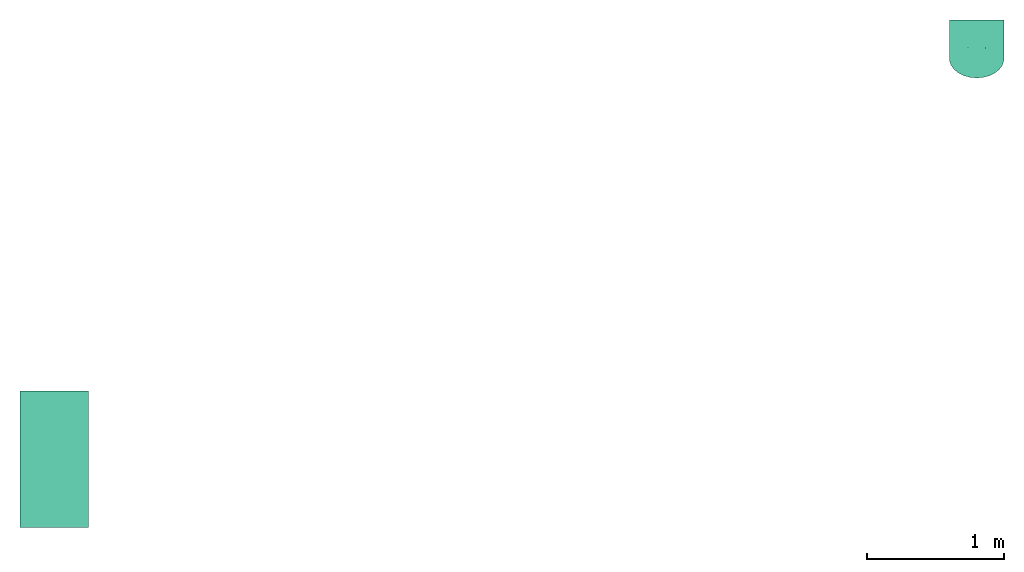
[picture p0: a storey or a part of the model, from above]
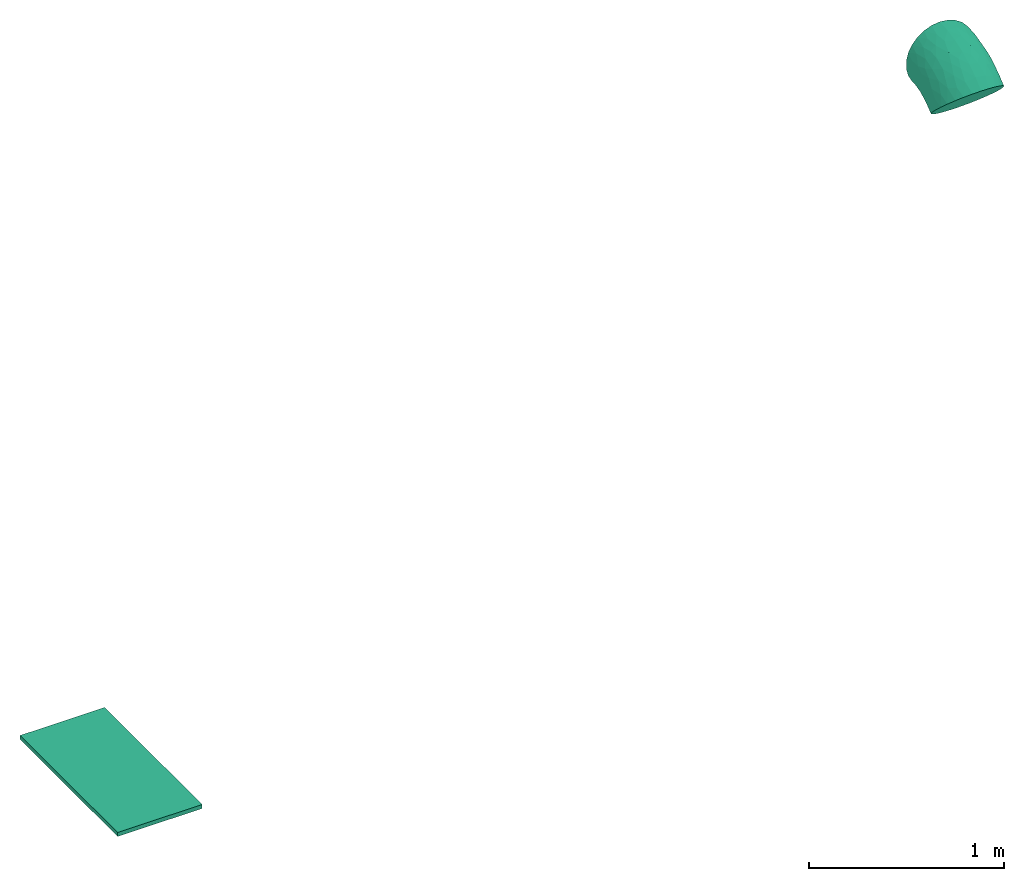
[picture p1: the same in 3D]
Properties of the parts of a building model (IFC2X3), part 1 of 11

# File
Description: ViewDefinition [CoordinationView]
File name: gmtgo-a-200-1-0001.ifc (Edited by Naviate Simple BIM 2022 version 6)
Time: 2026-03-17T17:30:04+01:00
Written by: ODA SDAI 24.12
Made in: Autodesk Revit 25.4.20.11 (ENU) - IFC 25.4.0.27

# IfcProject, 10004870
LongName: 10004870; Phase: Detaljprosjekt

# IfcSite (6)
Name | RefLatitude | RefLongitude | RefElevation (mm)
ENGM | 59, 54, 57, 599999 | 10, 44, 59, 999999 | -4.85124e-10
3 x  | 59, 54, 57, 599999 | 10, 44, 59, 999999 | 0 | MagiCAD Pset_Site - Reference longitude: 10, 44, 59, 999999; Reference elevation: 0; Reference latitude: 59, 54, 57, 599999
ENGM | 59, 54, 49, 759826 | 10, 44, 19, 467315 | 0
Gardermoen

# IfcBuilding (6)
Name
TG | LongName: TG; Pset_BuildingCommon - NumberOfStoreys: 15
3 x mc-building
2 x TG

# IfcBuildingStorey (17)
Name | In | Elevation (mm) | Name
Nivå F - 0,7 m | mc-building | 210200 | Nivå F - 0,7 m Himling
3 x Nivå D + 1,2 m | mc-building | 205200 | Nivå D + 1,2 m
Nivå G - 2,0 m | mc-building | 213700 | Nivå G - 2,0 m
2 x Nivå F - 0,7 m | mc-building | 210200 | Nivå F - 0,7 m
2 x Nivå C | mc-building | 200300 | Nivå C
Nivå F | mc-building | 210900 | Nivå F
Nivå D + 1,2 o | mc-building | 205200 | Nivå D + 1,2 o
Nivå D + 1,2 | TG | 205200 | LongName: Nivå D + 1,2
Nivå F | TG | 210900 | LongName: Nivå F
Nivå F - 0,7 | TG | 210200 | LongName: Nivå F - 0,7
F | TG | 0
G | TG | 0
D | TG | 0

# IfcBuildingStorey: Level:T2 - Kote (6)
In: TG
Name | LongName | Elevation (mm) | Pset_ProductRequirements, Name | Pset_ProductRequirements, sets with these values
Nivå D + 1,2 m | Nivå D + 1,2 m | 205200 | Pset_AirSideSystemInformation - Name: Nivå D + 1,2 m; sets with these values: 2
Nivå E | Nivå E | 207370 | Nivå E | 2
Nivå F - 0,7 m | Nivå F - 0,7 m | 210200 | Nivå F - 0,7 m | 2
Nivå F | Nivå F | 210900 | Nivå F | 2
Nivå G - 2,0 m | Nivå G - 2,0 m | 213700 | Nivå G - 2,0 m | 2
Nivå G | Nivå G | 215700 | Nivå G | 2

# IfcBeam: 10*200 (2)
In: F
Description: 10*200; Material: STEEL/S355
Pset_BeamCommon - LoadBearing: no; Reference: DINN-997(?)
ePset_LocationTool - Splitting: ORIGINAL
ePset_SimplebimBasicQuantities - Volume, net (Simplebim): 0.0007 m3; Area, sides, net (Simplebim): 0.151 m2; Weight, as steel (Simplebim): 5.495 kg; Width (Simplebim): 10 mm; Length (Simplebim): 200 mm; Height (Simplebim): 350 mm
ePset_Simplebim - Assembly Level: Leaf
Tekla Quantity - VOLUME_GROSS: 0.0007 m3; VOLUME_NET: 0.0007 m3; AREA_NET: 0.151 m2; AREA_GROSS: 0.151 m2; WEIGTH_NET: 5.495 kg; WEIGTH_GROSS: 5.495 kg; Heigth: 10 mm; Width: 200 mm; Length: 350 mm
Tekla Common - Grade: S355; Bottom elevation: +213.297; Name: INNSTØPNGODS; Profile: 10*200; Class: 371; Part mark: DINN-997(?); Assembly mark: INN-391(?); Top elevation: +213.647
AVINOR - 07_Fase: F90; 02_Prosjekt: T1; 04_Kontrakt: FDV; 03_Ansvar: FDV; 08_Status: S2; 06_Omrade: TG; 01_Lufthavnkode: ENGM

# IfcBeam: 150*10 (6)
In: F
Description: 150*10; Material: STEEL/S355
ePset_SimplebimBasicQuantities - Weight, as steel (Simplebim): 3.5325 kg; Height (Simplebim): 10 mm; Width (Simplebim): 150 mm; Length (Simplebim): 300 mm; Area, sides, net (Simplebim): 0.099 m2; Volume, net (Simplebim): 0.00045 m3
Pset_BeamCommon - Reference: DINN-1005(?); LoadBearing: no
ePset_LocationTool - Splitting: ORIGINAL
ePset_Simplebim - Assembly Level: Leaf
Tekla Common - Bottom elevation: +209.755; Top elevation: +209.765; Profile: 150*10; Part mark: DINN-1005(?); Grade: S355; Name: INNSTØPNGODS; Class: 371; Assembly mark: INN-402(?)
Tekla Quantity - WEIGTH_NET: 3.5325 kg; WEIGTH_GROSS: 3.5325 kg; Width: 10 mm; Heigth: 150 mm; Length: 300 mm; AREA_NET: 0.099 m2; AREA_GROSS: 0.099 m2; VOLUME_GROSS: 0.00045 m3; VOLUME_NET: 0.00045 m3
AVINOR - 07_Fase: F90; 02_Prosjekt: T1; 04_Kontrakt: FDV; 03_Ansvar: FDV; 08_Status: S2; 06_Omrade: TG; 01_Lufthavnkode: ENGM

# IfcBeam: 20*180 (4)
In: F
Description: 20*180; Material: STEEL/S355
Pset_BeamCommon - LoadBearing: no; Reference: DINN-938(?)
Tekla Quantity - VOLUME_GROSS: 0.00126 m3; VOLUME_NET: 0.00126 m3; AREA_GROSS: 0.1472 m2; AREA_NET: 0.1472 m2; Heigth: 20 mm; Width: 180 mm; Length: 350 mm; WEIGTH_NET: 9.891 kg; WEIGTH_GROSS: 9.891 kg
ePset_Simplebim - Assembly Level: Leaf
ePset_SimplebimBasicQuantities - Volume, net (Simplebim): 0.00126 m3; Area, sides, net (Simplebim): 0.1472 m2; Width (Simplebim): 20 mm; Length (Simplebim): 180 mm; Height (Simplebim): 350 mm; Weight, as steel (Simplebim): 9.891 kg
ePset_LocationTool - Splitting: ORIGINAL
Tekla Common - Grade: S355; Name: INNSTØPNGODS; Assembly mark: INN-346(?); Class: 371; Profile: 20*180; Part mark: DINN-938(?); Top elevation: +213.615; Bottom elevation: +213.265
AVINOR - 07_Fase: F90; 02_Prosjekt: T1; 04_Kontrakt: FDV; 03_Ansvar: FDV; 08_Status: S2; 06_Omrade: TG; 01_Lufthavnkode: ENGM

# IfcBeam: 200*10 (4)
In: F
Description: 200*10; Material: STEEL/S355
Tekla Quantity - VOLUME_NET: 0.00039 m3; VOLUME_GROSS: 0.00039 m3; WEIGTH_GROSS: 3.14 kg; WEIGTH_NET: 3.14 kg; AREA_GROSS: 0.088 m2; AREA_NET: 0.088 m2; Width: 10 mm; Heigth: 200 mm; Length: 200 mm
Tekla Common - Part mark: DINN-1003(?); Grade: S355; Top elevation: +210.030; Bottom elevation: +210.020; Name: INNSTØPNGODS; Profile: 200*10; Class: 371; Assembly mark: INN-399(?)
ePset_Simplebim - Assembly Level: Leaf
ePset_SimplebimBasicQuantities - Length (Simplebim): 200.001 mm; Volume, net (Simplebim): 0.000400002 m3; Height (Simplebim): 10 mm; Width (Simplebim): 200 mm; Area, sides, net (Simplebim): 0.0880004 m2; Weight, as steel (Simplebim): 3.14002 kg
Pset_BeamCommon - Reference: DINN-1003(?); LoadBearing: no
ePset_LocationTool - Splitting: ORIGINAL
AVINOR - 07_Fase: F90; 02_Prosjekt: T1; 04_Kontrakt: FDV; 03_Ansvar: FDV; 08_Status: S2; 06_Omrade: TG; 01_Lufthavnkode: ENGM

# IfcBeam: 25*140 (10)
Description: 25*140; Material: STEEL/S355
Tekla Common - Grade: S355; Profile: 25*140; Name: STÅLBJELKE; Part mark: DSB-20613(?); Class: 330
ePset_Simplebim - Assembly Level: Leaf
ePset_LocationTool - Splitting: ORIGINAL
ePset_SimplebimBasicQuantities - Weight, as steel (Simplebim): 3.57175 kg; Area, sides, net (Simplebim): 0.0499 m2; Volume, net (Simplebim): 0.000455 m3; Width (Simplebim): 25 mm; Height (Simplebim): 130 mm; Length (Simplebim): 140 mm
Tekla Quantity - WEIGTH_NET: 3.57175 kg; WEIGTH_GROSS: 3.57175 kg; AREA_NET: 0.0499 m2; AREA_GROSS: 0.0499 m2; Heigth: 25 mm; Width: 140 mm; Length: 130 mm; VOLUME_GROSS: 0.00045 m3; VOLUME_NET: 0.00045 m3
AVINOR - 07_Fase: F90; 02_Prosjekt: T1; 04_Kontrakt: FDV; 03_Ansvar: FDV; 08_Status: S2; 06_Omrade: TG; 01_Lufthavnkode: ENGM
Pset_BeamCommon - Reference: DSB-20613(?); LoadBearing: no
Name | In | Top elevation | Bottom elevation | Assembly mark
2 x STÅLBJELKE | F | +213.457 | +213.327 | INN-391(?)
4 x STÅLBJELKE | F | +213.425 | +213.295 | INN-346(?)
4 x STÅLBJELKE | G | +213.541 | +213.411 | SB-12403(?)

# IfcBeam: 250*10 (4)
In: F
Description: 250*10; Material: STEEL/S355
ePset_LocationTool - Splitting: ORIGINAL
Tekla Quantity - VOLUME_GROSS: 0.00063 m3; VOLUME_NET: 0.00063 m3; AREA_NET: 0.135 m2; AREA_GROSS: 0.135 m2; WEIGTH_NET: 4.90625 kg; WEIGTH_GROSS: 4.90625 kg; Width: 10 mm; Heigth: 250 mm; Length: 250 mm
ePset_SimplebimBasicQuantities - Area, sides, net (Simplebim): 0.135 m2; Weight, as steel (Simplebim): 4.90625 kg; Height (Simplebim): 10 mm; Length (Simplebim): 250 mm; Width (Simplebim): 250 mm; Volume, net (Simplebim): 0.000625 m3
Pset_BeamCommon - Reference: DINN-1006(?); LoadBearing: no
ePset_Simplebim - Assembly Level: Leaf
Tekla Common - Profile: 250*10; Part mark: DINN-1006(?); Grade: S355; Name: INNSTØPNGODS; Class: 371; Assembly mark: INN-403(?)
AVINOR - 07_Fase: F90; 02_Prosjekt: T1; 04_Kontrakt: FDV; 03_Ansvar: FDV; 08_Status: S2; 06_Omrade: TG; 01_Lufthavnkode: ENGM
Name | Bottom elevation | Top elevation
3 x INNSTØPNGODS | +209.570 | +209.580
INNSTØPNGODS | +209.296 | +209.320

# IfcBeam: 350*10 (2)
In: F
Description: 350*10; Material: STEEL/S355
Pset_BeamCommon - Reference: DINN-1008(?); LoadBearing: no
ePset_SimplebimBasicQuantities - Volume, net (Simplebim): 0.00139999 m3; Length (Simplebim): 399.998 mm; Area, sides, net (Simplebim): 0.294998 m2; Height (Simplebim): 10 mm; Width (Simplebim): 350 mm; Weight, as steel (Simplebim): 10.9899 kg
ePset_Simplebim - Assembly Level: Leaf
ePset_LocationTool - Splitting: ORIGINAL
Tekla Common - Profile: 350*10; Part mark: DINN-1008(?); Grade: S355; Top elevation: +210.030; Bottom elevation: +210.020; Name: INNSTØPNGODS; Class: 371; Assembly mark: INN-405(?)
AVINOR - 07_Fase: F90; 02_Prosjekt: T1; 04_Kontrakt: FDV; 03_Ansvar: FDV; 08_Status: S2; 06_Omrade: TG; 01_Lufthavnkode: ENGM
Tekla Quantity - AREA_NET: 0.295 m2; AREA_GROSS: 0.295 m2; VOLUME_NET: 0.0014 m3; VOLUME_GROSS: 0.00141 m3; Length: 399.998 mm; WEIGTH_GROSS: 10.9899 kg; WEIGTH_NET: 10.9899 kg; Width: 10 mm; Heigth: 350 mm

# IfcBeam: 40*5, STÅLBJELKE
In: F
Description: 40*5; Material: STEEL/S355
Pset_BeamCommon - LoadBearing: no; Reference: DSB-18884(?)
Tekla Quantity - Length: 590.185 mm; AREA_GROSS: 0.05352 m2; AREA_NET: 0.05352 m2; WEIGTH_NET: 0.92659 kg; WEIGTH_GROSS: 0.92659 kg; Width: 5 mm; VOLUME_NET: 0.00013 m3; VOLUME_GROSS: 0.00013 m3; Heigth: 40 mm
Tekla Common - Grade: S355; Top elevation: +210.295; Bottom elevation: +210.255; Name: STÅLBJELKE; Assembly mark: SS-7596(?); Class: 330; Profile: 40*5; Part mark: DSB-18884(?)
ePset_Simplebim - Assembly Level: Leaf
ePset_SimplebimBasicQuantities - Volume, net (Simplebim): 0.000118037 m3; Length (Simplebim): 590.185 mm; Weight, as steel (Simplebim): 0.92659 kg; Height (Simplebim): 40 mm; Width (Simplebim): 5 mm; Area, sides, net (Simplebim): 0.0535166 m2
ePset_LocationTool - Splitting: ORIGINAL
AVINOR - 07_Fase: F90; 02_Prosjekt: T1; 04_Kontrakt: FDV; 03_Ansvar: FDV; 08_Status: S2; 06_Omrade: TG; 01_Lufthavnkode: ENGM

# IfcBeam: 5*80 (3)
In: F
Description: 5*80; Material: STEEL/S355
ePset_LocationTool - Splitting: ORIGINAL
Tekla Quantity - Heigth: 5 mm; Width: 80 mm
ePset_Simplebim - Assembly Level: Leaf
ePset_SimplebimBasicQuantities - Height (Simplebim): 5 mm; Width (Simplebim): 80 mm
Pset_BeamCommon - LoadBearing: no
AVINOR - 07_Fase: F90; 02_Prosjekt: T1; 04_Kontrakt: FDV; 03_Ansvar: FDV; 08_Status: S2; 06_Omrade: TG; 01_Lufthavnkode: ENGM
Tekla Common - Grade: S355; Bottom elevation: +210.255; Name: STÅLBJELKE; Profile: 5*80; Assembly mark: SS-7596(?); Class: 330; Top elevation: +210.260
Name | AREA_GROSS (m2) = AREA_NET (m2) | WEIGTH_GROSS (kg) = WEIGTH_NET (kg) = Weight, as steel (Simplebim) (kg) | Length (mm) = Length (Simplebim) (mm) | VOLUME_GROSS (m3) = VOLUME_NET (m3) | Volume, net (Simplebim) (m3) | Area, sides, net (Simplebim) (m2) | Reference = Part mark
STÅLBJELKE | 0.40879 | 7.53573 | 2399.91 | 0.00096 | 0.000959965 | 0.408785 | DSB-18881(?)
2 x STÅLBJELKE | 0.34491 | 6.35586 | 2024.16 | 0.00081 | 0.000809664 | 0.344907 | DSB-18880(?)

# IfcBeam: 50*12 (8)
In: F
Description: 50*12; Material: STEEL/S355
ePset_SimplebimBasicQuantities - Width (Simplebim): 12 mm; Height (Simplebim): 50 mm
Pset_BeamCommon - LoadBearing: no
Tekla Common - Grade: S355; Name: STÅLBJELKE; Profile: 50*12; Assembly mark: SS-7596(?); Class: 330
ePset_Simplebim - Assembly Level: Leaf
Tekla Quantity - Width: 12 mm; Heigth: 50 mm
ePset_LocationTool - Splitting: ORIGINAL
AVINOR - 07_Fase: F90; 02_Prosjekt: T1; 04_Kontrakt: FDV; 03_Ansvar: FDV; 08_Status: S2; 06_Omrade: TG; 01_Lufthavnkode: ENGM
Name | Volume, net (Simplebim) (m3) | Area, sides, net (Simplebim) (m2) | Length (Simplebim) (mm) | Weight, as steel (Simplebim) (kg) | Reference = Part mark | Bottom elevation | Top elevation | WEIGTH_NET (kg) = WEIGTH_GROSS (kg) | Length (mm) | VOLUME_GROSS (m3) = VOLUME_NET (m3) | AREA_GROSS (m2) = AREA_NET (m2)
STÅLBJELKE | 0.00144 | 0.2988 | 2400 | 11.304 | DSB-19554(?) | +213.180 | +213.230 | 11.304 | 2400 | 0.00144 | 0.2988
STÅLBJELKE | 0.000354 | 0.07436 | 590 | 2.7789 | DSB-19555(?) | +210.230 | +210.280 | 2.77977 | 590.185 | 0.00035 | 0.07438
2 x STÅLBJELKE | 0.000354 | 0.07436 | 590 | 2.7789 | DSB-19555(?) | +210.930 | +210.980 | 2.77977 | 590.185 | 0.00035 | 0.07438
2 x STÅLBJELKE | 0.000354 | 0.07436 | 590 | 2.7789 | DSB-19555(?) | +211.680 | +211.730 | 2.77977 | 590.185 | 0.00035 | 0.07438
STÅLBJELKE | 0.000731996 | 0.152479 | 1219.99 | 5.74617 | DSB-19556(?) | +212.385 | +212.435 | 5.7462 | 1220 | 0.00073 | 0.15248
STÅLBJELKE | 0.0012144 | 0.252176 | 2024 | 9.53305 | DSB-19553(?) | +213.180 | +213.230 | 9.53379 | 2024.16 | 0.00121 | 0.2522

# IfcBeam: 60*5 (28)
In: G
Description: 60*5; Material: STEEL/S355
Pset_BeamCommon - LoadBearing: no; Reference: DSB-18871(?)
Tekla Common - Grade: S355; Name: STÅLBJELKE; Assembly mark: SB-11173(?); Top elevation: +213.665; Bottom elevation: +213.660; Part mark: DSB-18871(?); Class: 330; Profile: 60*5
ePset_SimplebimBasicQuantities - Weight, as steel (Simplebim): 0.35325 kg; Volume, net (Simplebim): 0.000045 m3; Area, sides, net (Simplebim): 0.0201 m2; Height (Simplebim): 5 mm; Width (Simplebim): 60 mm; Length (Simplebim): 150 mm
ePset_Simplebim - Assembly Level: Leaf
ePset_LocationTool - Splitting: ORIGINAL
Tekla Quantity - VOLUME_GROSS: 0.00005 m3; VOLUME_NET: 0.00005 m3; WEIGTH_NET: 0.35325 kg; WEIGTH_GROSS: 0.35325 kg; AREA_NET: 0.0201 m2; AREA_GROSS: 0.0201 m2; Width: 5 mm; Heigth: 60 mm; Length: 150 mm
AVINOR - 07_Fase: F90; 02_Prosjekt: T1; 04_Kontrakt: FDV; 03_Ansvar: FDV; 08_Status: S2; 06_Omrade: TG; 01_Lufthavnkode: ENGM

# IfcBeam: 80*5 (10)
In: F
Description: 80*5; Material: STEEL/S355
ePset_SimplebimBasicQuantities - Width (Simplebim): 5 mm; Height (Simplebim): 80 mm
Tekla Quantity - Width: 5 mm; Heigth: 80 mm
ePset_Simplebim - Assembly Level: Leaf
Tekla Common - Grade: S355; Name: STÅLBJELKE; Assembly mark: SS-7596(?); Class: 330; Profile: 80*5
Pset_BeamCommon - LoadBearing: no
AVINOR - 07_Fase: F90; 02_Prosjekt: T1; 04_Kontrakt: FDV; 03_Ansvar: FDV; 08_Status: S2; 06_Omrade: TG; 01_Lufthavnkode: ENGM
ePset_LocationTool - Splitting: ORIGINAL
Name | Length (Simplebim) (mm) = Length (mm) | Area, sides, net (Simplebim) (m2) | Weight, as steel (Simplebim) (kg) = WEIGTH_GROSS (kg) = WEIGTH_NET (kg) | Volume, net (Simplebim) (m3) | AREA_NET (m2) = AREA_GROSS (m2) | VOLUME_GROSS (m3) = VOLUME_NET (m3) | Bottom elevation | Top elevation | Part mark = Reference
STÅLBJELKE | 2400 | 0.4088 | 7.536 | 0.00096 | 0.4088 | 0.00096 | +213.165 | +213.245 | DSB-18881(?)
STÅLBJELKE | 590.185 | 0.101131 | 1.85318 | 0.000236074 | 0.10113 | 0.00024 | +210.105 | +210.185 | DSB-18883(?)
2 x STÅLBJELKE | 590.185 | 0.101131 | 1.85318 | 0.000236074 | 0.10113 | 0.00024 | +210.915 | +210.995 | DSB-18883(?)
2 x STÅLBJELKE | 590.185 | 0.101131 | 1.85318 | 0.000236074 | 0.10113 | 0.00024 | +211.665 | +211.745 | DSB-18883(?)
STÅLBJELKE | 1220 | 0.2082 | 3.8308 | 0.000488 | 0.2082 | 0.00049 | +212.370 | +212.450 | DSB-18882(?)
2 x STÅLBJELKE | 590.185 | 0.101131 | 1.85318 | 0.000236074 | 0.10113 | 0.00024 | +213.605 | +213.685 | DSB-18883(?)
STÅLBJELKE | 2024.16 | 0.344907 | 6.35586 | 0.000809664 | 0.34491 | 0.00081 | +213.165 | +213.245 | DSB-18880(?)

# IfcBeam: AAJKORS265*195*30*900*150*700*700 (4)
In: F
Description: AAJKORS265*195*30*900*150*700*700
ePset_LocationTool - Splitting: RESULT
AVINOR - 07_Fase: F90; 02_Prosjekt: T1; 04_Kontrakt: FDV; 03_Ansvar: FDV; 08_Status: S2; 05_ID-nummer: +TA=223.001; 06_Omrade: TG; 01_Lufthavnkode: ENGM
ePset_Simplebim - Assembly Level: Leaf
Pset_BeamCommon - LoadBearing: no
ePset_SimplebimBasicQuantities - Height (Simplebim): 830 mm; Length (Simplebim): 9310 mm
Tekla Common - Name: PREFABBJELKE; Top elevation: +210.030; Bottom elevation: +209.130; Profile: AAJKORS265*195*30*900*150*700*700; Grade: C45/55; Class: 130
Name | Reference = Part mark | Volume, net (Simplebim) (m3) | Weight, as steel (Simplebim) (kg) | Width (Simplebim) (mm) | Area, sides, net (Simplebim) (m2) | Assembly mark
PREFABBJELKE | Concrete-19788(?) | 5.4907 | 43102 | 1000 | 36.4043 | PB-539(?)
PREFABBJELKE | Concrete-19791(?) | 4.22354 | 33154.8 | 705 | 30.4457 | PB-542(?)
PREFABBJELKE | Concrete-19784(?) | 5.49345 | 43123.6 | 1000 | 36.3873 | PB-535(?)
PREFABBJELKE | Concrete-19782(?) | 3.21961 | 25274 | 565 | 27.0215 | PB-533(?)

# IfcBeam: B223 - Bjelke - Flatstål:B223 - Bjelke - Flatstål - w240 h 8 (2)
In: Nivå G - 2,0 m
Type - PredefinedType: BEAM
Type - Pset_BeamCommon - LoadBearing: yes
Material: _NSW Stål
AVINOR - 08_Status: S4; 07_Fase: F90; 03_Ansvar: FDV; 06_Omrade: TG; 02_Prosjekt: T20100; 01_Lufthavnkode: ENGM
ePset_SimplebimBasicQuantities - Width (Simplebim): 8 mm; Volume, net (Simplebim): 0.01728 m3; Weight, as steel (Simplebim): 135.648 kg; Area, sides, net (Simplebim): 4.46784 m2; Height (Simplebim): 240 mm; Length (Simplebim): 9000 mm
ePset_Simplebim - Assembly Level: Leaf
ePset_LocationTool - Splitting: ORIGINAL
Pset_BeamCommon - IsExternal: no; Slope: 0 deg; Reference: B223 - Bjelke - Flatstål - w240 h 8; Span: 9000 mm
Pset_ReinforcementBarPitchOfBeam - Reference: B223 - Bjelke - Flatstål - w240 h 8; sets with these values: 2
Name (B223 - Bjelke - Flatstål:B223 - Bjelke - Flatstål - w240 h 8:...) | Group
49950679 | Model Group:A240 - eksisterende gallerivegg i pir G-2 / generell (members excluded):49950707
49959070 | Model Group:A240 - eksisterende gallerivegg i pir G-2 / forkortet ved bru akse 19-20 nordside, 21-22 sørside (members excluded):49959098

# IfcBeam: B223 - Bjelke - HUP2:B223 - HUP 150 x 150 x 8 mm (2)
In: Nivå G - 2,0 m
Type - PredefinedType: BEAM
Type - Pset_BeamCommon - LoadBearing: yes
Material: _NSW Stål; Group: Model Group:A162446 - Utvidelse eksisterende Kiosk (members excluded):59114857
AVINOR - 08_Status: S4; 07_Fase: F90; 02_Prosjekt: A162446; 03_Ansvar: 182412; 06_Omrade: TG; 01_Lufthavnkode: ENGM
ePset_SimplebimBasicQuantities - Width (Simplebim): 150 mm; Height (Simplebim): 150 mm
ePset_Simplebim - Assembly Level: Leaf
Pset_BeamCommon - IsExternal: no; Slope: 0 deg; Reference: B223 - HUP 150 x 150 x 8 mm
ePset_LocationTool - Splitting: ORIGINAL
Pset_QuantityTakeOff - Reference: B223 - HUP 150 x 150 x 8 mm; sets with these values: 2
Name (B223 - Bjelke - HUP2:B223 - HUP 150 x 150 x 8 mm:...) | Area, sides, net (Simplebim) (m2) | Weight, as steel (Simplebim) (kg) | Length (Simplebim) (mm) = Span (mm) | Volume, net (Simplebim) (m3)
59105830 | 16.5911 | 525.445 | 14867.6 | 0.0669357
59105838 | 16.2479 | 514.573 | 14560 | 0.0655506

# IfcBeam: B223 - Bjelke - HUP:B223 - HUP 100 x 100 x 5 mm (2)
Type - PredefinedType: BEAM
Type - Pset_BeamCommon - LoadBearing: yes
Material: _NSW Stål; Group: Model Group:tettfelt 2 (members excluded):48741169
AVINOR - 08_Status: S4; 07_Fase: F90; 03_Ansvar: FDV; 06_Omrade: TG; 02_Prosjekt: T20100; 01_Lufthavnkode: ENGM
Pset_BeamCommon - Reference: B223 - HUP 100 x 100 x 5 mm; IsExternal: no; Slope: 0 deg
ePset_Simplebim - Assembly Level: Leaf
ePset_LocationTool - Splitting: ORIGINAL
ePset_SimplebimBasicQuantities - Width (Simplebim): 100 mm; Height (Simplebim): 100 mm
Pset_ReinforcementBarPitchOfBeam - Reference: B223 - HUP 100 x 100 x 5 mm; sets with these values: 2
Name (B223 - Bjelke - HUP:B223 - HUP 100 x 100 x 5 mm:...) | In | Span (mm) = Length (Simplebim) (mm) | Volume, net (Simplebim) (m3) | Weight, as steel (Simplebim) (kg) | Area, sides, net (Simplebim) (m2)
48742636 | Nivå G - 2,0 m | 400 | 0.00075345 | 5.91458 | 0.302596
48742642 | Nivå F - 0,7 m | 425 | 0.000800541 | 6.28424 | 0.321273

# IfcBeam: B223 - Bjelke - HUP:B223 - HUP 40 x 80 x 4 mm (3)
In: Nivå G - 2,0 m
Type - PredefinedType: BEAM
Type - Pset_BeamCommon - LoadBearing: yes
Material: _NSW Stål
AVINOR - 08_Status: S4; 07_Fase: F90; 03_Ansvar: FDV; 06_Omrade: TG; 02_Prosjekt: T20100; 01_Lufthavnkode: ENGM
ePset_LocationTool - Splitting: ORIGINAL
Pset_BeamCommon - Reference: B223 - HUP 40 x 80 x 4 mm; IsExternal: no; Slope: 0 deg; Span: 9000 mm
ePset_Simplebim - Assembly Level: Leaf
ePset_SimplebimBasicQuantities - Area, sides, net (Simplebim): 3.94066 m2; Volume, net (Simplebim): 0.00796963 m3; Weight, as steel (Simplebim): 62.5616 kg; Width (Simplebim): 40 mm; Height (Simplebim): 80 mm; Length (Simplebim): 9000 mm
Pset_ReinforcementBarPitchOfBeam - Reference: B223 - HUP 40 x 80 x 4 mm; sets with these values: 2
Name (B223 - Bjelke - HUP:B223 - HUP 40 x 80 x 4 mm:...) | Group
49956616 | Model Group:A254 - eksisterende glassgulv i pir G ved fasade / __generell (members excluded):49956618
49956669 | Model Group:A254 - eksisterende glassgulv i pir G ved fasade / __generell (members excluded):49956671
53645472 | Model Group:A254 - eksisterende glassgulv i pir G ved fasade / __generell (members excluded):53645474

# IfcBeam: B223 - Bjelke - L:B223 - L-profil - 25 x 25 x 5 mm (12)
In: Nivå G - 2,0 m
Type - PredefinedType: BEAM
Type - Pset_BeamCommon - LoadBearing: yes
Material: _NSW Stål
AVINOR - 08_Status: S4; 07_Fase: F90; 03_Ansvar: FDV; 06_Omrade: TG; 02_Prosjekt: T20100; 01_Lufthavnkode: ENGM
Pset_QuantityTakeOff - Reference: B223 - L-profil - 25 x 25 x 5 mm; sets with these values: 2
ePset_Simplebim - Assembly Level: Leaf
Pset_BeamCommon - Reference: B223 - L-profil - 25 x 25 x 5 mm; IsExternal: no; Slope: 0 deg
ePset_LocationTool - Splitting: ORIGINAL
ePset_SimplebimBasicQuantities - Width (Simplebim): 25 mm; Height (Simplebim): 25 mm
Name (B223 - Bjelke - L:B223 - L-profil - 25 x 25 x 5 mm:...) | Span (mm) = Length (Simplebim) (mm) | Area, sides, net (Simplebim) (m2) | Volume, net (Simplebim) (m3) | Weight, as steel (Simplebim) (kg) | Group
49950716 | 1485 | 0.14639 | 0.000334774 | 2.62798 | Model Group:A240 - eksisterende gallerivegg i pir G-2 / generell (members excluded):49950707
49950719 | 1335 | 0.131648 | 0.000300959 | 2.36253 | Model Group:A240 - eksisterende gallerivegg i pir G-2 / generell (members excluded):49950707
49950722 | 1485 | 0.14639 | 0.000334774 | 2.62798 | Model Group:A240 - eksisterende gallerivegg i pir G-2 / generell (members excluded):49950707
49950725 | 1485 | 0.14639 | 0.000334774 | 2.62798 | Model Group:A240 - eksisterende gallerivegg i pir G-2 / generell (members excluded):49950707
49950728 | 1485 | 0.14639 | 0.000334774 | 2.62798 | Model Group:A240 - eksisterende gallerivegg i pir G-2 / generell (members excluded):49950707
49950731 | 1335 | 0.131648 | 0.000300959 | 2.36253 | Model Group:A240 - eksisterende gallerivegg i pir G-2 / generell (members excluded):49950707
49950747 | 285 | 0.0284593 | 0.0000642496 | 0.504359 | Model Group:A240 - eksisterende gallerivegg i pir G-2 / generell (members excluded):49950707
49951059 | 285 | 0.0284593 | 0.0000642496 | 0.504359 | Model Group:A240 - eksisterende gallerivegg i pir G-2 / generell (members excluded):49951019
49959107 | 1485 | 0.14639 | 0.000334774 | 2.62798 | Model Group:A240 - eksisterende gallerivegg i pir G-2 / forkortet ved bru akse 19-20 nordside, 21-22 sørside (members excluded):49959098
49959110 | 1335 | 0.131648 | 0.000300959 | 2.36253 | Model Group:A240 - eksisterende gallerivegg i pir G-2 / forkortet ved bru akse 19-20 nordside, 21-22 sørside (members excluded):49959098
49959113 | 1485 | 0.14639 | 0.000334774 | 2.62798 | Model Group:A240 - eksisterende gallerivegg i pir G-2 / forkortet ved bru akse 19-20 nordside, 21-22 sørside (members excluded):49959098
49959116 | 1317.58 | 0.129936 | 0.000297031 | 2.33169 | Model Group:A240 - eksisterende gallerivegg i pir G-2 / forkortet ved bru akse 19-20 nordside, 21-22 sørside (members excluded):49959098

# IfcBeam: B223 - Bjelke - L:B223 - L-profil - 40 x 40 x 4 mm (6)
In: Nivå G - 2,0 m
Type - PredefinedType: BEAM
Type - Pset_BeamCommon - LoadBearing: yes
Material: _NSW Stål
Pset_BeamCommon - Reference: B223 - L-profil - 40 x 40 x 4 mm; IsExternal: no; Slope: 0 deg; Span: 9000 mm
AVINOR - 08_Status: S4; 07_Fase: F90; 03_Ansvar: FDV; 06_Omrade: TG; 02_Prosjekt: T20100; 01_Lufthavnkode: ENGM
ePset_Simplebim - Assembly Level: Leaf
ePset_LocationTool - Splitting: ORIGINAL
ePset_SimplebimBasicQuantities - Height (Simplebim): 40 mm; Width (Simplebim): 40 mm; Weight, as steel (Simplebim): 21.6713 kg; Area, sides, net (Simplebim): 1.40182 m2; Length (Simplebim): 9000 mm; Volume, net (Simplebim): 0.00276068 m3
Pset_ReinforcementBarPitchOfBeam - Reference: B223 - L-profil - 40 x 40 x 4 mm; sets with these values: 2
Name (B223 - Bjelke - L:B223 - L-profil - 40 x 40 x 4 mm:...) | Group
49956612 | Model Group:A254 - eksisterende glassgulv i pir G ved fasade / __generell (members excluded):49956618
49956614 | Model Group:A254 - eksisterende glassgulv i pir G ved fasade / __generell (members excluded):49956618
49956665 | Model Group:A254 - eksisterende glassgulv i pir G ved fasade / __generell (members excluded):49956671
49956667 | Model Group:A254 - eksisterende glassgulv i pir G ved fasade / __generell (members excluded):49956671
53645468 | Model Group:A254 - eksisterende glassgulv i pir G ved fasade / __generell (members excluded):53645474
53645470 | Model Group:A254 - eksisterende glassgulv i pir G ved fasade / __generell (members excluded):53645474

# IfcBeam: B223 - Bjelke - T:B223 - T-profil - 40 x 40 x 10 mm (10)
In: Nivå G - 2,0 m
Type - PredefinedType: BEAM
Type - Pset_BeamCommon - LoadBearing: yes
Material: _NSW Stål
Pset_BeamCommon - Reference: B223 - T-profil - 40 x 40 x 10 mm; IsExternal: no; Slope: 0 deg; Span: 372 mm
AVINOR - 08_Status: S4; 07_Fase: F90; 03_Ansvar: FDV; 06_Omrade: TG; 02_Prosjekt: T20100; 01_Lufthavnkode: ENGM
ePset_LocationTool - Splitting: ORIGINAL
ePset_Simplebim - Assembly Level: Leaf
ePset_SimplebimBasicQuantities - Length (Simplebim): 372 mm; Weight, as steel (Simplebim): 1.09635 kg; Volume, net (Simplebim): 0.000139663 m3; Width (Simplebim): 40 mm; Height (Simplebim): 40 mm; Area, sides, net (Simplebim): 0.0599501 m2
Pset_QuantityTakeOff - Reference: B223 - T-profil - 40 x 40 x 10 mm; sets with these values: 2
Name (B223 - Bjelke - T:B223 - T-profil - 40 x 40 x 10 mm:...) | Group
50053641 | Model Group:A254 - eksisterende glassgulv i pir G ved fasade / __generell (members excluded):49956618
50053643 | Model Group:A254 - eksisterende glassgulv i pir G ved fasade / __generell (members excluded):49956618
50053645 | Model Group:A254 - eksisterende glassgulv i pir G ved fasade / __generell (members excluded):49956618
50053647 | Model Group:A254 - eksisterende glassgulv i pir G ved fasade / __generell (members excluded):49956671
50053649 | Model Group:A254 - eksisterende glassgulv i pir G ved fasade / __generell (members excluded):49956671
50053651 | Model Group:A254 - eksisterende glassgulv i pir G ved fasade / __generell (members excluded):49956671
50084047 | Model Group:A254 - eksisterende glassgulv i pir G ved fasade / Type D - SSG (members excluded):50084020
53645475 | Model Group:A254 - eksisterende glassgulv i pir G ved fasade / __generell (members excluded):53645474
53645477 | Model Group:A254 - eksisterende glassgulv i pir G ved fasade / __generell (members excluded):53645474
53645479 | Model Group:A254 - eksisterende glassgulv i pir G ved fasade / __generell (members excluded):53645474

# IfcBeam: B223 - Bjelke - UNP:B223 - UNP 240 (2)
In: Nivå G - 2,0 m
Type - PredefinedType: BEAM
Type - Pset_BeamCommon - LoadBearing: yes
Material: _NSW Stål
AVINOR - 08_Status: S4; 07_Fase: F90; 03_Ansvar: FDV; 06_Omrade: TG; 02_Prosjekt: T20100; 01_Lufthavnkode: ENGM
ePset_SimplebimBasicQuantities - Area, sides, net (Simplebim): 7.13458 m2; Volume, net (Simplebim): 0.0377809 m3; Weight, as steel (Simplebim): 296.58 kg; Width (Simplebim): 85 mm; Height (Simplebim): 240 mm; Length (Simplebim): 9000 mm
ePset_Simplebim - Assembly Level: Leaf
Pset_BeamCommon - IsExternal: no; Slope: 0 deg; Span: 9000 mm; Reference: B223 - UNP 240
Pset_ReinforcementBarPitchOfBeam - Reference: B223 - UNP 240; sets with these values: 2
ePset_LocationTool - Splitting: ORIGINAL
Name (B223 - Bjelke - UNP:B223 - UNP 240:...) | Group
49950690 | Model Group:A240 - eksisterende gallerivegg i pir G-2 / generell (members excluded):49950707
49959081 | Model Group:A240 - eksisterende gallerivegg i pir G-2 / forkortet ved bru akse 19-20 nordside, 21-22 sørside (members excluded):49959098

# IfcBeam: D12 (4)
In: F
Description: D12; Material: STEEL/S355
ePset_SimplebimBasicQuantities - Width (Simplebim): 12 mm
Tekla Quantity - Heigth: 12 mm; Width: 12 mm
ePset_LocationTool - Splitting: ORIGINAL
ePset_Simplebim - Assembly Level: Leaf
Pset_BeamCommon - LoadBearing: no
AVINOR - 07_Fase: F90; 02_Prosjekt: T1; 04_Kontrakt: FDV; 03_Ansvar: FDV; 08_Status: S2; 06_Omrade: TG; 01_Lufthavnkode: ENGM
Tekla Common - Grade: S355; Profile: D12; Name: STÅLBJELKE; Assembly mark: SS-7596(?); Class: 330
Name | Length (Simplebim) (mm) | Volume, net (Simplebim) (m3) | Weight, as steel (Simplebim) (kg) = WEIGTH_NET (kg) = WEIGTH_GROSS (kg) | Area, sides, net (Simplebim) (m2) | Height (Simplebim) (mm) | Length (mm) | VOLUME_NET (m3) = VOLUME_GROSS (m3) | AREA_GROSS (m2) = AREA_NET (m2) | Reference = Part mark | Top elevation | Bottom elevation
2 x STÅLBJELKE | 3173.13 | 0.000323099 | 2.53633 | 0.116777 | 12 | 3173.13 | 0.00032 | 0.11678 | DSB-22011(?) | +212.408 | +210.277
2 x STÅLBJELKE | 12 | 0.000295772 | 2.32181 | 0.106917 | 2904.75 | 2904.75 | 0.0003 | 0.10692 | DSB-22010(?) | +212.409 | +210.276

# IfcBeam: HEA260, STÅLBJELKE
In: F
Description: HEA260; Material: STEEL/S355
ePset_SimplebimBasicQuantities - Weight, as steel (Simplebim): 284.725 kg; Length (Simplebim): 4430 mm; Volume, net (Simplebim): 0.0362706 m3; Height (Simplebim): 250 mm; Width (Simplebim): 260 mm; Area, sides, net (Simplebim): 6.77213 m2
ePset_LocationTool - Splitting: ORIGINAL
Tekla Quantity - WEIGTH_GROSS: 301.921 kg; WEIGTH_NET: 284.725 kg; Length: 4430 mm; VOLUME_NET: 0.03627 m3; Heigth: 250 mm; Width: 260 mm; VOLUME_GROSS: 0.03846 m3; AREA_GROSS: 6.57412 m2; AREA_NET: 6.77213 m2
Tekla Common - Part mark: DSB-14574(?); Bottom elevation: +209.765; Grade: S355; Assembly mark: SB-8799(?); Name: STÅLBJELKE; Top elevation: +210.015; Profile: HEA260; Class: 330
ePset_Simplebim - Assembly Level: Leaf
Pset_BeamCommon - Reference: DSB-14574(?); LoadBearing: no
AVINOR - 07_Fase: F90; 02_Prosjekt: T1; 04_Kontrakt: FDV; 03_Ansvar: FDV; 08_Status: S2; 06_Omrade: TG; 01_Lufthavnkode: ENGM

# IfcBeam: HEB200, STÅLBJELKE
In: G
Description: HEB200; Material: STEEL/S355
ePset_LocationTool - Splitting: ORIGINAL
Tekla Common - Grade: S355; Assembly mark: SB-8261(?); Top elevation: +213.570; Name: STÅLBJELKE; Profile: HEB200; Bottom elevation: +213.370; Part mark: DSB-13801(?); Class: 330
ePset_Simplebim - Assembly Level: Leaf
Pset_BeamCommon - LoadBearing: no; Reference: DSB-13801(?)
Tekla Quantity - VOLUME_GROSS: 0.03949 m3; Length: 5057.01 mm; AREA_GROSS: 5.82062 m2; AREA_NET: 5.80971 m2; WEIGTH_NET: 288.437 kg; VOLUME_NET: 0.03674 m3; Heigth: 200 mm; Width: 200 mm; WEIGTH_GROSS: 309.958 kg
AVINOR - 07_Fase: F90; 02_Prosjekt: T1; 04_Kontrakt: FDV; 03_Ansvar: FDV; 08_Status: S2; 06_Omrade: TG; 01_Lufthavnkode: ENGM
ePset_SimplebimBasicQuantities - Length (Simplebim): 5057.01 mm; Weight, as steel (Simplebim): 288.437 kg; Volume, net (Simplebim): 0.0367436 m3; Area, sides, net (Simplebim): 5.80971 m2; Width (Simplebim): 200 mm; Height (Simplebim): 200 mm

# IfcBeam: HQ265*5-40*130-12*440 (4)
In: G
Description: HQ265*5-40*130-12*440; Material: STEEL/S355
Tekla Quantity - VOLUME_NET: 0.05199 m3; AREA_NET: 8.51048 m2; AREA_GROSS: 8.80808 m2; Heigth: 277 mm; Length: 4096 mm; WEIGTH_GROSS: 422.177 kg; Width: 440 mm; VOLUME_GROSS: 0.05378 m3; WEIGTH_NET: 408.158 kg
Tekla Common - Grade: S355; Top elevation: +213.560; Name: STÅLBJELKE; Part mark: DSB-24230(?); Assembly mark: SB-12403(?); Bottom elevation: +213.283; Profile: HQ265*5-40*130-12*440; Class: 330
ePset_LocationTool - Splitting: ORIGINAL
ePset_Simplebim - Assembly Level: Leaf
ePset_SimplebimBasicQuantities - Weight, as steel (Simplebim): 408.158 kg; Area, sides, net (Simplebim): 8.51049 m2; Volume, net (Simplebim): 0.0519947 m3; Height (Simplebim): 277 mm; Length (Simplebim): 4096 mm; Width (Simplebim): 440 mm
Pset_BeamCommon - Reference: DSB-24230(?); LoadBearing: no
AVINOR - 07_Fase: F90; 02_Prosjekt: T1; 04_Kontrakt: FDV; 03_Ansvar: FDV; 08_Status: S2; 06_Omrade: TG; 01_Lufthavnkode: ENGM

# IfcBeam: IPE330 (5)
In: G
Description: IPE330; Material: STEEL/S355
Pset_BeamCommon - LoadBearing: no
Tekla Common - Grade: S355; Top elevation: +213.570; Name: STÅLBJELKE; Profile: IPE330; Class: 330; Bottom elevation: +213.240
ePset_SimplebimBasicQuantities - Width (Simplebim): 160 mm; Height (Simplebim): 330 mm
ePset_LocationTool - Splitting: ORIGINAL
ePset_Simplebim - Assembly Level: Leaf
Tekla Quantity - Width: 160 mm; Heigth: 330 mm
AVINOR - 07_Fase: F90; 02_Prosjekt: T1; 04_Kontrakt: FDV; 03_Ansvar: FDV; 08_Status: S2; 06_Omrade: TG; 01_Lufthavnkode: ENGM
Name | Reference = Part mark | Assembly mark | Length (Simplebim) (mm) | Area, sides, net (Simplebim) (m2) | Weight, as steel (Simplebim) (kg) | Volume, net (Simplebim) (m3) | AREA_GROSS (m2) | VOLUME_NET (m3) | VOLUME_GROSS (m3) | WEIGTH_NET (kg) | AREA_NET (m2) | WEIGTH_GROSS (kg) | Length (mm)
STÅLBJELKE | DSB-13972(?) | SB-8213(?) | 4116 | 5.26825 | 191.878 | 0.0244431 | 5.16146 | 0.02444 | 0.02578 | 191.879 | 5.26826 | 202.265 | 4116.01
STÅLBJELKE | DSB-13972(?) | SB-8212(?) | 4116 | 5.26825 | 191.878 | 0.0244431 | 5.16146 | 0.02444 | 0.02578 | 191.879 | 5.26826 | 202.265 | 4116.01
3 x STÅLBJELKE | DSB-13962(?) | SB-8195(?) | 5057.01 | 6.33646 | 230.778 | 0.0293984 | 6.34149 | 0.0294 | 0.03166 | 230.778 | 6.33646 | 248.506 | 5057.01

# IfcBeam: L120*80*8, STÅLBJELKE
In: G
Description: L120*80*8
Pset_BeamCommon - Reference: DSB-5301(?); LoadBearing: no
ePset_SimplebimBasicQuantities - Volume, net (Simplebim): 0.00817153 m3; Area, sides, net (Simplebim): 2.13107 m2; Width (Simplebim): 80 mm; Height (Simplebim): 120 mm; Length (Simplebim): 5320 mm; Weight, as steel (Simplebim): 64.1465 kg
ePset_LocationTool - Splitting: RESULT
Tekla Common - Grade: S355; Bottom elevation: +213.580; Part mark: DSB-5301(?); Top elevation: +213.700; Name: STÅLBJELKE; Assembly mark: SB-8258(?); Class: 330; Profile: L120*80*8
ePset_Simplebim - Assembly Level: Leaf
AVINOR - 07_Fase: F90; 02_Prosjekt: T1; 04_Kontrakt: FDV; 03_Ansvar: FDV; 08_Status: S2; 06_Omrade: TG; 01_Lufthavnkode: ENGM

# IfcBeam: L150*12, STÅLBJELKE
In: F
Description: L150*12; Material: STEEL/S355
Pset_BeamCommon - Reference: DSB-16281(?); LoadBearing: no
Tekla Quantity - AREA_NET: 1.44682 m2; WEIGTH_NET: 65.1067 kg; WEIGTH_GROSS: 65.54 kg; VOLUME_NET: 0.00829 m3; AREA_GROSS: 1.40631 m2; Length: 2399.84 mm; VOLUME_GROSS: 0.00835 m3; Heigth: 150 mm; Width: 150 mm
ePset_Simplebim - Assembly Level: Leaf
Tekla Common - Grade: S355; Part mark: DSB-16281(?); Name: STÅLBJELKE; Bottom elevation: +213.467; Assembly mark: SS-7596(?); Class: 330; Top elevation: +213.617; Profile: L150*12
ePset_SimplebimBasicQuantities - Volume, net (Simplebim): 0.00829385 m3; Area, sides, net (Simplebim): 1.44682 m2; Length (Simplebim): 2399.84 mm; Weight, as steel (Simplebim): 65.1067 kg; Width (Simplebim): 150 mm; Height (Simplebim): 150 mm
AVINOR - 07_Fase: F90; 02_Prosjekt: T1; 04_Kontrakt: FDV; 03_Ansvar: FDV; 08_Status: S2; 06_Omrade: TG; 01_Lufthavnkode: ENGM
ePset_LocationTool - Splitting: ORIGINAL

# IfcBeam: L150*150*25 (4)
In: G
Description: L150*150*25; Material: STEEL/S355
ePset_SimplebimBasicQuantities - Weight, as steel (Simplebim): 16.1906 kg; Area, sides, net (Simplebim): 0.19375 m2; Width (Simplebim): 150 mm; Height (Simplebim): 150 mm; Length (Simplebim): 300 mm; Volume, net (Simplebim): 0.0020625 m3
Pset_BeamCommon - LoadBearing: no; Reference: DSB-16695(?)
ePset_LocationTool - Splitting: ORIGINAL
Tekla Common - Grade: S355; Name: STÅLBJELKE; Top elevation: +213.585; Bottom elevation: +213.435; Profile: L150*150*25; Class: 330; Part mark: DSB-16695(?)
ePset_Simplebim - Assembly Level: Leaf
Tekla Quantity - AREA_GROSS: 0.19375 m2; AREA_NET: 0.19375 m2; VOLUME_NET: 0.00206 m3; VOLUME_GROSS: 0.00206 m3; Heigth: 150 mm; Width: 150 mm; Length: 300 mm; WEIGTH_GROSS: 16.1906 kg; WEIGTH_NET: 16.1906 kg
AVINOR - 07_Fase: F90; 02_Prosjekt: T1; 04_Kontrakt: FDV; 03_Ansvar: FDV; 08_Status: S2; 06_Omrade: TG; 01_Lufthavnkode: ENGM
Name | Assembly mark
STÅLBJELKE | SB-8261(?)
3 x STÅLBJELKE | SB-8195(?)

# IfcBeam: L150*75*12, STÅLBJELKE
In: F
Description: L150*75*12; Material: STEEL/S355
ePset_SimplebimBasicQuantities - Area, sides, net (Simplebim): 0.0992368 m2; Height (Simplebim): 256.993 mm; Weight, as steel (Simplebim): 4.18799 kg; Volume, net (Simplebim): 0.000533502 m3; Width (Simplebim): 35 mm; Length (Simplebim): 150 mm
Tekla Common - Part mark: DSB-24274(?); Grade: S355; Name: STÅLBJELKE; Top elevation: +213.555; Bottom elevation: +213.298; Profile: L150*75*12; Class: 330; Assembly mark: SS-7757(?)
Tekla Quantity - AREA_GROSS: 0.12076 m2; Length: 256.993 mm; AREA_NET: 0.09924 m2; VOLUME_GROSS: 0.00066 m3; WEIGTH_GROSS: 5.15645 kg; WEIGTH_NET: 4.18799 kg; Width: 35 mm; Heigth: 150 mm; VOLUME_NET: 0.00053 m3
ePset_Simplebim - Assembly Level: Leaf
Pset_BeamCommon - Reference: DSB-24274(?); LoadBearing: no
ePset_LocationTool - Splitting: ORIGINAL
AVINOR - 07_Fase: F90; 02_Prosjekt: T1; 04_Kontrakt: FDV; 03_Ansvar: FDV; 08_Status: S2; 06_Omrade: TG; 01_Lufthavnkode: ENGM

# IfcBeam: L40*4 (2)
In: G
Description: L40*4
ePset_Simplebim - Assembly Level: Leaf
Pset_BeamCommon - LoadBearing: no; Reference: DSB-24129(?)
ePset_SimplebimBasicQuantities - Weight, as steel (Simplebim): 65.0765 kg; Volume, net (Simplebim): 0.00829 m3; Area, sides, net (Simplebim): 4.36377 m2; Width (Simplebim): 40 mm; Height (Simplebim): 40 mm
ePset_LocationTool - Splitting: RESULT
Tekla Common - Grade: S355; Profile: L40*4; Top elevation: +213.700; Name: STÅLBJELKE; Part mark: DSB-24129(?); Assembly mark: SB-11173(?); Bottom elevation: +213.660; Class: 330
AVINOR - 07_Fase: F90; 02_Prosjekt: T1; 04_Kontrakt: FDV; 03_Ansvar: FDV; 08_Status: S2; 06_Omrade: TG; 01_Lufthavnkode: ENGM
Name | Length (Simplebim) (mm)
STÅLBJELKE | 27269
STÅLBJELKE | 27270

# IfcBeam: L80*8 (3)
In: F
Description: L80*8; Material: STEEL/S355
ePset_LocationTool - Splitting: ORIGINAL
ePset_Simplebim - Assembly Level: Leaf
Pset_BeamCommon - LoadBearing: no
ePset_SimplebimBasicQuantities - Width (Simplebim): 80 mm; Height (Simplebim): 80 mm
Tekla Quantity - Heigth: 80 mm; Width: 80 mm
Tekla Common - Grade: S355; Name: STÅLBJELKE; Bottom elevation: +210.095; Top elevation: +210.175; Assembly mark: SS-7596(?); Profile: L80*8; Class: 330
AVINOR - 07_Fase: F90; 02_Prosjekt: T1; 04_Kontrakt: FDV; 03_Ansvar: FDV; 08_Status: S2; 06_Omrade: TG; 01_Lufthavnkode: ENGM
Name | Reference = Part mark | Volume, net (Simplebim) (m3) | Weight, as steel (Simplebim) (kg) | Length (Simplebim) (mm) | Area, sides, net (Simplebim) (m2) | AREA_NET (m2) | VOLUME_GROSS (m3) | VOLUME_NET (m3) | WEIGTH_NET (kg) | WEIGTH_GROSS (kg) | AREA_GROSS (m2) | Length (mm)
STÅLBJELKE | DSB-22082(?) | 0.00291829 | 22.9086 | 2399.91 | 0.770404 | 0.7704 | 0.00295 | 0.00292 | 22.9086 | 23.1724 | 0.74637 | 2399.91
2 x STÅLBJELKE | DSB-15645(?) | 0.00246123 | 19.3206 | 2024.03 | 0.650123 | 0.65016 | 0.00249 | 0.00246 | 19.3218 | 19.5443 | 0.62951 | 2024.16

# IfcBeam: PL10*110 (2)
In: G
Description: PL10*110; Material: STEEL/S355
Pset_BeamCommon - LoadBearing: no; Reference: DSB-5108(?)
Tekla Common - Grade: S355; Name: STÅLBJELKE; Assembly mark: SB-1530(?); Bottom elevation: +213.170; Part mark: DSB-5108(?); Profile: PL10*110; Class: 330; Top elevation: +213.280
ePset_SimplebimBasicQuantities - Width (Simplebim): 10 mm; Height (Simplebim): 110 mm; Length (Simplebim): 315 mm; Weight, as steel (Simplebim): 2.56695 kg; Volume, net (Simplebim): 0.000327 m3; Area, sides, net (Simplebim): 0.0739 m2
ePset_Simplebim - Assembly Level: Leaf
Tekla Quantity - VOLUME_NET: 0.00034 m3; VOLUME_GROSS: 0.00034 m3; AREA_GROSS: 0.03465 m2; Width: 10 mm; Heigth: 110 mm; Length: 315 mm; WEIGTH_NET: 2.56695 kg; WEIGTH_GROSS: 2.72003 kg; AREA_NET: 0.0739 m2
ePset_LocationTool - Splitting: ORIGINAL
AVINOR - 07_Fase: F90; 02_Prosjekt: T1; 04_Kontrakt: FDV; 03_Ansvar: FDV; 08_Status: S2; 06_Omrade: TG; 01_Lufthavnkode: ENGM

# IfcBeam: PL10*138 (4)
In: F
Description: PL10*138; Material: STEEL/S355
Pset_BeamCommon - Reference: DSB-17317(?); LoadBearing: no
ePset_LocationTool - Splitting: ORIGINAL
ePset_SimplebimBasicQuantities - Volume, net (Simplebim): 0.000189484 m3; Width (Simplebim): 137.831 mm; Length (Simplebim): 137.837 mm; Area, sides, net (Simplebim): 0.0433454 m2; Weight, as steel (Simplebim): 1.48745 kg; Height (Simplebim): 10 mm
ePset_Simplebim - Assembly Level: Leaf
Tekla Common - Grade: S355; Name: STÅLBJELKE; Part mark: DSB-17317(?); Assembly mark: SS-7596(?); Class: 330; Profile: PL10*138
Tekla Quantity - AREA_NET: 0.04335 m2; VOLUME_GROSS: 0.00019 m3; VOLUME_NET: 0.00019 m3; Heigth: 137.831 mm; Length: 137.837 mm; Width: 10 mm; AREA_GROSS: 0.019 m2; WEIGTH_NET: 1.48745 kg; WEIGTH_GROSS: 1.49136 kg
AVINOR - 07_Fase: F90; 02_Prosjekt: T1; 04_Kontrakt: FDV; 03_Ansvar: FDV; 08_Status: S2; 06_Omrade: TG; 01_Lufthavnkode: ENGM
Name | Bottom elevation | Top elevation
2 x STÅLBJELKE | +212.975 | +212.985
2 x STÅLBJELKE | +213.625 | +213.635

# IfcBeam: PL10*160 (14)
Description: PL10*160
Tekla Quantity - WEIGTH_NET: 3.2656 kg; WEIGTH_GROSS: 3.2656 kg; AREA_NET: 0.0916 m2; Width: 10 mm; Heigth: 160 mm; Length: 260 mm; VOLUME_NET: 0.00042 m3; VOLUME_GROSS: 0.00042 m3
ePset_SimplebimBasicQuantities - Weight, as steel (Simplebim): 3.2656 kg; Width (Simplebim): 10 mm; Length (Simplebim): 160 mm; Height (Simplebim): 260 mm; Volume, net (Simplebim): 0.000416 m3
Tekla Common - Name: STÅLBJELKE; Profile: PL10*160; Class: 330
ePset_LocationTool - Splitting: ORIGINAL
ePset_Simplebim - Assembly Level: Leaf
Pset_BeamCommon - LoadBearing: no
AVINOR - 07_Fase: F90; 02_Prosjekt: T1; 04_Kontrakt: FDV; 03_Ansvar: FDV; 08_Status: S2; 06_Omrade: TG; 01_Lufthavnkode: ENGM
Name | In | Material | AREA_GROSS (m2) | Area, sides, net (Simplebim) (m2) | Bottom elevation | Assembly mark | Grade | Part mark = Reference | Top elevation | 05_ID-nummer
4 x STÅLBJELKE | G | STEEL/S355J0 | 0.0916 | 0.0916 | +213.292 | SB-12403(?) | S355J0 | DSB-0(?) | +213.552
10 x STÅLBJELKE | F | STEEL/S355 | 0.0416 | 0.0915999 | +209.770 | SB-1554(?) | S355 | DSB-13648(?) | +210.030 | +TA=223.002

# IfcBeam: PL10*179 (3)
In: G
Description: PL10*179; Material: STEEL/S355
Tekla Quantity - WEIGTH_GROSS: 9.42153 kg; WEIGTH_NET: 9.24581 kg; AREA_NET: 0.2541 m2; VOLUME_GROSS: 0.00119 m3; Width: 10 mm; Heigth: 179 mm; Length: 670.5 mm; AREA_GROSS: 0.12002 m2; VOLUME_NET: 0.00118 m3
ePset_LocationTool - Splitting: ORIGINAL
ePset_Simplebim - Assembly Level: Leaf
Pset_BeamCommon - Reference: DSB-13718(?); LoadBearing: no
ePset_SimplebimBasicQuantities - Area, sides, net (Simplebim): 0.254098 m2; Weight, as steel (Simplebim): 9.24581 kg; Volume, net (Simplebim): 0.00117781 m3; Width (Simplebim): 10 mm; Height (Simplebim): 179 mm; Length (Simplebim): 670.5 mm
Tekla Common - Grade: S355; Part mark: DSB-13718(?); Name: STÅLBJELKE; Profile: PL10*179; Assembly mark: SB-8348(?); Bottom elevation: +213.380; Top elevation: +213.559; Class: 330
AVINOR - 07_Fase: F90; 02_Prosjekt: T1; 04_Kontrakt: FDV; 03_Ansvar: FDV; 08_Status: S2; 06_Omrade: TG; 01_Lufthavnkode: ENGM

# IfcBeam: PL10*180 (6)
In: F
Description: PL10*180; Material: STEEL/S355
Tekla Common - Grade: S355; Assembly mark: SB-1554(?); Name: STÅLBJELKE; Profile: PL10*180; Class: 330; Bottom elevation: +209.760; Top elevation: +209.770
AVINOR - 07_Fase: F90; 02_Prosjekt: T1; 04_Kontrakt: FDV; 03_Ansvar: FDV; 08_Status: S2; 05_ID-nummer: +TA=223.002; 06_Omrade: TG; 01_Lufthavnkode: ENGM
ePset_Simplebim - Assembly Level: Leaf
Pset_BeamCommon - LoadBearing: no
ePset_LocationTool - Splitting: ORIGINAL
ePset_SimplebimBasicQuantities - Width (Simplebim): 180 mm; Height (Simplebim): 10 mm
Tekla Quantity - Heigth: 180 mm; Width: 10 mm
Name | Part mark = Reference | Area, sides, net (Simplebim) (m2) | Length (Simplebim) (mm) = Length (mm) | Weight, as steel (Simplebim) (kg) = WEIGTH_NET (kg) | Volume, net (Simplebim) (m3) | AREA_GROSS (m2) | AREA_NET (m2) | VOLUME_NET (m3) | VOLUME_GROSS (m3) | WEIGTH_GROSS (kg)
STÅLBJELKE | DSB-5073(?) | 0.299056 | 777.524 | 10.9863 | 0.00139953 | 0.13995 | 0.29906 | 0.0014 | 0.00141 | 10.9864
2 x STÅLBJELKE | DSB-13647(?) | 0.297 | 772.114 | 10.9099 | 0.00138979 | 0.13898 | 0.297 | 0.00139 | 0.00139 | 10.91
STÅLBJELKE | DSB-5074(?) | 0.701226 | 1835.87 | 25.9407 | 0.00330454 | 0.33046 | 0.70123 | 0.0033 | 0.0033 | 25.9408
STÅLBJELKE | DSB-5075(?) | 0.0784986 | 197.109 | 2.78505 | 0.000354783 | 0.03548 | 0.0785 | 0.00035 | 0.00035 | 2.78515
STÅLBJELKE | DSB-5076(?) | 0.913661 | 2394.91 | 33.8399 | 0.00431081 | 0.43108 | 0.91366 | 0.00431 | 0.00431 | 33.84

# IfcBeam: PL10*189, STÅLBJELKE
In: G
Description: PL10*189; Material: STEEL/S355
ePset_SimplebimBasicQuantities - Weight, as steel (Simplebim): 2.01501 kg; Volume, net (Simplebim): 0.000256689 m3; Area, sides, net (Simplebim): 0.0581977 m2; Length (Simplebim): 188.863 mm; Height (Simplebim): 199.948 mm; Width (Simplebim): 10 mm
Pset_BeamCommon - Reference: DSB-13532(?); LoadBearing: no
ePset_Simplebim - Assembly Level: Leaf
ePset_LocationTool - Splitting: ORIGINAL
Tekla Common - Grade: S355; Assembly mark: SB-8261(?); Name: STÅLBJELKE; Profile: PL10*189; Bottom elevation: +213.170; Part mark: DSB-13532(?); Top elevation: +213.370; Class: 330
AVINOR - 07_Fase: F90; 02_Prosjekt: T1; 04_Kontrakt: FDV; 03_Ansvar: FDV; 08_Status: S2; 06_Omrade: TG; 01_Lufthavnkode: ENGM
Tekla Quantity - Heigth: 188.863 mm; AREA_NET: 0.0582 m2; WEIGTH_NET: 2.01501 kg; WEIGTH_GROSS: 2.96437 kg; Length: 199.948 mm; VOLUME_NET: 0.00026 m3; VOLUME_GROSS: 0.00026 m3; Width: 10 mm; AREA_GROSS: 0.03776 m2

# IfcBeam: PL10*460 (2)
In: G
Description: PL10*460; Material: STEEL/S355
Tekla Quantity - WEIGTH_NET: 24.335 kg; AREA_GROSS: 0.46 m2; VOLUME_NET: 0.0031 m3; VOLUME_GROSS: 0.0031 m3; WEIGTH_GROSS: 36.11 kg; Width: 10 mm; Heigth: 460 mm; Length: 1000 mm; AREA_NET: 0.64664 m2
Pset_BeamCommon - Reference: DSB-13444(?); LoadBearing: no
ePset_SimplebimBasicQuantities - Height (Simplebim): 460 mm; Weight, as steel (Simplebim): 24.335 kg; Volume, net (Simplebim): 0.0031 m3; Area, sides, net (Simplebim): 0.64664 m2; Width (Simplebim): 10 mm; Length (Simplebim): 1000 mm
ePset_LocationTool - Splitting: ORIGINAL
ePset_Simplebim - Assembly Level: Leaf
Tekla Common - Grade: S355; Part mark: DSB-13444(?); Top elevation: +213.550; Name: STÅLBJELKE; Profile: PL10*460; Class: 330; Bottom elevation: +213.090; Assembly mark: SB-7852(?)
AVINOR - 07_Fase: F90; 02_Prosjekt: T1; 04_Kontrakt: FDV; 03_Ansvar: FDV; 08_Status: S2; 06_Omrade: TG; 01_Lufthavnkode: ENGM

# IfcBeam: PL10*76 (5)
In: G
Description: PL10*76; Material: STEEL/S355
Tekla Common - Grade: S355; Part mark: DSB-5056(?); Name: STÅLBJELKE; Assembly mark: SB-1530(?); Bottom elevation: +213.170; Top elevation: +213.390; Profile: PL10*76; Class: 330
ePset_SimplebimBasicQuantities - Area, sides, net (Simplebim): 0.0382388 m2; Volume, net (Simplebim): 0.000162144 m3; Height (Simplebim): 220.8 mm; Weight, as steel (Simplebim): 1.27283 kg; Width (Simplebim): 10 mm; Length (Simplebim): 75.5 mm
ePset_Simplebim - Assembly Level: Leaf
Pset_BeamCommon - Reference: DSB-5056(?); LoadBearing: no
ePset_LocationTool - Splitting: ORIGINAL
AVINOR - 07_Fase: F90; 02_Prosjekt: T1; 04_Kontrakt: FDV; 03_Ansvar: FDV; 08_Status: S2; 06_Omrade: TG; 01_Lufthavnkode: ENGM
Tekla Quantity - WEIGTH_NET: 1.27283 kg; Length: 220.8 mm; AREA_GROSS: 0.01667 m2; VOLUME_GROSS: 0.00015 m3; VOLUME_NET: 0.00015 m3; WEIGTH_GROSS: 1.30863 kg; Width: 10 mm; Heigth: 75.5 mm; AREA_NET: 0.03824 m2

# IfcBeam: PL10*86, STÅLBJELKE
In: G
Description: PL10*86; Material: STEEL/S355
ePset_LocationTool - Splitting: ORIGINAL
Pset_BeamCommon - LoadBearing: no; Reference: DSB-13529(?)
Tekla Common - Grade: S355; Name: STÅLBJELKE; Bottom elevation: +213.395; Profile: PL10*86; Top elevation: +213.685; Assembly mark: SB-8258(?); Part mark: DSB-13529(?); Class: 330
ePset_Simplebim - Assembly Level: Leaf
Tekla Quantity - WEIGTH_GROSS: 1.95779 kg; AREA_NET: 0.05658 m2; AREA_GROSS: 0.02494 m2; Width: 10 mm; Heigth: 86 mm; Length: 290 mm; WEIGTH_NET: 1.92876 kg; VOLUME_GROSS: 0.00024 m3; VOLUME_NET: 0.00024 m3
ePset_SimplebimBasicQuantities - Area, sides, net (Simplebim): 0.0565765 m2; Weight, as steel (Simplebim): 1.92876 kg; Length (Simplebim): 100.16 mm; Volume, net (Simplebim): 0.000245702 m3; Width (Simplebim): 10 mm; Height (Simplebim): 289.638 mm
AVINOR - 07_Fase: F90; 02_Prosjekt: T1; 04_Kontrakt: FDV; 03_Ansvar: FDV; 08_Status: S2; 06_Omrade: TG; 01_Lufthavnkode: ENGM

# IfcBeam: PL100*10, STÅLBJELKE
In: G
Description: PL100*10; Material: STEEL/S355
ePset_SimplebimBasicQuantities - Area, sides, net (Simplebim): 0.0570287 m2; Weight, as steel (Simplebim): 1.91908 kg; Width (Simplebim): 10 mm; Length (Simplebim): 100 mm; Height (Simplebim): 253.032 mm; Volume, net (Simplebim): 0.000244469 m3
ePset_LocationTool - Splitting: ORIGINAL
Pset_BeamCommon - Reference: DSB-13630(?); LoadBearing: no
ePset_Simplebim - Assembly Level: Leaf
Tekla Quantity - WEIGTH_GROSS: 1.9863 kg; AREA_GROSS: 0.05719 m2; WEIGTH_NET: 1.91908 kg; Width: 10 mm; Heigth: 100 mm; Length: 253.032 mm; VOLUME_GROSS: 0.00024 m3; VOLUME_NET: 0.00024 m3; AREA_NET: 0.05703 m2
Tekla Common - Grade: S355; Name: STÅLBJELKE; Bottom elevation: +213.160; Part mark: DSB-13630(?); Top elevation: +213.380; Assembly mark: SB-8258(?); Profile: PL100*10; Class: 330
AVINOR - 07_Fase: F90; 02_Prosjekt: T1; 04_Kontrakt: FDV; 03_Ansvar: FDV; 08_Status: S2; 06_Omrade: TG; 01_Lufthavnkode: ENGM

# IfcBeam: PL145*10 (4)
In: G
Description: PL145*10; Material: STEEL/S355
Pset_BeamCommon - Reference: DSB-13531(?); LoadBearing: no
ePset_LocationTool - Splitting: ORIGINAL
Tekla Quantity - Length: 95.4991 mm; WEIGTH_NET: 1.08702 kg; WEIGTH_GROSS: 1.08702 kg; AREA_GROSS: 0.0325 m2; AREA_NET: 0.0325 m2; VOLUME_NET: 0.00013 m3; VOLUME_GROSS: 0.00013 m3; Width: 10 mm; Heigth: 145 mm
ePset_Simplebim - Assembly Level: Leaf
ePset_SimplebimBasicQuantities - Volume, net (Simplebim): 0.000138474 m3; Length (Simplebim): 95.4991 mm; Weight, as steel (Simplebim): 1.08702 kg; Area, sides, net (Simplebim): 0.0325047 m2; Width (Simplebim): 10 mm; Height (Simplebim): 145 mm
Tekla Common - Grade: S355; Assembly mark: SB-8261(?); Profile: PL145*10; Name: STÅLBJELKE; Top elevation: +213.555; Part mark: DSB-13531(?); Bottom elevation: +213.410; Class: 330
AVINOR - 07_Fase: F90; 02_Prosjekt: T1; 04_Kontrakt: FDV; 03_Ansvar: FDV; 08_Status: S2; 06_Omrade: TG; 01_Lufthavnkode: ENGM

# IfcBeam: PL148.5*10 (12)
In: G
Description: PL148.5*10; Material: STEEL/S355
Tekla Common - Grade: S355; Part mark: DSB-13446(?); Assembly mark: SB-8195(?); Name: STÅLBJELKE; Profile: PL148.5*10; Top elevation: +213.559; Bottom elevation: +213.410; Class: 330
Pset_BeamCommon - Reference: DSB-13446(?); LoadBearing: no
Tekla Quantity - AREA_GROSS: 0.02714 m2; AREA_NET: 0.02714 m2; WEIGTH_NET: 0.88885 kg; WEIGTH_GROSS: 0.88885 kg; VOLUME_GROSS: 0.0001 m3; VOLUME_NET: 0.0001 m3; Length: 76.2491 mm; Width: 10 mm; Heigth: 148.5 mm
ePset_LocationTool - Splitting: ORIGINAL
ePset_Simplebim - Assembly Level: Leaf
ePset_SimplebimBasicQuantities - Weight, as steel (Simplebim): 0.888854 kg; Area, sides, net (Simplebim): 0.027141 m2; Length (Simplebim): 76.2491 mm; Volume, net (Simplebim): 0.00011323 m3; Width (Simplebim): 10 mm; Height (Simplebim): 148.5 mm
AVINOR - 07_Fase: F90; 02_Prosjekt: T1; 04_Kontrakt: FDV; 03_Ansvar: FDV; 08_Status: S2; 06_Omrade: TG; 01_Lufthavnkode: ENGM

# IfcBeam: PL15*200 (2)
In: G
Description: PL15*200; Material: STEEL/S355
ePset_SimplebimBasicQuantities - Volume, net (Simplebim): 0.00075 m3; Weight, as steel (Simplebim): 5.8875 kg; Area, sides, net (Simplebim): 0.1135 m2; Height (Simplebim): 15 mm; Width (Simplebim): 200 mm; Length (Simplebim): 250 mm
Tekla Quantity - WEIGTH_GROSS: 5.8875 kg; WEIGTH_NET: 5.8875 kg; AREA_GROSS: 0.05 m2; VOLUME_GROSS: 0.00074 m3; VOLUME_NET: 0.00074 m3; AREA_NET: 0.1135 m2; Width: 15 mm; Heigth: 200 mm; Length: 250 mm
ePset_Simplebim - Assembly Level: Leaf
Tekla Common - Grade: S355; Name: STÅLBJELKE; Assembly mark: SB-1530(?); Profile: PL15*200; Part mark: DSB-5124(?); Top elevation: +213.295; Class: 330; Bottom elevation: +213.280
ePset_LocationTool - Splitting: ORIGINAL
AVINOR - 07_Fase: F90; 02_Prosjekt: T1; 04_Kontrakt: FDV; 03_Ansvar: FDV; 08_Status: S2; 06_Omrade: TG; 01_Lufthavnkode: ENGM
Pset_BeamCommon - Reference: DSB-5124(?); LoadBearing: no

# IfcBeam: PL15*75 (4)
In: G
Description: PL15*75; Material: STEEL/S355
Tekla Common - Grade: S355; Name: STÅLBJELKE; Part mark: DSB-13070(?); Class: 330; Bottom elevation: +213.090; Profile: PL15*75; Top elevation: +213.240; Assembly mark: SB-7852(?)
Tekla Quantity - WEIGTH_NET: 1.1775 kg; AREA_NET: 0.02631 m2; VOLUME_GROSS: 0.00015 m3; VOLUME_NET: 0.00015 m3; WEIGTH_GROSS: 1.32469 kg; Width: 15 mm; Heigth: 75 mm; Length: 150 mm; AREA_GROSS: 0.01125 m2
ePset_LocationTool - Splitting: ORIGINAL
Pset_BeamCommon - LoadBearing: no; Reference: DSB-13070(?)
ePset_Simplebim - Assembly Level: Leaf
ePset_SimplebimBasicQuantities - Area, sides, net (Simplebim): 0.0263107 m2; Weight, as steel (Simplebim): 1.1775 kg; Volume, net (Simplebim): 0.00015 m3; Width (Simplebim): 15 mm; Length (Simplebim): 75 mm; Height (Simplebim): 150 mm
AVINOR - 07_Fase: F90; 02_Prosjekt: T1; 04_Kontrakt: FDV; 03_Ansvar: FDV; 08_Status: S2; 06_Omrade: TG; 01_Lufthavnkode: ENGM

# IfcBeam: PL15*95 (4)
In: G
Description: PL15*95; Material: STEEL/S355
Tekla Common - Grade: S355; Name: STÅLBJELKE; Profile: PL15*95; Part mark: DSB-12911(?); Class: 330; Assembly mark: SB-7852(?)
Pset_BeamCommon - LoadBearing: no; Reference: DSB-12911(?)
ePset_Simplebim - Assembly Level: Leaf
ePset_SimplebimBasicQuantities - Weight, as steel (Simplebim): 3.22515 kg; Volume, net (Simplebim): 0.000410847 m3; Height (Simplebim): 15 mm; Width (Simplebim): 95 mm; Length (Simplebim): 364 mm; Area, sides, net (Simplebim): 0.0694177 m2
ePset_LocationTool - Splitting: ORIGINAL
Tekla Quantity - WEIGTH_GROSS: 4.0718 kg; WEIGTH_NET: 3.22515 kg; Width: 15 mm; Heigth: 95 mm; Length: 364 mm; AREA_NET: 0.06942 m2; VOLUME_NET: 0.00042 m3; VOLUME_GROSS: 0.00042 m3; AREA_GROSS: 0.03458 m2
AVINOR - 07_Fase: F90; 02_Prosjekt: T1; 04_Kontrakt: FDV; 03_Ansvar: FDV; 08_Status: S2; 06_Omrade: TG; 01_Lufthavnkode: ENGM
Name | Top elevation | Bottom elevation
2 x STÅLBJELKE | +213.105 | +213.090
2 x STÅLBJELKE | +213.550 | +213.535

# IfcBeam: PL160*10 (11)
In: G
Description: PL160*10; Material: STEEL/S355
Tekla Common - Grade: S355; Profile: PL160*10; Name: STÅLBJELKE; Class: 330
Tekla Quantity - Width: 10 mm; Heigth: 160 mm
ePset_Simplebim - Assembly Level: Leaf
Pset_BeamCommon - LoadBearing: no
ePset_LocationTool - Splitting: ORIGINAL
AVINOR - 07_Fase: F90; 02_Prosjekt: T1; 04_Kontrakt: FDV; 03_Ansvar: FDV; 08_Status: S2; 06_Omrade: TG; 01_Lufthavnkode: ENGM
Name | Top elevation | Bottom elevation | Part mark = Reference | Assembly mark | Volume, net (Simplebim) (m3) | Weight, as steel (Simplebim) (kg) = WEIGTH_NET (kg) | Area, sides, net (Simplebim) (m2) | Width (Simplebim) (mm) | Height (Simplebim) (mm) | Length (Simplebim) (mm) | WEIGTH_GROSS (kg) | AREA_GROSS (m2) = AREA_NET (m2) | VOLUME_GROSS (m3) = VOLUME_NET (m3) | Length (mm)
2 x STÅLBJELKE | +213.550 | +213.390 | DSB-13527(?) | SB-7852(?) | 0.001272 | 9.98519 | 0.2735 | 10 | 160 | 794.999 | 9.98519 | 0.2735 | 0.00127 | 794.999
3 x STÅLBJELKE | +213.410 | +213.400 | DSB-13442(?) | SB-8195(?) | 0.000207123 | 1.62592 | 0.0473957 | 131.904 | 10 | 160 | 1.65671 | 0.0474 | 0.00021 | 131.904
3 x STÅLBJELKE | +213.252 | +213.160 | DSB-13445(?) | SB-8195(?) | 0.000224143 | 1.75952 | 0.0515285 | 147.046 | 10 | 160 | 1.84689 | 0.05153 | 0.00021 | 147.046
3 x STÅLBJELKE | +213.410 | +213.251 | DSB-13441(?) | SB-8195(?) | 0.000294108 | 2.30875 | 0.0668933 | 10 | 192.726 | 160 | 2.42064 | 0.06689 | 0.00029 | 192.726

# IfcBeam: PL160*12 (5)
In: G
Description: PL160*12; Material: STEEL/S355
Tekla Quantity - AREA_GROSS: 0.08133 m2; AREA_NET: 0.08133 m2; Width: 12 mm; Heigth: 160 mm; Length: 232.64 mm; WEIGTH_NET: 3.32539 kg; WEIGTH_GROSS: 3.50635 kg; VOLUME_NET: 0.00042 m3; VOLUME_GROSS: 0.00042 m3
ePset_LocationTool - Splitting: ORIGINAL
Pset_BeamCommon - Reference: DSB-13855(?); LoadBearing: no
ePset_Simplebim - Assembly Level: Leaf
Tekla Common - Grade: S355; Name: STÅLBJELKE; Part mark: DSB-13855(?); Class: 330; Profile: PL160*12; Top elevation: +213.240; Bottom elevation: +213.073
AVINOR - 07_Fase: F90; 02_Prosjekt: T1; 04_Kontrakt: FDV; 03_Ansvar: FDV; 08_Status: S2; 06_Omrade: TG; 01_Lufthavnkode: ENGM
ePset_SimplebimBasicQuantities - Weight, as steel (Simplebim): 3.32539 kg; Height (Simplebim): 232.64 mm; Volume, net (Simplebim): 0.000423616 m3; Width (Simplebim): 12 mm; Length (Simplebim): 160 mm; Area, sides, net (Simplebim): 0.0813308 m2
Name | Assembly mark
STÅLBJELKE | SB-8213(?)
STÅLBJELKE | SB-8212(?)
3 x STÅLBJELKE | SB-8195(?)

# IfcBeam: PL170*10 (2)
In: G
Description: PL170*10; Material: STEEL/S355
Pset_BeamCommon - Reference: DSB-13530(?); LoadBearing: no
ePset_LocationTool - Splitting: ORIGINAL
Tekla Common - Grade: S355; Profile: PL170*10; Assembly mark: SB-8261(?); Name: STÅLBJELKE; Top elevation: +213.555; Part mark: DSB-13530(?); Bottom elevation: +213.385; Class: 330
ePset_SimplebimBasicQuantities - Weight, as steel (Simplebim): 1.27443 kg; Length (Simplebim): 95.4991 mm; Volume, net (Simplebim): 0.000162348 m3; Area, sides, net (Simplebim): 0.0377797 m2; Width (Simplebim): 10 mm; Height (Simplebim): 170 mm
ePset_Simplebim - Assembly Level: Leaf
Tekla Quantity - WEIGTH_GROSS: 1.27443 kg; WEIGTH_NET: 1.27443 kg; Length: 95.4991 mm; VOLUME_GROSS: 0.00015 m3; VOLUME_NET: 0.00015 m3; Width: 10 mm; Heigth: 170 mm; AREA_GROSS: 0.03778 m2; AREA_NET: 0.03778 m2
AVINOR - 07_Fase: F90; 02_Prosjekt: T1; 04_Kontrakt: FDV; 03_Ansvar: FDV; 08_Status: S2; 06_Omrade: TG; 01_Lufthavnkode: ENGM

# IfcBeam: PL190*10 (7)
In: G
Description: PL190*10; Material: STEEL/S355
Tekla Common - Grade: S355; Top elevation: +213.530; Name: STÅLBJELKE; Profile: PL190*10; Part mark: DSB-13526(?); Class: 330; Bottom elevation: +213.090; Assembly mark: SB-7852(?)
ePset_LocationTool - Splitting: ORIGINAL
ePset_Simplebim - Assembly Level: Leaf
Pset_BeamCommon - LoadBearing: no; Reference: DSB-13526(?)
Tekla Quantity - AREA_NET: 0.1798 m2; AREA_GROSS: 0.1798 m2; Length: 439.999 mm; WEIGTH_GROSS: 6.56259 kg; WEIGTH_NET: 6.56259 kg; Width: 10 mm; Heigth: 190 mm; VOLUME_GROSS: 0.00083 m3; VOLUME_NET: 0.00084 m3
AVINOR - 07_Fase: F90; 02_Prosjekt: T1; 04_Kontrakt: FDV; 03_Ansvar: FDV; 08_Status: S2; 06_Omrade: TG; 01_Lufthavnkode: ENGM
ePset_SimplebimBasicQuantities - Weight, as steel (Simplebim): 6.56259 kg; Area, sides, net (Simplebim): 0.1798 m2; Volume, net (Simplebim): 0.000835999 m3; Height (Simplebim): 439.999 mm; Width (Simplebim): 10 mm; Length (Simplebim): 190 mm

# IfcBeam: PL190*15 (2)
In: G
Description: PL190*15; Material: STEEL/S355
Tekla Common - Grade: S355; Name: STÅLBJELKE; Profile: PL190*15; Part mark: DSB-12942(?); Class: 330; Bottom elevation: +213.090; Top elevation: +213.250; Assembly mark: SB-7852(?)
ePset_Simplebim - Assembly Level: Leaf
ePset_LocationTool - Splitting: ORIGINAL
Tekla Quantity - Length: 159.999 mm; AREA_GROSS: 0.0713 m2; AREA_NET: 0.0713 m2; Width: 15 mm; Heigth: 190 mm; WEIGTH_GROSS: 3.57959 kg; WEIGTH_NET: 3.57959 kg; VOLUME_GROSS: 0.00045 m3; VOLUME_NET: 0.00045 m3
ePset_SimplebimBasicQuantities - Height (Simplebim): 159.999 mm; Weight, as steel (Simplebim): 3.57959 kg; Area, sides, net (Simplebim): 0.0712997 m2; Width (Simplebim): 15 mm; Length (Simplebim): 190 mm; Volume, net (Simplebim): 0.000455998 m3
AVINOR - 07_Fase: F90; 02_Prosjekt: T1; 04_Kontrakt: FDV; 03_Ansvar: FDV; 08_Status: S2; 06_Omrade: TG; 01_Lufthavnkode: ENGM
Pset_BeamCommon - Reference: DSB-12942(?); LoadBearing: no

# IfcBeam: PL20*230 (2)
In: F
Description: PL20*230; Material: STEEL/S355
Pset_BeamCommon - Reference: DSB-13196(?); LoadBearing: no
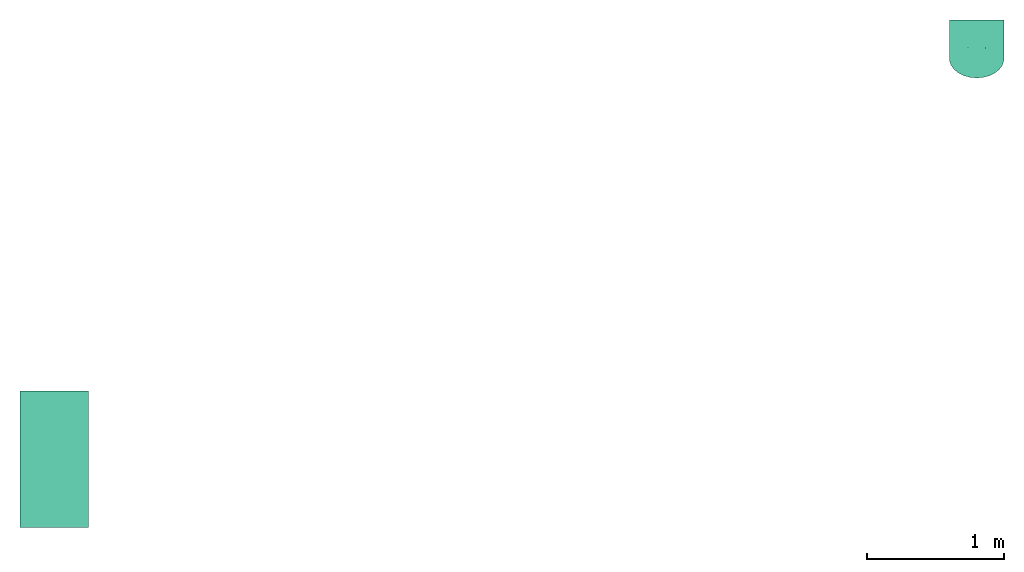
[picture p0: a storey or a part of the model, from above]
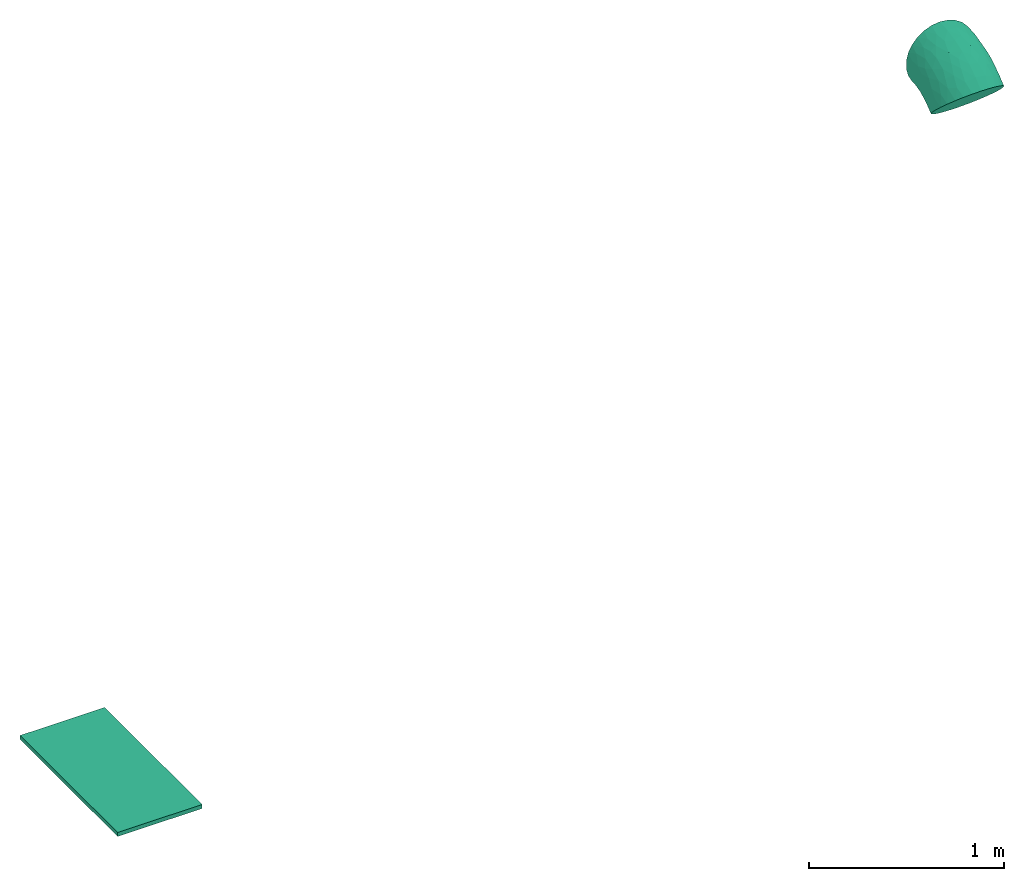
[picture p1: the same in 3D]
Properties of the parts of a building model (IFC2X3), part 2 of 11

# IfcBeam: PL20*230 (2)
Tekla Common - Grade: S355; Part mark: DSB-13196(?); Name: STÅLBJELKE; Assembly mark: SS-7548(?); Profile: PL20*230; Bottom elevation: +213.047; Top elevation: +213.067; Class: 330
ePset_Simplebim - Assembly Level: Leaf
ePset_LocationTool - Splitting: ORIGINAL
Tekla Quantity - AREA_GROSS: 0.0552 m2; AREA_NET: 0.1292 m2; WEIGTH_NET: 8.6664 kg; WEIGTH_GROSS: 8.6664 kg; VOLUME_GROSS: 0.0011 m3; VOLUME_NET: 0.0011 m3; Width: 20 mm; Heigth: 230 mm; Length: 240 mm
ePset_SimplebimBasicQuantities - Volume, net (Simplebim): 0.001104 m3; Area, sides, net (Simplebim): 0.1292 m2; Weight, as steel (Simplebim): 8.6664 kg; Height (Simplebim): 20 mm; Length (Simplebim): 240 mm; Width (Simplebim): 230 mm
AVINOR - 07_Fase: F90; 02_Prosjekt: T1; 04_Kontrakt: FDV; 03_Ansvar: FDV; 08_Status: S2; 06_Omrade: TG; 01_Lufthavnkode: ENGM

# IfcBeam: PL20*400, STÅLBJELKE
In: G
Description: PL20*400; Material: STEEL/S355
Tekla Quantity - Length: 1000 mm; AREA_GROSS: 0.4 m2; VOLUME_GROSS: 0.008 m3; VOLUME_NET: 0.008 m3; AREA_NET: 0.89122 m2; WEIGTH_NET: 62.8 kg; WEIGTH_GROSS: 62.8 kg; Width: 320 mm; Heigth: 400 mm
Tekla Common - Grade: S355; Part mark: DSB-13245(?); Name: STÅLBJELKE; Profile: PL20*400; Top elevation: +213.390; Class: 330; Bottom elevation: +213.070; Assembly mark: SB-7852(?)
Pset_BeamCommon - Reference: DSB-13245(?); LoadBearing: no
ePset_LocationTool - Splitting: ORIGINAL
ePset_Simplebim - Assembly Level: Leaf
ePset_SimplebimBasicQuantities - Length (Simplebim): 1000 mm; Volume, net (Simplebim): 0.008 m3; Weight, as steel (Simplebim): 62.8 kg; Area, sides, net (Simplebim): 0.891224 m2; Height (Simplebim): 320 mm; Width (Simplebim): 400 mm
AVINOR - 07_Fase: F90; 02_Prosjekt: T1; 04_Kontrakt: FDV; 03_Ansvar: FDV; 08_Status: S2; 06_Omrade: TG; 01_Lufthavnkode: ENGM

# IfcBeam: PL200*10 (3)
In: G
Description: PL200*10; Material: STEEL/S355
ePset_SimplebimBasicQuantities - Length (Simplebim): 200 mm
ePset_LocationTool - Splitting: ORIGINAL
ePset_Simplebim - Assembly Level: Leaf
Pset_BeamCommon - LoadBearing: no
Tekla Quantity - Width: 10 mm; Heigth: 200 mm
Tekla Common - Grade: S355; Assembly mark: SB-8261(?); Name: STÅLBJELKE; Profile: PL200*10; Class: 330
AVINOR - 07_Fase: F90; 02_Prosjekt: T1; 04_Kontrakt: FDV; 03_Ansvar: FDV; 08_Status: S2; 06_Omrade: TG; 01_Lufthavnkode: ENGM
Name | Volume, net (Simplebim) (m3) | Area, sides, net (Simplebim) (m2) | Weight, as steel (Simplebim) (kg) = WEIGTH_NET (kg) | Width (Simplebim) (mm) | Height (Simplebim) (mm) | Reference = Part mark | VOLUME_NET (m3) | AREA_NET (m2) | WEIGTH_GROSS (kg) | VOLUME_GROSS (m3) | Length (mm) | AREA_GROSS (m2) | Bottom elevation | Top elevation
STÅLBJELKE | 0.000471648 | 0.105513 | 3.70244 | 10 | 244.387 | DSB-13636(?) | 0.00047 | 0.10551 | 3.83688 | 0.00048 | 244.387 | 0.10572 | +213.160 | +213.370
STÅLBJELKE | 0.000236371 | 0.0537213 | 1.85552 | 120.132 | 10 | DSB-13533(?) | 0.00024 | 0.05372 | 1.88606 | 0.00024 | 120.132 | 0.05372 | +213.370 | +213.410
STÅLBJELKE | 0.000255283 | 0.0576258 | 2.00397 | 128.283 | 10 | DSB-13534(?) | 0.00026 | 0.05763 | 2.01404 | 0.00026 | 128.283 | 0.05763 | +213.400 | +213.410

# IfcBeam: PL3*100 (2)
In: G
Description: PL3*100; Material: STEEL/S355
ePset_LocationTool - Splitting: ORIGINAL
Pset_BeamCommon - Reference: DSB-23919(?); LoadBearing: no
Tekla Common - Grade: S355; Part mark: DSB-23919(?); Name: STÅLBJELKE; Profile: PL3*100; Bottom elevation: +213.067; Class: 330; Top elevation: +213.070; Assembly mark: SB-7852(?)
ePset_Simplebim - Assembly Level: Leaf
ePset_SimplebimBasicQuantities - Area, sides, net (Simplebim): 0.0212 m2; Weight, as steel (Simplebim): 0.2355 kg; Height (Simplebim): 3 mm; Length (Simplebim): 100 mm; Width (Simplebim): 100 mm; Volume, net (Simplebim): 0.00003 m3
AVINOR - 07_Fase: F90; 02_Prosjekt: T1; 04_Kontrakt: FDV; 03_Ansvar: FDV; 08_Status: S2; 06_Omrade: TG; 01_Lufthavnkode: ENGM
Tekla Quantity - AREA_NET: 0.0212 m2; WEIGTH_GROSS: 0.2355 kg; WEIGTH_NET: 0.2355 kg; Width: 3 mm; Heigth: 100 mm; Length: 100 mm; VOLUME_GROSS: 0.00003 m3; VOLUME_NET: 0.00003 m3; AREA_GROSS: 0.01 m2

# IfcBeam: PL307*10 (16)
In: G
Description: PL307*10; Material: STEEL/S355
Pset_BeamCommon - Reference: DSB-13443(?); LoadBearing: no
ePset_LocationTool - Splitting: ORIGINAL
ePset_SimplebimBasicQuantities - Volume, net (Simplebim): 0.000234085 m3; Length (Simplebim): 76.2491 mm; Weight, as steel (Simplebim): 1.83756 kg; Width (Simplebim): 10 mm; Height (Simplebim): 307 mm; Area, sides, net (Simplebim): 0.0544819 m2
Tekla Common - Grade: S355; Part mark: DSB-13443(?); Name: STÅLBJELKE; Bottom elevation: +213.252; Top elevation: +213.559; Profile: PL307*10; Class: 330
ePset_Simplebim - Assembly Level: Leaf
Tekla Quantity - VOLUME_NET: 0.00023 m3; VOLUME_GROSS: 0.00023 m3; Length: 76.2491 mm; Width: 10 mm; Heigth: 307 mm; AREA_GROSS: 0.05448 m2; AREA_NET: 0.05448 m2; WEIGTH_NET: 1.83756 kg; WEIGTH_GROSS: 1.83756 kg
AVINOR - 07_Fase: F90; 02_Prosjekt: T1; 04_Kontrakt: FDV; 03_Ansvar: FDV; 08_Status: S2; 06_Omrade: TG; 01_Lufthavnkode: ENGM
Name | Assembly mark
2 x STÅLBJELKE | SB-8213(?)
2 x STÅLBJELKE | SB-8212(?)
12 x STÅLBJELKE | SB-8195(?)

# IfcBeam: PL400*20 (5)
In: G
Description: PL400*20
Pset_BeamCommon - LoadBearing: no
Tekla Common - Grade: S355; Name: STÅLBJELKE; Profile: PL400*20; Class: 330; Assembly mark: SB-7852(?)
ePset_Simplebim - Assembly Level: Leaf
ePset_SimplebimBasicQuantities - Height (Simplebim): 20 mm; Width (Simplebim): 400 mm
AVINOR - 07_Fase: F90; 02_Prosjekt: T1; 04_Kontrakt: FDV; 03_Ansvar: FDV; 08_Status: S2; 06_Omrade: TG; 01_Lufthavnkode: ENGM
Name | Material | Reference = Part mark | Bottom elevation | Top elevation | Splitting | Volume, net (Simplebim) (m3) | Weight, as steel (Simplebim) (kg) | Length (Simplebim) (mm) | Area, sides, net (Simplebim) (m2) | AREA_GROSS (m2) | VOLUME_GROSS (m3) | VOLUME_NET (m3) | AREA_NET (m2) | WEIGTH_NET (kg) | Width (mm) | Heigth (mm) | Length (mm) | WEIGTH_GROSS (kg)
STÅLBJELKE | STEEL/S355 | DSB-13190(?) | +213.370 | +213.390 | ORIGINAL | 0.00625999 | 49.1409 | 794.999 | 0.679695 | 0.6838 | 0.00636 | 0.00626 | 0.6797 | 49.1409 | 20 | 400 | 794.999 | 49.9259
STÅLBJELKE | STEEL/S355 | DSB-13274(?) | +213.550 | +213.570 | ORIGINAL | 0.00635999 | 49.9259 | 794.999 | 0.683799 | 0.6838 | 0.00636 | 0.00636 | 0.6838 | 49.9259 | 20 | 400 | 794.999 | 49.9259
STÅLBJELKE | STEEL/S355 | DSB-13246(?) | +213.550 | +213.570 | ORIGINAL | 0.00799999 | 62.7999 | 999.999 | 0.855999 | 0.856 | 0.008 | 0.008 | 0.856 | 62.7999 | 20 | 400 | 999.999 | 62.7999
STÅLBJELKE |  | DSB-18186(?) | +213.070 | +213.090 | RESULT | 0.0835944 | 656.216 | 10485 | 8.79716
STÅLBJELKE |  | DSB-13187(?) | +213.550 | +213.570 | RESULT | 0.0835944 | 656.216 | 10485 | 8.79716

# IfcBeam: PL460*10 (2)
In: G
Description: PL460*10
Pset_BeamCommon - LoadBearing: no; Reference: DSB-13528(?)
ePset_Simplebim - Assembly Level: Leaf
ePset_SimplebimBasicQuantities - Width (Simplebim): 10 mm; Height (Simplebim): 460 mm; Length (Simplebim): 10485 mm; Volume, net (Simplebim): 0.0482321 m3; Area, sides, net (Simplebim): 9.86533 m2; Weight, as steel (Simplebim): 378.622 kg
ePset_LocationTool - Splitting: RESULT
AVINOR - 07_Fase: F90; 02_Prosjekt: T1; 04_Kontrakt: FDV; 03_Ansvar: FDV; 08_Status: S2; 06_Omrade: TG; 01_Lufthavnkode: ENGM
Tekla Common - Grade: S355; Top elevation: +213.550; Profile: PL460*10; Name: STÅLBJELKE; Part mark: DSB-13528(?); Class: 330; Bottom elevation: +213.090; Assembly mark: SB-7852(?)

# IfcBeam: PL5*140 (5)
Description: PL5*140
Tekla Quantity - Width: 5 mm
ePset_Simplebim - Assembly Level: Leaf
Tekla Common - Name: STÅLBJELKE; Class: 330; Profile: PL5*140
ePset_LocationTool - Splitting: ORIGINAL
ePset_SimplebimBasicQuantities - Width (Simplebim): 5 mm
AVINOR - 07_Fase: F90; 02_Prosjekt: T1; 04_Kontrakt: FDV; 03_Ansvar: FDV; 08_Status: S2; 06_Omrade: TG; 01_Lufthavnkode: ENGM
Pset_BeamCommon - LoadBearing: no
Name | In | Material | VOLUME_NET (m3) | VOLUME_GROSS (m3) | AREA_GROSS (m2) | WEIGTH_GROSS (kg) = WEIGTH_NET (kg) | AREA_NET (m2) | Heigth (mm) | Length (mm) | Grade | Top elevation | Part mark = Reference | Assembly mark | Bottom elevation | Weight, as steel (Simplebim) (kg) | Volume, net (Simplebim) (m3) | Area, sides, net (Simplebim) (m2) | Length (Simplebim) (mm) | Height (Simplebim) (mm)
STÅLBJELKE | F | STEEL/S355 | 0.0014 | 0.00141 | 0.28299 | 11.1074 | 0.58762 | 139.807 | 2024.16 | S355 | +213.758 | DSB-21134(?) | SS-7596(?) | +213.635 | 11.1074 | 0.00141496 | 0.587622 | 2024.16 | 139.807
4 x STÅLBJELKE | G | STEEL/S355J0 | 0.00017 | 0.00017 | 0.07593 | 1.41222 | 0.07593 | 140 | 257 | S355J0 | +213.550 | DSB-0(?) | SB-12403(?) | +213.293 | 1.41221 | 0.0001799 | 0.07593 | 140 | 257

# IfcBeam: PL5*405, STÅLBJELKE
In: F
Description: PL5*405; Material: STEEL/S355
Tekla Quantity - AREA_NET: 1.6645 m2; WEIGTH_NET: 32.1892 kg; WEIGTH_GROSS: 32.1892 kg; Width: 5 mm; VOLUME_NET: 0.0041 m3; VOLUME_GROSS: 0.0041 m3; AREA_GROSS: 0.82011 m2; Heigth: 405.159 mm; Length: 2024.16 mm
Tekla Common - Grade: S355; Name: STÅLBJELKE; Profile: PL5*405; Part mark: DSB-21132(?); Assembly mark: SS-7596(?); Top elevation: +213.635; Class: 330; Bottom elevation: +213.230
ePset_Simplebim - Assembly Level: Leaf
ePset_SimplebimBasicQuantities - Area, sides, net (Simplebim): 1.6645 m2; Length (Simplebim): 2024.16 mm; Weight, as steel (Simplebim): 32.1892 kg; Width (Simplebim): 5 mm; Volume, net (Simplebim): 0.00410053 m3; Height (Simplebim): 405.159 mm
ePset_LocationTool - Splitting: ORIGINAL
Pset_BeamCommon - LoadBearing: no; Reference: DSB-21132(?)
AVINOR - 07_Fase: F90; 02_Prosjekt: T1; 04_Kontrakt: FDV; 03_Ansvar: FDV; 08_Status: S2; 06_Omrade: TG; 01_Lufthavnkode: ENGM

# IfcBeam: PL5*74, STÅLBJELKE
In: F
Description: PL5*74; Material: STEEL/S355J0
ePset_LocationTool - Splitting: ORIGINAL
ePset_SimplebimBasicQuantities - Weight, as steel (Simplebim): 0.214933 kg; Area, sides, net (Simplebim): 0.012432 m2; Width (Simplebim): 5 mm; Length (Simplebim): 74 mm; Height (Simplebim): 74 mm; Volume, net (Simplebim): 0.00002738 m3
ePset_Simplebim - Assembly Level: Leaf
Tekla Common - Name: STÅLBJELKE; Profile: PL5*74; Grade: S355J0; Top elevation: +213.082; Part mark: DSB-0(?); Assembly mark: SB-0(?); Bottom elevation: +213.008; Class: 330
Tekla Quantity - WEIGTH_GROSS: 0.21493 kg; WEIGTH_NET: 0.21493 kg; Width: 5 mm; Heigth: 74 mm; Length: 74 mm; AREA_NET: 0.01243 m2; AREA_GROSS: 0.01243 m2; VOLUME_GROSS: 0.00003 m3; VOLUME_NET: 0.00003 m3
AVINOR - 08_Status: S4; 07_Fase: F90; 05_ID-nummer: +TG=221.002; 04_Kontrakt: 72717; 06_Omrade: TG; 02_Prosjekt: T20100; 03_Ansvar: 72101; 01_Lufthavnkode: ENGM
Pset_BeamCommon - LoadBearing: no; Reference: DSB-0(?)

# IfcBeam: PL8*150 (5)
In: G
Description: PL8*150; Material: STEEL/S355
Pset_BeamCommon - Reference: DSB-14959(?); LoadBearing: no
Tekla Quantity - WEIGTH_NET: 1.57785 kg; VOLUME_GROSS: 0.00019 m3; VOLUME_NET: 0.00019 m3; AREA_GROSS: 0.036 m2; WEIGTH_GROSS: 2.26081 kg; Length: 240.001 mm; Width: 8 mm; Heigth: 150 mm; AREA_NET: 0.0558 m2
ePset_SimplebimBasicQuantities - Weight, as steel (Simplebim): 1.57785 kg; Volume, net (Simplebim): 0.000201 m3; Height (Simplebim): 150.001 mm; Width (Simplebim): 8 mm; Length (Simplebim): 240 mm; Area, sides, net (Simplebim): 0.055799 m2
ePset_Simplebim - Assembly Level: Leaf
Tekla Common - Grade: S355; Part mark: DSB-14959(?); Name: STÅLBJELKE; Profile: PL8*150; Class: 330; Bottom elevation: +213.090; Top elevation: +213.240
ePset_LocationTool - Splitting: ORIGINAL
AVINOR - 07_Fase: F90; 02_Prosjekt: T1; 04_Kontrakt: FDV; 03_Ansvar: FDV; 08_Status: S2; 06_Omrade: TG; 01_Lufthavnkode: ENGM
Name | Assembly mark
STÅLBJELKE | SB-8213(?)
STÅLBJELKE | SB-8212(?)
3 x STÅLBJELKE | SB-8195(?)

# IfcBeam: PL8*189, STÅLBJELKE
In: G
Description: PL8*189; Material: STEEL/S355
Pset_BeamCommon - Reference: DSB-14960(?); LoadBearing: no
Tekla Quantity - AREA_NET: 0.05956 m2; AREA_GROSS: 0.03968 m2; Length: 209.937 mm; Heigth: 188.999 mm; Width: 8 mm; WEIGTH_GROSS: 2.49177 kg; WEIGTH_NET: 1.69325 kg; VOLUME_NET: 0.00021 m3; VOLUME_GROSS: 0.00021 m3
ePset_LocationTool - Splitting: ORIGINAL
Tekla Common - Grade: S355; Name: STÅLBJELKE; Part mark: DSB-14960(?); Bottom elevation: +213.170; Top elevation: +213.380; Profile: PL8*189; Assembly mark: SB-8258(?); Class: 330
ePset_Simplebim - Assembly Level: Leaf
AVINOR - 07_Fase: F90; 02_Prosjekt: T1; 04_Kontrakt: FDV; 03_Ansvar: FDV; 08_Status: S2; 06_Omrade: TG; 01_Lufthavnkode: ENGM
ePset_SimplebimBasicQuantities - Volume, net (Simplebim): 0.0002157 m3; Width (Simplebim): 8 mm; Area, sides, net (Simplebim): 0.0595631 m2; Weight, as steel (Simplebim): 1.69325 kg; Height (Simplebim): 209.937 mm; Length (Simplebim): 188.999 mm

# IfcBeam: PL8*190 (3)
In: G
Description: PL8*190; Material: STEEL/S355
ePset_LocationTool - Splitting: ORIGINAL
ePset_Simplebim - Assembly Level: Leaf
Pset_BeamCommon - LoadBearing: no; Reference: DSB-14927(?)
Tekla Common - Profile: PL8*190; Grade: S355; Assembly mark: SB-8195(?); Name: STÅLBJELKE; Bottom elevation: +213.170; Part mark: DSB-14927(?); Top elevation: +213.400; Class: 330
Tekla Quantity - AREA_GROSS: 0.04381 m2; AREA_NET: 0.06414 m2; VOLUME_NET: 0.00023 m3; VOLUME_GROSS: 0.00023 m3; Heigth: 190.157 mm; Length: 230.4 mm; WEIGTH_NET: 1.83846 kg; Width: 8 mm; WEIGTH_GROSS: 2.7514 kg
ePset_SimplebimBasicQuantities - Height (Simplebim): 230.4 mm; Area, sides, net (Simplebim): 0.0641443 m2; Length (Simplebim): 190.157 mm; Volume, net (Simplebim): 0.000234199 m3; Weight, as steel (Simplebim): 1.83846 kg; Width (Simplebim): 8 mm
AVINOR - 07_Fase: F90; 02_Prosjekt: T1; 04_Kontrakt: FDV; 03_Ansvar: FDV; 08_Status: S2; 06_Omrade: TG; 01_Lufthavnkode: ENGM

# IfcBeam: RHS100*4 (2)
In: F
Description: RHS100*4; Material: STEEL/S355
ePset_LocationTool - Splitting: ORIGINAL
Tekla Common - Grade: S355; Name: STÅLBJELKE; Profile: RHS100*4; Class: 330; Assembly mark: SS-7757(?)
ePset_Simplebim - Assembly Level: Leaf
ePset_SimplebimBasicQuantities - Width (Simplebim): 100 mm; Height (Simplebim): 100 mm
Tekla Quantity - Heigth: 100 mm; Width: 100 mm
AVINOR - 07_Fase: F90; 02_Prosjekt: T1; 04_Kontrakt: FDV; 03_Ansvar: FDV; 08_Status: S2; 06_Omrade: TG; 01_Lufthavnkode: ENGM
Pset_BeamCommon - LoadBearing: no
Name | Bottom elevation | Top elevation | Part mark = Reference | Weight, as steel (Simplebim) (kg) = WEIGTH_NET (kg) | Area, sides, net (Simplebim) (m2) | Length (Simplebim) (mm) = Length (mm) | Volume, net (Simplebim) (m3) | WEIGTH_GROSS (kg) | AREA_NET (m2) | VOLUME_GROSS (m3) = VOLUME_NET (m3) | AREA_GROSS (m2)
STÅLBJELKE | +213.570 | +213.670 | DSB-5634(?) | 2.41151 | 0.156671 | 199.999 | 0.000307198 | 2.40209 | 0.0816 | 0.0003 | 0.0782
STÅLBJELKE | +209.830 | +209.930 | DSB-21267(?) | 3.91871 | 0.252671 | 324.999 | 0.000499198 | 3.9034 | 0.1316 | 0.00049 | 0.12707

# IfcBeam: RHS120*80*5 (8)
In: F
Description: RHS120*80*5; Material: STEEL/S355
Tekla Common - Grade: S355; Name: STÅLBJELKE; Assembly mark: SS-579(?); Profile: RHS120*80*5; Class: 330
Pset_BeamCommon - LoadBearing: no
ePset_SimplebimBasicQuantities - Width (Simplebim): 80 mm; Height (Simplebim): 120 mm
ePset_Simplebim - Assembly Level: Leaf
ePset_LocationTool - Splitting: ORIGINAL
Tekla Quantity - Width: 80 mm; Heigth: 120 mm
AVINOR - 07_Fase: F90; 02_Prosjekt: T1; 04_Kontrakt: FDV; 03_Ansvar: FDV; 08_Status: S2; 06_Omrade: TG; 01_Lufthavnkode: ENGM
Name | Top elevation | Bottom elevation | Part mark = Reference | Length (Simplebim) (mm) = Length (mm) | Area, sides, net (Simplebim) (m2) | Weight, as steel (Simplebim) (kg) = WEIGTH_NET (kg) | Volume, net (Simplebim) (m3) | AREA_GROSS (m2) | AREA_NET (m2) | WEIGTH_GROSS (kg) | VOLUME_NET (m3) | VOLUME_GROSS (m3)
4 x STÅLBJELKE | +212.510 | +212.390 | DSB-5597(?) | 2495 | 1.9 | 37.2129 | 0.0047405 | 0.97055 | 0.9913 | 37.0171 | 0.00474 | 0.00472
2 x STÅLBJELKE | +211.760 | +211.640 | DSB-5597(?) | 2495 | 1.9 | 37.2129 | 0.0047405 | 0.97055 | 0.9913 | 37.0171 | 0.00474 | 0.00472
2 x STÅLBJELKE | +212.510 | +212.390 | DSB-5598(?) | 1870 | 1.425 | 27.891 | 0.003553 | 0.72743 | 0.74348 | 27.7443 | 0.00355 | 0.00353

# IfcBeam: RHS160*80*6.3 (4)
In: F
Description: RHS160*80*6.3; Material: STEEL/S355
Tekla Quantity - Width: 80 mm; Heigth: 160 mm
ePset_Simplebim - Assembly Level: Leaf
Tekla Common - Grade: S355; Top elevation: +213.500; Name: STÅLBJELKE; Bottom elevation: +213.340; Assembly mark: SS-579(?); Profile: RHS160*80*6.3; Class: 330
ePset_SimplebimBasicQuantities - Width (Simplebim): 80 mm; Height (Simplebim): 160 mm
Pset_BeamCommon - LoadBearing: no
ePset_LocationTool - Splitting: ORIGINAL
AVINOR - 07_Fase: F90; 02_Prosjekt: T1; 04_Kontrakt: FDV; 03_Ansvar: FDV; 08_Status: S2; 06_Omrade: TG; 01_Lufthavnkode: ENGM
Name | VOLUME_NET (m3) | AREA_NET (m2) | Length (mm) = Length (Simplebim) (mm) | WEIGTH_GROSS (kg) | WEIGTH_NET (kg) = Weight, as steel (Simplebim) (kg) | VOLUME_GROSS (m3) | AREA_GROSS (m2) | Part mark = Reference | Area, sides, net (Simplebim) (m2) | Volume, net (Simplebim) (m3)
2 x STÅLBJELKE | 0.01499 | 2.47908 | 5230 | 117.008 | 117.634 | 0.01491 | 2.43718 | DSB-5618(?) | 4.76294 | 0.0149852
2 x STÅLBJELKE | 0.00536 | 0.88832 | 1870 | 41.8366 | 42.0603 | 0.00533 | 0.87142 | DSB-5619(?) | 1.70668 | 0.005358

# IfcBeam: RHS80*40*4 (4)
In: F
Description: RHS80*40*4; Material: STEEL/S355
ePset_SimplebimBasicQuantities - Width (Simplebim): 40 mm; Height (Simplebim): 80 mm
Pset_BeamCommon - LoadBearing: no
ePset_Simplebim - Assembly Level: Leaf
ePset_LocationTool - Splitting: ORIGINAL
Tekla Common - Grade: S355; Top elevation: +210.255; Name: STÅLBJELKE; Bottom elevation: +210.175; Profile: RHS80*40*4; Assembly mark: SS-7596(?); Class: 330
AVINOR - 07_Fase: F90; 02_Prosjekt: T1; 04_Kontrakt: FDV; 03_Ansvar: FDV; 08_Status: S2; 06_Omrade: TG; 01_Lufthavnkode: ENGM
Tekla Quantity - Width: 40 mm; Heigth: 80 mm
Name | Area, sides, net (Simplebim) (m2) | Weight, as steel (Simplebim) (kg) | Length (Simplebim) (mm) | Volume, net (Simplebim) (m3) | Reference = Part mark | WEIGTH_GROSS (kg) | Length (mm) | VOLUME_GROSS (m3) | WEIGTH_NET (kg) | AREA_NET (m2) | AREA_GROSS (m2) | VOLUME_NET (m3)
STÅLBJELKE | 0.266112 | 4.14983 | 590 | 0.00052864 | DSB-23464(?) | 4.11277 | 590 | 0.00052 | 4.14983 | 0.14006 | 0.13629 | 0.00053
STÅLBJELKE | 1.07695 | 16.88 | 2399.91 | 0.00215032 | DSB-23465(?) | 16.7293 | 2399.91 | 0.00213 | 16.88 | 0.56682 | 0.55438 | 0.00215
2 x STÅLBJELKE | 0.90856 | 14.2363 | 2024.03 | 0.00181354 | DSB-5470(?) | 14.11 | 2024.16 | 0.0018 | 14.2371 | 0.47822 | 0.46758 | 0.00181

# IfcBeam: RHS80*40*5, STÅLBJELKE
In: G
Description: RHS80*40*5
Tekla Common - Grade: S355; Bottom elevation: +213.580; Profile: RHS80*40*5; Name: STÅLBJELKE; Part mark: DSB-24093(?); Assembly mark: SB-11173(?); Top elevation: +213.660; Class: 330
ePset_LocationTool - Splitting: RESULT
Pset_BeamCommon - LoadBearing: no; Reference: DSB-24093(?)
ePset_Simplebim - Assembly Level: Leaf
ePset_SimplebimBasicQuantities - Area, sides, net (Simplebim): 12.0009 m2; Volume, net (Simplebim): 0.0299967 m3; Weight, as steel (Simplebim): 235.474 kg; Width (Simplebim): 40 mm; Height (Simplebim): 80 mm; Length (Simplebim): 27270 mm
AVINOR - 07_Fase: F90; 02_Prosjekt: T1; 04_Kontrakt: FDV; 03_Ansvar: FDV; 08_Status: S2; 06_Omrade: TG; 01_Lufthavnkode: ENGM

# IfcBeam: RØR60.3X5.0 (3)
In: F
Description: RØR60.3X5.0; Material: STEEL/S355
Tekla Quantity - Heigth: 60.3 mm; Width: 60.3 mm
ePset_Simplebim - Assembly Level: Leaf
Pset_BeamCommon - LoadBearing: no
ePset_SimplebimBasicQuantities - Height (Simplebim): 60.3 mm; Width (Simplebim): 60.3 mm
Tekla Common - Grade: S355; Name: STÅLBJELKE; Profile: RØR60.3X5.0; Assembly mark: SS-7596(?); Top elevation: +212.485; Bottom elevation: +212.425; Class: 330
AVINOR - 07_Fase: F90; 02_Prosjekt: T1; 04_Kontrakt: FDV; 03_Ansvar: FDV; 08_Status: S2; 06_Omrade: TG; 01_Lufthavnkode: ENGM
ePset_LocationTool - Splitting: ORIGINAL
Name | VOLUME_NET (m3) | WEIGTH_NET (kg) | AREA_NET (m2) | VOLUME_GROSS (m3) | WEIGTH_GROSS (kg) | AREA_GROSS (m2) | Length (mm) | Reference = Part mark | Volume, net (Simplebim) (m3) | Area, sides, net (Simplebim) (m2) | Weight, as steel (Simplebim) (kg) | Length (Simplebim) (mm)
2 x STÅLBJELKE | 0.00203 | 15.9474 | 0.45264 | 0.00209 | 16.3714 | 0.45358 | 2399.91 | DSB-16480(?) | 0.00203152 | 0.830219 | 15.9474 | 2399.91
STÅLBJELKE | 0.00171 | 13.4505 | 0.38192 | 0.00176 | 13.8081 | 0.38257 | 2024.16 | DSB-5474(?) | 0.00171332 | 0.700446 | 13.4495 | 2024.01

# IfcBeam: T-Tees:TEE100x140 (7)
In: Nivå G - 2,0 m
Type - PredefinedType: BEAM
Type - Pset_BeamCommon - LoadBearing: yes
Material: Metal - Steel - 345 MPa; Group: Model Group:A162446 - Utvidelse eksisterende Kiosk (members excluded):59114857
AVINOR - 08_Status: S4; 07_Fase: F90; 02_Prosjekt: A162446; 03_Ansvar: 182412; 06_Omrade: TG; 01_Lufthavnkode: ENGM
Pset_ReinforcementBarPitchOfBeam - Reference: TEE100x140; sets with these values: 2
ePset_SimplebimBasicQuantities - Width (Simplebim): 100 mm; Height (Simplebim): 140 mm
ePset_LocationTool - Splitting: ORIGINAL
ePset_Simplebim - Assembly Level: Leaf
Pset_BeamCommon - Reference: TEE100x140; IsExternal: no; Slope: 0 deg; Span: 5300 mm
Name (T-Tees:TEE100x140:...) | Volume, net (Simplebim) (m3) | Weight, as steel (Simplebim) (kg) | Area, sides, net (Simplebim) (m2) | Length (Simplebim) (mm)
59105842 | 0.0135989 | 106.751 | 2.37485 | 5143
59105886 | 0.0135989 | 106.751 | 2.37485 | 5143
59105888 | 0.0135989 | 106.751 | 2.37485 | 5143
59105890 | 0.0135989 | 106.751 | 2.37485 | 5143
59105892 | 0.0135989 | 106.751 | 2.37485 | 5143
59105894 | 0.011559 | 90.7384 | 2.01942 | 4371.55
59106062 | 0.0135989 | 106.751 | 2.37485 | 5143

# IfcBeam: T100, STÅLBJELKE
In: G
Description: T100; Material: STEEL/S355
Tekla Quantity - AREA_GROSS: 2.00601 m2; VOLUME_GROSS: 0.01048 m3; VOLUME_NET: 0.01031 m3; WEIGTH_NET: 80.9517 kg; WEIGTH_GROSS: 82.2789 kg; Length: 5015.02 mm; AREA_NET: 1.98946 m2; Heigth: 100 mm; Width: 100 mm
Tekla Common - Grade: S355; Assembly mark: SB-9613(?); Profile: T100; Part mark: DSB-16230(?); Top elevation: +213.570; Name: STÅLBJELKE; Bottom elevation: +213.470; Class: 330
ePset_Simplebim - Assembly Level: Leaf
Pset_BeamCommon - Reference: DSB-16230(?); LoadBearing: no
ePset_SimplebimBasicQuantities - Volume, net (Simplebim): 0.0103123 m3; Area, sides, net (Simplebim): 1.98946 m2; Weight, as steel (Simplebim): 80.9517 kg; Length (Simplebim): 5015.02 mm; Width (Simplebim): 100 mm; Height (Simplebim): 100 mm
AVINOR - 07_Fase: F90; 02_Prosjekt: T1; 04_Kontrakt: FDV; 03_Ansvar: FDV; 08_Status: S2; 06_Omrade: TG; 01_Lufthavnkode: ENGM
ePset_LocationTool - Splitting: ORIGINAL

# IfcBeam: T40 (10)
In: G
Description: T40; Material: STEEL/S355
Tekla Common - Grade: S355; Profile: T40; Top elevation: +213.700; Name: STÅLBJELKE; Assembly mark: SB-11173(?); Part mark: DSB-18617(?); Bottom elevation: +213.660; Class: 330
Tekla Quantity - Heigth: 40.0006 mm; AREA_GROSS: 0.05952 m2; Length: 372 mm; WEIGTH_NET: 0.98205 kg; AREA_NET: 0.05451 m2; VOLUME_NET: 0.00013 m3; VOLUME_GROSS: 0.00013 m3; Width: 40 mm; WEIGTH_GROSS: 1.10092 kg
ePset_Simplebim - Assembly Level: Leaf
AVINOR - 07_Fase: F90; 02_Prosjekt: T1; 04_Kontrakt: FDV; 03_Ansvar: FDV; 08_Status: S2; 06_Omrade: TG; 01_Lufthavnkode: ENGM
ePset_LocationTool - Splitting: ORIGINAL
Pset_BeamCommon - LoadBearing: no; Reference: DSB-18617(?)
ePset_SimplebimBasicQuantities - Area, sides, net (Simplebim): 0.0545101 m2; Height (Simplebim): 40.0006 mm; Length (Simplebim): 372 mm; Volume, net (Simplebim): 0.000125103 m3; Width (Simplebim): 40 mm; Weight, as steel (Simplebim): 0.982055 kg

# IfcBeam: UNP240 (2)
In: G
Description: UNP240; Material: STEEL/S355
ePset_LocationTool - Splitting: ORIGINAL
Pset_BeamCommon - LoadBearing: no; Reference: DSB-5420(?)
ePset_SimplebimBasicQuantities - Volume, net (Simplebim): 0.0372979 m3; Area, sides, net (Simplebim): 7.04412 m2; Weight, as steel (Simplebim): 292.788 kg; Width (Simplebim): 85 mm; Height (Simplebim): 240 mm; Length (Simplebim): 8980 mm
Tekla Common - Grade: S355; Profile: UNP240; Name: STÅLBJELKE; Assembly mark: SB-1530(?); Bottom elevation: +213.160; Top elevation: +213.400; Class: 330; Part mark: DSB-5420(?)
ePset_Simplebim - Assembly Level: Leaf
AVINOR - 07_Fase: F90; 02_Prosjekt: T1; 04_Kontrakt: FDV; 03_Ansvar: FDV; 08_Status: S2; 06_Omrade: TG; 01_Lufthavnkode: ENGM
Tekla Quantity - AREA_NET: 7.04412 m2; WEIGTH_NET: 292.788 kg; VOLUME_GROSS: 0.03799 m3; WEIGTH_GROSS: 298.185 kg; Width: 85 mm; Heigth: 240 mm; Length: 8980 mm; AREA_GROSS: 6.9595 m2; VOLUME_NET: 0.0373 m3

# IfcBeam: UNP260 (2)
In: F
Description: UNP260; Material: STEEL/S355
Tekla Quantity - AREA_NET: 7.01166 m2; AREA_GROSS: 6.88885 m2; WEIGTH_NET: 309.681 kg; Width: 90 mm; Heigth: 260 mm; Length: 8260.02 mm; WEIGTH_GROSS: 313.183 kg; VOLUME_GROSS: 0.03991 m3; VOLUME_NET: 0.03945 m3
Pset_BeamCommon - Reference: DSB-14072(?); LoadBearing: no
Tekla Common - Part mark: DSB-14072(?); Grade: S355; Top elevation: +210.030; Assembly mark: SB-1554(?); Profile: UNP260; Name: STÅLBJELKE; Class: 330; Bottom elevation: +209.770
ePset_LocationTool - Splitting: ORIGINAL
AVINOR - 07_Fase: F90; 02_Prosjekt: T1; 04_Kontrakt: FDV; 03_Ansvar: FDV; 08_Status: S2; 05_ID-nummer: +TA=223.002; 06_Omrade: TG; 01_Lufthavnkode: ENGM
ePset_Simplebim - Assembly Level: Leaf
ePset_SimplebimBasicQuantities - Volume, net (Simplebim): 0.0394498 m3; Area, sides, net (Simplebim): 7.01166 m2; Weight, as steel (Simplebim): 309.681 kg; Width (Simplebim): 90 mm; Height (Simplebim): 260 mm; Length (Simplebim): 8260.02 mm

# IfcBeam: UNP320, STÅLBJELKE
In: G
Description: UNP320
Tekla Common - Grade: S355; Top elevation: +213.700; Name: STÅLBJELKE; Part mark: DSB-15924(?); Bottom elevation: +213.380; Assembly mark: SB-8258(?); Profile: UNP320; Class: 330
ePset_LocationTool - Splitting: RESULT
ePset_Simplebim - Assembly Level: Leaf
Pset_BeamCommon - Reference: DSB-15924(?); LoadBearing: no
ePset_SimplebimBasicQuantities - Volume, net (Simplebim): 0.0393739 m3; Area, sides, net (Simplebim): 5.33602 m2; Weight, as steel (Simplebim): 309.085 kg; Width (Simplebim): 100 mm; Height (Simplebim): 320 mm; Length (Simplebim): 5320 mm
AVINOR - 07_Fase: F90; 02_Prosjekt: T1; 04_Kontrakt: FDV; 03_Ansvar: FDV; 08_Status: S2; 06_Omrade: TG; 01_Lufthavnkode: ENGM

# IfcBuildingElementProxy (3)
ePset_SimplebimBasicQuantities - Height (Simplebim): 100 mm
ePset_Simplebim - Assembly Level: Leaf
ePset_LocationTool - Splitting: ORIGINAL
Name | In | Thickness (Simplebim) (mm) | Length (Simplebim) (mm) | Volume, net (Simplebim) (m3) | Area, largest surface, net (Simplebim) (m2) | Group
Fordeler_Varme_2XDN32_0005 | Nivå F - 0,7 m | 175 | 520 | 0.00880479 | 0.0875 | 32= R 20° Kopi 57; 32= R 20° Kopi 58
Fordeler_Varme_2XDN32_0005 | Nivå F - 0,7 m | 175 | 520 | 0.00880479 | 0.0875 | 32= R 20° Kopi 5; 32= R 20° Kopi 7
Pådrag_DN20_4 | Nivå D + 1,2 m | 225 | 275 | 0.00533211 | 0.052875

# IfcBuildingElementProxy: A234 - Gitter:A241 - Gitter 300 x 300_UK_2700_offset 51 (3)
In: Nivå F - 0,7 m
Type - Material: <Unnamed>
ePset_SimplebimBasicQuantities - Height (Simplebim): 300 mm; Thickness (Simplebim): 300 mm
ePset_Simplebim - Assembly Level: Leaf
ePset_LocationTool - Splitting: ORIGINAL
Pset_QuantityTakeOff - Reference: A241 - Gitter 300 x 300_UK_2700_offset 51; sets with these values: 2
AVINOR - 08_Status: S4; 07_Fase: F90; 02_Prosjekt: A162446; 03_Ansvar: 182412; 06_Omrade: TG; 01_Lufthavnkode: ENGM
Group: Model Group:A162446 - Utvidelse eksisterende Kiosk (members excluded):59114857
Name (A234 - Gitter:A241 - Gitter 300 x 300_UK_2700_offset 51:...) | Volume, net (Simplebim) (m3) | Length (Simplebim) (mm) | Area, largest surface, net (Simplebim) (m2) | 05_ID-nummer
59105807 | 0.41985 | 4665 | 1.3995 | +TG=243.001-IR0016
59105829 | 0.47925 | 5325 | 1.5975 | +TG=243.001-IR0015
59105883 | 0.41625 | 4625 | 1.3875 | +TG=243.001-IR0017

# IfcBuildingElementProxy: A240 - eksisterende dekkeforkantbeslag nivå G:A240 - Eksisterende dekkeforkantbeslag - Plate - 1500 mm (15)
In: Nivå F
Type - Material: <Unnamed>
AVINOR - 08_Status: S4; 07_Fase: F90; 03_Ansvar: FDV; 06_Omrade: TG; 02_Prosjekt: T20100; 01_Lufthavnkode: ENGM
Pset_QuantityTakeOff - Reference: A240 - Eksisterende dekkeforkantbeslag - Plate - 1500 mm; sets with these values: 2
ePset_Simplebim - Assembly Level: Leaf
ePset_SimplebimBasicQuantities - Thickness (Simplebim): 26 mm; Height (Simplebim): 295 mm
ePset_LocationTool - Splitting: ORIGINAL
Name (A240 - eksisterende dekkeforkantbeslag nivå G:A240 - Eksisterende dekkeforkantbeslag - Plate - 1500 mm:...) | Volume, net (Simplebim) (m3) | Length (Simplebim) (mm) | Area, largest surface, net (Simplebim) (m2) | Group
49950708 | 0.00048015 | 1455 | 0.39285 | Model Group:A240 - eksisterende gallerivegg i pir G-2 / generell (members excluded):49950707
49950718 | 0.00043065 | 1305 | 0.35235 | Model Group:A240 - eksisterende gallerivegg i pir G-2 / generell (members excluded):49950707
49950721 | 0.00048015 | 1455 | 0.39285 | Model Group:A240 - eksisterende gallerivegg i pir G-2 / generell (members excluded):49950707
49950724 | 0.00048015 | 1455 | 0.39285 | Model Group:A240 - eksisterende gallerivegg i pir G-2 / generell (members excluded):49950707
49950727 | 0.00048015 | 1455 | 0.39285 | Model Group:A240 - eksisterende gallerivegg i pir G-2 / generell (members excluded):49950707
49950730 | 0.00043065 | 1305 | 0.35235 | Model Group:A240 - eksisterende gallerivegg i pir G-2 / generell (members excluded):49950707
49950746 | 0.00008415 | 255 | 0.06885 | Model Group:A240 - eksisterende gallerivegg i pir G-2 / generell (members excluded):49950707
49951058 | 0.00008415 | 255 | 0.06885 | Model Group:A240 - eksisterende gallerivegg i pir G-2 / generell (members excluded):49951019
49959099 | 0.00048015 | 1455 | 0.39285 | Model Group:A240 - eksisterende gallerivegg i pir G-2 / forkortet ved bru akse 19-20 nordside, 21-22 sørside (members excluded):49959098
49959109 | 0.00043065 | 1305 | 0.35235 | Model Group:A240 - eksisterende gallerivegg i pir G-2 / forkortet ved bru akse 19-20 nordside, 21-22 sørside (members excluded):49959098
49959112 | 0.00048015 | 1455 | 0.39285 | Model Group:A240 - eksisterende gallerivegg i pir G-2 / forkortet ved bru akse 19-20 nordside, 21-22 sørside (members excluded):49959098
49959115 | 0.000424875 | 1287.5 | 0.347625 | Model Group:A240 - eksisterende gallerivegg i pir G-2 / forkortet ved bru akse 19-20 nordside, 21-22 sørside (members excluded):49959098
49959118 | 0.00048015 | 1455 | 0.39285 | Model Group:A240 - eksisterende gallerivegg i pir G-2 / forkortet ved bru akse 19-20 nordside, 21-22 sørside (members excluded):49959098
49959121 | 0.00043065 | 1305 | 0.35235 | Model Group:A240 - eksisterende gallerivegg i pir G-2 / forkortet ved bru akse 19-20 nordside, 21-22 sørside (members excluded):49959098
49959129 | 0.00008415 | 255 | 0.06885 | Model Group:A240 - eksisterende gallerivegg i pir G-2 / forkortet ved bru akse 19-20 nordside, 21-22 sørside (members excluded):49959098

# IfcBuildingElementProxy: A255 - eksisterende beslag mellom himling - pirF_type__A:A255 - eksisterende beslag mellom himling - Type A (100mm sprang) (2)
In: Nivå F
Type - Material: <Unnamed>
AVINOR - 08_Status: S4; 07_Fase: F90; 03_Ansvar: FDV; 06_Omrade: TG; 02_Prosjekt: T20100; 01_Lufthavnkode: ENGM
ePset_LocationTool - Splitting: ORIGINAL
ePset_SimplebimBasicQuantities - Length (Simplebim): 9000 mm; Volume, net (Simplebim): 0.001701 m3; Area, largest surface, net (Simplebim): 0.909 m2; Thickness (Simplebim): 50 mm; Height (Simplebim): 101 mm
ePset_Simplebim - Assembly Level: Leaf
Pset_BuildingElementProxyCommon - Reference: A255 - eksisterende beslag mellom himling - Type A (100mm sprang); sets with these values: 2
Group: Model Group:A255 - eksisterende himling i pir F-0,7 / TG__sørside akse 22-24:49480116
Name (A255 - eksisterende beslag mellom himling - pirF_type__A:A255 - eksisterende beslag mellom himling - Type A (100mm sprang):...)
49480120
49480121

# IfcBuildingElementProxy: A255 - eksisterende beslag mellom himling - pirF_type__B:A255 - eksisterende beslag mellom himling - Type B (305mm sprang), A255 - eksisterende beslag mellom himling - pirF_type__B:A255 - eksisterende beslag mellom himling - Type B (305mm sprang):49480122
In: Nivå F
Type - Material: <Unnamed>
AVINOR - 08_Status: S4; 07_Fase: F90; 03_Ansvar: FDV; 06_Omrade: TG; 02_Prosjekt: T20100; 01_Lufthavnkode: ENGM
Pset_BuildingElementProxyCommon - Reference: A255 - eksisterende beslag mellom himling - Type B (305mm sprang); sets with these values: 2
ePset_LocationTool - Splitting: ORIGINAL
ePset_SimplebimBasicQuantities - Length (Simplebim): 9000 mm; Thickness (Simplebim): 50 mm; Height (Simplebim): 306 mm; Area, largest surface, net (Simplebim): 2.754 m2; Volume, net (Simplebim): 0.003546 m3
ePset_Simplebim - Assembly Level: Leaf
Group: Model Group:A255 - eksisterende himling i pir F-0,7 / TG__sørside akse 22-24:49480116

# IfcBuildingElementProxy: A255 - eksisterende beslag mellom himling - pirF_type__C:A255 - eksisterende beslag mellom himling - Type C (4)
In: Nivå F
Type - Material: <Unnamed>
AVINOR - 08_Status: S4; 07_Fase: F90; 03_Ansvar: FDV; 06_Omrade: TG; 02_Prosjekt: T20100; 01_Lufthavnkode: ENGM
ePset_SimplebimBasicQuantities - Thickness (Simplebim): 130 mm; Height (Simplebim): 315 mm
ePset_Simplebim - Assembly Level: Leaf
ePset_LocationTool - Splitting: ORIGINAL
Pset_BuildingElementProxyCommon - Reference: A255 - eksisterende beslag mellom himling - Type C; sets with these values: 2
Name (A255 - eksisterende beslag mellom himling - pirF_type__C:A255 - eksisterende beslag mellom himling - Type C:...) | Length (Simplebim) (mm) | Area, largest surface, net (Simplebim) (m2) | Volume, net (Simplebim) (m3)
49469875 | 3000 | 0.87 | 0.00168
49470116 | 9000 | 2.61 | 0.00504
49480123 | 9000 | 2.61 | 0.00504 | Group: Model Group:A255 - eksisterende himling i pir F-0,7 / TG__sørside akse 22-24:49480116
49480834 | 6000 | 1.74 | 0.00336

# IfcBuildingElementProxy: A255 - eksisterende beslag mellom himling - pirF_type__D:A255 - eksisterende beslag mellom himling - Type D, A255 - eksisterende beslag mellom himling - pirF_type__D:A255 - eksisterende beslag mellom himling - Type D:49480124
In: Nivå F
Type - Material: <Unnamed>
AVINOR - 08_Status: S4; 07_Fase: F90; 03_Ansvar: FDV; 06_Omrade: TG; 02_Prosjekt: T20100; 01_Lufthavnkode: ENGM
ePset_LocationTool - Splitting: ORIGINAL
ePset_SimplebimBasicQuantities - Length (Simplebim): 9000 mm; Height (Simplebim): 155 mm; Thickness (Simplebim): 81 mm; Area, largest surface, net (Simplebim): 0.72 m2; Volume, net (Simplebim): 0.003258 m3
Pset_QuantityTakeOff - Reference: A255 - eksisterende beslag mellom himling - Type D; sets with these values: 2
ePset_Simplebim - Assembly Level: Leaf
Group: Model Group:A255 - eksisterende himling i pir F-0,7 / TG__sørside akse 22-24:49480116

# IfcBuildingElementProxy: A270 - eksisterende skilt Pendel_T1:A270 - 1400x300mm (2)
In: Nivå F - 0,7 m
Type - Material: <Unnamed>
AVINOR - 08_Status: S4; 07_Fase: F90; 03_Ansvar: FDV; 06_Omrade: TG; 02_Prosjekt: T20100; 01_Lufthavnkode: ENGM
ePset_LocationTool - Splitting: ORIGINAL
ePset_SimplebimBasicQuantities - Area, largest surface, net (Simplebim): 0.42 m2; Length (Simplebim): 1400 mm; Thickness (Simplebim): 70 mm; Height (Simplebim): 840 mm; Volume, net (Simplebim): 0.0301595 m3
ePset_Simplebim - Assembly Level: Leaf
Pset_QuantityTakeOff - Reference: A270 - 1400x300mm; sets with these values: 2
Name (A270 - eksisterende skilt Pendel_T1:A270 - 1400x300mm:...)
49623032
49623079

# IfcBuildingElementProxy: A270 - eksisterende skilt Pendel_T1:A270 - 800x300mm (2)
In: Nivå F - 0,7 m
Type - Material: <Unnamed>
AVINOR - 08_Status: S4; 07_Fase: F90; 03_Ansvar: FDV; 06_Omrade: TG; 02_Prosjekt: T20100; 01_Lufthavnkode: ENGM
ePset_SimplebimBasicQuantities - Volume, net (Simplebim): 0.0175595 m3; Length (Simplebim): 800 mm; Thickness (Simplebim): 70 mm; Area, largest surface, net (Simplebim): 0.24 m2; Height (Simplebim): 840 mm
Pset_QuantityTakeOff - Reference: A270 - 800x300mm; sets with these values: 2
ePset_Simplebim - Assembly Level: Leaf
ePset_LocationTool - Splitting: ORIGINAL
Name (A270 - eksisterende skilt Pendel_T1:A270 - 800x300mm:...)
49623003
49623078

# IfcBuildingElementProxy: A275 - Pylon - venstrehengslet:Pylon med topp brakett, A275 - Pylon - venstrehengslet:Pylon med topp brakett:56702736
In: Nivå F - 0,7 m
Type - Material: <Unnamed>
Pset_QuantityTakeOff - Reference: Pylon med topp brakett; sets with these values: 2
ePset_Simplebim - Assembly Level: Leaf
ePset_LocationTool - Splitting: ORIGINAL
ePset_SimplebimBasicQuantities - Area, largest surface, net (Simplebim): 1.78713 m2; Volume, net (Simplebim): 0.0408924 m3; Thickness (Simplebim): 195 mm; Length (Simplebim): 752 mm; Height (Simplebim): 2500 mm
AVINOR - 08_Status: S4; 04_Kontrakt: 72717; 06_Omrade: TG; 02_Prosjekt: T20100; 07_Fase: F50; 03_Ansvar: OSL; 01_Lufthavnkode: ENGM

# IfcBuildingElementProxy: A313 Drikkefontene:A313 Drikkefontene, A313 Drikkefontene:A313 Drikkefontene:53029942
In: Nivå F - 0,7 m
Type - Material: <Unnamed>
AVINOR - 08_Status: S4; 07_Fase: F90; 03_Ansvar: FDV; 06_Omrade: TG; 02_Prosjekt: T20100; 01_Lufthavnkode: ENGM
Pset_QuantityTakeOff - Reference: A313 Drikkefontene; sets with these values: 2
ePset_LocationTool - Splitting: ORIGINAL
ePset_SimplebimBasicQuantities - Area, largest surface, net (Simplebim): 0.27 m2; Thickness (Simplebim): 450 mm; Length (Simplebim): 470 mm; Height (Simplebim): 600 mm; Volume, net (Simplebim): 0.0894767 m3
ePset_Simplebim - Assembly Level: Leaf

# IfcBuildingElementProxy: B220 - konsoll eksyst pir Vest:B220 - Konsoll eksyst. pir Vest (6)
In: Nivå G - 2,0 m
Type - Material: _NSW Stål
AVINOR - 08_Status: S4; 07_Fase: F90; 03_Ansvar: FDV; 06_Omrade: TG; 02_Prosjekt: T20100; 01_Lufthavnkode: ENGM
ePset_Simplebim - Assembly Level: Leaf
ePset_LocationTool - Splitting: ORIGINAL
ePset_SimplebimBasicQuantities - Area, largest surface, net (Simplebim): 0.0594036 m2; Height (Simplebim): 269.993 mm; Thickness (Simplebim): 150.019 mm; Volume, net (Simplebim): 0.00149397 m3; Length (Simplebim): 339.998 mm
Pset_QuantityTakeOff - Reference: B220 - Konsoll eksyst. pir Vest; sets with these values: 2
Name (B220 - konsoll eksyst pir Vest:B220 - Konsoll eksyst. pir Vest:...) | Group
50060606 | Model Group:A254 - eksisterende glassgulv i pir G ved fasade / __generell (members excluded):49956618
50060607 | Model Group:A254 - eksisterende glassgulv i pir G ved fasade / __generell (members excluded):49956618
50060608 | Model Group:A254 - eksisterende glassgulv i pir G ved fasade / __generell (members excluded):49956671
50060609 | Model Group:A254 - eksisterende glassgulv i pir G ved fasade / __generell (members excluded):49956671
53645481 | Model Group:A254 - eksisterende glassgulv i pir G ved fasade / __generell (members excluded):53645474
53645482 | Model Group:A254 - eksisterende glassgulv i pir G ved fasade / __generell (members excluded):53645474

# IfcBuildingElementProxy: Generic Models 10:Generic Models 1, Generic Models 10:Generic Models 1:59105980
In: Nivå F
Type - Material: <Unnamed>
AVINOR - 08_Status: S4; 07_Fase: F90; 02_Prosjekt: A162446; 03_Ansvar: 182412; 06_Omrade: TG; 01_Lufthavnkode: ENGM
ePset_LocationTool - Splitting: ORIGINAL
ePset_Simplebim - Assembly Level: Leaf
ePset_SimplebimBasicQuantities - Height (Simplebim): 500 mm; Area, largest surface, net (Simplebim): 0.975 m2; Thickness (Simplebim): 50 mm; Length (Simplebim): 1950 mm; Volume, net (Simplebim): 0.00367837 m3
Pset_QuantityTakeOff - Reference: Generic Models 1; sets with these values: 2
Group: Model Group:A162446 - Utvidelse eksisterende Kiosk (members excluded):59114857

# IfcBuildingElementProxy: Generic Models 11:Generic Models 1, Generic Models 11:Generic Models 1:59105996
In: Nivå F
Type - Material: <Unnamed>
AVINOR - 08_Status: S4; 07_Fase: F90; 02_Prosjekt: A162446; 03_Ansvar: 182412; 06_Omrade: TG; 01_Lufthavnkode: ENGM
ePset_Simplebim - Assembly Level: Leaf
ePset_LocationTool - Splitting: ORIGINAL
ePset_SimplebimBasicQuantities - Height (Simplebim): 500 mm; Area, largest surface, net (Simplebim): 0.975 m2; Thickness (Simplebim): 50 mm; Length (Simplebim): 1950 mm; Volume, net (Simplebim): 0.00367837 m3
Pset_QuantityTakeOff - Reference: Generic Models 1; sets with these values: 2
Group: Model Group:A162446 - Utvidelse eksisterende Kiosk (members excluded):59114857

# IfcBuildingElementProxy: Generic Models 12:Generic Models 1, Generic Models 12:Generic Models 1:59106012
In: Nivå F
Type - Material: <Unnamed>
AVINOR - 08_Status: S4; 07_Fase: F90; 02_Prosjekt: A162446; 03_Ansvar: 182412; 06_Omrade: TG; 01_Lufthavnkode: ENGM
ePset_Simplebim - Assembly Level: Leaf
ePset_SimplebimBasicQuantities - Height (Simplebim): 500 mm; Area, largest surface, net (Simplebim): 0.975 m2; Thickness (Simplebim): 50 mm; Length (Simplebim): 1950 mm; Volume, net (Simplebim): 0.00367837 m3
Pset_QuantityTakeOff - Reference: Generic Models 1; sets with these values: 2
ePset_LocationTool - Splitting: ORIGINAL
Group: Model Group:A162446 - Utvidelse eksisterende Kiosk (members excluded):59114857

# IfcBuildingElementProxy: Generic Models 13:Generic Models 1, Generic Models 13:Generic Models 1:59106028
In: Nivå F
Type - Material: <Unnamed>
AVINOR - 08_Status: S4; 07_Fase: F90; 02_Prosjekt: A162446; 03_Ansvar: 182412; 06_Omrade: TG; 01_Lufthavnkode: ENGM
ePset_LocationTool - Splitting: ORIGINAL
ePset_Simplebim - Assembly Level: Leaf
ePset_SimplebimBasicQuantities - Height (Simplebim): 500 mm; Area, largest surface, net (Simplebim): 0.975 m2; Thickness (Simplebim): 50 mm; Length (Simplebim): 1950 mm; Volume, net (Simplebim): 0.00367837 m3
Pset_QuantityTakeOff - Reference: Generic Models 1; sets with these values: 2
Group: Model Group:A162446 - Utvidelse eksisterende Kiosk (members excluded):59114857

# IfcBuildingElementProxy: Generic Models 14:Generic Models 1, Generic Models 14:Generic Models 1:59106044
In: Nivå F
Type - Material: <Unnamed>
AVINOR - 08_Status: S4; 07_Fase: F90; 02_Prosjekt: A162446; 03_Ansvar: 182412; 06_Omrade: TG; 01_Lufthavnkode: ENGM
ePset_LocationTool - Splitting: ORIGINAL
ePset_SimplebimBasicQuantities - Volume, net (Simplebim): 0.00285634 m3; Height (Simplebim): 500 mm; Thickness (Simplebim): 50 mm; Area, largest surface, net (Simplebim): 0.757109 m2; Length (Simplebim): 1514.22 mm
ePset_Simplebim - Assembly Level: Leaf
Pset_QuantityTakeOff - Reference: Generic Models 1; sets with these values: 2
Group: Model Group:A162446 - Utvidelse eksisterende Kiosk (members excluded):59114857

# IfcBuildingElementProxy: Generic Models 15:Generic Models 1, Generic Models 15:Generic Models 1:59106060
In: Nivå F
Type - Material: <Unnamed>
AVINOR - 08_Status: S4; 07_Fase: F90; 02_Prosjekt: A162446; 03_Ansvar: 182412; 06_Omrade: TG; 01_Lufthavnkode: ENGM
ePset_Simplebim - Assembly Level: Leaf
ePset_LocationTool - Splitting: ORIGINAL
ePset_SimplebimBasicQuantities - Height (Simplebim): 500 mm; Length (Simplebim): 1840.38 mm; Area, largest surface, net (Simplebim): 0.920188 m2; Thickness (Simplebim): 50 mm; Volume, net (Simplebim): 0.00345306 m3
Pset_QuantityTakeOff - Reference: Generic Models 1; sets with these values: 2
Group: Model Group:A162446 - Utvidelse eksisterende Kiosk (members excluded):59114857

# IfcBuildingElementProxy: Generic Models 1:Generic Models 1, Generic Models 1:Generic Models 1:59105948
In: Nivå F
Type - Material: <Unnamed>
AVINOR - 08_Status: S4; 07_Fase: F90; 02_Prosjekt: A162446; 03_Ansvar: 182412; 06_Omrade: TG; 01_Lufthavnkode: ENGM
ePset_Simplebim - Assembly Level: Leaf
ePset_SimplebimBasicQuantities - Height (Simplebim): 500 mm; Area, largest surface, net (Simplebim): 0.975 m2; Thickness (Simplebim): 50 mm; Length (Simplebim): 1950 mm; Volume, net (Simplebim): 0.00367837 m3
Pset_QuantityTakeOff - Reference: Generic Models 1; sets with these values: 2
ePset_LocationTool - Splitting: ORIGINAL
Group: Model Group:A162446 - Utvidelse eksisterende Kiosk (members excluded):59114857

# IfcBuildingElementProxy: Generic Models 9:Generic Models 1, Generic Models 9:Generic Models 1:59105964
In: Nivå F
Type - Material: <Unnamed>
AVINOR - 08_Status: S4; 07_Fase: F90; 02_Prosjekt: A162446; 03_Ansvar: 182412; 06_Omrade: TG; 01_Lufthavnkode: ENGM
ePset_LocationTool - Splitting: ORIGINAL
ePset_Simplebim - Assembly Level: Leaf
ePset_SimplebimBasicQuantities - Height (Simplebim): 500 mm; Area, largest surface, net (Simplebim): 0.975 m2; Thickness (Simplebim): 50 mm; Length (Simplebim): 1950 mm; Volume, net (Simplebim): 0.00367837 m3
Pset_QuantityTakeOff - Reference: Generic Models 1; sets with these values: 2
Group: Model Group:A162446 - Utvidelse eksisterende Kiosk (members excluded):59114857

# IfcBuildingElementProxy: Model Text:230mm Arial (2)
In: Nivå F
AVINOR - 08_Status: S4; 07_Fase: F90; 02_Prosjekt: A162446; 03_Ansvar: 182412; 06_Omrade: TG; 01_Lufthavnkode: ENGM
Pset_BuildingElementProxyCommon - Reference: 230mm Arial; sets with these values: 2
ePset_SimplebimBasicQuantities - Thickness (Simplebim): 49.9986 mm; Area, largest surface, net (Simplebim): 0.0356542 m2; Length (Simplebim): 498.857 mm; Volume, net (Simplebim): 0.00363536 m3; Height (Simplebim): 1656.54 mm
ePset_Simplebim - Assembly Level: Leaf
ePset_LocationTool - Splitting: ORIGINAL
Group: Model Group:A162446 - Utvidelse eksisterende Kiosk (members excluded):59114857
Name (Model Text:230mm Arial:...)
59105885
59105912

# IfcColumn: A243 - Rullegardinskinner:A243 - Portskinne Trav Val Innl (12)
Type - PredefinedType: COLUMN; Material: _NSW Stål
Type - Pset_ColumnCommon - LoadBearing: yes
AVINOR - 08_Status: S4; 07_Fase: F90; 02_Prosjekt: A162446; 03_Ansvar: 182412; 06_Omrade: TG; 01_Lufthavnkode: ENGM
ePset_SimplebimBasicQuantities - Width (Simplebim): 60 mm; Depth (Simplebim): 100 mm
Pset_ReinforcementBarPitchOfColumn - Reference: A243 - Portskinne Trav Val Innl; sets with these values: 2
Pset_ColumnCommon - IsExternal: no; Reference: A243 - Portskinne Trav Val Innl
ePset_Simplebim - Assembly Level: Leaf
ePset_LocationTool - Splitting: ORIGINAL
Group: Model Group:A162446 - Utvidelse eksisterende Kiosk (members excluded):59114857
Name (A243 - Rullegardinskinner:A243 - Portskinne Trav Val Innl:...) | In | Volume, net (Simplebim) (m3) | Weight, as steel (Simplebim) (kg) | Area, sides, net (Simplebim) (m2) | Height (Simplebim) (mm)
59105808 | Nivå F - 0,7 m | 0.0006888 | 5.40708 | 0.4396 | 700
59105808 | Nivå F | 0.0020172 | 15.835 | 1.2874 | 2050
59105814 | Nivå F - 0,7 m | 0.0006888 | 5.40708 | 0.4396 | 700
59105814 | Nivå F | 0.0020172 | 15.835 | 1.2874 | 2050
59105875 | Nivå F - 0,7 m | 0.0006888 | 5.40708 | 0.4396 | 700
59105875 | Nivå F | 0.0020172 | 15.835 | 1.2874 | 2050
59105877 | Nivå F - 0,7 m | 0.0006888 | 5.40708 | 0.4396 | 700
59105877 | Nivå F | 0.0020172 | 15.835 | 1.2874 | 2050
59105879 | Nivå F - 0,7 m | 0.0006888 | 5.40708 | 0.4396 | 700
59105879 | Nivå F | 0.0020172 | 15.835 | 1.2874 | 2050
59105881 | Nivå F - 0,7 m | 0.0006888 | 5.40708 | 0.4396 | 700
59105881 | Nivå F | 0.0020172 | 15.835 | 1.2874 | 2050

# IfcColumn: AAJOVAL470*770 (4)
In: F
Description: AAJOVAL470*770; Material: CONCRETE/C45/55
Pset_ColumnCommon - Reference: Concrete-820; LoadBearing: no
Tekla Common - Name: PREFABSØYLE; Bottom elevation: +210.080; Class: 120; Part mark: Concrete-820; Top elevation: +210.350; Grade: C45/55; Profile: AAJOVAL470*770
Tekla Quantity - AREA_GROSS: 1.18912 m2; AREA_NET: 1.18912 m2; VOLUME_GROSS: 0.08486 m3; VOLUME_NET: 0.08486 m3; Heigth: 769.577 mm; Length: 270 mm; Width: 470 mm; WEIGTH_NET: 203.657 kg; WEIGTH_GROSS: 203.657 kg
ePset_Simplebim - Assembly Level: Leaf
ePset_SimplebimBasicQuantities - Weight, as steel (Simplebim): 666.129 kg; Height (Simplebim): 769.577 mm; Volume, net (Simplebim): 0.0848572 m3; Area, sides, net (Simplebim): 0.560548 m2; Width (Simplebim): 270 mm; Depth (Simplebim): 470 mm
AVINOR - 07_Fase: F90; 02_Prosjekt: T1; 04_Kontrakt: FDV; 03_Ansvar: FDV; 08_Status: S2; 06_Omrade: TG; 01_Lufthavnkode: ENGM
ePset_LocationTool - Splitting: ORIGINAL
Name | Assembly mark
2 x PREFABSØYLE | PS-439
2 x PREFABSØYLE | PS-166

# IfcColumn: AAJOVAL500*800 (3)
In: F
Description: AAJOVAL500*800; Material: CONCRETE/C45/55
Tekla Quantity - VOLUME_GROSS: 2.02684 m3; WEIGTH_GROSS: 4864.42 kg; Width: 500 mm; Length: 5856 mm; AREA_GROSS: 13.4017 m2
ePset_LocationTool - Splitting: ORIGINAL
ePset_SimplebimBasicQuantities - Width (Simplebim): 500 mm; Height (Simplebim): 5856 mm
Pset_ColumnCommon - LoadBearing: no
ePset_Simplebim - Assembly Level: Leaf
Tekla Common - Name: PREFABSØYLE; Class: 120; Bottom elevation: +210.350; Top elevation: +216.206; Grade: C45/55; Profile: AAJOVAL500*800
AVINOR - 07_Fase: F90; 02_Prosjekt: T1; 04_Kontrakt: FDV; 03_Ansvar: FDV; 08_Status: S2; 06_Omrade: TG; 01_Lufthavnkode: ENGM
Name | WEIGTH_NET (kg) | VOLUME_NET (m3) = Volume, net (Simplebim) (m3) | AREA_NET (m2) | Heigth (mm) = Depth (Simplebim) (mm) | Area, sides, net (Simplebim) (m2) | Weight, as steel (Simplebim) (kg) | Reference = Part mark | Assembly mark
2 x PREFABSØYLE | 4854.9 | 2.02288 | 13.4375 | 799.991 | 12.7204 | 15879.6 | Concrete-20168 | PS-439
PREFABSØYLE | 4859.01 | 2.02459 | 13.4257 | 799.775 | 12.7194 | 15893 | Concrete-828 | PS-166

# IfcColumn: B222 - HUP (Oppsveiset):B222 - HUP oppsveiset - 100 x 100 x 6.3 mm (2)
Type - PredefinedType: COLUMN; Material: _NSW Stål
Type - Pset_ColumnCommon - LoadBearing: yes
AVINOR - 08_Status: S4; 07_Fase: F90; 03_Ansvar: FDV; 06_Omrade: TG; 02_Prosjekt: T20100; 01_Lufthavnkode: ENGM
ePset_SimplebimBasicQuantities - Width (Simplebim): 100 mm; Depth (Simplebim): 100 mm
ePset_Simplebim - Assembly Level: Leaf
ePset_LocationTool - Splitting: ORIGINAL
Pset_QuantityTakeOff - Reference: B222 - HUP oppsveiset - 100 x 100 x 6.3 mm; sets with these values: 2
Pset_ColumnCommon - Reference: B222 - HUP oppsveiset - 100 x 100 x 6.3 mm; IsExternal: no
Group: Model Group:tettfelt 2 (members excluded):48741169
Name (B222 - HUP (Oppsveiset):B222 - HUP oppsveiset - 100 x 100 x 6.3 mm:...) | In | Volume, net (Simplebim) (m3) | Height (Simplebim) (mm) | Area, sides, net (Simplebim) (m2) | Weight, as steel (Simplebim) (kg)
48742604 | Nivå F - 0,7 m | 0.0022904 | 970 | 0.727112 | 17.9797
48742604 | Nivå F | 0.00661147 | 2800 | 2.09888 | 51.9001

# IfcColumn: B222 - HUP (Oppsveiset):B222 - HUP oppsveiset - 150 x 150 x 6 mm 2 (8)
Type - PredefinedType: COLUMN; Material: _NSW Stål
Type - Pset_ColumnCommon - LoadBearing: yes
AVINOR - 08_Status: S4; 07_Fase: F90; 02_Prosjekt: A162446; 03_Ansvar: 182412; 06_Omrade: TG; 01_Lufthavnkode: ENGM
ePset_LocationTool - Splitting: ORIGINAL
ePset_Simplebim - Assembly Level: Leaf
ePset_SimplebimBasicQuantities - Width (Simplebim): 150 mm; Depth (Simplebim): 150 mm
Pset_QuantityTakeOff - Reference: B222 - HUP oppsveiset - 150 x 150 x 6 mm 2; sets with these values: 2
Pset_ColumnCommon - IsExternal: no; Reference: B222 - HUP oppsveiset - 150 x 150 x 6 mm 2
Group: Model Group:A162446 - Utvidelse eksisterende Kiosk (members excluded):59114857
Name (B222 - HUP (Oppsveiset):B222 - HUP oppsveiset - 150 x 150 x 6 mm 2:...) | In | Weight, as steel (Simplebim) (kg) | Volume, net (Simplebim) (m3) | Height (Simplebim) (mm) | Area, sides, net (Simplebim) (m2)
59105812 | Nivå F - 0,7 m | 18.9907 | 0.0024192 | 700 | 0.8064
59105812 | Nivå F | 62.3981 | 0.0079488 | 2300 | 2.6496
59105896 | Nivå F - 0,7 m | 18.9907 | 0.0024192 | 700 | 0.8064
59105896 | Nivå F | 62.3981 | 0.0079488 | 2300 | 2.6496
59105898 | Nivå F - 0,7 m | 18.9907 | 0.0024192 | 700 | 0.8064
59105898 | Nivå F | 62.3981 | 0.0079488 | 2300 | 2.6496
59105900 | Nivå F - 0,7 m | 18.9907 | 0.0024192 | 700 | 0.8064
59105900 | Nivå F | 62.3981 | 0.0079488 | 2300 | 2.6496

# IfcColumn: B222 - HUP1:B222 - HUP 90x60x5 (4)
Type - PredefinedType: COLUMN; Material: _NSW Stål
Type - Pset_ColumnCommon - LoadBearing: yes
Pset_ReinforcementBarPitchOfColumn - Reference: B222 - HUP 90x60x5; sets with these values: 2
Pset_ColumnCommon - IsExternal: no; Reference: B222 - HUP 90x60x5
ePset_LocationTool - Splitting: ORIGINAL
ePset_SimplebimBasicQuantities - Width (Simplebim): 80 mm; Depth (Simplebim): 120 mm
ePset_Simplebim - Assembly Level: Leaf
Group: Model Group:pylon 2430 (members excluded):59105865
Name (B222 - HUP1:B222 - HUP 90x60x5:...) | In | Weight, as steel (Simplebim) (kg) | Area, sides, net (Simplebim) (m2) | Volume, net (Simplebim) (m3) | Height (Simplebim) (mm)
59105859 | Nivå F - 0,7 m | 12.2226 | 0.514567 | 0.00155702 | 700
59105859 | Nivå F | 30.2057 | 1.27169 | 0.00384786 | 1730
59105863 | Nivå F - 0,7 m | 12.2227 | 0.514567 | 0.00155703 | 700
59105863 | Nivå F | 30.2058 | 1.27169 | 0.00384788 | 1730

# IfcColumn: B222 - UNP (U-profil):B222 - UNP 120 (4)
Type - PredefinedType: COLUMN; Material: _NSW Stål
Type - Pset_ColumnCommon - LoadBearing: yes
Pset_ReinforcementBarPitchOfColumn - Reference: B222 - UNP 120; sets with these values: 2
Pset_ColumnCommon - Reference: B222 - UNP 120; IsExternal: no
AVINOR - 08_Status: S4; 07_Fase: F90; 03_Ansvar: FDV; 06_Omrade: TG; 02_Prosjekt: T20100; 01_Lufthavnkode: ENGM
ePset_SimplebimBasicQuantities - Width (Simplebim): 55 mm; Depth (Simplebim): 120 mm
ePset_Simplebim - Assembly Level: Leaf
ePset_LocationTool - Splitting: ORIGINAL
Name (B222 - UNP (U-profil):B222 - UNP 120:...) | In | Area, sides, net (Simplebim) (m2) | Volume, net (Simplebim) (m3) | Height (Simplebim) (mm) | Weight, as steel (Simplebim) (kg)
49351539 | Nivå F - 0,7 m | 0.338916 | 0.0012958 | 770 | 10.1721
49351539 | Nivå F | 1.23242 | 0.00471201 | 2800 | 36.9893
49351541 | Nivå F - 0,7 m | 0.338916 | 0.0012958 | 770 | 10.1721
49351541 | Nivå F | 1.23242 | 0.00471201 | 2800 | 36.9893

# IfcColumn: B222 - Vinkelprofil:B222 - Stålvinkel - 150 x 150 x 12 mm (4)
Type - PredefinedType: COLUMN; Material: _NSW Stål
Type - Pset_ColumnCommon - LoadBearing: yes
AVINOR - 08_Status: S4; 07_Fase: F90; 03_Ansvar: FDV; 06_Omrade: TG; 02_Prosjekt: T20100; 01_Lufthavnkode: ENGM
Pset_ReinforcementBarPitchOfColumn - Reference: B222 - Stålvinkel - 150 x 150 x 12 mm; sets with these values: 2
Pset_ColumnCommon - IsExternal: no; Reference: B222 - Stålvinkel - 150 x 150 x 12 mm
ePset_Simplebim - Assembly Level: Leaf
ePset_SimplebimBasicQuantities - Width (Simplebim): 150 mm; Depth (Simplebim): 150 mm
ePset_LocationTool - Splitting: ORIGINAL
Name (B222 - Vinkelprofil:B222 - Stålvinkel - 150 x 150 x 12 mm:...) | In | Weight, as steel (Simplebim) (kg) | Height (Simplebim) (mm) | Area, sides, net (Simplebim) (m2) | Volume, net (Simplebim) (m3)
49351535 | Nivå F - 0,7 m | 21.0595 | 770 | 0.45138 | 0.00268274
49351535 | Nivå F | 76.58 | 2800 | 1.64138 | 0.00975541
49351537 | Nivå F - 0,7 m | 21.0595 | 770 | 0.45138 | 0.00268274
49351537 | Nivå F | 76.58 | 2800 | 1.64138 | 0.00975541

# IfcColumn: HEA140 (4)
In: F
Description: HEA140; Material: STEEL/S355
Tekla Quantity - WEIGTH_GROSS: 77.1512 kg; AREA_NET: 2.55536 m2; AREA_GROSS: 2.48363 m2; Width: 140 mm; Heigth: 133 mm; Length: 3128 mm; WEIGTH_NET: 74.1064 kg; VOLUME_NET: 0.00944 m3; VOLUME_GROSS: 0.00983 m3
ePset_LocationTool - Splitting: ORIGINAL
Tekla Common - Grade: S355; Class: 320; Bottom elevation: +210.145; Name: STÅLSØYLE; Assembly mark: SS-8790(?); Top elevation: +213.273; Part mark: DSS-6485(?); Profile: HEA140
ePset_Simplebim - Assembly Level: Leaf
Pset_ColumnCommon - LoadBearing: no; Reference: DSS-6485(?)
ePset_SimplebimBasicQuantities - Area, sides, net (Simplebim): 2.54932 m2; Volume, net (Simplebim): 0.0094403 m3; Width (Simplebim): 133 mm; Depth (Simplebim): 140 mm; Height (Simplebim): 3128 mm; Weight, as steel (Simplebim): 74.1064 kg
AVINOR - 07_Fase: F90; 02_Prosjekt: T1; 04_Kontrakt: FDV; 03_Ansvar: FDV; 08_Status: S2; 06_Omrade: TG; 01_Lufthavnkode: ENGM

# IfcColumn: HEA240 (2)
In: F
Description: HEA240; Material: STEEL/S355
Tekla Quantity - WEIGTH_GROSS: 170.523 kg; VOLUME_GROSS: 0.02172 m3; AREA_NET: 3.98655 m2; AREA_GROSS: 3.87016 m2; VOLUME_NET: 0.02065 m3; Heigth: 230 mm; Width: 240 mm; Length: 2827 mm; WEIGTH_NET: 162.112 kg
ePset_SimplebimBasicQuantities - Area, sides, net (Simplebim): 3.97194 m2; Volume, net (Simplebim): 0.0206512 m3; Depth (Simplebim): 240 mm; Width (Simplebim): 230 mm; Height (Simplebim): 2827 mm; Weight, as steel (Simplebim): 162.112 kg
ePset_Simplebim - Assembly Level: Leaf
Tekla Common - Grade: S355; Assembly mark: SS-7548(?); Class: 320; Profile: HEA240; Name: STÅLSØYLE; Part mark: DSS-4527(?); Top elevation: +213.047; Bottom elevation: +210.220
ePset_LocationTool - Splitting: ORIGINAL
AVINOR - 07_Fase: F90; 02_Prosjekt: T1; 04_Kontrakt: FDV; 03_Ansvar: FDV; 08_Status: S2; 06_Omrade: TG; 01_Lufthavnkode: ENGM
Pset_ColumnCommon - Reference: DSS-4527(?); LoadBearing: no

# IfcColumn: PL10*138 (2)
In: F
Description: PL10*138; Material: STEEL/S355
Tekla Quantity - AREA_NET: 0.04335 m2; VOLUME_NET: 0.00019 m3; VOLUME_GROSS: 0.00019 m3; Heigth: 137.831 mm; Length: 137.837 mm; Width: 10 mm; AREA_GROSS: 0.019 m2; WEIGTH_NET: 1.48745 kg; WEIGTH_GROSS: 1.49136 kg
Tekla Common - Grade: S355; Class: 320; Name: STÅLSØYLE; Assembly mark: SS-7596(?); Part mark: DSS-0(?); Top elevation: +212.460; Bottom elevation: +212.450; Profile: PL10*138
Pset_ColumnCommon - LoadBearing: no; Reference: DSS-0(?)
ePset_SimplebimBasicQuantities - Volume, net (Simplebim): 0.000189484 m3; Depth (Simplebim): 137.831 mm; Height (Simplebim): 137.837 mm; Weight, as steel (Simplebim): 1.48745 kg; Width (Simplebim): 10 mm; Area, sides, net (Simplebim): 0.00544848 m2
ePset_LocationTool - Splitting: ORIGINAL
ePset_Simplebim - Assembly Level: Leaf
AVINOR - 07_Fase: F90; 02_Prosjekt: T1; 04_Kontrakt: FDV; 03_Ansvar: FDV; 08_Status: S2; 06_Omrade: TG; 01_Lufthavnkode: ENGM

# IfcColumn: PL10*160 (4)
In: F
Description: PL10*160; Material: STEEL/S355J0
Tekla Common - Part mark: DSS-5802(?); Class: 320; Name: STÅLSØYLE; Assembly mark: SS-8790(?); Grade: S355J0; Bottom elevation: +213.273; Top elevation: +213.283; Profile: PL10*160
Tekla Quantity - AREA_GROSS: 0.05522 m2; AREA_NET: 0.05522 m2; WEIGTH_GROSS: 1.92168 kg; WEIGTH_NET: 1.92168 kg; Width: 10 mm; Length: 153 mm; Heigth: 160 mm; VOLUME_NET: 0.00024 m3; VOLUME_GROSS: 0.00024 m3
Pset_ColumnCommon - Reference: DSS-5802(?); LoadBearing: no
ePset_Simplebim - Assembly Level: Leaf
ePset_LocationTool - Splitting: ORIGINAL
ePset_SimplebimBasicQuantities - Weight, as steel (Simplebim): 1.92168 kg; Volume, net (Simplebim): 0.0002448 m3; Area, sides, net (Simplebim): 0.00626 m2; Width (Simplebim): 10 mm; Depth (Simplebim): 153 mm; Height (Simplebim): 160 mm
AVINOR - 07_Fase: F90; 02_Prosjekt: T1; 04_Kontrakt: FDV; 03_Ansvar: FDV; 08_Status: S2; 06_Omrade: TG; 01_Lufthavnkode: ENGM

# IfcColumn: PL10*70 (8)
In: F
Description: PL10*70; Material: STEEL/S355
ePset_LocationTool - Splitting: ORIGINAL
Pset_ColumnCommon - LoadBearing: no; Reference: DSS-0(?)
ePset_SimplebimBasicQuantities - Width (Simplebim): 10 mm
Tekla Quantity - VOLUME_NET: 0.00002 m3; VOLUME_GROSS: 0.00002 m3; Width: 10 mm
ePset_Simplebim - Assembly Level: Leaf
Tekla Common - Grade: S355; Class: 320; Profile: PL10*70; Name: STÅLSØYLE; Assembly mark: SS-7596(?); Part mark: DSS-0(?)
AVINOR - 07_Fase: F90; 02_Prosjekt: T1; 04_Kontrakt: FDV; 03_Ansvar: FDV; 08_Status: S2; 06_Omrade: TG; 01_Lufthavnkode: ENGM
Name | Volume, net (Simplebim) (m3) | Weight, as steel (Simplebim) (kg) | Height (Simplebim) (mm) | Depth (Simplebim) (mm) | WEIGTH_NET (kg) | WEIGTH_GROSS (kg) | Length (mm) | AREA_NET (m2) | Heigth (mm) | AREA_GROSS (m2) | Bottom elevation | Top elevation
2 x STÅLSØYLE | 0.0000245 | 0.192325 | 70 | 70 | 0.19323 | 0.38647 | 70.1667 | 0.00732 | 70.1646 | 0.00492 | +212.355 | +212.425
2 x STÅLSØYLE | 0.0000245 | 0.192325 | 70 | 70 | 0.19233 | 0.38465 | 69.9997 | 0.00729 | 70.0006 | 0.0049 | +212.355 | +212.425
2 x STÅLSØYLE | 0.0000245 | 0.192325 | 70 | 70 | 0.19323 | 0.38647 | 70.1646 | 0.00732 | 70.1656 | 0.00492 | +210.260 | +210.330
2 x STÅLSØYLE | 0.0000245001 | 0.192326 | 98.9952 | 49.4976 | 0.19233 | 0.38465 | 70.0006 | 0.00729 | 69.9997 | 0.0049 | +210.260 | +210.330
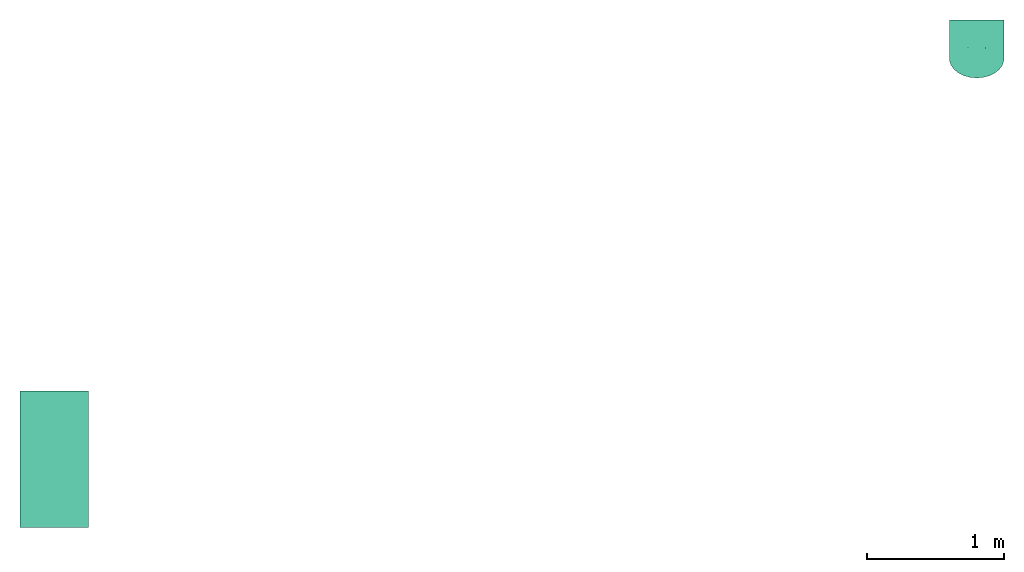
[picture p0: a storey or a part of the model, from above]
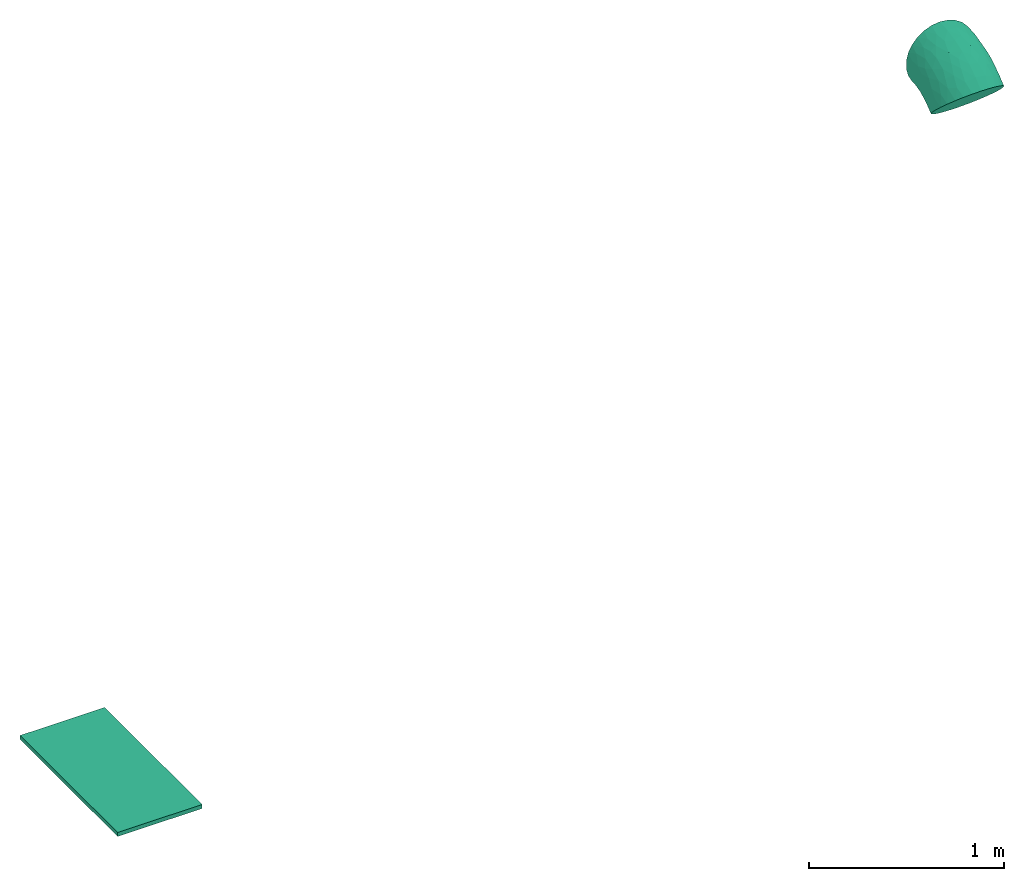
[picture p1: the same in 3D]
Properties of the parts of a building model (IFC2X3), part 3 of 11

# IfcColumn: PL15*160 (4)
In: F
Description: PL15*160; Material: STEEL/S355J0
ePset_SimplebimBasicQuantities - Volume, net (Simplebim): 0.0003672 m3; Weight, as steel (Simplebim): 2.88252 kg; Width (Simplebim): 15 mm; Depth (Simplebim): 153 mm; Height (Simplebim): 160 mm; Area, sides, net (Simplebim): 0.00939 m2
Tekla Common - Profile: PL15*160; Part mark: DSS-5487(?); Class: 320; Top elevation: +210.145; Bottom elevation: +210.130; Name: STÅLSØYLE; Assembly mark: SS-8790(?); Grade: S355J0
Pset_ColumnCommon - Reference: DSS-5487(?); LoadBearing: no
ePset_Simplebim - Assembly Level: Leaf
Tekla Quantity - VOLUME_GROSS: 0.00037 m3; VOLUME_NET: 0.00037 m3; WEIGTH_GROSS: 2.88252 kg; WEIGTH_NET: 2.88252 kg; AREA_NET: 0.05835 m2; AREA_GROSS: 0.05835 m2; Width: 15 mm; Length: 153 mm; Heigth: 160 mm
ePset_LocationTool - Splitting: ORIGINAL
AVINOR - 07_Fase: F90; 02_Prosjekt: T1; 04_Kontrakt: FDV; 03_Ansvar: FDV; 08_Status: S2; 06_Omrade: TG; 01_Lufthavnkode: ENGM

# IfcColumn: PL25*250 (4)
In: F
Description: PL25*250; Material: STEEL/S355
Pset_ColumnCommon - LoadBearing: no; Reference: DSS-0(?)
Tekla Quantity - Length: 250 mm; AREA_NET: 0.1253 m2; VOLUME_NET: 0.00128 m3; VOLUME_GROSS: 0.00128 m3; WEIGTH_NET: 10.0578 kg; WEIGTH_GROSS: 12.2656 kg; AREA_GROSS: 0.0625 m2; Width: 25 mm; Heigth: 250 mm
Tekla Common - Grade: S355; Bottom elevation: +210.070; Top elevation: +210.095; Class: 320; Profile: PL25*250; Name: STÅLSØYLE; Assembly mark: SS-7596(?); Part mark: DSS-0(?)
ePset_SimplebimBasicQuantities - Depth (Simplebim): 250 mm; Volume, net (Simplebim): 0.00128125 m3; Area, sides, net (Simplebim): 0.0228033 m2; Weight, as steel (Simplebim): 10.0578 kg; Width (Simplebim): 25 mm; Height (Simplebim): 250 mm
ePset_Simplebim - Assembly Level: Leaf
ePset_LocationTool - Splitting: ORIGINAL
AVINOR - 07_Fase: F90; 02_Prosjekt: T1; 04_Kontrakt: FDV; 03_Ansvar: FDV; 08_Status: S2; 06_Omrade: TG; 01_Lufthavnkode: ENGM

# IfcColumn: PL270*20 (2)
In: F
Description: PL270*20; Material: STEEL/S355
Tekla Common - Grade: S355; Profile: PL270*20; Assembly mark: SS-7548(?); Class: 320; Name: STÅLSØYLE; Part mark: DSS-625(?); Top elevation: +210.220; Bottom elevation: +210.200
Pset_ColumnCommon - LoadBearing: no; Reference: DSS-625(?)
ePset_SimplebimBasicQuantities - Volume, net (Simplebim): 0.001458 m3; Weight, as steel (Simplebim): 11.4453 kg; Width (Simplebim): 20 mm; Height (Simplebim): 270 mm; Depth (Simplebim): 270 mm; Area, sides, net (Simplebim): 0.0216 m2
ePset_LocationTool - Splitting: ORIGINAL
ePset_Simplebim - Assembly Level: Leaf
Tekla Quantity - AREA_GROSS: 0.1674 m2; AREA_NET: 0.1674 m2; WEIGTH_NET: 11.4453 kg; WEIGTH_GROSS: 11.4453 kg; VOLUME_NET: 0.00146 m3; VOLUME_GROSS: 0.00146 m3; Width: 20 mm; Heigth: 270 mm; Length: 270 mm
AVINOR - 07_Fase: F90; 02_Prosjekt: T1; 04_Kontrakt: FDV; 03_Ansvar: FDV; 08_Status: S2; 06_Omrade: TG; 01_Lufthavnkode: ENGM

# IfcColumn: PL30*345, STÅLDIAGONAL
In: D
Description: PL30*345; Material: STEEL/S355
ePset_SimplebimBasicQuantities - Volume, net (Simplebim): 0.0052605 m3; Area, sides, net (Simplebim): 0.360882 m2; Width (Simplebim): 30 mm; Depth (Simplebim): 345 mm; Height (Simplebim): 700 mm; Weight, as steel (Simplebim): 41.2949 kg
Pset_ColumnCommon - Reference: DSD-82(?); LoadBearing: no
ePset_Simplebim - Assembly Level: Leaf
Tekla Quantity - WEIGTH_GROSS: 56.8732 kg; AREA_GROSS: 0.2415 m2; AREA_NET: 0.40119 m2; WEIGTH_NET: 41.2949 kg; Width: 30 mm; Heigth: 345 mm; Length: 700 mm; VOLUME_NET: 0.00526 m3; VOLUME_GROSS: 0.00526 m3
AVINOR - 07_Fase: F90; 02_Prosjekt: T1; 04_Kontrakt: FDV; 03_Ansvar: FDV; 08_Status: S2; 06_Omrade: TG; 01_Lufthavnkode: ENGM
Tekla Common - Top elevation: +209.735; Grade: S355; Bottom elevation: +209.390; Part mark: DSD-82(?); Assembly mark: SD-136(?); Name: STÅLDIAGONAL; Profile: PL30*345; Class: 331
ePset_LocationTool - Splitting: ORIGINAL

# IfcColumn: PL300*20 (2)
In: F
Description: PL300*20; Material: STEEL/S355
Tekla Common - Grade: S355; Part mark: DSS-3991(?); Top elevation: +210.050; Bottom elevation: +210.030; Assembly mark: SS-7548(?); Class: 320; Name: STÅLSØYLE; Profile: PL300*20
ePset_SimplebimBasicQuantities - Area, sides, net (Simplebim): 0.024 m2; Weight, as steel (Simplebim): 14.13 kg; Width (Simplebim): 20 mm; Height (Simplebim): 300 mm; Depth (Simplebim): 300 mm; Volume, net (Simplebim): 0.0018 m3
Pset_ColumnCommon - Reference: DSS-3991(?); LoadBearing: no
ePset_Simplebim - Assembly Level: Leaf
ePset_LocationTool - Splitting: ORIGINAL
Tekla Quantity - WEIGTH_GROSS: 14.13 kg; WEIGTH_NET: 14.13 kg; AREA_NET: 0.204 m2; AREA_GROSS: 0.204 m2; Width: 20 mm; Heigth: 300 mm; Length: 300 mm; VOLUME_NET: 0.0018 m3; VOLUME_GROSS: 0.0018 m3
AVINOR - 07_Fase: F90; 02_Prosjekt: T1; 04_Kontrakt: FDV; 03_Ansvar: FDV; 08_Status: S2; 06_Omrade: TG; 01_Lufthavnkode: ENGM

# IfcColumn: PL5*134 (6)
In: D
Description: PL5*134; Material: STEEL/S355J0
Pset_ColumnCommon - Reference: DSS-6966(?); LoadBearing: no
ePset_LocationTool - Splitting: ORIGINAL
AVINOR - 07_Fase: F90; 02_Prosjekt: T1; 04_Kontrakt: FDV; 03_Ansvar: FDV; 08_Status: S2; 05_ID-nummer: +TA=222.002; 06_Omrade: TG; 01_Lufthavnkode: ENGM
ePset_Simplebim - Assembly Level: Leaf
ePset_SimplebimBasicQuantities - Volume, net (Simplebim): 0.00008978 m3; Weight, as steel (Simplebim): 0.704773 kg; Area, sides, net (Simplebim): 0.00268 m2; Width (Simplebim): 5 mm; Height (Simplebim): 134 mm; Depth (Simplebim): 134 mm
Tekla Common - Part mark: DSS-6966(?); Class: 320; Profile: PL5*134; Name: STÅLSØYLE; Grade: S355J0
Tekla Quantity - VOLUME_NET: 0.00008 m3; VOLUME_GROSS: 0.00008 m3; AREA_GROSS: 0.03859 m2; AREA_NET: 0.03859 m2; WEIGTH_NET: 0.70477 kg; WEIGTH_GROSS: 0.70477 kg; Width: 5 mm; Heigth: 134 mm; Length: 134 mm
Name | Top elevation | Bottom elevation | Assembly mark
STÅLSØYLE | +209.310 | +209.305 | SS-9073(?)
3 x STÅLSØYLE | +209.570 | +209.565 | SS-9077(?)
2 x STÅLSØYLE | +209.765 | +209.760 | SS-9080(?)

# IfcColumn: RHS100*5 (4)
In: F
Description: RHS100*5; Material: STEEL/S355
ePset_LocationTool - Splitting: ORIGINAL
ePset_Simplebim - Assembly Level: Leaf
ePset_SimplebimBasicQuantities - Volume, net (Simplebim): 0.00019 m3; Weight, as steel (Simplebim): 1.4915 kg; Height (Simplebim): 100 mm; Width (Simplebim): 100 mm; Depth (Simplebim): 100 mm; Area, sides, net (Simplebim): 0.076 m2
Tekla Common - Grade: S355; Bottom elevation: +210.030; Profile: RHS100*5; Class: 320; Top elevation: +210.130; Part mark: DSS-6795(?); Name: STÅLSØYLE; Assembly mark: SS-8790(?)
Tekla Quantity - VOLUME_NET: 0.00019 m3; VOLUME_GROSS: 0.00019 m3; WEIGTH_GROSS: 1.48365 kg; AREA_NET: 0.042 m2; WEIGTH_NET: 1.4915 kg; Heigth: 100 mm; Width: 100 mm; Length: 100 mm; AREA_GROSS: 0.0389 m2
Pset_ColumnCommon - Reference: DSS-6795(?); LoadBearing: no
AVINOR - 07_Fase: F90; 02_Prosjekt: T1; 04_Kontrakt: FDV; 03_Ansvar: FDV; 08_Status: S2; 06_Omrade: TG; 01_Lufthavnkode: ENGM

# IfcColumn: RHS140*10 (5)
In: D
Description: RHS140*10; Material: STEEL/S355
Pset_ColumnCommon - LoadBearing: no; Reference: DSS-5952(?)
ePset_LocationTool - Splitting: ORIGINAL
ePset_SimplebimBasicQuantities - Volume, net (Simplebim): 0.00124795 m3; Weight, as steel (Simplebim): 9.79639 kg; Width (Simplebim): 140 mm; Depth (Simplebim): 140 mm; Height (Simplebim): 239.99 mm; Area, sides, net (Simplebim): 0.24959 m2
Tekla Common - Grade: S355; Profile: RHS140*10; Class: 320; Name: STÅLSØYLE; Part mark: DSS-5952(?)
Tekla Quantity - WEIGTH_GROSS: 9.7022 kg; VOLUME_GROSS: 0.00124 m3; AREA_NET: 0.13999 m2; WEIGTH_NET: 9.79639 kg; Heigth: 140 mm; Width: 140 mm; AREA_GROSS: 0.12935 m2; Length: 239.99 mm; VOLUME_NET: 0.00125 m3
AVINOR - 07_Fase: F90; 02_Prosjekt: T1; 04_Kontrakt: FDV; 03_Ansvar: FDV; 08_Status: S2; 05_ID-nummer: +TA=222.002; 06_Omrade: TG; 01_Lufthavnkode: ENGM
ePset_Simplebim - Assembly Level: Leaf
Name | Top elevation | Bottom elevation | Assembly mark
3 x STÅLSØYLE | +209.565 | +209.325 | SS-9077(?)
2 x STÅLSØYLE | +209.760 | +209.520 | SS-9080(?)

# IfcColumn: RHS250*250*10 (2)
In: F
Description: RHS250*250*10; Material: STEEL/S355
ePset_SimplebimBasicQuantities - Weight, as steel (Simplebim): 11.304 kg; Area, sides, net (Simplebim): 0.288 m2; Volume, net (Simplebim): 0.00144 m3; Width (Simplebim): 150 mm; Height (Simplebim): 250 mm; Depth (Simplebim): 250 mm
ePset_Simplebim - Assembly Level: Leaf
Tekla Common - Grade: S355; Bottom elevation: +210.050; Profile: RHS250*250*10; Assembly mark: SS-7548(?); Class: 320; Name: STÅLSØYLE; Part mark: DSS-4880(?); Top elevation: +210.200
Tekla Quantity - WEIGTH_NET: 11.304 kg; WEIGTH_GROSS: 11.2451 kg; VOLUME_GROSS: 0.00143 m3; VOLUME_NET: 0.00144 m3; AREA_GROSS: 0.14685 m2; Length: 150 mm; Heigth: 250 mm; Width: 250 mm; AREA_NET: 0.16 m2
Pset_ColumnCommon - LoadBearing: no; Reference: DSS-4880(?)
ePset_LocationTool - Splitting: ORIGINAL
AVINOR - 07_Fase: F90; 02_Prosjekt: T1; 04_Kontrakt: FDV; 03_Ansvar: FDV; 08_Status: S2; 06_Omrade: TG; 01_Lufthavnkode: ENGM

# IfcColumn: RHS80*80*5 (6)
In: F
Description: RHS80*80*5; Material: STEEL/S355
ePset_SimplebimBasicQuantities - Area, sides, net (Simplebim): 1.989 m2; Width (Simplebim): 80 mm; Depth (Simplebim): 80 mm; Height (Simplebim): 3315 mm; Volume, net (Simplebim): 0.0049725 m3; Weight, as steel (Simplebim): 39.0341 kg
Pset_ColumnCommon - LoadBearing: no; Reference: DSS-814(?)
ePset_LocationTool - Splitting: ORIGINAL
Tekla Quantity - AREA_GROSS: 1.02433 m2; VOLUME_NET: 0.00497 m3; VOLUME_GROSS: 0.00494 m3; AREA_NET: 1.0624 m2; WEIGTH_NET: 39.0341 kg; Heigth: 80 mm; Width: 80 mm; Length: 3315 mm; WEIGTH_GROSS: 38.7739 kg
ePset_Simplebim - Assembly Level: Leaf
Tekla Common - Grade: S355; Profile: RHS80*80*5; Bottom elevation: +210.025; Class: 320; Top elevation: +213.340; Assembly mark: SS-579(?); Name: STÅLSØYLE; Part mark: DSS-814(?)
AVINOR - 07_Fase: F90; 02_Prosjekt: T1; 04_Kontrakt: FDV; 03_Ansvar: FDV; 08_Status: S2; 06_Omrade: TG; 01_Lufthavnkode: ENGM

# IfcColumn: T100 (4)
In: F
Description: T100; Material: STEEL/S355
ePset_LocationTool - Splitting: ORIGINAL
Tekla Common - Grade: S355; Bottom elevation: +212.847; Profile: T100; Part mark: DSS-5017(?); Assembly mark: SS-7548(?); Class: 320; Name: STÅLSØYLE; Top elevation: +213.047
Pset_ColumnCommon - Reference: DSS-5017(?); LoadBearing: no
ePset_Simplebim - Assembly Level: Leaf
Tekla Quantity - WEIGTH_NET: 2.72434 kg; VOLUME_NET: 0.00035 m3; AREA_NET: 0.07063 m2; Heigth: 100 mm; Width: 100 mm; Length: 200 mm; WEIGTH_GROSS: 3.2813 kg; AREA_GROSS: 0.08 m2; VOLUME_GROSS: 0.00042 m3
ePset_SimplebimBasicQuantities - Area, sides, net (Simplebim): 0.0678427 m2; Width (Simplebim): 100 mm; Depth (Simplebim): 100 mm; Height (Simplebim): 200 mm; Weight, as steel (Simplebim): 2.72434 kg; Volume, net (Simplebim): 0.00034705 m3
AVINOR - 07_Fase: F90; 02_Prosjekt: T1; 04_Kontrakt: FDV; 03_Ansvar: FDV; 08_Status: S2; 06_Omrade: TG; 01_Lufthavnkode: ENGM

# IfcColumn: T80, STÅLSØYLE
In: F
Description: T80; Material: STEEL/S355
ePset_LocationTool - Splitting: ORIGINAL
ePset_SimplebimBasicQuantities - Height (Simplebim): 3345 mm; Area, sides, net (Simplebim): 1.04834 m2; Weight, as steel (Simplebim): 34.9055 kg; Volume, net (Simplebim): 0.00444657 m3; Width (Simplebim): 80 mm; Depth (Simplebim): 80 mm
Tekla Common - Grade: S355; Part mark: DSS-7911(?); Class: 320; Profile: T80; Name: STÅLSØYLE; Assembly mark: SS-7596(?); Top elevation: +213.605; Bottom elevation: +210.260
ePset_Simplebim - Assembly Level: Leaf
Pset_ColumnCommon - Reference: DSS-7911(?); LoadBearing: no
Tekla Quantity - Length: 3345 mm; AREA_NET: 1.05105 m2; VOLUME_NET: 0.00445 m3; WEIGTH_NET: 34.9055 kg; AREA_GROSS: 1.0704 m2; WEIGTH_GROSS: 35.7112 kg; Heigth: 80 mm; Width: 80 mm; VOLUME_GROSS: 0.00455 m3
AVINOR - 07_Fase: F90; 02_Prosjekt: T1; 04_Kontrakt: FDV; 03_Ansvar: FDV; 08_Status: S2; 06_Omrade: TG; 01_Lufthavnkode: ENGM

# IfcColumn: UNP120 (3)
In: F
Description: UNP120; Material: STEEL/S355
Tekla Quantity - Width: 55 mm; Heigth: 120 mm
Tekla Common - Grade: S355; Class: 320; Name: STÅLSØYLE; Assembly mark: SS-7596(?); Top elevation: +212.410; Profile: UNP120
ePset_LocationTool - Splitting: ORIGINAL
ePset_Simplebim - Assembly Level: Leaf
Pset_ColumnCommon - LoadBearing: no
AVINOR - 07_Fase: F90; 02_Prosjekt: T1; 04_Kontrakt: FDV; 03_Ansvar: FDV; 08_Status: S2; 06_Omrade: TG; 01_Lufthavnkode: ENGM
ePset_SimplebimBasicQuantities - Width (Simplebim): 55 mm; Depth (Simplebim): 120 mm
Name | AREA_NET (m2) | VOLUME_NET (m3) | VOLUME_GROSS (m3) | WEIGTH_GROSS (kg) | AREA_GROSS (m2) | Length (mm) = Height (Simplebim) (mm) | WEIGTH_NET (kg) = Weight, as steel (Simplebim) (kg) | Part mark = Reference | Bottom elevation | Volume, net (Simplebim) (m3)
STÅLSØYLE | 0.48707 | 0.00184 | 0.00207 | 16.276 | 0.52932 | 1219.63 | 14.4771 | DSS-8072(?) | +212.290 | 0.00184421 | ePset_SimplebimBasicQuantities - Area, sides, net (Simplebim): 0.26021 m2
STÅLSØYLE | 0.99315 | 0.00378 | 0.00394 | 30.8937 | 1.00471 | 2315 | 29.688 | DSS-4540(?) | +210.095 | 0.00378191
STÅLSØYLE | 0.99315 | 0.00378 | 0.00394 | 30.8937 | 1.00471 | 2315 | 29.688 | DSS-4538(?) | +210.095 | 0.00378191

# IfcCovering (435)
PredefinedType: INSULATION
ePset_Simplebim - Assembly Level: Leaf
Name | In | Description | Area, largest surface, net (Simplebim) (m2) | Length (Simplebim) (mm) | Width (Simplebim) (mm) | Volume, net (Simplebim) (m3) | Height (Simplebim) (mm) | Splitting | SystemType | Material | MagiCAD Pset_Pipe, User Code | MagiCAD Pset_Pipe, NationalCode | SystemClass
BI17T - Cellegummi 13 mm SPV fett | Nivå F - 0,7 m | BI17T - Cellegummi 13 mm SPV fett | 0.00689709 | 58 | 58 | 0.0000693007 | 37.9 | ORIGINAL | SPV FETT | PP avløpsrør | PP | UB2.1114431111 | Sanitary | MagiCAD Pset_Heating - v_SizingFlow_ms: 0 m/s; pTot_SizingFlow_kPa: 0 kPa; dpTot_SizingFlow_kPa: 0 kPa; MagiCAD Pset_Water - dpTot_SizingFlow_kPa: 0 kPa; pTot_SizingFlow_kPa: 0 kPa; v_SizingFlow_ms: 0 m/s; MagiCAD Pset_Pipe - Length_mm: 37.92 mm; qv_SizingFlow_ls: 0 m3/s; SystemName: 31= SPV Kopi 138; Insulation_thickness_mm: 13 mm; ConnectionSize_mm: 32 mm
3 x BI17T - Cellegummi 13 mm SPV fett | Nivå F - 0,7 m | BI17T - Cellegummi 13 mm SPV fett | 0.0626278 | 199.49 | 157 | 0.00348595 | 199.075 | ORIGINAL | MagiCAD Pset_Elbow - Description: Generic PVC Bend; qv_SizingFlow_ls: 0 m3/s; pTot_SizingFlow_Pa: 0 kPa; dpTot_SizingFlow_Pa: 0 kPa; v_SizingFlow_ms: 0 m/s; ConnectionSize_mm: 0 mm; Insulation_thickness_mm: 13 mm
BI17T - Cellegummi 13 mm SPV fett | Nivå F - 0,7 m | BI17T - Cellegummi 13 mm SPV fett | 0.0086623 | 136 | 20.3 | 0.000101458 | 136 | ORIGINAL | SPV FETT | MA | MA | UB2.1115131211 | Sanitary | MagiCAD Pset_Heating - v_SizingFlow_ms: 0 m/s; pTot_SizingFlow_kPa: 0 kPa; dpTot_SizingFlow_kPa: 0 kPa; MagiCAD Pset_Water - dpTot_SizingFlow_kPa: 0 kPa; pTot_SizingFlow_kPa: 0 kPa; v_SizingFlow_ms: 0 m/s; MagiCAD Pset_Pipe - Length_mm: 20.278 mm; qv_SizingFlow_ls: 0 m3/s; SystemName: 31= SPV Kopi 138; Insulation_thickness_mm: 13 mm; ConnectionSize_mm: 110 mm
BI17T - Cellegummi 13 mm SPV fett | Nivå F - 0,7 m | BI17T - Cellegummi 13 mm SPV fett | 0.0435837 | 160.911 | 137.527 | 0.00158751 | 147 | ORIGINAL | MagiCAD Pset_Elbow - Description: Generic PVC Bend; qv_SizingFlow_ls: 0 m3/s; pTot_SizingFlow_Pa: 0 kPa; dpTot_SizingFlow_Pa: 0 kPa; v_SizingFlow_ms: 0 m/s; ConnectionSize_mm: 0 mm; Insulation_thickness_mm: 13 mm
BI17T - Cellegummi 13 mm SPV fett | Nivå F - 0,7 m | BI17T - Cellegummi 13 mm SPV fett | 0.158482 | 371.4 | 136 | 0.00185624 | 136 | ORIGINAL | SPV FETT | MA | MA | UB2.1115131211 | Sanitary | MagiCAD Pset_Heating - v_SizingFlow_ms: 0 m/s; pTot_SizingFlow_kPa: 0 kPa; dpTot_SizingFlow_kPa: 0 kPa; MagiCAD Pset_Water - dpTot_SizingFlow_kPa: 0 kPa; pTot_SizingFlow_kPa: 0 kPa; v_SizingFlow_ms: 0 m/s; MagiCAD Pset_Pipe - Length_mm: 371.355 mm; qv_SizingFlow_ls: 0 m3/s; SystemName: 31= SPV Kopi 138; Insulation_thickness_mm: 13 mm; ConnectionSize_mm: 110 mm
BI17T - Cellegummi 13 mm SPV fett | Nivå F - 0,7 m | BI17T - Cellegummi 13 mm SPV fett | 1.52862 | 3582.3 | 136 | 0.0179041 | 136 | ORIGINAL | SPV FETT | MA | MA | UB2.1115131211 | Sanitary | MagiCAD Pset_Heating - v_SizingFlow_ms: 0 m/s; pTot_SizingFlow_kPa: 0 kPa; dpTot_SizingFlow_kPa: 0 kPa; MagiCAD Pset_Water - dpTot_SizingFlow_kPa: 0 kPa; pTot_SizingFlow_kPa: 0 kPa; v_SizingFlow_ms: 0 m/s; MagiCAD Pset_Pipe - Length_mm: 3582.26 mm; qv_SizingFlow_ls: 0 m3/s; SystemName: 31= SPV Kopi 138; Insulation_thickness_mm: 13 mm; ConnectionSize_mm: 110 mm
BI17T - Cellegummi 13 mm SPV fett | Nivå F - 0,7 m | BI17T - Cellegummi 13 mm SPV fett | 0.0453766 | 239.357 | 238.016 | 0.00761463 | 171.021 | ORIGINAL | MagiCAD Pset_TBranch - qv_SizingFlow_ls: 0 m3/s; pTot_SizingFlow_Pa: 0 kPa; dpTot_SizingFlow_Pa: 0 kPa; v_SizingFlow_ms: 0 m/s; ConnectionSize_mm: 0 mm; Insulation_thickness_mm: 13 mm
BI17T - Cellegummi 13 mm SPV fett | Nivå F - 0,7 m | BI17T - Cellegummi 13 mm SPV fett | 0.18784 | 440.2 | 136 | 0.00220009 | 136 | ORIGINAL | SPV FETT | MA | MA | UB2.1115131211 | Sanitary | MagiCAD Pset_Heating - v_SizingFlow_ms: 0 m/s; pTot_SizingFlow_kPa: 0 kPa; dpTot_SizingFlow_kPa: 0 kPa; MagiCAD Pset_Water - dpTot_SizingFlow_kPa: 0 kPa; pTot_SizingFlow_kPa: 0 kPa; v_SizingFlow_ms: 0 m/s; MagiCAD Pset_Pipe - Length_mm: 440.221 mm; qv_SizingFlow_ls: 0 m3/s; SystemName: 31= SPV Kopi 138; Insulation_thickness_mm: 13 mm; ConnectionSize_mm: 110 mm
BI17T - Cellegummi 13 mm SPV fett | Nivå F - 0,7 m | BI17T - Cellegummi 13 mm SPV fett | 0.162152 | 380 | 136 | 0.00189922 | 136 | ORIGINAL | SPV FETT | MA | MA | UB2.1115131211 | Sanitary | MagiCAD Pset_Heating - v_SizingFlow_ms: 0 m/s; pTot_SizingFlow_kPa: 0 kPa; dpTot_SizingFlow_kPa: 0 kPa; MagiCAD Pset_Water - dpTot_SizingFlow_kPa: 0 kPa; pTot_SizingFlow_kPa: 0 kPa; v_SizingFlow_ms: 0 m/s; MagiCAD Pset_Pipe - Length_mm: 379.99 mm; qv_SizingFlow_ls: 0 m3/s; SystemName: 31= SPV Kopi 138; Insulation_thickness_mm: 13 mm; ConnectionSize_mm: 110 mm
BI17T - Cellegummi 13 mm SPV fett | Nivå F - 0,7 m | BI17T - Cellegummi 13 mm SPV fett | 0.165224 | 387.2 | 136 | 0.0019352 | 136 | ORIGINAL | SPV FETT | MA | MA | UB2.1115131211 | Sanitary | MagiCAD Pset_Heating - v_SizingFlow_ms: 0 m/s; pTot_SizingFlow_kPa: 0 kPa; dpTot_SizingFlow_kPa: 0 kPa; MagiCAD Pset_Water - dpTot_SizingFlow_kPa: 0 kPa; pTot_SizingFlow_kPa: 0 kPa; v_SizingFlow_ms: 0 m/s; MagiCAD Pset_Pipe - Length_mm: 387.157 mm; qv_SizingFlow_ls: 0 m3/s; SystemName: 31= SPV Kopi 138; Insulation_thickness_mm: 13 mm; ConnectionSize_mm: 110 mm
BI17T - Cellegummi 13 mm SPV fett | Nivå F - 0,7 m | BI17T - Cellegummi 13 mm SPV fett | 0.224068 | 525.1 | 136 | 0.00262442 | 136 | ORIGINAL | SPV FETT | MA | MA | UB2.1115131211 | Sanitary | MagiCAD Pset_Heating - v_SizingFlow_ms: 0 m/s; pTot_SizingFlow_kPa: 0 kPa; dpTot_SizingFlow_kPa: 0 kPa; MagiCAD Pset_Water - dpTot_SizingFlow_kPa: 0 kPa; pTot_SizingFlow_kPa: 0 kPa; v_SizingFlow_ms: 0 m/s; MagiCAD Pset_Pipe - Length_mm: 525.125 mm; qv_SizingFlow_ls: 0 m3/s; SystemName: 31= SPV Kopi 138; Insulation_thickness_mm: 13 mm; ConnectionSize_mm: 110 mm
BI10T - Cellegummi 18-32 mm kalde rør | Nivå F - 0,7 m | BI10T - Cellegummi 18-32 mm kalde rør | 0.352165 | 2440 | 46 | 0.00375993 | 46 | ORIGINAL | KV | Kobberrør | Cu | UB1.111713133 | Domestic Cold Water | MagiCAD Pset_Heating - v_SizingFlow_ms: 0 m/s; pTot_SizingFlow_kPa: 0 kPa; dpTot_SizingFlow_kPa: 0 kPa; MagiCAD Pset_Water - dpTot_SizingFlow_kPa: 0 kPa; pTot_SizingFlow_kPa: 0 kPa; v_SizingFlow_ms: 0 m/s; MagiCAD Pset_Pipe - Length_mm: 2440 mm; qv_SizingFlow_ls: 0 m3/s; SystemName: 31=KV Kopi 13; Insulation_thickness_mm: 17 mm; ConnectionSize_mm: 12 mm
BI16T - Rørskål m/Al.folie - VV 40mm | Nivå F - 0,7 m | BI16T - Rørskål m/Al.folie - VV 40mm | 0.474657 | 2440 | 62 | 0.00705463 | 62 | ORIGINAL | VV | Kobberrør | Cu | UB1.111713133 | Domestic Hot Water | MagiCAD Pset_Heating - v_SizingFlow_ms: 0 m/s; pTot_SizingFlow_kPa: 0 kPa; dpTot_SizingFlow_kPa: 0 kPa; MagiCAD Pset_Water - dpTot_SizingFlow_kPa: 0 kPa; pTot_SizingFlow_kPa: 0 kPa; v_SizingFlow_ms: 0 m/s; MagiCAD Pset_Pipe - Length_mm: 2440 mm; qv_SizingFlow_ls: 0 m3/s; SystemName: 31= VV Kopi 11; Insulation_thickness_mm: 25 mm; ConnectionSize_mm: 12 mm
BI10T - Cellegummi 18-32 mm kalde rør | Nivå F - 0,7 m | BI10T - Cellegummi 18-32 mm kalde rør | 0.558675 | 2871.9 | 62 | 0.00772886 | 62 | ORIGINAL | Kjøle Retur 17° | Stålrør normaltykke | DN | UB3.144613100 | Hydronic Return | MagiCAD Pset_Heating - v_SizingFlow_ms: 0 m/s; pTot_SizingFlow_kPa: 0 kPa; dpTot_SizingFlow_kPa: 0 kPa; MagiCAD Pset_Water - dpTot_SizingFlow_kPa: 0 kPa; pTot_SizingFlow_kPa: 0 kPa; v_SizingFlow_ms: 0 m/s; MagiCAD Pset_Pipe - Length_mm: 2871.88 mm; qv_SizingFlow_ls: 0 m3/s; SystemName: 37= R 12° Kopi 4; Insulation_thickness_mm: 21 mm; ConnectionSize_mm: 20 mm
BI10T - Cellegummi 18-32 mm kalde rør | Nivå F - 0,7 m | BI10T - Cellegummi 18-32 mm kalde rør | 0.0603023 | 343.2 | 56 | 0.000733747 | 56 | ORIGINAL | Kjøle Tur 14° | Stålrør normaltykke | DN | UB3.144613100 | Hydronic Supply | MagiCAD Pset_Heating - v_SizingFlow_ms: 0 m/s; pTot_SizingFlow_kPa: 0 kPa; dpTot_SizingFlow_kPa: 0 kPa; MagiCAD Pset_Water - dpTot_SizingFlow_kPa: 0 kPa; pTot_SizingFlow_kPa: 0 kPa; v_SizingFlow_ms: 0 m/s; MagiCAD Pset_Pipe - Length_mm: 343.2 mm; qv_SizingFlow_ls: 0 m3/s; SystemName: 37= T 7° Kopi 6; Insulation_thickness_mm: 18 mm; ConnectionSize_mm: 20 mm
BI10T - Cellegummi 18-32 mm kalde rør | Nivå F - 0,7 m | BI10T - Cellegummi 18-32 mm kalde rør | 0.0655735 | 373.2 | 56 | 0.000797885 | 56 | ORIGINAL | Kjøle Tur 14° | Stålrør normaltykke | DN | UB3.144613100 | Hydronic Supply | MagiCAD Pset_Heating - v_SizingFlow_ms: 0 m/s; pTot_SizingFlow_kPa: 0 kPa; dpTot_SizingFlow_kPa: 0 kPa; MagiCAD Pset_Water - dpTot_SizingFlow_kPa: 0 kPa; pTot_SizingFlow_kPa: 0 kPa; v_SizingFlow_ms: 0 m/s; MagiCAD Pset_Pipe - Length_mm: 373.2 mm; qv_SizingFlow_ls: 0 m3/s; SystemName: 37= T 7° Kopi 6; Insulation_thickness_mm: 18 mm; ConnectionSize_mm: 20 mm
BI10T - Cellegummi 18-32 mm kalde rør | Nivå F - 0,7 m | BI10T - Cellegummi 18-32 mm kalde rør | 0.0891532 | 507.4 | 56 | 0.0010848 | 56 | ORIGINAL | Kjøle Tur 14° | Stålrør normaltykke | DN | UB3.144613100 | Hydronic Supply | MagiCAD Pset_Heating - v_SizingFlow_ms: 0 m/s; pTot_SizingFlow_kPa: 0 kPa; dpTot_SizingFlow_kPa: 0 kPa; MagiCAD Pset_Water - dpTot_SizingFlow_kPa: 0 kPa; pTot_SizingFlow_kPa: 0 kPa; v_SizingFlow_ms: 0 m/s; MagiCAD Pset_Pipe - Length_mm: 507.389 mm; qv_SizingFlow_ls: 0 m3/s; SystemName: 37= T 7° Kopi 6; Insulation_thickness_mm: 18 mm; ConnectionSize_mm: 20 mm
4 x BI10T - Cellegummi 18-32 mm kalde rør | Nivå F - 0,7 m | BI10T - Cellegummi 18-32 mm kalde rør | 0.00720979 | 62.8 | 58.2 | 0.000128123 | 58.2 | ORIGINAL | MagiCAD Pset_Elbow - qv_SizingFlow_ls: 0 m3/s; pTot_SizingFlow_Pa: 0 kPa; dpTot_SizingFlow_Pa: 0 kPa; v_SizingFlow_ms: 0 m/s; ConnectionSize_mm: 0 mm; Insulation_thickness_mm: 18 mm
BI10T - Cellegummi 18-32 mm kalde rør | Nivå F - 0,7 m | BI10T - Cellegummi 18-32 mm kalde rør | 0.00471848 | 69.8 | 60.25 | 0.000284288 | 67.6 | ORIGINAL | MagiCAD Pset_TBranch - qv_SizingFlow_ls: 0 m3/s; pTot_SizingFlow_Pa: 0 kPa; dpTot_SizingFlow_Pa: 0 kPa; v_SizingFlow_ms: 0 m/s; ConnectionSize_mm: 0 mm; Insulation_thickness_mm: 18 mm
BI10T - Cellegummi 18-32 mm kalde rør | Nivå F - 0,7 m | BI10T - Cellegummi 18-32 mm kalde rør | 0.733151 | 4172.6 | 56 | 0.00892084 | 56 | ORIGINAL | Kjøle Tur 14° | Stålrør normaltykke | DN | UB3.144613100 | Hydronic Supply | MagiCAD Pset_Heating - v_SizingFlow_ms: 0 m/s; pTot_SizingFlow_kPa: 0 kPa; dpTot_SizingFlow_kPa: 0 kPa; MagiCAD Pset_Water - dpTot_SizingFlow_kPa: 0 kPa; pTot_SizingFlow_kPa: 0 kPa; v_SizingFlow_ms: 0 m/s; MagiCAD Pset_Pipe - Length_mm: 4172.58 mm; qv_SizingFlow_ls: 0 m3/s; SystemName: 37= T 7° Kopi 6; Insulation_thickness_mm: 18 mm; ConnectionSize_mm: 20 mm
2 x BI10T - Cellegummi 18-32 mm kalde rør | Nivå F - 0,7 m | BI10T - Cellegummi 18-32 mm kalde rør | 0.00295788 | 7 | 62.8 | 0.0000207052 | 62.8 | ORIGINAL | MagiCAD Pset_Reduction - qv_SizingFlow_ls: 0 m3/s; pTot_SizingFlow_Pa: 0 kPa; dpTot_SizingFlow_Pa: 0 kPa; v_SizingFlow_ms: 0 m/s; ConnectionSize_mm: 0 mm; Insulation_thickness_mm: 18 mm
BI10T - Cellegummi 18-32 mm kalde rør | Nivå F - 0,7 m | BI10T - Cellegummi 18-32 mm kalde rør | 0.0822655 | 468.2 | 56 | 0.00100099 | 56 | ORIGINAL | Kjøle Retur 17° | Stålrør normaltykke | DN | UB3.144613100 | Hydronic Return | MagiCAD Pset_Heating - v_SizingFlow_ms: 0 m/s; pTot_SizingFlow_kPa: 0 kPa; dpTot_SizingFlow_kPa: 0 kPa; MagiCAD Pset_Water - dpTot_SizingFlow_kPa: 0 kPa; pTot_SizingFlow_kPa: 0 kPa; v_SizingFlow_ms: 0 m/s; MagiCAD Pset_Pipe - Length_mm: 468.2 mm; qv_SizingFlow_ls: 0.096 m3/s; SystemName: 37= R 12° Kopi 6; Insulation_thickness_mm: 18 mm; ConnectionSize_mm: 20 mm
BI10T - Cellegummi 18-32 mm kalde rør | Nivå F - 0,7 m | BI10T - Cellegummi 18-32 mm kalde rør | 0.0822655 | 468.2 | 56 | 0.00100099 | 56 | ORIGINAL | Kjøle Retur 17° | Stålrør normaltykke | DN | UB3.144613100 | Hydronic Return | MagiCAD Pset_Heating - v_SizingFlow_ms: 0 m/s; pTot_SizingFlow_kPa: 0 kPa; dpTot_SizingFlow_kPa: 0 kPa; MagiCAD Pset_Water - dpTot_SizingFlow_kPa: 0 kPa; pTot_SizingFlow_kPa: 0 kPa; v_SizingFlow_ms: 0 m/s; MagiCAD Pset_Pipe - Length_mm: 468.2 mm; qv_SizingFlow_ls: 0 m3/s; SystemName: 37= R 12° Kopi 6; Insulation_thickness_mm: 18 mm; ConnectionSize_mm: 20 mm
BI10T - Cellegummi 18-32 mm kalde rør | Nivå F - 0,7 m | BI10T - Cellegummi 18-32 mm kalde rør | 0.377946 | 1974.7 | 61 | 0.00477733 | 61 | ORIGINAL | Kjøle Tur 14° | Stålrør normaltykke | DN | UB3.144613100 | Hydronic Supply | MagiCAD Pset_Heating - v_SizingFlow_ms: 0 m/s; pTot_SizingFlow_kPa: 0 kPa; dpTot_SizingFlow_kPa: 0 kPa; MagiCAD Pset_Water - dpTot_SizingFlow_kPa: 0 kPa; pTot_SizingFlow_kPa: 0 kPa; v_SizingFlow_ms: 0 m/s; MagiCAD Pset_Pipe - Length_mm: 1974.65 mm; qv_SizingFlow_ls: 0 m3/s; SystemName: 37= T 7° Kopi 6; Insulation_thickness_mm: 18 mm; ConnectionSize_mm: 25 mm
BI10T - Cellegummi 18-32 mm kalde rør | Nivå F - 0,7 m | BI10T - Cellegummi 18-32 mm kalde rør | 0.361007 | 1886.2 | 61 | 0.00456322 | 61 | ORIGINAL | Kjøle Retur 17° | Stålrør normaltykke | DN | UB3.144613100 | Hydronic Return | MagiCAD Pset_Heating - v_SizingFlow_ms: 0 m/s; pTot_SizingFlow_kPa: 0 kPa; dpTot_SizingFlow_kPa: 0 kPa; MagiCAD Pset_Water - dpTot_SizingFlow_kPa: 0 kPa; pTot_SizingFlow_kPa: 0 kPa; v_SizingFlow_ms: 0 m/s; MagiCAD Pset_Pipe - Length_mm: 1886.2 mm; qv_SizingFlow_ls: 0 m3/s; SystemName: 37= R 12° Kopi 6; Insulation_thickness_mm: 18 mm; ConnectionSize_mm: 25 mm
BI10T - Cellegummi 18-32 mm kalde rør | Nivå F - 0,7 m | BI10T - Cellegummi 18-32 mm kalde rør | 0.00269866 | 61 | 61 | 0.0000341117 | 14.1 | ORIGINAL | Kjøle Retur 17° | Stålrør normaltykke | DN | UB3.144613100 | Hydronic Return | MagiCAD Pset_Heating - v_SizingFlow_ms: 0 m/s; pTot_SizingFlow_kPa: 0 kPa; dpTot_SizingFlow_kPa: 0 kPa; MagiCAD Pset_Water - dpTot_SizingFlow_kPa: 0 kPa; pTot_SizingFlow_kPa: 0 kPa; v_SizingFlow_ms: 0 m/s; MagiCAD Pset_Pipe - Length_mm: 14.1 mm; qv_SizingFlow_ls: 0 m3/s; SystemName: 37= R 12° Kopi 6; Insulation_thickness_mm: 18 mm; ConnectionSize_mm: 25 mm
BI10T - Cellegummi 18-32 mm kalde rør | Nivå F - 0,7 m | BI10T - Cellegummi 18-32 mm kalde rør | 0.00471848 | 69.8 | 67.6 | 0.000243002 | 51.5 | ORIGINAL | MagiCAD Pset_TBranch - qv_SizingFlow_ls: 0 m3/s; pTot_SizingFlow_Pa: 0 kPa; dpTot_SizingFlow_Pa: 0 kPa; v_SizingFlow_ms: 0 m/s; ConnectionSize_mm: 0 mm; Insulation_thickness_mm: 18 mm
BI10T - Cellegummi 18-32 mm kalde rør | Nivå F - 0,7 m | BI10T - Cellegummi 18-32 mm kalde rør | 0.106091 | 603.8 | 56 | 0.0012909 | 56 | ORIGINAL | Kjøle Retur 17° | Stålrør normaltykke | DN | UB3.144613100 | Hydronic Return | MagiCAD Pset_Heating - v_SizingFlow_ms: 0 m/s; pTot_SizingFlow_kPa: 0 kPa; dpTot_SizingFlow_kPa: 0 kPa; MagiCAD Pset_Water - dpTot_SizingFlow_kPa: 0 kPa; pTot_SizingFlow_kPa: 0 kPa; v_SizingFlow_ms: 0 m/s; MagiCAD Pset_Pipe - Length_mm: 603.796 mm; qv_SizingFlow_ls: 0.096 m3/s; SystemName: 37= R 12° Kopi 6; Insulation_thickness_mm: 18 mm; ConnectionSize_mm: 20 mm
BI10T - Cellegummi 18-32 mm kalde rør | Nivå F - 0,7 m | BI10T - Cellegummi 18-32 mm kalde rør | 0.00960412 | 69.8 | 68.7 | 0.0000874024 | 68.6996 | ORIGINAL | MagiCAD Pset_Elbow - qv_SizingFlow_ls: 0 m3/s; pTot_SizingFlow_Pa: 0 kPa; dpTot_SizingFlow_Pa: 0 kPa; v_SizingFlow_ms: 0 m/s; ConnectionSize_mm: 25 mm; Insulation_thickness_mm: 18 mm
BI10T - Cellegummi 18-32 mm kalde rør | Nivå F - 0,7 m | BI10T - Cellegummi 18-32 mm kalde rør | 0.568168 | 2920.7 | 62 | 0.00786019 | 62 | ORIGINAL | Kjøle Tur 14° | Stålrør normaltykke | DN | UB3.144613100 | Hydronic Supply | MagiCAD Pset_Heating - v_SizingFlow_ms: 0 m/s; pTot_SizingFlow_kPa: 0 kPa; dpTot_SizingFlow_kPa: 0 kPa; MagiCAD Pset_Water - dpTot_SizingFlow_kPa: 0 kPa; pTot_SizingFlow_kPa: 0 kPa; v_SizingFlow_ms: 0 m/s; MagiCAD Pset_Pipe - Length_mm: 2920.75 mm; qv_SizingFlow_ls: 0 m3/s; SystemName: 37= T 7° Kopi 4; Insulation_thickness_mm: 21 mm; ConnectionSize_mm: 20 mm
BI10T - Cellegummi 18-32 mm kalde rør | Nivå F - 0,7 m | BI10T - Cellegummi 18-32 mm kalde rør | 0.173422 | 921.2 | 60 | 0.00230349 | 60 | ORIGINAL | Kjøle Tur 14° | Stålrør normaltykke | DN | UB3.144613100 | Hydronic Supply | MagiCAD Pset_Heating - v_SizingFlow_ms: 0 m/s; pTot_SizingFlow_kPa: 0 kPa; dpTot_SizingFlow_kPa: 0 kPa; MagiCAD Pset_Water - dpTot_SizingFlow_kPa: 0 kPa; pTot_SizingFlow_kPa: 0 kPa; v_SizingFlow_ms: 0 m/s; MagiCAD Pset_Pipe - Length_mm: 921.237 mm; qv_SizingFlow_ls: 0 m3/s; SystemName: 37= T 7° Kopi 4; Insulation_thickness_mm: 20 mm; ConnectionSize_mm: 20 mm
2 x BI10T - Cellegummi 18-32 mm kalde rør | Nivå F - 0,7 m | BI10T - Cellegummi 18-32 mm kalde rør | 0.0078726 | 66.8 | 60.2 | 0.000145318 | 60.2 | ORIGINAL | MagiCAD Pset_Elbow - qv_SizingFlow_ls: 0 m3/s; pTot_SizingFlow_Pa: 0 kPa; dpTot_SizingFlow_Pa: 0 kPa; v_SizingFlow_ms: 0 m/s; ConnectionSize_mm: 0 mm; Insulation_thickness_mm: 20 mm
BI10T - Cellegummi 18-32 mm kalde rør | Nivå F - 0,7 m | BI10T - Cellegummi 18-32 mm kalde rør | 0.0153241 | 81.4 | 60 | 0.000203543 | 60 | ORIGINAL | Kjøle Retur 17° | Stålrør normaltykke | DN | UB3.144613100 | Hydronic Return | MagiCAD Pset_Heating - v_SizingFlow_ms: 0 m/s; pTot_SizingFlow_kPa: 0 kPa; dpTot_SizingFlow_kPa: 0 kPa; MagiCAD Pset_Water - dpTot_SizingFlow_kPa: 0 kPa; pTot_SizingFlow_kPa: 0 kPa; v_SizingFlow_ms: 0 m/s; MagiCAD Pset_Pipe - Length_mm: 81.405 mm; qv_SizingFlow_ls: 0 m3/s; SystemName: 37= R 12° Kopi 4; Insulation_thickness_mm: 20 mm; ConnectionSize_mm: 20 mm
BI10T - Cellegummi 18-32 mm kalde rør | Nivå F - 0,7 m | BI10T - Cellegummi 18-32 mm kalde rør | 0.00787174 | 66.8 | 60.2 | 0.000145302 | 60.2 | ORIGINAL | MagiCAD Pset_Elbow - qv_SizingFlow_ls: 0 m3/s; pTot_SizingFlow_Pa: 0 kPa; dpTot_SizingFlow_Pa: 0 kPa; v_SizingFlow_ms: 0 m/s; ConnectionSize_mm: 0 mm; Insulation_thickness_mm: 20 mm
BI10T - Cellegummi 18-32 mm kalde rør | Nivå F - 0,7 m | BI10T - Cellegummi 18-32 mm kalde rør | 0.174325 | 926 | 60 | 0.00231549 | 60 | ORIGINAL | Kjøle Retur 17° | Stålrør normaltykke | DN | UB3.144613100 | Hydronic Return | MagiCAD Pset_Heating - v_SizingFlow_ms: 0 m/s; pTot_SizingFlow_kPa: 0 kPa; dpTot_SizingFlow_kPa: 0 kPa; MagiCAD Pset_Water - dpTot_SizingFlow_kPa: 0 kPa; pTot_SizingFlow_kPa: 0 kPa; v_SizingFlow_ms: 0 m/s; MagiCAD Pset_Pipe - Length_mm: 925.987 mm; qv_SizingFlow_ls: 0 m3/s; SystemName: 37= R 12° Kopi 4; Insulation_thickness_mm: 20 mm; ConnectionSize_mm: 20 mm
BI10T - Cellegummi 18-32 mm kalde rør | Nivå F - 0,7 m | BI10T - Cellegummi 18-32 mm kalde rør | 0.0145172 | 58 | 79.9 | 0.000287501 | 79.9 | ORIGINAL | MagiCAD Pset_Valve - Description: Ball valve, threaded, brass; qv_SizingFlow_ls: 0 m3/s; pTot_SizingFlow_kPa: 0 kPa; dpTot_SizingFlow_kPa: 0 kPa; Manufacturer: Armatec; Product Code: AT3600-20; User Code: SM01T; Insulation_thickness_mm: 20 mm
BI10T - Cellegummi 18-32 mm kalde rør | Nivå F - 0,7 m | BI10T - Cellegummi 18-32 mm kalde rør | 0.0365217 | 194 | 60 | 0.000485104 | 60 | ORIGINAL | Kjøle Tur 14° | Stålrør normaltykke | DN | UB3.144613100 | Hydronic Supply | MagiCAD Pset_Heating - v_SizingFlow_ms: 0 m/s; pTot_SizingFlow_kPa: 0 kPa; dpTot_SizingFlow_kPa: 0 kPa; MagiCAD Pset_Water - dpTot_SizingFlow_kPa: 0 kPa; pTot_SizingFlow_kPa: 0 kPa; v_SizingFlow_ms: 0 m/s; MagiCAD Pset_Pipe - Length_mm: 193.963 mm; qv_SizingFlow_ls: 0 m3/s; SystemName: 37= T 7° Kopi 4; Insulation_thickness_mm: 20 mm; ConnectionSize_mm: 20 mm
BI10T - Cellegummi 18-32 mm kalde rør | Nivå F - 0,7 m | BI10T - Cellegummi 18-32 mm kalde rør | 0.0211794 | 97 | 69.7 | 0.000365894 | 69.7 | ORIGINAL | MagiCAD Pset_Valve - Description: Presetting of flow, shut-off valve, flow measuring,pressure reading 10-50; qv_SizingFlow_ls: 0 m3/s; pTot_SizingFlow_kPa: 0 kPa; dpTot_SizingFlow_kPa: 0 kPa; Manufacturer: TA; Product Code: STAD/F-20; User Code: SV01T; Insulation_thickness_mm: 20 mm; NationalCode: UL5.11091
BI10T - Cellegummi 18-32 mm kalde rør | Nivå F - 0,7 m | BI10T - Cellegummi 18-32 mm kalde rør | 0.0508669 | 270.2 | 60 | 0.000675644 | 60 | ORIGINAL | Kjøle Retur 17° | Stålrør normaltykke | DN | UB3.144613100 | Hydronic Return | MagiCAD Pset_Heating - v_SizingFlow_ms: 0 m/s; pTot_SizingFlow_kPa: 0 kPa; dpTot_SizingFlow_kPa: 0 kPa; MagiCAD Pset_Water - dpTot_SizingFlow_kPa: 0 kPa; pTot_SizingFlow_kPa: 0 kPa; v_SizingFlow_ms: 0 m/s; MagiCAD Pset_Pipe - Length_mm: 270.213 mm; qv_SizingFlow_ls: 0 m3/s; SystemName: 37= R 12° Kopi 4; Insulation_thickness_mm: 20 mm; ConnectionSize_mm: 20 mm
BI10T - Cellegummi 18-32 mm kalde rør | Nivå F - 0,7 m | BI10T - Cellegummi 18-32 mm kalde rør | 0.0137905 | 58 | 75.9 | 0.000259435 | 75.9 | ORIGINAL | MagiCAD Pset_Valve - Description: Ball valve, threaded, brass; qv_SizingFlow_ls: 0 m3/s; pTot_SizingFlow_kPa: 0 kPa; dpTot_SizingFlow_kPa: 0 kPa; Manufacturer: Armatec; Product Code: AT3600-20; User Code: SM01T; Insulation_thickness_mm: 18 mm
BI10T - Cellegummi 18-32 mm kalde rør | Nivå F - 0,7 m | BI10T - Cellegummi 18-32 mm kalde rør | 0.106636 | 606.9 | 56 | 0.00129753 | 56 | ORIGINAL | Kjøle Tur 14° | Stålrør normaltykke | DN | UB3.144613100 | Hydronic Supply | MagiCAD Pset_Heating - v_SizingFlow_ms: 0 m/s; pTot_SizingFlow_kPa: 0 kPa; dpTot_SizingFlow_kPa: 0 kPa; MagiCAD Pset_Water - dpTot_SizingFlow_kPa: 0 kPa; pTot_SizingFlow_kPa: 0 kPa; v_SizingFlow_ms: 0 m/s; MagiCAD Pset_Pipe - Length_mm: 606.889 mm; qv_SizingFlow_ls: 0 m3/s; SystemName: 37= T 7° Kopi 6; Insulation_thickness_mm: 18 mm; ConnectionSize_mm: 20 mm
BI10T - Cellegummi 18-32 mm kalde rør | Nivå F - 0,7 m | BI10T - Cellegummi 18-32 mm kalde rør | 0.063588 | 361.9 | 56 | 0.000773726 | 56 | ORIGINAL | Kjøle Tur 14° | Stålrør normaltykke | DN | UB3.144613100 | Hydronic Supply | MagiCAD Pset_Heating - v_SizingFlow_ms: 0 m/s; pTot_SizingFlow_kPa: 0 kPa; dpTot_SizingFlow_kPa: 0 kPa; MagiCAD Pset_Water - dpTot_SizingFlow_kPa: 0 kPa; pTot_SizingFlow_kPa: 0 kPa; v_SizingFlow_ms: 0 m/s; MagiCAD Pset_Pipe - Length_mm: 361.945 mm; qv_SizingFlow_ls: 0 m3/s; SystemName: 37= T 7° Kopi 6; Insulation_thickness_mm: 18 mm; ConnectionSize_mm: 20 mm
BI10T - Cellegummi 18-32 mm kalde rør | Nivå F - 0,7 m | BI10T - Cellegummi 18-32 mm kalde rør | 0.102542 | 583.6 | 56 | 0.00124771 | 56 | ORIGINAL | Kjøle Retur 17° | Stålrør normaltykke | DN | UB3.144613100 | Hydronic Return | MagiCAD Pset_Heating - v_SizingFlow_ms: 0 m/s; pTot_SizingFlow_kPa: 0 kPa; dpTot_SizingFlow_kPa: 0 kPa; MagiCAD Pset_Water - dpTot_SizingFlow_kPa: 0 kPa; pTot_SizingFlow_kPa: 0 kPa; v_SizingFlow_ms: 0 m/s; MagiCAD Pset_Pipe - Length_mm: 583.578 mm; qv_SizingFlow_ls: 0.096 m3/s; SystemName: 37= R 12° Kopi 6; Insulation_thickness_mm: 18 mm; ConnectionSize_mm: 20 mm
BI10T - Cellegummi 18-32 mm kalde rør | Nivå F - 0,7 m | BI10T - Cellegummi 18-32 mm kalde rør | 0.0606361 | 345.1 | 56 | 0.000737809 | 56 | ORIGINAL | Kjøle Retur 17° | Stålrør normaltykke | DN | UB3.144613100 | Hydronic Return | MagiCAD Pset_Heating - v_SizingFlow_ms: 0 m/s; pTot_SizingFlow_kPa: 0 kPa; dpTot_SizingFlow_kPa: 0 kPa; MagiCAD Pset_Water - dpTot_SizingFlow_kPa: 0 kPa; pTot_SizingFlow_kPa: 0 kPa; v_SizingFlow_ms: 0 m/s; MagiCAD Pset_Pipe - Length_mm: 345.121 mm; qv_SizingFlow_ls: 0 m3/s; SystemName: 37= R 12° Kopi 6; Insulation_thickness_mm: 18 mm; ConnectionSize_mm: 20 mm
2 x BI10T - Cellegummi 18-32 mm kalde rør | Nivå F - 0,7 m | BI10T - Cellegummi 18-32 mm kalde rør | 0.0199639 | 97 | 65.7 | 0.000325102 | 65.7 | ORIGINAL | MagiCAD Pset_Valve - Description: Presetting of flow, shut-off valve, flow measuring,pressure reading 10-50; qv_SizingFlow_ls: 0 m3/s; pTot_SizingFlow_kPa: 0 kPa; dpTot_SizingFlow_kPa: 0 kPa; Manufacturer: TA; Product Code: STAD/F-20; User Code: SV01T; Insulation_thickness_mm: 18 mm; NationalCode: UL5.11091
BI10T - Cellegummi 18-32 mm kalde rør | Nivå F - 0,7 m | BI10T - Cellegummi 18-32 mm kalde rør | 0.711803 | 4051.1 | 56 | 0.00866108 | 56 | ORIGINAL | Kjøle Retur 17° | Stålrør normaltykke | DN | UB3.144613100 | Hydronic Return | MagiCAD Pset_Heating - v_SizingFlow_ms: 0 m/s; pTot_SizingFlow_kPa: 0 kPa; dpTot_SizingFlow_kPa: 0 kPa; MagiCAD Pset_Water - dpTot_SizingFlow_kPa: 0 kPa; pTot_SizingFlow_kPa: 0 kPa; v_SizingFlow_ms: 0 m/s; MagiCAD Pset_Pipe - Length_mm: 4051.11 mm; qv_SizingFlow_ls: 0 m3/s; SystemName: 37= R 12° Kopi 6; Insulation_thickness_mm: 18 mm; ConnectionSize_mm: 20 mm
BI17T - Cellegummi 13 mm SPV fett | Nivå F - 0,7 m | BI17T - Cellegummi 13 mm SPV fett | 0.804186 | 1884.6 | 136 | 0.00941912 | 136 | ORIGINAL | SPV FETT | MA | MA | UB2.1115131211 | Sanitary | MagiCAD Pset_Heating - v_SizingFlow_ms: 0 m/s; pTot_SizingFlow_kPa: 0 kPa; dpTot_SizingFlow_kPa: 0 kPa; MagiCAD Pset_Water - dpTot_SizingFlow_kPa: 0 kPa; pTot_SizingFlow_kPa: 0 kPa; v_SizingFlow_ms: 0 m/s; MagiCAD Pset_Pipe - Length_mm: 1884.56 mm; qv_SizingFlow_ls: 0 m3/s; SystemName: 31= SPV Kopi 138; Insulation_thickness_mm: 13 mm; ConnectionSize_mm: 110 mm
BI17T - Cellegummi 13 mm SPV fett | Nivå F - 0,7 m | BI17T - Cellegummi 13 mm SPV fett | 0.0626287 | 199.49 | 157 | 0.00348606 | 199.077 | ORIGINAL | MagiCAD Pset_Elbow - Description: Generic PVC Bend; qv_SizingFlow_ls: 0 m3/s; pTot_SizingFlow_Pa: 0 kPa; dpTot_SizingFlow_Pa: 0 kPa; v_SizingFlow_ms: 0 m/s; ConnectionSize_mm: 0 mm; Insulation_thickness_mm: 13 mm
BI17T - Cellegummi 13 mm SPV fett | Nivå F - 0,7 m | BI17T - Cellegummi 13 mm SPV fett | 0.0453754 | 239.36 | 238.009 | 0.00761228 | 170.958 | ORIGINAL | MagiCAD Pset_TBranch - qv_SizingFlow_ls: 0 m3/s; pTot_SizingFlow_Pa: 0 kPa; dpTot_SizingFlow_Pa: 0 kPa; v_SizingFlow_ms: 0 m/s; ConnectionSize_mm: 0 mm; Insulation_thickness_mm: 13 mm
BI17T - Cellegummi 13 mm SPV fett | Nivå F - 0,7 m | BI17T - Cellegummi 13 mm SPV fett | 0.00499794 | 136 | 3 | 0.0000149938 | 136 | ORIGINAL | SPV FETT | MA | MA | UB2.1115131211 | Sanitary | MagiCAD Pset_Heating - v_SizingFlow_ms: 0 m/s; pTot_SizingFlow_kPa: 0 kPa; dpTot_SizingFlow_kPa: 0 kPa; MagiCAD Pset_Water - dpTot_SizingFlow_kPa: 0 kPa; pTot_SizingFlow_kPa: 0 kPa; v_SizingFlow_ms: 0 m/s; MagiCAD Pset_Pipe - Length_mm: 3.018 mm; qv_SizingFlow_ls: 0 m3/s; SystemName: 31= SPV Kopi 138; Insulation_thickness_mm: 13 mm; ConnectionSize_mm: 110 mm
BI17T - Cellegummi 13 mm SPV fett | Nivå F - 0,7 m | BI17T - Cellegummi 13 mm SPV fett | 0.0368923 | 224.902 | 202.236 | 0.00615866 | 168.963 | ORIGINAL | MagiCAD Pset_TBranch - qv_SizingFlow_ls: 0 m3/s; pTot_SizingFlow_Pa: 0 kPa; dpTot_SizingFlow_Pa: 0 kPa; v_SizingFlow_ms: 0 m/s; ConnectionSize_mm: 0 mm; Insulation_thickness_mm: 13 mm
BI17T - Cellegummi 13 mm SPV fett | Nivå F - 0,7 m | BI17T - Cellegummi 13 mm SPV fett | 0.178068 | 417.3 | 136 | 0.00208564 | 136 | ORIGINAL | SPV FETT | MA | MA | UB2.1115131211 | Sanitary | MagiCAD Pset_Heating - v_SizingFlow_ms: 0 m/s; pTot_SizingFlow_kPa: 0 kPa; dpTot_SizingFlow_kPa: 0 kPa; MagiCAD Pset_Water - dpTot_SizingFlow_kPa: 0 kPa; pTot_SizingFlow_kPa: 0 kPa; v_SizingFlow_ms: 0 m/s; MagiCAD Pset_Pipe - Length_mm: 417.345 mm; qv_SizingFlow_ls: 0 m3/s; SystemName: 31= SPV Kopi 138; Insulation_thickness_mm: 13 mm; ConnectionSize_mm: 110 mm
BI17T - Cellegummi 13 mm SPV fett | Nivå F - 0,7 m | BI17T - Cellegummi 13 mm SPV fett | 0.0864815 | 272.9 | 101 | 0.000975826 | 101 | ORIGINAL | SPV FETT | MA | MA | UB2.1115131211 | Sanitary | MagiCAD Pset_Heating - v_SizingFlow_ms: 0 m/s; pTot_SizingFlow_kPa: 0 kPa; dpTot_SizingFlow_kPa: 0 kPa; MagiCAD Pset_Water - dpTot_SizingFlow_kPa: 0 kPa; pTot_SizingFlow_kPa: 0 kPa; v_SizingFlow_ms: 0 m/s; MagiCAD Pset_Pipe - Length_mm: 272.891 mm; qv_SizingFlow_ls: 0 m3/s; SystemName: 31= SPV Kopi 138; Insulation_thickness_mm: 13 mm; ConnectionSize_mm: 75 mm
BI17T - Cellegummi 13 mm SPV fett | Nivå F - 0,7 m | BI17T - Cellegummi 13 mm SPV fett | 0.0181583 | 57.3 | 101 | 0.000204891 | 101 | ORIGINAL | SPV FETT | MA | MA | UB2.1115131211 | Sanitary | MagiCAD Pset_Heating - v_SizingFlow_ms: 0 m/s; pTot_SizingFlow_kPa: 0 kPa; dpTot_SizingFlow_kPa: 0 kPa; MagiCAD Pset_Water - dpTot_SizingFlow_kPa: 0 kPa; pTot_SizingFlow_kPa: 0 kPa; v_SizingFlow_ms: 0 m/s; MagiCAD Pset_Pipe - Length_mm: 57.282 mm; qv_SizingFlow_ls: 0 m3/s; SystemName: 31= SPV Kopi 138; Insulation_thickness_mm: 13 mm; ConnectionSize_mm: 75 mm
BI17T - Cellegummi 13 mm SPV fett | Nivå F - 0,7 m | BI17T - Cellegummi 13 mm SPV fett | 0.0154089 | 116.575 | 95.7251 | 0.000581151 | 108.5 | ORIGINAL | MagiCAD Pset_Elbow - Description: Generic PVC Bend; qv_SizingFlow_ls: 0 m3/s; pTot_SizingFlow_Pa: 0 kPa; dpTot_SizingFlow_Pa: 0 kPa; v_SizingFlow_ms: 0 m/s; ConnectionSize_mm: 0 mm; Insulation_thickness_mm: 13 mm
BI17T - Cellegummi 13 mm SPV fett | Nivå F - 0,7 m | BI17T - Cellegummi 13 mm SPV fett | 0.122259 | 385.8 | 101 | 0.00137953 | 101 | ORIGINAL | SPV FETT | MA | MA | UB2.1115131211 | Sanitary | MagiCAD Pset_Heating - v_SizingFlow_ms: 0 m/s; pTot_SizingFlow_kPa: 0 kPa; dpTot_SizingFlow_kPa: 0 kPa; MagiCAD Pset_Water - dpTot_SizingFlow_kPa: 0 kPa; pTot_SizingFlow_kPa: 0 kPa; v_SizingFlow_ms: 0 m/s; MagiCAD Pset_Pipe - Length_mm: 385.827 mm; qv_SizingFlow_ls: 0 m3/s; SystemName: 31= SPV Kopi 138; Insulation_thickness_mm: 13 mm; ConnectionSize_mm: 75 mm
BI17T - Cellegummi 13 mm SPV fett | Nivå F - 0,7 m | BI17T - Cellegummi 13 mm SPV fett | 0.015634 | 116.774 | 108.5 | 0.000589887 | 96.6968 | ORIGINAL | MagiCAD Pset_Elbow - Description: Generic PVC Bend; qv_SizingFlow_ls: 0 m3/s; pTot_SizingFlow_Pa: 0 kPa; dpTot_SizingFlow_Pa: 0 kPa; v_SizingFlow_ms: 0 m/s; ConnectionSize_mm: 0 mm; Insulation_thickness_mm: 13 mm
BI17T - Cellegummi 13 mm SPV fett | Nivå F - 0,7 m | BI17T - Cellegummi 13 mm SPV fett | 0.00567781 | 31.2 | 58 | 0.0000570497 | 58 | ORIGINAL | SPV FETT | PP avløpsrør | PP | UB2.1114431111 | Sanitary | MagiCAD Pset_Heating - v_SizingFlow_ms: 0 m/s; pTot_SizingFlow_kPa: 0 kPa; dpTot_SizingFlow_kPa: 0 kPa; MagiCAD Pset_Water - dpTot_SizingFlow_kPa: 0 kPa; pTot_SizingFlow_kPa: 0 kPa; v_SizingFlow_ms: 0 m/s; MagiCAD Pset_Pipe - Length_mm: 31.182 mm; qv_SizingFlow_ls: 0 m3/s; SystemName: 31= SPV Kopi 138; Insulation_thickness_mm: 13 mm; ConnectionSize_mm: 32 mm
BI17T - Cellegummi 13 mm SPV fett | Nivå F - 0,7 m | BI17T - Cellegummi 13 mm SPV fett | 0.00410354 | 62.5473 | 61.2 | 0.0000797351 | 46.5276 | ORIGINAL | MagiCAD Pset_Elbow - Description: Generic PVC Bend; qv_SizingFlow_ls: 0 m3/s; pTot_SizingFlow_Pa: 0 kPa; dpTot_SizingFlow_Pa: 0 kPa; v_SizingFlow_ms: 0 m/s; ConnectionSize_mm: 0 mm; Insulation_thickness_mm: 13 mm
BI17T - Cellegummi 13 mm SPV fett | Nivå F - 0,7 m | BI17T - Cellegummi 13 mm SPV fett | 0.115776 | 636.2 | 58 | 0.0011633 | 58 | ORIGINAL | SPV FETT | PP avløpsrør | PP | UB2.1114431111 | Sanitary | MagiCAD Pset_Heating - v_SizingFlow_ms: 0 m/s; pTot_SizingFlow_kPa: 0 kPa; dpTot_SizingFlow_kPa: 0 kPa; MagiCAD Pset_Water - dpTot_SizingFlow_kPa: 0 kPa; pTot_SizingFlow_kPa: 0 kPa; v_SizingFlow_ms: 0 m/s; MagiCAD Pset_Pipe - Length_mm: 636.184 mm; qv_SizingFlow_ls: 0 m3/s; SystemName: 31= SPV Kopi 138; Insulation_thickness_mm: 13 mm; ConnectionSize_mm: 32 mm
2 x BI17T - Cellegummi 13 mm SPV fett | Nivå F - 0,7 m | BI17T - Cellegummi 13 mm SPV fett | 0.00402115 | 62.4936 | 45.7458 | 0.0000781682 | 61.2 | ORIGINAL | MagiCAD Pset_Elbow - Description: Generic PVC Bend; qv_SizingFlow_ls: 0 m3/s; pTot_SizingFlow_Pa: 0 kPa; dpTot_SizingFlow_Pa: 0 kPa; v_SizingFlow_ms: 0 m/s; ConnectionSize_mm: 0 mm; Insulation_thickness_mm: 13 mm
BI17T - Cellegummi 13 mm SPV fett | Nivå F - 0,7 m | BI17T - Cellegummi 13 mm SPV fett | 0.00744303 | 40.9 | 58 | 0.0000747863 | 58 | ORIGINAL | SPV FETT | PP avløpsrør | PP | UB2.1114431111 | Sanitary | MagiCAD Pset_Heating - v_SizingFlow_ms: 0 m/s; pTot_SizingFlow_kPa: 0 kPa; dpTot_SizingFlow_kPa: 0 kPa; MagiCAD Pset_Water - dpTot_SizingFlow_kPa: 0 kPa; pTot_SizingFlow_kPa: 0 kPa; v_SizingFlow_ms: 0 m/s; MagiCAD Pset_Pipe - Length_mm: 40.853 mm; qv_SizingFlow_ls: 0 m3/s; SystemName: 31= SPV Kopi 138; Insulation_thickness_mm: 13 mm; ConnectionSize_mm: 32 mm
2 x BI17T - Cellegummi 13 mm SPV fett | Nivå F - 0,7 m | BI17T - Cellegummi 13 mm SPV fett | 0.00410296 | 62.5469 | 46.5224 | 0.0000797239 | 61.2 | ORIGINAL | MagiCAD Pset_Elbow - Description: Generic PVC Bend; qv_SizingFlow_ls: 0 m3/s; pTot_SizingFlow_Pa: 0 kPa; dpTot_SizingFlow_Pa: 0 kPa; v_SizingFlow_ms: 0 m/s; ConnectionSize_mm: 0 mm; Insulation_thickness_mm: 13 mm
BI17T - Cellegummi 13 mm SPV fett | Nivå F - 0,7 m | BI17T - Cellegummi 13 mm SPV fett | 0.155066 | 852.1 | 58 | 0.00155808 | 58 | ORIGINAL | SPV FETT | PP avløpsrør | PP | UB2.1114431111 | Sanitary | MagiCAD Pset_Heating - v_SizingFlow_ms: 0 m/s; pTot_SizingFlow_kPa: 0 kPa; dpTot_SizingFlow_kPa: 0 kPa; MagiCAD Pset_Water - dpTot_SizingFlow_kPa: 0 kPa; pTot_SizingFlow_kPa: 0 kPa; v_SizingFlow_ms: 0 m/s; MagiCAD Pset_Pipe - Length_mm: 852.113 mm; qv_SizingFlow_ls: 0 m3/s; SystemName: 31= SPV Kopi 138; Insulation_thickness_mm: 13 mm; ConnectionSize_mm: 32 mm
BI17T - Cellegummi 13 mm SPV fett | Nivå F - 0,7 m | BI17T - Cellegummi 13 mm SPV fett | 0.00962681 | 58 | 58 | 0.0000967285 | 52.9 | ORIGINAL | SPV FETT | PP avløpsrør | PP | UB2.1114431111 | Sanitary | MagiCAD Pset_Heating - v_SizingFlow_ms: 0 m/s; pTot_SizingFlow_kPa: 0 kPa; dpTot_SizingFlow_kPa: 0 kPa; MagiCAD Pset_Water - dpTot_SizingFlow_kPa: 0 kPa; pTot_SizingFlow_kPa: 0 kPa; v_SizingFlow_ms: 0 m/s; MagiCAD Pset_Pipe - Length_mm: 53.213 mm; qv_SizingFlow_ls: 0 m3/s; SystemName: 31= SPV Kopi 138; Insulation_thickness_mm: 13 mm; ConnectionSize_mm: 32 mm
BI17T - Cellegummi 13 mm SPV fett | Nivå F - 0,7 m | BI17T - Cellegummi 13 mm SPV fett | 0.0250588 | 137.7 | 58 | 0.000251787 | 58 | ORIGINAL | SPV FETT | PP avløpsrør | PP | UB2.1114431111 | Sanitary | MagiCAD Pset_Heating - v_SizingFlow_ms: 0 m/s; pTot_SizingFlow_kPa: 0 kPa; dpTot_SizingFlow_kPa: 0 kPa; MagiCAD Pset_Water - dpTot_SizingFlow_kPa: 0 kPa; pTot_SizingFlow_kPa: 0 kPa; v_SizingFlow_ms: 0 m/s; MagiCAD Pset_Pipe - Length_mm: 137.75 mm; qv_SizingFlow_ls: 0 m3/s; SystemName: 31= SPV Kopi 138; Insulation_thickness_mm: 13 mm; ConnectionSize_mm: 32 mm
BI17T - Cellegummi 13 mm SPV fett | Nivå F - 0,7 m | BI17T - Cellegummi 13 mm SPV fett | 0.00410354 | 62.5473 | 46.5276 | 0.0000797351 | 61.2 | ORIGINAL | MagiCAD Pset_Elbow - Description: Generic PVC Bend; qv_SizingFlow_ls: 0 m3/s; pTot_SizingFlow_Pa: 0 kPa; dpTot_SizingFlow_Pa: 0 kPa; v_SizingFlow_ms: 0 m/s; ConnectionSize_mm: 0 mm; Insulation_thickness_mm: 13 mm
2 x BI17T - Cellegummi 13 mm SPV fett | Nivå F - 0,7 m | BI17T - Cellegummi 13 mm SPV fett | 0.0073281 | 68.4 | 68.4 | 0.000124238 | 34.2 | ORIGINAL | MagiCAD Pset_Plug - ConnectionSize_mm: 0 mm; pTot_SizingFlow_kPa: 0 kPa; Insulation_thickness_mm: 13 mm
BI17T - Cellegummi 13 mm SPV fett | Nivå F - 0,7 m | BI17T - Cellegummi 13 mm SPV fett | 0.00590793 | 94.9555 | 68 | 0.000401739 | 77.0122 | ORIGINAL | MagiCAD Pset_TBranch - qv_SizingFlow_ls: 0 m3/s; pTot_SizingFlow_Pa: 0 kPa; dpTot_SizingFlow_Pa: 0 kPa; v_SizingFlow_ms: 0 m/s; ConnectionSize_mm: 0 mm; Insulation_thickness_mm: 13 mm
BI17T - Cellegummi 13 mm SPV fett | Nivå F - 0,7 m | BI17T - Cellegummi 13 mm SPV fett | 0.073666 | 404.8 | 58 | 0.000740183 | 58 | ORIGINAL | SPV FETT | PP avløpsrør | PP | UB2.1114431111 | Sanitary | MagiCAD Pset_Heating - v_SizingFlow_ms: 0 m/s; pTot_SizingFlow_kPa: 0 kPa; dpTot_SizingFlow_kPa: 0 kPa; MagiCAD Pset_Water - dpTot_SizingFlow_kPa: 0 kPa; pTot_SizingFlow_kPa: 0 kPa; v_SizingFlow_ms: 0 m/s; MagiCAD Pset_Pipe - Length_mm: 404.765 mm; qv_SizingFlow_ls: 0 m3/s; SystemName: 31= SPV Kopi 138; Insulation_thickness_mm: 13 mm; ConnectionSize_mm: 32 mm
BI17T - Cellegummi 13 mm SPV fett | Nivå F - 0,7 m | BI17T - Cellegummi 13 mm SPV fett | 0.0390137 | 112.6 | 111 | 0.00106183 | 111 | ORIGINAL | MagiCAD Pset_Reduction - qv_SizingFlow_ls: 0 m3/s; pTot_SizingFlow_Pa: 0 kPa; dpTot_SizingFlow_Pa: 0 kPa; v_SizingFlow_ms: 0 m/s; ConnectionSize_mm: 0 mm; Insulation_thickness_mm: 13 mm
BI17T - Cellegummi 13 mm SPV fett | Nivå F - 0,7 m | BI17T - Cellegummi 13 mm SPV fett | 0.0227658 | 125.1 | 58 | 0.000228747 | 58 | ORIGINAL | SPV FETT | PP avløpsrør | PP | UB2.1114431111 | Sanitary | MagiCAD Pset_Heating - v_SizingFlow_ms: 0 m/s; pTot_SizingFlow_kPa: 0 kPa; dpTot_SizingFlow_kPa: 0 kPa; MagiCAD Pset_Water - dpTot_SizingFlow_kPa: 0 kPa; pTot_SizingFlow_kPa: 0 kPa; v_SizingFlow_ms: 0 m/s; MagiCAD Pset_Pipe - Length_mm: 125.129 mm; qv_SizingFlow_ls: 0 m3/s; SystemName: 31= SPV Kopi 138; Insulation_thickness_mm: 13 mm; ConnectionSize_mm: 32 mm
BI17T - Cellegummi 13 mm SPV fett | Nivå F - 0,7 m | BI17T - Cellegummi 13 mm SPV fett | 0.00948122 | 58 | 58 | 0.0000952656 | 52.1 | ORIGINAL | SPV FETT | PP avløpsrør | PP | UB2.1114431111 | Sanitary | MagiCAD Pset_Heating - v_SizingFlow_ms: 0 m/s; pTot_SizingFlow_kPa: 0 kPa; dpTot_SizingFlow_kPa: 0 kPa; MagiCAD Pset_Water - dpTot_SizingFlow_kPa: 0 kPa; pTot_SizingFlow_kPa: 0 kPa; v_SizingFlow_ms: 0 m/s; MagiCAD Pset_Pipe - Length_mm: 52.1 mm; qv_SizingFlow_ls: 0 m3/s; SystemName: 31= SPV Kopi 138; Insulation_thickness_mm: 13 mm; ConnectionSize_mm: 32 mm
BI17T - Cellegummi 13 mm SPV fett | Nivå F - 0,7 m | BI17T - Cellegummi 13 mm SPV fett | 0.00402115 | 62.4936 | 61.2 | 0.0000781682 | 45.7458 | ORIGINAL | MagiCAD Pset_Elbow - Description: Generic PVC Bend; qv_SizingFlow_ls: 0 m3/s; pTot_SizingFlow_Pa: 0 kPa; dpTot_SizingFlow_Pa: 0 kPa; v_SizingFlow_ms: 0 m/s; ConnectionSize_mm: 0 mm; Insulation_thickness_mm: 13 mm
BI10T - Cellegummi 18-32 mm kalde rør | Nivå F - 0,7 m | BI10T - Cellegummi 18-32 mm kalde rør | 0.0392778 | 391.2 | 32 | 0.000269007 | 32 | ORIGINAL | KV | Kobberrør | Cu | UB1.111713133 | Domestic Cold Water | MagiCAD Pset_Heating - v_SizingFlow_ms: 0 m/s; pTot_SizingFlow_kPa: 0 kPa; dpTot_SizingFlow_kPa: 0 kPa; MagiCAD Pset_Water - dpTot_SizingFlow_kPa: 0 kPa; pTot_SizingFlow_kPa: 0 kPa; v_SizingFlow_ms: 0 m/s; MagiCAD Pset_Pipe - Length_mm: 391.151 mm; qv_SizingFlow_ls: 0 m3/s; SystemName: 31=KV Kopi 4 (29) (2); Insulation_thickness_mm: 10 mm; ConnectionSize_mm: 12 mm
BI10T - Cellegummi 18-32 mm kalde rør | Nivå F - 0,7 m | BI10T - Cellegummi 18-32 mm kalde rør | 0.157985 | 1573.5 | 32 | 0.00108201 | 32 | ORIGINAL | KV | Kobberrør | Cu | UB1.111713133 | Domestic Cold Water | MagiCAD Pset_Heating - v_SizingFlow_ms: 0 m/s; pTot_SizingFlow_kPa: 0 kPa; dpTot_SizingFlow_kPa: 0 kPa; MagiCAD Pset_Water - dpTot_SizingFlow_kPa: 0 kPa; pTot_SizingFlow_kPa: 0 kPa; v_SizingFlow_ms: 0 m/s; MagiCAD Pset_Pipe - Length_mm: 1573.5 mm; qv_SizingFlow_ls: 0 m3/s; SystemName: 31=KV Kopi 4 (29) (2); Insulation_thickness_mm: 10 mm; ConnectionSize_mm: 12 mm
BI10T - Cellegummi 18-32 mm kalde rør | Nivå F - 0,7 m | BI10T - Cellegummi 18-32 mm kalde rør | 0.0175907 | 175.2 | 32 | 0.000120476 | 32 | ORIGINAL | KV | Kobberrør | Cu | UB1.111713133 | Domestic Cold Water | MagiCAD Pset_Heating - v_SizingFlow_ms: 0 m/s; pTot_SizingFlow_kPa: 0 kPa; dpTot_SizingFlow_kPa: 0 kPa; MagiCAD Pset_Water - dpTot_SizingFlow_kPa: 0 kPa; pTot_SizingFlow_kPa: 0 kPa; v_SizingFlow_ms: 0 m/s; MagiCAD Pset_Pipe - Length_mm: 175.184 mm; qv_SizingFlow_ls: 0 m3/s; SystemName: 31=KV Kopi 4 (29) (2); Insulation_thickness_mm: 10 mm; ConnectionSize_mm: 12 mm
BI10T - Cellegummi 18-32 mm kalde rør | Nivå F - 0,7 m | BI10T - Cellegummi 18-32 mm kalde rør | 0.0008 | 32 | 24 | 0.0000192 | 25 | ORIGINAL | MagiCAD Pset_TBranch - qv_SizingFlow_ls: 0 m3/s; pTot_SizingFlow_Pa: 0 kPa; dpTot_SizingFlow_Pa: 0 kPa; v_SizingFlow_ms: 0 m/s; ConnectionSize_mm: 0 mm; Insulation_thickness_mm: 10 mm
BI10T - Cellegummi 18-32 mm kalde rør | Nivå F - 0,7 m | BI10T - Cellegummi 18-32 mm kalde rør | 0.119329 | 1188.5 | 32 | 0.000817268 | 32 | ORIGINAL | KV | Kobberrør | Cu | UB1.111713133 | Domestic Cold Water | MagiCAD Pset_Heating - v_SizingFlow_ms: 0 m/s; pTot_SizingFlow_kPa: 0 kPa; dpTot_SizingFlow_kPa: 0 kPa; MagiCAD Pset_Water - dpTot_SizingFlow_kPa: 0 kPa; pTot_SizingFlow_kPa: 0 kPa; v_SizingFlow_ms: 0 m/s; MagiCAD Pset_Pipe - Length_mm: 1188.5 mm; qv_SizingFlow_ls: 0 m3/s; SystemName: 31=KV Kopi 4 (29) (2); Insulation_thickness_mm: 10 mm; ConnectionSize_mm: 12 mm
5 x BI10T - Cellegummi 18-32 mm kalde rør | Nivå F - 0,7 m | BI10T - Cellegummi 18-32 mm kalde rør | 0.00175276 | 32 | 28 | 0.00000675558 | 28 | ORIGINAL | MagiCAD Pset_Elbow - qv_SizingFlow_ls: 0 m3/s; pTot_SizingFlow_Pa: 0 kPa; dpTot_SizingFlow_Pa: 0 kPa; v_SizingFlow_ms: 0 m/s; ConnectionSize_mm: 0 mm; Insulation_thickness_mm: 10 mm
BI10T - Cellegummi 18-32 mm kalde rør | Nivå F - 0,7 m | BI10T - Cellegummi 18-32 mm kalde rør | 0.0388963 | 387.4 | 32 | 0.000266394 | 32 | ORIGINAL | KV | Kobberrør | Cu | UB1.111713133 | Domestic Cold Water | MagiCAD Pset_Heating - v_SizingFlow_ms: 0 m/s; pTot_SizingFlow_kPa: 0 kPa; dpTot_SizingFlow_kPa: 0 kPa; MagiCAD Pset_Water - dpTot_SizingFlow_kPa: 0 kPa; pTot_SizingFlow_kPa: 0 kPa; v_SizingFlow_ms: 0 m/s; MagiCAD Pset_Pipe - Length_mm: 387.439 mm; qv_SizingFlow_ls: 0 m3/s; SystemName: 31=KV Kopi 4 (29) (2); Insulation_thickness_mm: 10 mm; ConnectionSize_mm: 12 mm
BI10T - Cellegummi 18-32 mm kalde rør | Nivå F - 0,7 m | BI10T - Cellegummi 18-32 mm kalde rør | 0.0126207 | 125.7 | 32 | 0.0000864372 | 32 | ORIGINAL | KV | Kobberrør | Cu | UB1.111713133 | Domestic Cold Water | MagiCAD Pset_Heating - v_SizingFlow_ms: 0 m/s; pTot_SizingFlow_kPa: 0 kPa; dpTot_SizingFlow_kPa: 0 kPa; MagiCAD Pset_Water - dpTot_SizingFlow_kPa: 0 kPa; pTot_SizingFlow_kPa: 0 kPa; v_SizingFlow_ms: 0 m/s; MagiCAD Pset_Pipe - Length_mm: 125.689 mm; qv_SizingFlow_ls: 0 m3/s; SystemName: 31=KV Kopi 4 (29) (2); Insulation_thickness_mm: 10 mm; ConnectionSize_mm: 12 mm
BI10T - Cellegummi 18-32 mm kalde rør | Nivå F - 0,7 m | BI10T - Cellegummi 18-32 mm kalde rør | 0.0040563 | 40.4 | 32 | 0.0000277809 | 32 | ORIGINAL | KV | Kobberrør | Cu | UB1.111713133 | Domestic Cold Water | MagiCAD Pset_Heating - v_SizingFlow_ms: 0 m/s; pTot_SizingFlow_kPa: 0 kPa; dpTot_SizingFlow_kPa: 0 kPa; MagiCAD Pset_Water - dpTot_SizingFlow_kPa: 0 kPa; pTot_SizingFlow_kPa: 0 kPa; v_SizingFlow_ms: 0 m/s; MagiCAD Pset_Pipe - Length_mm: 40.448 mm; qv_SizingFlow_ls: 0 m3/s; SystemName: 31=KV Kopi 4 (29) (2); Insulation_thickness_mm: 10 mm; ConnectionSize_mm: 12 mm
BI10T - Cellegummi 18-32 mm kalde rør | Nivå F - 0,7 m | BI10T - Cellegummi 18-32 mm kalde rør | 0.00139561 | 13.9 | 32 | 0.00000955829 | 32 | ORIGINAL | KV | Kobberrør | Cu | UB1.111713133 | Domestic Cold Water | MagiCAD Pset_Heating - v_SizingFlow_ms: 0 m/s; pTot_SizingFlow_kPa: 0 kPa; dpTot_SizingFlow_kPa: 0 kPa; MagiCAD Pset_Water - dpTot_SizingFlow_kPa: 0 kPa; pTot_SizingFlow_kPa: 0 kPa; v_SizingFlow_ms: 0 m/s; MagiCAD Pset_Pipe - Length_mm: 13.876 mm; qv_SizingFlow_ls: 0 m3/s; SystemName: 31=KV Kopi 4 (29) (2); Insulation_thickness_mm: 10 mm; ConnectionSize_mm: 12 mm
BI10T - Cellegummi 18-32 mm kalde rør | Nivå F - 0,7 m | BI10T - Cellegummi 18-32 mm kalde rør | 0.00112452 | 32 | 32 | 0.00000770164 | 11.2 | ORIGINAL | KV | Kobberrør | Cu | UB1.111713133 | Domestic Cold Water | MagiCAD Pset_Heating - v_SizingFlow_ms: 0 m/s; pTot_SizingFlow_kPa: 0 kPa; dpTot_SizingFlow_kPa: 0 kPa; MagiCAD Pset_Water - dpTot_SizingFlow_kPa: 0 kPa; pTot_SizingFlow_kPa: 0 kPa; v_SizingFlow_ms: 0 m/s; MagiCAD Pset_Pipe - Length_mm: 11.22 mm; qv_SizingFlow_ls: 0 m3/s; SystemName: 31=KV Kopi 4 (29) (2); Insulation_thickness_mm: 10 mm; ConnectionSize_mm: 12 mm
BI10T - Cellegummi 18-32 mm kalde rør | Nivå F - 0,7 m | BI10T - Cellegummi 18-32 mm kalde rør | 0.000737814 | 32 | 2.61354 | 8.98319e-07 | 27.894 | ORIGINAL | MagiCAD Pset_Elbow - qv_SizingFlow_ls: 0 m3/s; pTot_SizingFlow_Pa: 0 kPa; dpTot_SizingFlow_Pa: 0 kPa; v_SizingFlow_ms: 0 m/s; ConnectionSize_mm: 0 mm; Insulation_thickness_mm: 10 mm
2 x BI10T - Cellegummi 18-32 mm kalde rør | Nivå F - 0,7 m | BI10T - Cellegummi 18-32 mm kalde rør | 0.000868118 | 32 | 19.799 | 0.00000749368 | 27.9247 | ORIGINAL | MagiCAD Pset_Elbow - qv_SizingFlow_ls: 0 m3/s; pTot_SizingFlow_Pa: 0 kPa; dpTot_SizingFlow_Pa: 0 kPa; v_SizingFlow_ms: 0 m/s; ConnectionSize_mm: 0 mm; Insulation_thickness_mm: 10 mm
BI10T - Cellegummi 18-32 mm kalde rør | Nivå F - 0,7 m | BI10T - Cellegummi 18-32 mm kalde rør | 0.000737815 | 32 | 2.61354 | 8.98318e-07 | 27.894 | ORIGINAL | MagiCAD Pset_Elbow - qv_SizingFlow_ls: 0 m3/s; pTot_SizingFlow_Pa: 0 kPa; dpTot_SizingFlow_Pa: 0 kPa; v_SizingFlow_ms: 0 m/s; ConnectionSize_mm: 0 mm; Insulation_thickness_mm: 10 mm
BI10T - Cellegummi 18-32 mm kalde rør | Nivå F - 0,7 m | BI10T - Cellegummi 18-32 mm kalde rør | 0.00349216 | 26.5 | 42 | 0.0000335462 | 42 | ORIGINAL | VV | Kobberrør | Cu | UB1.111713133 | Domestic Hot Water | MagiCAD Pset_Heating - v_SizingFlow_ms: 0 m/s; pTot_SizingFlow_kPa: 0 kPa; dpTot_SizingFlow_kPa: 0 kPa; MagiCAD Pset_Water - dpTot_SizingFlow_kPa: 0 kPa; pTot_SizingFlow_kPa: 0 kPa; v_SizingFlow_ms: 0 m/s; MagiCAD Pset_Pipe - Length_mm: 26.503 mm; qv_SizingFlow_ls: 0 m3/s; SystemName: 31= VV Kopi 41; Insulation_thickness_mm: 15 mm; ConnectionSize_mm: 12 mm
BI10T - Cellegummi 18-32 mm kalde rør | Nivå F - 0,7 m | BI10T - Cellegummi 18-32 mm kalde rør | 0.00863469 | 86 | 32 | 0.0000591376 | 32 | ORIGINAL | Undefined | Kobberrør | Cu | UB1.111713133 | Undefined | MagiCAD Pset_Heating - v_SizingFlow_ms: 0 m/s; pTot_SizingFlow_kPa: 0 kPa; dpTot_SizingFlow_kPa: 0 kPa; MagiCAD Pset_Water - dpTot_SizingFlow_kPa: 0 kPa; pTot_SizingFlow_kPa: 0 kPa; v_SizingFlow_ms: 0 m/s; MagiCAD Pset_Pipe - Length_mm: 86 mm; qv_SizingFlow_ls: 0 m3/s; Insulation_thickness_mm: 10 mm; ConnectionSize_mm: 12 mm
BI17T - Cellegummi 13 mm SPV fett | Nivå F - 0,7 m | BI17T - Cellegummi 13 mm SPV fett | 0.0633797 | 200 | 101 | 0.000715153 | 101 | ORIGINAL | SPV | MA | MA | UB2.1115131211 | Sanitary | MagiCAD Pset_Heating - v_SizingFlow_ms: 0 m/s; pTot_SizingFlow_kPa: 0 kPa; dpTot_SizingFlow_kPa: 0 kPa; MagiCAD Pset_Water - dpTot_SizingFlow_kPa: 0 kPa; pTot_SizingFlow_kPa: 0 kPa; v_SizingFlow_ms: 0 m/s; MagiCAD Pset_Pipe - Length_mm: 200 mm; qv_SizingFlow_ls: 0 m3/s; SystemName: 31= SPV Kopi 147 (4); Insulation_thickness_mm: 13 mm; ConnectionSize_mm: 75 mm
BI10T - Cellegummi 18-32 mm kalde rør | Nivå F - 0,7 m | BI10T - Cellegummi 18-32 mm kalde rør | 0.0560251 | 558 | 32 | 0.000383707 | 32 | ORIGINAL | KV | Kobberrør | Cu | UB1.111713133 | Domestic Cold Water | MagiCAD Pset_Heating - v_SizingFlow_ms: 0 m/s; pTot_SizingFlow_kPa: 0 kPa; dpTot_SizingFlow_kPa: 0 kPa; MagiCAD Pset_Water - dpTot_SizingFlow_kPa: 0 kPa; pTot_SizingFlow_kPa: 0 kPa; v_SizingFlow_ms: 0 m/s; MagiCAD Pset_Pipe - Length_mm: 557.997 mm; qv_SizingFlow_ls: 0 m3/s; SystemName: 31=KV Kopi 4 (29) (2); Insulation_thickness_mm: 10 mm; ConnectionSize_mm: 12 mm
BI10T - Cellegummi 18-32 mm kalde rør | Nivå F - 0,7 m | BI10T - Cellegummi 18-32 mm kalde rør | 0.0156629 | 156 | 32 | 0.000107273 | 32 | ORIGINAL | KV | Kobberrør | Cu | UB1.111713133 | Domestic Cold Water | MagiCAD Pset_Heating - v_SizingFlow_ms: 0 m/s; pTot_SizingFlow_kPa: 0 kPa; dpTot_SizingFlow_kPa: 0 kPa; MagiCAD Pset_Water - dpTot_SizingFlow_kPa: 0 kPa; pTot_SizingFlow_kPa: 0 kPa; v_SizingFlow_ms: 0 m/s; MagiCAD Pset_Pipe - Length_mm: 156 mm; qv_SizingFlow_ls: 0 m3/s; SystemName: 31=KV Kopi 4 (29) (2); Insulation_thickness_mm: 10 mm; ConnectionSize_mm: 12 mm
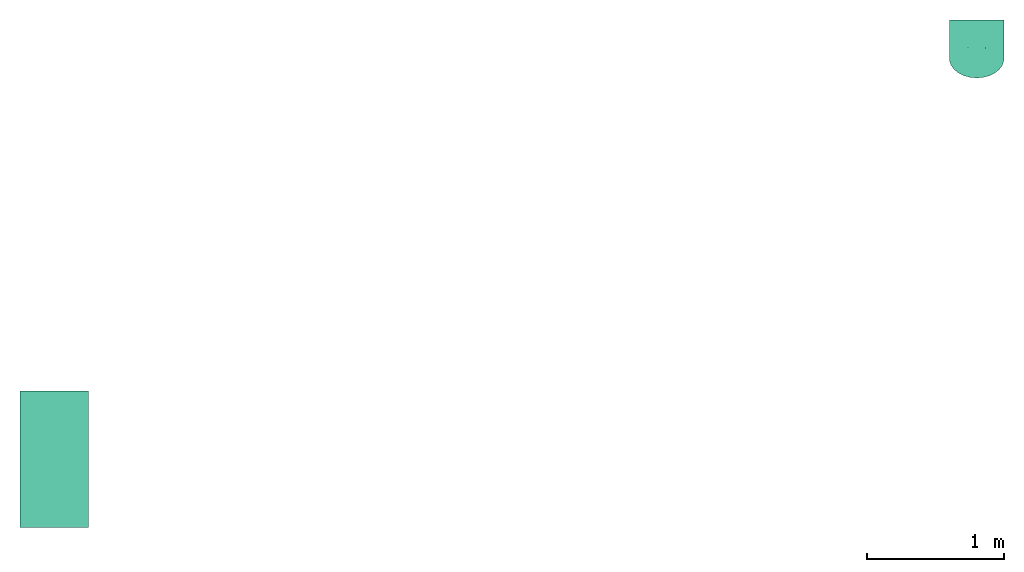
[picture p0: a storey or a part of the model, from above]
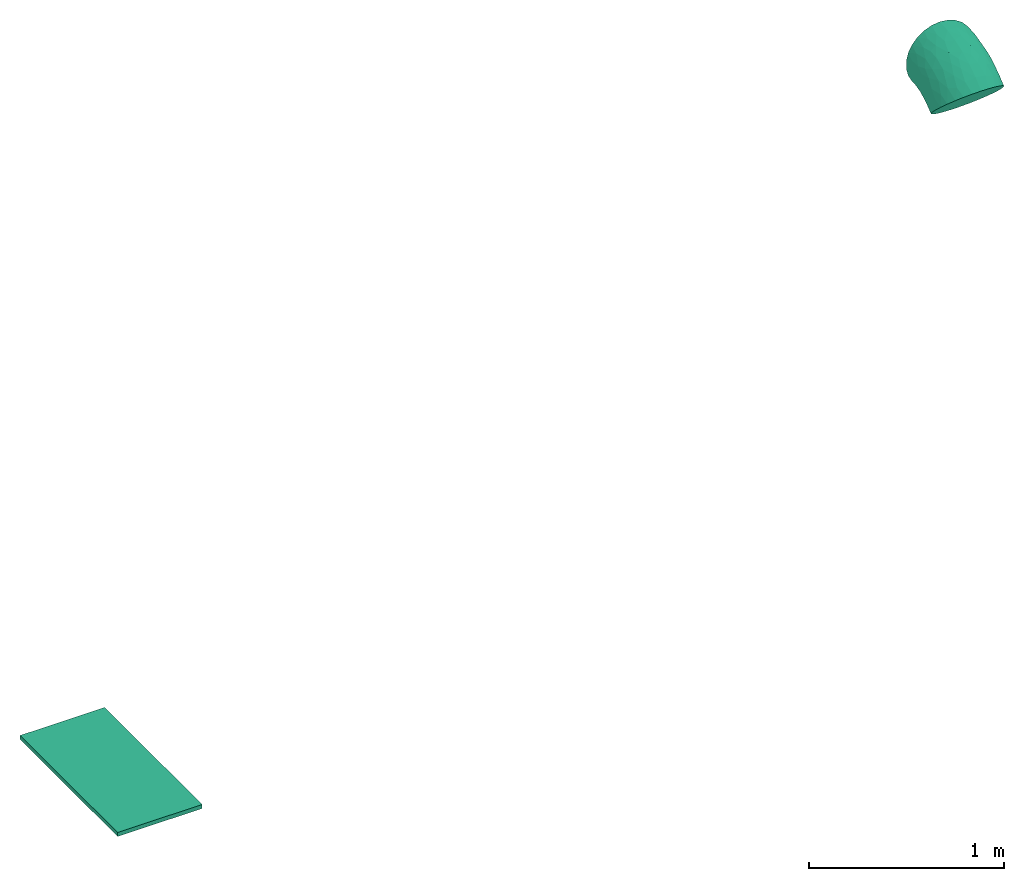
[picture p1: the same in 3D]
Properties of the parts of a building model (IFC2X3), part 4 of 11

# IfcCovering (435)
Name | In | Description | Area, largest surface, net (Simplebim) (m2) | Length (Simplebim) (mm) | Width (Simplebim) (mm) | Volume, net (Simplebim) (m3) | Height (Simplebim) (mm) | Splitting | SystemType | Material | MagiCAD Pset_Pipe, User Code | MagiCAD Pset_Pipe, NationalCode | SystemClass
BI10T - Cellegummi 18-32 mm kalde rør | Nivå F - 0,7 m | BI10T - Cellegummi 18-32 mm kalde rør | 0.0850216 | 846.8 | 32 | 0.000582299 | 32 | ORIGINAL | KV | Kobberrør | Cu | UB1.111713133 | Domestic Cold Water | MagiCAD Pset_Heating - v_SizingFlow_ms: 0 m/s; pTot_SizingFlow_kPa: 0 kPa; dpTot_SizingFlow_kPa: 0 kPa; MagiCAD Pset_Water - dpTot_SizingFlow_kPa: 0 kPa; pTot_SizingFlow_kPa: 0 kPa; v_SizingFlow_ms: 0 m/s; MagiCAD Pset_Pipe - Length_mm: 846.814 mm; qv_SizingFlow_ls: 0 m3/s; SystemName: 31=KV Kopi 4 (29) (2); Insulation_thickness_mm: 10 mm; ConnectionSize_mm: 12 mm
BI10T - Cellegummi 18-32 mm kalde rør | Nivå F - 0,7 m | BI10T - Cellegummi 18-32 mm kalde rør | 0.0291772 | 290.6 | 32 | 0.00019983 | 32 | ORIGINAL | KV | Kobberrør | Cu | UB1.111713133 | Domestic Cold Water | MagiCAD Pset_Heating - v_SizingFlow_ms: 0 m/s; pTot_SizingFlow_kPa: 0 kPa; dpTot_SizingFlow_kPa: 0 kPa; MagiCAD Pset_Water - dpTot_SizingFlow_kPa: 0 kPa; pTot_SizingFlow_kPa: 0 kPa; v_SizingFlow_ms: 0 m/s; MagiCAD Pset_Pipe - Length_mm: 290.568 mm; qv_SizingFlow_ls: 0 m3/s; SystemName: 31=KV Kopi 4 (29) (2); Insulation_thickness_mm: 10 mm; ConnectionSize_mm: 12 mm
BI10T - Cellegummi 18-32 mm kalde rør | Nivå F - 0,7 m | BI10T - Cellegummi 18-32 mm kalde rør | 0.000687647 | 4.8 | 32 | 0.0000033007 | 32 | ORIGINAL | KV | Kobberrør | Cu | UB1.111713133 | Domestic Cold Water | MagiCAD Pset_Heating - v_SizingFlow_ms: 0 m/s; pTot_SizingFlow_kPa: 0 kPa; dpTot_SizingFlow_kPa: 0 kPa; MagiCAD Pset_Water - dpTot_SizingFlow_kPa: 0 kPa; pTot_SizingFlow_kPa: 0 kPa; v_SizingFlow_ms: 0 m/s; MagiCAD Pset_Pipe - Length_mm: 4.809 mm; qv_SizingFlow_ls: 0 m3/s; SystemName: 31=KV Kopi 4 (29) (2); Insulation_thickness_mm: 10 mm; ConnectionSize_mm: 12 mm
BI10T - Cellegummi 18-32 mm kalde rør | Nivå F - 0,7 m | BI10T - Cellegummi 18-32 mm kalde rør | 0.14188 | 1413.1 | 32 | 0.000971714 | 32 | ORIGINAL | KV | Kobberrør | Cu | UB1.111713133 | Domestic Cold Water | MagiCAD Pset_Heating - v_SizingFlow_ms: 0 m/s; pTot_SizingFlow_kPa: 0 kPa; dpTot_SizingFlow_kPa: 0 kPa; MagiCAD Pset_Water - dpTot_SizingFlow_kPa: 0 kPa; pTot_SizingFlow_kPa: 0 kPa; v_SizingFlow_ms: 0 m/s; MagiCAD Pset_Pipe - Length_mm: 1413.1 mm; qv_SizingFlow_ls: 0 m3/s; SystemName: 31=KV Kopi 4 (29) (2); Insulation_thickness_mm: 10 mm; ConnectionSize_mm: 12 mm
BI10T - Cellegummi 18-32 mm kalde rør | Nivå F - 0,7 m | BI10T - Cellegummi 18-32 mm kalde rør | 0.0469888 | 468 | 32 | 0.000321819 | 32 | ORIGINAL | KV | Kobberrør | Cu | UB1.111713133 | Domestic Cold Water | MagiCAD Pset_Heating - v_SizingFlow_ms: 0 m/s; pTot_SizingFlow_kPa: 0 kPa; dpTot_SizingFlow_kPa: 0 kPa; MagiCAD Pset_Water - dpTot_SizingFlow_kPa: 0 kPa; pTot_SizingFlow_kPa: 0 kPa; v_SizingFlow_ms: 0 m/s; MagiCAD Pset_Pipe - Length_mm: 468 mm; qv_SizingFlow_ls: 0 m3/s; SystemName: 31=KV Kopi 4 (29) (2); Insulation_thickness_mm: 10 mm; ConnectionSize_mm: 12 mm
BI10T - Cellegummi 18-32 mm kalde rør | Nivå F - 0,7 m | BI10T - Cellegummi 18-32 mm kalde rør | 0.0529754 | 402 | 42 | 0.00050889 | 42 | ORIGINAL | VV | Kobberrør | Cu | UB1.111713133 | Domestic Hot Water | MagiCAD Pset_Heating - v_SizingFlow_ms: 0 m/s; pTot_SizingFlow_kPa: 0 kPa; dpTot_SizingFlow_kPa: 0 kPa; MagiCAD Pset_Water - dpTot_SizingFlow_kPa: 0 kPa; pTot_SizingFlow_kPa: 0 kPa; v_SizingFlow_ms: 0 m/s; MagiCAD Pset_Pipe - Length_mm: 401.971 mm; qv_SizingFlow_ls: 0 m3/s; SystemName: 31= VV Kopi 41; Insulation_thickness_mm: 15 mm; ConnectionSize_mm: 12 mm
BI10T - Cellegummi 18-32 mm kalde rør | Nivå F - 0,7 m | BI10T - Cellegummi 18-32 mm kalde rør | 0.0555532 | 553.3 | 32 | 0.000380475 | 32 | ORIGINAL | KV | Kobberrør | Cu | UB1.111713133 | Domestic Cold Water | MagiCAD Pset_Heating - v_SizingFlow_ms: 0 m/s; pTot_SizingFlow_kPa: 0 kPa; dpTot_SizingFlow_kPa: 0 kPa; MagiCAD Pset_Water - dpTot_SizingFlow_kPa: 0 kPa; pTot_SizingFlow_kPa: 0 kPa; v_SizingFlow_ms: 0 m/s; MagiCAD Pset_Pipe - Length_mm: 553.316 mm; qv_SizingFlow_ls: 0 m3/s; SystemName: 31=KV Kopi 4 (29) (2); Insulation_thickness_mm: 10 mm; ConnectionSize_mm: 12 mm
BI10T - Cellegummi 18-32 mm kalde rør | Nivå F - 0,7 m | BI10T - Cellegummi 18-32 mm kalde rør | 0.0397598 | 396 | 32 | 0.000272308 | 32 | ORIGINAL | KV | Kobberrør | Cu | UB1.111713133 | Domestic Cold Water | MagiCAD Pset_Heating - v_SizingFlow_ms: 0 m/s; pTot_SizingFlow_kPa: 0 kPa; dpTot_SizingFlow_kPa: 0 kPa; MagiCAD Pset_Water - dpTot_SizingFlow_kPa: 0 kPa; pTot_SizingFlow_kPa: 0 kPa; v_SizingFlow_ms: 0 m/s; MagiCAD Pset_Pipe - Length_mm: 396 mm; qv_SizingFlow_ls: 0 m3/s; SystemName: 31=KV Kopi 4 (29) (2); Insulation_thickness_mm: 10 mm; ConnectionSize_mm: 12 mm
BI10T - Cellegummi 18-32 mm kalde rør | Nivå F - 0,7 m | BI10T - Cellegummi 18-32 mm kalde rør | 0.00261893 | 42 | 33 | 0.0000267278 | 33 | ORIGINAL | MagiCAD Pset_Elbow - qv_SizingFlow_ls: 0 m3/s; pTot_SizingFlow_Pa: 0 kPa; dpTot_SizingFlow_Pa: 0 kPa; v_SizingFlow_ms: 0 m/s; ConnectionSize_mm: 0 mm; Insulation_thickness_mm: 15 mm
BI10T - Cellegummi 18-32 mm kalde rør | Nivå F - 0,7 m | BI10T - Cellegummi 18-32 mm kalde rør | 0.0642952 | 487.9 | 42 | 0.00061763 | 42 | ORIGINAL | VV | Kobberrør | Cu | UB1.111713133 | Domestic Hot Water | MagiCAD Pset_Heating - v_SizingFlow_ms: 0 m/s; pTot_SizingFlow_kPa: 0 kPa; dpTot_SizingFlow_kPa: 0 kPa; MagiCAD Pset_Water - dpTot_SizingFlow_kPa: 0 kPa; pTot_SizingFlow_kPa: 0 kPa; v_SizingFlow_ms: 0 m/s; MagiCAD Pset_Pipe - Length_mm: 487.898 mm; qv_SizingFlow_ls: 0 m3/s; SystemName: 31= VV Kopi 41; Insulation_thickness_mm: 15 mm; ConnectionSize_mm: 12 mm
BI10T - Cellegummi 18-32 mm kalde rør | Nivå F - 0,7 m | BI10T - Cellegummi 18-32 mm kalde rør | 0.154933 | 1543.1 | 32 | 0.00106111 | 32 | ORIGINAL | KV | Kobberrør | Cu | UB1.111713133 | Domestic Cold Water | MagiCAD Pset_Heating - v_SizingFlow_ms: 0 m/s; pTot_SizingFlow_kPa: 0 kPa; dpTot_SizingFlow_kPa: 0 kPa; MagiCAD Pset_Water - dpTot_SizingFlow_kPa: 0 kPa; pTot_SizingFlow_kPa: 0 kPa; v_SizingFlow_ms: 0 m/s; MagiCAD Pset_Pipe - Length_mm: 1543.12 mm; qv_SizingFlow_ls: 0 m3/s; SystemName: 31=KV Kopi 4 (29) (2); Insulation_thickness_mm: 10 mm; ConnectionSize_mm: 12 mm
BI10T - Cellegummi 18-32 mm kalde rør | Nivå F - 0,7 m | BI10T - Cellegummi 18-32 mm kalde rør | 0.409134 | 4074.9 | 32 | 0.00280209 | 32 | ORIGINAL | KV | Kobberrør | Cu | UB1.111713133 | Domestic Cold Water | MagiCAD Pset_Heating - v_SizingFlow_ms: 0 m/s; pTot_SizingFlow_kPa: 0 kPa; dpTot_SizingFlow_kPa: 0 kPa; MagiCAD Pset_Water - dpTot_SizingFlow_kPa: 0 kPa; pTot_SizingFlow_kPa: 0 kPa; v_SizingFlow_ms: 0 m/s; MagiCAD Pset_Pipe - Length_mm: 4074.91 mm; qv_SizingFlow_ls: 0 m3/s; SystemName: 31=KV Kopi 4 (29) (2); Insulation_thickness_mm: 10 mm; ConnectionSize_mm: 12 mm
BI10T - Cellegummi 18-32 mm kalde rør | Nivå F - 0,7 m | BI10T - Cellegummi 18-32 mm kalde rør | 0.000799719 | 32 | 18.5254 | 0.00000691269 | 27.9202 | ORIGINAL | MagiCAD Pset_Elbow - qv_SizingFlow_ls: 0 m3/s; pTot_SizingFlow_Pa: 0 kPa; dpTot_SizingFlow_Pa: 0 kPa; v_SizingFlow_ms: 0 m/s; ConnectionSize_mm: 0 mm; Insulation_thickness_mm: 10 mm
BI17T - Cellegummi 13 mm SPV fett | Nivå D + 1,2 m | BI17T - Cellegummi 13 mm SPV fett | 0.130562 | 412 | 101 | 0.00147321 | 101 | ORIGINAL | SPV | MA | MA | UB2.1115131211 | Sanitary | MagiCAD Pset_Heating - v_SizingFlow_ms: 0 m/s; pTot_SizingFlow_kPa: 0 kPa; dpTot_SizingFlow_kPa: 0 kPa; MagiCAD Pset_Water - dpTot_SizingFlow_kPa: 0 kPa; pTot_SizingFlow_kPa: 0 kPa; v_SizingFlow_ms: 0 m/s; MagiCAD Pset_Pipe - Length_mm: 411.987 mm; qv_SizingFlow_ls: 0 m3/s; SystemName: 31= SPV Kopi 147 (11); Insulation_thickness_mm: 13 mm; ConnectionSize_mm: 75 mm
BI17T - Cellegummi 13 mm SPV fett | Nivå D + 1,2 m | BI17T - Cellegummi 13 mm SPV fett | 0.0422447 | 99 | 136 | 0.000494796 | 136 | ORIGINAL | SPV FETT | MA | MA | UB2.1115131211 | Sanitary | MagiCAD Pset_Heating - v_SizingFlow_ms: 0 m/s; pTot_SizingFlow_kPa: 0 kPa; dpTot_SizingFlow_kPa: 0 kPa; MagiCAD Pset_Water - dpTot_SizingFlow_kPa: 0 kPa; pTot_SizingFlow_kPa: 0 kPa; v_SizingFlow_ms: 0 m/s; MagiCAD Pset_Pipe - Length_mm: 99.036 mm; qv_SizingFlow_ls: 0 m3/s; SystemName: 31= SPV Kopi 138; Insulation_thickness_mm: 13 mm; ConnectionSize_mm: 110 mm
3 x BI17T - Cellegummi 13 mm SPV fett | Nivå D + 1,2 m | BI17T - Cellegummi 13 mm SPV fett | 0.043586 | 160.912 | 147 | 0.00158759 | 137.532 | ORIGINAL | MagiCAD Pset_Elbow - Description: Generic PVC Bend; qv_SizingFlow_ls: 0 m3/s; pTot_SizingFlow_Pa: 0 kPa; dpTot_SizingFlow_Pa: 0 kPa; v_SizingFlow_ms: 0 m/s; ConnectionSize_mm: 0 mm; Insulation_thickness_mm: 13 mm
BI17T - Cellegummi 13 mm SPV fett | Nivå D + 1,2 m | BI17T - Cellegummi 13 mm SPV fett | 0.0637938 | 149.5 | 136 | 0.000747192 | 136 | ORIGINAL | SPV FETT | MA | MA | UB2.1115131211 | Sanitary | MagiCAD Pset_Heating - v_SizingFlow_ms: 0 m/s; pTot_SizingFlow_kPa: 0 kPa; dpTot_SizingFlow_kPa: 0 kPa; MagiCAD Pset_Water - dpTot_SizingFlow_kPa: 0 kPa; pTot_SizingFlow_kPa: 0 kPa; v_SizingFlow_ms: 0 m/s; MagiCAD Pset_Pipe - Length_mm: 149.496 mm; qv_SizingFlow_ls: 0 m3/s; SystemName: 31= SPV Kopi 138; Insulation_thickness_mm: 13 mm; ConnectionSize_mm: 110 mm
3 x BI17T - Cellegummi 13 mm SPV fett | Nivå D + 1,2 m | BI17T - Cellegummi 13 mm SPV fett | 0.0426693 | 160.357 | 135.221 | 0.00155452 | 147 | ORIGINAL | MagiCAD Pset_Elbow - Description: Generic PVC Bend; qv_SizingFlow_ls: 0 m3/s; pTot_SizingFlow_Pa: 0 kPa; dpTot_SizingFlow_Pa: 0 kPa; v_SizingFlow_ms: 0 m/s; ConnectionSize_mm: 0 mm; Insulation_thickness_mm: 13 mm
BI17T - Cellegummi 13 mm SPV fett | Nivå D + 1,2 m | BI17T - Cellegummi 13 mm SPV fett | 0.321273 | 752.9 | 136 | 0.00376295 | 136 | ORIGINAL | SPV FETT | MA | MA | UB2.1115131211 | Sanitary | MagiCAD Pset_Heating - v_SizingFlow_ms: 0 m/s; pTot_SizingFlow_kPa: 0 kPa; dpTot_SizingFlow_kPa: 0 kPa; MagiCAD Pset_Water - dpTot_SizingFlow_kPa: 0 kPa; pTot_SizingFlow_kPa: 0 kPa; v_SizingFlow_ms: 0 m/s; MagiCAD Pset_Pipe - Length_mm: 752.937 mm; qv_SizingFlow_ls: 0 m3/s; SystemName: 31= SPV Kopi 138; Insulation_thickness_mm: 13 mm; ConnectionSize_mm: 110 mm
BI17T - Cellegummi 13 mm SPV fett | Nivå D + 1,2 m | BI17T - Cellegummi 13 mm SPV fett | 0.0200556 | 136 | 136 | 0.000234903 | 47 | ORIGINAL | SPV FETT | MA | MA | UB2.1115131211 | Sanitary | MagiCAD Pset_Heating - v_SizingFlow_ms: 0 m/s; pTot_SizingFlow_kPa: 0 kPa; dpTot_SizingFlow_kPa: 0 kPa; MagiCAD Pset_Water - dpTot_SizingFlow_kPa: 0 kPa; pTot_SizingFlow_kPa: 0 kPa; v_SizingFlow_ms: 0 m/s; MagiCAD Pset_Pipe - Length_mm: 46.98 mm; qv_SizingFlow_ls: 0 m3/s; SystemName: 31= SPV Kopi 138; Insulation_thickness_mm: 13 mm; ConnectionSize_mm: 110 mm
BI17T - Cellegummi 13 mm SPV fett | Nivå D + 1,2 m | BI17T - Cellegummi 13 mm SPV fett | 0.046978 | 163.061 | 147 | 0.00170915 | 145.8 | ORIGINAL | MagiCAD Pset_Elbow - Description: Generic PVC Bend; qv_SizingFlow_ls: 0 m3/s; pTot_SizingFlow_Pa: 0 kPa; dpTot_SizingFlow_Pa: 0 kPa; v_SizingFlow_ms: 0 m/s; ConnectionSize_mm: 0 mm; Insulation_thickness_mm: 13 mm
BI17T - Cellegummi 13 mm SPV fett | Nivå D + 1,2 m | BI17T - Cellegummi 13 mm SPV fett | 0.0642329 | 413.845 | 207.975 | 0.011744 | 286.388 | ORIGINAL | MagiCAD Pset_TBranch - qv_SizingFlow_ls: 0 m3/s; pTot_SizingFlow_Pa: 0 kPa; dpTot_SizingFlow_Pa: 0 kPa; v_SizingFlow_ms: 0 m/s; ConnectionSize_mm: 0 mm; Insulation_thickness_mm: 13 mm
BI17T - Cellegummi 13 mm SPV fett | Nivå D + 1,2 m | BI17T - Cellegummi 13 mm SPV fett | 0.131129 | 307.3 | 136 | 0.00153587 | 136 | ORIGINAL | SPV FETT | MA | MA | UB2.1115131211 | Sanitary | MagiCAD Pset_Heating - v_SizingFlow_ms: 0 m/s; pTot_SizingFlow_kPa: 0 kPa; dpTot_SizingFlow_kPa: 0 kPa; MagiCAD Pset_Water - dpTot_SizingFlow_kPa: 0 kPa; pTot_SizingFlow_kPa: 0 kPa; v_SizingFlow_ms: 0 m/s; MagiCAD Pset_Pipe - Length_mm: 307.273 mm; qv_SizingFlow_ls: 0 m3/s; SystemName: 31= SPV Kopi 138; Insulation_thickness_mm: 13 mm; ConnectionSize_mm: 110 mm
BI17T - Cellegummi 13 mm SPV fett | Nivå D + 1,2 m | BI17T - Cellegummi 13 mm SPV fett | 0.251676 | 589.8 | 136 | 0.00294779 | 136 | ORIGINAL | SPV FETT | MA | MA | UB2.1115131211 | Sanitary | MagiCAD Pset_Heating - v_SizingFlow_ms: 0 m/s; pTot_SizingFlow_kPa: 0 kPa; dpTot_SizingFlow_kPa: 0 kPa; MagiCAD Pset_Water - dpTot_SizingFlow_kPa: 0 kPa; pTot_SizingFlow_kPa: 0 kPa; v_SizingFlow_ms: 0 m/s; MagiCAD Pset_Pipe - Length_mm: 589.786 mm; qv_SizingFlow_ls: 0 m3/s; SystemName: 31= SPV Kopi 138; Insulation_thickness_mm: 13 mm; ConnectionSize_mm: 110 mm
BI17T - Cellegummi 13 mm SPV fett | Nivå D + 1,2 m | BI17T - Cellegummi 13 mm SPV fett | 0.0434822 | 136 | 101.9 | 0.00050929 | 136 | ORIGINAL | SPV FETT | MA | MA | UB2.1115131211 | Sanitary | MagiCAD Pset_Heating - v_SizingFlow_ms: 0 m/s; pTot_SizingFlow_kPa: 0 kPa; dpTot_SizingFlow_kPa: 0 kPa; MagiCAD Pset_Water - dpTot_SizingFlow_kPa: 0 kPa; pTot_SizingFlow_kPa: 0 kPa; v_SizingFlow_ms: 0 m/s; MagiCAD Pset_Pipe - Length_mm: 101.938 mm; qv_SizingFlow_ls: 0 m3/s; SystemName: 31= SPV Kopi 138; Insulation_thickness_mm: 13 mm; ConnectionSize_mm: 110 mm
BI17T - Cellegummi 13 mm SPV fett | Nivå D + 1,2 m | BI17T - Cellegummi 13 mm SPV fett | 0.05265 | 166.814 | 147 | 0.00191783 | 158.044 | ORIGINAL | MagiCAD Pset_Elbow - Description: Generic PVC Bend; qv_SizingFlow_ls: 0 m3/s; pTot_SizingFlow_Pa: 0 kPa; dpTot_SizingFlow_Pa: 0 kPa; v_SizingFlow_ms: 0 m/s; ConnectionSize_mm: 0 mm; Insulation_thickness_mm: 13 mm
BI17T - Cellegummi 13 mm SPV fett | Nivå D + 1,2 m | BI17T - Cellegummi 13 mm SPV fett | 0.0730812 | 416.994 | 236.828 | 0.0137932 | 303.201 | ORIGINAL | MagiCAD Pset_TBranch - qv_SizingFlow_ls: 0 m3/s; pTot_SizingFlow_Pa: 0 kPa; dpTot_SizingFlow_Pa: 0 kPa; v_SizingFlow_ms: 0 m/s; ConnectionSize_mm: 0 mm; Insulation_thickness_mm: 13 mm
BI17T - Cellegummi 13 mm SPV fett | Nivå D + 1,2 m | BI17T - Cellegummi 13 mm SPV fett | 0.0553875 | 129.8 | 136 | 0.000648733 | 136 | ORIGINAL | SPV FETT | MA | MA | UB2.1115131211 | Sanitary | MagiCAD Pset_Heating - v_SizingFlow_ms: 0 m/s; pTot_SizingFlow_kPa: 0 kPa; dpTot_SizingFlow_kPa: 0 kPa; MagiCAD Pset_Water - dpTot_SizingFlow_kPa: 0 kPa; pTot_SizingFlow_kPa: 0 kPa; v_SizingFlow_ms: 0 m/s; MagiCAD Pset_Pipe - Length_mm: 129.759 mm; qv_SizingFlow_ls: 0 m3/s; SystemName: 31= SPV Kopi 138; Insulation_thickness_mm: 13 mm; ConnectionSize_mm: 110 mm
BI17T - Cellegummi 13 mm SPV fett | Nivå D + 1,2 m | BI17T - Cellegummi 13 mm SPV fett | 0.0125027 | 29.3 | 136 | 0.00014644 | 136 | ORIGINAL | SPV FETT | MA | MA | UB2.1115131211 | Sanitary | MagiCAD Pset_Heating - v_SizingFlow_ms: 0 m/s; pTot_SizingFlow_kPa: 0 kPa; dpTot_SizingFlow_kPa: 0 kPa; MagiCAD Pset_Water - dpTot_SizingFlow_kPa: 0 kPa; pTot_SizingFlow_kPa: 0 kPa; v_SizingFlow_ms: 0 m/s; MagiCAD Pset_Pipe - Length_mm: 29.344 mm; qv_SizingFlow_ls: 0 m3/s; SystemName: 31= SPV Kopi 138; Insulation_thickness_mm: 13 mm; ConnectionSize_mm: 110 mm
BI17T - Cellegummi 13 mm SPV fett | Nivå D + 1,2 m | BI17T - Cellegummi 13 mm SPV fett | 0.300322 | 703.8 | 136 | 0.00351755 | 136 | ORIGINAL | SPV FETT | MA | MA | UB2.1115131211 | Sanitary | MagiCAD Pset_Heating - v_SizingFlow_ms: 0 m/s; pTot_SizingFlow_kPa: 0 kPa; dpTot_SizingFlow_kPa: 0 kPa; MagiCAD Pset_Water - dpTot_SizingFlow_kPa: 0 kPa; pTot_SizingFlow_kPa: 0 kPa; v_SizingFlow_ms: 0 m/s; MagiCAD Pset_Pipe - Length_mm: 703.781 mm; qv_SizingFlow_ls: 0 m3/s; SystemName: 31= SPV Kopi 138; Insulation_thickness_mm: 13 mm; ConnectionSize_mm: 110 mm
BI17T - Cellegummi 13 mm SPV fett | Nivå D + 1,2 m | BI17T - Cellegummi 13 mm SPV fett | 0.299938 | 702.9 | 136 | 0.00351305 | 136 | ORIGINAL | SPV FETT | MA | MA | UB2.1115131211 | Sanitary | MagiCAD Pset_Heating - v_SizingFlow_ms: 0 m/s; pTot_SizingFlow_kPa: 0 kPa; dpTot_SizingFlow_kPa: 0 kPa; MagiCAD Pset_Water - dpTot_SizingFlow_kPa: 0 kPa; pTot_SizingFlow_kPa: 0 kPa; v_SizingFlow_ms: 0 m/s; MagiCAD Pset_Pipe - Length_mm: 702.868 mm; qv_SizingFlow_ls: 0 m3/s; SystemName: 31= SPV Kopi 138; Insulation_thickness_mm: 13 mm; ConnectionSize_mm: 110 mm
BI17T - Cellegummi 13 mm SPV fett | Nivå D + 1,2 m | BI17T - Cellegummi 13 mm SPV fett | 0.319182 | 748 | 136 | 0.00373846 | 136 | ORIGINAL | SPV FETT | MA | MA | UB2.1115131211 | Sanitary | MagiCAD Pset_Heating - v_SizingFlow_ms: 0 m/s; pTot_SizingFlow_kPa: 0 kPa; dpTot_SizingFlow_kPa: 0 kPa; MagiCAD Pset_Water - dpTot_SizingFlow_kPa: 0 kPa; pTot_SizingFlow_kPa: 0 kPa; v_SizingFlow_ms: 0 m/s; MagiCAD Pset_Pipe - Length_mm: 747.975 mm; qv_SizingFlow_ls: 0 m3/s; SystemName: 31= SPV Kopi 138; Insulation_thickness_mm: 13 mm; ConnectionSize_mm: 110 mm
BI17T - Cellegummi 13 mm SPV fett | Nivå D + 1,2 m | BI17T - Cellegummi 13 mm SPV fett | 0.0382763 | 136 | 136 | 0.000448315 | 89.7 | ORIGINAL | SPV FETT | MA | MA | UB2.1115131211 | Sanitary | MagiCAD Pset_Heating - v_SizingFlow_ms: 0 m/s; pTot_SizingFlow_kPa: 0 kPa; dpTot_SizingFlow_kPa: 0 kPa; MagiCAD Pset_Water - dpTot_SizingFlow_kPa: 0 kPa; pTot_SizingFlow_kPa: 0 kPa; v_SizingFlow_ms: 0 m/s; MagiCAD Pset_Pipe - Length_mm: 89.701 mm; qv_SizingFlow_ls: 0 m3/s; SystemName: 31= SPV Kopi 138; Insulation_thickness_mm: 13 mm; ConnectionSize_mm: 110 mm
BI17T - Cellegummi 13 mm SPV fett | Nivå D + 1,2 m | BI17T - Cellegummi 13 mm SPV fett | 0.04359 | 160.919 | 147 | 0.00158766 | 137.561 | ORIGINAL | MagiCAD Pset_Elbow - Description: Generic PVC Bend; qv_SizingFlow_ls: 0 m3/s; pTot_SizingFlow_Pa: 0 kPa; dpTot_SizingFlow_Pa: 0 kPa; v_SizingFlow_ms: 0 m/s; ConnectionSize_mm: 0 mm; Insulation_thickness_mm: 13 mm
BI17T - Cellegummi 13 mm SPV fett | Nivå D + 1,2 m | BI17T - Cellegummi 13 mm SPV fett | 0.0617579 | 400.483 | 207.545 | 0.0112409 | 283.515 | ORIGINAL | MagiCAD Pset_TBranch - qv_SizingFlow_ls: 0 m3/s; pTot_SizingFlow_Pa: 0 kPa; dpTot_SizingFlow_Pa: 0 kPa; v_SizingFlow_ms: 0 m/s; ConnectionSize_mm: 0 mm; Insulation_thickness_mm: 13 mm
BI17T - Cellegummi 13 mm SPV fett | Nivå D + 1,2 m | BI17T - Cellegummi 13 mm SPV fett | 0.339835 | 796.4 | 136 | 0.00398036 | 136 | ORIGINAL | SPV FETT | MA | MA | UB2.1115131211 | Sanitary | MagiCAD Pset_Heating - v_SizingFlow_ms: 0 m/s; pTot_SizingFlow_kPa: 0 kPa; dpTot_SizingFlow_kPa: 0 kPa; MagiCAD Pset_Water - dpTot_SizingFlow_kPa: 0 kPa; pTot_SizingFlow_kPa: 0 kPa; v_SizingFlow_ms: 0 m/s; MagiCAD Pset_Pipe - Length_mm: 796.367 mm; qv_SizingFlow_ls: 0 m3/s; SystemName: 31= SPV Kopi 138; Insulation_thickness_mm: 13 mm; ConnectionSize_mm: 110 mm
BI17T - Cellegummi 13 mm SPV fett | Nivå D + 1,2 m | BI17T - Cellegummi 13 mm SPV fett | 0.0287179 | 136 | 136 | 0.000336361 | 67.3 | ORIGINAL | SPV FETT | MA | MA | UB2.1115131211 | Sanitary | MagiCAD Pset_Heating - v_SizingFlow_ms: 0 m/s; pTot_SizingFlow_kPa: 0 kPa; dpTot_SizingFlow_kPa: 0 kPa; MagiCAD Pset_Water - dpTot_SizingFlow_kPa: 0 kPa; pTot_SizingFlow_kPa: 0 kPa; v_SizingFlow_ms: 0 m/s; MagiCAD Pset_Pipe - Length_mm: 67.343 mm; qv_SizingFlow_ls: 0 m3/s; SystemName: 31= SPV Kopi 138; Insulation_thickness_mm: 13 mm; ConnectionSize_mm: 110 mm
BI17T - Cellegummi 13 mm SPV fett | Nivå D + 1,2 m | BI17T - Cellegummi 13 mm SPV fett | 0.043594 | 160.922 | 147 | 0.00158781 | 137.571 | ORIGINAL | MagiCAD Pset_Elbow - Description: Generic PVC Bend; qv_SizingFlow_ls: 0 m3/s; pTot_SizingFlow_Pa: 0 kPa; dpTot_SizingFlow_Pa: 0 kPa; v_SizingFlow_ms: 0 m/s; ConnectionSize_mm: 0 mm; Insulation_thickness_mm: 13 mm
BI17T - Cellegummi 13 mm SPV fett | Nivå D + 1,2 m | BI17T - Cellegummi 13 mm SPV fett | 0.0617022 | 401.174 | 206.833 | 0.0112151 | 283.119 | ORIGINAL | MagiCAD Pset_TBranch - qv_SizingFlow_ls: 0 m3/s; pTot_SizingFlow_Pa: 0 kPa; dpTot_SizingFlow_Pa: 0 kPa; v_SizingFlow_ms: 0 m/s; ConnectionSize_mm: 0 mm; Insulation_thickness_mm: 13 mm
BI17T - Cellegummi 13 mm SPV fett | Nivå D + 1,2 m | BI17T - Cellegummi 13 mm SPV fett | 0.35332 | 828 | 136 | 0.0041383 | 136 | ORIGINAL | SPV FETT | MA | MA | UB2.1115131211 | Sanitary | MagiCAD Pset_Heating - v_SizingFlow_ms: 0 m/s; pTot_SizingFlow_kPa: 0 kPa; dpTot_SizingFlow_kPa: 0 kPa; MagiCAD Pset_Water - dpTot_SizingFlow_kPa: 0 kPa; pTot_SizingFlow_kPa: 0 kPa; v_SizingFlow_ms: 0 m/s; MagiCAD Pset_Pipe - Length_mm: 827.969 mm; qv_SizingFlow_ls: 0 m3/s; SystemName: 31= SPV Kopi 138; Insulation_thickness_mm: 13 mm; ConnectionSize_mm: 110 mm
BI17T - Cellegummi 13 mm SPV fett | Nivå D + 1,2 m | BI17T - Cellegummi 13 mm SPV fett | 0.108126 | 341.2 | 101 | 0.00122005 | 101 | ORIGINAL | SPV FETT | MA | MA | UB2.1115131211 | Sanitary | MagiCAD Pset_Heating - v_SizingFlow_ms: 0 m/s; pTot_SizingFlow_kPa: 0 kPa; dpTot_SizingFlow_kPa: 0 kPa; MagiCAD Pset_Water - dpTot_SizingFlow_kPa: 0 kPa; pTot_SizingFlow_kPa: 0 kPa; v_SizingFlow_ms: 0 m/s; MagiCAD Pset_Pipe - Length_mm: 341.224 mm; qv_SizingFlow_ls: 0 m3/s; SystemName: 31= SPV Kopi 138; Insulation_thickness_mm: 13 mm; ConnectionSize_mm: 75 mm
BI17T - Cellegummi 13 mm SPV fett | Nivå D + 1,2 m | BI17T - Cellegummi 13 mm SPV fett | 0.0435796 | 160.909 | 137.516 | 0.00158736 | 147 | ORIGINAL | MagiCAD Pset_Elbow - Description: Generic PVC Bend; qv_SizingFlow_ls: 0 m3/s; pTot_SizingFlow_Pa: 0 kPa; dpTot_SizingFlow_Pa: 0 kPa; v_SizingFlow_ms: 0 m/s; ConnectionSize_mm: 0 mm; Insulation_thickness_mm: 13 mm
BI17T - Cellegummi 13 mm SPV fett | Nivå D + 1,2 m | BI17T - Cellegummi 13 mm SPV fett | 0.0230426 | 136 | 54 | 0.000269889 | 136 | ORIGINAL | SPV FETT | MA | MA | UB2.1115131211 | Sanitary | MagiCAD Pset_Heating - v_SizingFlow_ms: 0 m/s; pTot_SizingFlow_kPa: 0 kPa; dpTot_SizingFlow_kPa: 0 kPa; MagiCAD Pset_Water - dpTot_SizingFlow_kPa: 0 kPa; pTot_SizingFlow_kPa: 0 kPa; v_SizingFlow_ms: 0 m/s; MagiCAD Pset_Pipe - Length_mm: 54.04 mm; qv_SizingFlow_ls: 0 m3/s; SystemName: 31= SPV Kopi 138; Insulation_thickness_mm: 13 mm; ConnectionSize_mm: 110 mm
BI17T - Cellegummi 13 mm SPV fett | Nivå D + 1,2 m | BI17T - Cellegummi 13 mm SPV fett | 0.0870851 | 531.912 | 239.369 | 0.0158216 | 187.961 | ORIGINAL | MagiCAD Pset_TBranch - qv_SizingFlow_ls: 0 m3/s; pTot_SizingFlow_Pa: 0 kPa; dpTot_SizingFlow_Pa: 0 kPa; v_SizingFlow_ms: 0 m/s; ConnectionSize_mm: 0 mm; Insulation_thickness_mm: 13 mm
BI17T - Cellegummi 13 mm SPV fett | Nivå D + 1,2 m | BI17T - Cellegummi 13 mm SPV fett | 0.0220185 | 136 | 51.6 | 0.000257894 | 136 | ORIGINAL | SPV FETT | MA | MA | UB2.1115131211 | Sanitary | MagiCAD Pset_Heating - v_SizingFlow_ms: 0 m/s; pTot_SizingFlow_kPa: 0 kPa; dpTot_SizingFlow_kPa: 0 kPa; MagiCAD Pset_Water - dpTot_SizingFlow_kPa: 0 kPa; pTot_SizingFlow_kPa: 0 kPa; v_SizingFlow_ms: 0 m/s; MagiCAD Pset_Pipe - Length_mm: 51.626 mm; qv_SizingFlow_ls: 0 m3/s; SystemName: 31= SPV Kopi 138; Insulation_thickness_mm: 13 mm; ConnectionSize_mm: 110 mm
BI17T - Cellegummi 13 mm SPV fett | Nivå D + 1,2 m | BI17T - Cellegummi 13 mm SPV fett | 0.0366121 | 136 | 85.8 | 0.000428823 | 136 | ORIGINAL | SPV FETT | MA | MA | UB2.1115131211 | Sanitary | MagiCAD Pset_Heating - v_SizingFlow_ms: 0 m/s; pTot_SizingFlow_kPa: 0 kPa; dpTot_SizingFlow_kPa: 0 kPa; MagiCAD Pset_Water - dpTot_SizingFlow_kPa: 0 kPa; pTot_SizingFlow_kPa: 0 kPa; v_SizingFlow_ms: 0 m/s; MagiCAD Pset_Pipe - Length_mm: 85.76 mm; qv_SizingFlow_ls: 0 m3/s; SystemName: 31= SPV Kopi 138; Insulation_thickness_mm: 13 mm; ConnectionSize_mm: 110 mm
BI17T - Cellegummi 13 mm SPV fett | Nivå D + 1,2 m | BI17T - Cellegummi 13 mm SPV fett | 0.045688 | 239.373 | 237.824 | 0.00864046 | 196.197 | ORIGINAL | MagiCAD Pset_TBranch - qv_SizingFlow_ls: 0 m3/s; pTot_SizingFlow_Pa: 0 kPa; dpTot_SizingFlow_Pa: 0 kPa; v_SizingFlow_ms: 0 m/s; ConnectionSize_mm: 0 mm; Insulation_thickness_mm: 13 mm
BI17T - Cellegummi 13 mm SPV fett | Nivå D + 1,2 m | BI17T - Cellegummi 13 mm SPV fett | 0.0396418 | 136 | 92.9 | 0.000464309 | 136 | ORIGINAL | SPV FETT | MA | MA | UB2.1115131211 | Sanitary | MagiCAD Pset_Heating - v_SizingFlow_ms: 0 m/s; pTot_SizingFlow_kPa: 0 kPa; dpTot_SizingFlow_kPa: 0 kPa; MagiCAD Pset_Water - dpTot_SizingFlow_kPa: 0 kPa; pTot_SizingFlow_kPa: 0 kPa; v_SizingFlow_ms: 0 m/s; MagiCAD Pset_Pipe - Length_mm: 92.941 mm; qv_SizingFlow_ls: 0 m3/s; SystemName: 31= SPV Kopi 138; Insulation_thickness_mm: 13 mm; ConnectionSize_mm: 110 mm
BI17T - Cellegummi 13 mm SPV fett | Nivå D + 1,2 m | BI17T - Cellegummi 13 mm SPV fett | 0.153105 | 358.8 | 136 | 0.00179326 | 136 | ORIGINAL | SPV FETT | MA | MA | UB2.1115131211 | Sanitary | MagiCAD Pset_Heating - v_SizingFlow_ms: 0 m/s; pTot_SizingFlow_kPa: 0 kPa; dpTot_SizingFlow_kPa: 0 kPa; MagiCAD Pset_Water - dpTot_SizingFlow_kPa: 0 kPa; pTot_SizingFlow_kPa: 0 kPa; v_SizingFlow_ms: 0 m/s; MagiCAD Pset_Pipe - Length_mm: 358.78 mm; qv_SizingFlow_ls: 0 m3/s; SystemName: 31= SPV Kopi 138; Insulation_thickness_mm: 13 mm; ConnectionSize_mm: 110 mm
BI17T - Cellegummi 13 mm SPV fett | Nivå D + 1,2 m | BI17T - Cellegummi 13 mm SPV fett | 0.0435942 | 160.917 | 137.553 | 0.00158789 | 147 | ORIGINAL | MagiCAD Pset_Elbow - Description: Generic PVC Bend; qv_SizingFlow_ls: 0 m3/s; pTot_SizingFlow_Pa: 0 kPa; dpTot_SizingFlow_Pa: 0 kPa; v_SizingFlow_ms: 0 m/s; ConnectionSize_mm: 0 mm; Insulation_thickness_mm: 13 mm
BI17T - Cellegummi 13 mm SPV fett | Nivå D + 1,2 m | BI17T - Cellegummi 13 mm SPV fett | 0.0518011 | 128 | 146 | 0.00162766 | 146 | ORIGINAL | MagiCAD Pset_Reduction - qv_SizingFlow_ls: 0 m3/s; pTot_SizingFlow_Pa: 0 kPa; dpTot_SizingFlow_Pa: 0 kPa; v_SizingFlow_ms: 0 m/s; ConnectionSize_mm: 0 mm; Insulation_thickness_mm: 13 mm
5 x BI17T - Cellegummi 13 mm SPV fett | Nivå D + 1,2 m | BI17T - Cellegummi 13 mm SPV fett | 0.0289705 | 136 | 136 | 0.000976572 | 68 | ORIGINAL | MagiCAD Pset_Plug - ConnectionSize_mm: 0 mm; pTot_SizingFlow_kPa: 0 kPa; Insulation_thickness_mm: 13 mm
BI17T - Cellegummi 13 mm SPV fett | Nivå D + 1,2 m | BI17T - Cellegummi 13 mm SPV fett | 0.197491 | 623.2 | 101 | 0.00222842 | 101 | ORIGINAL | SPV FETT | MA | MA | UB2.1115131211 | Sanitary | MagiCAD Pset_Heating - v_SizingFlow_ms: 0 m/s; pTot_SizingFlow_kPa: 0 kPa; dpTot_SizingFlow_kPa: 0 kPa; MagiCAD Pset_Water - dpTot_SizingFlow_kPa: 0 kPa; pTot_SizingFlow_kPa: 0 kPa; v_SizingFlow_ms: 0 m/s; MagiCAD Pset_Pipe - Length_mm: 623.231 mm; qv_SizingFlow_ls: 0 m3/s; SystemName: 31= SPV Kopi 138; Insulation_thickness_mm: 13 mm; ConnectionSize_mm: 75 mm
BI17T - Cellegummi 13 mm SPV fett | Nivå D + 1,2 m | BI17T - Cellegummi 13 mm SPV fett | 0.0086623 | 136 | 20.3 | 0.000101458 | 136 | ORIGINAL | SPV FETT | MA | MA | UB2.1115131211 | Sanitary | MagiCAD Pset_Heating - v_SizingFlow_ms: 0 m/s; pTot_SizingFlow_kPa: 0 kPa; dpTot_SizingFlow_kPa: 0 kPa; MagiCAD Pset_Water - dpTot_SizingFlow_kPa: 0 kPa; pTot_SizingFlow_kPa: 0 kPa; v_SizingFlow_ms: 0 m/s; MagiCAD Pset_Pipe - Length_mm: 19.634 mm; qv_SizingFlow_ls: 0 m3/s; SystemName: 31= SPV Kopi 138; Insulation_thickness_mm: 13 mm; ConnectionSize_mm: 110 mm
BI17T - Cellegummi 13 mm SPV fett | Nivå D + 1,2 m | BI17T - Cellegummi 13 mm SPV fett | 0.0208237 | 48.8 | 136 | 0.0002439 | 136 | ORIGINAL | SPV FETT | MA | MA | UB2.1115131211 | Sanitary | MagiCAD Pset_Heating - v_SizingFlow_ms: 0 m/s; pTot_SizingFlow_kPa: 0 kPa; dpTot_SizingFlow_kPa: 0 kPa; MagiCAD Pset_Water - dpTot_SizingFlow_kPa: 0 kPa; pTot_SizingFlow_kPa: 0 kPa; v_SizingFlow_ms: 0 m/s; MagiCAD Pset_Pipe - Length_mm: 48.847 mm; qv_SizingFlow_ls: 0 m3/s; SystemName: 31= SPV Kopi 138; Insulation_thickness_mm: 13 mm; ConnectionSize_mm: 110 mm
BI17T - Cellegummi 13 mm SPV fett | Nivå D + 1,2 m | BI17T - Cellegummi 13 mm SPV fett | 0.0424415 | 160.216 | 134.621 | 0.00154675 | 147 | ORIGINAL | MagiCAD Pset_Elbow - Description: Generic PVC Bend; qv_SizingFlow_ls: 0 m3/s; pTot_SizingFlow_Pa: 0 kPa; dpTot_SizingFlow_Pa: 0 kPa; v_SizingFlow_ms: 0 m/s; ConnectionSize_mm: 0 mm; Insulation_thickness_mm: 13 mm
BI17T - Cellegummi 13 mm SPV fett | Nivå D + 1,2 m | BI17T - Cellegummi 13 mm SPV fett | 0.043586 | 160.912 | 137.532 | 0.00158759 | 147 | ORIGINAL | MagiCAD Pset_Elbow - Description: Generic PVC Bend; qv_SizingFlow_ls: 0 m3/s; pTot_SizingFlow_Pa: 0 kPa; dpTot_SizingFlow_Pa: 0 kPa; v_SizingFlow_ms: 0 m/s; ConnectionSize_mm: 0 mm; Insulation_thickness_mm: 13 mm
BI17T - Cellegummi 13 mm SPV fett | Nivå D + 1,2 m | BI17T - Cellegummi 13 mm SPV fett | 0.127374 | 298.5 | 136 | 0.00149189 | 136 | ORIGINAL | SPV FETT | MA | MA | UB2.1115131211 | Sanitary | MagiCAD Pset_Heating - v_SizingFlow_ms: 0 m/s; pTot_SizingFlow_kPa: 0 kPa; dpTot_SizingFlow_kPa: 0 kPa; MagiCAD Pset_Water - dpTot_SizingFlow_kPa: 0 kPa; pTot_SizingFlow_kPa: 0 kPa; v_SizingFlow_ms: 0 m/s; MagiCAD Pset_Pipe - Length_mm: 298.518 mm; qv_SizingFlow_ls: 0 m3/s; SystemName: 31= SPV Kopi 138; Insulation_thickness_mm: 13 mm; ConnectionSize_mm: 110 mm
BI17T - Cellegummi 13 mm SPV fett | Nivå D + 1,2 m | BI17T - Cellegummi 13 mm SPV fett | 0.00823559 | 136 | 136 | 0.0000964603 | 19.3 | ORIGINAL | SPV FETT | MA | MA | UB2.1115131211 | Sanitary | MagiCAD Pset_Heating - v_SizingFlow_ms: 0 m/s; pTot_SizingFlow_kPa: 0 kPa; dpTot_SizingFlow_kPa: 0 kPa; MagiCAD Pset_Water - dpTot_SizingFlow_kPa: 0 kPa; pTot_SizingFlow_kPa: 0 kPa; v_SizingFlow_ms: 0 m/s; MagiCAD Pset_Pipe - Length_mm: 19.338 mm; qv_SizingFlow_ls: 0 m3/s; SystemName: 31= SPV Kopi 138; Insulation_thickness_mm: 13 mm; ConnectionSize_mm: 110 mm
BI17T - Cellegummi 13 mm SPV fett | Nivå D + 1,2 m | BI17T - Cellegummi 13 mm SPV fett | 0.0625136 | 199.472 | 157 | 0.00347273 | 198.792 | ORIGINAL | MagiCAD Pset_Elbow - Description: Generic PVC Bend; qv_SizingFlow_ls: 0 m3/s; pTot_SizingFlow_Pa: 0 kPa; dpTot_SizingFlow_Pa: 0 kPa; v_SizingFlow_ms: 0 m/s; ConnectionSize_mm: 0 mm; Insulation_thickness_mm: 13 mm
BI17T - Cellegummi 13 mm SPV fett | Nivå D + 1,2 m | BI17T - Cellegummi 13 mm SPV fett | 0.107446 | 212.7 | 161 | 0.00127913 | 161 | ORIGINAL | SPV FETT | MA | MA | UB2.1115131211 | Sanitary | MagiCAD Pset_Heating - v_SizingFlow_ms: 0 m/s; pTot_SizingFlow_kPa: 0 kPa; dpTot_SizingFlow_kPa: 0 kPa; MagiCAD Pset_Water - dpTot_SizingFlow_kPa: 0 kPa; pTot_SizingFlow_kPa: 0 kPa; v_SizingFlow_ms: 0 m/s; MagiCAD Pset_Pipe - Length_mm: 212.732 mm; qv_SizingFlow_ls: 0 m3/s; SystemName: 31= SPV Kopi 138; Insulation_thickness_mm: 13 mm; ConnectionSize_mm: 135 mm
BI17T - Cellegummi 13 mm SPV fett | Nivå D + 1,2 m | BI17T - Cellegummi 13 mm SPV fett | 0.0351588 | 69.6 | 161 | 0.000418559 | 161 | ORIGINAL | SPV FETT | MA | MA | UB2.1115131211 | Sanitary | MagiCAD Pset_Heating - v_SizingFlow_ms: 0 m/s; pTot_SizingFlow_kPa: 0 kPa; dpTot_SizingFlow_kPa: 0 kPa; MagiCAD Pset_Water - dpTot_SizingFlow_kPa: 0 kPa; pTot_SizingFlow_kPa: 0 kPa; v_SizingFlow_ms: 0 m/s; MagiCAD Pset_Pipe - Length_mm: 69.588 mm; qv_SizingFlow_ls: 0 m3/s; SystemName: 31= SPV Kopi 138; Insulation_thickness_mm: 13 mm; ConnectionSize_mm: 135 mm
2 x BI17T - Cellegummi 13 mm SPV fett | Nivå D + 1,2 m | BI17T - Cellegummi 13 mm SPV fett | 0.070914 | 196.582 | 174.5 | 0.0030642 | 181.248 | ORIGINAL | MagiCAD Pset_Elbow - Description: Generic PVC Bend; qv_SizingFlow_ls: 0 m3/s; pTot_SizingFlow_Pa: 0 kPa; dpTot_SizingFlow_Pa: 0 kPa; v_SizingFlow_ms: 0 m/s; ConnectionSize_mm: 0 mm; Insulation_thickness_mm: 13 mm
BI17T - Cellegummi 13 mm SPV fett | Nivå D + 1,2 m | BI17T - Cellegummi 13 mm SPV fett | 1.43727 | 2845.2 | 161 | 0.0171104 | 161 | ORIGINAL | SPV FETT | MA | MA | UB2.1115131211 | Sanitary | MagiCAD Pset_Heating - v_SizingFlow_ms: 0 m/s; pTot_SizingFlow_kPa: 0 kPa; dpTot_SizingFlow_kPa: 0 kPa; MagiCAD Pset_Water - dpTot_SizingFlow_kPa: 0 kPa; pTot_SizingFlow_kPa: 0 kPa; v_SizingFlow_ms: 0 m/s; MagiCAD Pset_Pipe - Length_mm: 2845.23 mm; qv_SizingFlow_ls: 0 m3/s; SystemName: 31= SPV Kopi 138; Insulation_thickness_mm: 13 mm; ConnectionSize_mm: 135 mm
BI17T - Cellegummi 13 mm SPV fett | Nivå D + 1,2 m | BI17T - Cellegummi 13 mm SPV fett | 0.0548093 | 108.5 | 161 | 0.000652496 | 161 | ORIGINAL | SPV FETT | MA | MA | UB2.1115131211 | Sanitary | MagiCAD Pset_Heating - v_SizingFlow_ms: 0 m/s; pTot_SizingFlow_kPa: 0 kPa; dpTot_SizingFlow_kPa: 0 kPa; MagiCAD Pset_Water - dpTot_SizingFlow_kPa: 0 kPa; pTot_SizingFlow_kPa: 0 kPa; v_SizingFlow_ms: 0 m/s; MagiCAD Pset_Pipe - Length_mm: 108.54 mm; qv_SizingFlow_ls: 0 m3/s; SystemName: 31= SPV Kopi 138; Insulation_thickness_mm: 13 mm; ConnectionSize_mm: 135 mm
BI17T - Cellegummi 13 mm SPV fett | Nivå D + 1,2 m | BI17T - Cellegummi 13 mm SPV fett | 0.0634394 | 192.44 | 174.5 | 0.00273831 | 166.7 | ORIGINAL | MagiCAD Pset_Elbow - Description: Generic PVC Bend; qv_SizingFlow_ls: 0 m3/s; pTot_SizingFlow_Pa: 0 kPa; dpTot_SizingFlow_Pa: 0 kPa; v_SizingFlow_ms: 0 m/s; ConnectionSize_mm: 0 mm; Insulation_thickness_mm: 13 mm
BI17T - Cellegummi 13 mm SPV fett | Nivå D + 1,2 m | BI17T - Cellegummi 13 mm SPV fett | 0.575977 | 1140.2 | 161 | 0.00685692 | 161 | ORIGINAL | SPV FETT | MA | MA | UB2.1115131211 | Sanitary | MagiCAD Pset_Heating - v_SizingFlow_ms: 0 m/s; pTot_SizingFlow_kPa: 0 kPa; dpTot_SizingFlow_kPa: 0 kPa; MagiCAD Pset_Water - dpTot_SizingFlow_kPa: 0 kPa; pTot_SizingFlow_kPa: 0 kPa; v_SizingFlow_ms: 0 m/s; MagiCAD Pset_Pipe - Length_mm: 1140.16 mm; qv_SizingFlow_ls: 0 m3/s; SystemName: 31= SPV Kopi 138; Insulation_thickness_mm: 13 mm; ConnectionSize_mm: 135 mm
BI17T - Cellegummi 13 mm SPV fett | Nivå D + 1,2 m | BI17T - Cellegummi 13 mm SPV fett | 0.0621224 | 191.724 | 163.899 | 0.00268193 | 174.5 | ORIGINAL | MagiCAD Pset_Elbow - Description: Generic PVC Bend; qv_SizingFlow_ls: 0 m3/s; pTot_SizingFlow_Pa: 0 kPa; dpTot_SizingFlow_Pa: 0 kPa; v_SizingFlow_ms: 0 m/s; ConnectionSize_mm: 0 mm; Insulation_thickness_mm: 13 mm
BI17T - Cellegummi 13 mm SPV fett | Nivå D + 1,2 m | BI17T - Cellegummi 13 mm SPV fett | 0.0695598 | 137.7 | 161 | 0.000828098 | 161 | ORIGINAL | SPV FETT | MA | MA | UB2.1115131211 | Sanitary | MagiCAD Pset_Heating - v_SizingFlow_ms: 0 m/s; pTot_SizingFlow_kPa: 0 kPa; dpTot_SizingFlow_kPa: 0 kPa; MagiCAD Pset_Water - dpTot_SizingFlow_kPa: 0 kPa; pTot_SizingFlow_kPa: 0 kPa; v_SizingFlow_ms: 0 m/s; MagiCAD Pset_Pipe - Length_mm: 137.681 mm; qv_SizingFlow_ls: 0 m3/s; SystemName: 31= SPV Kopi 138; Insulation_thickness_mm: 13 mm; ConnectionSize_mm: 135 mm
BI17T - Cellegummi 13 mm SPV fett | Nivå D + 1,2 m | BI17T - Cellegummi 13 mm SPV fett | 0.0720088 | 197.217 | 174.5 | 0.00311314 | 183.251 | ORIGINAL | MagiCAD Pset_Elbow - Description: Generic PVC Bend; qv_SizingFlow_ls: 0 m3/s; pTot_SizingFlow_Pa: 0 kPa; dpTot_SizingFlow_Pa: 0 kPa; v_SizingFlow_ms: 0 m/s; ConnectionSize_mm: 0 mm; Insulation_thickness_mm: 13 mm
BI17T - Cellegummi 13 mm SPV fett | Nivå D + 1,2 m | BI17T - Cellegummi 13 mm SPV fett | 0.488939 | 967.9 | 161 | 0.00582074 | 161 | ORIGINAL | SPV FETT | MA | MA | UB2.1115131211 | Sanitary | MagiCAD Pset_Heating - v_SizingFlow_ms: 0 m/s; pTot_SizingFlow_kPa: 0 kPa; dpTot_SizingFlow_kPa: 0 kPa; MagiCAD Pset_Water - dpTot_SizingFlow_kPa: 0 kPa; pTot_SizingFlow_kPa: 0 kPa; v_SizingFlow_ms: 0 m/s; MagiCAD Pset_Pipe - Length_mm: 967.949 mm; qv_SizingFlow_ls: 0 m3/s; SystemName: 31= SPV Kopi 138; Insulation_thickness_mm: 13 mm; ConnectionSize_mm: 135 mm
BI17T - Cellegummi 13 mm SPV fett | Nivå D + 1,2 m | BI17T - Cellegummi 13 mm SPV fett | 0.0730413 | 197.843 | 174.5 | 0.00315481 | 185.176 | ORIGINAL | MagiCAD Pset_Elbow - Description: Generic PVC Bend; qv_SizingFlow_ls: 0 m3/s; pTot_SizingFlow_Pa: 0 kPa; dpTot_SizingFlow_Pa: 0 kPa; v_SizingFlow_ms: 0 m/s; ConnectionSize_mm: 0 mm; Insulation_thickness_mm: 13 mm
BI10T - Cellegummi 18-32 mm kalde rør | Nivå D + 1,2 m | BI10T - Cellegummi 18-32 mm kalde rør | 1.41898 | 3350 | 135 | 0.0366484 | 135 | ORIGINAL | Undefined | Stålrør normaltykke | DN | UB3.144613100 | Undefined | MagiCAD Pset_Heating - v_SizingFlow_ms: 0 m/s; pTot_SizingFlow_kPa: 0 kPa; dpTot_SizingFlow_kPa: 0 kPa; MagiCAD Pset_Water - dpTot_SizingFlow_kPa: 0 kPa; pTot_SizingFlow_kPa: 0 kPa; v_SizingFlow_ms: 0 m/s; MagiCAD Pset_Pipe - Length_mm: 3350 mm; qv_SizingFlow_ls: 0 m3/s; Insulation_thickness_mm: 35 mm; ConnectionSize_mm: 65 mm
8 x BI10T - Cellegummi 18-32 mm kalde rør | Nivå D + 1,2 m | BI10T - Cellegummi 18-32 mm kalde rør | 0.0430311 | 135 | 132.5 | 0.00143575 | 132.5 | ORIGINAL | MagiCAD Pset_Elbow - qv_SizingFlow_ls: 0 m3/s; pTot_SizingFlow_Pa: 0 kPa; dpTot_SizingFlow_Pa: 0 kPa; v_SizingFlow_ms: 0 m/s; ConnectionSize_mm: 0 mm; Insulation_thickness_mm: 35 mm
BI10T - Cellegummi 18-32 mm kalde rør | Nivå D + 1,2 m | BI10T - Cellegummi 18-32 mm kalde rør | 0.113434 | 267.8 | 135 | 0.00292969 | 135 | ORIGINAL | Undefined | Stålrør normaltykke | DN | UB3.144613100 | Undefined | MagiCAD Pset_Heating - v_SizingFlow_ms: 0 m/s; pTot_SizingFlow_kPa: 0 kPa; dpTot_SizingFlow_kPa: 0 kPa; MagiCAD Pset_Water - dpTot_SizingFlow_kPa: 0 kPa; pTot_SizingFlow_kPa: 0 kPa; v_SizingFlow_ms: 0 m/s; MagiCAD Pset_Pipe - Length_mm: 267.829 mm; qv_SizingFlow_ls: 0 m3/s; Insulation_thickness_mm: 35 mm; ConnectionSize_mm: 65 mm
BI10T - Cellegummi 18-32 mm kalde rør | Nivå D + 1,2 m | BI10T - Cellegummi 18-32 mm kalde rør | 0.346189 | 817.3 | 135 | 0.00894113 | 135 | ORIGINAL | Undefined | Stålrør normaltykke | DN | UB3.144613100 | Undefined | MagiCAD Pset_Heating - v_SizingFlow_ms: 0 m/s; pTot_SizingFlow_kPa: 0 kPa; dpTot_SizingFlow_kPa: 0 kPa; MagiCAD Pset_Water - dpTot_SizingFlow_kPa: 0 kPa; pTot_SizingFlow_kPa: 0 kPa; v_SizingFlow_ms: 0 m/s; MagiCAD Pset_Pipe - Length_mm: 817.274 mm; qv_SizingFlow_ls: 0 m3/s; Insulation_thickness_mm: 35 mm; ConnectionSize_mm: 65 mm
BI17T - Cellegummi 13 mm SPV fett | Nivå D + 1,2 m | BI17T - Cellegummi 13 mm SPV fett | 0.611519 | 1929.7 | 101 | 0.00690015 | 101 | ORIGINAL | SPV FETT | MA | MA | UB2.1115131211 | Sanitary | MagiCAD Pset_Heating - v_SizingFlow_ms: 0 m/s; pTot_SizingFlow_kPa: 0 kPa; dpTot_SizingFlow_kPa: 0 kPa; MagiCAD Pset_Water - dpTot_SizingFlow_kPa: 0 kPa; pTot_SizingFlow_kPa: 0 kPa; v_SizingFlow_ms: 0 m/s; MagiCAD Pset_Pipe - Length_mm: 1929.7 mm; qv_SizingFlow_ls: 0 m3/s; SystemName: 31= SPV Kopi 138; Insulation_thickness_mm: 13 mm; ConnectionSize_mm: 75 mm
BI10T - Cellegummi 18-32 mm kalde rør | Nivå D + 1,2 m | BI10T - Cellegummi 18-32 mm kalde rør | 0.0464664 | 109.7 | 135 | 0.0012001 | 135 | ORIGINAL | Undefined | Stålrør normaltykke | DN | UB3.144613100 | Undefined | MagiCAD Pset_Heating - v_SizingFlow_ms: 0 m/s; pTot_SizingFlow_kPa: 0 kPa; dpTot_SizingFlow_kPa: 0 kPa; MagiCAD Pset_Water - dpTot_SizingFlow_kPa: 0 kPa; pTot_SizingFlow_kPa: 0 kPa; v_SizingFlow_ms: 0 m/s; MagiCAD Pset_Pipe - Length_mm: 109.661 mm; qv_SizingFlow_ls: 0 m3/s; Insulation_thickness_mm: 35 mm; ConnectionSize_mm: 65 mm
BI10T - Cellegummi 18-32 mm kalde rør | Nivå D + 1,2 m | BI10T - Cellegummi 18-32 mm kalde rør | 0.0166768 | 135 | 75.856 | 0.000556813 | 132.375 | ORIGINAL | MagiCAD Pset_Elbow - qv_SizingFlow_ls: 0 m3/s; pTot_SizingFlow_Pa: 0 kPa; dpTot_SizingFlow_Pa: 0 kPa; v_SizingFlow_ms: 0 m/s; ConnectionSize_mm: 0 mm; Insulation_thickness_mm: 35 mm
BI10T - Cellegummi 18-32 mm kalde rør | Nivå D + 1,2 m | BI10T - Cellegummi 18-32 mm kalde rør | 0.556284 | 1313.3 | 135 | 0.0143673 | 135 | ORIGINAL | VARME R | Stålrør normaltykke | DN | UB3.144613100 | Hydronic Return | MagiCAD Pset_Heating - v_SizingFlow_ms: 0 m/s; pTot_SizingFlow_kPa: 0 kPa; dpTot_SizingFlow_kPa: 0 kPa; MagiCAD Pset_Water - dpTot_SizingFlow_kPa: 0 kPa; pTot_SizingFlow_kPa: 0 kPa; v_SizingFlow_ms: 0 m/s; MagiCAD Pset_Pipe - Length_mm: 1313.26 mm; qv_SizingFlow_ls: 0 m3/s; SystemName: +TG=320.000.R; Insulation_thickness_mm: 35 mm; ConnectionSize_mm: 65 mm
BI10T - Cellegummi 18-32 mm kalde rør | Nivå D + 1,2 m | BI10T - Cellegummi 18-32 mm kalde rør | 0.0552344 | 130.4 | 135 | 0.00142655 | 135 | ORIGINAL | Undefined | Stålrør normaltykke | DN | UB3.144613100 | Undefined | MagiCAD Pset_Heating - v_SizingFlow_ms: 0 m/s; pTot_SizingFlow_kPa: 0 kPa; dpTot_SizingFlow_kPa: 0 kPa; MagiCAD Pset_Water - dpTot_SizingFlow_kPa: 0 kPa; pTot_SizingFlow_kPa: 0 kPa; v_SizingFlow_ms: 0 m/s; MagiCAD Pset_Pipe - Length_mm: 130.396 mm; qv_SizingFlow_ls: 0 m3/s; Insulation_thickness_mm: 35 mm; ConnectionSize_mm: 65 mm
3 x BI10T - Cellegummi 18-32 mm kalde rør | Nivå D + 1,2 m | BI10T - Cellegummi 18-32 mm kalde rør | 0.0178763 | 135 | 93.6916 | 0.000718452 | 132.407 | ORIGINAL | MagiCAD Pset_Elbow - qv_SizingFlow_ls: 0 m3/s; pTot_SizingFlow_Pa: 0 kPa; dpTot_SizingFlow_Pa: 0 kPa; v_SizingFlow_ms: 0 m/s; ConnectionSize_mm: 0 mm; Insulation_thickness_mm: 35 mm
BI10T - Cellegummi 18-32 mm kalde rør | Nivå D + 1,2 m | BI10T - Cellegummi 18-32 mm kalde rør | 0.140966 | 332.8 | 135 | 0.00364078 | 135 | ORIGINAL | Undefined | Stålrør normaltykke | DN | UB3.144613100 | Undefined | MagiCAD Pset_Heating - v_SizingFlow_ms: 0 m/s; pTot_SizingFlow_kPa: 0 kPa; dpTot_SizingFlow_kPa: 0 kPa; MagiCAD Pset_Water - dpTot_SizingFlow_kPa: 0 kPa; pTot_SizingFlow_kPa: 0 kPa; v_SizingFlow_ms: 0 m/s; MagiCAD Pset_Pipe - Length_mm: 332.82 mm; qv_SizingFlow_ls: 0 m3/s; Insulation_thickness_mm: 35 mm; ConnectionSize_mm: 65 mm
BI10T - Cellegummi 18-32 mm kalde rør | Nivå D + 1,2 m | BI10T - Cellegummi 18-32 mm kalde rør | 0.423831 | 1000.6 | 135 | 0.0109464 | 135 | ORIGINAL | Undefined | Stålrør normaltykke | DN | UB3.144613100 | Undefined | MagiCAD Pset_Heating - v_SizingFlow_ms: 0 m/s; pTot_SizingFlow_kPa: 0 kPa; dpTot_SizingFlow_kPa: 0 kPa; MagiCAD Pset_Water - dpTot_SizingFlow_kPa: 0 kPa; pTot_SizingFlow_kPa: 0 kPa; v_SizingFlow_ms: 0 m/s; MagiCAD Pset_Pipe - Length_mm: 1000.64 mm; qv_SizingFlow_ls: 0 m3/s; Insulation_thickness_mm: 35 mm; ConnectionSize_mm: 65 mm
BI17T - Cellegummi 13 mm SPV fett | Nivå D + 1,2 m | BI17T - Cellegummi 13 mm SPV fett | 0.148087 | 467.3 | 101 | 0.00167095 | 101 | ORIGINAL | SPV FETT | MA | MA | UB2.1115131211 | Sanitary | MagiCAD Pset_Heating - v_SizingFlow_ms: 0 m/s; pTot_SizingFlow_kPa: 0 kPa; dpTot_SizingFlow_kPa: 0 kPa; MagiCAD Pset_Water - dpTot_SizingFlow_kPa: 0 kPa; pTot_SizingFlow_kPa: 0 kPa; v_SizingFlow_ms: 0 m/s; MagiCAD Pset_Pipe - Length_mm: 467.265 mm; qv_SizingFlow_ls: 0 m3/s; SystemName: 31= SPV Kopi 138; Insulation_thickness_mm: 13 mm; ConnectionSize_mm: 75 mm
BI17T - Cellegummi 13 mm SPV fett | Nivå D + 1,2 m | BI17T - Cellegummi 13 mm SPV fett | 0.0265668 | 125.5 | 125.5 | 0.00092494 | 101 | ORIGINAL | MagiCAD Pset_Elbow - qv_SizingFlow_ls: 0 m3/s; pTot_SizingFlow_Pa: 0 kPa; dpTot_SizingFlow_Pa: 0 kPa; v_SizingFlow_ms: 0 m/s; ConnectionSize_mm: 0 mm; Insulation_thickness_mm: 13 mm
BI17T - Cellegummi 13 mm SPV fett | Nivå D + 1,2 m | BI17T - Cellegummi 13 mm SPV fett | 0.0173026 | 101 | 101 | 0.000195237 | 54.6 | ORIGINAL | SPV FETT | MA | MA | UB2.1115131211 | Sanitary | MagiCAD Pset_Heating - v_SizingFlow_ms: 0 m/s; pTot_SizingFlow_kPa: 0 kPa; dpTot_SizingFlow_kPa: 0 kPa; MagiCAD Pset_Water - dpTot_SizingFlow_kPa: 0 kPa; pTot_SizingFlow_kPa: 0 kPa; v_SizingFlow_ms: 0 m/s; MagiCAD Pset_Pipe - Length_mm: 54.839 mm; qv_SizingFlow_ls: 0 m3/s; SystemName: 31= SPV Kopi 138; Insulation_thickness_mm: 13 mm; ConnectionSize_mm: 75 mm
BI17T - Cellegummi 13 mm SPV fett | Nivå D + 1,2 m | BI17T - Cellegummi 13 mm SPV fett | 0.0164903 | 106.732 | 80.6698 | 0.000412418 | 101 | ORIGINAL | MagiCAD Pset_Elbow - qv_SizingFlow_ls: 0 m3/s; pTot_SizingFlow_Pa: 0 kPa; dpTot_SizingFlow_Pa: 0 kPa; v_SizingFlow_ms: 0 m/s; ConnectionSize_mm: 0 mm; Insulation_thickness_mm: 13 mm
BI17T - Cellegummi 13 mm SPV fett | Nivå D + 1,2 m | BI17T - Cellegummi 13 mm SPV fett | 0.179048 | 565 | 101 | 0.00202031 | 101 | ORIGINAL | SPV FETT | MA | MA | UB2.1115131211 | Sanitary | MagiCAD Pset_Heating - v_SizingFlow_ms: 0 m/s; pTot_SizingFlow_kPa: 0 kPa; dpTot_SizingFlow_kPa: 0 kPa; MagiCAD Pset_Water - dpTot_SizingFlow_kPa: 0 kPa; pTot_SizingFlow_kPa: 0 kPa; v_SizingFlow_ms: 0 m/s; MagiCAD Pset_Pipe - Length_mm: 565 mm; qv_SizingFlow_ls: 0 m3/s; SystemName: 31= SPV Kopi 138; Insulation_thickness_mm: 13 mm; ConnectionSize_mm: 75 mm
BI17T - Cellegummi 13 mm SPV fett | Nivå D + 1,2 m | BI17T - Cellegummi 13 mm SPV fett | 0.020609 | 109.752 | 96.1386 | 0.000515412 | 101 | ORIGINAL | MagiCAD Pset_Elbow - qv_SizingFlow_ls: 0 m3/s; pTot_SizingFlow_Pa: 0 kPa; dpTot_SizingFlow_Pa: 0 kPa; v_SizingFlow_ms: 0 m/s; ConnectionSize_mm: 0 mm; Insulation_thickness_mm: 13 mm
BI17T - Cellegummi 13 mm SPV fett | Nivå D + 1,2 m | BI17T - Cellegummi 13 mm SPV fett | 0.0454432 | 143.4 | 101 | 0.000512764 | 101 | ORIGINAL | SPV FETT | MA | MA | UB2.1115131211 | Sanitary | MagiCAD Pset_Heating - v_SizingFlow_ms: 0 m/s; pTot_SizingFlow_kPa: 0 kPa; dpTot_SizingFlow_kPa: 0 kPa; MagiCAD Pset_Water - dpTot_SizingFlow_kPa: 0 kPa; pTot_SizingFlow_kPa: 0 kPa; v_SizingFlow_ms: 0 m/s; MagiCAD Pset_Pipe - Length_mm: 143.401 mm; qv_SizingFlow_ls: 0 m3/s; SystemName: 31= SPV Kopi 138; Insulation_thickness_mm: 13 mm; ConnectionSize_mm: 75 mm
BI17T - Cellegummi 13 mm SPV fett | Nivå D + 1,2 m | BI17T - Cellegummi 13 mm SPV fett | 0.0259343 | 184.727 | 177.55 | 0.00287871 | 111 | ORIGINAL | MagiCAD Pset_TBranch - qv_SizingFlow_ls: 0 m3/s; pTot_SizingFlow_Pa: 0 kPa; dpTot_SizingFlow_Pa: 0 kPa; v_SizingFlow_ms: 0 m/s; ConnectionSize_mm: 0 mm; Insulation_thickness_mm: 13 mm
BI17T - Cellegummi 13 mm SPV fett | Nivå D + 1,2 m | BI17T - Cellegummi 13 mm SPV fett | 0.0220878 | 101 | 69.7 | 0.000249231 | 101 | ORIGINAL | SPV FETT | MA | MA | UB2.1115131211 | Sanitary | MagiCAD Pset_Heating - v_SizingFlow_ms: 0 m/s; pTot_SizingFlow_kPa: 0 kPa; dpTot_SizingFlow_kPa: 0 kPa; MagiCAD Pset_Water - dpTot_SizingFlow_kPa: 0 kPa; pTot_SizingFlow_kPa: 0 kPa; v_SizingFlow_ms: 0 m/s; MagiCAD Pset_Pipe - Length_mm: 69.687 mm; qv_SizingFlow_ls: 0 m3/s; SystemName: 31= SPV Kopi 138; Insulation_thickness_mm: 13 mm; ConnectionSize_mm: 75 mm
BI17T - Cellegummi 13 mm SPV fett | Nivå D + 1,2 m | BI17T - Cellegummi 13 mm SPV fett | 0.1189 | 375.2 | 101 | 0.00134163 | 101 | ORIGINAL | SPV FETT | MA | MA | UB2.1115131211 | Sanitary | MagiCAD Pset_Heating - v_SizingFlow_ms: 0 m/s; pTot_SizingFlow_kPa: 0 kPa; dpTot_SizingFlow_kPa: 0 kPa; MagiCAD Pset_Water - dpTot_SizingFlow_kPa: 0 kPa; pTot_SizingFlow_kPa: 0 kPa; v_SizingFlow_ms: 0 m/s; MagiCAD Pset_Pipe - Length_mm: 375.221 mm; qv_SizingFlow_ls: 0 m3/s; SystemName: 31= SPV Kopi 138; Insulation_thickness_mm: 13 mm; ConnectionSize_mm: 75 mm
4 x BI17T - Cellegummi 13 mm SPV fett | Nivå D + 1,2 m | BI17T - Cellegummi 13 mm SPV fett | 0.0133213 | 108.176 | 88.7419 | 0.000464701 | 101 | ORIGINAL | MagiCAD Pset_Elbow - qv_SizingFlow_ls: 0 m3/s; pTot_SizingFlow_Pa: 0 kPa; dpTot_SizingFlow_Pa: 0 kPa; v_SizingFlow_ms: 0 m/s; ConnectionSize_mm: 0 mm; Insulation_thickness_mm: 13 mm
BI17T - Cellegummi 13 mm SPV fett | Nivå D + 1,2 m | BI17T - Cellegummi 13 mm SPV fett | 0.0894604 | 282.3 | 101 | 0.00100944 | 101 | ORIGINAL | SPV FETT | MA | MA | UB2.1115131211 | Sanitary | MagiCAD Pset_Heating - v_SizingFlow_ms: 0 m/s; pTot_SizingFlow_kPa: 0 kPa; dpTot_SizingFlow_kPa: 0 kPa; MagiCAD Pset_Water - dpTot_SizingFlow_kPa: 0 kPa; pTot_SizingFlow_kPa: 0 kPa; v_SizingFlow_ms: 0 m/s; MagiCAD Pset_Pipe - Length_mm: 282.327 mm; qv_SizingFlow_ls: 0 m3/s; SystemName: 31= SPV Kopi 138; Insulation_thickness_mm: 13 mm; ConnectionSize_mm: 75 mm
5 x BI17T - Cellegummi 13 mm SPV fett | Nivå D + 1,2 m | BI17T - Cellegummi 13 mm SPV fett | 0.0265668 | 101 | 125.5 | 0.00092494 | 125.5 | ORIGINAL | MagiCAD Pset_Elbow - qv_SizingFlow_ls: 0 m3/s; pTot_SizingFlow_Pa: 0 kPa; dpTot_SizingFlow_Pa: 0 kPa; v_SizingFlow_ms: 0 m/s; ConnectionSize_mm: 0 mm; Insulation_thickness_mm: 13 mm
BI17T - Cellegummi 13 mm SPV fett | Nivå D + 1,2 m | BI17T - Cellegummi 13 mm SPV fett | 0.0262392 | 82.8 | 101 | 0.000296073 | 101 | ORIGINAL | SPV FETT | MA | MA | UB2.1115131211 | Sanitary | MagiCAD Pset_Heating - v_SizingFlow_ms: 0 m/s; pTot_SizingFlow_kPa: 0 kPa; dpTot_SizingFlow_kPa: 0 kPa; MagiCAD Pset_Water - dpTot_SizingFlow_kPa: 0 kPa; pTot_SizingFlow_kPa: 0 kPa; v_SizingFlow_ms: 0 m/s; MagiCAD Pset_Pipe - Length_mm: 82.824 mm; qv_SizingFlow_ls: 0 m3/s; SystemName: 31= SPV Kopi 138; Insulation_thickness_mm: 13 mm; ConnectionSize_mm: 75 mm
BI17T - Cellegummi 13 mm SPV fett | Nivå D + 1,2 m | BI17T - Cellegummi 13 mm SPV fett | 0.0867984 | 273.9 | 101 | 0.000979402 | 101 | ORIGINAL | SPV FETT | MA | MA | UB2.1115131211 | Sanitary | MagiCAD Pset_Heating - v_SizingFlow_ms: 0 m/s; pTot_SizingFlow_kPa: 0 kPa; dpTot_SizingFlow_kPa: 0 kPa; MagiCAD Pset_Water - dpTot_SizingFlow_kPa: 0 kPa; pTot_SizingFlow_kPa: 0 kPa; v_SizingFlow_ms: 0 m/s; MagiCAD Pset_Pipe - Length_mm: 273.934 mm; qv_SizingFlow_ls: 0 m3/s; SystemName: 31= SPV Kopi 138; Insulation_thickness_mm: 13 mm; ConnectionSize_mm: 75 mm
BI17T - Cellegummi 13 mm SPV fett | Nivå D + 1,2 m | BI17T - Cellegummi 13 mm SPV fett | 0.235265 | 742.4 | 101 | 0.00265465 | 101 | ORIGINAL | SPV FETT | MA | MA | UB2.1115131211 | Sanitary | MagiCAD Pset_Heating - v_SizingFlow_ms: 0 m/s; pTot_SizingFlow_kPa: 0 kPa; dpTot_SizingFlow_kPa: 0 kPa; MagiCAD Pset_Water - dpTot_SizingFlow_kPa: 0 kPa; pTot_SizingFlow_kPa: 0 kPa; v_SizingFlow_ms: 0 m/s; MagiCAD Pset_Pipe - Length_mm: 742.376 mm; qv_SizingFlow_ls: 0 m3/s; SystemName: 31= SPV Kopi 138; Insulation_thickness_mm: 13 mm; ConnectionSize_mm: 75 mm
BI17T - Cellegummi 13 mm SPV fett | Nivå D + 1,2 m | BI17T - Cellegummi 13 mm SPV fett | 0.0283307 | 101 | 89.4 | 0.000319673 | 101 | ORIGINAL | SPV FETT | MA | MA | UB2.1115131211 | Sanitary | MagiCAD Pset_Heating - v_SizingFlow_ms: 0 m/s; pTot_SizingFlow_kPa: 0 kPa; dpTot_SizingFlow_kPa: 0 kPa; MagiCAD Pset_Water - dpTot_SizingFlow_kPa: 0 kPa; pTot_SizingFlow_kPa: 0 kPa; v_SizingFlow_ms: 0 m/s; MagiCAD Pset_Pipe - Length_mm: 89.375 mm; qv_SizingFlow_ls: 0 m3/s; SystemName: 31= SPV Kopi 138; Insulation_thickness_mm: 13 mm; ConnectionSize_mm: 75 mm
BI17T - Cellegummi 13 mm SPV fett | Nivå D + 1,2 m | BI17T - Cellegummi 13 mm SPV fett | 0.0169224 | 53.4 | 101 | 0.000190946 | 101 | ORIGINAL | SPV FETT | MA | MA | UB2.1115131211 | Sanitary | MagiCAD Pset_Heating - v_SizingFlow_ms: 0 m/s; pTot_SizingFlow_kPa: 0 kPa; dpTot_SizingFlow_kPa: 0 kPa; MagiCAD Pset_Water - dpTot_SizingFlow_kPa: 0 kPa; pTot_SizingFlow_kPa: 0 kPa; v_SizingFlow_ms: 0 m/s; MagiCAD Pset_Pipe - Length_mm: 53.226 mm; qv_SizingFlow_ls: 0 m3/s; SystemName: 31= SPV Kopi 138; Insulation_thickness_mm: 13 mm; ConnectionSize_mm: 75 mm
BI17T - Cellegummi 13 mm SPV fett | Nivå D + 1,2 m | BI17T - Cellegummi 13 mm SPV fett | 0.00794478 | 101.723 | 30.259 | 0.000143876 | 101 | ORIGINAL | MagiCAD Pset_Elbow - qv_SizingFlow_ls: 0 m3/s; pTot_SizingFlow_Pa: 0 kPa; dpTot_SizingFlow_Pa: 0 kPa; v_SizingFlow_ms: 0 m/s; ConnectionSize_mm: 0 mm; Insulation_thickness_mm: 13 mm
BI17T - Cellegummi 13 mm SPV fett | Nivå D + 1,2 m | BI17T - Cellegummi 13 mm SPV fett | 0.00794478 | 102.325 | 40.7099 | 0.000193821 | 101 | ORIGINAL | MagiCAD Pset_Elbow - qv_SizingFlow_ls: 0 m3/s; pTot_SizingFlow_Pa: 0 kPa; dpTot_SizingFlow_Pa: 0 kPa; v_SizingFlow_ms: 0 m/s; ConnectionSize_mm: 0 mm; Insulation_thickness_mm: 13 mm
BI17T - Cellegummi 13 mm SPV fett | Nivå D + 1,2 m | BI17T - Cellegummi 13 mm SPV fett | 0.0952596 | 300.6 | 101 | 0.00107487 | 101 | ORIGINAL | SPV FETT | MA | MA | UB2.1115131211 | Sanitary | MagiCAD Pset_Heating - v_SizingFlow_ms: 0 m/s; pTot_SizingFlow_kPa: 0 kPa; dpTot_SizingFlow_kPa: 0 kPa; MagiCAD Pset_Water - dpTot_SizingFlow_kPa: 0 kPa; pTot_SizingFlow_kPa: 0 kPa; v_SizingFlow_ms: 0 m/s; MagiCAD Pset_Pipe - Length_mm: 300.636 mm; qv_SizingFlow_ls: 0 m3/s; SystemName: 31= SPV Kopi 138; Insulation_thickness_mm: 13 mm; ConnectionSize_mm: 75 mm
BI17T - Cellegummi 13 mm SPV fett | Nivå D + 1,2 m | BI17T - Cellegummi 13 mm SPV fett | 0.0133899 | 108.246 | 101 | 0.000467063 | 89.0973 | ORIGINAL | MagiCAD Pset_Elbow - qv_SizingFlow_ls: 0 m3/s; pTot_SizingFlow_Pa: 0 kPa; dpTot_SizingFlow_Pa: 0 kPa; v_SizingFlow_ms: 0 m/s; ConnectionSize_mm: 0 mm; Insulation_thickness_mm: 13 mm
BI10T - Cellegummi 18-32 mm kalde rør | Nivå D + 1,2 m | BI10T - Cellegummi 18-32 mm kalde rør | 0.73067 | 1725 | 135 | 0.0188712 | 135 | ORIGINAL | VARME T | Stålrør normaltykke | DN | UB3.144613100 | Hydronic Supply | MagiCAD Pset_Heating - v_SizingFlow_ms: 0 m/s; pTot_SizingFlow_kPa: 0 kPa; dpTot_SizingFlow_kPa: 0 kPa; MagiCAD Pset_Water - dpTot_SizingFlow_kPa: 0 kPa; pTot_SizingFlow_kPa: 0 kPa; v_SizingFlow_ms: 0 m/s; MagiCAD Pset_Pipe - Length_mm: 1725.01 mm; qv_SizingFlow_ls: 0 m3/s; SystemName: +TG=320.000.T; Insulation_thickness_mm: 35 mm; ConnectionSize_mm: 65 mm
BI10T - Cellegummi 18-32 mm kalde rør | Nivå D + 1,2 m | BI10T - Cellegummi 18-32 mm kalde rør | 0.713642 | 1684.8 | 135 | 0.0184314 | 135 | ORIGINAL | VARME R | Stålrør normaltykke | DN | UB3.144613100 | Hydronic Return | MagiCAD Pset_Heating - v_SizingFlow_ms: 0 m/s; pTot_SizingFlow_kPa: 0 kPa; dpTot_SizingFlow_kPa: 0 kPa; MagiCAD Pset_Water - dpTot_SizingFlow_kPa: 0 kPa; pTot_SizingFlow_kPa: 0 kPa; v_SizingFlow_ms: 0 m/s; MagiCAD Pset_Pipe - Length_mm: 1684.79 mm; qv_SizingFlow_ls: 0 m3/s; SystemName: +TG=320.000.R; Insulation_thickness_mm: 35 mm; ConnectionSize_mm: 65 mm
BI17T - Cellegummi 13 mm SPV fett | Nivå D + 1,2 m | BI17T - Cellegummi 13 mm SPV fett | 0.03882 | 122.5 | 101 | 0.000438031 | 101 | ORIGINAL | SPV FETT | MA | MA | UB2.1115131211 | Sanitary | MagiCAD Pset_Heating - v_SizingFlow_ms: 0 m/s; pTot_SizingFlow_kPa: 0 kPa; dpTot_SizingFlow_kPa: 0 kPa; MagiCAD Pset_Water - dpTot_SizingFlow_kPa: 0 kPa; pTot_SizingFlow_kPa: 0 kPa; v_SizingFlow_ms: 0 m/s; MagiCAD Pset_Pipe - Length_mm: 122.056 mm; qv_SizingFlow_ls: 0 m3/s; SystemName: 31= SPV Kopi 138; Insulation_thickness_mm: 13 mm; ConnectionSize_mm: 75 mm
BI17T - Cellegummi 13 mm SPV fett | Nivå D + 1,2 m | BI17T - Cellegummi 13 mm SPV fett | 0.0426545 | 134.6 | 101 | 0.000481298 | 101 | ORIGINAL | SPV FETT | MA | MA | UB2.1115131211 | Sanitary | MagiCAD Pset_Heating - v_SizingFlow_ms: 0 m/s; pTot_SizingFlow_kPa: 0 kPa; dpTot_SizingFlow_kPa: 0 kPa; MagiCAD Pset_Water - dpTot_SizingFlow_kPa: 0 kPa; pTot_SizingFlow_kPa: 0 kPa; v_SizingFlow_ms: 0 m/s; MagiCAD Pset_Pipe - Length_mm: 134.553 mm; qv_SizingFlow_ls: 0 m3/s; SystemName: 31= SPV Kopi 138; Insulation_thickness_mm: 13 mm; ConnectionSize_mm: 75 mm
BI17T - Cellegummi 13 mm SPV fett | Nivå D + 1,2 m | BI17T - Cellegummi 13 mm SPV fett | 0.0239575 | 75.6 | 101 | 0.000270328 | 101 | ORIGINAL | SPV FETT | MA | MA | UB2.1115131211 | Sanitary | MagiCAD Pset_Heating - v_SizingFlow_ms: 0 m/s; pTot_SizingFlow_kPa: 0 kPa; dpTot_SizingFlow_kPa: 0 kPa; MagiCAD Pset_Water - dpTot_SizingFlow_kPa: 0 kPa; pTot_SizingFlow_kPa: 0 kPa; v_SizingFlow_ms: 0 m/s; MagiCAD Pset_Pipe - Length_mm: 75.871 mm; qv_SizingFlow_ls: 0 m3/s; SystemName: 31= SPV Kopi 138; Insulation_thickness_mm: 13 mm; ConnectionSize_mm: 75 mm
BI17T - Cellegummi 13 mm SPV fett | Nivå D + 1,2 m | BI17T - Cellegummi 13 mm SPV fett | 0.0197511 | 109.086 | 101 | 0.000493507 | 93.1703 | ORIGINAL | MagiCAD Pset_Elbow - qv_SizingFlow_ls: 0 m3/s; pTot_SizingFlow_Pa: 0 kPa; dpTot_SizingFlow_Pa: 0 kPa; v_SizingFlow_ms: 0 m/s; ConnectionSize_mm: 0 mm; Insulation_thickness_mm: 13 mm
BI17T - Cellegummi 13 mm SPV fett | Nivå D + 1,2 m | BI17T - Cellegummi 13 mm SPV fett | 0.0124218 | 107.318 | 84.1159 | 0.000433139 | 101 | ORIGINAL | MagiCAD Pset_Elbow - qv_SizingFlow_ls: 0 m3/s; pTot_SizingFlow_Pa: 0 kPa; dpTot_SizingFlow_Pa: 0 kPa; v_SizingFlow_ms: 0 m/s; ConnectionSize_mm: 0 mm; Insulation_thickness_mm: 13 mm
BI17T - Cellegummi 13 mm SPV fett | Nivå D + 1,2 m | BI17T - Cellegummi 13 mm SPV fett | 0.0212005 | 101 | 101 | 0.000239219 | 66.9 | ORIGINAL | SPV FETT | MA | MA | UB2.1115131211 | Sanitary | MagiCAD Pset_Heating - v_SizingFlow_ms: 0 m/s; pTot_SizingFlow_kPa: 0 kPa; dpTot_SizingFlow_kPa: 0 kPa; MagiCAD Pset_Water - dpTot_SizingFlow_kPa: 0 kPa; pTot_SizingFlow_kPa: 0 kPa; v_SizingFlow_ms: 0 m/s; MagiCAD Pset_Pipe - Length_mm: 66.582 mm; qv_SizingFlow_ls: 0 m3/s; SystemName: 31= SPV Kopi 138; Insulation_thickness_mm: 13 mm; ConnectionSize_mm: 75 mm
BI17T - Cellegummi 13 mm SPV fett | Nivå D + 1,2 m | BI17T - Cellegummi 13 mm SPV fett | 0.387218 | 1221.9 | 101 | 0.00436923 | 101 | ORIGINAL | SPV FETT | MA | MA | UB2.1115131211 | Sanitary | MagiCAD Pset_Heating - v_SizingFlow_ms: 0 m/s; pTot_SizingFlow_kPa: 0 kPa; dpTot_SizingFlow_kPa: 0 kPa; MagiCAD Pset_Water - dpTot_SizingFlow_kPa: 0 kPa; pTot_SizingFlow_kPa: 0 kPa; v_SizingFlow_ms: 0 m/s; MagiCAD Pset_Pipe - Length_mm: 1221.93 mm; qv_SizingFlow_ls: 0 m3/s; SystemName: 31= SPV Kopi 138; Insulation_thickness_mm: 13 mm; ConnectionSize_mm: 75 mm
2 x BI17T - Cellegummi 13 mm SPV fett | Nivå D + 1,2 m | BI17T - Cellegummi 13 mm SPV fett | 0.0316898 | 101 | 101 | 0.000357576 | 100 | ORIGINAL | SPV FETT | MA | MA | UB2.1115131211 | Sanitary | MagiCAD Pset_Heating - v_SizingFlow_ms: 0 m/s; pTot_SizingFlow_kPa: 0 kPa; dpTot_SizingFlow_kPa: 0 kPa; MagiCAD Pset_Water - dpTot_SizingFlow_kPa: 0 kPa; pTot_SizingFlow_kPa: 0 kPa; v_SizingFlow_ms: 0 m/s; MagiCAD Pset_Pipe - Length_mm: 100.2 mm; qv_SizingFlow_ls: 0 m3/s; SystemName: 31= SPV Kopi 138; Insulation_thickness_mm: 13 mm; ConnectionSize_mm: 75 mm
BI17T - Cellegummi 13 mm SPV fett | Nivå D + 1,2 m | BI17T - Cellegummi 13 mm SPV fett | 0.0122503 | 107.152 | 83.1647 | 0.000427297 | 101 | ORIGINAL | MagiCAD Pset_Elbow - qv_SizingFlow_ls: 0 m3/s; pTot_SizingFlow_Pa: 0 kPa; dpTot_SizingFlow_Pa: 0 kPa; v_SizingFlow_ms: 0 m/s; ConnectionSize_mm: 0 mm; Insulation_thickness_mm: 13 mm
BI17T - Cellegummi 13 mm SPV fett | Nivå D + 1,2 m | BI17T - Cellegummi 13 mm SPV fett | 0.0407848 | 128.7 | 101 | 0.000460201 | 101 | ORIGINAL | SPV FETT | MA | MA | UB2.1115131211 | Sanitary | MagiCAD Pset_Heating - v_SizingFlow_ms: 0 m/s; pTot_SizingFlow_kPa: 0 kPa; dpTot_SizingFlow_kPa: 0 kPa; MagiCAD Pset_Water - dpTot_SizingFlow_kPa: 0 kPa; pTot_SizingFlow_kPa: 0 kPa; v_SizingFlow_ms: 0 m/s; MagiCAD Pset_Pipe - Length_mm: 128.682 mm; qv_SizingFlow_ls: 0 m3/s; SystemName: 31= SPV Kopi 138; Insulation_thickness_mm: 13 mm; ConnectionSize_mm: 75 mm
BI17T - Cellegummi 13 mm SPV fett | Nivå D + 1,2 m | BI17T - Cellegummi 13 mm SPV fett | 0.985712 | 3110.5 | 101 | 0.0111224 | 101 | ORIGINAL | SPV FETT | MA | MA | UB2.1115131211 | Sanitary | MagiCAD Pset_Heating - v_SizingFlow_ms: 0 m/s; pTot_SizingFlow_kPa: 0 kPa; dpTot_SizingFlow_kPa: 0 kPa; MagiCAD Pset_Water - dpTot_SizingFlow_kPa: 0 kPa; pTot_SizingFlow_kPa: 0 kPa; v_SizingFlow_ms: 0 m/s; MagiCAD Pset_Pipe - Length_mm: 3110.46 mm; qv_SizingFlow_ls: 0 m3/s; SystemName: 31= SPV Kopi 138; Insulation_thickness_mm: 13 mm; ConnectionSize_mm: 75 mm
BI17T - Cellegummi 13 mm SPV fett | Nivå D + 1,2 m | BI17T - Cellegummi 13 mm SPV fett | 0.0265114 | 125.499 | 125.42 | 0.000923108 | 101 | ORIGINAL | MagiCAD Pset_Elbow - qv_SizingFlow_ls: 0 m3/s; pTot_SizingFlow_Pa: 0 kPa; dpTot_SizingFlow_Pa: 0 kPa; v_SizingFlow_ms: 0 m/s; ConnectionSize_mm: 0 mm; Insulation_thickness_mm: 13 mm
BI17T - Cellegummi 13 mm SPV fett | Nivå D + 1,2 m | BI17T - Cellegummi 13 mm SPV fett | 0.182438 | 575.7 | 101 | 0.00205857 | 101 | ORIGINAL | SPV FETT | MA | MA | UB2.1115131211 | Sanitary | MagiCAD Pset_Heating - v_SizingFlow_ms: 0 m/s; pTot_SizingFlow_kPa: 0 kPa; dpTot_SizingFlow_kPa: 0 kPa; MagiCAD Pset_Water - dpTot_SizingFlow_kPa: 0 kPa; pTot_SizingFlow_kPa: 0 kPa; v_SizingFlow_ms: 0 m/s; MagiCAD Pset_Pipe - Length_mm: 575.745 mm; qv_SizingFlow_ls: 0 m3/s; SystemName: 31= SPV Kopi 138; Insulation_thickness_mm: 13 mm; ConnectionSize_mm: 75 mm
BI17T - Cellegummi 13 mm SPV fett | Nivå D + 1,2 m | BI17T - Cellegummi 13 mm SPV fett | 0.0134594 | 104.887 | 67.834 | 0.000336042 | 101 | ORIGINAL | MagiCAD Pset_Elbow - qv_SizingFlow_ls: 0 m3/s; pTot_SizingFlow_Pa: 0 kPa; dpTot_SizingFlow_Pa: 0 kPa; v_SizingFlow_ms: 0 m/s; ConnectionSize_mm: 0 mm; Insulation_thickness_mm: 13 mm
BI17T - Cellegummi 13 mm SPV fett | Nivå D + 1,2 m | BI17T - Cellegummi 13 mm SPV fett | 0.00399292 | 101 | 101 | 0.0000450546 | 12.6 | ORIGINAL | SPV FETT | MA | MA | UB2.1115131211 | Sanitary | MagiCAD Pset_Heating - v_SizingFlow_ms: 0 m/s; pTot_SizingFlow_kPa: 0 kPa; dpTot_SizingFlow_kPa: 0 kPa; MagiCAD Pset_Water - dpTot_SizingFlow_kPa: 0 kPa; pTot_SizingFlow_kPa: 0 kPa; v_SizingFlow_ms: 0 m/s; MagiCAD Pset_Pipe - Length_mm: 12.625 mm; qv_SizingFlow_ls: 0 m3/s; SystemName: 31= SPV Kopi 138; Insulation_thickness_mm: 13 mm; ConnectionSize_mm: 75 mm
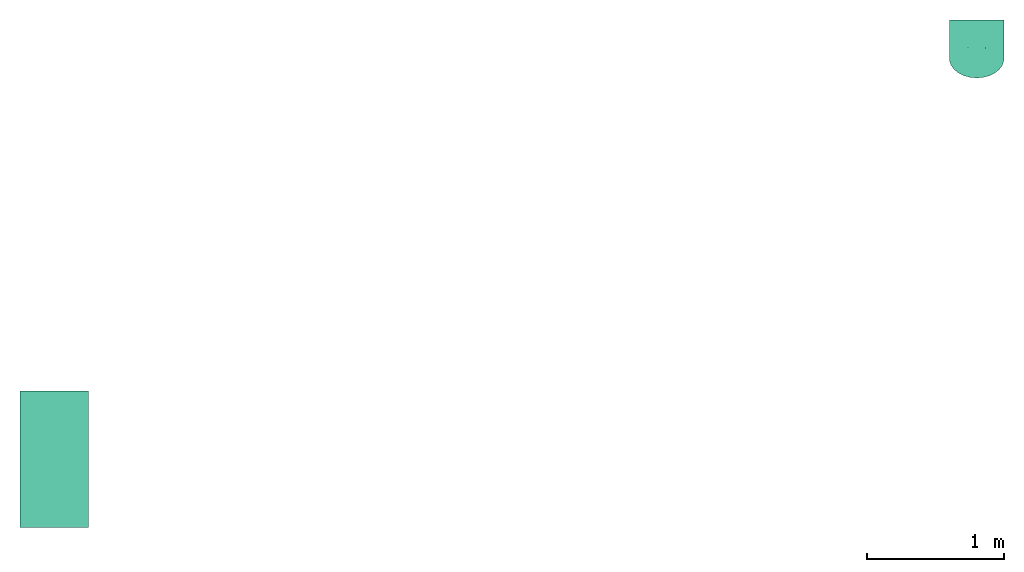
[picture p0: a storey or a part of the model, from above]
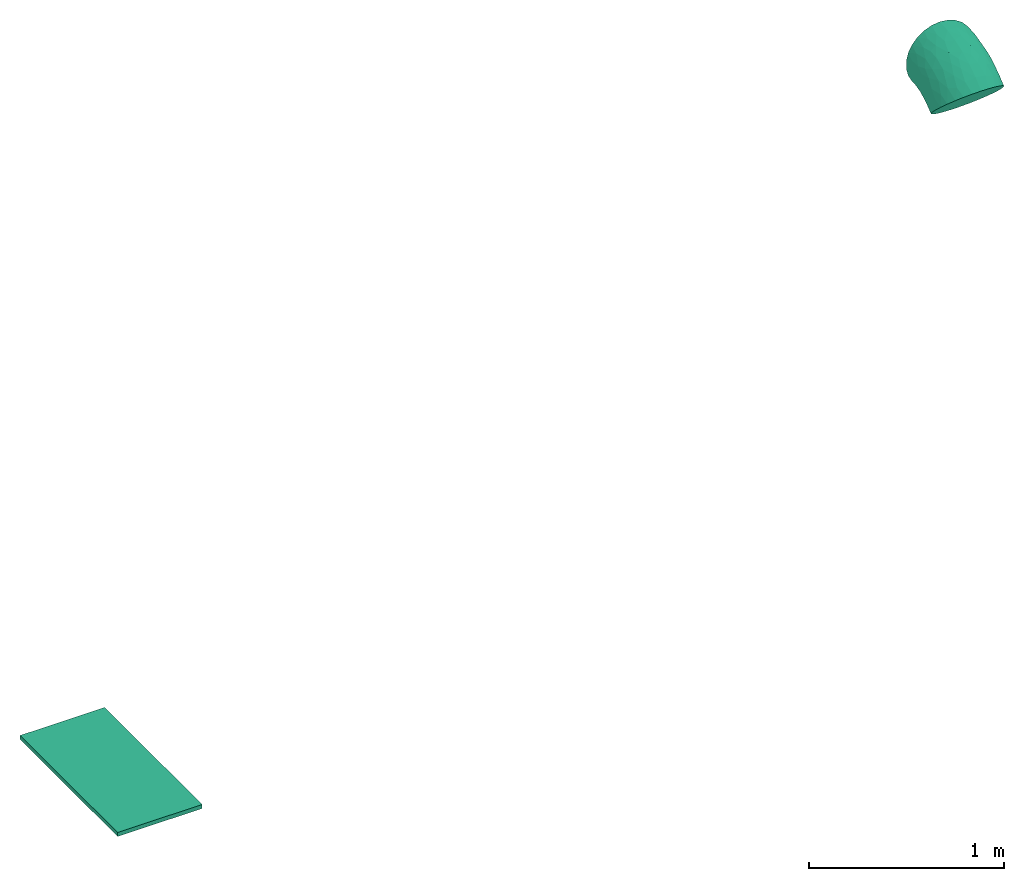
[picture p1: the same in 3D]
Properties of the parts of a building model (IFC2X3), part 5 of 11

# IfcCovering (435)
Name | In | Description | Area, largest surface, net (Simplebim) (m2) | Length (Simplebim) (mm) | Width (Simplebim) (mm) | Volume, net (Simplebim) (m3) | Height (Simplebim) (mm) | Splitting | SystemType | Material | MagiCAD Pset_Pipe, User Code | MagiCAD Pset_Pipe, NationalCode | SystemClass
BI17T - Cellegummi 13 mm SPV fett | Nivå D + 1,2 m | BI17T - Cellegummi 13 mm SPV fett | 0.0253719 | 125.194 | 101 | 0.000884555 | 123.791 | ORIGINAL | MagiCAD Pset_Elbow - qv_SizingFlow_ls: 0 m3/s; pTot_SizingFlow_Pa: 0 kPa; dpTot_SizingFlow_Pa: 0 kPa; v_SizingFlow_ms: 0 m/s; ConnectionSize_mm: 0 mm; Insulation_thickness_mm: 13 mm
BI17T - Cellegummi 13 mm SPV fett | Nivå D + 1,2 m | BI17T - Cellegummi 13 mm SPV fett | 0.323521 | 1020.9 | 101 | 0.0036505 | 101 | ORIGINAL | SPV FETT | MA | MA | UB2.1115131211 | Sanitary | MagiCAD Pset_Heating - v_SizingFlow_ms: 0 m/s; pTot_SizingFlow_kPa: 0 kPa; dpTot_SizingFlow_kPa: 0 kPa; MagiCAD Pset_Water - dpTot_SizingFlow_kPa: 0 kPa; pTot_SizingFlow_kPa: 0 kPa; v_SizingFlow_ms: 0 m/s; MagiCAD Pset_Pipe - Length_mm: 1020.94 mm; qv_SizingFlow_ls: 0 m3/s; SystemName: 31= SPV Kopi 138; Insulation_thickness_mm: 13 mm; ConnectionSize_mm: 75 mm
BI10T - Cellegummi 18-32 mm kalde rør | Nivå D + 1,2 m | BI10T - Cellegummi 18-32 mm kalde rør | 0.202485 | 1290.7 | 50 | 0.00242058 | 50 | ORIGINAL | Undefined | Stålrør normaltykke | DN | UB3.144613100 | Undefined | MagiCAD Pset_Heating - v_SizingFlow_ms: 0 m/s; pTot_SizingFlow_kPa: 0 kPa; dpTot_SizingFlow_kPa: 0 kPa; MagiCAD Pset_Water - dpTot_SizingFlow_kPa: 0 kPa; pTot_SizingFlow_kPa: 0 kPa; v_SizingFlow_ms: 0 m/s; MagiCAD Pset_Pipe - Length_mm: 1290.74 mm; qv_SizingFlow_ls: 0 m3/s; Insulation_thickness_mm: 20 mm; ConnectionSize_mm: 10 mm
BI10T - Cellegummi 18-32 mm kalde rør | Nivå D + 1,2 m | BI10T - Cellegummi 18-32 mm kalde rør | 0.164693 | 1049.8 | 50 | 0.0019688 | 50 | ORIGINAL | Undefined | Stålrør normaltykke | DN | UB3.144613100 | Undefined | MagiCAD Pset_Heating - v_SizingFlow_ms: 0 m/s; pTot_SizingFlow_kPa: 0 kPa; dpTot_SizingFlow_kPa: 0 kPa; MagiCAD Pset_Water - dpTot_SizingFlow_kPa: 0 kPa; pTot_SizingFlow_kPa: 0 kPa; v_SizingFlow_ms: 0 m/s; MagiCAD Pset_Pipe - Length_mm: 1049.76 mm; qv_SizingFlow_ls: 0 m3/s; Insulation_thickness_mm: 20 mm; ConnectionSize_mm: 10 mm
BI10T - Cellegummi 18-32 mm kalde rør | Nivå D + 1,2 m | BI10T - Cellegummi 18-32 mm kalde rør | 0.02303 | 146.8 | 50 | 0.000275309 | 50 | ORIGINAL | Undefined | Stålrør normaltykke | DN | UB3.144613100 | Undefined | MagiCAD Pset_Heating - v_SizingFlow_ms: 0 m/s; pTot_SizingFlow_kPa: 0 kPa; dpTot_SizingFlow_kPa: 0 kPa; MagiCAD Pset_Water - dpTot_SizingFlow_kPa: 0 kPa; pTot_SizingFlow_kPa: 0 kPa; v_SizingFlow_ms: 0 m/s; MagiCAD Pset_Pipe - Length_mm: 146.8 mm; qv_SizingFlow_ls: 0 m3/s; Insulation_thickness_mm: 20 mm; ConnectionSize_mm: 10 mm
BI10T - Cellegummi 18-32 mm kalde rør | Nivå D + 1,2 m | BI10T - Cellegummi 18-32 mm kalde rør | 0.0135545 | 72 | 60 | 0.000196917 | 60 | ORIGINAL | Undefined | Stålrør normaltykke | DN | UB3.144613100 | Undefined | MagiCAD Pset_Heating - v_SizingFlow_ms: 0 m/s; pTot_SizingFlow_kPa: 0 kPa; dpTot_SizingFlow_kPa: 0 kPa; MagiCAD Pset_Water - dpTot_SizingFlow_kPa: 0 kPa; pTot_SizingFlow_kPa: 0 kPa; v_SizingFlow_ms: 0 m/s; MagiCAD Pset_Pipe - Length_mm: 71.967 mm; qv_SizingFlow_ls: 0 m3/s; Insulation_thickness_mm: 25 mm; ConnectionSize_mm: 10 mm
BI10T - Cellegummi 18-32 mm kalde rør | Nivå D + 1,2 m | BI10T - Cellegummi 18-32 mm kalde rør | 0.00212682 | 60 | 39.7996 | 0.0000268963 | 28.2843 | ORIGINAL | MagiCAD Pset_Elbow - qv_SizingFlow_ls: 0 m3/s; pTot_SizingFlow_Pa: 0 kPa; dpTot_SizingFlow_Pa: 0 kPa; v_SizingFlow_ms: 0 m/s; ConnectionSize_mm: 0 mm; Insulation_thickness_mm: 25 mm
BI10T - Cellegummi 18-32 mm kalde rør | Nivå D + 1,2 m | BI10T - Cellegummi 18-32 mm kalde rør | 3.83798 | 20387 | 60 | 0.0557576 | 60 | ORIGINAL | Undefined | Stålrør normaltykke | DN | UB3.144613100 | Undefined | MagiCAD Pset_Heating - v_SizingFlow_ms: 0 m/s; pTot_SizingFlow_kPa: 0 kPa; dpTot_SizingFlow_kPa: 0 kPa; MagiCAD Pset_Water - dpTot_SizingFlow_kPa: 0 kPa; pTot_SizingFlow_kPa: 0 kPa; v_SizingFlow_ms: 0 m/s; MagiCAD Pset_Pipe - Length_mm: 20387 mm; qv_SizingFlow_ls: 0 m3/s; Insulation_thickness_mm: 25 mm; ConnectionSize_mm: 10 mm
2 x BI10T - Cellegummi 18-32 mm kalde rør | Nivå D + 1,2 m | BI10T - Cellegummi 18-32 mm kalde rør | 0.00427011 | 60 | 40 | 0.0000537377 | 40 | ORIGINAL | MagiCAD Pset_Elbow - qv_SizingFlow_ls: 0 m3/s; pTot_SizingFlow_Pa: 0 kPa; dpTot_SizingFlow_Pa: 0 kPa; v_SizingFlow_ms: 0 m/s; ConnectionSize_mm: 0 mm; Insulation_thickness_mm: 25 mm
BI10T - Cellegummi 18-32 mm kalde rør | Nivå D + 1,2 m | BI10T - Cellegummi 18-32 mm kalde rør | 0.43619 | 2317 | 60 | 0.0063369 | 60 | ORIGINAL | Undefined | Stålrør normaltykke | DN | UB3.144613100 | Undefined | MagiCAD Pset_Heating - v_SizingFlow_ms: 0 m/s; pTot_SizingFlow_kPa: 0 kPa; dpTot_SizingFlow_kPa: 0 kPa; MagiCAD Pset_Water - dpTot_SizingFlow_kPa: 0 kPa; pTot_SizingFlow_kPa: 0 kPa; v_SizingFlow_ms: 0 m/s; MagiCAD Pset_Pipe - Length_mm: 2316.97 mm; qv_SizingFlow_ls: 0 m3/s; Insulation_thickness_mm: 25 mm; ConnectionSize_mm: 10 mm
BI10T - Cellegummi 18-32 mm kalde rør | Nivå D + 1,2 m | BI10T - Cellegummi 18-32 mm kalde rør | 0.00564769 | 30 | 60 | 0.0000820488 | 60 | ORIGINAL | Undefined | Stålrør normaltykke | DN | UB3.144613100 | Undefined | MagiCAD Pset_Heating - v_SizingFlow_ms: 0 m/s; pTot_SizingFlow_kPa: 0 kPa; dpTot_SizingFlow_kPa: 0 kPa; MagiCAD Pset_Water - dpTot_SizingFlow_kPa: 0 kPa; pTot_SizingFlow_kPa: 0 kPa; v_SizingFlow_ms: 0 m/s; MagiCAD Pset_Pipe - Length_mm: 30 mm; qv_SizingFlow_ls: 0 m3/s; Insulation_thickness_mm: 25 mm; ConnectionSize_mm: 10 mm
2 x BI10T - Cellegummi 18-32 mm kalde rør | Nivå D + 1,2 m | BI10T - Cellegummi 18-32 mm kalde rør | 0.00197318 | 60 | 22.188 | 0.000012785 | 39.7642 | ORIGINAL | MagiCAD Pset_Elbow - qv_SizingFlow_ls: 0 m3/s; pTot_SizingFlow_Pa: 0 kPa; dpTot_SizingFlow_Pa: 0 kPa; v_SizingFlow_ms: 0 m/s; ConnectionSize_mm: 0 mm; Insulation_thickness_mm: 25 mm
BI10T - Cellegummi 18-32 mm kalde rør | Nivå D + 1,2 m | BI10T - Cellegummi 18-32 mm kalde rør | 0.0423953 | 225.2 | 60 | 0.000615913 | 60 | ORIGINAL | Undefined | Stålrør normaltykke | DN | UB3.144613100 | Undefined | MagiCAD Pset_Heating - v_SizingFlow_ms: 0 m/s; pTot_SizingFlow_kPa: 0 kPa; dpTot_SizingFlow_kPa: 0 kPa; MagiCAD Pset_Water - dpTot_SizingFlow_kPa: 0 kPa; pTot_SizingFlow_kPa: 0 kPa; v_SizingFlow_ms: 0 m/s; MagiCAD Pset_Pipe - Length_mm: 225.25 mm; qv_SizingFlow_ls: 0 m3/s; Insulation_thickness_mm: 25 mm; ConnectionSize_mm: 10 mm
BI10T - Cellegummi 18-32 mm kalde rør | Nivå D + 1,2 m | BI10T - Cellegummi 18-32 mm kalde rør | 0.00197318 | 60 | 39.7829 | 0.0000239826 | 25.7115 | ORIGINAL | MagiCAD Pset_Elbow - qv_SizingFlow_ls: 0 m3/s; pTot_SizingFlow_Pa: 0 kPa; dpTot_SizingFlow_Pa: 0 kPa; v_SizingFlow_ms: 0 m/s; ConnectionSize_mm: 0 mm; Insulation_thickness_mm: 25 mm
BI10T - Cellegummi 18-32 mm kalde rør | Nivå D + 1,2 m | BI10T - Cellegummi 18-32 mm kalde rør | 0.582955 | 3096.6 | 60 | 0.00846907 | 60 | ORIGINAL | Undefined | Stålrør normaltykke | DN | UB3.144613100 | Undefined | MagiCAD Pset_Heating - v_SizingFlow_ms: 0 m/s; pTot_SizingFlow_kPa: 0 kPa; dpTot_SizingFlow_kPa: 0 kPa; MagiCAD Pset_Water - dpTot_SizingFlow_kPa: 0 kPa; pTot_SizingFlow_kPa: 0 kPa; v_SizingFlow_ms: 0 m/s; MagiCAD Pset_Pipe - Length_mm: 3096.55 mm; qv_SizingFlow_ls: 0 m3/s; Insulation_thickness_mm: 25 mm; ConnectionSize_mm: 10 mm
BI10T - Cellegummi 18-32 mm kalde rør | Nivå D + 1,2 m | BI10T - Cellegummi 18-32 mm kalde rør | 0.440294 | 2338.8 | 60 | 0.00639652 | 60 | ORIGINAL | Undefined | Stålrør normaltykke | DN | UB3.144613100 | Undefined | MagiCAD Pset_Heating - v_SizingFlow_ms: 0 m/s; pTot_SizingFlow_kPa: 0 kPa; dpTot_SizingFlow_kPa: 0 kPa; MagiCAD Pset_Water - dpTot_SizingFlow_kPa: 0 kPa; pTot_SizingFlow_kPa: 0 kPa; v_SizingFlow_ms: 0 m/s; MagiCAD Pset_Pipe - Length_mm: 2338.77 mm; qv_SizingFlow_ls: 0 m3/s; Insulation_thickness_mm: 25 mm; ConnectionSize_mm: 10 mm
BI10T - Cellegummi 18-32 mm kalde rør | Nivå D + 1,2 m | BI10T - Cellegummi 18-32 mm kalde rør | 0.00730435 | 38.8 | 60 | 0.000106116 | 60 | ORIGINAL | Undefined | Stålrør normaltykke | DN | UB3.144613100 | Undefined | MagiCAD Pset_Heating - v_SizingFlow_ms: 0 m/s; pTot_SizingFlow_kPa: 0 kPa; dpTot_SizingFlow_kPa: 0 kPa; MagiCAD Pset_Water - dpTot_SizingFlow_kPa: 0 kPa; pTot_SizingFlow_kPa: 0 kPa; v_SizingFlow_ms: 0 m/s; MagiCAD Pset_Pipe - Length_mm: 38.769 mm; qv_SizingFlow_ls: 0 m3/s; Insulation_thickness_mm: 25 mm; ConnectionSize_mm: 10 mm
4 x BI10T - Cellegummi 18-32 mm kalde rør | Nivå D + 1,2 m | BI10T - Cellegummi 18-32 mm kalde rør | 0.00196916 | 60 | 9.70143 | 0.00000838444 | 39.7333 | ORIGINAL | MagiCAD Pset_Elbow - qv_SizingFlow_ls: 0 m3/s; pTot_SizingFlow_Pa: 0 kPa; dpTot_SizingFlow_Pa: 0 kPa; v_SizingFlow_ms: 0 m/s; ConnectionSize_mm: 0 mm; Insulation_thickness_mm: 25 mm
BI10T - Cellegummi 18-32 mm kalde rør | Nivå D + 1,2 m | BI10T - Cellegummi 18-32 mm kalde rør | 0.882452 | 4687.5 | 60 | 0.0128201 | 60 | ORIGINAL | Undefined | Stålrør normaltykke | DN | UB3.144613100 | Undefined | MagiCAD Pset_Heating - v_SizingFlow_ms: 0 m/s; pTot_SizingFlow_kPa: 0 kPa; dpTot_SizingFlow_kPa: 0 kPa; MagiCAD Pset_Water - dpTot_SizingFlow_kPa: 0 kPa; pTot_SizingFlow_kPa: 0 kPa; v_SizingFlow_ms: 0 m/s; MagiCAD Pset_Pipe - Length_mm: 4687.54 mm; qv_SizingFlow_ls: 0 m3/s; Insulation_thickness_mm: 25 mm; ConnectionSize_mm: 10 mm
BI10T - Cellegummi 18-32 mm kalde rør | Nivå D + 1,2 m | BI10T - Cellegummi 18-32 mm kalde rør | 0.0150605 | 80 | 60 | 0.000218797 | 60 | ORIGINAL | Undefined | Stålrør normaltykke | DN | UB3.144613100 | Undefined | MagiCAD Pset_Heating - v_SizingFlow_ms: 0 m/s; pTot_SizingFlow_kPa: 0 kPa; dpTot_SizingFlow_kPa: 0 kPa; MagiCAD Pset_Water - dpTot_SizingFlow_kPa: 0 kPa; pTot_SizingFlow_kPa: 0 kPa; v_SizingFlow_ms: 0 m/s; MagiCAD Pset_Pipe - Length_mm: 80 mm; qv_SizingFlow_ls: 0 m3/s; Insulation_thickness_mm: 25 mm; ConnectionSize_mm: 10 mm
BI10T - Cellegummi 18-32 mm kalde rør | Nivå D + 1,2 m | BI10T - Cellegummi 18-32 mm kalde rør | 0.398539 | 2117 | 60 | 0.00578991 | 60 | ORIGINAL | Undefined | Stålrør normaltykke | DN | UB3.144613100 | Undefined | MagiCAD Pset_Heating - v_SizingFlow_ms: 0 m/s; pTot_SizingFlow_kPa: 0 kPa; dpTot_SizingFlow_kPa: 0 kPa; MagiCAD Pset_Water - dpTot_SizingFlow_kPa: 0 kPa; pTot_SizingFlow_kPa: 0 kPa; v_SizingFlow_ms: 0 m/s; MagiCAD Pset_Pipe - Length_mm: 2116.96 mm; qv_SizingFlow_ls: 0 m3/s; Insulation_thickness_mm: 25 mm; ConnectionSize_mm: 10 mm
BI10T - Cellegummi 18-32 mm kalde rør | Nivå D + 1,2 m | BI10T - Cellegummi 18-32 mm kalde rør | 0.0112013 | 59.5 | 60 | 0.00016273 | 60 | ORIGINAL | Undefined | Stålrør normaltykke | DN | UB3.144613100 | Undefined | MagiCAD Pset_Heating - v_SizingFlow_ms: 0 m/s; pTot_SizingFlow_kPa: 0 kPa; dpTot_SizingFlow_kPa: 0 kPa; MagiCAD Pset_Water - dpTot_SizingFlow_kPa: 0 kPa; pTot_SizingFlow_kPa: 0 kPa; v_SizingFlow_ms: 0 m/s; MagiCAD Pset_Pipe - Length_mm: 59.485 mm; qv_SizingFlow_ls: 0 m3/s; Insulation_thickness_mm: 25 mm; ConnectionSize_mm: 10 mm
BI10T - Cellegummi 18-32 mm kalde rør | Nivå D + 1,2 m | BI10T - Cellegummi 18-32 mm kalde rør | 0.00368983 | 19.6 | 60 | 0.0000536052 | 60 | ORIGINAL | Undefined | Stålrør normaltykke | DN | UB3.144613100 | Undefined | MagiCAD Pset_Heating - v_SizingFlow_ms: 0 m/s; pTot_SizingFlow_kPa: 0 kPa; dpTot_SizingFlow_kPa: 0 kPa; MagiCAD Pset_Water - dpTot_SizingFlow_kPa: 0 kPa; pTot_SizingFlow_kPa: 0 kPa; v_SizingFlow_ms: 0 m/s; MagiCAD Pset_Pipe - Length_mm: 19.633 mm; qv_SizingFlow_ls: 0 m3/s; Insulation_thickness_mm: 25 mm; ConnectionSize_mm: 10 mm
BI10T - Cellegummi 18-32 mm kalde rør | Nivå D + 1,2 m | BI10T - Cellegummi 18-32 mm kalde rør | 0.00229437 | 60 | 29.9772 | 0.0000290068 | 39.8124 | ORIGINAL | MagiCAD Pset_Elbow - qv_SizingFlow_ls: 0 m3/s; pTot_SizingFlow_Pa: 0 kPa; dpTot_SizingFlow_Pa: 0 kPa; v_SizingFlow_ms: 0 m/s; ConnectionSize_mm: 0 mm; Insulation_thickness_mm: 25 mm
BI10T - Cellegummi 18-32 mm kalde rør | Nivå D + 1,2 m | BI10T - Cellegummi 18-32 mm kalde rør | 0.00212682 | 60 | 28.2843 | 0.0000268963 | 39.7996 | ORIGINAL | MagiCAD Pset_Elbow - qv_SizingFlow_ls: 0 m3/s; pTot_SizingFlow_Pa: 0 kPa; dpTot_SizingFlow_Pa: 0 kPa; v_SizingFlow_ms: 0 m/s; ConnectionSize_mm: 0 mm; Insulation_thickness_mm: 25 mm
BI10T - Cellegummi 18-32 mm kalde rør | Nivå D + 1,2 m | BI10T - Cellegummi 18-32 mm kalde rør | 0.00196944 | 60 | 14.0449 | 0.0000123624 | 39.7516 | ORIGINAL | MagiCAD Pset_Elbow - qv_SizingFlow_ls: 0 m3/s; pTot_SizingFlow_Pa: 0 kPa; dpTot_SizingFlow_Pa: 0 kPa; v_SizingFlow_ms: 0 m/s; ConnectionSize_mm: 0 mm; Insulation_thickness_mm: 25 mm
BI10T - Cellegummi 18-32 mm kalde rør | Nivå D + 1,2 m | BI10T - Cellegummi 18-32 mm kalde rør | 0.661194 | 3512.2 | 60 | 0.00960572 | 60 | ORIGINAL | Undefined | Stålrør normaltykke | DN | UB3.144613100 | Undefined | MagiCAD Pset_Heating - v_SizingFlow_ms: 0 m/s; pTot_SizingFlow_kPa: 0 kPa; dpTot_SizingFlow_kPa: 0 kPa; MagiCAD Pset_Water - dpTot_SizingFlow_kPa: 0 kPa; pTot_SizingFlow_kPa: 0 kPa; v_SizingFlow_ms: 0 m/s; MagiCAD Pset_Pipe - Length_mm: 3512.16 mm; qv_SizingFlow_ls: 0 m3/s; Insulation_thickness_mm: 25 mm; ConnectionSize_mm: 10 mm
BI10T - Cellegummi 18-32 mm kalde rør | Nivå D + 1,2 m | BI10T - Cellegummi 18-32 mm kalde rør | 0.159736 | 848.5 | 60 | 0.00232061 | 60 | ORIGINAL | Undefined | Stålrør normaltykke | DN | UB3.144613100 | Undefined | MagiCAD Pset_Heating - v_SizingFlow_ms: 0 m/s; pTot_SizingFlow_kPa: 0 kPa; dpTot_SizingFlow_kPa: 0 kPa; MagiCAD Pset_Water - dpTot_SizingFlow_kPa: 0 kPa; pTot_SizingFlow_kPa: 0 kPa; v_SizingFlow_ms: 0 m/s; MagiCAD Pset_Pipe - Length_mm: 848.53 mm; qv_SizingFlow_ls: 0 m3/s; Insulation_thickness_mm: 25 mm; ConnectionSize_mm: 10 mm
BI10T - Cellegummi 18-32 mm kalde rør | Nivå D + 1,2 m | BI10T - Cellegummi 18-32 mm kalde rør | 0.00344509 | 18.3 | 60 | 0.0000500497 | 60 | ORIGINAL | Undefined | Stålrør normaltykke | DN | UB3.144613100 | Undefined | MagiCAD Pset_Heating - v_SizingFlow_ms: 0 m/s; pTot_SizingFlow_kPa: 0 kPa; dpTot_SizingFlow_kPa: 0 kPa; MagiCAD Pset_Water - dpTot_SizingFlow_kPa: 0 kPa; pTot_SizingFlow_kPa: 0 kPa; v_SizingFlow_ms: 0 m/s; MagiCAD Pset_Pipe - Length_mm: 18.333 mm; qv_SizingFlow_ls: 0 m3/s; Insulation_thickness_mm: 25 mm; ConnectionSize_mm: 10 mm
2 x BI10T - Cellegummi 18-32 mm kalde rør | Nivå D + 1,2 m | BI10T - Cellegummi 18-32 mm kalde rør | 0.00197318 | 60 | 24 | 0.000022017 | 39.7733 | ORIGINAL | MagiCAD Pset_Elbow - qv_SizingFlow_ls: 0 m3/s; pTot_SizingFlow_Pa: 0 kPa; dpTot_SizingFlow_Pa: 0 kPa; v_SizingFlow_ms: 0 m/s; ConnectionSize_mm: 0 mm; Insulation_thickness_mm: 25 mm
BI10T - Cellegummi 18-32 mm kalde rør | Nivå D + 1,2 m | BI10T - Cellegummi 18-32 mm kalde rør | 0.0105612 | 56.1 | 60 | 0.000153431 | 60 | ORIGINAL | Undefined | Stålrør normaltykke | DN | UB3.144613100 | Undefined | MagiCAD Pset_Heating - v_SizingFlow_ms: 0 m/s; pTot_SizingFlow_kPa: 0 kPa; dpTot_SizingFlow_kPa: 0 kPa; MagiCAD Pset_Water - dpTot_SizingFlow_kPa: 0 kPa; pTot_SizingFlow_kPa: 0 kPa; v_SizingFlow_ms: 0 m/s; MagiCAD Pset_Pipe - Length_mm: 56.083 mm; qv_SizingFlow_ls: 0 m3/s; Insulation_thickness_mm: 25 mm; ConnectionSize_mm: 10 mm
2 x BI10T - Cellegummi 18-32 mm kalde rør | Nivå D + 1,2 m | BI10T - Cellegummi 18-32 mm kalde rør | 0.00196966 | 60 | 16.5521 | 0.0000146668 | 39.7652 | ORIGINAL | MagiCAD Pset_Elbow - qv_SizingFlow_ls: 0 m3/s; pTot_SizingFlow_Pa: 0 kPa; dpTot_SizingFlow_Pa: 0 kPa; v_SizingFlow_ms: 0 m/s; ConnectionSize_mm: 0 mm; Insulation_thickness_mm: 25 mm
BI10T - Cellegummi 18-32 mm kalde rør | Nivå D + 1,2 m | BI10T - Cellegummi 18-32 mm kalde rør | 0.0123935 | 79 | 50 | 0.000148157 | 50 | ORIGINAL | Undefined | Stålrør normaltykke | DN | UB3.144613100 | Undefined | MagiCAD Pset_Heating - v_SizingFlow_ms: 0 m/s; pTot_SizingFlow_kPa: 0 kPa; dpTot_SizingFlow_kPa: 0 kPa; MagiCAD Pset_Water - dpTot_SizingFlow_kPa: 0 kPa; pTot_SizingFlow_kPa: 0 kPa; v_SizingFlow_ms: 0 m/s; MagiCAD Pset_Pipe - Length_mm: 79.002 mm; qv_SizingFlow_ls: 0 m3/s; Insulation_thickness_mm: 20 mm; ConnectionSize_mm: 10 mm
3 x BI10T - Cellegummi 18-32 mm kalde rør | Nivå D + 1,2 m | BI10T - Cellegummi 18-32 mm kalde rør | 0.0031248 | 67.2 | 34.4 | 0.000107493 | 46.5 | ORIGINAL | MagiCAD Pset_TBranch - qv_SizingFlow_ls: 0 m3/s; pTot_SizingFlow_Pa: 0 kPa; dpTot_SizingFlow_Pa: 0 kPa; v_SizingFlow_ms: 0 m/s; ConnectionSize_mm: 0 mm; Insulation_thickness_mm: 25 mm
BI10T - Cellegummi 18-32 mm kalde rør | Nivå D + 1,2 m | BI10T - Cellegummi 18-32 mm kalde rør | 0.11815 | 627.6 | 60 | 0.00171646 | 60 | ORIGINAL | Undefined | Stålrør normaltykke | DN | UB3.144613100 | Undefined | MagiCAD Pset_Heating - v_SizingFlow_ms: 0 m/s; pTot_SizingFlow_kPa: 0 kPa; dpTot_SizingFlow_kPa: 0 kPa; MagiCAD Pset_Water - dpTot_SizingFlow_kPa: 0 kPa; pTot_SizingFlow_kPa: 0 kPa; v_SizingFlow_ms: 0 m/s; MagiCAD Pset_Pipe - Length_mm: 627.589 mm; qv_SizingFlow_ls: 0 m3/s; Insulation_thickness_mm: 25 mm; ConnectionSize_mm: 10 mm
BI10T - Cellegummi 18-32 mm kalde rør | Nivå D + 1,2 m | BI10T - Cellegummi 18-32 mm kalde rør | 0.0288346 | 183.8 | 50 | 0.000344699 | 50 | ORIGINAL | Undefined | Stålrør normaltykke | DN | UB3.144613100 | Undefined | MagiCAD Pset_Heating - v_SizingFlow_ms: 0 m/s; pTot_SizingFlow_kPa: 0 kPa; dpTot_SizingFlow_kPa: 0 kPa; MagiCAD Pset_Water - dpTot_SizingFlow_kPa: 0 kPa; pTot_SizingFlow_kPa: 0 kPa; v_SizingFlow_ms: 0 m/s; MagiCAD Pset_Pipe - Length_mm: 183.804 mm; qv_SizingFlow_ls: 0 m3/s; Insulation_thickness_mm: 20 mm; ConnectionSize_mm: 10 mm
BI10T - Cellegummi 18-32 mm kalde rør | Nivå D + 1,2 m | BI10T - Cellegummi 18-32 mm kalde rør | 0.00274542 | 50 | 34.9523 | 0.0000301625 | 34.2352 | ORIGINAL | MagiCAD Pset_Elbow - qv_SizingFlow_ls: 0 m3/s; pTot_SizingFlow_Pa: 0 kPa; dpTot_SizingFlow_Pa: 0 kPa; v_SizingFlow_ms: 0 m/s; ConnectionSize_mm: 0 mm; Insulation_thickness_mm: 20 mm
BI10T - Cellegummi 18-32 mm kalde rør | Nivå D + 1,2 m | BI10T - Cellegummi 18-32 mm kalde rør | 0.0246145 | 156.9 | 50 | 0.00029425 | 50 | ORIGINAL | Undefined | Stålrør normaltykke | DN | UB3.144613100 | Undefined | MagiCAD Pset_Heating - v_SizingFlow_ms: 0 m/s; pTot_SizingFlow_kPa: 0 kPa; dpTot_SizingFlow_kPa: 0 kPa; MagiCAD Pset_Water - dpTot_SizingFlow_kPa: 0 kPa; pTot_SizingFlow_kPa: 0 kPa; v_SizingFlow_ms: 0 m/s; MagiCAD Pset_Pipe - Length_mm: 156.902 mm; qv_SizingFlow_ls: 0 m3/s; Insulation_thickness_mm: 20 mm; ConnectionSize_mm: 10 mm
BI10T - Cellegummi 18-32 mm kalde rør | Nivå D + 1,2 m | BI10T - Cellegummi 18-32 mm kalde rør | 0.00274542 | 50 | 34.2352 | 0.0000301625 | 34.9523 | ORIGINAL | MagiCAD Pset_Elbow - qv_SizingFlow_ls: 0 m3/s; pTot_SizingFlow_Pa: 0 kPa; dpTot_SizingFlow_Pa: 0 kPa; v_SizingFlow_ms: 0 m/s; ConnectionSize_mm: 0 mm; Insulation_thickness_mm: 20 mm
BI10T - Cellegummi 18-32 mm kalde rør | Nivå D + 1,2 m | BI10T - Cellegummi 18-32 mm kalde rør | 0.015688 | 100 | 50 | 0.00018754 | 50 | ORIGINAL | Undefined | Stålrør normaltykke | DN | UB3.144613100 | Undefined | MagiCAD Pset_Heating - v_SizingFlow_ms: 0 m/s; pTot_SizingFlow_kPa: 0 kPa; dpTot_SizingFlow_kPa: 0 kPa; MagiCAD Pset_Water - dpTot_SizingFlow_kPa: 0 kPa; pTot_SizingFlow_kPa: 0 kPa; v_SizingFlow_ms: 0 m/s; MagiCAD Pset_Pipe - Length_mm: 100 mm; qv_SizingFlow_ls: 0 m3/s; Insulation_thickness_mm: 20 mm; ConnectionSize_mm: 10 mm
BI10T - Cellegummi 18-32 mm kalde rør | Nivå D + 1,2 m | BI10T - Cellegummi 18-32 mm kalde rør | 0.00933752 | 49.6 | 60 | 0.000135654 | 60 | ORIGINAL | Undefined | Stålrør normaltykke | DN | UB3.144613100 | Undefined | MagiCAD Pset_Heating - v_SizingFlow_ms: 0 m/s; pTot_SizingFlow_kPa: 0 kPa; dpTot_SizingFlow_kPa: 0 kPa; MagiCAD Pset_Water - dpTot_SizingFlow_kPa: 0 kPa; pTot_SizingFlow_kPa: 0 kPa; v_SizingFlow_ms: 0 m/s; MagiCAD Pset_Pipe - Length_mm: 49.581 mm; qv_SizingFlow_ls: 0 m3/s; Insulation_thickness_mm: 25 mm; ConnectionSize_mm: 10 mm
BI10T - Cellegummi 18-32 mm kalde rør | Nivå D + 1,2 m | BI10T - Cellegummi 18-32 mm kalde rør | 0.0101972 | 65 | 50 | 0.000121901 | 50 | ORIGINAL | Undefined | Stålrør normaltykke | DN | UB3.144613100 | Undefined | MagiCAD Pset_Heating - v_SizingFlow_ms: 0 m/s; pTot_SizingFlow_kPa: 0 kPa; dpTot_SizingFlow_kPa: 0 kPa; MagiCAD Pset_Water - dpTot_SizingFlow_kPa: 0 kPa; pTot_SizingFlow_kPa: 0 kPa; v_SizingFlow_ms: 0 m/s; MagiCAD Pset_Pipe - Length_mm: 65 mm; qv_SizingFlow_ls: 0 m3/s; Insulation_thickness_mm: 20 mm; ConnectionSize_mm: 10 mm
12 x BI10T - Cellegummi 18-32 mm kalde rør | Nivå D + 1,2 m | BI10T - Cellegummi 18-32 mm kalde rør | 0.00317344 | 50 | 35 | 0.0000347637 | 35 | ORIGINAL | MagiCAD Pset_Elbow - qv_SizingFlow_ls: 0 m3/s; pTot_SizingFlow_Pa: 0 kPa; dpTot_SizingFlow_Pa: 0 kPa; v_SizingFlow_ms: 0 m/s; ConnectionSize_mm: 0 mm; Insulation_thickness_mm: 20 mm
BI10T - Cellegummi 18-32 mm kalde rør | Nivå D + 1,2 m | BI10T - Cellegummi 18-32 mm kalde rør | 0.0125504 | 80 | 50 | 0.000150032 | 50 | ORIGINAL | Undefined | Stålrør normaltykke | DN | UB3.144613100 | Undefined | MagiCAD Pset_Heating - v_SizingFlow_ms: 0 m/s; pTot_SizingFlow_kPa: 0 kPa; dpTot_SizingFlow_kPa: 0 kPa; MagiCAD Pset_Water - dpTot_SizingFlow_kPa: 0 kPa; pTot_SizingFlow_kPa: 0 kPa; v_SizingFlow_ms: 0 m/s; MagiCAD Pset_Pipe - Length_mm: 80 mm; qv_SizingFlow_ls: 0 m3/s; Insulation_thickness_mm: 20 mm; ConnectionSize_mm: 10 mm
BI10T - Cellegummi 18-32 mm kalde rør | Nivå D + 1,2 m | BI10T - Cellegummi 18-32 mm kalde rør | 0.0133348 | 85 | 50 | 0.000159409 | 50 | ORIGINAL | Undefined | Stålrør normaltykke | DN | UB3.144613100 | Undefined | MagiCAD Pset_Heating - v_SizingFlow_ms: 0 m/s; pTot_SizingFlow_kPa: 0 kPa; dpTot_SizingFlow_kPa: 0 kPa; MagiCAD Pset_Water - dpTot_SizingFlow_kPa: 0 kPa; pTot_SizingFlow_kPa: 0 kPa; v_SizingFlow_ms: 0 m/s; MagiCAD Pset_Pipe - Length_mm: 85 mm; qv_SizingFlow_ls: 0 m3/s; Insulation_thickness_mm: 20 mm; ConnectionSize_mm: 10 mm
2 x BI10T - Cellegummi 18-32 mm kalde rør | Nivå D + 1,2 m | BI10T - Cellegummi 18-32 mm kalde rør | 0.0109816 | 70 | 50 | 0.000131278 | 50 | ORIGINAL | Undefined | Stålrør normaltykke | DN | UB3.144613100 | Undefined | MagiCAD Pset_Heating - v_SizingFlow_ms: 0 m/s; pTot_SizingFlow_kPa: 0 kPa; dpTot_SizingFlow_kPa: 0 kPa; MagiCAD Pset_Water - dpTot_SizingFlow_kPa: 0 kPa; pTot_SizingFlow_kPa: 0 kPa; v_SizingFlow_ms: 0 m/s; MagiCAD Pset_Pipe - Length_mm: 70 mm; qv_SizingFlow_ls: 0 m3/s; Insulation_thickness_mm: 20 mm; ConnectionSize_mm: 10 mm
BI10T - Cellegummi 18-32 mm kalde rør | Nivå D + 1,2 m | BI10T - Cellegummi 18-32 mm kalde rør | 0.0160175 | 102.1 | 50 | 0.000191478 | 50 | ORIGINAL | Undefined | Stålrør normaltykke | DN | UB3.144613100 | Undefined | MagiCAD Pset_Heating - v_SizingFlow_ms: 0 m/s; pTot_SizingFlow_kPa: 0 kPa; dpTot_SizingFlow_kPa: 0 kPa; MagiCAD Pset_Water - dpTot_SizingFlow_kPa: 0 kPa; pTot_SizingFlow_kPa: 0 kPa; v_SizingFlow_ms: 0 m/s; MagiCAD Pset_Pipe - Length_mm: 102.1 mm; qv_SizingFlow_ls: 0 m3/s; Insulation_thickness_mm: 20 mm; ConnectionSize_mm: 10 mm
BI10T - Cellegummi 18-32 mm kalde rør | Nivå D + 1,2 m | BI10T - Cellegummi 18-32 mm kalde rør | 0.9567 | 5081.9 | 60 | 0.0138988 | 60 | ORIGINAL | Undefined | Stålrør normaltykke | DN | UB3.144613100 | Undefined | MagiCAD Pset_Heating - v_SizingFlow_ms: 0 m/s; pTot_SizingFlow_kPa: 0 kPa; dpTot_SizingFlow_kPa: 0 kPa; MagiCAD Pset_Water - dpTot_SizingFlow_kPa: 0 kPa; pTot_SizingFlow_kPa: 0 kPa; v_SizingFlow_ms: 0 m/s; MagiCAD Pset_Pipe - Length_mm: 5081.88 mm; qv_SizingFlow_ls: 0 m3/s; Insulation_thickness_mm: 25 mm; ConnectionSize_mm: 10 mm
BI10T - Cellegummi 18-32 mm kalde rør | Nivå D + 1,2 m | BI10T - Cellegummi 18-32 mm kalde rør | 0.0321605 | 205 | 50 | 0.000384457 | 50 | ORIGINAL | Undefined | Stålrør normaltykke | DN | UB3.144613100 | Undefined | MagiCAD Pset_Heating - v_SizingFlow_ms: 0 m/s; pTot_SizingFlow_kPa: 0 kPa; dpTot_SizingFlow_kPa: 0 kPa; MagiCAD Pset_Water - dpTot_SizingFlow_kPa: 0 kPa; pTot_SizingFlow_kPa: 0 kPa; v_SizingFlow_ms: 0 m/s; MagiCAD Pset_Pipe - Length_mm: 205 mm; qv_SizingFlow_ls: 0 m3/s; Insulation_thickness_mm: 20 mm; ConnectionSize_mm: 10 mm
BI10T - Cellegummi 18-32 mm kalde rør | Nivå D + 1,2 m | BI10T - Cellegummi 18-32 mm kalde rør | 0.0282385 | 180 | 50 | 0.000337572 | 50 | ORIGINAL | Undefined | Stålrør normaltykke | DN | UB3.144613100 | Undefined | MagiCAD Pset_Heating - v_SizingFlow_ms: 0 m/s; pTot_SizingFlow_kPa: 0 kPa; dpTot_SizingFlow_kPa: 0 kPa; MagiCAD Pset_Water - dpTot_SizingFlow_kPa: 0 kPa; pTot_SizingFlow_kPa: 0 kPa; v_SizingFlow_ms: 0 m/s; MagiCAD Pset_Pipe - Length_mm: 180 mm; qv_SizingFlow_ls: 0 m3/s; Insulation_thickness_mm: 20 mm; ConnectionSize_mm: 10 mm
BI10T - Cellegummi 18-32 mm kalde rør | Nivå D + 1,2 m | BI10T - Cellegummi 18-32 mm kalde rør | 0.0153272 | 97.7 | 50 | 0.000183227 | 50 | ORIGINAL | Undefined | Stålrør normaltykke | DN | UB3.144613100 | Undefined | MagiCAD Pset_Heating - v_SizingFlow_ms: 0 m/s; pTot_SizingFlow_kPa: 0 kPa; dpTot_SizingFlow_kPa: 0 kPa; MagiCAD Pset_Water - dpTot_SizingFlow_kPa: 0 kPa; pTot_SizingFlow_kPa: 0 kPa; v_SizingFlow_ms: 0 m/s; MagiCAD Pset_Pipe - Length_mm: 97.667 mm; qv_SizingFlow_ls: 0 m3/s; Insulation_thickness_mm: 20 mm; ConnectionSize_mm: 10 mm
BI10T - Cellegummi 18-32 mm kalde rør | Nivå D + 1,2 m | BI10T - Cellegummi 18-32 mm kalde rør | 0.283514 | 1807.2 | 50 | 0.00338922 | 50 | ORIGINAL | Undefined | Stålrør normaltykke | DN | UB3.144613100 | Undefined | MagiCAD Pset_Heating - v_SizingFlow_ms: 0 m/s; pTot_SizingFlow_kPa: 0 kPa; dpTot_SizingFlow_kPa: 0 kPa; MagiCAD Pset_Water - dpTot_SizingFlow_kPa: 0 kPa; pTot_SizingFlow_kPa: 0 kPa; v_SizingFlow_ms: 0 m/s; MagiCAD Pset_Pipe - Length_mm: 1807.24 mm; qv_SizingFlow_ls: 0 m3/s; Insulation_thickness_mm: 20 mm; ConnectionSize_mm: 10 mm
BI10T - Cellegummi 18-32 mm kalde rør | Nivå D + 1,2 m | BI10T - Cellegummi 18-32 mm kalde rør | 0.0149036 | 95 | 50 | 0.000178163 | 50 | ORIGINAL | Undefined | Stålrør normaltykke | DN | UB3.144613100 | Undefined | MagiCAD Pset_Heating - v_SizingFlow_ms: 0 m/s; pTot_SizingFlow_kPa: 0 kPa; dpTot_SizingFlow_kPa: 0 kPa; MagiCAD Pset_Water - dpTot_SizingFlow_kPa: 0 kPa; pTot_SizingFlow_kPa: 0 kPa; v_SizingFlow_ms: 0 m/s; MagiCAD Pset_Pipe - Length_mm: 95 mm; qv_SizingFlow_ls: 0 m3/s; Insulation_thickness_mm: 20 mm; ConnectionSize_mm: 10 mm
BI10T - Cellegummi 18-32 mm kalde rør | Nivå D + 1,2 m | BI10T - Cellegummi 18-32 mm kalde rør | 0.182954 | 1166.2 | 50 | 0.00218709 | 50 | ORIGINAL | Undefined | Stålrør normaltykke | DN | UB3.144613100 | Undefined | MagiCAD Pset_Heating - v_SizingFlow_ms: 0 m/s; pTot_SizingFlow_kPa: 0 kPa; dpTot_SizingFlow_kPa: 0 kPa; MagiCAD Pset_Water - dpTot_SizingFlow_kPa: 0 kPa; pTot_SizingFlow_kPa: 0 kPa; v_SizingFlow_ms: 0 m/s; MagiCAD Pset_Pipe - Length_mm: 1166.19 mm; qv_SizingFlow_ls: 0 m3/s; Insulation_thickness_mm: 20 mm; ConnectionSize_mm: 10 mm
BI10T - Cellegummi 18-32 mm kalde rør | Nivå D + 1,2 m | BI10T - Cellegummi 18-32 mm kalde rør | 0.0191551 | 122.1 | 50 | 0.000228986 | 50 | ORIGINAL | Undefined | Stålrør normaltykke | DN | UB3.144613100 | Undefined | MagiCAD Pset_Heating - v_SizingFlow_ms: 0 m/s; pTot_SizingFlow_kPa: 0 kPa; dpTot_SizingFlow_kPa: 0 kPa; MagiCAD Pset_Water - dpTot_SizingFlow_kPa: 0 kPa; pTot_SizingFlow_kPa: 0 kPa; v_SizingFlow_ms: 0 m/s; MagiCAD Pset_Pipe - Length_mm: 122.1 mm; qv_SizingFlow_ls: 0 m3/s; Insulation_thickness_mm: 20 mm; ConnectionSize_mm: 10 mm
2 x BI10T - Cellegummi 18-32 mm kalde rør | Nivå D + 1,2 m | BI10T - Cellegummi 18-32 mm kalde rør | 0.0023738 | 57.2 | 34.4 | 0.0000816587 | 41.5 | ORIGINAL | MagiCAD Pset_TBranch - qv_SizingFlow_ls: 0 m3/s; pTot_SizingFlow_Pa: 0 kPa; dpTot_SizingFlow_Pa: 0 kPa; v_SizingFlow_ms: 0 m/s; ConnectionSize_mm: 0 mm; Insulation_thickness_mm: 20 mm
BI10T - Cellegummi 18-32 mm kalde rør | Nivå D + 1,2 m | BI10T - Cellegummi 18-32 mm kalde rør | 0.00680861 | 43.4 | 50 | 0.0000813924 | 50 | ORIGINAL | Undefined | Stålrør normaltykke | DN | UB3.144613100 | Undefined | MagiCAD Pset_Heating - v_SizingFlow_ms: 0 m/s; pTot_SizingFlow_kPa: 0 kPa; dpTot_SizingFlow_kPa: 0 kPa; MagiCAD Pset_Water - dpTot_SizingFlow_kPa: 0 kPa; pTot_SizingFlow_kPa: 0 kPa; v_SizingFlow_ms: 0 m/s; MagiCAD Pset_Pipe - Length_mm: 43.361 mm; qv_SizingFlow_ls: 0 m3/s; Insulation_thickness_mm: 20 mm; ConnectionSize_mm: 10 mm
BI10T - Cellegummi 18-32 mm kalde rør | Nivå D + 1,2 m | BI10T - Cellegummi 18-32 mm kalde rør | 0.0251009 | 160 | 50 | 0.000300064 | 50 | ORIGINAL | Undefined | Stålrør normaltykke | DN | UB3.144613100 | Undefined | MagiCAD Pset_Heating - v_SizingFlow_ms: 0 m/s; pTot_SizingFlow_kPa: 0 kPa; dpTot_SizingFlow_kPa: 0 kPa; MagiCAD Pset_Water - dpTot_SizingFlow_kPa: 0 kPa; pTot_SizingFlow_kPa: 0 kPa; v_SizingFlow_ms: 0 m/s; MagiCAD Pset_Pipe - Length_mm: 160 mm; qv_SizingFlow_ls: 0 m3/s; Insulation_thickness_mm: 20 mm; ConnectionSize_mm: 10 mm
BI10T - Cellegummi 18-32 mm kalde rør | Nivå D + 1,2 m | BI10T - Cellegummi 18-32 mm kalde rør | 0.0450403 | 287.1 | 50 | 0.000538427 | 50 | ORIGINAL | Undefined | Stålrør normaltykke | DN | UB3.144613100 | Undefined | MagiCAD Pset_Heating - v_SizingFlow_ms: 0 m/s; pTot_SizingFlow_kPa: 0 kPa; dpTot_SizingFlow_kPa: 0 kPa; MagiCAD Pset_Water - dpTot_SizingFlow_kPa: 0 kPa; pTot_SizingFlow_kPa: 0 kPa; v_SizingFlow_ms: 0 m/s; MagiCAD Pset_Pipe - Length_mm: 287.1 mm; qv_SizingFlow_ls: 0 m3/s; Insulation_thickness_mm: 20 mm; ConnectionSize_mm: 10 mm
BI10T - Cellegummi 18-32 mm kalde rør | Nivå D + 1,2 m | BI10T - Cellegummi 18-32 mm kalde rør | 0.0171627 | 109.4 | 50 | 0.000205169 | 50 | ORIGINAL | Undefined | Stålrør normaltykke | DN | UB3.144613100 | Undefined | MagiCAD Pset_Heating - v_SizingFlow_ms: 0 m/s; pTot_SizingFlow_kPa: 0 kPa; dpTot_SizingFlow_kPa: 0 kPa; MagiCAD Pset_Water - dpTot_SizingFlow_kPa: 0 kPa; pTot_SizingFlow_kPa: 0 kPa; v_SizingFlow_ms: 0 m/s; MagiCAD Pset_Pipe - Length_mm: 109.408 mm; qv_SizingFlow_ls: 0 m3/s; Insulation_thickness_mm: 20 mm; ConnectionSize_mm: 10 mm
BI15T - Cellegummi KV 15mm | Nivå D + 1,2 m | BI15T - Cellegummi KV 15mm | 0.263284 | 1907.1 | 44 | 0.00240227 | 44 | ORIGINAL | KJØL T | Kobberrør | Cu | UB1.111713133 | Hydronic Supply | MagiCAD Pset_Heating - v_SizingFlow_ms: 0 m/s; pTot_SizingFlow_kPa: 0 kPa; dpTot_SizingFlow_kPa: 0 kPa; MagiCAD Pset_Water - dpTot_SizingFlow_kPa: 0 kPa; pTot_SizingFlow_kPa: 0 kPa; v_SizingFlow_ms: 0 m/s; MagiCAD Pset_Pipe - Length_mm: 1907.1 mm; qv_SizingFlow_ls: 0 m3/s; SystemName: 37= T 9° Kopi 168; Insulation_thickness_mm: 13 mm; ConnectionSize_mm: 18 mm
BI15T - Cellegummi KV 15mm | Nivå D + 1,2 m | BI15T - Cellegummi KV 15mm | 0.00394651 | 46 | 43 | 0.0000228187 | 43 | ORIGINAL | MagiCAD Pset_Elbow - qv_SizingFlow_ls: 0 m3/s; pTot_SizingFlow_Pa: 0 kPa; dpTot_SizingFlow_Pa: 0 kPa; v_SizingFlow_ms: 0 m/s; ConnectionSize_mm: 0 mm; Insulation_thickness_mm: 13 mm
BI10T - Cellegummi 18-32 mm kalde rør | Nivå D + 1,2 m | BI10T - Cellegummi 18-32 mm kalde rør | 0.193321 | 456.4 | 135 | 0.00499294 | 135 | ORIGINAL | VARME T | Stålrør normaltykke | DN | UB3.144613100 | Hydronic Supply | MagiCAD Pset_Heating - v_SizingFlow_ms: 0 m/s; pTot_SizingFlow_kPa: 0 kPa; dpTot_SizingFlow_kPa: 0 kPa; MagiCAD Pset_Water - dpTot_SizingFlow_kPa: 0 kPa; pTot_SizingFlow_kPa: 0 kPa; v_SizingFlow_ms: 0 m/s; MagiCAD Pset_Pipe - Length_mm: 456.355 mm; qv_SizingFlow_ls: 0 m3/s; SystemName: +TG=320.000.T; Insulation_thickness_mm: 35 mm; ConnectionSize_mm: 65 mm
BI10T - Cellegummi 18-32 mm kalde rør | Nivå D + 1,2 m | BI10T - Cellegummi 18-32 mm kalde rør | 0.017409 | 41.1 | 135 | 0.000449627 | 135 | ORIGINAL | Undefined | Stålrør normaltykke | DN | UB3.144613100 | Undefined | MagiCAD Pset_Heating - v_SizingFlow_ms: 0 m/s; pTot_SizingFlow_kPa: 0 kPa; dpTot_SizingFlow_kPa: 0 kPa; MagiCAD Pset_Water - dpTot_SizingFlow_kPa: 0 kPa; pTot_SizingFlow_kPa: 0 kPa; v_SizingFlow_ms: 0 m/s; MagiCAD Pset_Pipe - Length_mm: 41.133 mm; qv_SizingFlow_ls: 0 m3/s; Insulation_thickness_mm: 35 mm; ConnectionSize_mm: 65 mm
BI10T - Cellegummi 18-32 mm kalde rør | Nivå D + 1,2 m | BI10T - Cellegummi 18-32 mm kalde rør | 0.0430241 | 135 | 132.5 | 0.00143552 | 132.5 | ORIGINAL | MagiCAD Pset_Elbow - qv_SizingFlow_ls: 0 m3/s; pTot_SizingFlow_Pa: 0 kPa; dpTot_SizingFlow_Pa: 0 kPa; v_SizingFlow_ms: 0 m/s; ConnectionSize_mm: 0 mm; Insulation_thickness_mm: 35 mm
BI10T - Cellegummi 18-32 mm kalde rør | Nivå D + 1,2 m | BI10T - Cellegummi 18-32 mm kalde rør | 0.0703561 | 166.1 | 135 | 0.00181711 | 135 | ORIGINAL | VARME R | Stålrør normaltykke | DN | UB3.144613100 | Hydronic Return | MagiCAD Pset_Heating - v_SizingFlow_ms: 0 m/s; pTot_SizingFlow_kPa: 0 kPa; dpTot_SizingFlow_kPa: 0 kPa; MagiCAD Pset_Water - dpTot_SizingFlow_kPa: 0 kPa; pTot_SizingFlow_kPa: 0 kPa; v_SizingFlow_ms: 0 m/s; MagiCAD Pset_Pipe - Length_mm: 166.139 mm; qv_SizingFlow_ls: 0 m3/s; SystemName: +TG=320.000.R; Insulation_thickness_mm: 35 mm; ConnectionSize_mm: 65 mm
BI10T - Cellegummi 18-32 mm kalde rør | Nivå D + 1,2 m | BI10T - Cellegummi 18-32 mm kalde rør | 0.0146981 | 34.7 | 135 | 0.000379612 | 135 | ORIGINAL | Undefined | Stålrør normaltykke | DN | UB3.144613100 | Undefined | MagiCAD Pset_Heating - v_SizingFlow_ms: 0 m/s; pTot_SizingFlow_kPa: 0 kPa; dpTot_SizingFlow_kPa: 0 kPa; MagiCAD Pset_Water - dpTot_SizingFlow_kPa: 0 kPa; pTot_SizingFlow_kPa: 0 kPa; v_SizingFlow_ms: 0 m/s; MagiCAD Pset_Pipe - Length_mm: 34.597 mm; qv_SizingFlow_ls: 0 m3/s; Insulation_thickness_mm: 35 mm; ConnectionSize_mm: 65 mm
BI10T - Cellegummi 18-32 mm kalde rør | Nivå D + 1,2 m | BI10T - Cellegummi 18-32 mm kalde rør | 0.0178766 | 135 | 93.6918 | 0.000718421 | 132.407 | ORIGINAL | MagiCAD Pset_Elbow - qv_SizingFlow_ls: 0 m3/s; pTot_SizingFlow_Pa: 0 kPa; dpTot_SizingFlow_Pa: 0 kPa; v_SizingFlow_ms: 0 m/s; ConnectionSize_mm: 0 mm; Insulation_thickness_mm: 35 mm
BI10T - Cellegummi 18-32 mm kalde rør | Nivå D + 1,2 m | BI10T - Cellegummi 18-32 mm kalde rør | 0.0430279 | 135 | 132.5 | 0.00143564 | 132.5 | ORIGINAL | MagiCAD Pset_Elbow - qv_SizingFlow_ls: 0 m3/s; pTot_SizingFlow_Pa: 0 kPa; dpTot_SizingFlow_Pa: 0 kPa; v_SizingFlow_ms: 0 m/s; ConnectionSize_mm: 0 mm; Insulation_thickness_mm: 35 mm
BI10T - Cellegummi 18-32 mm kalde rør | Nivå D + 1,2 m | BI10T - Cellegummi 18-32 mm kalde rør | 0.0178766 | 135 | 132.407 | 0.000718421 | 93.6918 | ORIGINAL | MagiCAD Pset_Elbow - qv_SizingFlow_ls: 0 m3/s; pTot_SizingFlow_Pa: 0 kPa; dpTot_SizingFlow_Pa: 0 kPa; v_SizingFlow_ms: 0 m/s; ConnectionSize_mm: 0 mm; Insulation_thickness_mm: 35 mm
BI10T - Cellegummi 18-32 mm kalde rør | Nivå D + 1,2 m | BI10T - Cellegummi 18-32 mm kalde rør | 0.224538 | 530.1 | 135 | 0.00579921 | 135 | ORIGINAL | Undefined | Stålrør normaltykke | DN | UB3.144613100 | Undefined | MagiCAD Pset_Heating - v_SizingFlow_ms: 0 m/s; pTot_SizingFlow_kPa: 0 kPa; dpTot_SizingFlow_kPa: 0 kPa; MagiCAD Pset_Water - dpTot_SizingFlow_kPa: 0 kPa; pTot_SizingFlow_kPa: 0 kPa; v_SizingFlow_ms: 0 m/s; MagiCAD Pset_Pipe - Length_mm: 530.123 mm; qv_SizingFlow_ls: 0 m3/s; Insulation_thickness_mm: 35 mm; ConnectionSize_mm: 65 mm
BI10T - Cellegummi 18-32 mm kalde rør | Nivå D + 1,2 m | BI10T - Cellegummi 18-32 mm kalde rør | 1.40632 | 3320.1 | 135 | 0.0363213 | 135 | ORIGINAL | Undefined | Stålrør normaltykke | DN | UB3.144613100 | Undefined | MagiCAD Pset_Heating - v_SizingFlow_ms: 0 m/s; pTot_SizingFlow_kPa: 0 kPa; dpTot_SizingFlow_kPa: 0 kPa; MagiCAD Pset_Water - dpTot_SizingFlow_kPa: 0 kPa; pTot_SizingFlow_kPa: 0 kPa; v_SizingFlow_ms: 0 m/s; MagiCAD Pset_Pipe - Length_mm: 3320.13 mm; qv_SizingFlow_ls: 0 m3/s; Insulation_thickness_mm: 35 mm; ConnectionSize_mm: 65 mm
BI10T - Cellegummi 18-32 mm kalde rør | Nivå D + 1,2 m | BI10T - Cellegummi 18-32 mm kalde rør | 0.0366818 | 86.6 | 135 | 0.00094739 | 135 | ORIGINAL | Undefined | Stålrør normaltykke | DN | UB3.144613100 | Undefined | MagiCAD Pset_Heating - v_SizingFlow_ms: 0 m/s; pTot_SizingFlow_kPa: 0 kPa; dpTot_SizingFlow_kPa: 0 kPa; MagiCAD Pset_Water - dpTot_SizingFlow_kPa: 0 kPa; pTot_SizingFlow_kPa: 0 kPa; v_SizingFlow_ms: 0 m/s; MagiCAD Pset_Pipe - Length_mm: 86.844 mm; qv_SizingFlow_ls: 0 m3/s; Insulation_thickness_mm: 35 mm; ConnectionSize_mm: 65 mm
BI10T - Cellegummi 18-32 mm kalde rør | Nivå D + 1,2 m | BI10T - Cellegummi 18-32 mm kalde rør | 0.0429795 | 135 | 132.5 | 0.00143404 | 132.5 | ORIGINAL | MagiCAD Pset_Elbow - qv_SizingFlow_ls: 0 m3/s; pTot_SizingFlow_Pa: 0 kPa; dpTot_SizingFlow_Pa: 0 kPa; v_SizingFlow_ms: 0 m/s; ConnectionSize_mm: 0 mm; Insulation_thickness_mm: 35 mm
2 x BI10T - Cellegummi 18-32 mm kalde rør | Nivå D + 1,2 m | BI10T - Cellegummi 18-32 mm kalde rør | 0.043031 | 135 | 132.5 | 0.00143575 | 132.5 | ORIGINAL | MagiCAD Pset_Elbow - qv_SizingFlow_ls: 0 m3/s; pTot_SizingFlow_Pa: 0 kPa; dpTot_SizingFlow_Pa: 0 kPa; v_SizingFlow_ms: 0 m/s; ConnectionSize_mm: 0 mm; Insulation_thickness_mm: 35 mm
BI17T - Cellegummi 13 mm SPV fett | Nivå D + 1,2 m | BI17T - Cellegummi 13 mm SPV fett | 0.362373 | 1143.5 | 101 | 0.00408889 | 101 | ORIGINAL | SPV FETT | MA | MA | UB2.1115131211 | Sanitary | MagiCAD Pset_Heating - v_SizingFlow_ms: 0 m/s; pTot_SizingFlow_kPa: 0 kPa; dpTot_SizingFlow_kPa: 0 kPa; MagiCAD Pset_Water - dpTot_SizingFlow_kPa: 0 kPa; pTot_SizingFlow_kPa: 0 kPa; v_SizingFlow_ms: 0 m/s; MagiCAD Pset_Pipe - Length_mm: 1143.47 mm; qv_SizingFlow_ls: 0 m3/s; SystemName: 31= SPV Kopi 138; Insulation_thickness_mm: 13 mm; ConnectionSize_mm: 75 mm
BI17T - Cellegummi 13 mm SPV fett | Nivå D + 1,2 m | BI17T - Cellegummi 13 mm SPV fett | 0.0201864 | 63.7 | 101 | 0.000227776 | 101 | ORIGINAL | SPV FETT | MA | MA | UB2.1115131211 | Sanitary | MagiCAD Pset_Heating - v_SizingFlow_ms: 0 m/s; pTot_SizingFlow_kPa: 0 kPa; dpTot_SizingFlow_kPa: 0 kPa; MagiCAD Pset_Water - dpTot_SizingFlow_kPa: 0 kPa; pTot_SizingFlow_kPa: 0 kPa; v_SizingFlow_ms: 0 m/s; MagiCAD Pset_Pipe - Length_mm: 63.701 mm; qv_SizingFlow_ls: 0 m3/s; SystemName: 31= SPV Kopi 138; Insulation_thickness_mm: 13 mm; ConnectionSize_mm: 75 mm
BI17T - Cellegummi 13 mm SPV fett | Nivå D + 1,2 m | BI17T - Cellegummi 13 mm SPV fett | 0.743792 | 2347.1 | 101 | 0.00839267 | 101 | ORIGINAL | SPV FETT | MA | MA | UB2.1115131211 | Sanitary | MagiCAD Pset_Heating - v_SizingFlow_ms: 0 m/s; pTot_SizingFlow_kPa: 0 kPa; dpTot_SizingFlow_kPa: 0 kPa; MagiCAD Pset_Water - dpTot_SizingFlow_kPa: 0 kPa; pTot_SizingFlow_kPa: 0 kPa; v_SizingFlow_ms: 0 m/s; MagiCAD Pset_Pipe - Length_mm: 2347.07 mm; qv_SizingFlow_ls: 0 m3/s; SystemName: 31= SPV Kopi 138; Insulation_thickness_mm: 13 mm; ConnectionSize_mm: 75 mm
BI17T - Cellegummi 13 mm SPV fett | Nivå D + 1,2 m | BI17T - Cellegummi 13 mm SPV fett | 0.041296 | 126.044 | 111 | 0.00136407 | 119.549 | ORIGINAL | MagiCAD Pset_TBranch - qv_SizingFlow_ls: 0 m3/s; pTot_SizingFlow_Pa: 0 kPa; dpTot_SizingFlow_Pa: 0 kPa; v_SizingFlow_ms: 0 m/s; ConnectionSize_mm: 0 mm; Insulation_thickness_mm: 13 mm
BI17T - Cellegummi 13 mm SPV fett | Nivå D + 1,2 m | BI17T - Cellegummi 13 mm SPV fett | 0.0271899 | 85.8 | 101 | 0.0003068 | 101 | ORIGINAL | SPV FETT | MA | MA | UB2.1115131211 | Sanitary | MagiCAD Pset_Heating - v_SizingFlow_ms: 0 m/s; pTot_SizingFlow_kPa: 0 kPa; dpTot_SizingFlow_kPa: 0 kPa; MagiCAD Pset_Water - dpTot_SizingFlow_kPa: 0 kPa; pTot_SizingFlow_kPa: 0 kPa; v_SizingFlow_ms: 0 m/s; MagiCAD Pset_Pipe - Length_mm: 85.841 mm; qv_SizingFlow_ls: 0 m3/s; SystemName: 31= SPV Kopi 138; Insulation_thickness_mm: 13 mm; ConnectionSize_mm: 75 mm
BI17T - Cellegummi 13 mm SPV fett | Nivå D + 1,2 m | BI17T - Cellegummi 13 mm SPV fett | 0.123495 | 389.7 | 101 | 0.00139347 | 101 | ORIGINAL | SPV FETT | MA | MA | UB2.1115131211 | Sanitary | MagiCAD Pset_Heating - v_SizingFlow_ms: 0 m/s; pTot_SizingFlow_kPa: 0 kPa; dpTot_SizingFlow_kPa: 0 kPa; MagiCAD Pset_Water - dpTot_SizingFlow_kPa: 0 kPa; pTot_SizingFlow_kPa: 0 kPa; v_SizingFlow_ms: 0 m/s; MagiCAD Pset_Pipe - Length_mm: 389.743 mm; qv_SizingFlow_ls: 0 m3/s; SystemName: 31= SPV Kopi 138; Insulation_thickness_mm: 13 mm; ConnectionSize_mm: 75 mm
BI17T - Cellegummi 13 mm SPV fett | Nivå D + 1,2 m | BI17T - Cellegummi 13 mm SPV fett | 0.0156317 | 116.772 | 96.6857 | 0.000589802 | 108.5 | ORIGINAL | MagiCAD Pset_Elbow - Description: Generic PVC Bend; qv_SizingFlow_ls: 0 m3/s; pTot_SizingFlow_Pa: 0 kPa; dpTot_SizingFlow_Pa: 0 kPa; v_SizingFlow_ms: 0 m/s; ConnectionSize_mm: 0 mm; Insulation_thickness_mm: 13 mm
BI17T - Cellegummi 13 mm SPV fett | Nivå D + 1,2 m | BI17T - Cellegummi 13 mm SPV fett | 0.152872 | 482.4 | 101 | 0.00172495 | 101 | ORIGINAL | SPV FETT | MA | MA | UB2.1115131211 | Sanitary | MagiCAD Pset_Heating - v_SizingFlow_ms: 0 m/s; pTot_SizingFlow_kPa: 0 kPa; dpTot_SizingFlow_kPa: 0 kPa; MagiCAD Pset_Water - dpTot_SizingFlow_kPa: 0 kPa; pTot_SizingFlow_kPa: 0 kPa; v_SizingFlow_ms: 0 m/s; MagiCAD Pset_Pipe - Length_mm: 481.495 mm; qv_SizingFlow_ls: 0 m3/s; SystemName: 31= SPV Kopi 138; Insulation_thickness_mm: 13 mm; ConnectionSize_mm: 75 mm
BI17T - Cellegummi 13 mm SPV fett | Nivå D + 1,2 m | BI17T - Cellegummi 13 mm SPV fett | 0.0331478 | 141.75 | 118.5 | 0.00135016 | 141.75 | ORIGINAL | MagiCAD Pset_Elbow - Description: Generic PVC Bend; qv_SizingFlow_ls: 0 m3/s; pTot_SizingFlow_Pa: 0 kPa; dpTot_SizingFlow_Pa: 0 kPa; v_SizingFlow_ms: 0 m/s; ConnectionSize_mm: 0 mm; Insulation_thickness_mm: 13 mm
BI17T - Cellegummi 13 mm SPV fett | Nivå D + 1,2 m | BI17T - Cellegummi 13 mm SPV fett | 0.0459679 | 141.73 | 118.5 | 0.00133788 | 141.363 | ORIGINAL | MagiCAD Pset_Elbow - Description: Generic PVC Bend; qv_SizingFlow_ls: 0 m3/s; pTot_SizingFlow_Pa: 0 kPa; dpTot_SizingFlow_Pa: 0 kPa; v_SizingFlow_ms: 0 m/s; ConnectionSize_mm: 0 mm; Insulation_thickness_mm: 13 mm
BI10T - Cellegummi 18-32 mm kalde rør | Nivå D + 1,2 m | BI10T - Cellegummi 18-32 mm kalde rør | 0.0405617 | 307.8 | 42 | 0.000389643 | 42 | ORIGINAL | VV | Kobberrør | Cu | UB1.111713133 | Domestic Hot Water | MagiCAD Pset_Heating - v_SizingFlow_ms: 0 m/s; pTot_SizingFlow_kPa: 0 kPa; dpTot_SizingFlow_kPa: 0 kPa; MagiCAD Pset_Water - dpTot_SizingFlow_kPa: 0 kPa; pTot_SizingFlow_kPa: 0 kPa; v_SizingFlow_ms: 0 m/s; MagiCAD Pset_Pipe - Length_mm: 307.843 mm; qv_SizingFlow_ls: 0 m3/s; SystemName: 31= VV Kopi 41; Insulation_thickness_mm: 15 mm; ConnectionSize_mm: 12 mm
BI10T - Cellegummi 18-32 mm kalde rør | Nivå D + 1,2 m | BI10T - Cellegummi 18-32 mm kalde rør | 0.0110299 | 83.7 | 42 | 0.000105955 | 42 | ORIGINAL | VV | Kobberrør | Cu | UB1.111713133 | Domestic Hot Water | MagiCAD Pset_Heating - v_SizingFlow_ms: 0 m/s; pTot_SizingFlow_kPa: 0 kPa; dpTot_SizingFlow_kPa: 0 kPa; MagiCAD Pset_Water - dpTot_SizingFlow_kPa: 0 kPa; pTot_SizingFlow_kPa: 0 kPa; v_SizingFlow_ms: 0 m/s; MagiCAD Pset_Pipe - Length_mm: 83.7 mm; qv_SizingFlow_ls: 0 m3/s; SystemName: 31= VV Kopi 41; Insulation_thickness_mm: 15 mm; ConnectionSize_mm: 12 mm
BI10T - Cellegummi 18-32 mm kalde rør | Nivå D + 1,2 m | BI10T - Cellegummi 18-32 mm kalde rør | 0.00261893 | 42 | 33 | 0.0000267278 | 33 | ORIGINAL | MagiCAD Pset_Elbow - qv_SizingFlow_ls: 0 m3/s; pTot_SizingFlow_Pa: 0 kPa; dpTot_SizingFlow_Pa: 0 kPa; v_SizingFlow_ms: 0 m/s; ConnectionSize_mm: 0 mm; Insulation_thickness_mm: 15 mm
BI10T - Cellegummi 18-32 mm kalde rør | Nivå D + 1,2 m | BI10T - Cellegummi 18-32 mm kalde rør | 0.0210847 | 160 | 42 | 0.000202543 | 42 | ORIGINAL | Undefined | Kobberrør | Cu | UB1.111713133 | Undefined | MagiCAD Pset_Heating - v_SizingFlow_ms: 0 m/s; pTot_SizingFlow_kPa: 0 kPa; dpTot_SizingFlow_kPa: 0 kPa; MagiCAD Pset_Water - dpTot_SizingFlow_kPa: 0 kPa; pTot_SizingFlow_kPa: 0 kPa; v_SizingFlow_ms: 0 m/s; MagiCAD Pset_Pipe - Length_mm: 160 mm; qv_SizingFlow_ls: 0 m3/s; Insulation_thickness_mm: 15 mm; ConnectionSize_mm: 12 mm
BI15T - Cellegummi KV 15mm | Nivå D + 1,2 m | BI15T - Cellegummi KV 15mm | 0.00209088 | 8.8 | 52.8 | 0.0000183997 | 52.8 | ORIGINAL | MagiCAD Pset_Reduction - qv_SizingFlow_ls: 0 m3/s; pTot_SizingFlow_Pa: 0 kPa; dpTot_SizingFlow_Pa: 0 kPa; v_SizingFlow_ms: 0 m/s; ConnectionSize_mm: 0 mm; Insulation_thickness_mm: 13 mm
BI15T - Cellegummi KV 15mm | Nivå D + 1,2 m | BI15T - Cellegummi KV 15mm | 0.00415152 | 74.4 | 74.4 | 0.0000896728 | 21.6 | ORIGINAL | MagiCAD Pset_Reduction - qv_SizingFlow_ls: 0 m3/s; pTot_SizingFlow_Pa: 0 kPa; dpTot_SizingFlow_Pa: 0 kPa; v_SizingFlow_ms: 0 m/s; ConnectionSize_mm: 0 mm; Insulation_thickness_mm: 13 mm
BI15T - Cellegummi KV 15mm | Nivå D + 1,2 m | BI15T - Cellegummi KV 15mm | 0.00299579 | 21.7 | 44 | 0.0000273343 | 44 | ORIGINAL | KJØL T | Kobberrør | Cu | UB1.111713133 | Hydronic Supply | MagiCAD Pset_Heating - v_SizingFlow_ms: 0 m/s; pTot_SizingFlow_kPa: 0 kPa; dpTot_SizingFlow_kPa: 0 kPa; MagiCAD Pset_Water - dpTot_SizingFlow_kPa: 0 kPa; pTot_SizingFlow_kPa: 0 kPa; v_SizingFlow_ms: 0 m/s; MagiCAD Pset_Pipe - Length_mm: 21.739 mm; qv_SizingFlow_ls: 0 m3/s; SystemName: 37= T 9° Kopi 168; Insulation_thickness_mm: 13 mm; ConnectionSize_mm: 18 mm
BI15T - Cellegummi KV 15mm | Nivå D + 1,2 m | BI15T - Cellegummi KV 15mm | 0.00125964 | 6.4 | 44 | 0.00000806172 | 44 | ORIGINAL | KJØL T | Kobberrør | Cu | UB1.111713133 | Hydronic Supply | MagiCAD Pset_Heating - v_SizingFlow_ms: 0 m/s; pTot_SizingFlow_kPa: 0 kPa; dpTot_SizingFlow_kPa: 0 kPa; MagiCAD Pset_Water - dpTot_SizingFlow_kPa: 0 kPa; pTot_SizingFlow_kPa: 0 kPa; v_SizingFlow_ms: 0 m/s; MagiCAD Pset_Pipe - Length_mm: 6.354 mm; qv_SizingFlow_ls: 0 m3/s; SystemName: 37= T 9° Kopi 168; Insulation_thickness_mm: 13 mm; ConnectionSize_mm: 18 mm
BI15T - Cellegummi KV 15mm | Nivå D + 1,2 m | BI15T - Cellegummi KV 15mm | 0.00184993 | 13.4 | 44 | 0.0000168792 | 44 | ORIGINAL | KJØL T | Kobberrør | Cu | UB1.111713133 | Hydronic Supply | MagiCAD Pset_Heating - v_SizingFlow_ms: 0 m/s; pTot_SizingFlow_kPa: 0 kPa; dpTot_SizingFlow_kPa: 0 kPa; MagiCAD Pset_Water - dpTot_SizingFlow_kPa: 0 kPa; pTot_SizingFlow_kPa: 0 kPa; v_SizingFlow_ms: 0 m/s; MagiCAD Pset_Pipe - Length_mm: 13.373 mm; qv_SizingFlow_ls: 0 m3/s; SystemName: 37= T 9° Kopi 168; Insulation_thickness_mm: 13 mm; ConnectionSize_mm: 18 mm
2 x BI15T - Cellegummi KV 15mm | Nivå D + 1,2 m | BI15T - Cellegummi KV 15mm | 0.00143555 | 44 | 16.9047 | 0.0000117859 | 39.8845 | ORIGINAL | MagiCAD Pset_Elbow - qv_SizingFlow_ls: 0 m3/s; pTot_SizingFlow_Pa: 0 kPa; dpTot_SizingFlow_Pa: 0 kPa; v_SizingFlow_ms: 0 m/s; ConnectionSize_mm: 0 mm; Insulation_thickness_mm: 13 mm
BI15T - Cellegummi KV 15mm | Nivå D + 1,2 m | BI15T - Cellegummi KV 15mm | 0.00172268 | 44 | 28.2843 | 0.0000211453 | 39.9099 | ORIGINAL | MagiCAD Pset_Elbow - qv_SizingFlow_ls: 0 m3/s; pTot_SizingFlow_Pa: 0 kPa; dpTot_SizingFlow_Pa: 0 kPa; v_SizingFlow_ms: 0 m/s; ConnectionSize_mm: 0 mm; Insulation_thickness_mm: 13 mm
BI15T - Cellegummi KV 15mm | Nivå D + 1,2 m | BI15T - Cellegummi KV 15mm | 0.00172268 | 44 | 39.9099 | 0.0000211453 | 28.2843 | ORIGINAL | MagiCAD Pset_Elbow - qv_SizingFlow_ls: 0 m3/s; pTot_SizingFlow_Pa: 0 kPa; dpTot_SizingFlow_Pa: 0 kPa; v_SizingFlow_ms: 0 m/s; ConnectionSize_mm: 0 mm; Insulation_thickness_mm: 13 mm
BI10T - Cellegummi 18-32 mm kalde rør | Nivå D + 1,2 m | BI10T - Cellegummi 18-32 mm kalde rør | 0.439842 | 1038.4 | 135 | 0.0113599 | 135 | ORIGINAL | VARME T | Stålrør normaltykke | DN | UB3.144613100 | Hydronic Supply | MagiCAD Pset_Heating - v_SizingFlow_ms: 0 m/s; pTot_SizingFlow_kPa: 0 kPa; dpTot_SizingFlow_kPa: 0 kPa; MagiCAD Pset_Water - dpTot_SizingFlow_kPa: 0 kPa; pTot_SizingFlow_kPa: 0 kPa; v_SizingFlow_ms: 0 m/s; MagiCAD Pset_Pipe - Length_mm: 1038.36 mm; qv_SizingFlow_ls: 0 m3/s; SystemName: +TG=320.000.T; Insulation_thickness_mm: 35 mm; ConnectionSize_mm: 65 mm
BI10T - Cellegummi 18-32 mm kalde rør | Nivå D + 1,2 m | BI10T - Cellegummi 18-32 mm kalde rør | 0.0575641 | 135.9 | 135 | 0.00148672 | 135 | ORIGINAL | VARME R | Stålrør normaltykke | DN | UB3.144613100 | Hydronic Return | MagiCAD Pset_Heating - v_SizingFlow_ms: 0 m/s; pTot_SizingFlow_kPa: 0 kPa; dpTot_SizingFlow_kPa: 0 kPa; MagiCAD Pset_Water - dpTot_SizingFlow_kPa: 0 kPa; pTot_SizingFlow_kPa: 0 kPa; v_SizingFlow_ms: 0 m/s; MagiCAD Pset_Pipe - Length_mm: 135.892 mm; qv_SizingFlow_ls: 0 m3/s; SystemName: +TG=320.000.R; Insulation_thickness_mm: 35 mm; ConnectionSize_mm: 65 mm
BI10T - Cellegummi 18-32 mm kalde rør | Nivå D + 1,2 m | BI10T - Cellegummi 18-32 mm kalde rør | 0.0542602 | 128.1 | 135 | 0.00140139 | 135 | ORIGINAL | VARME T | Stålrør normaltykke | DN | UB3.144613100 | Hydronic Supply | MagiCAD Pset_Heating - v_SizingFlow_ms: 0 m/s; pTot_SizingFlow_kPa: 0 kPa; dpTot_SizingFlow_kPa: 0 kPa; MagiCAD Pset_Water - dpTot_SizingFlow_kPa: 0 kPa; pTot_SizingFlow_kPa: 0 kPa; v_SizingFlow_ms: 0 m/s; MagiCAD Pset_Pipe - Length_mm: 128.067 mm; qv_SizingFlow_ls: 0 m3/s; SystemName: +TG=320.000.T; Insulation_thickness_mm: 35 mm; ConnectionSize_mm: 65 mm
2 x BI10T - Cellegummi 18-32 mm kalde rør | Nivå D + 1,2 m | BI10T - Cellegummi 18-32 mm kalde rør | 0.0163593 | 33.8 | 146.2 | 0.000552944 | 146.2 | ORIGINAL | MagiCAD Pset_Reduction - qv_SizingFlow_ls: 0 m3/s; pTot_SizingFlow_Pa: 0 kPa; dpTot_SizingFlow_Pa: 0 kPa; v_SizingFlow_ms: 0 m/s; ConnectionSize_mm: 0 mm; Insulation_thickness_mm: 35 mm
BI17T - Cellegummi 13 mm SPV fett | Nivå D + 1,2 m | BI17T - Cellegummi 13 mm SPV fett | 0.0331523 | 141.75 | 141.75 | 0.00135065 | 118.5 | ORIGINAL | MagiCAD Pset_Elbow - Description: Generic PVC Bend; qv_SizingFlow_ls: 0 m3/s; pTot_SizingFlow_Pa: 0 kPa; dpTot_SizingFlow_Pa: 0 kPa; v_SizingFlow_ms: 0 m/s; ConnectionSize_mm: 0 mm; Insulation_thickness_mm: 13 mm
BI10T - Cellegummi 18-32 mm kalde rør | Nivå D + 1,2 m | BI10T - Cellegummi 18-32 mm kalde rør | 0.0763267 | 579.2 | 42 | 0.000733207 | 42 | ORIGINAL | VV | Kobberrør | Cu | UB1.111713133 | Domestic Hot Water | MagiCAD Pset_Heating - v_SizingFlow_ms: 0 m/s; pTot_SizingFlow_kPa: 0 kPa; dpTot_SizingFlow_kPa: 0 kPa; MagiCAD Pset_Water - dpTot_SizingFlow_kPa: 0 kPa; pTot_SizingFlow_kPa: 0 kPa; v_SizingFlow_ms: 0 m/s; MagiCAD Pset_Pipe - Length_mm: 579.186 mm; qv_SizingFlow_ls: 0 m3/s; SystemName: 31= VV Kopi 41; Insulation_thickness_mm: 15 mm; ConnectionSize_mm: 12 mm
BI10T - Cellegummi 18-32 mm kalde rør | Nivå D + 1,2 m | BI10T - Cellegummi 18-32 mm kalde rør | 0.414908 | 3148.5 | 42 | 0.00398567 | 42 | ORIGINAL | VV | Kobberrør | Cu | UB1.111713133 | Domestic Hot Water | MagiCAD Pset_Heating - v_SizingFlow_ms: 0 m/s; pTot_SizingFlow_kPa: 0 kPa; dpTot_SizingFlow_kPa: 0 kPa; MagiCAD Pset_Water - dpTot_SizingFlow_kPa: 0 kPa; pTot_SizingFlow_kPa: 0 kPa; v_SizingFlow_ms: 0 m/s; MagiCAD Pset_Pipe - Length_mm: 3148.5 mm; qv_SizingFlow_ls: 0 m3/s; SystemName: 31= VV Kopi 41; Insulation_thickness_mm: 15 mm; ConnectionSize_mm: 12 mm
BI10T - Cellegummi 18-32 mm kalde rør | Nivå D + 1,2 m | BI10T - Cellegummi 18-32 mm kalde rør | 0.0288992 | 219.3 | 42 | 0.000277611 | 42 | ORIGINAL | VV | Kobberrør | Cu | UB1.111713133 | Domestic Hot Water | MagiCAD Pset_Heating - v_SizingFlow_ms: 0 m/s; pTot_SizingFlow_kPa: 0 kPa; dpTot_SizingFlow_kPa: 0 kPa; MagiCAD Pset_Water - dpTot_SizingFlow_kPa: 0 kPa; pTot_SizingFlow_kPa: 0 kPa; v_SizingFlow_ms: 0 m/s; MagiCAD Pset_Pipe - Length_mm: 219.315 mm; qv_SizingFlow_ls: 0 m3/s; SystemName: 31= VV Kopi 41; Insulation_thickness_mm: 15 mm; ConnectionSize_mm: 12 mm
BI10T - Cellegummi 18-32 mm kalde rør | Nivå D + 1,2 m | BI10T - Cellegummi 18-32 mm kalde rør | 0.11735 | 890.5 | 42 | 0.00112728 | 42 | ORIGINAL | VV | Kobberrør | Cu | UB1.111713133 | Domestic Hot Water | MagiCAD Pset_Heating - v_SizingFlow_ms: 0 m/s; pTot_SizingFlow_kPa: 0 kPa; dpTot_SizingFlow_kPa: 0 kPa; MagiCAD Pset_Water - dpTot_SizingFlow_kPa: 0 kPa; pTot_SizingFlow_kPa: 0 kPa; v_SizingFlow_ms: 0 m/s; MagiCAD Pset_Pipe - Length_mm: 890.528 mm; qv_SizingFlow_ls: 0 m3/s; SystemName: 31= VV Kopi 41; Insulation_thickness_mm: 15 mm; ConnectionSize_mm: 12 mm
BI10T - Cellegummi 18-32 mm kalde rør | Nivå D + 1,2 m | BI10T - Cellegummi 18-32 mm kalde rør | 0.050577 | 383.8 | 42 | 0.000485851 | 42 | ORIGINAL | VV | Kobberrør | Cu | UB1.111713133 | Domestic Hot Water | MagiCAD Pset_Heating - v_SizingFlow_ms: 0 m/s; pTot_SizingFlow_kPa: 0 kPa; dpTot_SizingFlow_kPa: 0 kPa; MagiCAD Pset_Water - dpTot_SizingFlow_kPa: 0 kPa; pTot_SizingFlow_kPa: 0 kPa; v_SizingFlow_ms: 0 m/s; MagiCAD Pset_Pipe - Length_mm: 383.778 mm; qv_SizingFlow_ls: 0 m3/s; SystemName: 31= VV Kopi 41; Insulation_thickness_mm: 15 mm; ConnectionSize_mm: 12 mm
BI17T - Cellegummi 13 mm SPV fett | Nivå D + 1,2 m | BI17T - Cellegummi 13 mm SPV fett | 0.0156326 | 116.773 | 96.6898 | 0.000589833 | 108.5 | ORIGINAL | MagiCAD Pset_Elbow - Description: Generic PVC Bend; qv_SizingFlow_ls: 0 m3/s; pTot_SizingFlow_Pa: 0 kPa; dpTot_SizingFlow_Pa: 0 kPa; v_SizingFlow_ms: 0 m/s; ConnectionSize_mm: 0 mm; Insulation_thickness_mm: 13 mm
T=25mm | Nivå D + 1,2 m | 25mm lamellmatte | 0.407165 | 740.3 | 550 | 0.0314627 | 350 | ORIGINAL | MagiCAD Pset_Duct - Length_mm: 740.323 mm; qv_SizingFlow_ls: 0 m3/s; dpTot_SizingFlow_Pa: 0 kPa; pTot_SizingFlow_Pa: 0 kPa; v_SizingFlow_ms: 0 m/s; Description: Rektangulære, Forsinket stål; Insulation_thickness_mm: 25 mm; UserCode: 1-REKT
B-EI60 | Nivå D + 1,2 m | EI60 Brannisolasjon 30 mm | 0.0742 | 560 | 132.5 | 0.006837 | 360 | ORIGINAL | MagiCAD Pset_Duct - Length_mm: 132.5 mm; qv_SizingFlow_ls: 0 m3/s; dpTot_SizingFlow_Pa: 0 kPa; pTot_SizingFlow_Pa: 0 kPa; v_SizingFlow_ms: 0 m/s; Description: Rektangulære, Forsinket stål; Insulation_thickness_mm: 30 mm; UserCode: 1-REKT
T=25mm | Nivå D + 1,2 m | 25mm lamellmatte | 0.408375 | 742.5 | 550 | 0.0315563 | 350 | ORIGINAL | MagiCAD Pset_Duct - Length_mm: 742.5 mm; qv_SizingFlow_ls: 0 m3/s; dpTot_SizingFlow_Pa: 0 kPa; pTot_SizingFlow_Pa: 0 kPa; v_SizingFlow_ms: 0 m/s; Description: Rektangulære, Forsinket stål; Insulation_thickness_mm: 25 mm; UserCode: 1-REKT
B-EI60 | Nivå D + 1,2 m | EI60 Brannisolasjon 30 mm | 0.444812 | 644.4 | 220 | 0.0114808 | 220 | ORIGINAL | MagiCAD Pset_Duct - Length_mm: 644.376 mm; qv_SizingFlow_ls: 0 m3/s; dpTot_SizingFlow_Pa: 0 kPa; pTot_SizingFlow_Pa: 0 kPa; v_SizingFlow_ms: 0 m/s; Description: Spiro kanaler, Forsinket stål; Insulation_thickness_mm: 30 mm; UserCode: Circ
3 x B-EI60 | Nivå D + 1,2 m | EI60 Brannisolasjon 30 mm | 0.371179 | 455 | 260 | 0.0149329 | 260 | ORIGINAL | MagiCAD Pset_Duct - Length_mm: 455 mm; qv_SizingFlow_ls: 0 m3/s; dpTot_SizingFlow_Pa: 0 kPa; pTot_SizingFlow_Pa: 0 kPa; v_SizingFlow_ms: 0 m/s; Description: Spiro kanaler, Forsinket stål; Insulation_thickness_mm: 50 mm; UserCode: Circ
B-EI60 | Nivå D + 1,2 m | EI60 Brannisolasjon 30 mm | 0.270148 | 410 | 210 | 0.00592705 | 210 | ORIGINAL | MagiCAD Pset_Duct - Length_mm: 410 mm; qv_SizingFlow_ls: 0 m3/s; dpTot_SizingFlow_Pa: 0 kPa; pTot_SizingFlow_Pa: 0 kPa; v_SizingFlow_ms: 0 m/s; Description: Spiro kanaler, Forsinket stål; Insulation_thickness_mm: 25 mm; UserCode: Circ
B-EI60 | Nivå D + 1,2 m | EI60 Brannisolasjon 30 mm | 0.260264 | 395 | 210 | 0.0057102 | 210 | ORIGINAL | MagiCAD Pset_Duct - Length_mm: 395 mm; qv_SizingFlow_ls: 0 m3/s; dpTot_SizingFlow_Pa: 0 kPa; pTot_SizingFlow_Pa: 0 kPa; v_SizingFlow_ms: 0 m/s; Description: Spiro kanaler, Forsinket stål; Insulation_thickness_mm: 25 mm; UserCode: Circ
T=25mm | Nivå D + 1,2 m | 25mm lamellmatte | 0.331789 | 576.5 | 576.5 | 0.116126 | 350 | ORIGINAL | MagiCAD Pset_Elbow - qv_SizingFlow_ls: 0 m3/s; pTot_SizingFlow_Pa: 0 kPa; dpTot_SizingFlow_Pa: 0 kPa; v_SizingFlow_ms: 0 m/s; ConnectionSize_mm: 0 mm; Insulation_thickness_mm: 25 mm
T=25mm | Nivå D + 1,2 m | 25mm lamellmatte | 0.1925 | 550 | 300.52 | 0.0376509 | 371.967 | ORIGINAL | MagiCAD Pset_Elbow - qv_SizingFlow_ls: 0 m3/s; pTot_SizingFlow_Pa: 0 kPa; dpTot_SizingFlow_Pa: 0 kPa; v_SizingFlow_ms: 0 m/s; ConnectionSize_mm: 0 mm; Insulation_thickness_mm: 25 mm
B-EI60 | Nivå D + 1,2 m | EI60 Brannisolasjon 30 mm | 0.21364 | 560 | 381.5 | 0.0812948 | 381.5 | ORIGINAL | MagiCAD Pset_Elbow - qv_SizingFlow_ls: 0 m3/s; pTot_SizingFlow_Pa: 0 kPa; dpTot_SizingFlow_Pa: 0 kPa; v_SizingFlow_ms: 0 m/s; ConnectionSize_mm: 0 mm; Insulation_thickness_mm: 30 mm
3 x B-EI60 | Nivå D + 1,2 m | EI60 Brannisolasjon 30 mm | 0.16459 | 265 | 210 | 0.00855959 | 265 | ORIGINAL | MagiCAD Pset_Elbow - qv_SizingFlow_ls: 0 m3/s; pTot_SizingFlow_Pa: 0 kPa; dpTot_SizingFlow_Pa: 0 kPa; v_SizingFlow_ms: 0 m/s; ConnectionSize_mm: 0 mm; Insulation_thickness_mm: 25 mm
B-EI60 | Nivå D + 1,2 m | EI60 Brannisolasjon 30 mm | 0.172407 | 270 | 220 | 0.00938891 | 270 | ORIGINAL | MagiCAD Pset_Elbow - qv_SizingFlow_ls: 0 m3/s; pTot_SizingFlow_Pa: 0 kPa; dpTot_SizingFlow_Pa: 0 kPa; v_SizingFlow_ms: 0 m/s; ConnectionSize_mm: 0 mm; Insulation_thickness_mm: 30 mm
5 x B-EI60 | Nivå D + 1,2 m | EI60 Brannisolasjon 30 mm | 0.203747 | 290 | 260 | 0.0131143 | 290 | ORIGINAL | MagiCAD Pset_Elbow - qv_SizingFlow_ls: 0 m3/s; pTot_SizingFlow_Pa: 0 kPa; dpTot_SizingFlow_Pa: 0 kPa; v_SizingFlow_ms: 0 m/s; ConnectionSize_mm: 0 mm; Insulation_thickness_mm: 50 mm
B-EI60 | Nivå D + 1,2 m | EI60 Brannisolasjon 30 mm | 0.441775 | 640 | 220 | 0.0114024 | 220 | ORIGINAL | MagiCAD Pset_Duct - Length_mm: 639.971 mm; qv_SizingFlow_ls: 0 m3/s; dpTot_SizingFlow_Pa: 0 kPa; pTot_SizingFlow_Pa: 0 kPa; v_SizingFlow_ms: 0 m/s; Description: Spiro kanaler, Forsinket stål; Insulation_thickness_mm: 30 mm; UserCode: Circ
B-EI60 | Nivå F - 0,7 m | EI60 Brannisolasjon 30 mm | 0.199251 | 302.4 | 210 | 0.00437156 | 210 | ORIGINAL | MagiCAD Pset_Duct - Length_mm: 302.444 mm; qv_SizingFlow_ls: 0 m3/s; dpTot_SizingFlow_Pa: 0 kPa; pTot_SizingFlow_Pa: 0 kPa; v_SizingFlow_ms: 0 m/s; Description: Spiro kanaler, Forsinket stål; Insulation_thickness_mm: 25 mm; UserCode: Circ
B-EI60 | Nivå F - 0,7 m | EI60 Brannisolasjon 30 mm | 0.19108 | 290 | 210 | 0.0041923 | 210 | ORIGINAL | MagiCAD Pset_Duct - Length_mm: 290 mm; qv_SizingFlow_ls: 0 m3/s; dpTot_SizingFlow_Pa: 0 kPa; pTot_SizingFlow_Pa: 0 kPa; v_SizingFlow_ms: 0 m/s; Description: Spiro kanaler, Forsinket stål; Insulation_thickness_mm: 25 mm; UserCode: Circ
B-EI60 | Nivå F - 0,7 m | EI60 Brannisolasjon 30 mm | 0.0342418 | 210 | 210 | 0.000342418 | 10 | ORIGINAL | MagiCAD Pset_Joint - qv_SizingFlow_ls: 0 m3/s; pTot_SizingFlow_Pa: 0 kPa; dpTot_SizingFlow_Pa: 0 kPa; v_SizingFlow_ms: 0 m/s; ConnectionSize_mm: 0 mm; Insulation_thickness_mm: 25 mm
B-EI60 | Nivå F - 0,7 m | EI60 Brannisolasjon 30 mm | 0.16459 | 265 | 210 | 0.00855959 | 265 | ORIGINAL | MagiCAD Pset_Elbow - qv_SizingFlow_ls: 0 m3/s; pTot_SizingFlow_Pa: 0 kPa; dpTot_SizingFlow_Pa: 0 kPa; v_SizingFlow_ms: 0 m/s; ConnectionSize_mm: 0 mm; Insulation_thickness_mm: 25 mm
B-EI60 | Nivå F - 0,7 m | EI60 Brannisolasjon 30 mm | 0.226065 | 327.5 | 220 | 0.00583484 | 220 | ORIGINAL | MagiCAD Pset_Duct - Length_mm: 327.5 mm; qv_SizingFlow_ls: 0 m3/s; dpTot_SizingFlow_Pa: 0 kPa; pTot_SizingFlow_Pa: 0 kPa; v_SizingFlow_ms: 0 m/s; Description: Spiro kanaler, Forsinket stål; Insulation_thickness_mm: 30 mm; UserCode: Circ
B-EI60 | Nivå F - 0,7 m | EI60 Brannisolasjon 30 mm | 0.25697 | 315 | 260 | 0.0103381 | 260 | ORIGINAL | MagiCAD Pset_Duct - Length_mm: 315 mm; qv_SizingFlow_ls: 0 m3/s; dpTot_SizingFlow_Pa: 0 kPa; pTot_SizingFlow_Pa: 0 kPa; v_SizingFlow_ms: 0 m/s; Description: Spiro kanaler, Forsinket stål; Insulation_thickness_mm: 50 mm; UserCode: Circ
B-EI60 | Nivå F - 0,7 m | EI60 Brannisolasjon 30 mm | 0.261049 | 320 | 260 | 0.0105022 | 260 | ORIGINAL | MagiCAD Pset_Duct - Length_mm: 320 mm; qv_SizingFlow_ls: 0 m3/s; dpTot_SizingFlow_Pa: 0 kPa; pTot_SizingFlow_Pa: 0 kPa; v_SizingFlow_ms: 0 m/s; Description: Spiro kanaler, Forsinket stål; Insulation_thickness_mm: 50 mm; UserCode: Circ
BI10T - Cellegummi 18-32 mm kalde rør | Nivå D + 1,2 m | BI10T - Cellegummi 18-32 mm kalde rør | 0.0216022 | 1836 | 136 | 0.0200853 | 136 | RESULT | VARME T | Stålrør normaltykke | DN | UB3.144613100 | Hydronic Supply | MagiCAD Pset_Pipe - SystemName: +TG=320.000.T
BI10T - Cellegummi 18-32 mm kalde rør | Nivå D + 1,2 m | BI10T - Cellegummi 18-32 mm kalde rør | 0.0250143 | 2126 | 136 | 0.0232578 | 136 | RESULT | VARME R | Stålrør normaltykke | DN | UB3.144613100 | Hydronic Return | MagiCAD Pset_Pipe - SystemName: +TG=320.000.R
BI17T - Cellegummi 13 mm SPV fett | Nivå D + 1,2 m | BI17T - Cellegummi 13 mm SPV fett | 0.026027 | 1827 | 100 | 0.00397681 | 80 | RESULT | SPV FETT | MA | MA | UB2.1115131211 | Sanitary | MagiCAD Pset_Pipe - SystemName: 31= SPV Kopi 138
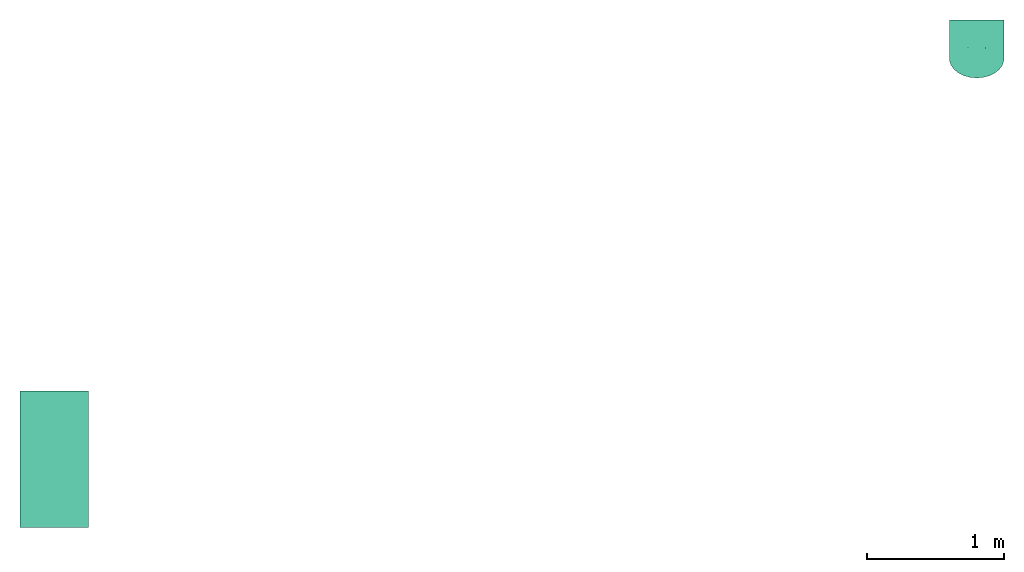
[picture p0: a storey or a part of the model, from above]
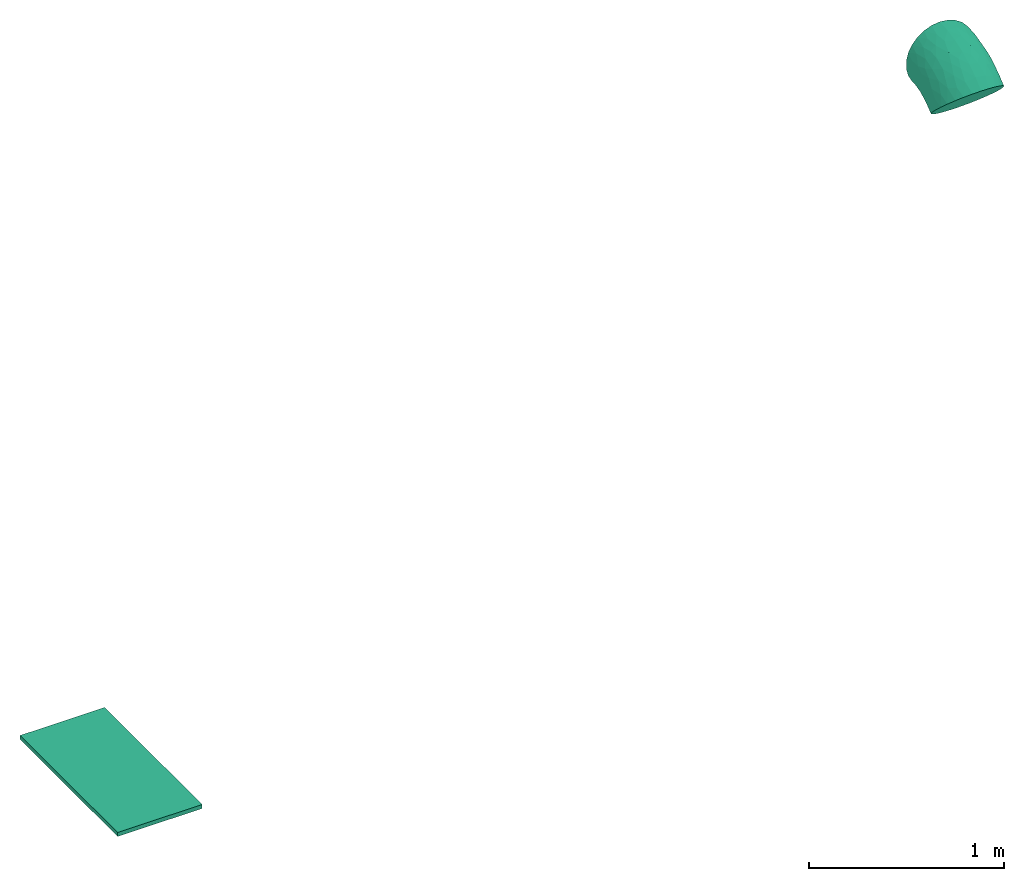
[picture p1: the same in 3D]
Properties of the parts of a building model (IFC2X3), part 6 of 11

# IfcCovering (435)
Name | In | Description | Area, largest surface, net (Simplebim) (m2) | Length (Simplebim) (mm) | Width (Simplebim) (mm) | Volume, net (Simplebim) (m3) | Height (Simplebim) (mm) | Splitting | SystemType | Material | MagiCAD Pset_Pipe, User Code | MagiCAD Pset_Pipe, NationalCode | SystemClass
BI17T - Cellegummi 13 mm SPV fett | Nivå D + 1,2 m | BI17T - Cellegummi 13 mm SPV fett | 0.00837451 | 108 | 77 | 0.000281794 | 95 | RESULT | MagiCAD Pset_Elbow - Description: Generic PVC Bend
BI15T - Cellegummi KV 15mm | Nivå D + 1,2 m | BI15T - Cellegummi KV 15mm | 0.00362338 | 945 | 44 | 0.00119018 | 44 | RESULT | KJØL T | Kobberrør | Cu | UB1.111713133 | Hydronic Supply | MagiCAD Pset_Pipe - SystemName: 37= T 9° Kopi 168
B-EI60 | Nivå D + 1,2 m | EI60 Brannisolasjon 30 mm | 0.0703275 | 500 | 500 | 0.0216327 | 308 | RESULT | MagiCAD Pset_Duct - Description: Spiro kanaler, Forsinket stål; UserCode: Circ
BI10T - Cellegummi 18-32 mm kalde rør | Nivå F - 0,7 m | BI10T - Cellegummi 18-32 mm kalde rør | 0.00312229 | 157 | 32 | 0.000074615 | 32 | RESULT | KV | Kobberrør | Cu | UB1.111713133 | Domestic Cold Water | MagiCAD Pset_Pipe - SystemName: 31=KV Kopi 4 (29) (2)
BI10T - Cellegummi 18-32 mm kalde rør | Nivå F - 0,7 m | BI10T - Cellegummi 18-32 mm kalde rør | 0.0025864 | 109 | 32 | 0.0000417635 | 26 | RESULT | KV | Kobberrør | Cu | UB1.111713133 | Domestic Cold Water | MagiCAD Pset_Pipe - SystemName: 31=KV Kopi 4 (29) (2)
BI10T - Cellegummi 18-32 mm kalde rør | Nivå D + 1,2 m | BI10T - Cellegummi 18-32 mm kalde rør | 0.0192077 | 216 | 136 | 0.000864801 | 94 | RESULT | Undefined | Stålrør normaltykke | DN | UB3.144613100 | Undefined
BI17T - Cellegummi 13 mm SPV fett | Nivå D + 1,2 m | BI17T - Cellegummi 13 mm SPV fett | 0.00505483 | 115 | 100 | 0.00023263 | 100 | RESULT | SPV FETT | MA | MA | UB2.1115131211 | Sanitary | MagiCAD Pset_Pipe - SystemName: 31= SPV Kopi 138
BI17T - Cellegummi 13 mm SPV fett | Nivå D + 1,2 m | BI17T - Cellegummi 13 mm SPV fett | 0.00318359 | 100 | 68 | 0.0000853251 | 67 | RESULT | SPV FETT | MA | MA | UB2.1115131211 | Sanitary | MagiCAD Pset_Pipe - SystemName: 31= SPV Kopi 138
BI17T - Cellegummi 13 mm SPV fett | Nivå D + 1,2 m | BI17T - Cellegummi 13 mm SPV fett | 0.00259425 | 100 | 91 | 0.000063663 | 29 | RESULT | SPV FETT | MA | MA | UB2.1115131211 | Sanitary | MagiCAD Pset_Pipe - SystemName: 31= SPV Kopi 138
BI17T - Cellegummi 13 mm SPV fett | Nivå D + 1,2 m | BI17T - Cellegummi 13 mm SPV fett | 0.0053038 | 90 | 67 | 0.0000801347 | 75 | RESULT
T=25mm | Nivå D + 1,2 m | 25mm lamellmatte | 0.111245 | 550 | 202 | 0.00339479 | 202 | RESULT | MagiCAD Pset_Duct - Description: Rektangulære, Forsinket stål; UserCode: 1-REKT
BI17T - Cellegummi 13 mm SPV fett | Nivå D + 1,2 m | BI17T - Cellegummi 13 mm SPV fett | 0.00357576 | 72 | 100 | 0.000204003 | 100 | RESULT | SPV FETT | MA | MA | UB2.1115131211 | Sanitary | MagiCAD Pset_Pipe - SystemName: 31= SPV Kopi 138

# IfcCovering: Compound Ceiling:A255 - Eksisterende - A60 Gips - 30 mm, Compound Ceiling:A255 - Eksisterende - A60 Gips - 30 mm:49478821
In: Nivå F - 0,7 m
Type - PredefinedType: CEILING
Type - Pset_CoveringCommon - TotalThickness: 30 mm
Material: T2_Gips Protect F 15 mm, T2_Gips Protect F 15 mm
AVINOR - 08_Status: S4; 07_Fase: F90; 03_Ansvar: FDV; 06_Omrade: TG; 02_Prosjekt: T20100; 01_Lufthavnkode: ENGM
Pset_QuantityTakeOff - Reference: A255 - Eksisterende - A60 Gips - 30 mm; sets with these values: 2
ePset_Simplebim - Assembly Level: Leaf
ePset_LocationTool - Splitting: ORIGINAL
ePset_SimplebimBasicQuantities - Width (Simplebim): 1810 mm; Height (Simplebim): 30 mm; Volume, net (Simplebim): 0.108356 m3; Length (Simplebim): 1995.5 mm; Area, largest surface, net (Simplebim): 3.61185 m2

# IfcCovering: Compound Ceiling:A255 - Eksisterende - akustisk direktmontert - 600 x 1200 mm (2)
In: Nivå D + 1,2 m
Type - PredefinedType: CEILING
Type - Pset_CoveringCommon - TotalThickness: 23 mm
AVINOR - 08_Status: S4; 07_Fase: F90; 03_Ansvar: FDV; 06_Omrade: TG; 02_Prosjekt: T20100; 01_Lufthavnkode: ENGM
ePset_LocationTool - Splitting: RESULT
ePset_SimplebimBasicQuantities - Height (Simplebim): 23 mm; Width (Simplebim): 7800 mm; Length (Simplebim): 8000 mm; Area, largest surface, net (Simplebim): 62.4 m2; Volume, net (Simplebim): 1.4352 m3
Pset_QuantityTakeOff - Reference: A255 - Eksisterende - akustisk direktmontert - 600 x 1200 mm; sets with these values: 2
ePset_Simplebim - Assembly Level: Leaf
Name (Compound Ceiling:A255 - Eksisterende - akustisk direktmontert - 600 x 1200 mm:...)
49219716
49219725

# IfcCovering: Compound Ceiling:A255 - Eksisterende - perforerte metallkassetter - 600 x 600 mm (6)
In: Nivå F - 0,7 m
Type - PredefinedType: CEILING
Type - Pset_CoveringCommon - TotalThickness: 52 mm
Material: <Unnamed> 36 mm, _NSW Himlingsplate 600x600 mm_med mønster 16 mm
AVINOR - 08_Status: S4; 07_Fase: F90; 03_Ansvar: FDV; 06_Omrade: TG; 02_Prosjekt: T20100; 01_Lufthavnkode: ENGM
ePset_Simplebim - Assembly Level: Leaf
Pset_CoveringCommon - Reference: A255 - Eksisterende - perforerte metallkassetter - 600 x 600 mm; Finish: _NSW Himlingsplate 600x600 mm_med mønster;
ePset_SimplebimBasicQuantities - Height (Simplebim): 52 mm
ePset_LocationTool - Splitting: ORIGINAL
Pset_QuantityTakeOff - Reference: A255 - Eksisterende - perforerte metallkassetter - 600 x 600 mm
Name (Compound Ceiling:A255 - Eksisterende - perforerte metallkassetter - 600 x 600 mm:...) | Area, largest surface, net (Simplebim) (m2) | Length (Simplebim) (mm) | Volume, net (Simplebim) (m3) | Width (Simplebim) (mm)
49478198 | 1.0572 | 1177.29 | 0.0549746 | 898
49478345 | 1.11323 | 1177.29 | 0.0578885 | 973
49478373 | 1.0572 | 1177.29 | 0.0549746 | 898
49478398 | 1.0572 | 1177.29 | 0.0549746 | 898
49478417 | 1.11249 | 1177.29 | 0.0578496 | 972
49478568 | 5.66547 | 5137 | 0.294601 | 1102.86

# IfcCovering: Compound Ceiling:A255 - eksisterende - perforert gips systemhimling - 1200 x 600 mm (5)
In: Nivå F - 0,7 m
Type - PredefinedType: CEILING
Type - Pset_CoveringCommon - TotalThickness: 52 mm
Material: T2_Gips Standard 36 mm, _NSW Himlingsplate 600x1200 mm 16 mm
ePset_LocationTool - Splitting: ORIGINAL
AVINOR - 08_Status: S4; 07_Fase: F90; 03_Ansvar: FDV; 06_Omrade: TG; 02_Prosjekt: T20100; 01_Lufthavnkode: ENGM
Pset_CoveringCommon - Reference: A255 - eksisterende - perforert gips systemhimling - 1200 x 600 mm; Finish: _NSW Himlingsplate 600x1200 mm;
ePset_Simplebim - Assembly Level: Leaf
Pset_QuantityTakeOff - Reference: A255 - eksisterende - perforert gips systemhimling - 1200 x 600 mm
ePset_SimplebimBasicQuantities - Height (Simplebim): 52 mm; Length (Simplebim): 4930.23 mm
Name (Compound Ceiling:A255 - eksisterende - perforert gips systemhimling - 1200 x 600 mm:...) | Width (Simplebim) (mm) | Volume, net (Simplebim) (m3) | Area, largest surface, net (Simplebim) (m2)
49576698 | 1739.99 | 0.437313 | 8.40988
49576705 | 1190.01 | 0.296312 | 5.69826
49576712 | 669.896 | 0.171742 | 3.30263
49576719 | 1189.99 | 0.305081 | 5.86696
49576726 | 1740.02 | 0.437318 | 8.40988

# IfcCovering: Compound Ceiling:A255 - eksisterende himling perfo. metall kassetter 600mm pir-nivåF (17)
In: Nivå F - 0,7 m
Type - PredefinedType: CEILING
Type - Pset_CoveringCommon - TotalThickness: 40 mm
Material: _NSW Himlingsplate 600mm 40 mm
AVINOR - 08_Status: S4; 07_Fase: F90; 03_Ansvar: FDV; 06_Omrade: TG; 02_Prosjekt: T20100; 01_Lufthavnkode: ENGM
Pset_CoveringCommon - Reference: A255 - eksisterende himling perfo. metall kassetter 600mm pir-nivåF; sets with these values: 2
ePset_SimplebimBasicQuantities - Height (Simplebim): 40 mm
ePset_Simplebim - Assembly Level: Leaf
ePset_LocationTool - Splitting: ORIGINAL
Name (Compound Ceiling:A255 - eksisterende himling perfo. metall kassetter 600mm pir-nivåF:...) | Volume, net (Simplebim) (m3) | Length (Simplebim) (mm) | Area, largest surface, net (Simplebim) (m2) | Width (Simplebim) (mm)
49469843 | 0.535969 | 9000 | 13.3992 | 1500
49469850 | 0.30272 | 8800 | 7.568 | 860
49469857 | 0.30272 | 8800 | 7.568 | 860
49469864 | 0.054 | 3000 | 1.35 | 450
49470084 | 0.0259363 | 1826.5 | 0.648408 | 355
49470091 | 0.0628316 | 1826.5 | 1.57079 | 860
49470098 | 0.0599092 | 1826.5 | 1.49773 | 820
49470105 | 0.162 | 9000 | 4.05 | 450
49479172 | 0.0259931 | 1830.5 | 0.649828 | 355
49479179 | 0.0629692 | 1830.5 | 1.57423 | 860
49479186 | 0.0600111 | 1830.5 | 1.50027 | 819.6
49479500 | 0.357696 | 9000 | 8.94234 | 993.6
49480091 | 0.54 | 9000 | 13.5 | 1500 | Group: Model Group:A255 - eksisterende himling i pir F-0,7 / TG__sørside akse 22-24:49480116
49480098 | 0.3096 | 9000 | 7.74 | 860 | Group: Model Group:A255 - eksisterende himling i pir F-0,7 / TG__sørside akse 22-24:49480116
49480105 | 0.3096 | 9000 | 7.74 | 860 | Group: Model Group:A255 - eksisterende himling i pir F-0,7 / TG__sørside akse 22-24:49480116
49480112 | 0.162 | 9000 | 4.05 | 450 | Group: Model Group:A255 - eksisterende himling i pir F-0,7 / TG__sørside akse 22-24:49480116
49480705 | 0.108 | 6000 | 2.7 | 450

# IfcCovering: Compound Ceiling:A255 - eksisterende utvendig båndtekking med isolasjon (3)
In: Nivå D + 1,2 m
Type - PredefinedType: CEILING
Type - Pset_CoveringCommon - TotalThickness: 100 mm
Material: _NSW Isolasjon 98 mm, _NSW Aluminium 2 mm
AVINOR - 08_Status: S4; 07_Fase: F90; 03_Ansvar: FDV; 06_Omrade: TG; 02_Prosjekt: T20100; 01_Lufthavnkode: ENGM
Pset_QuantityTakeOff - Reference: A255 - eksisterende utvendig båndtekking med isolasjon; sets with these values: 2
ePset_LocationTool - Splitting: ORIGINAL
ePset_Simplebim - Assembly Level: Leaf
ePset_SimplebimBasicQuantities - Width (Simplebim): 424.8 mm; Length (Simplebim): 9003.7 mm; Volume, net (Simplebim): 0.382477 m3; Height (Simplebim): 100 mm; Area, largest surface, net (Simplebim): 3.82488 m2
Name (Compound Ceiling:A255 - eksisterende utvendig båndtekking med isolasjon:...)
49227816
49227832
49228118

# IfcCurtainWall: Curtain Wall:A232 - UGV - Glass 30 mm (4)
AVINOR - 08_Status: S4; 07_Fase: F90; 03_Ansvar: FDV; 06_Omrade: TG; 02_Prosjekt: T20100; 01_Lufthavnkode: ENGM
Pset_CurtainWallCommon - IsExternal: yes; Reference: A232 - UGV - Glass 30 mm
Pset_QuantityTakeOff - Reference: A232 - UGV - Glass 30 mm
ePset_Simplebim - Assembly Level: Topmost
Name (Curtain Wall:A232 - UGV - Glass 30 mm:...) | In | Width (mm) | Height (mm) | Length (mm) | Volume, net (Simplebim) (m3) | Group
37454443 | Nivå D + 1,2 m | 215 | 1725 | 2305 | 0.191989 | Identity Data - CQFireRequirement: EI 60/ A2-s1,d0
48691435 | Nivå F - 0,7 m | 235 | 7460 | 8910 | 6.59956 | Model Group:A230 - eksisterende fasadesystem i pir_SØR_9000_HEL (members excluded):48691507
49613558 | Nivå F - 0,7 m | 235 | 7460 | 8910 | 6.59956 | Model Group:A230 - eksisterende fasadesystem i pir_SØR_9000_HEL (members excluded):49613630
49613693 | Nivå F - 0,7 m | 235 | 7460 | 8908.77 | 6.5989 | Model Group:A230 - eksisterende fasadesystem i pir_SØR_9000_HEL (members excluded):49613765

# IfcCurtainWall: Curtain Wall:A242 - IGV - Glass - 10 mm (4)
In: Nivå F - 0,7 m
AVINOR - 08_Status: S4; 07_Fase: F90; 06_Omrade: TG; 01_Lufthavnkode: ENGM
Pset_CurtainWallCommon - IsExternal: no; Reference: A242 - IGV - Glass - 10 mm
Pset_QuantityTakeOff - Reference: A242 - IGV - Glass - 10 mm
ePset_Simplebim - Assembly Level: Topmost
Name (Curtain Wall:A242 - IGV - Glass - 10 mm:...) | 03_Ansvar | 02_Prosjekt | Length (mm) | Width (mm) | Height (mm) | Volume, net (Simplebim) (m3)
53692766 | FDV | T20100 | 124.862 | 10 | 2500 | 0.00312155
53692772 | FDV | T20100 | 203.694 | 10 | 2500 | 0.00509235
53693266 | FDV | T20100 | 163.669 | 10 | 2250 | 0.00368255
59106076 | 182412 | A162446 | 5183.5 | 22 | 2500 | 0.102461 | Group: Model Group:A162446 - Utvidelse eksisterende Kiosk (members excluded):59114857

# IfcCurtainWall: Curtain Wall:A242 - IGV - Glass - 12 mm (3)
In: Nivå F - 0,7 m
AVINOR - 08_Status: S4; 07_Fase: F90; 03_Ansvar: FDV; 06_Omrade: TG; 02_Prosjekt: T20100; 01_Lufthavnkode: ENGM
Pset_CurtainWallCommon - IsExternal: no; Reference: A242 - IGV - Glass - 12 mm
ePset_SimplebimBasicQuantities - Width: 12 mm; Height: 7300 mm
Pset_QuantityTakeOff - Reference: A242 - IGV - Glass - 12 mm
ePset_Simplebim - Assembly Level: Topmost
Name (Curtain Wall:A242 - IGV - Glass - 12 mm:...) | Volume, net (Simplebim) (m3) | Length (mm)
49351543 | 0.228154 | 2604.49
49351545 | 0.152763 | 2533.24
49351547 | 0.175928 | 2008.31

# IfcCurtainWall: Curtain Wall:A242 - IGV - Glass - 6 mm (18)
In: Nivå F - 0,7 m
AVINOR - 08_Status: S4; 07_Fase: F90; 03_Ansvar: FDV; 06_Omrade: TG; 02_Prosjekt: T20100; 01_Lufthavnkode: ENGM
Pset_QuantityTakeOff - Reference: A242 - IGV - Glass - 6 mm
Pset_CurtainWallCommon - IsExternal: no; Reference: A242 - IGV - Glass - 6 mm
ePset_Simplebim - Assembly Level: Topmost
ePset_SimplebimBasicQuantities - Width: 6 mm
Name (Curtain Wall:A242 - IGV - Glass - 6 mm:...) | Volume, net (Simplebim) (m3) | Length (mm) | Height (mm)
49469457 | 0.00267794 | 1239.79 | 360
49469459 | 0.0112682 | 5216.75 | 360
49469461 | 0.00267794 | 1239.79 | 360
49469463 | 0.00267794 | 1239.79 | 360
49469465 | 0.00267794 | 1239.79 | 360
50544380 | 0.00434808 | 2013 | 360
50544382 | 0.00173694 | 804.137 | 360
50544384 | 0.00504765 | 1869.5 | 450
50544386 | 0.00729105 | 1869.5 | 650
50544388 | 0.00738855 | 1894.5 | 650
50544395 | 0.00504765 | 1869.5 | 450
50544397 | 0.0117439 | 5437 | 360
50544399 | 0.00316478 | 811.481 | 650
50544404 | 0.002739 | 830 | 550
50544406 | 0.00106488 | 394.4 | 450
50544408 | 0.00316478 | 811.481 | 650
50544413 | 0.002739 | 830 | 550
50544415 | 0.00106488 | 394.4 | 450

# IfcCurtainWall: Curtain Wall:A245 - BIM av T1 - IMK 20mm - Offset 30mm (3)
In: Nivå F - 0,7 m
AVINOR - 08_Status: S4; 07_Fase: F90; 03_Ansvar: FDV; 06_Omrade: TG; 02_Prosjekt: T20100; 01_Lufthavnkode: ENGM
Pset_QuantityTakeOff - Reference: A245 - BIM av T1 - IMK 20mm - Offset 30mm
Pset_CurtainWallCommon - Reference: A245 - BIM av T1 - IMK 20mm - Offset 30mm; IsExternal: no
ePset_Simplebim - Assembly Level: Topmost
Name (Curtain Wall:A245 - BIM av T1 - IMK 20mm - Offset 30mm:...) | Volume, net (Simplebim) (m3) | Width (mm) | Height (mm) | Length (mm)
50238658 | 0.651585 | 110 | 5850 | 5390
50238682 | 0.0609013 | 20 | 2950 | 2032.27
50238940 | 0.0790364 | 20 | 2950 | 2186.21

# IfcCurtainWall: Curtain Wall:A245 - IGK - Glass Kledning (2)
In: Nivå F - 0,7 m
Pset_QuantityTakeOff - Reference: A245 - IGK - Glass Kledning
Pset_CurtainWallCommon - Reference: A245 - IGK - Glass Kledning; IsExternal: no
ePset_SimplebimBasicQuantities - Width: 10 mm; Height: 2430 mm
ePset_Simplebim - Assembly Level: Topmost
Group: Model Group:pylon 2430 (members excluded):59105865
Name (Curtain Wall:A245 - IGK - Glass Kledning:...) | Length (mm) | Volume, net (Simplebim) (m3)
59105853 | 619 | 0.0150417
59105857 | 553.546 | 0.0134512

# IfcCurtainWall: Curtain Wall:A245 - IMK - Metal Kledning (3)
In: Nivå F - 0,7 m
ePset_SimplebimBasicQuantities - Width: 10 mm
Pset_QuantityTakeOff - Reference: A245 - IMK - Metal Kledning
Pset_CurtainWallCommon - IsExternal: no; Reference: A245 - IMK - Metal Kledning
ePset_Simplebim - Assembly Level: Topmost
Name (Curtain Wall:A245 - IMK - Metal Kledning:...) | Length (mm) | Height (mm) | Volume, net (Simplebim) (m3) | Group
59105832 | 14845 | 440 | 0.065318 | Model Group:A162446 - Utvidelse eksisterende Kiosk (members excluded):59114857 | AVINOR - 08_Status: S4; 07_Fase: F90; 02_Prosjekt: A162446; 03_Ansvar: 182412; 06_Omrade: TG; 01_Lufthavnkode: ENGM
59105855 | 108 | 2430 | 0.0026244 | Model Group:pylon 2430 (members excluded):59105865
59105861 | 108 | 2430 | 0.0026244 | Model Group:pylon 2430 (members excluded):59105865

# IfcCurtainWall: Curtain Wall:A245 - ITK - Trekledning (6)
In: Nivå F - 0,7 m
AVINOR - 08_Status: S4; 07_Fase: F90; 03_Ansvar: FDV; 06_Omrade: TG; 02_Prosjekt: T20100; 01_Lufthavnkode: ENGM
Pset_CurtainWallCommon - Reference: A245 - ITK - Trekledning; IsExternal: no
Pset_QuantityTakeOff - Reference: A245 - ITK - Trekledning
ePset_SimplebimBasicQuantities - Width: 14 mm; Height: 2250 mm
ePset_Simplebim - Assembly Level: Topmost
Name (Curtain Wall:A245 - ITK - Trekledning:...) | Volume, net (Simplebim) (m3) | Length (mm)
50255382 | 0.298053 | 9462
50255406 | 0.0024674 | 78.3302
50255418 | 0.031563 | 1002
50255442 | 0.073647 | 2338
50255454 | 0.002583 | 82
50255466 | 0.031563 | 1002

# IfcCurtainWall: Curtain Wall:A245 - ITK-01, Curtain Wall:A245 - ITK-01:59105836
In: Nivå F - 0,7 m
AVINOR - 08_Status: S4; 07_Fase: F90; 02_Prosjekt: A162446; 03_Ansvar: 182412; 06_Omrade: TG; 01_Lufthavnkode: ENGM
ePset_SimplebimBasicQuantities - Width: 100 mm; Height: 2700 mm; Length: 2524.76 mm; Volume, net (Simplebim): 0.12884 m3
Pset_CurtainWallCommon - Reference: A245 - ITK-01; IsExternal: no
Pset_QuantityTakeOff - Reference: A245 - ITK-01
ePset_Simplebim - Assembly Level: Topmost
Group: Model Group:A162446 - Utvidelse eksisterende Kiosk (members excluded):59114857

# IfcDistributionControlElement: BUS Binærutgang 4-kanals (2)
In: Nivå F
Type - Description: BUS Binærutgang 4-kanals
MagiCAD Pset_Device - Length [mm]: 0 mm; Width [mm]: 0 mm; Height [mm]: 0 mm; Manufacturer: General; System code: 562X
AVINOR - ID-nummer2: +TG=561.001
ePset_LocationTool - Splitting: ORIGINAL
ePset_Simplebim - Assembly Level: Leaf
Group: KNX Binærutgang
Name | Host | Connection
BUS Binærutgang 4-kanals | +TG=433.055 | 2
BUS Binærutgang 4-kanals | +TG=433.045 | 1

# IfcDistributionControlElement: Standard (12)
Type - Description: Brannalarm Røykdetektor
ePset_LocationTool - Splitting: ORIGINAL
ePset_Simplebim - Assembly Level: Leaf
MagiCAD Pset_Device - System code: 542; Length [mm]: 0 mm; Width [mm]: 0 mm; Height [mm]: 0 mm
AVINOR - 08_Status: S4; 07_Fase: F90; 06_Omrade: TG; 01_Lufthavnkode: ENGM
Group: Brannalarm
Name | In | IP_Code | User code | Host | National code | P1 | Connection | Manufacturer | 03_Ansvar | ID-nummer2 = 05_ID-nummer | 04_Kontrakt | 02_Prosjekt
Standard | Nivå D + 1,2 | IP20 | -TY | +TG=542.001 | XJ1.1115 | -RY | 8 | General | T20100 | +TG=542.003-TY0052 | 72581 | 72101
Standard | Nivå D + 1,2 | IP20 | -TY | +TG=542.002 | XJ1.1115 | -RY | 8 | General | T20100 | +TG=542.013-TY0018 | 72581 | 72101
Standard | Nivå F | IP20 | -TY | +TG=542.001 | XJ1.1115 | -RY | 5 | General | T20100 | +TG=542.004-TY0070 | 72581 | 72101
Standard | Nivå F | IP20 | -TY | +TG=542.001 | XJ1.1115 | -RY | 5 | General | T20100 | +TG=542.004-TY0027 | 72581 | 72101
Standard | Nivå F | IP20 | -TY | +TG=542.001 | XJ1.1115 | -RY | 5 | General | T20100 | +TG=542.004-TY0067 | 72581 | 72101
Standard | Nivå F | IP20 | -TY | +TG=542.002 | XJ1.1115 | -RY | 10 | General | 181608 | +TG=542.014-TY0048 | 183766 | A162446
Standard | Nivå F | IP20 | -TY | +TG=542.001 | XJ1.1115 | -RY | 5 | General | 181608 | +TG=542.004-TY0025 | 183766 | A162446
Standard | Nivå F |  | -TY | +TG=542.001 |  |  | 5 |  | 181608 | +TG=542.004-TY0026 | 183766 | A162446 | Description: Brannalarm Røykdetektor over himling
Standard | Nivå F |  | -TY | +TG=542.002 |  |  | 10 |  | 181608 | +TG=542.014-TY0004 | 183766 | A162446 | Description: Brannalarm Røykdetektor over himling
Standard | Nivå F |  | -TY | +TG=542.001 | XJ1.1115 | -TY | 5 | General | 181608 | +TG=542.004-TY0100 | 183766 | A162446 | Description: Brannalarm Multikriteriedetektor
Standard | Nivå F |  | -TW | +TG=542.002 | XJ1.1117 | -RY | 10 | General | 181608 | +TG=542.014-TW0067 | 183766 | A162446 | Description: Brannalarm Varmedetektor
Standard | Nivå F - 0,7 |  |  |  |  |  | <unnamed> | Generic | T20100 | +TO=542.013 | 72579 | 72101 | Description: Koblingsboks utenpåliggende brannalarm

# IfcDoor: A20 - Dørkarm - uten dørfløy:A243 - veggåpning med karm - 0890 x 2240 mm, A20 - Dørkarm - uten dørfløy:A243 - veggåpning med karm - 0890 x 2240 mm:46950982
In: Nivå F - 0,7 m
Type - ParameterTakesPrecedence: no; Sizeable: no; Material: _NSW Dør - karm, hvit, N_Door - Threshold
OverallHeight: 2260 mm; OverallWidth: 910 mm
ePset_LocationTool - Splitting: ORIGINAL
AVINOR - 08_Status: S4; 07_Fase: F90; 03_Ansvar: FDV; 06_Omrade: TG; 02_Prosjekt: T20100; 01_Lufthavnkode: ENGM
Pset_QuantityTakeOff - Reference: A243 - veggåpning med karm - 0890 x 2240 mm
Pset_DoorCommon - Reference: A243 - veggåpning med karm - 0890 x 2240 mm; IsExternal: no
ePset_Simplebim - Assembly Level: Leaf
ePset_SimplebimBasicQuantities - Length, frame (Simplebim): 5370 mm; Height (Simplebim): 2240 mm; Height, opening (Simplebim): 2260 mm; Area, opening (Simplebim): 2.0566 m2; Area (Simplebim): 1.9936 m2; Width (Simplebim): 890 mm; Width, opening (Simplebim): 910 mm

# IfcDoor: A20 - Slagdør - Enkel:A243 - DI_LTO - 0690 x 2240 mm (5)
In: Nivå F - 0,7 m
Type - OperationType: SINGLE_SWING_RIGHT; ParameterTakesPrecedence: no; Sizeable: no; Material: _NSW Stål - rustfritt, N_Door - Handle, _NSW Dør - karm, hvit, N_Door - Threshold, N_Door - Panel
Type - IfcDoorPanelProperties - PanelOperation: SWINGING
OverallHeight: 2260 mm; OverallWidth: 710 mm
AVINOR - 08_Status: S4; 07_Fase: F90; 03_Ansvar: FDV; 06_Omrade: TG; 02_Prosjekt: T20100; 01_Lufthavnkode: ENGM
Pset_DoorCommon - IsExternal: no; Reference: A243 - DI_LTO - 0690 x 2240 mm
ePset_LocationTool - Splitting: ORIGINAL
ePset_Simplebim - Assembly Level: Leaf
Pset_QuantityTakeOff - Reference: A243 - DI_LTO - 0690 x 2240 mm
ePset_SimplebimBasicQuantities - Height, opening (Simplebim): 2260 mm; Area (Simplebim): 1.5456 m2; Area, opening (Simplebim): 1.6046 m2; Width, opening (Simplebim): 710 mm; Width (Simplebim): 690 mm; Height (Simplebim): 2240 mm; Length, frame (Simplebim): 5170 mm
Name (A20 - Slagdør - Enkel:A243 - DI_LTO - 0690 x 2240 mm:...)
2513532
2513602
2513699
2513700
2513722

# IfcDoor: A20 - Slagdør - Enkel:A243 - DI_LTO - 0890 x 2240 mm, A20 - Slagdør - Enkel:A243 - DI_LTO - 0890 x 2240 mm:53693265
In: Nivå F - 0,7 m
Type - OperationType: SINGLE_SWING_RIGHT; ParameterTakesPrecedence: no; Sizeable: no; Material: _NSW Stål - rustfritt, N_Door - Handle, _NSW Dør - karm, hvit, N_Door - Threshold, N_Door - Panel
Type - IfcDoorPanelProperties - PanelOperation: SWINGING
OverallHeight: 2260 mm; OverallWidth: 910 mm
AVINOR - 08_Status: S4; 07_Fase: F90; 03_Ansvar: FDV; 06_Omrade: TG; 02_Prosjekt: T20100; 01_Lufthavnkode: ENGM
ePset_SimplebimBasicQuantities - Height, opening (Simplebim): 2260 mm; Area, opening (Simplebim): 2.0566 m2; Area (Simplebim): 1.9936 m2; Width (Simplebim): 890 mm; Width, opening (Simplebim): 910 mm; Height (Simplebim): 2240 mm; Length, frame (Simplebim): 5370 mm
Pset_DoorCommon - IsExternal: no; Reference: A243 - DI_LTO - 0890 x 2240 mm
Pset_QuantityTakeOff - Reference: A243 - DI_LTO - 0890 x 2240 mm
ePset_Simplebim - Assembly Level: Leaf
ePset_LocationTool - Splitting: ORIGINAL

# IfcDoor: A20 - Slagdør - Enkel:A243 - DI_LTO - 0990 x 2090 mm, A20 - Slagdør - Enkel:A243 - DI_LTO - 0990 x 2090 mm:2513423
In: Nivå F - 0,7 m
Type - OperationType: SINGLE_SWING_RIGHT; ParameterTakesPrecedence: no; Sizeable: no; Material: _NSW Stål - rustfritt, N_Door - Handle, _NSW Dør - karm, hvit, N_Door - Threshold, N_Door - Panel
Type - IfcDoorPanelProperties - PanelOperation: SWINGING
OverallHeight: 2110 mm; OverallWidth: 1010 mm
AVINOR - 08_Status: S4; 07_Fase: F90; 03_Ansvar: FDV; 06_Omrade: TG; 02_Prosjekt: T20100; 01_Lufthavnkode: ENGM
ePset_LocationTool - Splitting: ORIGINAL
Pset_DoorCommon - Reference: A243 - DI_LTO - 0990 x 2090 mm; IsExternal: no
Identity Data - CQFireRequirement: EI 60Sa
Pset_QuantityTakeOff - Reference: A243 - DI_LTO - 0990 x 2090 mm
ePset_Simplebim - Assembly Level: Leaf
ePset_SimplebimBasicQuantities - Height, opening (Simplebim): 2110 mm; Area (Simplebim): 2.0691 m2; Width (Simplebim): 990 mm; Width, opening (Simplebim): 1010 mm; Height (Simplebim): 2090 mm; Length, frame (Simplebim): 5170 mm; Area, opening (Simplebim): 2.1311 m2

# IfcDoor: A20 - Slagdør - Enkel:A243 - DI_LTO - 0990 x 2240 mm (2)
In: Nivå F - 0,7 m
Type - OperationType: SINGLE_SWING_RIGHT; ParameterTakesPrecedence: no; Sizeable: no; Material: _NSW Stål - rustfritt, N_Door - Handle, _NSW Dør - karm, hvit, N_Door - Threshold, N_Door - Panel
Type - IfcDoorPanelProperties - PanelOperation: SWINGING
OverallHeight: 2260 mm; OverallWidth: 1010 mm
AVINOR - 08_Status: S4; 07_Fase: F90; 03_Ansvar: FDV; 06_Omrade: TG; 02_Prosjekt: T20100; 01_Lufthavnkode: ENGM
ePset_SimplebimBasicQuantities - Area, opening (Simplebim): 2.2826 m2; Height, opening (Simplebim): 2260 mm; Width, opening (Simplebim): 1010 mm; Width (Simplebim): 990 mm; Height (Simplebim): 2240 mm; Length, frame (Simplebim): 5470 mm; Area (Simplebim): 2.2176 m2
ePset_Simplebim - Assembly Level: Leaf
ePset_LocationTool - Splitting: ORIGINAL
Pset_DoorCommon - Reference: A243 - DI_LTO - 0990 x 2240 mm; IsExternal: no
Pset_QuantityTakeOff - Reference: A243 - DI_LTO - 0990 x 2240 mm
Name (A20 - Slagdør - Enkel:A243 - DI_LTO - 0990 x 2240 mm:...)
2513270
2513481

# IfcDoor: A20 - Slagdør - Enkel:A243 - DI_LTO - 1090 x 2090 mm, A20 - Slagdør - Enkel:A243 - DI_LTO - 1090 x 2090 mm:2513354
In: Nivå F - 0,7 m
Type - OperationType: SINGLE_SWING_RIGHT; ParameterTakesPrecedence: no; Sizeable: no; Material: _NSW Stål - rustfritt, N_Door - Handle, _NSW Dør - karm, hvit, N_Door - Threshold, N_Door - Panel
Type - IfcDoorPanelProperties - PanelOperation: SWINGING
OverallHeight: 2110 mm; OverallWidth: 1110 mm
AVINOR - 08_Status: S4; 07_Fase: F90; 03_Ansvar: FDV; 06_Omrade: TG; 02_Prosjekt: T20100; 01_Lufthavnkode: ENGM
ePset_SimplebimBasicQuantities - Area, opening (Simplebim): 2.3421 m2; Height, opening (Simplebim): 2110 mm; Width, opening (Simplebim): 1110 mm; Area (Simplebim): 2.2781 m2; Width (Simplebim): 1090 mm; Height (Simplebim): 2090 mm; Length, frame (Simplebim): 5270 mm
Pset_DoorCommon - Reference: A243 - DI_LTO - 1090 x 2090 mm; IsExternal: no
ePset_Simplebim - Assembly Level: Leaf
Pset_QuantityTakeOff - Reference: A243 - DI_LTO - 1090 x 2090 mm
ePset_LocationTool - Splitting: ORIGINAL

# IfcDoor: A20 - Slagdør - Enkel:A243 - DI_SSO - 0590 x 0985 mm (2)
In: Nivå F - 0,7 m
Type - OperationType: SINGLE_SWING_RIGHT; ParameterTakesPrecedence: no; Sizeable: no; Material: _NSW Stål - rustfritt, N_Door - Handle, _NSW Stål, N_Door - Threshold, N_Door - Panel
Type - IfcDoorPanelProperties - PanelOperation: SWINGING
OverallHeight: 1005 mm; OverallWidth: 610 mm
AVINOR - 08_Status: S4; 07_Fase: F90; 03_Ansvar: FDV; 06_Omrade: TG; 02_Prosjekt: T20100; 01_Lufthavnkode: ENGM
ePset_SimplebimBasicQuantities - Height, opening (Simplebim): 1005 mm; Area (Simplebim): 0.58115 m2; Area, opening (Simplebim): 0.61305 m2; Width (Simplebim): 590 mm; Width, opening (Simplebim): 610 mm; Height (Simplebim): 985 mm; Length, frame (Simplebim): 2560 mm
Identity Data - CQFireRequirement: EI 60Sa
Pset_QuantityTakeOff - Reference: A243 - DI_SSO - 0590 x 0985 mm
ePset_LocationTool - Splitting: ORIGINAL
ePset_Simplebim - Assembly Level: Leaf
Pset_DoorCommon - Reference: A243 - DI_SSO - 0590 x 0985 mm; IsExternal: no
Name (A20 - Slagdør - Enkel:A243 - DI_SSO - 0590 x 0985 mm:...)
49723437
49723705

# IfcDoor: single_panel_sliding_door_whafele_hrdw_parametric_2015:single_panel_sliding_door_whafele_hrdw_parametric_7m (2)
In: Nivå F - 0,7 m
Type - ParameterTakesPrecedence: no; Sizeable: no; Material: Glass, <Unnamed>
OverallHeight: 2133.6 mm; OverallWidth: 700 mm; Group: Model Group:A162446 - Utvidelse eksisterende Kiosk (members excluded):59114857
Pset_QuantityTakeOff - Reference: single_panel_sliding_door_whafele_hrdw_parametric_7m
ePset_LocationTool - Splitting: ORIGINAL
ePset_SimplebimBasicQuantities - Height (Simplebim): 2199.64 mm; Area (Simplebim): 3.41472 m2; Width (Simplebim): 1552.4 mm; Length, frame (Simplebim): 5951.68 mm
ePset_Simplebim - Assembly Level: Leaf
AVINOR - 08_Status: S4; 07_Fase: F90; 02_Prosjekt: A162446; 03_Ansvar: 182412; 06_Omrade: TG; 05_ID-nummer: +TG=243.005-IP2149; 01_Lufthavnkode: ENGM
Pset_DoorCommon - Reference: single_panel_sliding_door_whafele_hrdw_parametric_7m; IsExternal: no
Name (single_panel_sliding_door_whafele_hrdw_parametric_2015:single_panel_sliding_door_whafele_hrdw_parametric_7m:...)
59105930
59106087

# IfcElectricalCircuit (12)
Name | Description
Belysningsutstyr | 442
Kursopplegg for belysning | 441
Underfordelinger | 434
KNX Tilstedeværelsesdetektor | 5621
Kursopplegg for drift og virksomhet | 461
Utstyr for drift og virksomhet | 462
Utstyr for automatisering | 562
Utstyr for nødlys | 443
Kursopplegg belysning | 441
BUS System | 561
Kursopplegg driftsteknisk | 461
Kursopplegg for el varme | 461

# IfcEnergyConversionDevice: GCS2.UWW.K01 (2)
In: Nivå F - 0,7 m
Type - Description: Casette fancoil; PredefinedType: WATERHEATINGCOIL
ePset_LocationTool - Splitting: ORIGINAL
MagiCAD Pset_FanCoilUnit - ProductCode: GCS2.UWW.K01; Description: Casette fancoil; qv_SizingFlow_ls: 0 m3/s; dpTot_SizingFlow_Pa: 0 kPa; qv_SizingFlow_ms: 0 m/s; Manufacturer: GEA; User Code: FC05
ePset_Simplebim - Assembly Level: Leaf
Name | Group
GCS2.UWW.K01 | Kjøle Retur 17°; 32= T 60° Kopi 10
GCS2.UWW.K01 | 32= T 60° Kopi 10; 37= R 12° Kopi 6

# IfcFlowController (2)
In: Nivå F - 0,7
Description: El. ford. skap; Group: Underfordelinger
AVINOR - 07_Fase: F90; 06_Omrade: TG; 01_Lufthavnkode: ENGM
ePset_Simplebim - Assembly Level: Leaf
ePset_LocationTool - Splitting: ORIGINAL
Name | 08_Status | 02_Prosjekt | 05_ID-nummer = ID-nummer2 | 04_Kontrakt | 03_Ansvar
El-ford-Skap_001 | S4 | A162446 | +TG=436.255 | 183766 | 181608
El-ford-Skap_001 | S2 | 72101 | +TG=432.022 | FDV | T20100

# IfcFlowController: AT-3600-20 (3)
In: Nivå F - 0,7 m
Type - Description: Ball valve, threaded, brass
MagiCAD Pset_Valve - Description: Ball valve, threaded, brass; qv_SizingFlow_ls: 0 m3/s; pTot_SizingFlow_kPa: 0 kPa; dpTot_SizingFlow_kPa: 0 kPa; Manufacturer: Armatec; Product Code: AT3600-20; User Code: SM01T
ePset_LocationTool - Splitting: ORIGINAL
ePset_Simplebim - Assembly Level: Leaf
Name | Insulation_thickness_mm (mm) | Group
AT-3600-20 | 20 | 37= T 7° Kopi 4
AT-3600-20 | 18 | 37= T 7° Kopi 6
AT-3600-20 | 0 | 37= T 7° Kopi 6

# IfcFlowController: AT-3600-20 2 (3)
In: Nivå D + 1,2 m
Type - Description: Ball valve, threaded, brass
MagiCAD Pset_Valve - Description: Ball valve, threaded, brass; Insulation_thickness_mm: 0 mm; qv_SizingFlow_ls: 0 m3/s; pTot_SizingFlow_kPa: 0 kPa; dpTot_SizingFlow_kPa: 0 kPa; Manufacturer: Armatec; Product Code: AT3600-20; User Code: SM01T
ePset_Simplebim - Assembly Level: Leaf
ePset_LocationTool - Splitting: ORIGINAL
Name | Group
2 x AT-3600-20 2 | +TG=310.002 (2)
AT-3600-20 2 | 31= VV Kopi 12

# IfcFlowController: AT-3600-32 (2)
In: Nivå F - 0,7 m
Type - Description: Ball valve, threaded, brass
MagiCAD Pset_Valve - Product Code: AT3600-32; Description: Ball valve, threaded, brass; Insulation_thickness_mm: 0 mm; qv_SizingFlow_ls: 0 m3/s; pTot_SizingFlow_kPa: 0 kPa; dpTot_SizingFlow_kPa: 0 kPa; Manufacturer: Armatec; User Code: SM01T
ePset_Simplebim - Assembly Level: Leaf
ePset_LocationTool - Splitting: ORIGINAL
Name | Group
AT-3600-32 | 32= R 20° Kopi 5
AT-3600-32 | 32= R 20° Kopi 58

# IfcFlowController: AT-3600-32 2
In: Nivå D + 1,2 m
Type - Description: Ball valve, threaded, brass
ePset_LocationTool - Splitting: ORIGINAL
MagiCAD Pset_Valve - Product Code: AT3600-32; Description: Ball valve, threaded, brass; Insulation_thickness_mm: 0 mm; qv_SizingFlow_ls: 0 m3/s; pTot_SizingFlow_kPa: 0 kPa; dpTot_SizingFlow_kPa: 0 kPa; Manufacturer: Armatec; User Code: SM01T
ePset_Simplebim - Assembly Level: Leaf
Group: 31=KV Kopi 4 (2)

# IfcFlowController: AT-3600-50 2
In: Nivå D + 1,2 m
Type - Description: Ball valve, threaded, brass
MagiCAD Pset_Valve - Description: Ball valve, threaded, brass; Product Code: AT3600-50; Insulation_thickness_mm: 0 mm; qv_SizingFlow_ls: 0 m3/s; pTot_SizingFlow_kPa: 0 kPa; dpTot_SizingFlow_kPa: 0 kPa; Manufacturer: Armatec; User Code: SM01T
ePset_LocationTool - Splitting: ORIGINAL
ePset_Simplebim - Assembly Level: Leaf
Group: 31=KV Kopi 4 (2)

# IfcFlowController: Bevegelsesdetektor m_boks KNX
In: Nivå F - 0,7
Type - Description: Bevegelsesdetektor m/boks
AVINOR - 07_Fase: F90; 04_Kontrakt: FDV; 05_ID-nummer: +TG=561.001; ID-nummer2: +TG=561.001; 08_Status: S2; 06_Omrade: TG; 03_Ansvar: T20100; 02_Prosjekt: 72101; 01_Lufthavnkode: ENGM
Pset_ElectricalDeviceCommon - IP_Code: IP20; ElectricalDeviceNominalPower: 0 W; NumberOfPoles: 1; NominalVoltage: 230
ePset_LocationTool - Splitting: ORIGINAL
ePset_Simplebim - Assembly Level: Leaf
MagiCAD Pset_Device - National code: WL1.311; System code: 5621; User code: 08; P1: -XD; Length [mm]: 0 mm; Width [mm]: 0 mm; Height [mm]: 0 mm; Manufacturer: General; Product code: Move detector
Group: KNX Tilstedeværelsesdetektor

# IfcFlowController: Bevegelsesdetektor tak-himling KNX
In: Nivå F
Type - Description: Bevegelsesdetektor Tak
ePset_LocationTool - Splitting: ORIGINAL
ePset_Simplebim - Assembly Level: Leaf
MagiCAD Pset_Device - System code: 442; National code: WL1.311; Switchboard: +TG=436.255; P1: -XD; User code: -XD; Length [mm]: 0 mm; Width [mm]: 0 mm; Height [mm]: 0 mm; Circuit: 1; Manufacturer: General
AVINOR - 08_Status: S4; 07_Fase: F90; ID-nummer2: +TO=442.100-XD0001; 05_ID-nummer: +TO=442.100-XD0001; 06_Omrade: TG; 03_Ansvar: T20100; 04_Kontrakt: 72586; 02_Prosjekt: 72101; 01_Lufthavnkode: ENGM
Pset_ElectricalDeviceCommon - ElectricalDeviceNominalPower: 0 W; NumberOfPoles: 1; NominalVoltage: 230
Group: Belysningsutstyr

# IfcFlowController: Bryter 1-polet m_boks (3)
In: Nivå F
Type - Description: Bryter 1-polet m/boks
MagiCAD Pset_Device - System code: 441; User code: 01; National code: WL1.311; P1: -XS; Length [mm]: 0 mm; Width [mm]: 0 mm; Height [mm]: 0 mm; Manufacturer: General; Product code: 1gang switch
AVINOR - 07_Fase: F90; 06_Omrade: TG; 01_Lufthavnkode: ENGM
Pset_ElectricalDeviceCommon - IP_Code: 21; ElectricalDeviceNominalPower: 0 W; NumberOfPoles: 1; NominalVoltage: 230
ePset_LocationTool - Splitting: ORIGINAL
ePset_Simplebim - Assembly Level: Leaf
Name | Switchboard | Circuit | 08_Status | 02_Prosjekt | 05_ID-nummer = ID-nummer2 | 04_Kontrakt | 03_Ansvar | Group
Bryter 1-polet m_boks | +TG=436.255 | 6 | S4 | A162446 | +TO=441.011 | 183766 | 181608 | Kursopplegg for belysning
Bryter 1-polet m_boks | +TG=433.055 | 4 | S2 | 72101 | +TO=441.001 | FDV | T20100 | Kursopplegg belysning
Bryter 1-polet m_boks | +TG=433.055 | 6 | S2 | 72101 | +TO=441.001 | FDV | T20100 | Kursopplegg belysning

# IfcFlowController: Bryter 2-polet m_boks (2)
In: Nivå F
Type - Description: Bryter 2-polet m/boks
AVINOR - 07_Fase: F90; 06_Omrade: TG; 01_Lufthavnkode: ENGM
ePset_LocationTool - Splitting: ORIGINAL
Pset_ElectricalDeviceCommon - IP_Code: 21; ElectricalDeviceNominalPower: 0 W; NumberOfPoles: 1; NominalVoltage: 230
ePset_Simplebim - Assembly Level: Leaf
MagiCAD Pset_Device - Product code: 2006015; National code: WL1.311; User code: 02; P1: -XS; Length [mm]: 0 mm; Width [mm]: 0 mm; Height [mm]: 0 mm; Manufacturer: General
Name | 05_ID-nummer = ID-nummer2 | 04_Kontrakt | 08_Status | 03_Ansvar | 02_Prosjekt | System code | Switchboard | Circuit | Group
Bryter 2-polet m_boks | +TO=441.001 | FDV | S2 | T20100 | 72101 | 441 | +TG=433.055 | 55 | Kursopplegg for belysning
Bryter 2-polet m_boks | +TO=462.001 | 183766 | S4 | 181608 | A162446 | 462 | +TG=436.255 | 9 | Utstyr for drift og virksomhet

# IfcFlowController: IRIS 10831 (2)
Type - PredefinedType: BALANCINGDAMPER
MagiCAD Pset_FlowDamper - Product Code: IRIS 200; Manufacturer: Swegon AB; qv_SizingFlow_ls: 0 m3/s; pTot_SizingFlow_Pa: 0 kPa; dpTot_SizingFlow_Pa: 0 kPa; v_SizingFlow_ms: 0 m/s; User Code: SP01
ePset_LocationTool - Splitting: ORIGINAL
ePset_Simplebim - Assembly Level: Leaf
Name | In | Group
IRIS 10831 | Nivå F | +TG=360.021-22 A
IRIS 10831 | Nivå F - 0,7 m | +TG=360.021-1 TL

# IfcFlowController: IRIS 10834 (2)
In: Nivå D + 1,2 m
Type - PredefinedType: BALANCINGDAMPER
ePset_Simplebim - Assembly Level: Leaf
MagiCAD Pset_FlowDamper - Product Code: IRIS 400; Manufacturer: Swegon AB; qv_SizingFlow_ls: 0 m3/s; pTot_SizingFlow_Pa: 0 kPa; dpTot_SizingFlow_Pa: 0 kPa; v_SizingFlow_ms: 0 m/s; User Code: SP01
ePset_LocationTool - Splitting: ORIGINAL
Name | Group
IRIS 10834 | +TG=360.020 TL
IRIS 10834 | +TG=360.021-22 A

# IfcFlowController: IRIS-125
In: Nivå F
Type - Description: Balancing damper; PredefinedType: BALANCINGDAMPER
ePset_LocationTool - Splitting: ORIGINAL
MagiCAD Pset_FlowDamper - ConnectionSize_mm: 125; qv_SizingFlow_ls: 0 m3/s; pTot_SizingFlow_Pa: 0 kPa; dpTot_SizingFlow_Pa: 0 kPa; v_SizingFlow_ms: 0 m/s; Product Code: IRIS-125; Manufacturer: Oeland
ePset_Simplebim - Assembly Level: Leaf
Group: 36= Avtrekk 3

# IfcFlowController: IRIS-160
In: Nivå F
Type - Description: Balancing damper; PredefinedType: BALANCINGDAMPER
ePset_LocationTool - Splitting: ORIGINAL
ePset_Simplebim - Assembly Level: Leaf
MagiCAD Pset_FlowDamper - qv_SizingFlow_ls: 0 m3/s; pTot_SizingFlow_Pa: 0 kPa; dpTot_SizingFlow_Pa: 0 kPa; v_SizingFlow_ms: 0 m/s; Product Code: IRIS-160; ConnectionSize_mm: 160; Manufacturer: Oeland
Group: +TG=360.021-22 A

# IfcFlowController: IRIS-250
In: Nivå F - 0,7 m
Type - PredefinedType: BALANCINGDAMPER
MagiCAD Pset_FlowDamper - Product Code: IRIS-250; qv_SizingFlow_ls: 0 m3/s; pTot_SizingFlow_Pa: 0 kPa; dpTot_SizingFlow_Pa: 0 kPa; v_SizingFlow_ms: 0 m/s; Manufacturer: Oeland
ePset_Simplebim - Assembly Level: Leaf
ePset_LocationTool - Splitting: ORIGINAL
Group: +TG=360.021-1 TL

# IfcFlowController: PK-I-S-EI90S-300x400-DV9-T (2)
Type - Description: Fire damper for explosive areas rectangular; PredefinedType: FIREDAMPER
MagiCAD Pset_FireDamper - Product Code: PK-I-S-EI90S-300x400-DV9-T; Manufacturer: Systemair; qv_SizingFlow_ls: 0 m3/s; pTot_SizingFlow_Pa: 0 kPa; dpTot_SizingFlow_Pa: 0 kPa; v_SizingFlow_ms: 0 m/s; Description: Fire damper for explosive areas rectangular
ePset_Simplebim - Assembly Level: Leaf
ePset_LocationTool - Splitting: ORIGINAL
Name | In | Group
PK-I-S-EI90S-300x400-DV9-T | Nivå D + 1,2 m | +TG=360.021-1 TL
PK-I-S-EI90S-300x400-DV9-T | Nivå F | +TG=360.021-22 A

# IfcFlowController: SAFE SWITCH, Safe switch
In: Nivå F - 0,7
Type - Description: Bryter 3-polet m/boks 16A
Description: Bryter 3-polet påvegg 16A; Group: Kursopplegg for drift og virksomhet
AVINOR - 07_Fase: F90; 04_Kontrakt: FDV; 05_ID-nummer: +TO=461.001; ID-nummer2: +TO=461.001; 08_Status: S2; 06_Omrade: TG; 03_Ansvar: T20100; 02_Prosjekt: 72101; 01_Lufthavnkode: ENGM
MagiCAD Pset_Device - National code: WL3.1; Circuit: <unnamed>; User code: 52; P1: -XS; Length [mm]: 0 mm; Manufacturer: General; Width [mm]: 106 mm; Height [mm]: 131 mm; Product code: Safe switch; System code: 461
ePset_Simplebim - Assembly Level: Leaf
ePset_LocationTool - Splitting: ORIGINAL
Pset_ElectricalDeviceCommon - IP_Code: 44; ElectricalDeviceNominalPower: 0 W; NumberOfPoles: 3; NominalVoltage: 230

# IfcFlowController: STAD/F-20 (3)
In: Nivå F - 0,7 m
Type - Description: Presetting of flow, shut-off valve, flow measuring,pressure reading 10-50
ePset_LocationTool - Splitting: ORIGINAL
ePset_Simplebim - Assembly Level: Leaf
MagiCAD Pset_Valve - Manufacturer: TA; qv_SizingFlow_ls: 0 m3/s; pTot_SizingFlow_kPa: 0 kPa; dpTot_SizingFlow_kPa: 0 kPa; Description: Presetting of flow, shut-off valve, flow measuring,pressure reading 10-50; NationalCode: UL5.11091; Product Code: STAD/F-20; User Code: SV01T
Name | Insulation_thickness_mm (mm) | Group
STAD/F-20 | 20 | 37= R 12° Kopi 4
2 x STAD/F-20 | 18 | 37= R 12° Kopi 6

# IfcFlowController: STAD/F-32 (2)
In: Nivå F - 0,7 m
Type - Description: Presetting of flow, shut-off valve, flow measuring,pressure reading 10-50
ePset_Simplebim - Assembly Level: Leaf
ePset_LocationTool - Splitting: ORIGINAL
MagiCAD Pset_Valve - Product Code: STAD/F-32; Manufacturer: TA; Insulation_thickness_mm: 0 mm; qv_SizingFlow_ls: 0 m3/s; pTot_SizingFlow_kPa: 0 kPa; dpTot_SizingFlow_kPa: 0 kPa; Description: Presetting of flow, shut-off valve, flow measuring,pressure reading 10-50; NationalCode: UL5.11091; User Code: SV01T
Name | Group
STAD/F-32 | 32= R 20° Kopi 7
STAD/F-32 | 32= R 20° Kopi 57

# IfcFlowController: TVT-EASY/500X300
In: Nivå D + 1,2 m
Type - Description: VARYCONTROL VAV Controller; PredefinedType: BALANCINGDAMPER
Classification: VE5.142012 Not defined (NS3420)
MagiCAD Pset_FlowDamper - Product Code: TVT-EASY/500X300; Manufacturer: TROX; Description: VARYCONTROL VAV Controller; qv_SizingFlow_ls: 0 m3/s; pTot_SizingFlow_Pa: 0 kPa; dpTot_SizingFlow_Pa: 0 kPa; v_SizingFlow_ms: 0 m/s; NationalCode: VE5.142012; User Code: SR01T
ePset_LocationTool - Splitting: ORIGINAL
ePset_Simplebim - Assembly Level: Leaf

# IfcFlowFitting: 10mm Radius
In: Nivå F - 0,7
Type - PredefinedType: TEE
AVINOR - 07_Fase: F90; 04_Kontrakt: FDV; 08_Status: S2; 05_ID-nummer: +TO=411.501; ID-nummer2: +TO=411.501; 06_Omrade: TG; 03_Ansvar: T20100; 02_Prosjekt: 72101; 01_Lufthavnkode: ENGM
ePset_Simplebim - Assembly Level: Leaf
ePset_LocationTool - Splitting: ORIGINAL
Group: Bæresystem generelt

# IfcFlowFitting: Koblingsboks skjult vegg (4)
Type - Description: Koblingsboks skjult
ePset_LocationTool - Splitting: ORIGINAL
AVINOR - 07_Fase: F90; 06_Omrade: TG; 01_Lufthavnkode: ENGM
ePset_Simplebim - Assembly Level: Leaf
MagiCAD Pset_Device - User code: -QM; Switchboard: +TG=433.055; Length [mm]: 0 mm; Width [mm]: 0 mm; Height [mm]: 0 mm; Manufacturer: General
Pset_ElectricalDeviceCommon - ElectricalDeviceNominalPower: 0 W; NumberOfPoles: 1; NominalVoltage: 230
Name | In | ID-nummer2 = 05_ID-nummer | 04_Kontrakt | 08_Status | 03_Ansvar | 02_Prosjekt | System code | Circuit | Group
Koblingsboks skjult vegg | Nivå F | +TO=441.001 | FDV | S2 | T20100 | 72101 | 441 | 2 | Kursopplegg for belysning
Koblingsboks skjult vegg | Nivå F | +TO=441.001 | 183766 | S4 | 181608 | A162446 | 441 | 3 | Kursopplegg for belysning
Koblingsboks skjult vegg | Nivå F | +TO=441.001 | 183766 | S4 | 181608 | A162446 | 441 | 2 | Kursopplegg for belysning
Koblingsboks skjult vegg | Nivå F - 0,7 | +TO=461.001 | FDV | S2 | T20100 | 72101 | 461 | 96 | Kursopplegg for drift og virksomhet

# IfcFlowFitting: Koblingsboks åpen (10)
Type - Description: Koblingsboks åpen
AVINOR - 08_Status: S4; 07_Fase: F90; 02_Prosjekt: A162446; 06_Omrade: TG; 04_Kontrakt: 183766; 03_Ansvar: 181608; 01_Lufthavnkode: ENGM
ePset_LocationTool - Splitting: ORIGINAL
ePset_Simplebim - Assembly Level: Leaf
MagiCAD Pset_Device - User code: -QM; Length [mm]: 0 mm; Width [mm]: 0 mm; Height [mm]: 0 mm; Manufacturer: General
Pset_ElectricalDeviceCommon - ElectricalDeviceNominalPower: 0 W; NumberOfPoles: 1; NominalVoltage: 230
Name | In | ID-nummer2 = 05_ID-nummer | System code | Switchboard | Circuit | Group
2 x Koblingsboks åpen | Nivå F | +TO=441.001 | 441 | +TG=436.255 | 4 | Kursopplegg for belysning
3 x Koblingsboks åpen | Nivå F | +TO=441.001 | 441 | +TG=436.255 | 5 | Kursopplegg for belysning
2 x Koblingsboks åpen | Nivå F | +TO=441.001 | 441 | +TG=436.255 | 3 | Kursopplegg for belysning
2 x Koblingsboks åpen | Nivå F | +TO=441.001 | 441 | +TG=436.255 | 2 | Kursopplegg for belysning
Koblingsboks åpen | Nivå F - 0,7 | +TO=461.001 | 461 | +TG=433.055 | 93 | Kursopplegg for el varme

# IfcFlowFitting: Lindab LBR (2)
In: Nivå D + 1,2 m
Type - PredefinedType: BEND
MagiCAD Pset_Elbow - qv_SizingFlow_ls: 0 m3/s; pTot_SizingFlow_Pa: 0 kPa; dpTot_SizingFlow_Pa: 0 kPa; v_SizingFlow_ms: 0 m/s; ConnectionSize_mm: 0 mm
ePset_Simplebim - Assembly Level: Leaf
ePset_LocationTool - Splitting: ORIGINAL
Name | Insulation_thickness_mm (mm)
Lindab LBR | 25
Lindab LBR | 30

# IfcFlowFitting: Standard
In: Nivå D + 1,2
Type - PredefinedType: BEND
ePset_LocationTool - Splitting: ORIGINAL
MagiCAD Pset_Cabletray - System code: 4111; Width [mm]: 0 mm; Height [mm]: 0 mm; Length [mm]: 0 mm
ePset_Simplebim - Assembly Level: Leaf
Group: Bæresystem for elkraft

# IfcFlowFitting: Standard 10mm (5)
In: Nivå D + 1,2
Type - PredefinedType: BEND
AVINOR - 07_Fase: F90; 04_Kontrakt: FDV; 08_Status: S2; 05_ID-nummer: +TO=411.501; 06_Omrade: TG; 03_Ansvar: T20100; 02_Prosjekt: 72101; 01_Lufthavnkode: ENGM
ePset_Simplebim - Assembly Level: Leaf
Group: Bæresystem for elkraft
Name | ID-nummer2 | Splitting
4 x Standard 10mm | +TO=411.501 | ORIGINAL
Standard 10mm |  | RESULT

# IfcFlowFitting: VSHA_multi_shape_trans
In: Nivå F
Type - PredefinedType: TRANSITION
MagiCAD Pset_Reduction - Insulation_thickness_mm: 0 mm; qv_SizingFlow_ls: 0 m3/s; pTot_SizingFlow_Pa: 0 kPa; dpTot_SizingFlow_Pa: 0 kPa; v_SizingFlow_ms: 0 m/s; ConnectionSize_mm: 0 mm
ePset_LocationTool - Splitting: ORIGINAL
ePset_Simplebim - Assembly Level: Leaf
Group: +TG=360.021-22 A

# IfcFlowFitting: magi_pipe_cu_reducer_centric_short_001 (2)
In: Nivå F - 0,7 m
Type - PredefinedType: TRANSITION
MagiCAD Pset_Reduction - Insulation_thickness_mm: 0 mm; qv_SizingFlow_ls: 0 m3/s; pTot_SizingFlow_Pa: 0 kPa; dpTot_SizingFlow_Pa: 0 kPa; v_SizingFlow_ms: 0 m/s; ConnectionSize_mm: 0 mm
ePset_Simplebim - Assembly Level: Leaf
ePset_LocationTool - Splitting: ORIGINAL
Name | Group
magi_pipe_cu_reducer_centric_short_001 | 31=KV Kopi 4 (2)
magi_pipe_cu_reducer_centric_short_001 | +TG=310.002 (2)

# IfcFlowFitting: magi_pipe_elbow_short_001 (211)
Type - PredefinedType: BEND
ePset_Simplebim - Assembly Level: Leaf
Name | In | Insulation_thickness_mm (mm) | qv_SizingFlow_ls (m3/s) = pTot_SizingFlow_Pa (kPa) = dpTot_SizingFlow_Pa (kPa) = v_SizingFlow_ms (m/s) = ConnectionSize_mm (mm) | Splitting | Group
22 x magi_pipe_elbow_short_001 | Nivå F - 0,7 m | 0 | 0 | ORIGINAL | 31=KV Kopi 4 (2)
3 x magi_pipe_elbow_short_001 | Nivå F - 0,7 m | 0 | 0 | ORIGINAL | +TG=310.002 (15)
3 x magi_pipe_elbow_short_001 | Nivå F - 0,7 m | 0 | 0 | ORIGINAL | 31=KV Kopi 4 (4)
11 x magi_pipe_elbow_short_001 | Nivå F - 0,7 m | 0 | 0 | ORIGINAL | +TG=310.002 (2)
2 x magi_pipe_elbow_short_001 | Nivå F - 0,7 m | 0 | 0 | ORIGINAL | 31=KV Kopi 4 (49)
2 x magi_pipe_elbow_short_001 | Nivå F - 0,7 m | 0 | 0 | ORIGINAL | +TG=310.002 (33)
2 x magi_pipe_elbow_short_001 | Nivå F - 0,7 m | 0 | 0 | ORIGINAL | 31= VV Kopi 12
3 x magi_pipe_elbow_short_001 | Nivå F - 0,7 m | 0 | 0 | ORIGINAL | +TG=310.002 (29)
10 x magi_pipe_elbow_short_001 | Nivå F - 0,7 m | 10 | 0 | ORIGINAL | 31=KV Kopi 4 (29) (2)
magi_pipe_elbow_short_001 | Nivå F - 0,7 m | 0 | 0 | ORIGINAL | 31=KV Kopi 4 (29) (2)
magi_pipe_elbow_short_001 | Nivå F - 0,7 m | 0 | 0 | ORIGINAL | 31= VV Kopi 41
magi_pipe_elbow_short_001 | Nivå F - 0,7 m | 15 | 0 | ORIGINAL | 31= VV Kopi 41
magi_pipe_elbow_short_001 | Nivå C | 0 | 0 | ORIGINAL | +TG=310.002 (2)
magi_pipe_elbow_short_001 | Nivå C | 0 | 0 | ORIGINAL | 31= VV Kopi 12
22 x magi_pipe_elbow_short_001 | Nivå D + 1,2 m | 0 | 0 | ORIGINAL | 31=KV Kopi 4 (2)
10 x magi_pipe_elbow_short_001 | Nivå D + 1,2 m | 0 | 0 | ORIGINAL | +TG=310.002 (2)
6 x magi_pipe_elbow_short_001 | Nivå D + 1,2 m | 0 | 0 | ORIGINAL | 31= VV Kopi 12
magi_pipe_elbow_short_001 | Nivå D + 1,2 m | 0 | 0 | ORIGINAL | +TG=310.002 (29)
15 x magi_pipe_elbow_short_001 | Nivå D + 1,2 m | 35 | 0 | ORIGINAL
21 x magi_pipe_elbow_short_001 | Nivå D + 1,2 m | 13 | 0 | ORIGINAL | 31= SPV Kopi 138
2 x magi_pipe_elbow_short_001 | Nivå D + 1,2 m | 35 | 0 | ORIGINAL | +TG=320.000.T
2 x magi_pipe_elbow_short_001 | Nivå D + 1,2 m | 35 | 0 | ORIGINAL | +TG=320.000.R
9 x magi_pipe_elbow_short_001 | Nivå D + 1,2 m | 0 | 0 | ORIGINAL | 37= T 9° Kopi 44
10 x magi_pipe_elbow_short_001 | Nivå D + 1,2 m | 0 | 0 | ORIGINAL | 37= R 18° Kopi 30
9 x magi_pipe_elbow_short_001 | Nivå D + 1,2 m | 0 | 0 | ORIGINAL
17 x magi_pipe_elbow_short_001 | Nivå D + 1,2 m | 25 | 0 | ORIGINAL
14 x magi_pipe_elbow_short_001 | Nivå D + 1,2 m | 20 | 0 | ORIGINAL
5 x magi_pipe_elbow_short_001 | Nivå D + 1,2 m | 13 | 0 | ORIGINAL | 37= T 9° Kopi 168
magi_pipe_elbow_short_001 | Nivå D + 1,2 m | 15 | 0 | ORIGINAL | 31= VV Kopi 41
3 x magi_pipe_elbow_short_001 | Nivå D + 1,2 m | 0 | 0 | ORIGINAL | 37= R 18° Kopi 81
magi_pipe_elbow_short_001 | Nivå D + 1,2 m |  |  | RESULT | 31= SPV Kopi 138

# IfcFlowFitting: magi_pipe_fe_cross_centric_90_001 (3)
Type - PredefinedType: JUNCTION
MagiCAD Pset_XBranch - Insulation_thickness_mm: 0 mm; qv_SizingFlow_ls: 0 m3/s; pTot_SizingFlow_Pa: 0 kPa; dpTot_SizingFlow_Pa: 0 kPa; v_SizingFlow_ms: 0 m/s; ConnectionSize_mm: 0 mm
ePset_LocationTool - Splitting: ORIGINAL
ePset_Simplebim - Assembly Level: Leaf
Name | In | Group
magi_pipe_fe_cross_centric_90_001 | Nivå F - 0,7 m | +TG=332.003 (2)
magi_pipe_fe_cross_centric_90_001 | Nivå F - 0,7 m | +TG=332.003 (46)
magi_pipe_fe_cross_centric_90_001 | Nivå D + 1,2 m | +TG=332.002 (1) (2)

# IfcFlowFitting: magi_pipe_fe_elbow_short_001 (165)
Type - PredefinedType: BEND
MagiCAD Pset_Elbow - qv_SizingFlow_ls: 0 m3/s; pTot_SizingFlow_Pa: 0 kPa; dpTot_SizingFlow_Pa: 0 kPa; v_SizingFlow_ms: 0 m/s
ePset_LocationTool - Splitting: ORIGINAL
ePset_Simplebim - Assembly Level: Leaf
Name | In | Insulation_thickness_mm (mm) | ConnectionSize_mm (mm) | Group
22 x magi_pipe_fe_elbow_short_001 | Nivå F - 0,7 m | 0 | 0 | +TG=332.003 (2)
11 x magi_pipe_fe_elbow_short_001 | Nivå F - 0,7 m | 0 | 0 | +TG=332.003 (46)
5 x magi_pipe_fe_elbow_short_001 | Nivå F - 0,7 m | 0 | 0 | +TG=332.003 (12)
9 x magi_pipe_fe_elbow_short_001 | Nivå D + 1,2 m | 0 | 0
52 x magi_pipe_fe_elbow_short_001 | Nivå D + 1,2 m | 0 | 0 | +TG=332.002 (1) (2)
7 x magi_pipe_fe_elbow_short_001 | Nivå D + 1,2 m | 0 | 0 | +TG=332.003 (10)
2 x magi_pipe_fe_elbow_short_001 | Nivå G - 2,0 m | 0 | 0 | 37= R 18° Kopi 20
2 x magi_pipe_fe_elbow_short_001 | Nivå G - 2,0 m | 0 | 0 | 37= T 9° Kopi 22
9 x magi_pipe_fe_elbow_short_001 | Nivå F - 0,7 m | 0 | 0 | 32= R 20° Kopi 5
9 x magi_pipe_fe_elbow_short_001 | Nivå F - 0,7 m | 0 | 0 | 32= R 20° Kopi 7
2 x magi_pipe_fe_elbow_short_001 | Nivå F - 0,7 m | 18 | 0 | 37= T 7° Kopi 6
2 x magi_pipe_fe_elbow_short_001 | Nivå F - 0,7 m | 18 | 0 | 37= R 12° Kopi 6
magi_pipe_fe_elbow_short_001 | Nivå F - 0,7 m | 18 | 25 | 37= R 12° Kopi 6
magi_pipe_fe_elbow_short_001 | Nivå F - 0,7 m | 20 | 0 | 37= T 7° Kopi 4
2 x magi_pipe_fe_elbow_short_001 | Nivå F - 0,7 m | 20 | 0 | 37= R 12° Kopi 4
5 x magi_pipe_fe_elbow_short_001 | Nivå F - 0,7 m | 0 | 0 | 32= R 20° Kopi 58
4 x magi_pipe_fe_elbow_short_001 | Nivå F - 0,7 m | 0 | 0 | 32= R 20° Kopi 57
2 x magi_pipe_fe_elbow_short_001 | Nivå D + 1,2 m | 0 | 0 | 37= T 9° Kopi 54
3 x magi_pipe_fe_elbow_short_001 | Nivå D + 1,2 m | 0 | 0 | 37= T 9° Kopi 1
5 x magi_pipe_fe_elbow_short_001 | Nivå D + 1,2 m | 0 | 0 | 37= R 18° Kopi 13
3 x magi_pipe_fe_elbow_short_001 | Nivå D + 1,2 m | 0 | 0 | 32= R 50° Kopi 54
2 x magi_pipe_fe_elbow_short_001 | Nivå D + 1,2 m | 0 | 0 | 32= T 60° Kopi 50
magi_pipe_fe_elbow_short_001 | Nivå D + 1,2 m | 0 | 0 | 37= R 18° Kopi 20
2 x magi_pipe_fe_elbow_short_001 | Nivå D + 1,2 m | 0 | 0 | 37= T 9° Kopi 122
2 x magi_pipe_fe_elbow_short_001 | Nivå D + 1,2 m | 0 | 0 | 37= R 18° Kopi 82

# IfcFlowFitting: magi_pipe_fe_plug_001 (22)
Type - PredefinedType: OBSTRUCTION
ePset_LocationTool - Splitting: ORIGINAL
ePset_Simplebim - Assembly Level: Leaf
MagiCAD Pset_Plug - ConnectionSize_mm: 0 mm; pTot_SizingFlow_kPa: 0 kPa
Name | In | Insulation_thickness_mm (mm) | Group
magi_pipe_fe_plug_001 | Nivå D + 1,2 m | 0
magi_pipe_fe_plug_001 | Nivå D + 1,2 m | 0 | +TG=332.003 (10)
4 x magi_pipe_fe_plug_001 | Nivå F - 0,7 m | 0 | 31=KV Kopi 4 (2)
magi_pipe_fe_plug_001 | Nivå F - 0,7 m | 0 | +TG=310.002 (2)
magi_pipe_fe_plug_001 | Nivå F - 0,7 m | 0 | 31=KV Kopi 4 (4)
magi_pipe_fe_plug_001 | Nivå F - 0,7 m | 0 | 31= SPV Kopi 147 (11)
2 x magi_pipe_fe_plug_001 | Nivå F - 0,7 m | 13 | 31= SPV Kopi 138
magi_pipe_fe_plug_001 | Nivå F - 0,7 m | 0 | +TG=310.002 (15)
magi_pipe_fe_plug_001 | Nivå F - 0,7 m | 0 | +TG=310.002 (29)
5 x magi_pipe_fe_plug_001 | Nivå D + 1,2 m | 13 | 31= SPV Kopi 138
4 x magi_pipe_fe_plug_001 | Nivå D + 1,2 m | 0 | 31=KV Kopi 4 (2)

# IfcFlowFitting: magi_pipe_fe_reducer_centric_short_001 (91)
Type - PredefinedType: TRANSITION
MagiCAD Pset_Reduction - qv_SizingFlow_ls: 0 m3/s; pTot_SizingFlow_Pa: 0 kPa; dpTot_SizingFlow_Pa: 0 kPa; v_SizingFlow_ms: 0 m/s; ConnectionSize_mm: 0 mm
ePset_LocationTool - Splitting: ORIGINAL
ePset_Simplebim - Assembly Level: Leaf
Name | In | Insulation_thickness_mm (mm) | Group
22 x magi_pipe_fe_reducer_centric_short_001 | Nivå F - 0,7 m | 0 | +TG=332.003 (2)
13 x magi_pipe_fe_reducer_centric_short_001 | Nivå F - 0,7 m | 0 | +TG=332.003 (46)
20 x magi_pipe_fe_reducer_centric_short_001 | Nivå D + 1,2 m | 0 | +TG=332.002 (1) (2)
5 x magi_pipe_fe_reducer_centric_short_001 | Nivå D + 1,2 m | 0 | +TG=332.003 (10)
2 x magi_pipe_fe_reducer_centric_short_001 | Nivå F - 0,7 m | 18 | 37= T 7° Kopi 6
magi_pipe_fe_reducer_centric_short_001 | Nivå F - 0,7 m | 0 | 32= R 20° Kopi 5
magi_pipe_fe_reducer_centric_short_001 | Nivå F - 0,7 m | 0 | 32= R 20° Kopi 7
2 x magi_pipe_fe_reducer_centric_short_001 | Nivå F - 0,7 m | 0 | 31=KV Kopi 4 (2)
magi_pipe_fe_reducer_centric_short_001 | Nivå D + 1,2 m | 0 | 32= R 50° Kopi 54
7 x magi_pipe_fe_reducer_centric_short_001 | Nivå D + 1,2 m | 0 | 31=KV Kopi 4 (2)
6 x magi_pipe_fe_reducer_centric_short_001 | Nivå D + 1,2 m | 0 | +TG=310.002 (2)
3 x magi_pipe_fe_reducer_centric_short_001 | Nivå D + 1,2 m | 0 | 31= VV Kopi 12
2 x magi_pipe_fe_reducer_centric_short_001 | Nivå D + 1,2 m | 0
magi_pipe_fe_reducer_centric_short_001 | Nivå D + 1,2 m | 0 | 37= T 9° Kopi 44
magi_pipe_fe_reducer_centric_short_001 | Nivå D + 1,2 m | 0 | 32= T 60° Kopi 50
2 x magi_pipe_fe_reducer_centric_short_001 | Nivå D + 1,2 m | 13 | 37= T 9° Kopi 168
magi_pipe_fe_reducer_centric_short_001 | Nivå D + 1,2 m | 35 | +TG=320.000.R
magi_pipe_fe_reducer_centric_short_001 | Nivå D + 1,2 m | 35 | +TG=320.000.T

# IfcFlowFitting: magi_pipe_fe_tee_centric_90_001 (69)
Type - PredefinedType: JUNCTION
ePset_Simplebim - Assembly Level: Leaf
Name | In | Insulation_thickness_mm (mm) | qv_SizingFlow_ls (m3/s) = pTot_SizingFlow_Pa (kPa) = dpTot_SizingFlow_Pa (kPa) = v_SizingFlow_ms (m/s) = ConnectionSize_mm (mm) | Splitting | Group
31 x magi_pipe_fe_tee_centric_90_001 | Nivå F - 0,7 m | 0 | 0 | ORIGINAL | +TG=332.003 (2)
8 x magi_pipe_fe_tee_centric_90_001 | Nivå F - 0,7 m | 0 | 0 | ORIGINAL | +TG=332.003 (46)
2 x magi_pipe_fe_tee_centric_90_001 | Nivå F - 0,7 m | 0 | 0 | ORIGINAL | +TG=332.003 (12)
6 x magi_pipe_fe_tee_centric_90_001 | Nivå D + 1,2 m | 0 | 0 | ORIGINAL | +TG=332.002 (1) (2)
4 x magi_pipe_fe_tee_centric_90_001 | Nivå D + 1,2 m | 0 | 0 | ORIGINAL | +TG=332.003 (10)
magi_pipe_fe_tee_centric_90_001 | Nivå F - 0,7 m | 18 | 0 | ORIGINAL | 37= T 7° Kopi 6
magi_pipe_fe_tee_centric_90_001 | Nivå F - 0,7 m | 18 | 0 | ORIGINAL | 37= R 12° Kopi 6
magi_pipe_fe_tee_centric_90_001 | Nivå F - 0,7 m | 0 | 0 | ORIGINAL | 32= R 20° Kopi 5
magi_pipe_fe_tee_centric_90_001 | Nivå F - 0,7 m | 0 | 0 | ORIGINAL | 32= R 20° Kopi 7
magi_pipe_fe_tee_centric_90_001 | Nivå D + 1,2 m | 0 | 0 | ORIGINAL | 37= T 9° Kopi 1
magi_pipe_fe_tee_centric_90_001 | Nivå D + 1,2 m | 0 | 0 | ORIGINAL | 37= R 18° Kopi 13
4 x magi_pipe_fe_tee_centric_90_001 | Nivå D + 1,2 m | 0 | 0 | ORIGINAL
magi_pipe_fe_tee_centric_90_001 | Nivå D + 1,2 m | 0 | 0 | ORIGINAL | 37= T 9° Kopi 44
magi_pipe_fe_tee_centric_90_001 | Nivå D + 1,2 m | 0 | 0 | ORIGINAL | 37= R 18° Kopi 30
3 x magi_pipe_fe_tee_centric_90_001 | Nivå D + 1,2 m | 25 | 0 | ORIGINAL
2 x magi_pipe_fe_tee_centric_90_001 | Nivå D + 1,2 m | 20 | 0 | ORIGINAL
magi_pipe_fe_tee_centric_90_001 | Nivå D + 1,2 m |  |  | RESULT | 32= R 50° Kopi 54

# IfcFlowFitting: magi_pipe_tee_centric_90_001 (27)
Type - PredefinedType: JUNCTION
MagiCAD Pset_TBranch - qv_SizingFlow_ls: 0 m3/s; pTot_SizingFlow_Pa: 0 kPa; dpTot_SizingFlow_Pa: 0 kPa; v_SizingFlow_ms: 0 m/s; ConnectionSize_mm: 0 mm
ePset_LocationTool - Splitting: ORIGINAL
ePset_Simplebim - Assembly Level: Leaf
Name | In | Insulation_thickness_mm (mm) | Group
9 x magi_pipe_tee_centric_90_001 | Nivå F - 0,7 m | 0 | 31=KV Kopi 4 (2)
3 x magi_pipe_tee_centric_90_001 | Nivå F - 0,7 m | 0 | +TG=310.002 (2)
magi_pipe_tee_centric_90_001 | Nivå F - 0,7 m | 10 | 31=KV Kopi 4 (29) (2)
9 x magi_pipe_tee_centric_90_001 | Nivå D + 1,2 m | 0 | 31=KV Kopi 4 (2)
5 x magi_pipe_tee_centric_90_001 | Nivå D + 1,2 m | 0 | +TG=310.002 (2)

# IfcFlowFitting: magi_sewer_bend_001 (62)
Type - Description: Generic PVC Bend; PredefinedType: BEND
ePset_Simplebim - Assembly Level: Leaf
MagiCAD Pset_Elbow - Description: Generic PVC Bend
Name | In | Splitting | Insulation_thickness_mm (mm) | qv_SizingFlow_ls (m3/s) = pTot_SizingFlow_Pa (kPa) = dpTot_SizingFlow_Pa (kPa) = v_SizingFlow_ms (m/s) = ConnectionSize_mm (mm) | Group
4 x magi_sewer_bend_001 | Nivå F - 0,7 m | ORIGINAL | 0 | 0 | 31= SPV Kopi 147 (11)
14 x magi_sewer_bend_001 | Nivå F - 0,7 m | ORIGINAL | 13 | 0 | 31= SPV Kopi 138
magi_sewer_bend_001 | Nivå F - 0,7 m | ORIGINAL | 0 | 0 | 31= SPV Kopi 13
magi_sewer_bend_001 | Nivå F - 0,7 m | ORIGINAL | 0 | 0
4 x magi_sewer_bend_001 | Nivå F - 0,7 m | ORIGINAL | 0 | 0 | 31= SPV Kopi 147 (1)
2 x magi_sewer_bend_001 | Nivå F - 0,7 m | ORIGINAL | 0 | 0 | 31= SPV Kopi 147 (7)
3 x magi_sewer_bend_001 | Nivå F - 0,7 m | ORIGINAL | 0 | 0 | 31= SPV Kopi 63
6 x magi_sewer_bend_001 | Nivå C | ORIGINAL | 0 | 0 | 31= SPV Kopi 63
26 x magi_sewer_bend_001 | Nivå D + 1,2 m | ORIGINAL | 13 | 0 | 31= SPV Kopi 138
magi_sewer_bend_001 | Nivå D + 1,2 m | RESULT |  |  | 31= SPV Kopi 138

# IfcFlowFitting: magi_sewer_endcap_001
In: Nivå D + 1,2 m
Type - Description: Generic PVC Plug; PredefinedType: OBSTRUCTION
MagiCAD Pset_Plug - Description: Generic PVC Plug; Insulation_thickness_mm: 0 mm; ConnectionSize_mm: 0 mm; pTot_SizingFlow_kPa: 0 kPa
ePset_LocationTool - Splitting: ORIGINAL
ePset_Simplebim - Assembly Level: Leaf
Group: 32= R 50° Kopi 56

# IfcFlowFitting: magi_sewer_tee_wye_NOR (12)
Type - PredefinedType: JUNCTION
ePset_LocationTool - Splitting: ORIGINAL
MagiCAD Pset_TBranch - qv_SizingFlow_ls: 0 m3/s; pTot_SizingFlow_Pa: 0 kPa; dpTot_SizingFlow_Pa: 0 kPa; v_SizingFlow_ms: 0 m/s; ConnectionSize_mm: 0 mm; Insulation_thickness_mm: 13 mm
ePset_Simplebim - Assembly Level: Leaf
Group: 31= SPV Kopi 138
Name | In
4 x magi_sewer_tee_wye_NOR | Nivå F - 0,7 m
8 x magi_sewer_tee_wye_NOR | Nivå D + 1,2 m

# IfcFlowFitting: magi_sewer_transition_001
In: Nivå F - 0,7 m
Type - Description: Generic PVC Reducer; PredefinedType: TRANSITION
ePset_LocationTool - Splitting: ORIGINAL
ePset_Simplebim - Assembly Level: Leaf
MagiCAD Pset_Reduction - Insulation_thickness_mm: 0 mm; qv_SizingFlow_ls: 0 m3/s; pTot_SizingFlow_Pa: 0 kPa; dpTot_SizingFlow_Pa: 0 kPa; v_SizingFlow_ms: 0 m/s; ConnectionSize_mm: 0 mm; Description: Generic PVC Reducer
Group: 31= SPV Kopi 147 (1)

# IfcFlowFitting: magi_sewer_transition_NOR (3)
Type - PredefinedType: TRANSITION
MagiCAD Pset_Reduction - qv_SizingFlow_ls: 0 m3/s; pTot_SizingFlow_Pa: 0 kPa; dpTot_SizingFlow_Pa: 0 kPa; v_SizingFlow_ms: 0 m/s; ConnectionSize_mm: 0 mm
ePset_Simplebim - Assembly Level: Leaf
ePset_LocationTool - Splitting: ORIGINAL
Name | In | Insulation_thickness_mm (mm) | Group
magi_sewer_transition_NOR | Nivå F - 0,7 m | 0 | 31= SPV Kopi 147 (11)
magi_sewer_transition_NOR | Nivå F - 0,7 m | 13 | 31= SPV Kopi 138
magi_sewer_transition_NOR | Nivå D + 1,2 m | 13 | 31= SPV Kopi 138

# IfcFlowFitting: magicirc_cross_centric_90_001
In: Nivå F - 0,7 m
Type - Description: Branch1 to left -Ok -in MRV; PredefinedType: JUNCTION
MagiCAD Pset_XBranch - Insulation_thickness_mm: 0 mm; qv_SizingFlow_ls: 0 m3/s; pTot_SizingFlow_Pa: 0 kPa; dpTot_SizingFlow_Pa: 0 kPa; v_SizingFlow_ms: 0 m/s; ConnectionSize_mm: 0 mm; Description: Branch1 to left -Ok -in MRV
ePset_LocationTool - Splitting: ORIGINAL
ePset_Simplebim - Assembly Level: Leaf
Group: +TG=360.021-22 A

# IfcFlowFitting: magicirc_elbow_full_radius_001 (60)
Type - PredefinedType: BEND
MagiCAD Pset_Elbow - qv_SizingFlow_ls: 0 m3/s; pTot_SizingFlow_Pa: 0 kPa; dpTot_SizingFlow_Pa: 0 kPa; v_SizingFlow_ms: 0 m/s; ConnectionSize_mm: 0 mm
ePset_LocationTool - Splitting: ORIGINAL
ePset_Simplebim - Assembly Level: Leaf
Name | In | Insulation_thickness_mm (mm) | Group
magicirc_elbow_full_radius_001 | Nivå C | 0 | +TG=360.021-22 A
3 x magicirc_elbow_full_radius_001 | Nivå D + 1,2 m | 0 | +TG=360.020 TL
3 x magicirc_elbow_full_radius_001 | Nivå D + 1,2 m | 25
magicirc_elbow_full_radius_001 | Nivå D + 1,2 m | 30
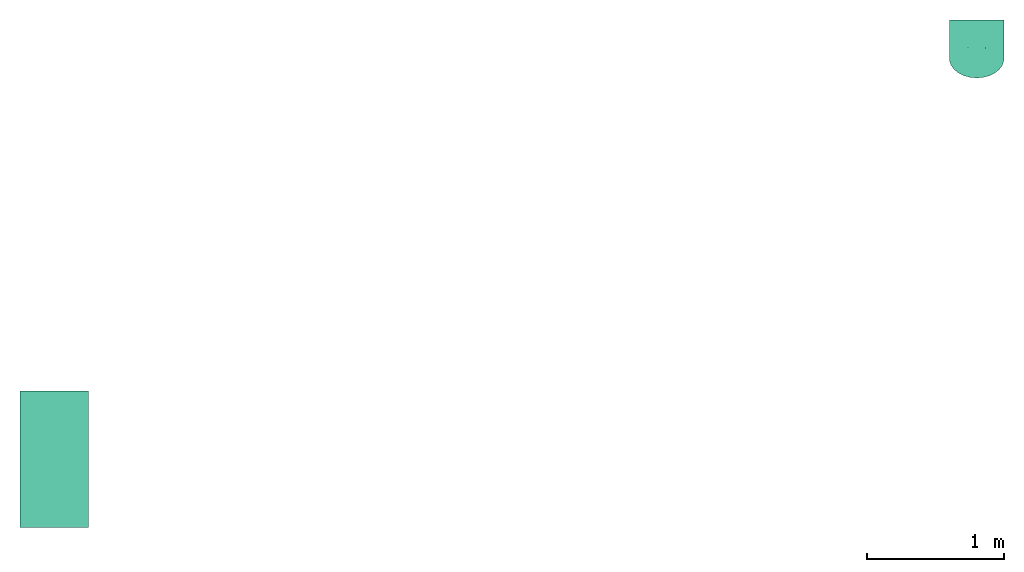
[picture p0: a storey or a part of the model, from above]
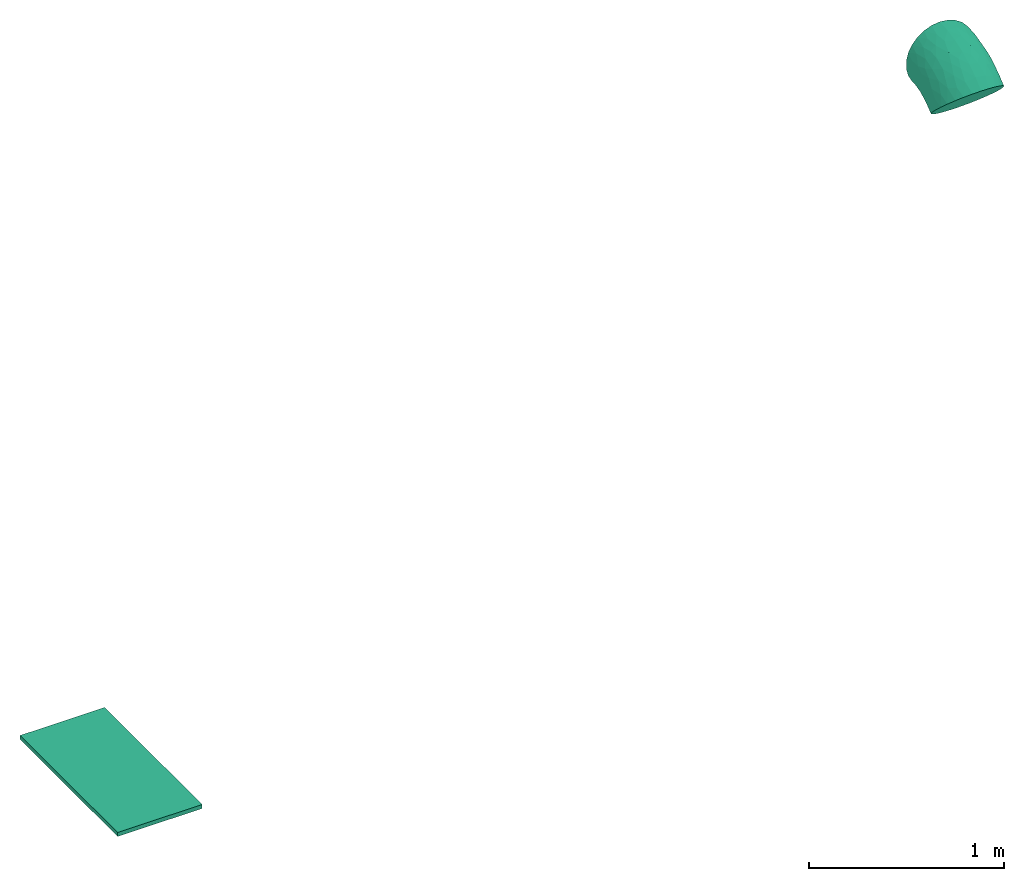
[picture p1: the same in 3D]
Properties of the parts of a building model (IFC2X3), part 7 of 11

# IfcFlowFitting: magicirc_elbow_full_radius_001 (60)
Name | In | Insulation_thickness_mm (mm) | Group
5 x magicirc_elbow_full_radius_001 | Nivå D + 1,2 m | 50
16 x magicirc_elbow_full_radius_001 | Nivå F | 0 | +TG=360.021-22 A
7 x magicirc_elbow_full_radius_001 | Nivå F | 0 | 36= Avtrekk 3
7 x magicirc_elbow_full_radius_001 | Nivå F - 0,7 m | 0 | +TG=360.021-1 TL
13 x magicirc_elbow_full_radius_001 | Nivå F - 0,7 m | 0 | +TG=360.021-22 A
3 x magicirc_elbow_full_radius_001 | Nivå F - 0,7 m | 0 | +TG=360.001 A
magicirc_elbow_full_radius_001 | Nivå F - 0,7 m | 25

# IfcFlowFitting: magicirc_elbow_short_001
In: Nivå F - 0,7 m
Type - PredefinedType: BEND
MagiCAD Pset_Elbow - Insulation_thickness_mm: 0 mm; qv_SizingFlow_ls: 0 m3/s; pTot_SizingFlow_Pa: 0 kPa; dpTot_SizingFlow_Pa: 0 kPa; v_SizingFlow_ms: 0 m/s; ConnectionSize_mm: 0 mm
ePset_Simplebim - Assembly Level: Leaf
ePset_LocationTool - Splitting: ORIGINAL
Group: +TG=360.021-1 TL

# IfcFlowFitting: magicirc_joint_001 (8)
Type - PredefinedType: CONNECTOR
MagiCAD Pset_Joint - qv_SizingFlow_ls: 0 m3/s; pTot_SizingFlow_Pa: 0 kPa; dpTot_SizingFlow_Pa: 0 kPa; v_SizingFlow_ms: 0 m/s; ConnectionSize_mm: 0 mm
ePset_Simplebim - Assembly Level: Leaf
ePset_LocationTool - Splitting: ORIGINAL
Name | In | Insulation_thickness_mm (mm)
2 x magicirc_joint_001 | Nivå D + 1,2 m | 0
magicirc_joint_001 | Nivå F | 0 | Group: +TG=360.021-22 A
magicirc_joint_001 | Nivå F - 0,7 m | 25
4 x magicirc_joint_001 | Nivå F - 0,7 m | 0

# IfcFlowFitting: magicirc_multi_shape_trans_001 (8)
Type - PredefinedType: TRANSITION
MagiCAD Pset_Reduction - Insulation_thickness_mm: 0 mm; qv_SizingFlow_ls: 0 m3/s; pTot_SizingFlow_Pa: 0 kPa; dpTot_SizingFlow_Pa: 0 kPa; v_SizingFlow_ms: 0 m/s; ConnectionSize_mm: 0 mm
ePset_LocationTool - Splitting: ORIGINAL
ePset_Simplebim - Assembly Level: Leaf
Name | In | Group
magicirc_multi_shape_trans_001 | Nivå F | Mechanical 36 Avtrekk (obsolete) 151
2 x magicirc_multi_shape_trans_001 | Nivå F | +TG=360.021-22 A
4 x magicirc_multi_shape_trans_001 | Nivå F - 0,7 m | +TG=360.021-1 TL
magicirc_multi_shape_trans_001 | Nivå F - 0,7 m | +TG=360.021-22 A

# IfcFlowFitting: magicirc_plug_001 (3)
In: Nivå F - 0,7 m
Type - PredefinedType: OBSTRUCTION
ePset_LocationTool - Splitting: ORIGINAL
ePset_Simplebim - Assembly Level: Leaf
MagiCAD Pset_Plug - Insulation_thickness_mm: 0 mm; ConnectionSize_mm: 0 mm; pTot_SizingFlow_kPa: 0 kPa
Name | Group
2 x magicirc_plug_001 | +TG=360.021-1 TL
magicirc_plug_001 | +TG=360.021-22 A

# IfcFlowFitting: magicirc_tee_centric_90_001 (10)
Type - PredefinedType: JUNCTION
MagiCAD Pset_TBranch - Insulation_thickness_mm: 0 mm; qv_SizingFlow_ls: 0 m3/s; pTot_SizingFlow_Pa: 0 kPa; dpTot_SizingFlow_Pa: 0 kPa; v_SizingFlow_ms: 0 m/s; ConnectionSize_mm: 0 mm
ePset_Simplebim - Assembly Level: Leaf
ePset_LocationTool - Splitting: ORIGINAL
Name | In | Group
magicirc_tee_centric_90_001 | Nivå F | 36= Avtrekk 3 | MagiCAD Pset_TBranch - National code: VB2.124212
2 x magicirc_tee_centric_90_001 | Nivå F | +TG=360.021-22 A
3 x magicirc_tee_centric_90_001 | Nivå F - 0,7 m | +TG=360.021-1 TL
2 x magicirc_tee_centric_90_001 | Nivå F - 0,7 m | +TG=360.021-22 A
2 x magicirc_tee_centric_90_001 | Nivå F - 0,7 m | +TG=360.001 A

# IfcFlowFitting: magirect_elbow1_001 (2)
In: Nivå D + 1,2 m
Type - PredefinedType: BEND
MagiCAD Pset_Elbow - qv_SizingFlow_ls: 0 m3/s; pTot_SizingFlow_Pa: 0 kPa; dpTot_SizingFlow_Pa: 0 kPa; v_SizingFlow_ms: 0 m/s; ConnectionSize_mm: 0 mm
ePset_LocationTool - Splitting: ORIGINAL
ePset_Simplebim - Assembly Level: Leaf
Name | Insulation_thickness_mm (mm)
magirect_elbow1_001 | 0 | Group: +TG=360.021-1 TL
magirect_elbow1_001 | 25

# IfcFlowFitting: magirect_outlet1_001 2 (3)
In: Nivå F - 0,7 m
Type - PredefinedType: CONNECTOR
ePset_LocationTool - Splitting: ORIGINAL
ePset_Simplebim - Assembly Level: Leaf
Group: +TG=360.021-1 TL

# IfcFlowFitting: magirect_plug1_001 (4)
Type - PredefinedType: OBSTRUCTION
ePset_Simplebim - Assembly Level: Leaf
MagiCAD Pset_Plug - Insulation_thickness_mm: 0 mm; ConnectionSize_mm: 0 mm; pTot_SizingFlow_kPa: 0 kPa
ePset_LocationTool - Splitting: ORIGINAL
Group: +TG=360.021-1 TL
Name | In
magirect_plug1_001 | Nivå C
3 x magirect_plug1_001 | Nivå F - 0,7 m

# IfcFlowFitting: magirect_reduction1_001 (2)
Type - PredefinedType: TRANSITION
MagiCAD Pset_Reduction - Insulation_thickness_mm: 0 mm; qv_SizingFlow_ls: 0 m3/s; pTot_SizingFlow_Pa: 0 kPa; dpTot_SizingFlow_Pa: 0 kPa; v_SizingFlow_ms: 0 m/s; ConnectionSize_mm: 0 mm
ePset_Simplebim - Assembly Level: Leaf
ePset_LocationTool - Splitting: ORIGINAL
Name | In | Group
magirect_reduction1_001 | Nivå D + 1,2 m | +TG=360.021-1 TL
magirect_reduction1_001 | Nivå F | +TG=360.021-22 A

# IfcFlowFitting: magirect_tbranch1_001 (2)
In: Nivå F
Type - PredefinedType: JUNCTION
MagiCAD Pset_TBranch - Insulation_thickness_mm: 0 mm; qv_SizingFlow_ls: 0 m3/s; pTot_SizingFlow_Pa: 0 kPa; dpTot_SizingFlow_Pa: 0 kPa; v_SizingFlow_ms: 0 m/s; ConnectionSize_mm: 0 mm
ePset_LocationTool - Splitting: ORIGINAL
ePset_Simplebim - Assembly Level: Leaf
Group: +TG=360.021-22 A

# IfcFlowFitting: magirect_xbranch1_001
In: Nivå D + 1,2 m
Type - Description: Branch1 to Right; PredefinedType: JUNCTION
ePset_LocationTool - Splitting: ORIGINAL
MagiCAD Pset_XBranch - Insulation_thickness_mm: 0 mm; qv_SizingFlow_ls: 0 m3/s; pTot_SizingFlow_Pa: 0 kPa; dpTot_SizingFlow_Pa: 0 kPa; v_SizingFlow_ms: 0 m/s; ConnectionSize_mm: 0 mm; Description: Branch1 to Right
ePset_Simplebim - Assembly Level: Leaf
Group: +TG=360.021-1 TL

# IfcFlowMovingDevice: K 125 M Circular duct fan
In: Nivå F
Type - Description: Circular Duct Fan
MagiCAD Pset_Fan - Manufacturer: Systemair; qv_SizingFlow_ls: 0 m3/s; Product Code: K 125 M Circular duct fan; Description: Circular Duct Fan
ePset_LocationTool - Splitting: ORIGINAL
ePset_Simplebim - Assembly Level: Leaf
Group: 36= Avtrekk 3

# IfcFlowMovingDevice: K 160 XL Circular duct fan
In: Nivå F - 0,7 m
Type - Description: Circular Duct Fan
MagiCAD Pset_Fan - Product Code: K 160 XL Circular duct fan; Manufacturer: Systemair; qv_SizingFlow_ls: 0 m3/s; Description: Circular Duct Fan
ePset_LocationTool - Splitting: ORIGINAL
ePset_Simplebim - Assembly Level: Leaf
Group: +TG=360.001 A

# IfcFlowSegment: 1-REKT (16)
Type - Description: Rektangulære, Forsinket stål; PredefinedType: RIGIDSEGMENT
ePset_Simplebim - Assembly Level: Leaf
MagiCAD Pset_Duct - Description: Rektangulære, Forsinket stål; UserCode: 1-REKT
Name | In | Splitting | Length (Simplebim) (mm) | Height (Simplebim) (mm) | Width (Simplebim) (mm) | Length_mm (mm) | qv_SizingFlow_ls (m3/s) = dpTot_SizingFlow_Pa (kPa) = pTot_SizingFlow_Pa (kPa) = v_SizingFlow_ms (m/s) | Insulation_thickness_mm (mm) | Group
1-REKT | Nivå D + 1,2 m | ORIGINAL | 740.3 | 300 | 500 | 740.323 | 0 | 25
1-REKT | Nivå D + 1,2 m | ORIGINAL | 500 | 300 | 132.5 | 132.5 | 0 | 30
1-REKT | Nivå D + 1,2 m | ORIGINAL | 742.5 | 300 | 500 | 742.5 | 0 | 25
1-REKT | Nivå D + 1,2 m | ORIGINAL | 400 | 138.9 | 300 | 138.9 | 0 | 0 | +TG=360.021-1 TL
1-REKT | Nivå D + 1,2 m | ORIGINAL | 2455.3 | 400 | 300 | 2455.31 | 0 | 0 | +TG=360.021-1 TL
1-REKT | Nivå D + 1,2 m | ORIGINAL | 350 | 281.2 | 350 | 281.186 | 0 | 0 | +TG=360.021-1 TL
1-REKT | Nivå F | ORIGINAL | 2489.1 | 400 | 300 | 2489.14 | 0 | 0 | +TG=360.021-22 A
1-REKT | Nivå F | ORIGINAL | 941.8 | 400 | 300 | 941.769 | 0 | 0 | +TG=360.021-22 A
1-REKT | Nivå F - 0,7 m | ORIGINAL | 300 | 200 | 110 | 110 | 0 | 0 | +TG=360.021-1 TL
1-REKT | Nivå F - 0,7 m | ORIGINAL | 1070 | 100 | 200 | 1070 | 0 | 0 | +TG=360.021-1 TL
1-REKT | Nivå F - 0,7 m | ORIGINAL | 300 | 250 | 40 | 40 | 0 | 0 | +TG=360.021-1 TL
1-REKT | Nivå F - 0,7 m | ORIGINAL | 1200 | 692.5 | 150 | 692.5 | 0 | 0 | +TG=360.021-1 TL
1-REKT | Nivå F - 0,7 m | ORIGINAL | 400 | 150 | 194.2 | 194.188 | 0 | 0 | +TG=360.021-1 TL
1-REKT | Nivå F - 0,7 m | ORIGINAL | 1205 | 400 | 150 | 1205 | 0 | 0 | +TG=360.021-1 TL
1-REKT | Nivå D + 1,2 m | RESULT | 5878 | 338 | 1000 |  |  |  | +TG=360.021-1 TL
1-REKT | Nivå D + 1,2 m | RESULT | 745 | 400 | 300 |  |  |  | +TG=360.021-1 TL

# IfcFlowSegment: 2 - Spiro kanaler, Forsinket stål (46)
Type - Description: Spiro kanaler, Forsinket stål; PredefinedType: RIGIDSEGMENT
MagiCAD Pset_Duct - UserCode: Circ; Description: Spiro kanaler, Forsinket stål
ePset_Simplebim - Assembly Level: Leaf
Name | In | Splitting | qv_SizingFlow_ls (m3/s) = dpTot_SizingFlow_Pa (kPa) = pTot_SizingFlow_Pa (kPa) = v_SizingFlow_ms (m/s) | Insulation_thickness_mm (mm) | Length_mm (mm) | Height (Simplebim) (mm) | Width (Simplebim) (mm) | Length (Simplebim) (mm) | Group
2 - Spiro kanaler, Forsinket stål | Nivå D + 1,2 m | ORIGINAL | 0 | 0 | 578.967 | 400 | 400 | 579 | +TG=360.021-22 A
2 - Spiro kanaler, Forsinket stål | Nivå D + 1,2 m | ORIGINAL | 0 | 0 | 211.45 | 400 | 400 | 211.5 | +TG=360.020 TL
2 - Spiro kanaler, Forsinket stål | Nivå D + 1,2 m | ORIGINAL | 0 | 0 | 31.802 | 400 | 400 | 31.8 | +TG=360.020 TL
2 - Spiro kanaler, Forsinket stål | Nivå D + 1,2 m | ORIGINAL | 0 | 30 | 644.376 | 160 | 160 | 644.4
3 x 2 - Spiro kanaler, Forsinket stål | Nivå D + 1,2 m | ORIGINAL | 0 | 50 | 455 | 160 | 160 | 455
2 - Spiro kanaler, Forsinket stål | Nivå D + 1,2 m | ORIGINAL | 0 | 25 | 410 | 160 | 160 | 410
2 - Spiro kanaler, Forsinket stål | Nivå D + 1,2 m | ORIGINAL | 0 | 25 | 395 | 160 | 160 | 395
2 - Spiro kanaler, Forsinket stål | Nivå D + 1,2 m | ORIGINAL | 0 | 0 | 311.772 | 311.7 | 400 | 400 | +TG=360.020 TL
2 - Spiro kanaler, Forsinket stål | Nivå D + 1,2 m | ORIGINAL | 0 | 30 | 639.971 | 160 | 160 | 640
2 - Spiro kanaler, Forsinket stål | Nivå F | ORIGINAL | 0 | 0 | 10.287 | 200 | 200 | 10.3 | +TG=360.021-22 A
2 - Spiro kanaler, Forsinket stål | Nivå F | ORIGINAL | 0 | 0 | 1293.31 | 250 | 250 | 1293.3 | +TG=360.021-22 A
2 - Spiro kanaler, Forsinket stål | Nivå F | ORIGINAL | 0 | 0 | 1639.36 | 250 | 250 | 1639.4 | +TG=360.021-22 A
2 - Spiro kanaler, Forsinket stål | Nivå F | ORIGINAL | 0 | 0 | 65.366 | 250 | 250 | 65.4 | +TG=360.021-22 A
2 - Spiro kanaler, Forsinket stål | Nivå F | ORIGINAL | 0 | 0 | 1855.24 | 250 | 250 | 1855.2 | +TG=360.021-22 A
2 - Spiro kanaler, Forsinket stål | Nivå F | ORIGINAL | 0 | 0 | 157.566 | 250 | 250 | 157.6 | +TG=360.021-22 A
2 - Spiro kanaler, Forsinket stål | Nivå F | ORIGINAL | 0 | 0 | 1653.94 | 250 | 250 | 1653.9 | +TG=360.021-22 A
2 - Spiro kanaler, Forsinket stål | Nivå F | ORIGINAL | 0 | 0 | 349.858 | 250 | 250 | 350 | +TG=360.021-22 A
2 - Spiro kanaler, Forsinket stål | Nivå F | ORIGINAL | 0 | 0 | 60 | 60 | 160 | 160 | +TG=360.021-22 A
2 - Spiro kanaler, Forsinket stål | Nivå F | ORIGINAL | 0 | 0 | 160.406 | 160 | 160 | 160 | +TG=360.021-22 A
2 - Spiro kanaler, Forsinket stål | Nivå F | ORIGINAL | 0 | 0 | 206.82 | 160 | 160 | 206.8 | +TG=360.021-22 A
2 - Spiro kanaler, Forsinket stål | Nivå F | ORIGINAL | 0 | 0 | 183.036 | 160 | 160 | 183 | +TG=360.021-22 A
2 - Spiro kanaler, Forsinket stål | Nivå F | ORIGINAL | 0 | 0 | 304.739 | 160 | 160 | 304.7 | +TG=360.021-22 A
2 - Spiro kanaler, Forsinket stål | Nivå F | ORIGINAL | 0 | 0 | 45 | 45 | 250 | 250 | +TG=360.021-22 A
2 - Spiro kanaler, Forsinket stål | Nivå F | ORIGINAL | 0 | 0 | 12.213 | 200 | 200 | 12.2 | +TG=360.021-22 A
2 - Spiro kanaler, Forsinket stål | Nivå F | ORIGINAL | 0 | 0 | 13.046 | 200 | 200 | 13 | +TG=360.021-22 A
2 - Spiro kanaler, Forsinket stål | Nivå F | ORIGINAL | 0 | 0 | 12.242 | 200 | 200 | 12.2 | +TG=360.021-22 A
2 - Spiro kanaler, Forsinket stål | Nivå F | ORIGINAL | 0 | 0 | 58.849 | 200 | 200 | 58.8 | +TG=360.021-22 A
2 - Spiro kanaler, Forsinket stål | Nivå F | ORIGINAL | 0 | 0 | 208.849 | 200 | 200 | 208.8 | +TG=360.021-22 A
2 - Spiro kanaler, Forsinket stål | Nivå F - 0,7 m | ORIGINAL | 0 | 25 | 302.444 | 160 | 160 | 302.4
2 x 2 - Spiro kanaler, Forsinket stål | Nivå F - 0,7 m | ORIGINAL | 0 | 0 | 340 | 160 | 160 | 340
2 - Spiro kanaler, Forsinket stål | Nivå F - 0,7 m | ORIGINAL | 0 | 0 | 335 | 160 | 160 | 335
2 - Spiro kanaler, Forsinket stål | Nivå F - 0,7 m | ORIGINAL | 0 | 25 | 290 | 160 | 160 | 290
2 - Spiro kanaler, Forsinket stål | Nivå F - 0,7 m | ORIGINAL | 0 | 0 | 312.556 | 160 | 160 | 313.2
2 - Spiro kanaler, Forsinket stål | Nivå F - 0,7 m | ORIGINAL | 0 | 0 | 315 | 160 | 160 | 315
2 - Spiro kanaler, Forsinket stål | Nivå F - 0,7 m | ORIGINAL | 0 | 30 | 327.5 | 160 | 160 | 327.8
2 - Spiro kanaler, Forsinket stål | Nivå F - 0,7 m | ORIGINAL | 0 | 50 | 315 | 160 | 160 | 315
2 - Spiro kanaler, Forsinket stål | Nivå F - 0,7 m | ORIGINAL | 0 | 50 | 320 | 160 | 160 | 320
2 - Spiro kanaler, Forsinket stål | Nivå D + 1,2 o | ORIGINAL | 0 | 0 | 277.869 | 400 | 400 | 277.9 | +TG=360.020 TL
2 - Spiro kanaler, Forsinket stål | Nivå D + 1,2 m | RESULT |  |  |  | 376 | 400 | 1753 | +TG=360.021-22 A
2 - Spiro kanaler, Forsinket stål | Nivå D + 1,2 m | RESULT |  |  |  | 300 | 400 | 628 | +TG=360.020 TL
2 - Spiro kanaler, Forsinket stål | Nivå D + 1,2 m | RESULT |  |  |  | 335 | 400 | 1925
2 - Spiro kanaler, Forsinket stål | Nivå D + 1,2 m | RESULT |  |  |  | 308 | 400 | 400 | +TG=360.020 TL
2 - Spiro kanaler, Forsinket stål | Nivå D + 1,2 m | RESULT |  |  |  | 283 | 283 | 400 | +TG=360.021-22 A

# IfcFlowSegment: 4 - Spiro kanaler, korte bend (68)
Type - Description: Spiro kanaler, korte bend; PredefinedType: RIGIDSEGMENT
ePset_LocationTool - Splitting: ORIGINAL
MagiCAD Pset_Duct - Description: Spiro kanaler, korte bend; UserCode: Circ; qv_SizingFlow_ls: 0 m3/s; dpTot_SizingFlow_Pa: 0 kPa; pTot_SizingFlow_Pa: 0 kPa; v_SizingFlow_ms: 0 m/s; Insulation_thickness_mm: 0 mm
ePset_Simplebim - Assembly Level: Leaf
Name | In | Length_mm (mm) | Height (Simplebim) (mm) | Width (Simplebim) (mm) | Length (Simplebim) (mm) | Group
3 x 4 - Spiro kanaler, korte bend | Nivå F | 174.901 | 125 | 125 | 175 | 36= Avtrekk 3
4 - Spiro kanaler, korte bend | Nivå F | 267.698 | 125 | 125 | 267.7 | 36= Avtrekk 3
4 - Spiro kanaler, korte bend | Nivå F | 161.858 | 125 | 125 | 161.9 | 36= Avtrekk 3
4 - Spiro kanaler, korte bend | Nivå F | 71.349 | 125 | 125 | 71 | 36= Avtrekk 3
4 - Spiro kanaler, korte bend | Nivå F | 108.849 | 125 | 125 | 108.8 | 36= Avtrekk 3
4 - Spiro kanaler, korte bend | Nivå F | 291.142 | 125 | 125 | 291.1 | 36= Avtrekk 3
4 - Spiro kanaler, korte bend | Nivå F | 127.279 | 125 | 125 | 127.3 | 36= Avtrekk 3
4 - Spiro kanaler, korte bend | Nivå F | 198.058 | 125 | 125 | 198.1 | 36= Avtrekk 3
4 - Spiro kanaler, korte bend | Nivå F | 200.503 | 125 | 125 | 200.5 | 36= Avtrekk 3
4 - Spiro kanaler, korte bend | Nivå F | 714.112 | 125 | 125 | 714.1 | 36= Avtrekk 3
4 - Spiro kanaler, korte bend | Nivå F | 101.878 | 100 | 100 | 101.9 | +TG=360.021-22 A
4 - Spiro kanaler, korte bend | Nivå F | 455.731 | 100 | 100 | 455.7 | +TG=360.021-22 A
4 - Spiro kanaler, korte bend | Nivå F | 158.104 | 100 | 100 | 158.1 | +TG=360.021-22 A
4 - Spiro kanaler, korte bend | Nivå F | 350.255 | 100 | 100 | 350.3 | +TG=360.021-22 A
4 - Spiro kanaler, korte bend | Nivå F | 104.807 | 100 | 100 | 104.8 | +TG=360.021-22 A
4 - Spiro kanaler, korte bend | Nivå F | 615.416 | 100 | 100 | 615.4 | +TG=360.021-22 A
4 - Spiro kanaler, korte bend | Nivå F | 156.838 | 100 | 100 | 156.8 | +TG=360.021-22 A
4 - Spiro kanaler, korte bend | Nivå F | 160 | 100 | 100 | 160 | +TG=360.021-22 A
4 - Spiro kanaler, korte bend | Nivå F - 0,7 m | 12.904 | 200 | 200 | 13 | +TG=360.021-1 TL
4 - Spiro kanaler, korte bend | Nivå F - 0,7 m | 39.294 | 39.3 | 200 | 200 | +TG=360.021-1 TL
4 - Spiro kanaler, korte bend | Nivå F - 0,7 m | 661.788 | 160 | 160 | 661.8 | +TG=360.021-1 TL
4 - Spiro kanaler, korte bend | Nivå F - 0,7 m | 360 | 160 | 160 | 360 | +TG=360.021-1 TL
4 - Spiro kanaler, korte bend | Nivå F - 0,7 m | 403.575 | 160 | 160 | 403.6 | +TG=360.021-1 TL
4 - Spiro kanaler, korte bend | Nivå F - 0,7 m | 151.757 | 160 | 160 | 151.8 | +TG=360.021-1 TL
4 - Spiro kanaler, korte bend | Nivå F - 0,7 m | 63.455 | 100 | 100 | 63.5 | +TG=360.021-1 TL
4 - Spiro kanaler, korte bend | Nivå F - 0,7 m | 320.773 | 200 | 200 | 320.8 | +TG=360.021-1 TL
4 - Spiro kanaler, korte bend | Nivå F - 0,7 m | 235.92 | 100 | 100 | 235.9 | +TG=360.021-1 TL
4 - Spiro kanaler, korte bend | Nivå F - 0,7 m | 733.44 | 100 | 100 | 733.4 | +TG=360.021-1 TL
4 - Spiro kanaler, korte bend | Nivå F - 0,7 m | 340.485 | 200 | 200 | 340.5 | +TG=360.021-1 TL
2 x 4 - Spiro kanaler, korte bend | Nivå F - 0,7 m | 67.5 | 250 | 250 | 67.5 | +TG=360.021-1 TL
4 - Spiro kanaler, korte bend | Nivå F - 0,7 m | 1396.22 | 250 | 250 | 1396.2 | +TG=360.021-1 TL
4 - Spiro kanaler, korte bend | Nivå F - 0,7 m | 606.025 | 250 | 250 | 606 | +TG=360.021-1 TL
4 - Spiro kanaler, korte bend | Nivå F - 0,7 m | 971.577 | 250 | 250 | 971.6 | +TG=360.021-1 TL
4 - Spiro kanaler, korte bend | Nivå F - 0,7 m | 49 | 160 | 160 | 49 | +TG=360.021-1 TL
4 - Spiro kanaler, korte bend | Nivå F - 0,7 m | 66.79 | 250 | 250 | 66.8 | +TG=360.021-1 TL
4 - Spiro kanaler, korte bend | Nivå F - 0,7 m | 333.97 | 160 | 160 | 334 | +TG=360.021-1 TL
4 - Spiro kanaler, korte bend | Nivå F - 0,7 m | 2335.37 | 100 | 100 | 2335.4 | +TG=360.021-22 A
4 - Spiro kanaler, korte bend | Nivå F - 0,7 m | 373.827 | 100 | 100 | 373.8 | +TG=360.021-22 A
4 - Spiro kanaler, korte bend | Nivå F - 0,7 m | 11.249 | 200 | 11.2 | 200 | +TG=360.021-22 A
4 - Spiro kanaler, korte bend | Nivå F - 0,7 m | 223.006 | 100 | 100 | 223 | +TG=360.021-22 A
4 - Spiro kanaler, korte bend | Nivå F - 0,7 m | 438.579 | 100 | 100 | 438.6 | +TG=360.021-22 A
4 - Spiro kanaler, korte bend | Nivå F - 0,7 m | 154.982 | 100 | 100 | 155 | +TG=360.021-22 A
4 - Spiro kanaler, korte bend | Nivå F - 0,7 m | 78.683 | 78.7 | 100 | 100 | +TG=360.021-22 A
4 - Spiro kanaler, korte bend | Nivå F - 0,7 m | 83.239 | 83.2 | 100 | 100 | +TG=360.021-22 A
4 - Spiro kanaler, korte bend | Nivå F - 0,7 m | 14.573 | 100 | 100 | 14.6 | +TG=360.021-22 A
4 - Spiro kanaler, korte bend | Nivå F - 0,7 m | 179.63 | 100 | 100 | 180.2 | +TG=360.021-22 A
4 - Spiro kanaler, korte bend | Nivå F - 0,7 m | 189.26 | 100 | 100 | 189.3 | +TG=360.021-22 A
4 - Spiro kanaler, korte bend | Nivå F - 0,7 m | 112.13 | 100 | 100 | 111.9 | +TG=360.021-22 A
4 - Spiro kanaler, korte bend | Nivå F - 0,7 m | 223.8 | 100 | 100 | 223.8 | +TG=360.021-22 A
4 - Spiro kanaler, korte bend | Nivå F - 0,7 m | 35.837 | 35.8 | 100 | 100 | +TG=360.021-22 A
4 - Spiro kanaler, korte bend | Nivå F - 0,7 m | 242.558 | 100 | 100 | 242.6 | +TG=360.021-22 A
4 - Spiro kanaler, korte bend | Nivå F - 0,7 m | 437.647 | 100 | 100 | 437.6 | +TG=360.021-22 A
4 - Spiro kanaler, korte bend | Nivå F - 0,7 m | 245.284 | 100 | 100 | 245.3 | +TG=360.021-22 A
4 - Spiro kanaler, korte bend | Nivå F - 0,7 m | 107.365 | 100 | 100 | 107.4 | +TG=360.021-22 A
4 - Spiro kanaler, korte bend | Nivå F - 0,7 m | 1179.26 | 100 | 100 | 1179.3 | +TG=360.021-22 A
4 - Spiro kanaler, korte bend | Nivå F - 0,7 m | 425.23 | 160 | 160 | 425.2 | +TG=360.001 A
4 - Spiro kanaler, korte bend | Nivå F - 0,7 m | 248.718 | 160 | 160 | 248.7 | +TG=360.001 A
4 - Spiro kanaler, korte bend | Nivå F - 0,7 m | 41.281 | 160 | 160 | 41 | +TG=360.001 A
4 - Spiro kanaler, korte bend | Nivå F - 0,7 m | 160.211 | 160 | 160 | 160 | +TG=360.001 A
4 - Spiro kanaler, korte bend | Nivå F - 0,7 m | 109.414 | 109 | 160 | 160 | +TG=360.001 A
4 - Spiro kanaler, korte bend | Nivå F - 0,7 m | 60.211 | 60 | 160 | 160 | +TG=360.001 A
4 - Spiro kanaler, korte bend | Nivå F - 0,7 m | 628.809 | 160 | 160 | 628.8 | +TG=360.001 A
4 - Spiro kanaler, korte bend | Nivå F - 0,7 m | 628.805 | 160 | 160 | 628.8 | +TG=360.001 A
4 - Spiro kanaler, korte bend | Nivå F - 0,7 m | 726.803 | 160 | 160 | 726.8 | +TG=360.001 A
4 - Spiro kanaler, korte bend | Nivå F - 0,7 m | 187.166 | 160 | 160 | 186.7 | +TG=360.001 A

# IfcFlowSegment: Conduit (30)
In: Nivå D + 1,2
Type - PredefinedType: CONDUITSEGMENT
ePset_Simplebim - Assembly Level: Leaf
AVINOR - 07_Fase: F90; 04_Kontrakt: FDV; 08_Status: S2; ID-nummer2: +TO=411.501; 05_ID-nummer: +TO=411.501; 06_Omrade: TG; 03_Ansvar: T20100; 02_Prosjekt: 72101; 01_Lufthavnkode: ENGM
Group: Trekkerør generelt
Name | Splitting | Height (Simplebim) (mm) = Width (Simplebim) (mm) | Length (Simplebim) (mm)
10 x Conduit | ORIGINAL | 25 | 1095
10 x Conduit | ORIGINAL | 25 | 3650
10 x Conduit | RESULT | 24 | 915

# IfcFlowSegment: Kabelbane (28)
Type - PredefinedType: CABLETRAYSEGMENT
Pset_CableCarrierSegmentTypeCableTraySegment - HasCover: yes
ePset_Simplebim - Assembly Level: Leaf
AVINOR - 07_Fase: F90; 06_Omrade: TG; 01_Lufthavnkode: ENGM
Name | In | Length [mm] (mm) = NominalLength (mm) | Height [mm] (mm) = NominalHeight (mm) | Width [mm] (mm) = NominalWidth (mm) | System code | Splitting | Length (Simplebim) (mm) | Height (Simplebim) (mm) | Width (Simplebim) (mm) | 04_Kontrakt | 08_Status | ID-nummer2 = 05_ID-nummer | 03_Ansvar | 02_Prosjekt | Group
Kabelbane | Nivå D + 1,2 | 6534.99 | 100 | 350 | 4115 | ORIGINAL | 6534.99 | 100 | 350 | FDV | S2 | +TO=411.501 | T20100 | 72101 | Gulvkanal
Kabelbane | Nivå D + 1,2 | 5099.01 | 100 | 350 | 4115 | ORIGINAL | 5099.01 | 100 | 350 | FDV | S2 | +TO=411.501 | T20100 | 72101 | Gulvkanal
Kabelbane | Nivå D + 1,2 | 790 | 100 | 350 | 4115 | ORIGINAL | 790 | 100 | 350 | FDV | S2 | +TO=411.501 | T20100 | 72101 | Gulvkanal
5 x Kabelbane | Nivå D + 1,2 | 2560.03 | 100 | 350 | 4115 | ORIGINAL | 2560.03 | 100 | 350 | FDV | S2 | +TO=411.501 | T20100 | 72101 | Gulvkanal
2 x Kabelbane | Nivå D + 1,2 | 2539.97 | 100 | 350 | 4115 | ORIGINAL | 2539.97 | 100 | 350 | FDV | S2 | +TO=411.501 | T20100 | 72101 | Gulvkanal
3 x Kabelbane | Nivå D + 1,2 | 2550 | 100 | 350 | 4115 | ORIGINAL | 2550 | 100 | 350 | FDV | S2 | +TO=411.501 | T20100 | 72101 | Gulvkanal
Kabelbane | Nivå D + 1,2 | 467.5 | 100 | 350 | 4115 | ORIGINAL | 467.5 | 100 | 350 | FDV | S2 | +TO=411.501 | T20100 | 72101 | Gulvkanal
Kabelbane | Nivå D + 1,2 | 50 | 100 | 350 | 4115 | ORIGINAL | 350 | 100 | 50 | FDV | S2 | +TO=411.501 | T20100 | 72101 | Gulvkanal
5 x Kabelbane | Nivå F - 0,7 | 5000 | 45 | 45 | 4113. | ORIGINAL | 5000 | 45 | 45 | 183766 | S4 | +TO=411.001 | 181608 | A162446 | Armaturskinne
Kabelbane | Nivå F - 0,7 | 1982.06 | 45 | 45 | 4113. | ORIGINAL | 1982.06 | 45 | 45 | 183766 | S4 | +TO=411.001 | 181608 | A162446 | Armaturskinne
2 x Kabelbane | Nivå F - 0,7 | 6400 | 45 | 45 | 4113. | ORIGINAL | 6400 | 45 | 45 | 183766 | S4 | +TO=411.001 | 181608 | A162446 | Armaturskinne
Kabelbane | Nivå F - 0,7 | 10363.8 | 45 | 45 | 4113. | ORIGINAL | 10363.8 | 45 | 45 | 183766 | S4 | +TO=411.001 | 181608 | A162446 | Armaturskinne
2 x Kabelbane | Nivå D + 1,2 |  |  |  | 4115 | RESULT | 3490 | 100 | 350 | FDV | S2 | +TO=411.501 | T20100 | 72101 | Gulvkanal
2 x Kabelbane | Nivå D + 1,2 |  |  |  | 4115 | RESULT | 1344 | 100 | 350 | FDV | S2 | +TO=411.501 | T20100 | 72101 | Gulvkanal

# IfcFlowSegment: Kabelbro (25)
Type - PredefinedType: CABLELADDERSEGMENT
ePset_Simplebim - Assembly Level: Leaf
AVINOR - 05_ID-nummer: +TO=411.501; 06_Omrade: TG; 01_Lufthavnkode: ENGM
Name | In | System code | Length [mm] (mm) = NominalLength (mm) | Height [mm] (mm) = NominalHeight (mm) | Width [mm] (mm) = NominalWidth (mm) | Splitting | Width (Simplebim) (mm) | Height (Simplebim) (mm) | Length (Simplebim) (mm) | 07_Fase | 04_Kontrakt | 08_Status | ID-nummer2 | 03_Ansvar | 02_Prosjekt | Group
Kabelbro | Nivå D + 1,2 | 4111 | 148.924 | 50 | 600 | ORIGINAL | 148.924 | 50 | 600 | F90 | FDV | S2 | +TO=411.501 | T20100 | 72101 | Bæresystem for elkraft
Kabelbro | Nivå D + 1,2 | 4111 | 240 | 50 | 600 | ORIGINAL | 240 | 50 | 600 | F90 | FDV | S2 | +TO=411.501 | T20100 | 72101 | Bæresystem for elkraft
Kabelbro | Nivå D + 1,2 | 4111 | 2777.78 | 50 | 600 | ORIGINAL | 600 | 50 | 2777.78 | F90 | FDV | S2 | +TO=411.501 | T20100 | 72101 | Bæresystem for elkraft
Kabelbro | Nivå D + 1,2 | 4111 | 824.661 | 50 | 300 | ORIGINAL | 300 | 50 | 824.661 | F90 | FDV | S2 | +TO=411.501 | T20100 | 72101 | Bæresystem for elkraft
Kabelbro | Nivå D + 1,2 | 4111 | 714.771 | 50 | 300 | ORIGINAL | 300 | 50 | 714.771 | F90 | FDV | S2 | +TO=411.501 | T20100 | 72101 | Bæresystem for elkraft
Kabelbro | Nivå D + 1,2 | 4111 | 416.045 | 50 | 300 | ORIGINAL | 300 | 50 | 416.045 | F90 | FDV | S2 | +TO=411.001 | T20100 | 72101 | Bæresystem for elkraft
Kabelbro | Nivå D + 1,2 | 4111 | 355 | 50 | 600 | ORIGINAL | 354.599 | 50 | 600 | F90 | FDV | S2 | +TO=411.501 | T20100 | 72101 | Bæresystem for elkraft
Kabelbro | Nivå D + 1,2 | 4111 | 2069.53 | 50 | 600 | ORIGINAL | 600 | 50 | 2069.53 | F90 | FDV | S2 | +TO=411.501 | T20100 | 72101 | Bæresystem for elkraft
Kabelbro | Nivå F | 4111 | 5000 | 50 | 600 | ORIGINAL | 600 | 50 | 5000 | A | 188899 | S4 |  | 187259 | 10004890 | Bæresystem for elkraft | AVINOR - 09_Arbeidspakke: K0G-Nivå D + 1,2
Kabelbro | Nivå F | 4111 | 2163.56 | 50 | 600 | ORIGINAL | 600 | 50 | 2163.56 | A | 188899 | S4 |  | 187259 | 10004890 | Bæresystem for elkraft | AVINOR - 09_Arbeidspakke: K0G-Nivå D + 1,2
Kabelbro | Nivå F - 0,7 | 410 | 9040 | 60 | 600 | ORIGINAL | 600 | 60 | 9040 | F90 | FDV | S2 | +TO=411.501 | T20100 | 72101 | Bæresystem generelt
2 x Kabelbro | Nivå F - 0,7 | 410 | 2800 | 60 | 600 | ORIGINAL | 60 | 600 | 2800 | F90 | FDV | S2 | +TO=411.501 | T20100 | 72101 | Bæresystem generelt
Kabelbro | Nivå F - 0,7 | 410 | 12860 | 50 | 600 | ORIGINAL | 600 | 50 | 12860 | F90 | FDV | S2 | +TO=411.501 | T20100 | 72101 | Bæresystem generelt
Kabelbro | Nivå F - 0,7 | 410 | 1620 | 50 | 600 | ORIGINAL | 600 | 50 | 1620 | F90 | FDV | S2 | +TO=411.501 | T20100 | 72101 | Bæresystem generelt
Kabelbro | Nivå F - 0,7 | 410 | 1160 | 50 | 600 | ORIGINAL | 600 | 50 | 1160 | F90 | FDV | S2 | +TO=411.501 | T20100 | 72101 | Bæresystem generelt
Kabelbro | Nivå F - 0,7 | 410 | 1100 | 50 | 600 | ORIGINAL | 600 | 50 | 1100 | F90 | FDV | S2 | +TO=411.501 | T20100 | 72101 | Bæresystem generelt
Kabelbro | Nivå F - 0,7 | 410 | 80 | 50 | 600 | ORIGINAL | 80 | 50 | 600 | F90 | FDV | S2 | +TO=411.501 | T20100 | 72101 | Bæresystem generelt
Kabelbro | Nivå F - 0,7 | 5111 | 1920 | 50 | 600 | ORIGINAL | 600 | 50 | 1920 | F50 | 188899 | S4 |  | 187259 | A181143 | Bæresystem for elkraft | AVINOR - 09_Arbeidspakke: K0G-Nivå D + 1,2
Kabelbro | Nivå D + 1,2 | 5111 |  |  |  | RESULT | 400 | 50 | 1375 | F90 | FDV | S2 | +TO=411.501 | T20100 | 72101 | Bæresytem for tele- og automasjon
Kabelbro | Nivå F - 0,7 | 410 |  |  |  | RESULT | 600 | 50 | 4505 | F90 | FDV | S2 | +TO=411.501 | T20100 | 72101 | Bæresystem generelt
Kabelbro | Nivå D + 1,2 | 4111 |  |  |  | RESULT | 554 | 40 | 600 | F90 | FDV | S2 | +TO=411.501 | T20100 | 72101 | Bæresystem for elkraft
2 x Kabelbro | Nivå D + 1,2 | 5111 |  |  |  | RESULT | 50 | 565 | 600 | F90 | FDV | S2 | +TO=411.501 | T20100 | 72101 | Bæresytem for tele- og automasjon
Kabelbro | Nivå D + 1,2 | 4111 |  |  |  | RESULT | 300 | 50 | 315 | F90 | FDV | S2 | +TO=411.001 | T20100 | 72101 | Bæresystem for elkraft

# IfcFlowSegment: Kobberrør (191)
Type - PredefinedType: RIGIDSEGMENT
MagiCAD Pset_Pipe - User Code: Cu; NationalCode: UB1.111713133; Material: Kobberrør
ePset_Simplebim - Assembly Level: Leaf
Name | In | SystemName = Group | Insulation_thickness_mm (mm) | qv_SizingFlow_ls (m3/s) = MagiCAD Pset_Heating, v_SizingFlow_ms (m/s) = MagiCAD Pset_Heating, pTot_SizingFlow_kPa (kPa) = MagiCAD Pset_Heating, dpTot_SizingFlow_kPa (kPa) = MagiCAD Pset_Water, dpTot_SizingFlow_kPa (kPa) = MagiCAD Pset_Water, pTot_SizingFlow_kPa (kPa) = MagiCAD Pset_Water, v_SizingFlow_ms (m/s) | Length_mm (mm) | ConnectionSize_mm (mm) | SystemType | SystemClass | Height (Simplebim) (mm) | Width (Simplebim) (mm) | Length (Simplebim) (mm) | Splitting
Kobberrør | Nivå F - 0,7 m | 31=KV Kopi 4 (2) | 0 | 0 | 677.547 | 12 | KV | Domestic Cold Water | 12 | 12 | 677.5 | ORIGINAL
Kobberrør | Nivå F - 0,7 m | 31=KV Kopi 4 (2) | 0 | 0 | 944.295 | 12 | KV | Domestic Cold Water | 12 | 12 | 944.3 | ORIGINAL
Kobberrør | Nivå F - 0,7 m | 31=KV Kopi 4 (2) | 0 | 0 | 1570.63 | 12 | KV | Domestic Cold Water | 12 | 12 | 1570.6 | ORIGINAL
Kobberrør | Nivå F - 0,7 m | +TG=310.002 (15) | 0 | 0 | 1281.94 | 12 | VV | Domestic Hot Water | 12 | 12 | 1281.9 | ORIGINAL
Kobberrør | Nivå F - 0,7 m | +TG=310.002 (15) | 0 | 0 | 786 | 12 | VV | Domestic Hot Water | 12 | 12 | 786 | ORIGINAL
Kobberrør | Nivå F - 0,7 m | 31=KV Kopi 4 (4) | 0 | 0 | 696 | 12 | KV | Domestic Cold Water | 12 | 12 | 696 | ORIGINAL
Kobberrør | Nivå F - 0,7 m | 31=KV Kopi 4 (4) | 0 | 0 | 716 | 12 | KV | Domestic Cold Water | 12 | 12 | 716 | ORIGINAL
Kobberrør | Nivå F - 0,7 m | 31=KV Kopi 4 (4) | 0 | 0 | 132.221 | 12 | KV | Domestic Cold Water | 12 | 12 | 132.2 | ORIGINAL
Kobberrør | Nivå F - 0,7 m | +TG=310.002 (2) | 0 | 0 | 411 | 12 | VV | Domestic Hot Water | 12 | 12 | 411 | ORIGINAL
Kobberrør | Nivå F - 0,7 m | +TG=310.002 (2) | 0 | 0 | 786 | 12 | VV | Domestic Hot Water | 12 | 12 | 786 | ORIGINAL
Kobberrør | Nivå F - 0,7 m | +TG=310.002 (2) | 0 | 0 | 1260.7 | 12 | VV | Domestic Hot Water | 12 | 12 | 1260.7 | ORIGINAL
Kobberrør | Nivå F - 0,7 m | +TG=310.002 (2) | 0 | 0 | 55.898 | 12 | VV | Domestic Hot Water | 12 | 12 | 55.9 | ORIGINAL
Kobberrør | Nivå F - 0,7 m | 31=KV Kopi 13 | 17 | 0 | 2440 | 12 | KV | Domestic Cold Water | 12 | 12 | 2440 | ORIGINAL
Kobberrør | Nivå F - 0,7 m | 31= VV Kopi 11 | 25 | 0 | 2440 | 12 | VV | Domestic Hot Water | 12 | 12 | 2440 | ORIGINAL
Kobberrør | Nivå F - 0,7 m | 31=KV Kopi 4 (49) | 0 | 0 | 190 | 15 | KV | Domestic Cold Water | 15 | 15 | 190 | ORIGINAL
Kobberrør | Nivå F - 0,7 m | 31=KV Kopi 4 (49) | 0 | 0 | 485 | 15 | KV | Domestic Cold Water | 15 | 15 | 485 | ORIGINAL
Kobberrør | Nivå F - 0,7 m | +TG=310.002 (33) | 0 | 0 | 190 | 15 | VV | Domestic Hot Water | 15 | 15 | 190 | ORIGINAL
Kobberrør | Nivå F - 0,7 m | +TG=310.002 (33) | 0 | 0 | 481.117 | 15 | VV | Domestic Hot Water | 15 | 15 | 481.1 | ORIGINAL
Kobberrør | Nivå F - 0,7 m | 31=KV Kopi 4 (2) | 0 | 0 | 343.966 | 28 | KV | Domestic Cold Water | 28 | 28 | 344 | ORIGINAL
Kobberrør | Nivå F - 0,7 m | 31=KV Kopi 4 (2) | 0 | 0 | 640.054 | 28 | KV | Domestic Cold Water | 28 | 28 | 640.1 | ORIGINAL
Kobberrør | Nivå F - 0,7 m | 31=KV Kopi 4 (2) | 0 | 0 | 915.698 | 28 | KV | Domestic Cold Water | 28 | 28 | 915.7 | ORIGINAL
Kobberrør | Nivå F - 0,7 m | 31=KV Kopi 4 (2) | 0 | 0 | 123.352 | 28 | KV | Domestic Cold Water | 28 | 28 | 123.4 | ORIGINAL
Kobberrør | Nivå F - 0,7 m | 31=KV Kopi 4 (2) | 0 | 0 | 77.355 | 15 | KV | Domestic Cold Water | 15 | 15 | 77.4 | ORIGINAL
Kobberrør | Nivå F - 0,7 m | 31=KV Kopi 4 (2) | 0 | 0 | 462.355 | 15 | KV | Domestic Cold Water | 15 | 15 | 462.4 | ORIGINAL
Kobberrør | Nivå F - 0,7 m | 31=KV Kopi 4 (2) | 0 | 0 | 195 | 15 | KV | Domestic Cold Water | 15 | 15 | 195 | ORIGINAL
Kobberrør | Nivå F - 0,7 m | 31=KV Kopi 4 (2) | 0 | 0 | 1999 | 28 | KV | Domestic Cold Water | 28 | 28 | 1999 | ORIGINAL
Kobberrør | Nivå F - 0,7 m | +TG=310.002 (2) | 0 | 0 | 2408 | 12 | VV | Domestic Hot Water | 12 | 12 | 2408 | ORIGINAL
Kobberrør | Nivå F - 0,7 m | 31=KV Kopi 4 (2) | 0 | 0 | 290 | 35 | KV | Domestic Cold Water | 35 | 35 | 290 | ORIGINAL
Kobberrør | Nivå F - 0,7 m | +TG=310.002 (2) | 0 | 0 | 284 | 18 | VV | Domestic Hot Water | 18 | 18 | 284 | ORIGINAL
Kobberrør | Nivå F - 0,7 m | 31= VV Kopi 12 | 0 | 0 | 250 | 15 | VVC | Domestic Hot Water | 15 | 15 | 250 | ORIGINAL
Kobberrør | Nivå F - 0,7 m | 31=KV Kopi 4 (2) | 0 | 0 | 597.698 | 12 | KV | Domestic Cold Water | 12 | 12 | 597.7 | ORIGINAL
Kobberrør | Nivå F - 0,7 m | 31=KV Kopi 4 (2) | 0 | 0 | 823.186 | 12 | KV | Domestic Cold Water | 12 | 12 | 823.2 | ORIGINAL
Kobberrør | Nivå F - 0,7 m | 31=KV Kopi 4 (2) | 0 | 0 | 76 | 12 | KV | Domestic Cold Water | 12 | 12 | 76 | ORIGINAL
Kobberrør | Nivå F - 0,7 m | 31=KV Kopi 4 (2) | 0 | 0 | 163.848 | 12 | KV | Domestic Cold Water | 12 | 12 | 163.8 | ORIGINAL
Kobberrør | Nivå F - 0,7 m | +TG=310.002 (2) | 0 | 0 | 176 | 12 | VV | Domestic Hot Water | 12 | 12 | 176 | ORIGINAL
Kobberrør | Nivå F - 0,7 m | +TG=310.002 (2) | 0 | 0 | 272.626 | 12 | VV | Domestic Hot Water | 12 | 12 | 273 | ORIGINAL
Kobberrør | Nivå F - 0,7 m | 31=KV Kopi 4 (2) | 0 | 0 | 118.367 | 12 | KV | Domestic Cold Water | 12 | 12 | 118.4 | ORIGINAL
Kobberrør | Nivå F - 0,7 m | 31=KV Kopi 4 (2) | 0 | 0 | 545.714 | 28 | KV | Domestic Cold Water | 28 | 28 | 545.7 | ORIGINAL
Kobberrør | Nivå F - 0,7 m | 31=KV Kopi 4 (2) | 0 | 0 | 118.4 | 12 | KV | Domestic Cold Water | 12 | 12 | 118.4 | ORIGINAL
Kobberrør | Nivå F - 0,7 m | 31=KV Kopi 4 (2) | 0 | 0 | 2147.27 | 28 | KV | Domestic Cold Water | 28 | 28 | 2147.3 | ORIGINAL
Kobberrør | Nivå F - 0,7 m | +TG=310.002 (2) | 0 | 0 | 49.586 | 12 | VV | Domestic Hot Water | 12 | 12 | 49.6 | ORIGINAL
Kobberrør | Nivå F - 0,7 m | +TG=310.002 (2) | 0 | 0 | 2260.02 | 12 | VV | Domestic Hot Water | 12 | 12 | 2260 | ORIGINAL
Kobberrør | Nivå F - 0,7 m | +TG=310.002 (2) | 0 | 0 | 228 | 12 | VV | Domestic Hot Water | 12 | 12 | 228 | ORIGINAL
Kobberrør | Nivå F - 0,7 m | 31=KV Kopi 4 (2) | 0 | 0 | 198 | 12 | KV | Domestic Cold Water | 12 | 12 | 198 | ORIGINAL
Kobberrør | Nivå F - 0,7 m | 31=KV Kopi 4 (2) | 0 | 0 | 198.033 | 12 | KV | Domestic Cold Water | 12 | 12 | 198 | ORIGINAL
Kobberrør | Nivå F - 0,7 m | +TG=310.002 (2) | 0 | 0 | 54.038 | 18 | VV | Domestic Hot Water | 18 | 18 | 54 | ORIGINAL
Kobberrør | Nivå F - 0,7 m | +TG=310.002 (2) | 0 | 0 | 522.273 | 18 | VV | Domestic Hot Water | 18 | 18 | 522.3 | ORIGINAL
Kobberrør | Nivå F - 0,7 m | 31= VV Kopi 12 | 0 | 0 | 60.032 | 15 | VVC | Domestic Hot Water | 15 | 15 | 60 | ORIGINAL
Kobberrør | Nivå F - 0,7 m | 31=KV Kopi 4 (2) | 0 | 0 | 20.038 | 35 | KV | Domestic Cold Water | 35 | 35 | 20 | ORIGINAL
Kobberrør | Nivå F - 0,7 m | 31=KV Kopi 4 (2) | 0 | 0 | 507.254 | 35 | KV | Domestic Cold Water | 35 | 35 | 507.3 | ORIGINAL
Kobberrør | Nivå F - 0,7 m | 31=KV Kopi 4 (2) | 0 | 0 | 364.663 | 28 | KV | Domestic Cold Water | 28 | 28 | 364.7 | ORIGINAL
Kobberrør | Nivå F - 0,7 m | 31=KV Kopi 4 (2) | 0 | 0 | 74 | 28 | KV | Domestic Cold Water | 28 | 28 | 74 | ORIGINAL
Kobberrør | Nivå F - 0,7 m | 31=KV Kopi 4 (2) | 0 | 0 | 125.625 | 12 | KV | Domestic Cold Water | 12 | 12 | 125.6 | ORIGINAL
Kobberrør | Nivå F - 0,7 m | 31=KV Kopi 4 (2) | 0 | 0 | 146.662 | 28 | KV | Domestic Cold Water | 28 | 28 | 146.8 | ORIGINAL
Kobberrør | Nivå F - 0,7 m | 31=KV Kopi 4 (2) | 0 | 0 | 138.941 | 12 | KV | Domestic Cold Water | 12 | 12 | 138.9 | ORIGINAL
Kobberrør | Nivå F - 0,7 m | 31=KV Kopi 4 (2) | 0 | 0 | 389.849 | 12 | KV | Domestic Cold Water | 12 | 12 | 389.8 | ORIGINAL
Kobberrør | Nivå F - 0,7 m | +TG=310.002 (2) | 0 | 0 | 274.771 | 12 | VV | Domestic Hot Water | 12 | 12 | 274.8 | ORIGINAL
Kobberrør | Nivå F - 0,7 m | +TG=310.002 (2) | 0 | 0 | 204.338 | 12 | VV | Domestic Hot Water | 12 | 12 | 204.3 | ORIGINAL
Kobberrør | Nivå F - 0,7 m | +TG=310.002 (2) | 0 | 0 | 271.586 | 12 | VV | Domestic Hot Water | 12 | 12 | 271.6 | ORIGINAL
2 x Kobberrør | Nivå F - 0,7 m | 31=KV Kopi 4 (2) | 0 | 0 | 322.4 | 12 | KV | Domestic Cold Water | 12 | 12 | 322.4 | ORIGINAL
Kobberrør | Nivå F - 0,7 m | +TG=310.002 (29) | 0 | 0 | 50.829 | 12 | VV | Domestic Hot Water | 12 | 12 | 50.8 | ORIGINAL
Kobberrør | Nivå F - 0,7 m | +TG=310.002 (29) | 0 | 0 | 756.193 | 12 | VV | Domestic Hot Water | 12 | 12 | 756.2 | ORIGINAL
Kobberrør | Nivå F - 0,7 m | +TG=310.002 (29) | 0 | 0 | 399.522 | 12 | VV | Domestic Hot Water | 12 | 12 | 399.5 | ORIGINAL
Kobberrør | Nivå F - 0,7 m | 31=KV Kopi 4 (2) | 0 | 0 | 49.094 | 12 | KV | Domestic Cold Water | 12 | 12 | 48.7 | ORIGINAL
Kobberrør | Nivå F - 0,7 m | 31=KV Kopi 4 (2) | 0 | 0 | 644.675 | 12 | KV | Domestic Cold Water | 12 | 12 | 644.7 | ORIGINAL
Kobberrør | Nivå F - 0,7 m | 31=KV Kopi 4 (2) | 0 | 0 | 691.109 | 12 | KV | Domestic Cold Water | 12 | 12 | 691.1 | ORIGINAL
Kobberrør | Nivå F - 0,7 m | +TG=310.002 (29) | 0 | 0 | 153 | 12 | VV | Domestic Hot Water | 12 | 12 | 153 | ORIGINAL
Kobberrør | Nivå F - 0,7 m | +TG=310.002 (15) | 0 | 0 | 177.265 | 12 | VV | Domestic Hot Water | 12 | 12 | 177.3 | ORIGINAL
Kobberrør | Nivå F - 0,7 m | 31=KV Kopi 4 (2) | 0 | 0 | 153 | 12 | KV | Domestic Cold Water | 12 | 12 | 153 | ORIGINAL
Kobberrør | Nivå F - 0,7 m | 31=KV Kopi 4 (2) | 0 | 0 | 177.284 | 12 | KV | Domestic Cold Water | 12 | 12 | 177.3 | ORIGINAL
Kobberrør | Nivå F - 0,7 m | 31=KV Kopi 4 (29) (2) | 10 | 0 | 391.151 | 12 | KV | Domestic Cold Water | 12 | 12 | 391.2 | ORIGINAL
Kobberrør | Nivå F - 0,7 m | 31=KV Kopi 4 (29) (2) | 10 | 0 | 1573.5 | 12 | KV | Domestic Cold Water | 12 | 12 | 1573.5 | ORIGINAL
Kobberrør | Nivå F - 0,7 m | 31=KV Kopi 4 (29) (2) | 10 | 0 | 175.184 | 12 | KV | Domestic Cold Water | 12 | 12 | 175.2 | ORIGINAL
Kobberrør | Nivå F - 0,7 m | 31=KV Kopi 4 (29) (2) | 10 | 0 | 1188.5 | 12 | KV | Domestic Cold Water | 12 | 12 | 1188.1 | ORIGINAL
Kobberrør | Nivå F - 0,7 m | 31=KV Kopi 4 (29) (2) | 10 | 0 | 387.439 | 12 | KV | Domestic Cold Water | 12 | 12 | 387.4 | ORIGINAL
Kobberrør | Nivå F - 0,7 m | 31=KV Kopi 4 (29) (2) | 10 | 0 | 125.689 | 12 | KV | Domestic Cold Water | 12 | 12 | 125.6 | ORIGINAL
Kobberrør | Nivå F - 0,7 m | 31=KV Kopi 4 (29) (2) | 0 | 0 | 243.2 | 12 | KV | Domestic Cold Water | 12 | 12 | 243.2 | ORIGINAL
Kobberrør | Nivå F - 0,7 m | 31=KV Kopi 4 (29) (2) | 10 | 0 | 40.448 | 12 | KV | Domestic Cold Water | 12 | 12 | 39.8 | ORIGINAL
Kobberrør | Nivå F - 0,7 m | 31=KV Kopi 4 (29) (2) | 10 | 0 | 13.876 | 12 | KV | Domestic Cold Water | 12 | 12 | 14.3 | ORIGINAL
Kobberrør | Nivå F - 0,7 m | 31=KV Kopi 4 (29) (2) | 10 | 0 | 11.22 | 12 | KV | Domestic Cold Water | 11.2 | 12 | 12 | ORIGINAL
Kobberrør | Nivå F - 0,7 m | 31= VV Kopi 41 | 15 | 0 | 26.503 | 12 | VV | Domestic Hot Water | 12 | 12 | 26.5 | ORIGINAL
Kobberrør | Nivå F - 0,7 m | 31= VV Kopi 41 | 0 | 0 | 52.334 | 12 | VV | Domestic Hot Water | 12 | 12 | 51.5 | ORIGINAL
Kobberrør | Nivå F - 0,7 m | 31= VV Kopi 41 | 0 | 0 | 243.2 | 12 | VV | Domestic Hot Water | 12 | 12 | 243.2 | ORIGINAL
Kobberrør | Nivå F - 0,7 m |  | 10 | 0 | 86 | 12 | Undefined | Undefined | 12 | 12 | 86 | ORIGINAL
Kobberrør | Nivå F - 0,7 m | 31=KV Kopi 4 (29) (2) | 10 | 0 | 557.997 | 12 | KV | Domestic Cold Water | 12 | 12 | 558 | ORIGINAL
Kobberrør | Nivå F - 0,7 m | 31=KV Kopi 4 (29) (2) | 10 | 0 | 156 | 12 | KV | Domestic Cold Water | 12 | 12 | 156 | ORIGINAL
Kobberrør | Nivå F - 0,7 m | 31=KV Kopi 4 (29) (2) | 10 | 0 | 846.814 | 12 | KV | Domestic Cold Water | 12 | 12 | 846.8 | ORIGINAL
Kobberrør | Nivå F - 0,7 m | 31=KV Kopi 4 (29) (2) | 10 | 0 | 290.568 | 12 | KV | Domestic Cold Water | 12 | 12 | 290.6 | ORIGINAL
Kobberrør | Nivå F - 0,7 m | 31=KV Kopi 4 (29) (2) | 10 | 0 | 4.809 | 12 | KV | Domestic Cold Water | 12 | 12 | 4.8 | ORIGINAL
Kobberrør | Nivå F - 0,7 m | 31=KV Kopi 4 (29) (2) | 10 | 0 | 1413.1 | 12 | KV | Domestic Cold Water | 12 | 12 | 1413.1 | ORIGINAL
Kobberrør | Nivå F - 0,7 m | 31=KV Kopi 4 (29) (2) | 10 | 0 | 468 | 12 | KV | Domestic Cold Water | 12 | 12 | 468 | ORIGINAL
Kobberrør | Nivå F - 0,7 m | 31=KV Kopi 4 (4) | 0 | 0 | 908.019 | 12 | KV | Domestic Cold Water | 12 | 12 | 908 | ORIGINAL
Kobberrør | Nivå F - 0,7 m | 31= VV Kopi 41 | 15 | 0 | 401.971 | 12 | VV | Domestic Hot Water | 12 | 12 | 402 | ORIGINAL
Kobberrør | Nivå F - 0,7 m | 31=KV Kopi 4 (29) (2) | 10 | 0 | 553.316 | 12 | KV | Domestic Cold Water | 12 | 12 | 553.3 | ORIGINAL
Kobberrør | Nivå F - 0,7 m | 31=KV Kopi 4 (29) (2) | 10 | 0 | 396 | 12 | KV | Domestic Cold Water | 12 | 12 | 396 | ORIGINAL
Kobberrør | Nivå F - 0,7 m | 31= VV Kopi 41 | 15 | 0 | 487.898 | 12 | VV | Domestic Hot Water | 12 | 12 | 488 | ORIGINAL
Kobberrør | Nivå F - 0,7 m | 31=KV Kopi 4 (29) (2) | 10 | 0 | 1543.12 | 12 | KV | Domestic Cold Water | 12 | 12 | 1543.1 | ORIGINAL
Kobberrør | Nivå F - 0,7 m | 31=KV Kopi 4 (29) (2) | 10 | 0 | 4074.91 | 12 | KV | Domestic Cold Water | 12 | 12 | 4074.9 | ORIGINAL
Kobberrør | Nivå D + 1,2 m | 31=KV Kopi 4 (2) | 0 | 0 | 124.538 | 35 | KV | Domestic Cold Water | 35 | 35 | 123.5 | ORIGINAL
Kobberrør | Nivå D + 1,2 m | 31=KV Kopi 4 (2) | 0 | 0 | 142.832 | 54 | KV | Domestic Cold Water | 54 | 54 | 142.8 | ORIGINAL
Kobberrør | Nivå D + 1,2 m | +TG=310.002 (2) | 0 | 0 | 19.544 | 18 | VV | Domestic Hot Water | 18 | 18 | 20.1 | ORIGINAL
Kobberrør | Nivå D + 1,2 m | +TG=310.002 (2) | 0 | 0 | 346.212 | 18 | VV | Domestic Hot Water | 18 | 18 | 345.5 | ORIGINAL
Kobberrør | Nivå D + 1,2 m | +TG=310.002 (2) | 0 | 0 | 219.738 | 22 | VV | Domestic Hot Water | 22 | 22 | 219.7 | ORIGINAL
Kobberrør | Nivå D + 1,2 m | 31= VV Kopi 12 | 0 | 0 | 23.176 | 15 | VVC | Domestic Hot Water | 15 | 15 | 23.1 | ORIGINAL
Kobberrør | Nivå D + 1,2 m | 31= VV Kopi 12 | 0 | 0 | 557.738 | 15 | VVC | Domestic Hot Water | 15 | 15 | 558 | ORIGINAL
Kobberrør | Nivå D + 1,2 m | 31= VV Kopi 12 | 0 | 0 | 333.224 | 18 | VVC | Domestic Hot Water | 18 | 18 | 333.2 | ORIGINAL
Kobberrør | Nivå D + 1,2 m | 31=KV Kopi 4 (2) | 0 | 0 | 3275.35 | 35 | KV | Domestic Cold Water | 35 | 35 | 3275.3 | ORIGINAL
Kobberrør | Nivå D + 1,2 m | 31=KV Kopi 4 (2) | 0 | 0 | 82 | 54 | KV | Domestic Cold Water | 54 | 54 | 82 | ORIGINAL
Kobberrør | Nivå D + 1,2 m | 31=KV Kopi 4 (2) | 0 | 0 | 116.122 | 54 | KV | Domestic Cold Water | 54 | 54 | 116.1 | ORIGINAL
Kobberrør | Nivå D + 1,2 m | 31=KV Kopi 4 (2) | 0 | 0 | 1150.1 | 15 | KV | Domestic Cold Water | 15 | 15 | 1150.1 | ORIGINAL
Kobberrør | Nivå D + 1,2 m | 31=KV Kopi 4 (2) | 0 | 0 | 1016.28 | 28 | KV | Domestic Cold Water | 28 | 28 | 1016.3 | ORIGINAL
Kobberrør | Nivå D + 1,2 m | 31=KV Kopi 4 (2) | 0 | 0 | 293 | 15 | KV | Domestic Cold Water | 15 | 15 | 293 | ORIGINAL
3 x Kobberrør | Nivå D + 1,2 m | 31=KV Kopi 4 (2) | 0 | 0 | 213 | 15 | KV | Domestic Cold Water | 15 | 15 | 213 | ORIGINAL
Kobberrør | Nivå D + 1,2 m | 31=KV Kopi 4 (2) | 0 | 0 | 410.147 | 28 | KV | Domestic Cold Water | 28 | 28 | 410.1 | ORIGINAL
Kobberrør | Nivå D + 1,2 m | 31=KV Kopi 4 (2) | 0 | 0 | 991.799 | 28 | KV | Domestic Cold Water | 28 | 28 | 991.8 | ORIGINAL
Kobberrør | Nivå D + 1,2 m | 31=KV Kopi 4 (2) | 0 | 0 | 868.228 | 28 | KV | Domestic Cold Water | 28 | 28 | 868.2 | ORIGINAL
Kobberrør | Nivå D + 1,2 m | 31=KV Kopi 4 (2) | 0 | 0 | 223.5 | 12 | KV | Domestic Cold Water | 12 | 12 | 223.5 | ORIGINAL
Kobberrør | Nivå D + 1,2 m | 31=KV Kopi 4 (2) | 0 | 0 | 991.998 | 18 | KV | Domestic Cold Water | 18 | 18 | 992 | ORIGINAL
Kobberrør | Nivå D + 1,2 m | 31=KV Kopi 4 (2) | 0 | 0 | 28.49 | 12 | KV | Domestic Cold Water | 12 | 12 | 28 | ORIGINAL
Kobberrør | Nivå D + 1,2 m | 31=KV Kopi 4 (2) | 0 | 0 | 710.845 | 15 | KV | Domestic Cold Water | 15 | 15 | 710.8 | ORIGINAL
3 x Kobberrør | Nivå D + 1,2 m | 31=KV Kopi 4 (2) | 0 | 0 | 841 | 15 | KV | Domestic Cold Water | 15 | 15 | 841 | ORIGINAL
Kobberrør | Nivå D + 1,2 m | 31=KV Kopi 4 (2) | 0 | 0 | 844 | 12 | KV | Domestic Cold Water | 12 | 12 | 844 | ORIGINAL
Kobberrør | Nivå D + 1,2 m | 31=KV Kopi 4 (2) | 0 | 0 | 440.454 | 35 | KV | Domestic Cold Water | 35 | 35 | 440.5 | ORIGINAL
Kobberrør | Nivå D + 1,2 m | 31=KV Kopi 4 (2) | 0 | 0 | 2516.78 | 35 | KV | Domestic Cold Water | 35 | 35 | 2516.8 | ORIGINAL
Kobberrør | Nivå D + 1,2 m | 31=KV Kopi 4 (2) | 0 | 0 | 54.777 | 28 | KV | Domestic Cold Water | 28 | 28 | 54.8 | ORIGINAL
Kobberrør | Nivå D + 1,2 m | +TG=310.002 (2) | 0 | 0 | 4.901 | 22 | VV | Domestic Hot Water | 22 | 22 | 4.9 | ORIGINAL
Kobberrør | Nivå D + 1,2 m | 31= VV Kopi 12 | 0 | 0 | 2521.16 | 15 | VVC | Domestic Hot Water | 15 | 15 | 2521.2 | ORIGINAL
Kobberrør | Nivå D + 1,2 m | +TG=310.002 (2) | 0 | 0 | 40.044 | 18 | VV | Domestic Hot Water | 18 | 18 | 40 | ORIGINAL
Kobberrør | Nivå D + 1,2 m | +TG=310.002 (2) | 0 | 0 | 2528.79 | 18 | VV | Domestic Hot Water | 18 | 18 | 2528.8 | ORIGINAL
Kobberrør | Nivå D + 1,2 m | +TG=310.002 (2) | 0 | 0 | 18.654 | 18 | VV | Domestic Hot Water | 18 | 18 | 18.7 | ORIGINAL
Kobberrør | Nivå D + 1,2 m | +TG=310.002 (2) | 0 | 0 | 307.019 | 18 | VV | Domestic Hot Water | 18 | 18 | 307.1 | ORIGINAL
Kobberrør | Nivå D + 1,2 m | +TG=310.002 (2) | 0 | 0 | 3893.99 | 12 | VV | Domestic Hot Water | 12 | 12 | 3894 | ORIGINAL
Kobberrør | Nivå D + 1,2 m | +TG=310.002 (2) | 0 | 0 | 262.692 | 12 | VV | Domestic Hot Water | 12 | 12 | 262.7 | ORIGINAL
Kobberrør | Nivå D + 1,2 m | +TG=310.002 (2) | 0 | 0 | 1278.14 | 15 | VV | Domestic Hot Water | 15 | 15 | 1278.1 | ORIGINAL
Kobberrør | Nivå D + 1,2 m | +TG=310.002 (2) | 0 | 0 | 153 | 22 | VV | Domestic Hot Water | 22 | 22 | 153 | ORIGINAL
Kobberrør | Nivå D + 1,2 m | +TG=310.002 (2) | 0 | 0 | 208.122 | 22 | VV | Domestic Hot Water | 22 | 22 | 208.1 | ORIGINAL
Kobberrør | Nivå D + 1,2 m | 31= VV Kopi 12 | 0 | 0 | 162 | 18 | VVC | Domestic Hot Water | 18 | 18 | 162 | ORIGINAL
Kobberrør | Nivå D + 1,2 m | 31= VV Kopi 12 | 0 | 0 | 462.843 | 18 | VVC | Domestic Hot Water | 18 | 18 | 462.8 | ORIGINAL
Kobberrør | Nivå D + 1,2 m | 31=KV Kopi 4 (2) | 0 | 0 | 122.51 | 15 | KV | Domestic Cold Water | 15 | 15 | 121.6 | ORIGINAL
Kobberrør | Nivå D + 1,2 m | 31=KV Kopi 4 (2) | 0 | 0 | 967.81 | 12 | KV | Domestic Cold Water | 12 | 12 | 967.8 | ORIGINAL
Kobberrør | Nivå D + 1,2 m | 31=KV Kopi 4 (2) | 0 | 0 | 373.15 | 35 | KV | Domestic Cold Water | 35 | 35 | 373.1 | ORIGINAL
Kobberrør | Nivå D + 1,2 m | +TG=310.002 (2) | 0 | 0 | 520.734 | 18 | VV | Domestic Hot Water | 18 | 18 | 520.7 | ORIGINAL
Kobberrør | Nivå D + 1,2 m | +TG=310.002 (2) | 0 | 0 | 580.014 | 22 | VV | Domestic Hot Water | 22 | 22 | 580 | ORIGINAL
Kobberrør | Nivå D + 1,2 m | 31= VV Kopi 12 | 0 | 0 | 580.014 | 18 | VVC | Domestic Hot Water | 18 | 18 | 580 | ORIGINAL
Kobberrør | Nivå D + 1,2 m | 31=KV Kopi 4 (2) | 0 | 0 | 507.414 | 54 | KV | Domestic Cold Water | 54 | 54 | 507 | ORIGINAL
Kobberrør | Nivå D + 1,2 m | +TG=310.002 (2) | 0 | 0 | 604.25 | 12 | VV | Domestic Hot Water | 12 | 12 | 604.3 | ORIGINAL
Kobberrør | Nivå D + 1,2 m | +TG=310.002 (2) | 0 | 0 | 2285.85 | 15 | VV | Domestic Hot Water | 15 | 15 | 2285.8 | ORIGINAL
Kobberrør | Nivå D + 1,2 m | 31=KV Kopi 4 (2) | 0 | 0 | 926.454 | 12 | KV | Domestic Cold Water | 12 | 12 | 926.5 | ORIGINAL
Kobberrør | Nivå D + 1,2 m | 31=KV Kopi 4 (2) | 0 | 0 | 554.806 | 15 | KV | Domestic Cold Water | 15 | 15 | 554.8 | ORIGINAL
Kobberrør | Nivå D + 1,2 m | 31=KV Kopi 4 (2) | 0 | 0 | 258.392 | 12 | KV | Domestic Cold Water | 12 | 12 | 258 | ORIGINAL
Kobberrør | Nivå D + 1,2 m | 31=KV Kopi 4 (2) | 0 | 0 | 3891.6 | 12 | KV | Domestic Cold Water | 12 | 12 | 3891.6 | ORIGINAL
Kobberrør | Nivå D + 1,2 m | +TG=310.002 (2) | 0 | 0 | 3975.11 | 12 | VV | Domestic Hot Water | 12 | 12 | 3975.1 | ORIGINAL
Kobberrør | Nivå D + 1,2 m | +TG=310.002 (2) | 0 | 0 | 3387.14 | 18 | VV | Domestic Hot Water | 18 | 18 | 3387.1 | ORIGINAL
Kobberrør | Nivå D + 1,2 m | 31= VV Kopi 12 | 0 | 0 | 3445.43 | 15 | VVC | Domestic Hot Water | 15 | 15 | 3445.4 | ORIGINAL
Kobberrør | Nivå D + 1,2 m | +TG=310.002 (2) | 0 | 0 | 224.72 | 22 | VV | Domestic Hot Water | 22 | 22 | 224.7 | ORIGINAL
Kobberrør | Nivå D + 1,2 m | 31=KV Kopi 4 (2) | 0 | 0 | 95.656 | 15 | KV | Domestic Cold Water | 15 | 15 | 95.7 | ORIGINAL
Kobberrør | Nivå D + 1,2 m | 31=KV Kopi 4 (2) | 0 | 0 | 270.12 | 54 | KV | Domestic Cold Water | 54 | 54 | 270.1 | ORIGINAL
Kobberrør | Nivå D + 1,2 m | 37= T 9° Kopi 168 | 13 | 0 | 1907.1 | 18 | KJØL T | Hydronic Supply | 18 | 18 | 1907.1 | ORIGINAL
Kobberrør | Nivå D + 1,2 m | 31=KV Kopi 4 (2) | 0 | 0 | 815.563 | 28 | KV | Domestic Cold Water | 28 | 28 | 815.6 | ORIGINAL
Kobberrør | Nivå D + 1,2 m | 31=KV Kopi 4 (2) | 0 | 0 | 144 | 28 | KV | Domestic Cold Water | 28 | 28 | 144 | ORIGINAL
Kobberrør | Nivå D + 1,2 m | 31=KV Kopi 4 (2) | 0 | 0 | 105.496 | 28 | KV | Domestic Cold Water | 28 | 28 | 106 | ORIGINAL
Kobberrør | Nivå D + 1,2 m | 31=KV Kopi 4 (2) | 0 | 0 | 1555.36 | 28 | KV | Domestic Cold Water | 28 | 28 | 1555.4 | ORIGINAL
2 x Kobberrør | Nivå D + 1,2 m | 31=KV Kopi 4 (2) | 0 | 0 | 19.23 | 28 | KV | Domestic Cold Water | 28 | 28 | 19.4 | ORIGINAL
Kobberrør | Nivå D + 1,2 m | 31= VV Kopi 41 | 15 | 0 | 307.843 | 12 | VV | Domestic Hot Water | 12 | 12 | 307.8 | ORIGINAL
Kobberrør | Nivå D + 1,2 m | 31= VV Kopi 41 | 15 | 0 | 83.7 | 12 | VV | Domestic Hot Water | 12 | 12 | 83.5 | ORIGINAL
Kobberrør | Nivå D + 1,2 m | 31= VV Kopi 41 | 0 | 0 | 191.25 | 12 | VV | Domestic Hot Water | 12 | 12 | 191.2 | ORIGINAL
Kobberrør | Nivå D + 1,2 m |  | 15 | 0 | 160 | 12 | Undefined | Undefined | 12 | 12 | 160.4 | ORIGINAL
Kobberrør | Nivå D + 1,2 m | 31= VV Kopi 41 | 0 | 0 | 1215 | 12 | VV | Domestic Hot Water | 12 | 12 | 1215 | ORIGINAL
Kobberrør | Nivå D + 1,2 m | 37= R 18° Kopi 81 | 0 | 0 | 194.244 | 12 | KJØL R | Hydronic Return | 12 | 12 | 194.2 | ORIGINAL
Kobberrør | Nivå D + 1,2 m | 37= R 18° Kopi 81 | 0 | 0 | 2365.88 | 12 | KJØL R | Hydronic Return | 12 | 12 | 2365.9 | ORIGINAL
Kobberrør | Nivå D + 1,2 m | 37= R 18° Kopi 81 | 0 | 0 | 218 | 12 | KJØL R | Hydronic Return | 12 | 12 | 217.5 | ORIGINAL
Kobberrør | Nivå D + 1,2 m | 37= T 9° Kopi 168 | 13 | 0 | 21.739 | 18 | KJØL T | Hydronic Supply | 18 | 18 | 21.7 | ORIGINAL
Kobberrør | Nivå D + 1,2 m | 37= T 9° Kopi 168 | 13 | 0 | 6.354 | 18 | KJØL T | Hydronic Supply | 18 | 18 | 6.4 | ORIGINAL
Kobberrør | Nivå D + 1,2 m | 37= T 9° Kopi 168 | 13 | 0 | 13.373 | 18 | KJØL T | Hydronic Supply | 18 | 18 | 12.7 | ORIGINAL
Kobberrør | Nivå D + 1,2 m | 31= VV Kopi 41 | 15 | 0 | 579.186 | 12 | VV | Domestic Hot Water | 12 | 12 | 579.2 | ORIGINAL
Kobberrør | Nivå D + 1,2 m | 31= VV Kopi 41 | 15 | 0 | 3148.5 | 12 | VV | Domestic Hot Water | 12 | 12 | 3148.5 | ORIGINAL
Kobberrør | Nivå D + 1,2 m | 31= VV Kopi 41 | 15 | 0 | 219.315 | 12 | VV | Domestic Hot Water | 12 | 12 | 219.3 | ORIGINAL
Kobberrør | Nivå D + 1,2 m | 31= VV Kopi 41 | 15 | 0 | 890.528 | 12 | VV | Domestic Hot Water | 12 | 12 | 890.5 | ORIGINAL
Kobberrør | Nivå D + 1,2 m | 31= VV Kopi 41 | 15 | 0 | 383.778 | 12 | VV | Domestic Hot Water | 12 | 12 | 384 | ORIGINAL
Kobberrør | Nivå D + 1,2 m | 31= VV Kopi 12 |  |  |  |  | VVC | Domestic Hot Water | 16 | 16 | 702 | RESULT
Kobberrør | Nivå D + 1,2 m | 31=KV Kopi 4 (2) |  |  |  |  | KV | Domestic Cold Water | 12 | 12 | 4222 | RESULT
Kobberrør | Nivå D + 1,2 m | 37= R 18° Kopi 81 |  |  |  |  | KJØL R | Hydronic Return | 12 | 12 | 865 | RESULT
Kobberrør | Nivå D + 1,2 m | 37= T 9° Kopi 168 |  |  |  |  | KJØL T | Hydronic Supply | 18 | 18 | 945 | RESULT
Kobberrør | Nivå F - 0,7 m | 31=KV Kopi 4 (29) (2) |  |  |  |  | KV | Domestic Cold Water | 12 | 12 | 153 | RESULT
Kobberrør | Nivå F - 0,7 m | 31=KV Kopi 4 (29) (2) |  |  |  |  | KV | Domestic Cold Water | 12 | 12 | 105 | RESULT

# IfcFlowSegment: MA (100)
Type - PredefinedType: RIGIDSEGMENT
MagiCAD Pset_Pipe - User Code: MA; Material: MA; NationalCode: UB2.1115131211
ePset_Simplebim - Assembly Level: Leaf
Name | In | Splitting | SystemType | qv_SizingFlow_ls (m3/s) = MagiCAD Pset_Heating, v_SizingFlow_ms (m/s) = MagiCAD Pset_Heating, pTot_SizingFlow_kPa (kPa) = MagiCAD Pset_Heating, dpTot_SizingFlow_kPa (kPa) = MagiCAD Pset_Water, dpTot_SizingFlow_kPa (kPa) = MagiCAD Pset_Water, pTot_SizingFlow_kPa (kPa) = MagiCAD Pset_Water, v_SizingFlow_ms (m/s) | SystemName = Group | SystemClass | Insulation_thickness_mm (mm) | ConnectionSize_mm (mm) | Length_mm (mm) | Width (Simplebim) (mm) | Height (Simplebim) (mm) | Length (Simplebim) (mm)
MA | Nivå F - 0,7 m | ORIGINAL | SPV FETT | 0 | 31= SPV Kopi 138 | Sanitary | 13 | 110 | 20.278 | 20.3 | 110 | 110
MA | Nivå F - 0,7 m | ORIGINAL | SPV FETT | 0 | 31= SPV Kopi 138 | Sanitary | 13 | 110 | 371.355 | 110 | 110 | 371.4
MA | Nivå F - 0,7 m | ORIGINAL | SPV FETT | 0 | 31= SPV Kopi 138 | Sanitary | 13 | 110 | 3582.26 | 110 | 110 | 3582.3
MA | Nivå F - 0,7 m | ORIGINAL | SPV FETT | 0 | 31= SPV Kopi 138 | Sanitary | 13 | 110 | 440.221 | 110 | 110 | 440.2
MA | Nivå F - 0,7 m | ORIGINAL | SPV FETT | 0 | 31= SPV Kopi 138 | Sanitary | 13 | 110 | 379.99 | 110 | 110 | 380
MA | Nivå F - 0,7 m | ORIGINAL | SPV | 0 | 31= SPV Kopi 13 | Sanitary | 0 | 75 | 354.024 | 75 | 75 | 354
MA | Nivå F - 0,7 m | ORIGINAL | SPV | 0 | 31= SPV Kopi 13 | Sanitary | 0 | 75 | 105.789 | 75 | 75 | 106.1
MA | Nivå F - 0,7 m | ORIGINAL | SPV FETT | 0 | 31= SPV Kopi 138 | Sanitary | 13 | 110 | 387.157 | 110 | 110 | 387.2
MA | Nivå F - 0,7 m | ORIGINAL | SPV FETT | 0 | 31= SPV Kopi 138 | Sanitary | 13 | 110 | 525.125 | 110 | 110 | 525.1
MA | Nivå F - 0,7 m | ORIGINAL | Undefined | 0 |  | Undefined | 0 | 75 | 100 | 75 | 75 | 100
MA | Nivå F - 0,7 m | ORIGINAL | SPV | 0 | 31= SPV Kopi 147 (7) | Sanitary | 0 | 75 | 198.864 | 75 | 75 | 198.9
MA | Nivå F - 0,7 m | ORIGINAL | SPV | 0 | 31= SPV Kopi 147 (7) | Sanitary | 0 | 75 | 837.844 | 75 | 75 | 837.8
MA | Nivå F - 0,7 m | ORIGINAL | OV | 0 | 31= SPV Kopi 63 | Sanitary | 0 | 75 | 65.518 | 65.8 | 75 | 75
MA | Nivå F - 0,7 m | ORIGINAL | OV | 0 | 31= SPV Kopi 63 | Sanitary | 0 | 75 | 435.388 | 75 | 75 | 435.4
MA | Nivå F - 0,7 m | ORIGINAL | OV | 0 | 31= SPV Kopi 63 | Sanitary | 0 | 75 | 194.928 | 75 | 75 | 194.9
MA | Nivå F - 0,7 m | ORIGINAL | SPV FETT | 0 | 31= SPV Kopi 138 | Sanitary | 13 | 110 | 1884.56 | 110 | 110 | 1884.6
MA | Nivå F - 0,7 m | ORIGINAL | SPV FETT | 0 | 31= SPV Kopi 138 | Sanitary | 13 | 110 | 3.018 | 110 | 110 | 2.7
MA | Nivå F - 0,7 m | ORIGINAL | SPV FETT | 0 | 31= SPV Kopi 138 | Sanitary | 13 | 110 | 417.345 | 110 | 110 | 417.3
MA | Nivå F - 0,7 m | ORIGINAL | SPV FETT | 0 | 31= SPV Kopi 138 | Sanitary | 13 | 75 | 272.891 | 75 | 75 | 272.9
MA | Nivå F - 0,7 m | ORIGINAL | SPV FETT | 0 | 31= SPV Kopi 138 | Sanitary | 13 | 75 | 57.282 | 75 | 75 | 57
MA | Nivå F - 0,7 m | ORIGINAL | SPV FETT | 0 | 31= SPV Kopi 138 | Sanitary | 13 | 75 | 385.827 | 75 | 75 | 385.8
MA | Nivå F - 0,7 m | ORIGINAL | SPV | 0 | 31= SPV Kopi 147 (4) | Sanitary | 13 | 75 | 200 | 75 | 75 | 200
MA | Nivå C | ORIGINAL | OV | 0 | 31= SPV Kopi 63 | Sanitary | 0 | 75 | 77.029 | 75 | 75 | 77.1
MA | Nivå C | ORIGINAL | OV | 0 | 31= SPV Kopi 63 | Sanitary | 0 | 75 | 1215.9 | 75 | 75 | 1215.9
MA | Nivå C | ORIGINAL | OV | 0 | 31= SPV Kopi 63 | Sanitary | 0 | 75 | 5.191 | 75 | 75 | 4.9
MA | Nivå C | ORIGINAL | OV | 0 | 31= SPV Kopi 63 | Sanitary | 0 | 75 | 3318.05 | 75 | 75 | 3318.1
MA | Nivå C | ORIGINAL | OV | 0 | 31= SPV Kopi 63 | Sanitary | 0 | 75 | 103.968 | 75 | 75 | 103.6
MA | Nivå D + 1,2 m | ORIGINAL | SPV | 0 | 31= SPV Kopi 147 (11) | Sanitary | 13 | 75 | 411.987 | 75 | 75 | 411.5
MA | Nivå D + 1,2 m | ORIGINAL | SPV FETT | 0 | 31= SPV Kopi 138 | Sanitary | 13 | 110 | 99.036 | 110 | 99.3 | 110
MA | Nivå D + 1,2 m | ORIGINAL | SPV FETT | 0 | 31= SPV Kopi 138 | Sanitary | 13 | 110 | 149.496 | 110 | 110 | 149.8
MA | Nivå D + 1,2 m | ORIGINAL | SPV FETT | 0 | 31= SPV Kopi 138 | Sanitary | 13 | 110 | 752.937 | 110 | 110 | 752.9
MA | Nivå D + 1,2 m | ORIGINAL | SPV FETT | 0 | 31= SPV Kopi 138 | Sanitary | 13 | 110 | 46.98 | 110 | 110 | 47.2
MA | Nivå D + 1,2 m | ORIGINAL | SPV FETT | 0 | 31= SPV Kopi 138 | Sanitary | 13 | 110 | 307.273 | 110 | 110 | 307.1
MA | Nivå D + 1,2 m | ORIGINAL | SPV FETT | 0 | 31= SPV Kopi 138 | Sanitary | 13 | 110 | 589.786 | 110 | 110 | 589.8
MA | Nivå D + 1,2 m | ORIGINAL | SPV FETT | 0 | 31= SPV Kopi 138 | Sanitary | 13 | 110 | 101.938 | 110 | 101.5 | 110
MA | Nivå D + 1,2 m | ORIGINAL | SPV FETT | 0 | 31= SPV Kopi 138 | Sanitary | 13 | 110 | 129.759 | 110 | 110 | 130.1
MA | Nivå D + 1,2 m | ORIGINAL | SPV FETT | 0 | 31= SPV Kopi 138 | Sanitary | 13 | 110 | 29.344 | 110 | 110 | 29.3
MA | Nivå D + 1,2 m | ORIGINAL | SPV FETT | 0 | 31= SPV Kopi 138 | Sanitary | 13 | 110 | 703.781 | 110 | 110 | 703.8
MA | Nivå D + 1,2 m | ORIGINAL | SPV FETT | 0 | 31= SPV Kopi 138 | Sanitary | 13 | 110 | 702.868 | 110 | 110 | 702.9
MA | Nivå D + 1,2 m | ORIGINAL | SPV FETT | 0 | 31= SPV Kopi 138 | Sanitary | 13 | 110 | 747.975 | 110 | 110 | 748
MA | Nivå D + 1,2 m | ORIGINAL | SPV FETT | 0 | 31= SPV Kopi 138 | Sanitary | 13 | 110 | 89.701 | 110 | 110 | 90.5
MA | Nivå D + 1,2 m | ORIGINAL | SPV FETT | 0 | 31= SPV Kopi 138 | Sanitary | 13 | 110 | 796.367 | 110 | 110 | 796.4
MA | Nivå D + 1,2 m | ORIGINAL | SPV FETT | 0 | 31= SPV Kopi 138 | Sanitary | 13 | 110 | 67.343 | 67.2 | 110 | 110
MA | Nivå D + 1,2 m | ORIGINAL | SPV FETT | 0 | 31= SPV Kopi 138 | Sanitary | 13 | 110 | 827.969 | 110 | 110 | 828
MA | Nivå D + 1,2 m | ORIGINAL | SPV FETT | 0 | 31= SPV Kopi 138 | Sanitary | 13 | 75 | 341.224 | 75 | 75 | 341.2
MA | Nivå D + 1,2 m | ORIGINAL | SPV FETT | 0 | 31= SPV Kopi 138 | Sanitary | 13 | 110 | 54.04 | 110 | 110 | 53.6
MA | Nivå D + 1,2 m | ORIGINAL | SPV FETT | 0 | 31= SPV Kopi 138 | Sanitary | 13 | 110 | 51.626 | 51.6 | 110 | 110
MA | Nivå D + 1,2 m | ORIGINAL | SPV FETT | 0 | 31= SPV Kopi 138 | Sanitary | 13 | 110 | 85.76 | 85.8 | 110 | 110
MA | Nivå D + 1,2 m | ORIGINAL | SPV FETT | 0 | 31= SPV Kopi 138 | Sanitary | 13 | 110 | 92.941 | 110 | 110 | 93
MA | Nivå D + 1,2 m | ORIGINAL | SPV FETT | 0 | 31= SPV Kopi 138 | Sanitary | 13 | 110 | 358.78 | 110 | 110 | 359.4
MA | Nivå D + 1,2 m | ORIGINAL | SPV FETT | 0 | 31= SPV Kopi 138 | Sanitary | 13 | 75 | 623.231 | 75 | 75 | 623.2
MA | Nivå D + 1,2 m | ORIGINAL | SPV FETT | 0 | 31= SPV Kopi 138 | Sanitary | 13 | 110 | 19.634 | 20.3 | 110 | 110
MA | Nivå D + 1,2 m | ORIGINAL | SPV FETT | 0 | 31= SPV Kopi 138 | Sanitary | 13 | 110 | 48.847 | 110 | 110 | 48.9
MA | Nivå D + 1,2 m | ORIGINAL | SPV FETT | 0 | 31= SPV Kopi 138 | Sanitary | 13 | 110 | 298.518 | 110 | 110 | 298.5
MA | Nivå D + 1,2 m | ORIGINAL | SPV FETT | 0 | 31= SPV Kopi 138 | Sanitary | 13 | 110 | 19.338 | 110 | 19.1 | 110
MA | Nivå D + 1,2 m | ORIGINAL | SPV FETT | 0 | 31= SPV Kopi 138 | Sanitary | 13 | 135 | 212.732 | 135 | 135 | 212.7
MA | Nivå D + 1,2 m | ORIGINAL | SPV FETT | 0 | 31= SPV Kopi 138 | Sanitary | 13 | 135 | 69.588 | 135 | 135 | 69.6
MA | Nivå D + 1,2 m | ORIGINAL | SPV FETT | 0 | 31= SPV Kopi 138 | Sanitary | 13 | 135 | 2845.23 | 135 | 135 | 2845.2
MA | Nivå D + 1,2 m | ORIGINAL | SPV FETT | 0 | 31= SPV Kopi 138 | Sanitary | 13 | 135 | 108.54 | 135 | 135 | 108.5
MA | Nivå D + 1,2 m | ORIGINAL | SPV FETT | 0 | 31= SPV Kopi 138 | Sanitary | 13 | 135 | 1140.16 | 135 | 135 | 1140.2
MA | Nivå D + 1,2 m | ORIGINAL | SPV FETT | 0 | 31= SPV Kopi 138 | Sanitary | 13 | 135 | 137.681 | 135 | 135 | 138.5
MA | Nivå D + 1,2 m | ORIGINAL | SPV FETT | 0 | 31= SPV Kopi 138 | Sanitary | 13 | 135 | 967.949 | 135 | 135 | 967.9
MA | Nivå D + 1,2 m | ORIGINAL | SPV FETT | 0 | 31= SPV Kopi 138 | Sanitary | 13 | 75 | 1929.7 | 75 | 75 | 1929.7
MA | Nivå D + 1,2 m | ORIGINAL | SPV FETT | 0 | 31= SPV Kopi 138 | Sanitary | 13 | 75 | 467.265 | 75 | 75 | 467.3
MA | Nivå D + 1,2 m | ORIGINAL | SPV FETT | 0 | 31= SPV Kopi 138 | Sanitary | 13 | 75 | 54.839 | 75 | 75 | 55.4
MA | Nivå D + 1,2 m | ORIGINAL | SPV FETT | 0 | 31= SPV Kopi 138 | Sanitary | 13 | 75 | 565 | 75 | 75 | 565.3
MA | Nivå D + 1,2 m | ORIGINAL | SPV FETT | 0 | 31= SPV Kopi 138 | Sanitary | 13 | 75 | 143.401 | 75 | 75 | 143.4
MA | Nivå D + 1,2 m | ORIGINAL | SPV FETT | 0 | 31= SPV Kopi 138 | Sanitary | 13 | 75 | 69.687 | 75 | 70.4 | 75
MA | Nivå D + 1,2 m | ORIGINAL | SPV FETT | 0 | 31= SPV Kopi 138 | Sanitary | 13 | 75 | 375.221 | 75 | 75 | 375.2
MA | Nivå D + 1,2 m | ORIGINAL | SPV FETT | 0 | 31= SPV Kopi 138 | Sanitary | 13 | 75 | 282.327 | 75 | 75 | 281.7
MA | Nivå D + 1,2 m | ORIGINAL | SPV FETT | 0 | 31= SPV Kopi 138 | Sanitary | 13 | 75 | 82.824 | 75 | 75 | 83.3
MA | Nivå D + 1,2 m | ORIGINAL | SPV FETT | 0 | 31= SPV Kopi 138 | Sanitary | 13 | 75 | 273.934 | 75 | 75 | 274.5
MA | Nivå D + 1,2 m | ORIGINAL | SPV FETT | 0 | 31= SPV Kopi 138 | Sanitary | 13 | 75 | 742.376 | 75 | 75 | 742.4
MA | Nivå D + 1,2 m | ORIGINAL | SPV FETT | 0 | 31= SPV Kopi 138 | Sanitary | 13 | 75 | 89.375 | 75 | 75 | 88.9
MA | Nivå D + 1,2 m | ORIGINAL | SPV FETT | 0 | 31= SPV Kopi 138 | Sanitary | 13 | 75 | 53.226 | 75 | 75 | 53
MA | Nivå D + 1,2 m | ORIGINAL | SPV FETT | 0 | 31= SPV Kopi 138 | Sanitary | 13 | 75 | 300.636 | 75 | 75 | 300.6
MA | Nivå D + 1,2 m | ORIGINAL | SPV FETT | 0 | 31= SPV Kopi 138 | Sanitary | 13 | 75 | 122.056 | 75 | 75 | 122.4
MA | Nivå D + 1,2 m | ORIGINAL | SPV FETT | 0 | 31= SPV Kopi 138 | Sanitary | 13 | 75 | 134.553 | 75 | 75 | 134.7
MA | Nivå D + 1,2 m | ORIGINAL | SPV FETT | 0 | 31= SPV Kopi 138 | Sanitary | 13 | 75 | 75.871 | 75 | 75 | 75.8
MA | Nivå D + 1,2 m | ORIGINAL | SPV FETT | 0 | 31= SPV Kopi 138 | Sanitary | 13 | 75 | 66.582 | 75 | 75 | 67.4
MA | Nivå D + 1,2 m | ORIGINAL | SPV FETT | 0 | 31= SPV Kopi 138 | Sanitary | 13 | 75 | 1221.93 | 75 | 75 | 1221.9
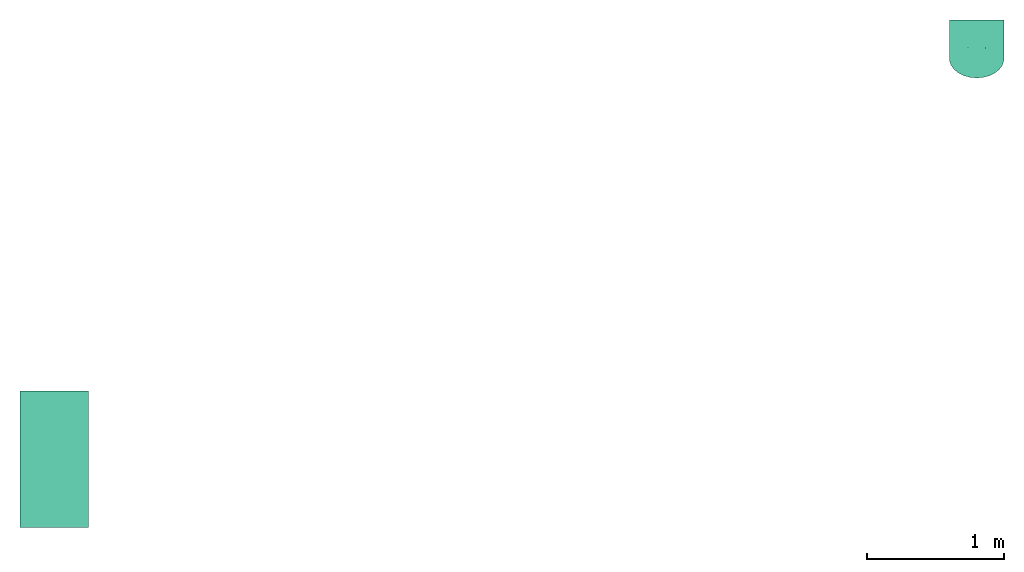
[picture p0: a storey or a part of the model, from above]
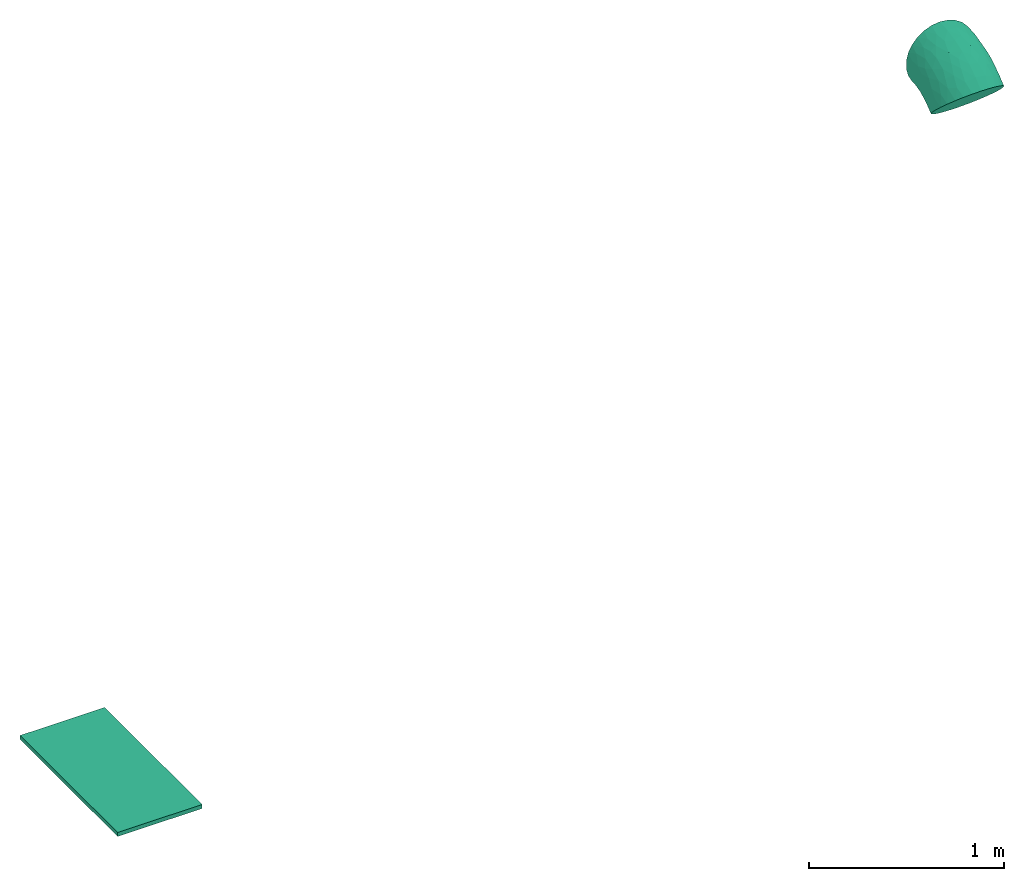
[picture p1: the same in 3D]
Properties of the parts of a building model (IFC2X3), part 8 of 11

# IfcFlowSegment: MA (100)
Name | In | Splitting | SystemType | qv_SizingFlow_ls (m3/s) = MagiCAD Pset_Heating, v_SizingFlow_ms (m/s) = MagiCAD Pset_Heating, pTot_SizingFlow_kPa (kPa) = MagiCAD Pset_Heating, dpTot_SizingFlow_kPa (kPa) = MagiCAD Pset_Water, dpTot_SizingFlow_kPa (kPa) = MagiCAD Pset_Water, pTot_SizingFlow_kPa (kPa) = MagiCAD Pset_Water, v_SizingFlow_ms (m/s) | SystemName = Group | SystemClass | Insulation_thickness_mm (mm) | ConnectionSize_mm (mm) | Length_mm (mm) | Width (Simplebim) (mm) | Height (Simplebim) (mm) | Length (Simplebim) (mm)
2 x MA | Nivå D + 1,2 m | ORIGINAL | SPV FETT | 0 | 31= SPV Kopi 138 | Sanitary | 13 | 75 | 100.2 | 75 | 75 | 100
MA | Nivå D + 1,2 m | ORIGINAL | SPV FETT | 0 | 31= SPV Kopi 138 | Sanitary | 13 | 75 | 128.682 | 75 | 75 | 128.7
MA | Nivå D + 1,2 m | ORIGINAL | SPV FETT | 0 | 31= SPV Kopi 138 | Sanitary | 13 | 75 | 3110.46 | 75 | 75 | 3110.5
MA | Nivå D + 1,2 m | ORIGINAL | SPV FETT | 0 | 31= SPV Kopi 138 | Sanitary | 13 | 75 | 575.745 | 75 | 75 | 575.7
MA | Nivå D + 1,2 m | ORIGINAL | SPV FETT | 0 | 31= SPV Kopi 138 | Sanitary | 13 | 75 | 12.625 | 75 | 75 | 13.1
MA | Nivå D + 1,2 m | ORIGINAL | SPV FETT | 0 | 31= SPV Kopi 138 | Sanitary | 13 | 75 | 1020.94 | 75 | 75 | 1020.9
MA | Nivå D + 1,2 m | ORIGINAL | SPV FETT | 0 | 31= SPV Kopi 138 | Sanitary | 13 | 75 | 1143.47 | 75 | 75 | 1143.5
MA | Nivå D + 1,2 m | ORIGINAL | SPV FETT | 0 | 31= SPV Kopi 138 | Sanitary | 13 | 75 | 63.701 | 75 | 75 | 64
MA | Nivå D + 1,2 m | ORIGINAL | SPV FETT | 0 | 31= SPV Kopi 138 | Sanitary | 13 | 75 | 2347.07 | 75 | 75 | 2347.1
MA | Nivå D + 1,2 m | ORIGINAL | SPV FETT | 0 | 31= SPV Kopi 138 | Sanitary | 13 | 75 | 85.841 | 75 | 75 | 85.8
MA | Nivå D + 1,2 m | ORIGINAL | SPV FETT | 0 | 31= SPV Kopi 138 | Sanitary | 13 | 75 | 389.743 | 75 | 75 | 389.7
MA | Nivå D + 1,2 m | ORIGINAL | SPV FETT | 0 | 31= SPV Kopi 138 | Sanitary | 13 | 75 | 481.495 | 75 | 75 | 482.5
MA | Nivå G - 2,0 m | RESULT | OV |  | 31= SPV Kopi 63 | Sanitary |  |  |  | 76 | 76 | 546
MA | Nivå D + 1,2 m | RESULT | SPV FETT |  | 31= SPV Kopi 138 | Sanitary |  |  |  | 76 | 68 | 1827
MA | Nivå D + 1,2 m | RESULT | SPV FETT |  | 31= SPV Kopi 138 | Sanitary |  |  |  | 76 | 76 | 102
MA | Nivå D + 1,2 m | RESULT | SPV FETT |  | 31= SPV Kopi 138 | Sanitary |  |  |  | 55 | 54 | 76
MA | Nivå D + 1,2 m | RESULT | SPV FETT |  | 31= SPV Kopi 138 | Sanitary |  |  |  | 73 | 29 | 76
MA | Nivå D + 1,2 m | RESULT | SPV FETT |  | 31= SPV Kopi 138 | Sanitary |  |  |  | 76 | 76 | 72

# IfcFlowSegment: PP avløpsrør (19)
In: Nivå F - 0,7 m
Type - PredefinedType: RIGIDSEGMENT
ePset_LocationTool - Splitting: ORIGINAL
ePset_Simplebim - Assembly Level: Leaf
MagiCAD Pset_Pipe - Material: PP avløpsrør; qv_SizingFlow_ls: 0 m3/s; User Code: PP; NationalCode: UB2.1114431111; SystemClass: Sanitary
MagiCAD Pset_Heating - v_SizingFlow_ms: 0 m/s; pTot_SizingFlow_kPa: 0 kPa; dpTot_SizingFlow_kPa: 0 kPa
MagiCAD Pset_Water - dpTot_SizingFlow_kPa: 0 kPa; pTot_SizingFlow_kPa: 0 kPa; v_SizingFlow_ms: 0 m/s
Name | Height (Simplebim) (mm) = Width (Simplebim) (mm) = ConnectionSize_mm (mm) | Length (Simplebim) (mm) | SystemType | Length_mm (mm) | SystemName = Group | Insulation_thickness_mm (mm)
PP avløpsrør | 32 | 37.9 | SPV FETT | 37.92 | 31= SPV Kopi 138 | 13
PP avløpsrør | 50 | 50 | SPV | 50 | 31= SPV Kopi 147 (11) | 0
PP avløpsrør | 50 | 55 | SPV | 55 | 31= SPV Kopi 147 (11) | 0
PP avløpsrør | 50 | 460 | SPV | 460.034 | 31= SPV Kopi 147 (11) | 0
PP avløpsrør | 50 | 665.6 | SPV | 665.591 | 31= SPV Kopi 147 (11) | 0
PP avløpsrør | 50 | 318.9 | SPV | 318.897 | 31= SPV Kopi 147 (11) | 0
PP avløpsrør | 75 | 146.7 | SPV | 146.655 | 31= SPV Kopi 147 (1) | 0
PP avløpsrør | 50 | 87.2 | SPV | 87.218 | 31= SPV Kopi 147 (1) | 0
PP avløpsrør | 50 | 65.1 | SPV | 64.816 | 31= SPV Kopi 147 (1) | 0
PP avløpsrør | 50 | 164.2 | SPV | 164.169 | 31= SPV Kopi 147 (1) | 0
PP avløpsrør | 32 | 31.2 | SPV FETT | 31.182 | 31= SPV Kopi 138 | 13
PP avløpsrør | 32 | 636.2 | SPV FETT | 636.184 | 31= SPV Kopi 138 | 13
PP avløpsrør | 32 | 40.8 | SPV FETT | 40.853 | 31= SPV Kopi 138 | 13
PP avløpsrør | 32 | 852.1 | SPV FETT | 852.113 | 31= SPV Kopi 138 | 13
PP avløpsrør | 32 | 52.9 | SPV FETT | 53.213 | 31= SPV Kopi 138 | 13
PP avløpsrør | 32 | 137.7 | SPV FETT | 137.75 | 31= SPV Kopi 138 | 13
PP avløpsrør | 32 | 404.8 | SPV FETT | 404.765 | 31= SPV Kopi 138 | 13
PP avløpsrør | 32 | 125.1 | SPV FETT | 125.129 | 31= SPV Kopi 138 | 13
PP avløpsrør | 32 | 52.1 | SPV FETT | 52.1 | 31= SPV Kopi 138 | 13

# IfcFlowSegment: Rektangulær kanal (5)
Type - Description: Rektangulær kanal, forsinket stål; PredefinedType: RIGIDSEGMENT
ePset_LocationTool - Splitting: ORIGINAL
MagiCAD Pset_Duct - UserCode: Rekt; qv_SizingFlow_ls: 0 m3/s; dpTot_SizingFlow_Pa: 0 kPa; pTot_SizingFlow_Pa: 0 kPa; v_SizingFlow_ms: 0 m/s; Insulation_thickness_mm: 0 mm; Description: Rektangulær kanal, forsinket stål
ePset_Simplebim - Assembly Level: Leaf
Name | In | Length_mm (mm) | Height (Simplebim) (mm) | Width (Simplebim) (mm) | Length (Simplebim) (mm) | Group
Rektangulær kanal | Nivå F | 147.995 | 148 | 300 | 400 | +TG=360.021-22 A
Rektangulær kanal | Nivå F | 500 | 500 | 1200 | 2110 | Mechanical 36 Avtrekk (obsolete) 149
Rektangulær kanal | Nivå F | 5940.29 | 200 | 400 | 5940.3 | +TG=360.021-22 A
Rektangulær kanal | Nivå F | 253.686 | 253.7 | 350 | 350 | +TG=360.021-22 A
Rektangulær kanal | Nivå F - 0,7 m | 260 | 200 | 260 | 400 | +TG=360.021-22 A

# IfcFlowSegment: SSt
In: Nivå D + 1,2 m
Type - PredefinedType: RIGIDSEGMENT
MagiCAD Pset_Pipe - Length_mm: 277.905 mm; SystemType: SPV LUFT; Material: Rustfritt stål - systemrør; SystemName: 31= SPV Kopi 21; Insulation_thickness_mm: 0 mm; qv_SizingFlow_ls: 0 m3/s; SystemClass: Sanitary; ConnectionSize_mm: 76 mm; User Code: SSt
ePset_SimplebimBasicQuantities - Length (Simplebim): 277.9 mm; Height (Simplebim): 76 mm; Width (Simplebim): 76 mm
ePset_Simplebim - Assembly Level: Leaf
ePset_LocationTool - Splitting: ORIGINAL
MagiCAD Pset_Heating - v_SizingFlow_ms: 0 m/s; pTot_SizingFlow_kPa: 0 kPa; dpTot_SizingFlow_kPa: 0 kPa
MagiCAD Pset_Water - dpTot_SizingFlow_kPa: 0 kPa; pTot_SizingFlow_kPa: 0 kPa; v_SizingFlow_ms: 0 m/s
Group: 31= SPV Kopi 21

# IfcFlowSegment: Sirkulær kanal
In: Nivå F - 0,7 m
Type - Description: Sirkulær kanal, forsinket stål; PredefinedType: RIGIDSEGMENT
ePset_SimplebimBasicQuantities - Height (Simplebim): 250 mm; Width (Simplebim): 250 mm; Length (Simplebim): 8434.9 mm
MagiCAD Pset_Duct - Length_mm: 8434.85 mm; Description: Sirkulær kanal, forsinket stål; qv_SizingFlow_ls: 0 m3/s; dpTot_SizingFlow_Pa: 0 kPa; pTot_SizingFlow_Pa: 0 kPa; v_SizingFlow_ms: 0 m/s; Insulation_thickness_mm: 0 mm; UserCode: KK02T
ePset_LocationTool - Splitting: ORIGINAL
ePset_Simplebim - Assembly Level: Leaf
Group: +TG=360.021-22 A

# IfcFlowSegment: Stålrør normaltykke (445)
Type - PredefinedType: RIGIDSEGMENT
MagiCAD Pset_Pipe - NationalCode: UB3.144613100; User Code: DN
ePset_Simplebim - Assembly Level: Leaf
Name | In | Length (Simplebim) (mm) | Height (Simplebim) (mm) | Width (Simplebim) (mm) | Splitting | SystemClass | SystemName = Group | SystemType | Insulation_thickness_mm (mm) | qv_SizingFlow_ls (m3/s) | Length_mm (mm) | ConnectionSize_mm (mm) | Material | MagiCAD Pset_Heating, v_SizingFlow_ms (m/s) = MagiCAD Pset_Heating, pTot_SizingFlow_kPa (kPa) = MagiCAD Pset_Heating, dpTot_SizingFlow_kPa (kPa) = MagiCAD Pset_Water, dpTot_SizingFlow_kPa (kPa) = MagiCAD Pset_Water, pTot_SizingFlow_kPa (kPa) = MagiCAD Pset_Water, v_SizingFlow_ms (m/s)
6 x Stålrør normaltykke | Nivå F - 0,7 m | 176.9 | 33.8 | 33.8 | ORIGINAL | Fire Protection Wet | +TG=332.003 (2) | SPRINKEL | 0 | 0 | 176.898 | 25 | Stålrør normaltykke | 0
6 x Stålrør normaltykke | Nivå F - 0,7 m | 2932.4 | 76 | 76 | ORIGINAL | Fire Protection Wet | +TG=332.003 (2) | SPRINKEL | 0 | 0 | 2932.4 | 65 |  | 0
Stålrør normaltykke | Nivå F - 0,7 m | 2937.8 | 76 | 76 | ORIGINAL | Fire Protection Wet | +TG=332.003 (2) | SPRINKEL | 0 | 0 | 2937.81 | 65 |  | 0
Stålrør normaltykke | Nivå F - 0,7 m | 491 | 76 | 76 | ORIGINAL | Fire Protection Wet | +TG=332.003 (2) | SPRINKEL | 0 | 0 | 490.973 | 65 |  | 0
Stålrør normaltykke | Nivå F - 0,7 m | 363.8 | 89 | 89 | ORIGINAL | Fire Protection Wet | +TG=332.003 (2) | SPRINKEL | 0 | 0 | 363.839 | 80 | Stålrør normaltykke | 0
Stålrør normaltykke | Nivå F - 0,7 m | 1390.9 | 76 | 76 | ORIGINAL | Fire Protection Wet | +TG=332.003 (2) | SPRINKEL | 0 | 0 | 1390.85 | 65 | Stålrør normaltykke | 0
Stålrør normaltykke | Nivå F - 0,7 m | 579.2 | 60.2 | 60.2 | ORIGINAL | Fire Protection Wet | +TG=332.003 (2) | SPRINKEL | 0 | 0 | 579.2 | 50 | Stålrør normaltykke | 0
Stålrør normaltykke | Nivå F - 0,7 m | 25 | 89 | 89 | ORIGINAL | Fire Protection Wet | +TG=332.003 (2) | SPRINKEL | 0 | 0 | 25 | 80 | Stålrør normaltykke | 0
Stålrør normaltykke | Nivå F - 0,7 m | 1228.8 | 60.2 | 60.2 | ORIGINAL | Fire Protection Wet | +TG=332.003 (2) | SPRINKEL | 0 | 0 | 1228.77 | 50 | Stålrør normaltykke | 0
Stålrør normaltykke | Nivå F - 0,7 m | 1233.8 | 60.2 | 60.2 | ORIGINAL | Fire Protection Wet | +TG=332.003 (2) | SPRINKEL | 0 | 0 | 1233.77 | 50 | Stålrør normaltykke | 0
Stålrør normaltykke | Nivå F - 0,7 m | 4751.1 | 60.2 | 60.2 | ORIGINAL | Fire Protection Wet | +TG=332.003 (2) | SPRINKEL | 0 | 0 | 4751.13 | 50 | Stålrør normaltykke | 0
Stålrør normaltykke | Nivå F - 0,7 m | 1025.2 | 33.8 | 33.8 | ORIGINAL | Fire Protection Wet | +TG=332.003 (2) | SPRINKEL | 0 | 0 | 1025.22 | 25 | Stålrør normaltykke | 0
Stålrør normaltykke | Nivå F - 0,7 m | 68.6 | 33.8 | 33.8 | ORIGINAL | Fire Protection Wet | +TG=332.003 (2) | SPRINKEL | 0 | 0 | 68.938 | 25 | Stålrør normaltykke | 0
4 x Stålrør normaltykke | Nivå F - 0,7 m | 60.8 | 33.8 | 33.8 | ORIGINAL | Fire Protection Wet | +TG=332.003 (2) | SPRINKEL | 0 | 0 | 60.698 | 25 | Stålrør normaltykke | 0
2 x Stålrør normaltykke | Nivå F - 0,7 m | 1120.9 | 33.8 | 33.8 | ORIGINAL | Fire Protection Wet | +TG=332.003 (2) | SPRINKEL | 0 | 0 | 1120.9 | 25 | Stålrør normaltykke | 0
2 x Stålrør normaltykke | Nivå F - 0,7 m | 1239.6 | 33.8 | 33.8 | ORIGINAL | Fire Protection Wet | +TG=332.003 (2) | SPRINKEL | 0 | 0 | 1239.58 | 25 | Stålrør normaltykke | 0
2 x Stålrør normaltykke | Nivå F - 0,7 m | 103.5 | 33.8 | 33.8 | ORIGINAL | Fire Protection Wet | +TG=332.003 (2) | SPRINKEL | 0 | 0 | 104.09 | 25 | Stålrør normaltykke | 0
Stålrør normaltykke | Nivå F - 0,7 m | 8.9 | 60.2 | 60.2 | ORIGINAL | Fire Protection Wet | +TG=332.003 (2) | SPRINKEL | 0 | 0 | 8.873 | 50 | Stålrør normaltykke | 0
Stålrør normaltykke | Nivå F - 0,7 m | 613.3 | 76 | 76 | ORIGINAL | Fire Protection Wet | +TG=332.003 (2) | SPRINKEL | 0 | 0 | 613.28 | 65 | Stålrør normaltykke | 0
Stålrør normaltykke | Nivå F - 0,7 m | 25.9 | 48.2 | 48.2 | ORIGINAL | Fire Protection Wet | +TG=332.003 (2) | SPRINKEL | 0 | 0 | 25.873 | 40 | Stålrør normaltykke | 0
Stålrør normaltykke | Nivå F - 0,7 m | 1481.4 | 33.8 | 33.8 | ORIGINAL | Fire Protection Wet | +TG=332.003 (2) | SPRINKEL | 0 | 0 | 1481.35 | 25 | Stålrør normaltykke | 0
Stålrør normaltykke | Nivå F - 0,7 m | 706.6 | 33.8 | 33.8 | ORIGINAL | Fire Protection Wet | +TG=332.003 (2) | SPRINKEL | 0 | 0 | 706.631 | 25 | Stålrør normaltykke | 0
Stålrør normaltykke | Nivå F - 0,7 m | 99.8 | 33.8 | 33.8 | ORIGINAL | Fire Protection Wet | +TG=332.003 (2) | SPRINKEL | 0 | 0 | 100.248 | 25 | Stålrør normaltykke | 0
Stålrør normaltykke | Nivå F - 0,7 m | 388.7 | 33.8 | 33.8 | ORIGINAL | Fire Protection Wet | +TG=332.003 (2) | SPRINKEL | 0 | 0 | 388.748 | 25 | Stålrør normaltykke | 0
Stålrør normaltykke | Nivå F - 0,7 m | 264.4 | 60.2 | 60.2 | ORIGINAL | Fire Protection Wet | +TG=332.003 (2) | SPRINKEL | 0 | 0 | 264.377 | 50 | Stålrør normaltykke | 0
3 x Stålrør normaltykke | Nivå F - 0,7 m | 398.2 | 33.8 | 33.8 | ORIGINAL | Fire Protection Wet | +TG=332.003 (2) | SPRINKEL | 0 | 0 | 397.748 | 25 | Stålrør normaltykke | 0
Stålrør normaltykke | Nivå F - 0,7 m | 674.5 | 48.2 | 48.2 | ORIGINAL | Fire Protection Wet | +TG=332.003 (2) | SPRINKEL | 0 | 0 | 674.527 | 40 | Stålrør normaltykke | 0
Stålrør normaltykke | Nivå F - 0,7 m | 951.9 | 48.2 | 48.2 | ORIGINAL | Fire Protection Wet | +TG=332.003 (2) | SPRINKEL | 0 | 0 | 951.9 | 40 | Stålrør normaltykke | 0
Stålrør normaltykke | Nivå F - 0,7 m | 957.4 | 48.2 | 48.2 | ORIGINAL | Fire Protection Wet | +TG=332.003 (2) | SPRINKEL | 0 | 0 | 957.4 | 40 | Stålrør normaltykke | 0
Stålrør normaltykke | Nivå F - 0,7 m | 408.7 | 33.8 | 33.8 | ORIGINAL | Fire Protection Wet | +TG=332.003 (2) | SPRINKEL | 0 | 0 | 408.698 | 25 | Stålrør normaltykke | 0
Stålrør normaltykke | Nivå F - 0,7 m | 142.4 | 33.8 | 33.8 | ORIGINAL | Fire Protection Wet | +TG=332.003 (2) | SPRINKEL | 0 | 0 | 141.973 | 25 | Stålrør normaltykke | 0
2 x Stålrør normaltykke | Nivå F - 0,7 m | 399.9 | 33.8 | 33.8 | ORIGINAL | Fire Protection Wet | +TG=332.003 (2) | SPRINKEL | 0 | 0 | 400.248 | 25 | Stålrør normaltykke | 0
Stålrør normaltykke | Nivå F - 0,7 m | 953.8 | 33.8 | 33.8 | ORIGINAL | Fire Protection Wet | +TG=332.003 (2) | SPRINKEL | 0 | 0 | 953.802 | 25 | Stålrør normaltykke | 0
Stålrør normaltykke | Nivå F - 0,7 m | 707.9 | 48.2 | 48.2 | ORIGINAL | Fire Protection Wet | +TG=332.003 (2) | SPRINKEL | 0 | 0 | 707.9 | 40 | Stålrør normaltykke | 0
Stålrør normaltykke | Nivå F - 0,7 m | 944.8 | 33.8 | 33.8 | ORIGINAL | Fire Protection Wet | +TG=332.003 (2) | SPRINKEL | 0 | 0 | 944.802 | 25 | Stålrør normaltykke | 0
Stålrør normaltykke | Nivå F - 0,7 m | 189.4 | 60.2 | 60.2 | ORIGINAL | Fire Protection Wet | +TG=332.003 (2) | SPRINKEL | 0 | 0 | 189.4 | 50 | Stålrør normaltykke | 0
Stålrør normaltykke | Nivå F - 0,7 m | 333.1 | 33.8 | 33.8 | ORIGINAL | Fire Protection Wet | +TG=332.003 (2) | SPRINKEL | 0 | 0 | 333.11 | 25 | Stålrør normaltykke | 0
Stålrør normaltykke | Nivå F - 0,7 m | 57 | 33.8 | 33.8 | ORIGINAL | Fire Protection Wet | +TG=332.003 (2) | SPRINKEL | 0 | 0 | 57.442 | 25 | Stålrør normaltykke | 0
2 x Stålrør normaltykke | Nivå F - 0,7 m | 1124.2 | 33.8 | 33.8 | ORIGINAL | Fire Protection Wet | +TG=332.003 (2) | SPRINKEL | 0 | 0 | 1124.2 | 25 | Stålrør normaltykke | 0
2 x Stålrør normaltykke | Nivå F - 0,7 m | 2332.4 | 60.2 | 60.2 | ORIGINAL | Fire Protection Wet | +TG=332.003 (2) | SPRINKEL | 0 | 0 | 2332.4 | 50 | Stålrør normaltykke | 0
Stålrør normaltykke | Nivå F - 0,7 m | 95 | 60.2 | 60.2 | ORIGINAL | Fire Protection Wet | +TG=332.003 (2) | SPRINKEL | 0 | 0 | 94.95 | 50 | Stålrør normaltykke | 0
Stålrør normaltykke | Nivå F - 0,7 m | 279.3 | 89 | 89 | ORIGINAL | Fire Protection Wet | +TG=332.003 (2) | SPRINKEL | 0 | 0 | 279.307 | 80 | Stålrør normaltykke | 0
Stålrør normaltykke | Nivå F - 0,7 m | 1146.2 | 33.8 | 33.8 | ORIGINAL | Fire Protection Wet | +TG=332.003 (2) | SPRINKEL | 0 | 0 | 1146.2 | 25 | Stålrør normaltykke | 0
Stålrør normaltykke | Nivå F - 0,7 m | 692.4 | 33.8 | 33.8 | ORIGINAL | Fire Protection Wet | +TG=332.003 (2) | SPRINKEL | 0 | 0 | 692.4 | 25 | Stålrør normaltykke | 0
Stålrør normaltykke | Nivå F - 0,7 m | 95.2 | 33.8 | 33.8 | ORIGINAL | Fire Protection Wet | +TG=332.003 (2) | SPRINKEL | 0 | 0 | 95.248 | 25 | Stålrør normaltykke | 0
3 x Stålrør normaltykke | Nivå F - 0,7 m | 729.1 | 33.8 | 33.8 | ORIGINAL | Fire Protection Wet | +TG=332.003 (2) | SPRINKEL | 0 | 0 | 729.05 | 25 | Stålrør normaltykke | 0
3 x Stålrør normaltykke | Nivå F - 0,7 m | 200.2 | 33.8 | 33.8 | ORIGINAL | Fire Protection Wet | +TG=332.003 (2) | SPRINKEL | 0 | 0 | 200.248 | 25 | Stålrør normaltykke | 0
Stålrør normaltykke | Nivå F - 0,7 m | 2284 | 76 | 76 | ORIGINAL | Fire Protection Wet | +TG=332.003 (2) | SPRINKEL | 0 | 0 | 2284.03 | 65 |  | 0
5 x Stålrør normaltykke | Nivå F - 0,7 m | 26.2 | 33.8 | 33.8 | ORIGINAL | Fire Protection Wet | +TG=332.003 (46) | SPRINKEL | 0 | 0 | 26.253 | 25 | Stålrør normaltykke | 0
2 x Stålrør normaltykke | Nivå F - 0,7 m | 873.4 | 33.8 | 33.8 | ORIGINAL | Fire Protection Wet | +TG=332.003 (46) | SPRINKEL | 0 | 0 | 873.354 | 25 | Stålrør normaltykke | 0
5 x Stålrør normaltykke | Nivå F - 0,7 m | 2932.4 | 33.8 | 33.8 | ORIGINAL | Fire Protection Wet | +TG=332.003 (46) | SPRINKEL | 0 | 0 | 2932.4 | 25 | Stålrør normaltykke | 0
5 x Stålrør normaltykke | Nivå F - 0,7 m | 33.8 | 17.8 | 33.8 | ORIGINAL | Fire Protection Wet | +TG=332.003 (46) | SPRINKEL | 0 | 0 | 17.803 | 25 | Stålrør normaltykke | 0
Stålrør normaltykke | Nivå F - 0,7 m | 148.2 | 76 | 76 | ORIGINAL | Fire Protection Wet | +TG=332.003 (46) | SPRINKEL | 0 | 0 | 148.246 | 65 | Stålrør normaltykke | 0
Stålrør normaltykke | Nivå F - 0,7 m | 76 | 69.1 | 76 | ORIGINAL | Fire Protection Wet | +TG=332.003 (46) | SPRINKEL | 0 | 0 | 69.069 | 65 | Stålrør normaltykke | 0
Stålrør normaltykke | Nivå F - 0,7 m | 1290.8 | 76 | 76 | ORIGINAL | Fire Protection Wet | +TG=332.003 (46) | SPRINKEL | 0 | 0 | 1290.77 | 65 | Stålrør normaltykke | 0
2 x Stålrør normaltykke | Nivå F - 0,7 m | 2909 | 48.2 | 48.2 | ORIGINAL | Fire Protection Wet | +TG=332.003 (46) | SPRINKEL | 0 | 0 | 2909.05 | 40 | Stålrør normaltykke | 0
2 x Stålrør normaltykke | Nivå F - 0,7 m | 2917.8 | 33.8 | 33.8 | ORIGINAL | Fire Protection Wet | +TG=332.003 (46) | SPRINKEL | 0 | 0 | 2917.8 | 25 | Stålrør normaltykke | 0
2 x Stålrør normaltykke | Nivå F - 0,7 m | 870.9 | 33.8 | 33.8 | ORIGINAL | Fire Protection Wet | +TG=332.003 (46) | SPRINKEL | 0 | 0 | 870.854 | 25 | Stålrør normaltykke | 0
Stålrør normaltykke | Nivå F - 0,7 m | 816.4 | 33.8 | 33.8 | ORIGINAL | Fire Protection Wet | +TG=332.003 (46) | SPRINKEL | 0 | 0 | 816.354 | 25 | Stålrør normaltykke | 0
Stålrør normaltykke | Nivå F - 0,7 m | 69.7 | 76 | 76 | ORIGINAL | Fire Protection Wet | +TG=332.003 (46) | SPRINKEL | 0 | 0 | 69.689 | 65 | Stålrør normaltykke | 0
Stålrør normaltykke | Nivå F - 0,7 m | 261.8 | 76 | 76 | ORIGINAL | Fire Protection Wet | +TG=332.003 (46) | SPRINKEL | 0 | 0 | 261.843 | 65 | Stålrør normaltykke | 0
Stålrør normaltykke | Nivå F - 0,7 m | 204.6 | 33.8 | 33.8 | ORIGINAL | Fire Protection Wet | +TG=332.003 (12) | SPRINKEL | 0 | 0 | 204.645 | 25 | Stålrør normaltykke | 0
Stålrør normaltykke | Nivå F - 0,7 m | 49.8 | 33.8 | 33.8 | ORIGINAL | Fire Protection Wet | +TG=332.003 (12) | SPRINKEL | 0 | 0 | 49.999 | 25 | Stålrør normaltykke | 0
Stålrør normaltykke | Nivå F - 0,7 m | 49.8 | 33.8 | 33.8 | ORIGINAL | Fire Protection Wet | +TG=332.003 (12) | SPRINKEL | 0 | 0 | 50 | 25 | Stålrør normaltykke | 0
Stålrør normaltykke | Nivå F - 0,7 m | 928.6 | 33.8 | 33.8 | ORIGINAL | Fire Protection Wet | +TG=332.003 (12) | SPRINKEL | 0 | 0 | 929.05 | 25 | Stålrør normaltykke | 0
Stålrør normaltykke | Nivå F - 0,7 m | 1269.1 | 76 | 76 | ORIGINAL | Fire Protection Wet | +TG=332.003 (2) | SPRINKEL | 0 | 0 | 1269.06 | 65 |  | 0
Stålrør normaltykke | Nivå F - 0,7 m | 2432.4 | 33.8 | 33.8 | ORIGINAL | Fire Protection Wet | +TG=332.003 (12) | SPRINKEL | 0 | 0 | 2432.4 | 25 | Stålrør normaltykke | 0
Stålrør normaltykke | Nivå F - 0,7 m | 951.9 | 33.8 | 33.8 | ORIGINAL | Fire Protection Wet | +TG=332.003 (12) | SPRINKEL | 0 | 0 | 952.4 | 25 | Stålrør normaltykke | 0
Stålrør normaltykke | Nivå F - 0,7 m | 960.8 | 33.8 | 33.8 | ORIGINAL | Fire Protection Wet | +TG=332.003 (12) | SPRINKEL | 0 | 0 | 960.849 | 25 | Stålrør normaltykke | 0
Stålrør normaltykke | Nivå F - 0,7 m | 1309.1 | 33.8 | 33.8 | ORIGINAL | Fire Protection Wet | +TG=332.003 (12) | SPRINKEL | 0 | 0 | 1309.12 | 25 | Stålrør normaltykke | 0
Stålrør normaltykke | Nivå F - 0,7 m | 264 | 33.8 | 33.8 | ORIGINAL | Fire Protection Wet | +TG=332.003 (2) | SPRINKEL | 0 | 0 | 264.351 | 25 | Stålrør normaltykke | 0
Stålrør normaltykke | Nivå F - 0,7 m | 107.9 | 33.8 | 33.8 | ORIGINAL | Fire Protection Wet | +TG=332.003 (2) | SPRINKEL | 0 | 0 | 107.933 | 25 | Stålrør normaltykke | 0
Stålrør normaltykke | Nivå F - 0,7 m | 353.8 | 33.8 | 33.8 | ORIGINAL | Fire Protection Wet | +TG=332.003 (2) | SPRINKEL | 0 | 0 | 353.8 | 25 | Stålrør normaltykke | 0
Stålrør normaltykke | Nivå F - 0,7 m | 832.4 | 33.8 | 33.8 | ORIGINAL | Fire Protection Wet | +TG=332.003 (2) | SPRINKEL | 0 | 0 | 832.4 | 25 | Stålrør normaltykke | 0
Stålrør normaltykke | Nivå F - 0,7 m | 278.3 | 33.8 | 33.8 | ORIGINAL | Fire Protection Wet | +TG=332.003 (2) | SPRINKEL | 0 | 0 | 277.494 | 25 | Stålrør normaltykke | 0
Stålrør normaltykke | Nivå F - 0,7 m | 449 | 33.8 | 33.8 | ORIGINAL | Fire Protection Wet | +TG=332.003 (2) | SPRINKEL | 0 | 0 | 448.975 | 25 | Stålrør normaltykke | 0
Stålrør normaltykke | Nivå F - 0,7 m | 846.6 | 33.8 | 33.8 | ORIGINAL | Fire Protection Wet | +TG=332.003 (2) | SPRINKEL | 0 | 0 | 846.644 | 25 | Stålrør normaltykke | 0
Stålrør normaltykke | Nivå F - 0,7 m | 260.8 | 33.8 | 33.8 | ORIGINAL | Fire Protection Wet | +TG=332.003 (2) | SPRINKEL | 0 | 0 | 260.848 | 25 | Stålrør normaltykke | 0
Stålrør normaltykke | Nivå F - 0,7 m | 100 | 89 | 89 | ORIGINAL | Fire Protection Wet | +TG=332.003 (2) | SPRINKEL | 0 | 0 | 99.972 | 80 | Stålrør normaltykke | 0
Stålrør normaltykke | Nivå F - 0,7 m | 54.5 | 33.8 | 33.8 | ORIGINAL | Fire Protection Wet | +TG=332.003 (2) | SPRINKEL | 0 | 0 | 53.848 | 25 | Stålrør normaltykke | 0
Stålrør normaltykke | Nivå F - 0,7 m | 1142.8 | 33.8 | 33.8 | ORIGINAL | Fire Protection Wet | +TG=332.003 (2) | SPRINKEL | 0 | 0 | 1143.12 | 25 | Stålrør normaltykke | 0
Stålrør normaltykke | Nivå F - 0,7 m | 559.5 | 60.2 | 60.2 | ORIGINAL | Fire Protection Wet | +TG=332.003 (2) | SPRINKEL | 0 | 0 | 560.473 | 50 | Stålrør normaltykke | 0
Stålrør normaltykke | Nivå D + 1,2 m | 57 | 33.8 | 33.8 | ORIGINAL | Fire Protection Wet | +TG=332.002 (1) (2) | SPRINKEL | 0 | 0 | 57.024 | 25 | Stålrør normaltykke | 0
Stålrør normaltykke | Nivå D + 1,2 m | 65.5 | 33.8 | 33.8 | ORIGINAL | Fire Protection Wet | +TG=332.002 (1) (2) | SPRINKEL | 0 | 0 | 65.474 | 25 | Stålrør normaltykke | 0
Stålrør normaltykke | Nivå D + 1,2 m | 328.8 | 33.8 | 33.8 | ORIGINAL | Fire Protection Wet | +TG=332.002 (1) (2) | SPRINKEL | 0 | 0 | 328.914 | 25 | Stålrør normaltykke | 0
Stålrør normaltykke | Nivå D + 1,2 m | 22.7 | 33.8 | 33.8 | ORIGINAL | Fire Protection Wet | +TG=332.002 (1) (2) | SPRINKEL | 0 | 0 | 22.612 | 25 | Stålrør normaltykke | 0
Stålrør normaltykke | Nivå D + 1,2 m | 96.1 | 33.8 | 33.8 | ORIGINAL | Fire Protection Wet | +TG=332.002 (1) (2) | SPRINKEL | 0 | 0 | 96.287 | 25 | Stålrør normaltykke | 0
Stålrør normaltykke | Nivå D + 1,2 m | 58.4 | 33.8 | 33.8 | ORIGINAL | Fire Protection Wet | +TG=332.002 (1) (2) | SPRINKEL | 0 | 0 | 57.848 | 25 | Stålrør normaltykke | 0
Stålrør normaltykke | Nivå D + 1,2 m | 1291.1 | 33.8 | 33.8 | ORIGINAL | Fire Protection Wet | +TG=332.002 (1) (2) | SPRINKEL | 0 | 0 | 1291.08 | 25 | Stålrør normaltykke | 0
Stålrør normaltykke | Nivå D + 1,2 m | 42 | 33.8 | 33.8 | ORIGINAL | Fire Protection Wet | +TG=332.002 (1) (2) | SPRINKEL | 0 | 0 | 42.178 | 25 | Stålrør normaltykke | 0
Stålrør normaltykke | Nivå D + 1,2 m | 3754.3 | 33.8 | 33.8 | ORIGINAL | Fire Protection Wet | +TG=332.002 (1) (2) | SPRINKEL | 0 | 0 | 3754.25 | 25 | Stålrør normaltykke | 0
Stålrør normaltykke | Nivå D + 1,2 m | 33.8 | 17.8 | 33.8 | ORIGINAL | Fire Protection Wet | +TG=332.002 (1) (2) | SPRINKEL | 0 | 0 | 17.554 | 25 | Stålrør normaltykke | 0
Stålrør normaltykke | Nivå D + 1,2 m | 45.6 | 33.8 | 33.8 | ORIGINAL | Fire Protection Wet | +TG=332.002 (1) (2) | SPRINKEL | 0 | 0 | 46.004 | 25 | Stålrør normaltykke | 0
Stålrør normaltykke | Nivå D + 1,2 m | 922.7 | 33.8 | 33.8 | ORIGINAL | Fire Protection Wet | +TG=332.002 (1) (2) | SPRINKEL | 0 | 0 | 922.679 | 25 | Stålrør normaltykke | 0
Stålrør normaltykke | Nivå D + 1,2 m | 635.8 | 33.8 | 33.8 | ORIGINAL | Fire Protection Wet | +TG=332.002 (1) (2) | SPRINKEL | 0 | 0 | 635.839 | 25 | Stålrør normaltykke | 0
Stålrør normaltykke | Nivå D + 1,2 m | 33.8 | 8.4 | 33.8 | ORIGINAL | Fire Protection Wet | +TG=332.002 (1) (2) | SPRINKEL | 0 | 0 | 7.848 | 25 | Stålrør normaltykke | 0
Stålrør normaltykke | Nivå D + 1,2 m | 16.5 | 33.8 | 33.8 | ORIGINAL | Fire Protection Wet | +TG=332.002 (1) (2) | SPRINKEL | 0 | 0 | 16.298 | 25 | Stålrør normaltykke | 0
Stålrør normaltykke | Nivå D + 1,2 m | 3498.7 | 33.8 | 33.8 | ORIGINAL | Fire Protection Wet | +TG=332.002 (1) (2) | SPRINKEL | 0 | 0 | 3498.74 | 25 | Stålrør normaltykke | 0
Stålrør normaltykke | Nivå D + 1,2 m | 3585 | 33.8 | 33.8 | ORIGINAL | Fire Protection Wet | +TG=332.002 (1) (2) | SPRINKEL | 0 | 0 | 3584.96 | 25 | Stålrør normaltykke | 0
Stålrør normaltykke | Nivå D + 1,2 m | 33.8 | 33.1 | 33.8 | ORIGINAL | Fire Protection Wet | +TG=332.002 (1) (2) | SPRINKEL | 0 | 0 | 32.848 | 25 | Stålrør normaltykke | 0
Stålrør normaltykke | Nivå D + 1,2 m | 26.2 | 33.8 | 33.8 | ORIGINAL | Fire Protection Wet | +TG=332.002 (1) (2) | SPRINKEL | 0 | 0 | 26.298 | 25 | Stålrør normaltykke | 0
Stålrør normaltykke | Nivå D + 1,2 m | 3526.2 | 33.8 | 33.8 | ORIGINAL | Fire Protection Wet | +TG=332.002 (1) (2) | SPRINKEL | 0 | 0 | 3526.24 | 25 | Stålrør normaltykke | 0
Stålrør normaltykke | Nivå D + 1,2 m | 3509.9 | 33.8 | 33.8 | ORIGINAL | Fire Protection Wet | +TG=332.002 (1) (2) | SPRINKEL | 0 | 0 | 3509.96 | 25 | Stålrør normaltykke | 0
Stålrør normaltykke | Nivå D + 1,2 m | 12.4 | 33.8 | 33.8 | ORIGINAL | Fire Protection Wet | +TG=332.003 (10) | SPRINKEL | 0 | 0 | 12.498 | 25 | Stålrør normaltykke | 0
Stålrør normaltykke | Nivå D + 1,2 m | 284.8 | 76 | 76 | ORIGINAL | Fire Protection Wet | +TG=332.003 (10) | SPRINKEL | 0 | 0 | 284.823 | 65 | Stålrør normaltykke | 0
Stålrør normaltykke | Nivå D + 1,2 m | 33.8 | 12.7 | 33.8 | ORIGINAL | Fire Protection Wet | +TG=332.003 (10) | SPRINKEL | 0 | 0 | 13.348 | 25 | Stålrør normaltykke | 0
Stålrør normaltykke | Nivå D + 1,2 m | 795.6 | 48.2 | 48.2 | ORIGINAL | Fire Protection Wet | +TG=332.003 (10) | SPRINKEL | 0 | 0 | 795.56 | 40 | Stålrør normaltykke | 0
Stålrør normaltykke | Nivå D + 1,2 m | 4467.4 | 48.2 | 48.2 | ORIGINAL | Fire Protection Wet | +TG=332.003 (10) | SPRINKEL | 0 | 0 | 4467.38 | 40 | Stålrør normaltykke | 0
Stålrør normaltykke | Nivå D + 1,2 m | 1551.7 | 76 | 76 | ORIGINAL | Fire Protection Wet | +TG=332.003 (10) | SPRINKEL | 0 | 0 | 1551.66 | 65 | Stålrør normaltykke | 0
Stålrør normaltykke | Nivå D + 1,2 m | 27.2 | 33.8 | 33.8 | ORIGINAL | Fire Protection Wet | +TG=332.002 (1) (2) | SPRINKEL | 0 | 0 | 27.001 | 25 | Stålrør normaltykke | 0
Stålrør normaltykke | Nivå D + 1,2 m | 33.8 | 21.5 | 33.8 | ORIGINAL | Fire Protection Wet | +TG=332.002 (1) (2) | SPRINKEL | 0 | 0 | 21.857 | 25 | Stålrør normaltykke | 0
Stålrør normaltykke | Nivå D + 1,2 m | 2444.9 | 33.8 | 33.8 | ORIGINAL | Fire Protection Wet | +TG=332.002 (1) (2) | SPRINKEL | 0 | 0 | 2444.85 | 25 | Stålrør normaltykke | 0
Stålrør normaltykke | Nivå D + 1,2 m | 662.1 | 33.8 | 33.8 | ORIGINAL | Fire Protection Wet | +TG=332.002 (1) (2) | SPRINKEL | 0 | 0 | 662.201 | 25 | Stålrør normaltykke | 0
Stålrør normaltykke | Nivå D + 1,2 m | 1229.8 | 48.2 | 48.2 | ORIGINAL | Fire Protection Wet | +TG=332.003 (10) | SPRINKEL | 0 | 0 | 1229.8 | 40 | Stålrør normaltykke | 0
Stålrør normaltykke | Nivå D + 1,2 m | 2150 | 76 | 76 | ORIGINAL | Fire Protection Wet | +TG=332.003 (10) | SPRINKEL | 0 | 0 | 2149.97 | 65 | Stålrør normaltykke | 0
Stålrør normaltykke | Nivå D + 1,2 m | 1134.6 | 76 | 76 | ORIGINAL | Fire Protection Wet | +TG=332.003 (10) | SPRINKEL | 0 | 0 | 1134.59 | 65 | Stålrør normaltykke | 0
Stålrør normaltykke | Nivå D + 1,2 m | 130.6 | 76 | 76 | ORIGINAL | Fire Protection Wet | +TG=332.003 (10) | SPRINKEL | 0 | 0 | 130.591 | 65 | Stålrør normaltykke | 0
Stålrør normaltykke | Nivå D + 1,2 m | 76 | 37.6 | 76 | ORIGINAL | Fire Protection Wet | +TG=332.003 (10) | SPRINKEL | 0 | 0 | 37.892 | 65 | Stålrør normaltykke | 0
Stålrør normaltykke | Nivå D + 1,2 m | 70.5 | 33.8 | 33.8 | ORIGINAL | Fire Protection Wet | +TG=332.003 (10) | SPRINKEL | 0 | 0 | 69.698 | 25 | Stålrør normaltykke | 0
Stålrør normaltykke | Nivå D + 1,2 m | 2797.2 | 33.8 | 33.8 | ORIGINAL | Fire Protection Wet | +TG=332.002 (1) (2) | SPRINKEL | 0 | 0 | 2797.19 | 25 | Stålrør normaltykke | 0
Stålrør normaltykke | Nivå D + 1,2 m | 39.7 | 33.8 | 33.8 | ORIGINAL | Fire Protection Wet | +TG=332.002 (1) (2) | SPRINKEL | 0 | 0 | 39.996 | 25 | Stålrør normaltykke | 0
Stålrør normaltykke | Nivå D + 1,2 m | 1012.9 | 33.8 | 33.8 | ORIGINAL | Fire Protection Wet | +TG=332.002 (1) (2) | SPRINKEL | 0 | 0 | 1013.4 | 25 | Stålrør normaltykke | 0
Stålrør normaltykke | Nivå D + 1,2 m | 51.6 | 33.8 | 33.8 | ORIGINAL | Fire Protection Wet | +TG=332.002 (1) (2) | SPRINKEL | 0 | 0 | 51.899 | 25 | Stålrør normaltykke | 0
Stålrør normaltykke | Nivå D + 1,2 m | 1067.9 | 33.8 | 33.8 | ORIGINAL | Fire Protection Wet | +TG=332.002 (1) (2) | SPRINKEL | 0 | 0 | 1067.9 | 25 | Stålrør normaltykke | 0
Stålrør normaltykke | Nivå D + 1,2 m | 196.9 | 33.8 | 33.8 | ORIGINAL | Fire Protection Wet | +TG=332.002 (1) (2) | SPRINKEL | 0 | 0 | 197.348 | 25 | Stålrør normaltykke | 0
Stålrør normaltykke | Nivå D + 1,2 m | 1761.7 | 33.8 | 33.8 | ORIGINAL | Fire Protection Wet | +TG=332.002 (1) (2) | SPRINKEL | 0 | 0 | 1761.68 | 25 | Stålrør normaltykke | 0
Stålrør normaltykke | Nivå D + 1,2 m | 687.2 | 33.8 | 33.8 | ORIGINAL | Fire Protection Wet | +TG=332.002 (1) (2) | SPRINKEL | 0 | 0 | 687.203 | 25 | Stålrør normaltykke | 0
Stålrør normaltykke | Nivå D + 1,2 m | 47.7 | 33.8 | 33.8 | ORIGINAL | Fire Protection Wet | +TG=332.002 (1) (2) | SPRINKEL | 0 | 0 | 47.996 | 25 | Stålrør normaltykke | 0
Stålrør normaltykke | Nivå D + 1,2 m | 54.7 | 33.8 | 33.8 | ORIGINAL | Fire Protection Wet | +TG=332.002 (1) (2) | SPRINKEL | 0 | 0 | 55.233 | 25 | Stålrør normaltykke | 0
Stålrør normaltykke | Nivå D + 1,2 m | 1567.5 | 33.8 | 33.8 | ORIGINAL | Fire Protection Wet | +TG=332.002 (1) (2) | SPRINKEL | 0 | 0 | 1567.52 | 25 | Stålrør normaltykke | 0
Stålrør normaltykke | Nivå D + 1,2 m | 74.9 | 33.8 | 33.8 | ORIGINAL | Fire Protection Wet | +TG=332.002 (1) (2) | SPRINKEL | 0 | 0 | 75.353 | 25 | Stålrør normaltykke | 0
Stålrør normaltykke | Nivå D + 1,2 m | 3156.9 | 33.8 | 33.8 | ORIGINAL | Fire Protection Wet | +TG=332.002 (1) (2) | SPRINKEL | 0 | 0 | 3156.86 | 25 | Stålrør normaltykke | 0
Stålrør normaltykke | Nivå D + 1,2 m | 155.6 | 33.8 | 33.8 | ORIGINAL | Fire Protection Wet | +TG=332.002 (1) (2) | SPRINKEL | 0 | 0 | 156.505 | 25 | Stålrør normaltykke | 0
Stålrør normaltykke | Nivå D + 1,2 m | 63.7 | 33.8 | 33.8 | ORIGINAL | Fire Protection Wet | +TG=332.002 (1) (2) | SPRINKEL | 0 | 0 | 64.028 | 25 | Stålrør normaltykke | 0
Stålrør normaltykke | Nivå D + 1,2 m | 51.6 | 33.8 | 33.8 | ORIGINAL | Fire Protection Wet | +TG=332.002 (1) (2) | SPRINKEL | 0 | 0 | 51.644 | 25 | Stålrør normaltykke | 0
Stålrør normaltykke | Nivå D + 1,2 m | 2441.1 | 33.8 | 33.8 | ORIGINAL | Fire Protection Wet | +TG=332.002 (1) (2) | SPRINKEL | 0 | 0 | 2441.06 | 25 | Stålrør normaltykke | 0
Stålrør normaltykke | Nivå D + 1,2 m | 79.8 | 33.8 | 33.8 | ORIGINAL | Fire Protection Wet | +TG=332.002 (1) (2) | SPRINKEL | 0 | 0 | 79.475 | 25 | Stålrør normaltykke | 0
Stålrør normaltykke | Nivå D + 1,2 m | 2061.4 | 33.8 | 33.8 | ORIGINAL | Fire Protection Wet | +TG=332.002 (1) (2) | SPRINKEL | 0 | 0 | 2061.45 | 25 | Stålrør normaltykke | 0
Stålrør normaltykke | Nivå D + 1,2 m | 60.8 | 33.8 | 33.8 | ORIGINAL | Fire Protection Wet | +TG=332.002 (1) (2) | SPRINKEL | 0 | 0 | 60.634 | 25 | Stålrør normaltykke | 0
Stålrør normaltykke | Nivå D + 1,2 m | 1113.8 | 33.8 | 33.8 | ORIGINAL | Fire Protection Wet | +TG=332.002 (1) (2) | SPRINKEL | 0 | 0 | 1114.03 | 25 | Stålrør normaltykke | 0
Stålrør normaltykke | Nivå D + 1,2 m | 35.1 | 33.8 | 33.8 | ORIGINAL | Fire Protection Wet | +TG=332.002 (1) (2) | SPRINKEL | 0 | 0 | 34.783 | 25 | Stålrør normaltykke | 0
Stålrør normaltykke | Nivå D + 1,2 m | 3614.3 | 33.8 | 33.8 | ORIGINAL | Fire Protection Wet | +TG=332.002 (1) (2) | SPRINKEL | 0 | 0 | 3614.33 | 25 | Stålrør normaltykke | 0
Stålrør normaltykke | Nivå D + 1,2 m | 39.7 | 33.8 | 33.8 | ORIGINAL | Fire Protection Wet | +TG=332.002 (1) (2) | SPRINKEL | 0 | 0 | 39.722 | 25 | Stålrør normaltykke | 0
Stålrør normaltykke | Nivå D + 1,2 m | 821.9 | 33.8 | 33.8 | ORIGINAL | Fire Protection Wet | +TG=332.002 (1) (2) | SPRINKEL | 0 | 0 | 821.919 | 25 | Stålrør normaltykke | 0
Stålrør normaltykke | Nivå D + 1,2 m | 2361.7 | 33.8 | 33.8 | ORIGINAL | Fire Protection Wet | +TG=332.002 (1) (2) | SPRINKEL | 0 | 0 | 2361.65 | 25 | Stålrør normaltykke | 0
Stålrør normaltykke | Nivå D + 1,2 m | 44.2 | 33.8 | 33.8 | ORIGINAL | Fire Protection Wet | +TG=332.002 (1) (2) | SPRINKEL | 0 | 0 | 44.296 | 25 | Stålrør normaltykke | 0
Stålrør normaltykke | Nivå D + 1,2 m | 99.8 | 33.8 | 33.8 | ORIGINAL | Fire Protection Wet | +TG=332.002 (1) (2) | SPRINKEL | 0 | 0 | 99.734 | 25 | Stålrør normaltykke | 0
Stålrør normaltykke | Nivå D + 1,2 m | 1588.4 | 33.8 | 33.8 | ORIGINAL | Fire Protection Wet | +TG=332.002 (1) (2) | SPRINKEL | 0 | 0 | 1587.58 | 25 | Stålrør normaltykke | 0
Stålrør normaltykke | Nivå D + 1,2 m | 42 | 33.8 | 33.8 | ORIGINAL | Fire Protection Wet | +TG=332.002 (1) (2) | SPRINKEL | 0 | 0 | 42.473 | 25 | Stålrør normaltykke | 0
Stålrør normaltykke | Nivå D + 1,2 m | 1142.8 | 33.8 | 33.8 | ORIGINAL | Fire Protection Wet | +TG=332.002 (1) (2) | SPRINKEL | 0 | 0 | 1142.73 | 25 | Stålrør normaltykke | 0
Stålrør normaltykke | Nivå D + 1,2 m | 78.8 | 33.8 | 33.8 | ORIGINAL | Fire Protection Wet | +TG=332.002 (1) (2) | SPRINKEL | 0 | 0 | 79.399 | 25 | Stålrør normaltykke | 0
Stålrør normaltykke | Nivå D + 1,2 m | 562.1 | 33.8 | 33.8 | ORIGINAL | Fire Protection Wet | +TG=332.002 (1) (2) | SPRINKEL | 0 | 0 | 561.659 | 25 | Stålrør normaltykke | 0
Stålrør normaltykke | Nivå D + 1,2 m | 45.6 | 33.8 | 33.8 | ORIGINAL | Fire Protection Wet | +TG=332.002 (1) (2) | SPRINKEL | 0 | 0 | 46.503 | 25 | Stålrør normaltykke | 0
Stålrør normaltykke | Nivå D + 1,2 m | 2043.3 | 33.8 | 33.8 | ORIGINAL | Fire Protection Wet | +TG=332.002 (1) (2) | SPRINKEL | 0 | 0 | 2043.29 | 25 | Stålrør normaltykke | 0
Stålrør normaltykke | Nivå D + 1,2 m | 1040.6 | 33.8 | 33.8 | ORIGINAL | Fire Protection Wet | +TG=332.002 (1) (2) | SPRINKEL | 0 | 0 | 1040.57 | 25 | Stålrør normaltykke | 0
Stålrør normaltykke | Nivå D + 1,2 m | 44.7 | 33.8 | 33.8 | ORIGINAL | Fire Protection Wet | +TG=332.002 (1) (2) | SPRINKEL | 0 | 0 | 45.165 | 25 | Stålrør normaltykke | 0
Stålrør normaltykke | Nivå D + 1,2 m | 35.1 | 33.8 | 33.8 | ORIGINAL | Fire Protection Wet | +TG=332.002 (1) (2) | SPRINKEL | 0 | 0 | 35.043 | 25 | Stålrør normaltykke | 0
Stålrør normaltykke | Nivå D + 1,2 m | 30 | 60.2 | 60.2 | ORIGINAL | Fire Protection Wet | +TG=332.003 (10) | SPRINKEL | 0 | 0 | 30 | 50 | Stålrør normaltykke | 0
Stålrør normaltykke | Nivå D + 1,2 m | 520.9 | 76 | 76 | ORIGINAL | Fire Protection Wet | +TG=332.003 (10) | SPRINKEL | 0 | 0 | 520.928 | 65 | Stålrør normaltykke | 0
Stålrør normaltykke | Nivå D + 1,2 m | 320 | 42.4 | 42.4 | ORIGINAL | Fire Protection Wet | +TG=332.003 (10) | SPRINKEL | 0 | 0 | 320 | 32 | Stålrør normaltykke | 0
4 x Stålrør normaltykke | Nivå D + 1,2 m | 12.4 | 33.8 | 33.8 | ORIGINAL | Fire Protection Wet | +TG=332.002 (1) (2) | SPRINKEL | 0 | 0 | 11.5 | 25 | Stålrør normaltykke | 0
Stålrør normaltykke | Nivå D + 1,2 m | 1519.4 | 33.8 | 33.8 | ORIGINAL | Fire Protection Wet | +TG=332.002 (1) (2) | SPRINKEL | 0 | 0 | 1519.43 | 25 | Stålrør normaltykke | 0
Stålrør normaltykke | Nivå D + 1,2 m | 382.4 | 33.8 | 33.8 | ORIGINAL | Fire Protection Wet | +TG=332.002 (1) (2) | SPRINKEL | 0 | 0 | 382.4 | 25 | Stålrør normaltykke | 0
Stålrør normaltykke | Nivå D + 1,2 m | 1490.2 | 33.8 | 33.8 | ORIGINAL | Fire Protection Wet | +TG=332.002 (1) (2) | SPRINKEL | 0 | 0 | 1490.23 | 25 | Stålrør normaltykke | 0
Stålrør normaltykke | Nivå D + 1,2 m | 3373.3 | 33.8 | 33.8 | ORIGINAL | Fire Protection Wet | +TG=332.002 (1) (2) | SPRINKEL | 0 | 0 | 3373.35 | 25 | Stålrør normaltykke | 0
Stålrør normaltykke | Nivå D + 1,2 m | 212.4 | 33.8 | 33.8 | ORIGINAL | Fire Protection Wet | +TG=332.002 (1) (2) | SPRINKEL | 0 | 0 | 212.053 | 25 | Stålrør normaltykke | 0
Stålrør normaltykke | Nivå D + 1,2 m | 346.1 | 33.8 | 33.8 | ORIGINAL | Fire Protection Wet | +TG=332.002 (1) (2) | SPRINKEL | 0 | 0 | 346.253 | 25 | Stålrør normaltykke | 0
Stålrør normaltykke | Nivå D + 1,2 m | 507 | 48.2 | 48.2 | ORIGINAL | Fire Protection Wet | +TG=332.002 (1) (2) | SPRINKEL | 0 | 0 | 506.988 | 40 | Stålrør normaltykke | 0
Stålrør normaltykke | Nivå D + 1,2 m | 518.7 | 48.2 | 48.2 | ORIGINAL | Fire Protection Wet | +TG=332.002 (1) (2) | SPRINKEL | 0 | 0 | 518.932 | 40 | Stålrør normaltykke | 0
Stålrør normaltykke | Nivå G - 2,0 m | 261.1 | 42.4 | 42.4 | ORIGINAL | Hydronic Return | 37= R 18° Kopi 20 | KJØL RETUR | 0 | 0 | 261.065 | 32 | Stålrør normaltykke | 0
Stålrør normaltykke | Nivå G - 2,0 m | 419.2 | 42.4 | 42.4 | ORIGINAL | Hydronic Supply | 37= T 9° Kopi 22 | KJØL TUR | 0 | 0 | 419.191 | 32 | Stålrør normaltykke | 0
Stålrør normaltykke | Nivå F - 0,7 m | 542.6 | 42.4 | 42.4 | ORIGINAL | Hydronic Return | 32= R 20° Kopi 5 | GULVVARME PRIM T | 0 | 0 | 542.6 | 32 | Stålrør normaltykke | 0
Stålrør normaltykke | Nivå F - 0,7 m | 1575.2 | 42.4 | 42.4 | ORIGINAL | Hydronic Return | 32= R 20° Kopi 5 | GULVVARME PRIM T | 0 | 0 | 1575.2 | 32 | Stålrør normaltykke | 0
Stålrør normaltykke | Nivå F - 0,7 m | 112.9 | 42.4 | 42.4 | ORIGINAL | Hydronic Return | 32= R 20° Kopi 5 | GULVVARME PRIM T | 0 | 0 | 113.365 | 32 | Stålrør normaltykke | 0
Stålrør normaltykke | Nivå F - 0,7 m | 253.4 | 42.4 | 42.4 | ORIGINAL | Hydronic Return | 32= R 20° Kopi 7 | GULVVARME PRIM R | 0 | 0 | 253.365 | 32 | Stålrør normaltykke | 0
Stålrør normaltykke | Nivå F - 0,7 m | 702.6 | 42.4 | 42.4 | ORIGINAL | Hydronic Return | 32= R 20° Kopi 7 | GULVVARME PRIM R | 0 | 0 | 702.6 | 32 | Stålrør normaltykke | 0
Stålrør normaltykke | Nivå F - 0,7 m | 1715.2 | 42.4 | 42.4 | ORIGINAL | Hydronic Return | 32= R 20° Kopi 7 | GULVVARME PRIM R | 0 | 0 | 1715.2 | 32 | Stålrør normaltykke | 0
Stålrør normaltykke | Nivå F - 0,7 m | 71 | 42.4 | 42.4 | ORIGINAL | Hydronic Return | 32= R 20° Kopi 7 | GULVVARME PRIM R | 0 | 0 | 71.012 | 32 | Stålrør normaltykke | 0
Stålrør normaltykke | Nivå F - 0,7 m | 17.5 | 42.4 | 42.4 | ORIGINAL | Hydronic Return | 32= R 20° Kopi 5 | GULVVARME PRIM T | 0 | 0 | 17.512 | 32 | Stålrør normaltykke | 0
Stålrør normaltykke | Nivå F - 0,7 m | 70.2 | 42.4 | 42.4 | ORIGINAL | Hydronic Return | 32= R 20° Kopi 5 | GULVVARME PRIM T | 0 | 0 | 70.2 | 32 | Stålrør normaltykke | 0
Stålrør normaltykke | Nivå F - 0,7 m | 764.6 | 42.4 | 42.4 | ORIGINAL | Hydronic Return | 32= R 20° Kopi 5 | GULVVARME PRIM T | 0 | 0 | 764.602 | 32 | Stålrør normaltykke | 0
Stålrør normaltykke | Nivå F - 0,7 m | 70.2 | 42.4 | 42.4 | ORIGINAL | Hydronic Return | 32= R 20° Kopi 7 | GULVVARME PRIM R | 0 | 0 | 70.2 | 32 | Stålrør normaltykke | 0
Stålrør normaltykke | Nivå F - 0,7 m | 764.6 | 42.4 | 42.4 | ORIGINAL | Hydronic Return | 32= R 20° Kopi 7 | GULVVARME PRIM R | 0 | 0 | 764.602 | 32 | Stålrør normaltykke | 0
Stålrør normaltykke | Nivå F - 0,7 m | 3118.2 | 60.2 | 60.2 | ORIGINAL | Hydronic Return | 32= R 20° Kopi 5 | GULVVARME PRIM T | 0 | 0 | 3118.2 | 50 | Stålrør normaltykke | 0
Stålrør normaltykke | Nivå F - 0,7 m | 3118.2 | 60.2 | 60.2 | ORIGINAL | Hydronic Return | 32= R 20° Kopi 7 | GULVVARME PRIM R | 0 | 0 | 3118.2 | 50 | Stålrør normaltykke | 0
Stålrør normaltykke | Nivå F - 0,7 m | 595.2 | 42.4 | 42.4 | ORIGINAL | Hydronic Return | 32= R 20° Kopi 5 | GULVVARME PRIM T | 0 | 0 | 595.2 | 32 | Stålrør normaltykke | 0
Stålrør normaltykke | Nivå F - 0,7 m | 595.2 | 42.4 | 42.4 | ORIGINAL | Hydronic Return | 32= R 20° Kopi 7 | GULVVARME PRIM R | 0 | 0 | 595.2 | 32 | Stålrør normaltykke | 0
Stålrør normaltykke | Nivå F - 0,7 m | 3274.4 | 42.4 | 42.4 | ORIGINAL | Hydronic Return | 32= R 20° Kopi 5 | GULVVARME PRIM T | 0 | 0 | 3274.35 | 32 | Stålrør normaltykke | 0
Stålrør normaltykke | Nivå F - 0,7 m | 3254.2 | 42.4 | 42.4 | ORIGINAL | Hydronic Return | 32= R 20° Kopi 7 | GULVVARME PRIM R | 0 | 0 | 3254.21 | 32 | Stålrør normaltykke | 0
2 x Stålrør normaltykke | Nivå F - 0,7 m | 71 | 42.4 | 42.4 | ORIGINAL | Hydronic Return | 32= R 20° Kopi 5 | GULVVARME PRIM T | 0 | 0 | 71.345 | 32 | Stålrør normaltykke | 0
2 x Stålrør normaltykke | Nivå F - 0,7 m | 71 | 42.4 | 42.4 | ORIGINAL | Hydronic Return | 32= R 20° Kopi 7 | GULVVARME PRIM R | 0 | 0 | 71.345 | 32 | Stålrør normaltykke | 0
Stålrør normaltykke | Nivå F - 0,7 m | 2871.9 | 26.6 | 26.6 | ORIGINAL | Hydronic Return | 37= R 12° Kopi 4 | Kjøle Retur 17° | 21 | 0 | 2871.88 | 20 | Stålrør normaltykke | 0
Stålrør normaltykke | Nivå F - 0,7 m | 343.2 | 26.6 | 26.6 | ORIGINAL | Hydronic Supply | 37= T 7° Kopi 6 | Kjøle Tur 14° | 18 | 0 | 343.2 | 20 | Stålrør normaltykke | 0
Stålrør normaltykke | Nivå F - 0,7 m | 373.2 | 26.6 | 26.6 | ORIGINAL | Hydronic Supply | 37= T 7° Kopi 6 | Kjøle Tur 14° | 18 | 0 | 373.2 | 20 | Stålrør normaltykke | 0
Stålrør normaltykke | Nivå F - 0,7 m | 507.4 | 26.6 | 26.6 | ORIGINAL | Hydronic Supply | 37= T 7° Kopi 6 | Kjøle Tur 14° | 18 | 0 | 507.389 | 20 | Stålrør normaltykke | 0
Stålrør normaltykke | Nivå F - 0,7 m | 4172.6 | 26.6 | 26.6 | ORIGINAL | Hydronic Supply | 37= T 7° Kopi 6 | Kjøle Tur 14° | 18 | 0 | 4172.58 | 20 | Stålrør normaltykke | 0
Stålrør normaltykke | Nivå F - 0,7 m | 468.2 | 26.6 | 26.6 | ORIGINAL | Hydronic Return | 37= R 12° Kopi 6 | Kjøle Retur 17° | 18 | 0.096 | 468.2 | 20 | Stålrør normaltykke | 0
Stålrør normaltykke | Nivå F - 0,7 m | 468.2 | 26.6 | 26.6 | ORIGINAL | Hydronic Return | 37= R 12° Kopi 6 | Kjøle Retur 17° | 18 | 0 | 468.2 | 20 | Stålrør normaltykke | 0
Stålrør normaltykke | Nivå F - 0,7 m | 1974.7 | 33.8 | 33.8 | ORIGINAL | Hydronic Supply | 37= T 7° Kopi 6 | Kjøle Tur 14° | 18 | 0 | 1974.65 | 25 | Stålrør normaltykke | 0
Stålrør normaltykke | Nivå F - 0,7 m | 1886.2 | 33.8 | 33.8 | ORIGINAL | Hydronic Return | 37= R 12° Kopi 6 | Kjøle Retur 17° | 18 | 0 | 1886.2 | 25 | Stålrør normaltykke | 0
Stålrør normaltykke | Nivå F - 0,7 m | 33.8 | 14.1 | 33.8 | ORIGINAL | Hydronic Return | 37= R 12° Kopi 6 | Kjøle Retur 17° | 18 | 0 | 14.1 | 25 | Stålrør normaltykke | 0
Stålrør normaltykke | Nivå F - 0,7 m | 603.8 | 26.6 | 26.6 | ORIGINAL | Hydronic Return | 37= R 12° Kopi 6 | Kjøle Retur 17° | 18 | 0.096 | 603.796 | 20 | Stålrør normaltykke | 0
Stålrør normaltykke | Nivå F - 0,7 m | 2920.7 | 26.6 | 26.6 | ORIGINAL | Hydronic Supply | 37= T 7° Kopi 4 | Kjøle Tur 14° | 21 | 0 | 2920.75 | 20 | Stålrør normaltykke | 0
Stålrør normaltykke | Nivå F - 0,7 m | 921.2 | 26.6 | 26.6 | ORIGINAL | Hydronic Supply | 37= T 7° Kopi 4 | Kjøle Tur 14° | 20 | 0 | 921.237 | 20 | Stålrør normaltykke | 0
Stålrør normaltykke | Nivå F - 0,7 m | 81.4 | 26.6 | 26.6 | ORIGINAL | Hydronic Return | 37= R 12° Kopi 4 | Kjøle Retur 17° | 20 | 0 | 81.405 | 20 | Stålrør normaltykke | 0
Stålrør normaltykke | Nivå F - 0,7 m | 926 | 26.6 | 26.6 | ORIGINAL | Hydronic Return | 37= R 12° Kopi 4 | Kjøle Retur 17° | 20 | 0 | 925.987 | 20 | Stålrør normaltykke | 0
Stålrør normaltykke | Nivå F - 0,7 m | 194 | 26.6 | 26.6 | ORIGINAL | Hydronic Supply | 37= T 7° Kopi 4 | Kjøle Tur 14° | 20 | 0 | 193.963 | 20 | Stålrør normaltykke | 0
Stålrør normaltykke | Nivå F - 0,7 m | 270.2 | 26.6 | 26.6 | ORIGINAL | Hydronic Return | 37= R 12° Kopi 4 | Kjøle Retur 17° | 20 | 0 | 270.213 | 20 | Stålrør normaltykke | 0
Stålrør normaltykke | Nivå F - 0,7 m | 606.9 | 26.6 | 26.6 | ORIGINAL | Hydronic Supply | 37= T 7° Kopi 6 | Kjøle Tur 14° | 18 | 0 | 606.889 | 20 | Stålrør normaltykke | 0
Stålrør normaltykke | Nivå F - 0,7 m | 361.6 | 26.6 | 26.6 | ORIGINAL | Hydronic Supply | 37= T 7° Kopi 6 | Kjøle Tur 14° | 18 | 0 | 361.945 | 20 | Stålrør normaltykke | 0
Stålrør normaltykke | Nivå F - 0,7 m | 583.6 | 26.6 | 26.6 | ORIGINAL | Hydronic Return | 37= R 12° Kopi 6 | Kjøle Retur 17° | 18 | 0.096 | 583.578 | 20 | Stålrør normaltykke | 0
Stålrør normaltykke | Nivå F - 0,7 m | 345.1 | 26.6 | 26.6 | ORIGINAL | Hydronic Return | 37= R 12° Kopi 6 | Kjøle Retur 17° | 18 | 0 | 345.121 | 20 | Stålrør normaltykke | 0
Stålrør normaltykke | Nivå F - 0,7 m | 4051.1 | 26.6 | 26.6 | ORIGINAL | Hydronic Return | 37= R 12° Kopi 6 | Kjøle Retur 17° | 18 | 0 | 4051.11 | 20 | Stålrør normaltykke | 0
Stålrør normaltykke | Nivå F - 0,7 m | 781.5 | 42.4 | 42.4 | ORIGINAL | Hydronic Return | 37= R 18° Kopi 20 | KJØL RETUR | 0 | 0 | 781.523 | 32 | Stålrør normaltykke | 0
Stålrør normaltykke | Nivå F - 0,7 m | 979.6 | 42.4 | 42.4 | ORIGINAL | Hydronic Supply | 37= T 9° Kopi 22 | KJØL TUR | 0 | 0 | 979.603 | 32 | Stålrør normaltykke | 0
Stålrør normaltykke | Nivå F - 0,7 m | 1031.2 | 42.4 | 42.4 | ORIGINAL | Hydronic Return | 32= R 20° Kopi 57 | GULVVARME PRIM R | 0 | 0 | 1031.18 | 32 | Stålrør normaltykke | 0
Stålrør normaltykke | Nivå F - 0,7 m | 33.4 | 42.4 | 42.4 | ORIGINAL | Hydronic Return | 32= R 20° Kopi 57 | GULVVARME PRIM R | 0 | 0 | 32.856 | 32 | Stålrør normaltykke | 0
Stålrør normaltykke | Nivå F - 0,7 m | 9.1 | 42.4 | 42.4 | ORIGINAL | Hydronic Return | 32= R 20° Kopi 57 | GULVVARME PRIM R | 0 | 0 | 8.892 | 32 | Stålrør normaltykke | 0
Stålrør normaltykke | Nivå F - 0,7 m | 1040.2 | 42.4 | 42.4 | ORIGINAL | Hydronic Return | 32= R 20° Kopi 58 | GULVVARME PRIM T | 0 | 0 | 1040.22 | 32 | Stålrør normaltykke | 0
Stålrør normaltykke | Nivå F - 0,7 m | 9.8 | 42.4 | 42.4 | ORIGINAL | Hydronic Return | 32= R 20° Kopi 58 | GULVVARME PRIM T | 0 | 0 | 9.771 | 32 | Stålrør normaltykke | 0
Stålrør normaltykke | Nivå F - 0,7 m | 609.5 | 60.2 | 60.2 | ORIGINAL | Hydronic Return | 32= R 20° Kopi 5 | GULVVARME PRIM T | 0 | 0 | 609.485 | 50 | Stålrør normaltykke | 0
Stålrør normaltykke | Nivå F - 0,7 m | 609.5 | 60.2 | 60.2 | ORIGINAL | Hydronic Return | 32= R 20° Kopi 7 | GULVVARME PRIM R | 0 | 0 | 609.485 | 50 | Stålrør normaltykke | 0
Stålrør normaltykke | Nivå F - 0,7 m | 152.8 | 42.4 | 42.4 | ORIGINAL | Hydronic Return | 32= R 20° Kopi 58 | GULVVARME PRIM T | 0 | 0 | 153.139 | 32 | Stålrør normaltykke | 0
Stålrør normaltykke | Nivå F - 0,7 m | 2036.2 | 42.4 | 42.4 | ORIGINAL | Hydronic Return | 32= R 20° Kopi 58 | GULVVARME PRIM T | 0 | 0 | 2036.2 | 32 | Stålrør normaltykke | 0
Stålrør normaltykke | Nivå F - 0,7 m | 42.4 | 34 | 42.4 | ORIGINAL | Hydronic Return | 32= R 20° Kopi 57 | GULVVARME PRIM R | 0 | 0 | 33.488 | 32 | Stålrør normaltykke | 0
Stålrør normaltykke | Nivå F - 0,7 m | 2036.2 | 42.4 | 42.4 | ORIGINAL | Hydronic Return | 32= R 20° Kopi 57 | GULVVARME PRIM R | 0 | 0 | 2036.2 | 32 | Stålrør normaltykke | 0
Stålrør normaltykke | Nivå F - 0,7 m | 501.2 | 42.4 | 42.4 | ORIGINAL | Hydronic Return | 32= R 20° Kopi 57 | GULVVARME PRIM R | 0 | 0 | 501.216 | 32 | Stålrør normaltykke | 0
Stålrør normaltykke | Nivå F - 0,7 m | 22.2 | 42.4 | 42.4 | ORIGINAL | Hydronic Return | 32= R 20° Kopi 58 | GULVVARME PRIM T | 0 | 0 | 22.176 | 32 | Stålrør normaltykke | 0
Stålrør normaltykke | Nivå F - 0,7 m | 431.5 | 42.4 | 42.4 | ORIGINAL | Hydronic Return | 32= R 20° Kopi 58 | GULVVARME PRIM T | 0 | 0 | 431.524 | 32 | Stålrør normaltykke | 0
Stålrør normaltykke | Nivå F - 0,7 m | 116 | 42.4 | 42.4 | ORIGINAL | Hydronic Return | 32= R 20° Kopi 58 | GULVVARME PRIM T | 0 | 0 | 116.024 | 32 | Stålrør normaltykke | 0
Stålrør normaltykke | Nivå D + 1,2 m | 2025.2 | 42.4 | 42.4 | ORIGINAL | Hydronic Supply | 37= T 9° Kopi 54 | KJØL TUR | 0 | 0 | 2025.2 | 32 | Stålrør normaltykke | 0
Stålrør normaltykke | Nivå D + 1,2 m | 397.7 | 42.4 | 42.4 | ORIGINAL | Hydronic Supply | 37= T 9° Kopi 54 | KJØL TUR | 0 | 0 | 397.7 | 32 | Stålrør normaltykke | 0
Stålrør normaltykke | Nivå D + 1,2 m | 112.2 | 42.4 | 42.4 | ORIGINAL | Hydronic Supply | 37= T 9° Kopi 1 | KJØL TUR | 0 | 0 | 112.191 | 32 | Stålrør normaltykke | 0
Stålrør normaltykke | Nivå D + 1,2 m | 159.6 | 42.4 | 42.4 | ORIGINAL | Hydronic Supply | 37= T 9° Kopi 1 | KJØL TUR | 0 | 0 | 159.642 | 32 | Stålrør normaltykke | 0
Stålrør normaltykke | Nivå D + 1,2 m | 2115.2 | 42.4 | 42.4 | ORIGINAL | Hydronic Return | 37= R 18° Kopi 13 | KJØL RETUR | 0 | 0 | 2115.2 | 32 | Stålrør normaltykke | 0
Stålrør normaltykke | Nivå D + 1,2 m | 397.7 | 42.4 | 42.4 | ORIGINAL | Hydronic Return | 37= R 18° Kopi 13 | KJØL RETUR | 0 | 0 | 397.7 | 32 | Stålrør normaltykke | 0
Stålrør normaltykke | Nivå D + 1,2 m | 144.5 | 42.4 | 42.4 | ORIGINAL | Hydronic Return | 37= R 18° Kopi 13 | KJØL RETUR | 0 | 0 | 144.5 | 32 | Stålrør normaltykke | 0
Stålrør normaltykke | Nivå D + 1,2 m | 230.5 | 42.4 | 42.4 | ORIGINAL | Hydronic Return | 37= R 18° Kopi 13 | KJØL RETUR | 0 | 0 | 229.642 | 32 | Stålrør normaltykke | 0
Stålrør normaltykke | Nivå D + 1,2 m | 41.7 | 42.4 | 42.4 | ORIGINAL | Hydronic Return | 37= R 18° Kopi 13 | KJØL RETUR | 0 | 0 | 41.47 | 32 | Stålrør normaltykke | 0
Stålrør normaltykke | Nivå D + 1,2 m | 461 | 42.4 | 42.4 | ORIGINAL | Hydronic Supply | 37= T 9° Kopi 54 | KJØL TUR | 0 | 0 | 460.958 | 32 | Stålrør normaltykke | 0
Stålrør normaltykke | Nivå D + 1,2 m | 471.6 | 42.4 | 42.4 | ORIGINAL | Hydronic Return | 37= R 18° Kopi 13 | KJØL RETUR | 0 | 0 | 471.63 | 32 | Stålrør normaltykke | 0
Stålrør normaltykke | Nivå D + 1,2 m | 3797.7 | 42.4 | 42.4 | ORIGINAL | Hydronic Supply | 37= T 9° Kopi 1 | KJØL TUR | 0 | 0 | 3797.7 | 32 | Stålrør normaltykke | 0
Stålrør normaltykke | Nivå D + 1,2 m | 3797.7 | 42.4 | 42.4 | ORIGINAL | Hydronic Return | 37= R 18° Kopi 13 | KJØL RETUR | 0 | 0 | 3797.7 | 32 | Stålrør normaltykke | 0
Stålrør normaltykke | Nivå D + 1,2 m | 1995.6 | 89 | 89 | ORIGINAL | Hydronic Return | 32= R 50° Kopi 54 | VARME RETUR | 0 | 0 | 1995.57 | 80 | Stålrør normaltykke | 0
Stålrør normaltykke | Nivå D + 1,2 m | 451.3 | 76 | 76 | ORIGINAL | Hydronic Return | 32= R 50° Kopi 54 | VARME RETUR | 0 | 0 | 451.302 | 65 | Stålrør normaltykke | 0
Stålrør normaltykke | Nivå D + 1,2 m | 1832.9 | 89 | 89 | ORIGINAL | Hydronic Supply | 32= T 60° Kopi 50 | VARME T | 0 | 0 | 1832.93 | 80 | Stålrør normaltykke | 0
Stålrør normaltykke | Nivå D + 1,2 m | 448 | 76 | 76 | ORIGINAL | Hydronic Supply | 32= T 60° Kopi 50 | VARME T | 0 | 0 | 448.545 | 65 | Stålrør normaltykke | 0
Stålrør normaltykke | Nivå D + 1,2 m | 420 | 21.4 | 21.4 | ORIGINAL | Undefined |  | Undefined | 0 | 0 | 420 | 15 | Stålrør normaltykke | 0
Stålrør normaltykke | Nivå D + 1,2 m | 320 | 21.4 | 21.4 | ORIGINAL | Undefined |  | Undefined | 0 | 0 | 320 | 15 | Stålrør normaltykke | 0
Stålrør normaltykke | Nivå D + 1,2 m | 140.4 | 26.6 | 26.6 | ORIGINAL | Undefined |  | Undefined | 0 | 0 | 140.31 | 20 | Stålrør normaltykke | 0
Stålrør normaltykke | Nivå D + 1,2 m | 112 | 26.6 | 26.6 | ORIGINAL | Undefined |  | Undefined | 0 | 0 | 111.868 | 20 | Stålrør normaltykke | 0
Stålrør normaltykke | Nivå D + 1,2 m | 84 | 21.4 | 21.4 | ORIGINAL | Undefined |  | Undefined | 0 | 0 | 84.024 | 15 | Stålrør normaltykke | 0
Stålrør normaltykke | Nivå D + 1,2 m | 271.8 | 21.4 | 21.4 | ORIGINAL | Undefined |  | Undefined | 0 | 0 | 271.766 | 15 | Stålrør normaltykke | 0
2 x Stålrør normaltykke | Nivå D + 1,2 m | 15.9 | 21.4 | 21.4 | ORIGINAL | Undefined |  | Undefined | 0 | 0 | 15.895 | 15 | Stålrør normaltykke | 0
Stålrør normaltykke | Nivå D + 1,2 m | 1220 | 26.6 | 26.6 | ORIGINAL | Hydronic Supply | 37= T 9° Kopi 122 | KJØL T | 0 | 0 | 1220 | 20 | Stålrør normaltykke | 0
Stålrør normaltykke | Nivå D + 1,2 m | 405.5 | 26.6 | 26.6 | ORIGINAL | Hydronic Supply | 37= T 9° Kopi 122 | KJØL T | 0 | 0 | 406.4 | 20 | Stålrør normaltykke | 0
Stålrør normaltykke | Nivå D + 1,2 m | 1300 | 26.6 | 26.6 | ORIGINAL | Hydronic Return | 37= R 18° Kopi 82 | KJØL R | 0 | 0 | 1300 | 20 | Stålrør normaltykke | 0
Stålrør normaltykke | Nivå D + 1,2 m | 515.5 | 26.6 | 26.6 | ORIGINAL | Hydronic Return | 37= R 18° Kopi 82 | KJØL R | 0 | 0 | 516.4 | 20 | Stålrør normaltykke | 0
Stålrør normaltykke | Nivå D + 1,2 m | 205.8 | 26.6 | 26.6 | ORIGINAL | Undefined |  | Undefined | 0 | 0 | 206.495 | 20 | Stålrør normaltykke | 0
Stålrør normaltykke | Nivå D + 1,2 m | 91.7 | 26.6 | 26.6 | ORIGINAL | Undefined |  | Undefined | 0 | 0 | 92.406 | 20 | Stålrør normaltykke | 0
Stålrør normaltykke | Nivå D + 1,2 m | 9.6 | 21.4 | 21.4 | ORIGINAL | Undefined |  | Undefined | 0 | 0 | 9.772 | 15 | Stålrør normaltykke | 0
Stålrør normaltykke | Nivå D + 1,2 m | 243.9 | 21.4 | 21.4 | ORIGINAL | Undefined |  | Undefined | 0 | 0 | 243.548 | 15 | Stålrør normaltykke | 0
Stålrør normaltykke | Nivå D + 1,2 m | 3350 | 76 | 76 | ORIGINAL | Undefined |  | Undefined | 35 | 0 | 3350 | 65 | Stålrør normaltykke | 0
Stålrør normaltykke | Nivå D + 1,2 m | 267.5 | 76 | 76 | ORIGINAL | Undefined |  | Undefined | 35 | 0 | 267.829 | 65 | Stålrør normaltykke | 0
Stålrør normaltykke | Nivå D + 1,2 m | 817.3 | 76 | 76 | ORIGINAL | Undefined |  | Undefined | 35 | 0 | 817.274 | 65 | Stålrør normaltykke | 0
Stålrør normaltykke | Nivå D + 1,2 m | 109.6 | 76 | 76 | ORIGINAL | Undefined |  | Undefined | 35 | 0 | 109.661 | 65 | Stålrør normaltykke | 0
Stålrør normaltykke | Nivå D + 1,2 m | 1313.3 | 76 | 76 | ORIGINAL | Hydronic Return | +TG=320.000.R | VARME R | 35 | 0 | 1313.26 | 65 | Stålrør normaltykke | 0
Stålrør normaltykke | Nivå D + 1,2 m | 130.4 | 76 | 76 | ORIGINAL | Undefined |  | Undefined | 35 | 0 | 130.396 | 65 | Stålrør normaltykke | 0
Stålrør normaltykke | Nivå D + 1,2 m | 333 | 76 | 76 | ORIGINAL | Undefined |  | Undefined | 35 | 0 | 332.82 | 65 | Stålrør normaltykke | 0
Stålrør normaltykke | Nivå D + 1,2 m | 1000.6 | 76 | 76 | ORIGINAL | Undefined |  | Undefined | 35 | 0 | 1000.64 | 65 | Stålrør normaltykke | 0
Stålrør normaltykke | Nivå D + 1,2 m | 1725.4 | 76 | 76 | ORIGINAL | Hydronic Supply | +TG=320.000.T | VARME T | 35 | 0 | 1725.01 | 65 | Stålrør normaltykke | 0
Stålrør normaltykke | Nivå D + 1,2 m | 1684.8 | 76 | 76 | ORIGINAL | Hydronic Return | +TG=320.000.R | VARME R | 35 | 0 | 1684.79 | 65 | Stålrør normaltykke | 0
Stålrør normaltykke | Nivå D + 1,2 m | 372.9 | 48.2 | 48.2 | ORIGINAL | Hydronic Supply | 37= T 9° Kopi 44 | KJØL T | 0 | 0 | 372.85 | 40 | Stålrør normaltykke | 0
Stålrør normaltykke | Nivå D + 1,2 m | 810 | 48.2 | 48.2 | ORIGINAL | Hydronic Supply | 37= T 9° Kopi 44 | KJØL T | 0 | 0 | 810 | 40 | Stålrør normaltykke | 0
Stålrør normaltykke | Nivå D + 1,2 m | 110.2 | 48.2 | 48.2 | ORIGINAL | Hydronic Supply | 37= T 9° Kopi 44 | KJØL T | 0 | 0 | 110.2 | 40 | Stålrør normaltykke | 0
Stålrør normaltykke | Nivå D + 1,2 m | 84.6 | 48.2 | 48.2 | ORIGINAL | Hydronic Return | 37= R 18° Kopi 30 | KJØL R | 0 | 0 | 85.285 | 40 | Stålrør normaltykke | 0
Stålrør normaltykke | Nivå D + 1,2 m | 78.3 | 48.2 | 48.2 | ORIGINAL | Hydronic Return | 37= R 18° Kopi 30 | KJØL R | 0 | 0 | 78.35 | 40 | Stålrør normaltykke | 0
Stålrør normaltykke | Nivå D + 1,2 m | 103.4 | 48.2 | 48.2 | ORIGINAL | Hydronic Return | 37= R 18° Kopi 30 | KJØL R | 0 | 0 | 103.413 | 40 | Stålrør normaltykke | 0
Stålrør normaltykke | Nivå D + 1,2 m | 61.3 | 48.2 | 48.2 | ORIGINAL | Hydronic Return | 37= R 18° Kopi 30 | KJØL R | 0 | 0 | 61.288 | 40 | Stålrør normaltykke | 0
Stålrør normaltykke | Nivå D + 1,2 m | 1032.3 | 48.2 | 48.2 | ORIGINAL | Hydronic Return | 37= R 18° Kopi 30 | KJØL R | 0 | 0 | 1032.25 | 40 | Stålrør normaltykke | 0
Stålrør normaltykke | Nivå D + 1,2 m | 95.2 | 48.2 | 48.2 | ORIGINAL | Hydronic Return | 37= R 18° Kopi 30 | KJØL R | 0 | 0 | 95.202 | 40 | Stålrør normaltykke | 0
Stålrør normaltykke | Nivå D + 1,2 m | 253.2 | 76 | 76 | ORIGINAL | Undefined |  | Undefined | 0 | 0 | 252.85 | 65 | Stålrør normaltykke | 0
Stålrør normaltykke | Nivå D + 1,2 m | 263.2 | 60.2 | 60.2 | ORIGINAL | Hydronic Supply | 37= T 9° Kopi 44 | KJØL T | 0 | 0 | 262.85 | 50 | Stålrør normaltykke | 0
Stålrør normaltykke | Nivå D + 1,2 m | 310.9 | 42.4 | 42.4 | ORIGINAL | Hydronic Supply | 37= T 9° Kopi 44 | KJØL T | 0 | 0 | 310.85 | 32 | Stålrør normaltykke | 0
Stålrør normaltykke | Nivå D + 1,2 m | 715 | 76 | 76 | ORIGINAL | Undefined |  | Undefined | 0 | 0 | 715 | 65 | Stålrør normaltykke | 0
Stålrør normaltykke | Nivå D + 1,2 m | 382.6 | 60.2 | 60.2 | ORIGINAL | Hydronic Supply | 37= T 9° Kopi 44 | KJØL T | 0 | 0 | 382.565 | 50 | Stålrør normaltykke | 0
Stålrør normaltykke | Nivå D + 1,2 m | 129.2 | 60.2 | 60.2 | ORIGINAL | Hydronic Supply | 37= T 9° Kopi 44 | KJØL T | 0 | 0 | 128.743 | 50 | Stålrør normaltykke | 0
Stålrør normaltykke | Nivå D + 1,2 m | 183.7 | 60.2 | 60.2 | ORIGINAL | Hydronic Supply | 37= T 9° Kopi 44 | KJØL T | 0 | 0 | 183.722 | 50 | Stålrør normaltykke | 0
Stålrør normaltykke | Nivå D + 1,2 m | 60.2 | 43.4 | 60.2 | ORIGINAL | Hydronic Supply | 37= T 9° Kopi 44 | KJØL T | 0 | 0 | 43.157 | 50 | Stålrør normaltykke | 0
Stålrør normaltykke | Nivå D + 1,2 m | 986.8 | 48.2 | 48.2 | ORIGINAL | Hydronic Supply | 37= T 9° Kopi 44 | KJØL T | 0 | 0 | 986.831 | 40 | Stålrør normaltykke | 0
Stålrør normaltykke | Nivå D + 1,2 m | 252.6 | 48.2 | 48.2 | ORIGINAL | Hydronic Supply | 37= T 9° Kopi 44 | KJØL T | 0 | 0 | 252.608 | 40 | Stålrør normaltykke | 0
Stålrør normaltykke | Nivå D + 1,2 m | 48.2 | 6.3 | 48.2 | ORIGINAL | Hydronic Supply | 37= T 9° Kopi 44 | KJØL T | 0 | 0 | 6.288 | 40 | Stålrør normaltykke | 0
Stålrør normaltykke | Nivå D + 1,2 m | 53.9 | 48.2 | 48.2 | ORIGINAL | Hydronic Supply | 37= T 9° Kopi 44 | KJØL T | 0 | 0 | 53.869 | 40 | Stålrør normaltykke | 0
Stålrør normaltykke | Nivå D + 1,2 m | 4.4 | 42.4 | 42.4 | ORIGINAL | Hydronic Supply | 37= T 9° Kopi 44 | KJØL T | 0 | 0 | 4.266 | 32 | Stålrør normaltykke | 0
Stålrør normaltykke | Nivå D + 1,2 m | 267.5 | 76 | 76 | ORIGINAL | Undefined |  | Undefined | 0 | 0 | 268.089 | 65 | Stålrør normaltykke | 0
Stålrør normaltykke | Nivå D + 1,2 m | 247.3 | 76 | 76 | ORIGINAL | Hydronic Return | 37= R 18° Kopi 30 | KJØL R | 0 | 0 | 247.332 | 65 | Stålrør normaltykke | 0
Stålrør normaltykke | Nivå D + 1,2 m | 304.6 | 48.2 | 48.2 | ORIGINAL | Hydronic Return | 37= R 18° Kopi 30 | KJØL R | 0 | 0 | 304.621 | 40 | Stålrør normaltykke | 0
Stålrør normaltykke | Nivå D + 1,2 m | 530 | 76 | 76 | ORIGINAL | Undefined |  | Undefined | 0 | 0 | 530 | 65 | Stålrør normaltykke | 0
Stålrør normaltykke | Nivå D + 1,2 m | 157.6 | 48.2 | 48.2 | ORIGINAL | Hydronic Return | 37= R 18° Kopi 30 | KJØL R | 0 | 0 | 157.571 | 40 | Stålrør normaltykke | 0
Stålrør normaltykke | Nivå D + 1,2 m | 436.5 | 60.2 | 60.2 | ORIGINAL | Hydronic Return | 37= R 18° Kopi 30 | KJØL R | 0 | 0 | 436.458 | 50 | Stålrør normaltykke | 0
Stålrør normaltykke | Nivå D + 1,2 m | 5.7 | 60.2 | 60.2 | ORIGINAL | Hydronic Return | 37= R 18° Kopi 30 | KJØL R | 0 | 0 | 5.695 | 50 | Stålrør normaltykke | 0
Stålrør normaltykke | Nivå D + 1,2 m | 380.1 | 48.2 | 48.2 | ORIGINAL | Hydronic Return | 37= R 18° Kopi 30 | KJØL R | 0 | 0 | 380.138 | 40 | Stålrør normaltykke | 0
Stålrør normaltykke | Nivå D + 1,2 m | 240.2 | 48.2 | 48.2 | ORIGINAL | Hydronic Return | 37= R 18° Kopi 30 | KJØL R | 0 | 0 | 240.2 | 40 | Stålrør normaltykke | 0
Stålrør normaltykke | Nivå D + 1,2 m | 962.2 | 48.2 | 48.2 | ORIGINAL | Hydronic Return | 37= R 18° Kopi 30 | KJØL R | 0 | 0 | 962.391 | 40 | Stålrør normaltykke | 0
Stålrør normaltykke | Nivå D + 1,2 m | 109.1 | 48.2 | 48.2 | ORIGINAL | Hydronic Return | 37= R 18° Kopi 30 | KJØL R | 0 | 0 | 109.104 | 40 | Stålrør normaltykke | 0
Stålrør normaltykke | Nivå D + 1,2 m | 5.3 | 48.2 | 48.2 | ORIGINAL | Hydronic Return | 37= R 18° Kopi 30 | KJØL R | 0 | 0 | 5.299 | 40 | Stålrør normaltykke | 0
Stålrør normaltykke | Nivå D + 1,2 m | 48.2 | 6.3 | 48.2 | ORIGINAL | Hydronic Return | 37= R 18° Kopi 30 | KJØL R | 0 | 0 | 6.528 | 40 | Stålrør normaltykke | 0
Stålrør normaltykke | Nivå D + 1,2 m | 59 | 48.2 | 48.2 | ORIGINAL | Hydronic Return | 37= R 18° Kopi 30 | KJØL R | 0 | 0 | 58.987 | 40 | Stålrør normaltykke | 0
Stålrør normaltykke | Nivå D + 1,2 m | 5.3 | 48.2 | 48.2 | ORIGINAL | Hydronic Return | 37= R 18° Kopi 30 | KJØL R | 0 | 0 | 4.567 | 40 | Stålrør normaltykke | 0
Stålrør normaltykke | Nivå D + 1,2 m | 1290.7 | 17.2 | 17.2 | ORIGINAL | Undefined |  | Undefined | 20 | 0 | 1290.74 | 10 | Stålrør normaltykke | 0
Stålrør normaltykke | Nivå D + 1,2 m | 1049.8 | 17.2 | 17.2 | ORIGINAL | Undefined |  | Undefined | 20 | 0 | 1049.76 | 10 | Stålrør normaltykke | 0
Stålrør normaltykke | Nivå D + 1,2 m | 147.3 | 17.2 | 17.2 | ORIGINAL | Undefined |  | Undefined | 20 | 0 | 146.8 | 10 | Stålrør normaltykke | 0
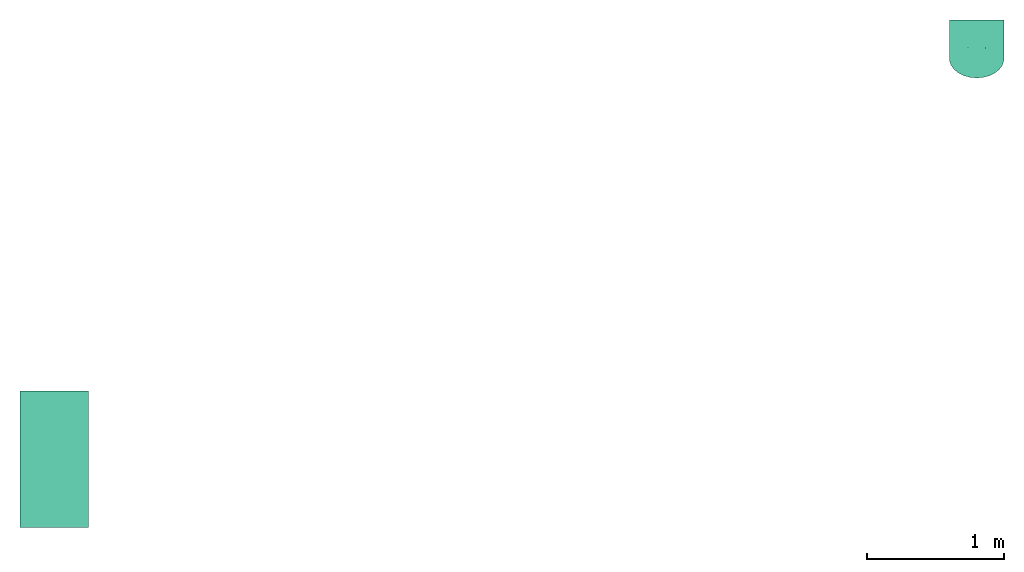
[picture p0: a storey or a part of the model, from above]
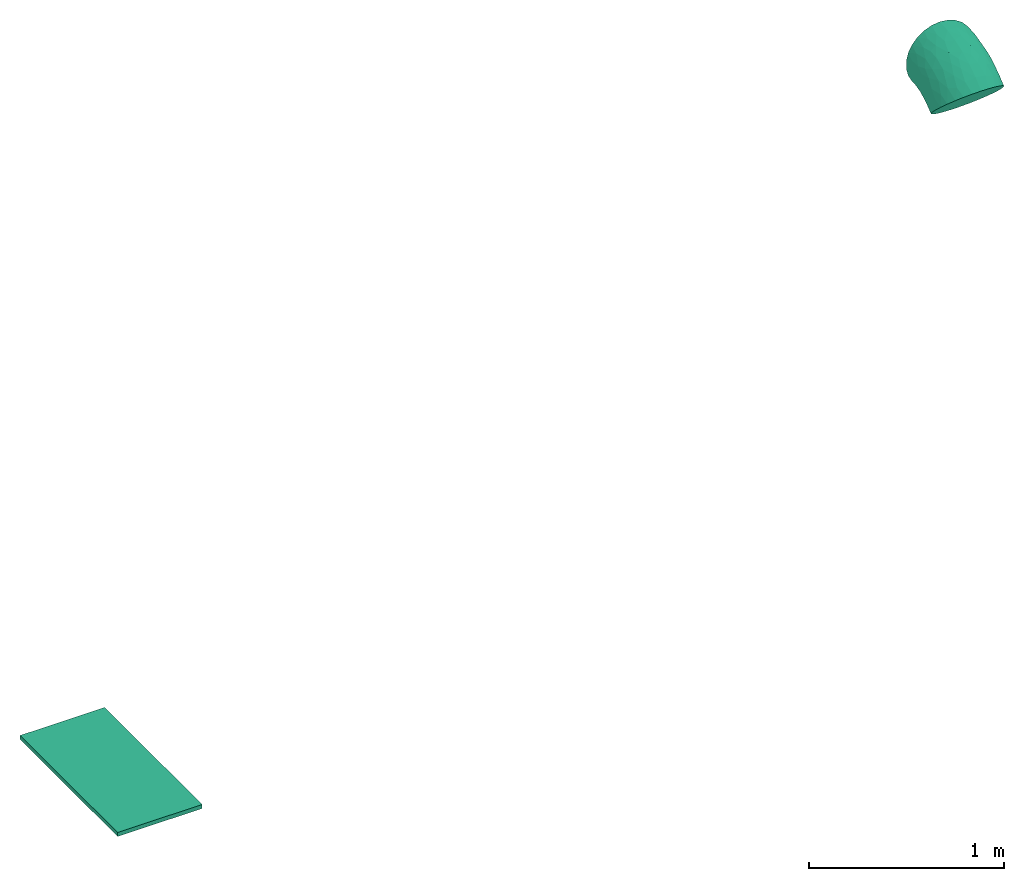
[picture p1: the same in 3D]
Properties of the parts of a building model (IFC2X3), part 9 of 11

# IfcFlowSegment: Stålrør normaltykke (445)
Name | In | Length (Simplebim) (mm) | Height (Simplebim) (mm) | Width (Simplebim) (mm) | Splitting | SystemClass | SystemName = Group | SystemType | Insulation_thickness_mm (mm) | qv_SizingFlow_ls (m3/s) | Length_mm (mm) | ConnectionSize_mm (mm) | Material | MagiCAD Pset_Heating, v_SizingFlow_ms (m/s) = MagiCAD Pset_Heating, pTot_SizingFlow_kPa (kPa) = MagiCAD Pset_Heating, dpTot_SizingFlow_kPa (kPa) = MagiCAD Pset_Water, dpTot_SizingFlow_kPa (kPa) = MagiCAD Pset_Water, pTot_SizingFlow_kPa (kPa) = MagiCAD Pset_Water, v_SizingFlow_ms (m/s)
Stålrør normaltykke | Nivå D + 1,2 m | 2544.2 | 21.4 | 21.4 | ORIGINAL | Undefined |  | Undefined | 0 | 0 | 2544.25 | 15 | Stålrør normaltykke | 0
Stålrør normaltykke | Nivå D + 1,2 m | 2493 | 21.4 | 21.4 | ORIGINAL | Undefined |  | Undefined | 0 | 0 | 2492.95 | 15 | Stålrør normaltykke | 0
Stålrør normaltykke | Nivå D + 1,2 m | 72 | 17.2 | 17.2 | ORIGINAL | Undefined |  | Undefined | 25 | 0 | 71.967 | 10 | Stålrør normaltykke | 0
Stålrør normaltykke | Nivå D + 1,2 m | 20387 | 17.2 | 17.2 | ORIGINAL | Undefined |  | Undefined | 25 | 0 | 20387 | 10 | Stålrør normaltykke | 0
Stålrør normaltykke | Nivå D + 1,2 m | 2317 | 17.2 | 17.2 | ORIGINAL | Undefined |  | Undefined | 25 | 0 | 2316.97 | 10 | Stålrør normaltykke | 0
Stålrør normaltykke | Nivå D + 1,2 m | 30.2 | 17.2 | 17.2 | ORIGINAL | Undefined |  | Undefined | 25 | 0 | 30 | 10 | Stålrør normaltykke | 0
Stålrør normaltykke | Nivå D + 1,2 m | 225.2 | 17.2 | 17.2 | ORIGINAL | Undefined |  | Undefined | 25 | 0 | 225.25 | 10 | Stålrør normaltykke | 0
Stålrør normaltykke | Nivå D + 1,2 m | 3096.6 | 17.2 | 17.2 | ORIGINAL | Undefined |  | Undefined | 25 | 0 | 3096.55 | 10 | Stålrør normaltykke | 0
Stålrør normaltykke | Nivå D + 1,2 m | 2338.8 | 17.2 | 17.2 | ORIGINAL | Undefined |  | Undefined | 25 | 0 | 2338.77 | 10 | Stålrør normaltykke | 0
Stålrør normaltykke | Nivå D + 1,2 m | 39.2 | 17.2 | 17.2 | ORIGINAL | Undefined |  | Undefined | 25 | 0 | 38.769 | 10 | Stålrør normaltykke | 0
Stålrør normaltykke | Nivå D + 1,2 m | 4687.5 | 17.2 | 17.2 | ORIGINAL | Undefined |  | Undefined | 25 | 0 | 4687.54 | 10 | Stålrør normaltykke | 0
Stålrør normaltykke | Nivå D + 1,2 m | 80 | 17.2 | 17.2 | ORIGINAL | Undefined |  | Undefined | 25 | 0 | 80 | 10 | Stålrør normaltykke | 0
Stålrør normaltykke | Nivå D + 1,2 m | 2117 | 17.2 | 17.2 | ORIGINAL | Undefined |  | Undefined | 25 | 0 | 2116.96 | 10 | Stålrør normaltykke | 0
Stålrør normaltykke | Nivå D + 1,2 m | 59.5 | 17.2 | 17.2 | ORIGINAL | Undefined |  | Undefined | 25 | 0 | 59.485 | 10 | Stålrør normaltykke | 0
Stålrør normaltykke | Nivå D + 1,2 m | 19.9 | 17.2 | 17.2 | ORIGINAL | Undefined |  | Undefined | 25 | 0 | 19.633 | 10 | Stålrør normaltykke | 0
Stålrør normaltykke | Nivå D + 1,2 m | 3512.2 | 17.2 | 17.2 | ORIGINAL | Undefined |  | Undefined | 25 | 0 | 3512.16 | 10 | Stålrør normaltykke | 0
Stålrør normaltykke | Nivå D + 1,2 m | 848.5 | 17.2 | 17.2 | ORIGINAL | Undefined |  | Undefined | 25 | 0 | 848.53 | 10 | Stålrør normaltykke | 0
Stålrør normaltykke | Nivå D + 1,2 m | 17.9 | 17.2 | 17.2 | ORIGINAL | Undefined |  | Undefined | 25 | 0 | 18.333 | 10 | Stålrør normaltykke | 0
Stålrør normaltykke | Nivå D + 1,2 m | 56.1 | 17.2 | 17.2 | ORIGINAL | Undefined |  | Undefined | 25 | 0 | 56.083 | 10 | Stålrør normaltykke | 0
Stålrør normaltykke | Nivå D + 1,2 m | 79 | 17.2 | 17.2 | ORIGINAL | Undefined |  | Undefined | 20 | 0 | 79.002 | 10 | Stålrør normaltykke | 0
Stålrør normaltykke | Nivå D + 1,2 m | 627.7 | 17.2 | 17.2 | ORIGINAL | Undefined |  | Undefined | 25 | 0 | 627.589 | 10 | Stålrør normaltykke | 0
Stålrør normaltykke | Nivå D + 1,2 m | 183.8 | 17.2 | 17.2 | ORIGINAL | Undefined |  | Undefined | 20 | 0 | 183.804 | 10 | Stålrør normaltykke | 0
Stålrør normaltykke | Nivå D + 1,2 m | 156.9 | 17.2 | 17.2 | ORIGINAL | Undefined |  | Undefined | 20 | 0 | 156.902 | 10 | Stålrør normaltykke | 0
Stålrør normaltykke | Nivå D + 1,2 m | 99.5 | 17.2 | 17.2 | ORIGINAL | Undefined |  | Undefined | 20 | 0 | 100 | 10 | Stålrør normaltykke | 0
Stålrør normaltykke | Nivå D + 1,2 m | 49.7 | 17.2 | 17.2 | ORIGINAL | Undefined |  | Undefined | 25 | 0 | 49.581 | 10 | Stålrør normaltykke | 0
Stålrør normaltykke | Nivå D + 1,2 m | 65 | 17.2 | 17.2 | ORIGINAL | Undefined |  | Undefined | 20 | 0 | 65 | 10 | Stålrør normaltykke | 0
Stålrør normaltykke | Nivå D + 1,2 m | 80 | 17.2 | 17.2 | ORIGINAL | Undefined |  | Undefined | 20 | 0 | 80 | 10 | Stålrør normaltykke | 0
Stålrør normaltykke | Nivå D + 1,2 m | 85 | 17.2 | 17.2 | ORIGINAL | Undefined |  | Undefined | 20 | 0 | 85 | 10 | Stålrør normaltykke | 0
2 x Stålrør normaltykke | Nivå D + 1,2 m | 69.9 | 17.2 | 17.2 | ORIGINAL | Undefined |  | Undefined | 20 | 0 | 70 | 10 | Stålrør normaltykke | 0
Stålrør normaltykke | Nivå D + 1,2 m | 101.8 | 17.2 | 17.2 | ORIGINAL | Undefined |  | Undefined | 20 | 0 | 102.1 | 10 | Stålrør normaltykke | 0
Stålrør normaltykke | Nivå D + 1,2 m | 5081.9 | 17.2 | 17.2 | ORIGINAL | Undefined |  | Undefined | 25 | 0 | 5081.88 | 10 | Stålrør normaltykke | 0
Stålrør normaltykke | Nivå D + 1,2 m | 204.8 | 17.2 | 17.2 | ORIGINAL | Undefined |  | Undefined | 20 | 0 | 205 | 10 | Stålrør normaltykke | 0
Stålrør normaltykke | Nivå D + 1,2 m | 180 | 17.2 | 17.2 | ORIGINAL | Undefined |  | Undefined | 20 | 0 | 180 | 10 | Stålrør normaltykke | 0
Stålrør normaltykke | Nivå D + 1,2 m | 98.3 | 17.2 | 17.2 | ORIGINAL | Undefined |  | Undefined | 20 | 0 | 97.667 | 10 | Stålrør normaltykke | 0
Stålrør normaltykke | Nivå D + 1,2 m | 1807.2 | 17.2 | 17.2 | ORIGINAL | Undefined |  | Undefined | 20 | 0 | 1807.24 | 10 | Stålrør normaltykke | 0
Stålrør normaltykke | Nivå D + 1,2 m | 95 | 17.2 | 17.2 | ORIGINAL | Undefined |  | Undefined | 20 | 0 | 95 | 10 | Stålrør normaltykke | 0
Stålrør normaltykke | Nivå D + 1,2 m | 1166.2 | 17.2 | 17.2 | ORIGINAL | Undefined |  | Undefined | 20 | 0 | 1166.19 | 10 | Stålrør normaltykke | 0
Stålrør normaltykke | Nivå D + 1,2 m | 122.2 | 17.2 | 17.2 | ORIGINAL | Undefined |  | Undefined | 20 | 0 | 122.1 | 10 | Stålrør normaltykke | 0
Stålrør normaltykke | Nivå D + 1,2 m | 42.8 | 17.2 | 17.2 | ORIGINAL | Undefined |  | Undefined | 20 | 0 | 43.361 | 10 | Stålrør normaltykke | 0
Stålrør normaltykke | Nivå D + 1,2 m | 159.8 | 17.2 | 17.2 | ORIGINAL | Undefined |  | Undefined | 20 | 0 | 160 | 10 | Stålrør normaltykke | 0
Stålrør normaltykke | Nivå D + 1,2 m | 287.1 | 17.2 | 17.2 | ORIGINAL | Undefined |  | Undefined | 20 | 0 | 287.1 | 10 | Stålrør normaltykke | 0
Stålrør normaltykke | Nivå D + 1,2 m | 109.4 | 17.2 | 17.2 | ORIGINAL | Undefined |  | Undefined | 20 | 0 | 109.408 | 10 | Stålrør normaltykke | 0
Stålrør normaltykke | Nivå D + 1,2 m | 399 | 26.6 | 26.6 | ORIGINAL | Undefined |  | Undefined | 0 | 0 | 398.611 | 20 | Stålrør normaltykke | 0
Stålrør normaltykke | Nivå D + 1,2 m | 204.7 | 26.6 | 26.6 | ORIGINAL | Undefined |  | Undefined | 0 | 0 | 205 | 20 | Stålrør normaltykke | 0
Stålrør normaltykke | Nivå D + 1,2 m | 595.1 | 26.6 | 26.6 | ORIGINAL | Undefined |  | Undefined | 0 | 0 | 595.054 | 20 | Stålrør normaltykke | 0
Stålrør normaltykke | Nivå D + 1,2 m | 66.5 | 26.6 | 26.6 | ORIGINAL | Undefined |  | Undefined | 0 | 0 | 65.609 | 20 | Stålrør normaltykke | 0
Stålrør normaltykke | Nivå D + 1,2 m | 5.5 | 26.6 | 26.6 | ORIGINAL | Undefined |  | Undefined | 0 | 0 | 5.525 | 20 | Stålrør normaltykke | 0
Stålrør normaltykke | Nivå D + 1,2 m | 12.2 | 26.6 | 26.6 | ORIGINAL | Undefined |  | Undefined | 0 | 0 | 11.715 | 20 | Stålrør normaltykke | 0
Stålrør normaltykke | Nivå D + 1,2 m | 2092.6 | 76 | 76 | ORIGINAL | Hydronic Supply | 32= T 60° Kopi 125 | VARME T | 0 | 0 | 2092.6 | 65 | Stålrør normaltykke | 0
Stålrør normaltykke | Nivå D + 1,2 m | 2255.3 | 76 | 76 | ORIGINAL | Hydronic Return | 32= R 50° Kopi 56 | VARME RETUR | 0 | 0 | 2255.35 | 65 | Stålrør normaltykke | 0
Stålrør normaltykke | Nivå D + 1,2 m | 3.2 | 21.4 | 21.4 | ORIGINAL | Hydronic Return | 32= R 20° Kopi 81 | GULVVARME PRIM R | 0 | 0 | 3.33 | 15 | Stålrør normaltykke | 0
Stålrør normaltykke | Nivå D + 1,2 m | 456.4 | 76 | 76 | ORIGINAL | Hydronic Supply | +TG=320.000.T | VARME T | 35 | 0 | 456.355 | 65 | Stålrør normaltykke | 0
Stålrør normaltykke | Nivå D + 1,2 m | 41.1 | 76 | 76 | ORIGINAL | Undefined |  | Undefined | 35 | 0 | 41.133 | 65 | Stålrør normaltykke | 0
Stålrør normaltykke | Nivå D + 1,2 m | 166.1 | 76 | 76 | ORIGINAL | Hydronic Return | +TG=320.000.R | VARME R | 35 | 0 | 166.139 | 65 | Stålrør normaltykke | 0
Stålrør normaltykke | Nivå D + 1,2 m | 34.7 | 76 | 76 | ORIGINAL | Undefined |  | Undefined | 35 | 0 | 34.597 | 65 | Stålrør normaltykke | 0
Stålrør normaltykke | Nivå D + 1,2 m | 1973.4 | 76 | 76 | ORIGINAL | Hydronic Return | 32= R 50° Kopi 56 | VARME RETUR | 0 | 0 | 1973.44 | 65 | Stålrør normaltykke | 0
Stålrør normaltykke | Nivå D + 1,2 m | 530 | 76 | 76 | ORIGINAL | Undefined |  | Undefined | 35 | 0 | 530.123 | 65 | Stålrør normaltykke | 0
Stålrør normaltykke | Nivå D + 1,2 m | 3320.1 | 76 | 76 | ORIGINAL | Undefined |  | Undefined | 35 | 0 | 3320.13 | 65 | Stålrør normaltykke | 0
Stålrør normaltykke | Nivå D + 1,2 m | 86.8 | 76 | 76 | ORIGINAL | Undefined |  | Undefined | 35 | 0 | 86.844 | 65 | Stålrør normaltykke | 0
Stålrør normaltykke | Nivå D + 1,2 m | 1038.4 | 76 | 76 | ORIGINAL | Hydronic Supply | +TG=320.000.T | VARME T | 35 | 0 | 1038.36 | 65 | Stålrør normaltykke | 0
Stålrør normaltykke | Nivå D + 1,2 m | 136.4 | 76 | 76 | ORIGINAL | Hydronic Return | +TG=320.000.R | VARME R | 35 | 0 | 135.892 | 65 | Stålrør normaltykke | 0
Stålrør normaltykke | Nivå D + 1,2 m | 128.1 | 76 | 76 | ORIGINAL | Hydronic Supply | +TG=320.000.T | VARME T | 35 | 0 | 128.067 | 65 | Stålrør normaltykke | 0
Stålrør normaltykke | Nivå D + 1,2 m | 14 | 48.2 | 48.2 | ORIGINAL | Hydronic Supply | 37= T 9° Kopi 44 | KJØL T | 0 | 0 | 14.412 | 40 | Stålrør normaltykke | 0
Stålrør normaltykke | Nivå D + 1,2 m | 48.2 | 9.2 | 48.2 | ORIGINAL | Hydronic Return | 37= R 18° Kopi 30 | KJØL R | 0 | 0 | 9.172 | 40 | Stålrør normaltykke | 0
Stålrør normaltykke | Nivå D + 1,2 m | 393.5 | 42.4 | 42.4 | ORIGINAL | Hydronic Supply | 37= T 9° Kopi 44 | KJØL T | 0 | 0 | 393.484 | 32 | Stålrør normaltykke | 0
Stålrør normaltykke | Nivå D + 1,2 m | 180.5 | 48.2 | 48.2 | ORIGINAL | Hydronic Return | 37= R 18° Kopi 30 | KJØL R | 0 | 0 | 180.433 | 40 | Stålrør normaltykke | 0
Stålrør normaltykke | Nivå D + 1,2 m | 1836 | 76 | 76 | RESULT | Hydronic Supply | +TG=320.000.T | VARME T |  |  |  |  | Stålrør normaltykke
Stålrør normaltykke | Nivå D + 1,2 m | 2126 | 76 | 76 | RESULT | Hydronic Return | +TG=320.000.R | VARME R |  |  |  |  | Stålrør normaltykke
Stålrør normaltykke | Nivå F - 0,7 m | 473 | 88 | 88 | RESULT | Fire Protection Wet | +TG=332.003 (2) | SPRINKEL |  |  |  |  | Stålrør normaltykke
2 x Stålrør normaltykke | Nivå F - 0,7 m | 387 | 34 | 34 | RESULT | Fire Protection Wet | +TG=332.003 (2) | SPRINKEL |  |  |  |  | Stålrør normaltykke
Stålrør normaltykke | Nivå F - 0,7 m | 1343 | 60 | 60 | RESULT | Fire Protection Wet | +TG=332.003 (2) | SPRINKEL |  |  |  |  | Stålrør normaltykke
Stålrør normaltykke | Nivå F - 0,7 m | 1338 | 60 | 60 | RESULT | Fire Protection Wet | +TG=332.003 (2) | SPRINKEL |  |  |  |  | Stålrør normaltykke
Stålrør normaltykke | Nivå F - 0,7 m | 1690 | 76 | 76 | RESULT | Fire Protection Wet | +TG=332.003 (2) | SPRINKEL
Stålrør normaltykke | Nivå D + 1,2 m | 6333 | 88 | 88 | RESULT | Fire Protection Wet | +TG=332.002 (1) (2) | SPRINKEL |  |  |  |  | Stålrør normaltykke
Stålrør normaltykke | Nivå D + 1,2 m | 366 | 34 | 34 | RESULT | Undefined |  | Undefined |  |  |  |  | Stålrør normaltykke
Stålrør normaltykke | Nivå D + 1,2 m | 311 | 48 | 48 | RESULT | Fire Protection Wet | +TG=332.003 (10) | SPRINKEL |  |  |  |  | Stålrør normaltykke
Stålrør normaltykke | Nivå D + 1,2 m | 370 | 34 | 34 | RESULT | Undefined |  | Undefined |  |  |  |  | Stålrør normaltykke
Stålrør normaltykke | Nivå D + 1,2 m | 202 | 55 | 60 | RESULT | Undefined |  | Undefined |  |  |  |  | Stålrør normaltykke
Stålrør normaltykke | Nivå D + 1,2 m | 373 | 26 | 26 | RESULT | Hydronic Supply | 37= T 9° Kopi 122 | KJØL T |  |  |  |  | Stålrør normaltykke
Stålrør normaltykke | Nivå D + 1,2 m | 373 | 26 | 26 | RESULT | Hydronic Return | 37= R 18° Kopi 82 | KJØL R |  |  |  |  | Stålrør normaltykke
Stålrør normaltykke | Nivå D + 1,2 m | 4758 | 48 | 48 | RESULT | Undefined |  | Undefined |  |  |  |  | Stålrør normaltykke
Stålrør normaltykke | Nivå D + 1,2 m | 76 | 60 | 60 | RESULT | Hydronic Return | 32= R 50° Kopi 54 | VARME RETUR |  |  |  |  | Stålrør normaltykke
Stålrør normaltykke | Nivå D + 1,2 m | 159 | 64 | 76 | RESULT | Undefined |  | Undefined |  |  |  |  | Stålrør normaltykke
Stålrør normaltykke | Nivå D + 1,2 m | 359 | 48 | 48 | RESULT | Undefined |  | Undefined |  |  |  |  | Stålrør normaltykke

# IfcFlowTerminal: 5611144 IDO Trevi
In: Nivå F - 0,7 m
Type - Description: WASHBASIN TREVI 500x360
ePset_LocationTool - Splitting: ORIGINAL
MagiCAD Pset_DrainageDevices - Manufacturer: IDO; Product Code: 5611144 IDO Trevi; User Code: WB1; ConnectionSize_mm: 0 mm; Description: WASHBASIN TREVI 500x360
ePset_Simplebim - Assembly Level: Leaf
Group: 31= SPV Kopi 147 (1)

# IfcFlowTerminal: A10-S350 118 WALL (12)
In: Nivå F
Type - Description: Glamox A10-S is a very versatile circular luminaire with high light output and a decorative ill
MagiCAD Pset_Device - System code: 442; Switchboard: +TG=433.055; Manufacturer: Glamox; User code: IB2105; Length [mm]: 0 mm; Width [mm]: 0 mm; Height [mm]: 0 mm
AVINOR - 07_Fase: F90; 04_Kontrakt: FDV; 08_Status: S2; ID-nummer2: +TO=446.001-IB2105; 05_ID-nummer: +TO=446.001-IB2105; 06_Omrade: TG; 03_Ansvar: T20100; 02_Prosjekt: 72101; 01_Lufthavnkode: ENGM
ePset_LocationTool - Splitting: ORIGINAL
ePset_Simplebim - Assembly Level: Leaf
Pset_LightFixtureTypeCommon - TotalWattage: 0 W
Pset_ElectricalDeviceCommon - ElectricalDeviceNominalPower: 0 W; NumberOfPoles: 1; NominalVoltage: 230
Group: Belysningsutstyr
Name | Circuit
10 x A10-S350 118 WALL | 57
2 x A10-S350 118 WALL | 56

# IfcFlowTerminal: A313 - Vaskgruppe x0:A313 - Vaskgruppe - b=600 mm, A313 - Vaskgruppe x0:A313 - Vaskgruppe - b=600 mm:46848042
In: Nivå F - 0,7 m
Type - Material: NSW - våtrom silver
AVINOR - 08_Status: S4; 07_Fase: F90; 03_Ansvar: FDV; 06_Omrade: TG; 02_Prosjekt: T20100; 01_Lufthavnkode: ENGM
Pset_QuantityTakeOff - Reference: A313 - Vaskgruppe - b=600 mm; sets with these values: 2
ePset_LocationTool - Splitting: ORIGINAL
ePset_Simplebim - Assembly Level: Leaf

# IfcFlowTerminal: A313 - Vaskgruppe x1:A313 - Vaskgruppe - 850 x 600mm (3)
In: Nivå F - 0,7 m
Type - Material: NSW - våtrom silver
AVINOR - 08_Status: S4; 07_Fase: F90; 03_Ansvar: FDV; 06_Omrade: TG; 02_Prosjekt: T20100; 01_Lufthavnkode: ENGM
ePset_LocationTool - Splitting: ORIGINAL
Pset_DistributionFlowElementCommon - Reference: A313 - Vaskgruppe - 850 x 600mm; sets with these values: 2
ePset_Simplebim - Assembly Level: Leaf
Name (A313 - Vaskgruppe x1:A313 - Vaskgruppe - 850 x 600mm:...)
46848033
46848035
46848037

# IfcFlowTerminal: A313 - WC vegghengt kompakt:A313 - WC vegghengt kompakt - 375 x 570 mm (5)
In: Nivå F - 0,7 m
Type - Material: <Unnamed>
ePset_Simplebim - Assembly Level: Leaf
AVINOR - 08_Status: S1; 06_Omrade: TG; 02_Prosjekt: T20100; 07_Fase: F50; 03_Ansvar: AV1; 01_Lufthavnkode: ENGM
Pset_QuantityTakeOff - Reference: A313 - WC vegghengt kompakt - 375 x 570 mm; sets with these values: 2
ePset_LocationTool - Splitting: ORIGINAL
Name (A313 - WC vegghengt kompakt:A313 - WC vegghengt kompakt - 375 x 570 mm:...)
46848022
46848029
46848030
46848031
46848032

# IfcFlowTerminal: B21 (3)
In: Nivå F - 0,7 m
Type - Description: Sluk 75 rustfri
ePset_Simplebim - Assembly Level: Leaf
ePset_LocationTool - Splitting: ORIGINAL
MagiCAD Pset_DrainageDevices - Product Code: Sluk 75 rustfri; Description: Sluk 75 rustfri; NationalCode: UT5.101054; ConnectionSize_mm: 0 mm; User Code: KN03T
Name | Group
B21 | 31= SPV Kopi 147 (5)
B21 | 31= SPV Kopi 147 (4)
B21 | 31= SPV Kopi 147 (3)

# IfcFlowTerminal: BM NO. 210.200.075 V MULTI 206-75S D150 Horizontal (3)
In: Nivå F - 0,7 m
Type - Description: Floor drain, bath/shower use. Light duty
MagiCAD Pset_DrainageDevices - User Code: sluk 75s; Description: Floor drain, bath/shower use. Light duty; Manufacturer: Blucher; ConnectionSize_mm: 0 mm; Product Code: BM NO. 210.200.075 V MULTI 206-75S D150 Horizontal
ePset_Simplebim - Assembly Level: Leaf
ePset_LocationTool - Splitting: ORIGINAL

# IfcFlowTerminal: BRD-100
In: Nivå F - 0,7 m
Type - Description: Wall diffuser with plenum box
MagiCAD Pset_AirTerminal - Description: Wall diffuser with plenum box; dpTot_SizingFlow_Pa: 0 kPa; qv_SizingFlow_ms: 0 m/s; ConnectionSize_mm: 100; qv_SizingFlow_ls: 27.778 m3/s; Manufacturer: Klimatbyran_Netavent; ProductCode: BRD-100
ePset_LocationTool - Splitting: ORIGINAL
ePset_Simplebim - Assembly Level: Leaf
Group: +TG=360.021-1 TL

# IfcFlowTerminal: D20-R210 226 (6)
In: Nivå F
Type - Description: plug and play solution, meaning easy installation.
Pset_ElectricalDeviceCommon - NumberOfPoles: 1; ElectricalDeviceNominalPower: 50 W; NominalVoltage: 230
AVINOR - 07_Fase: F90; 04_Kontrakt: FDV; 08_Status: S2; 06_Omrade: TG; 03_Ansvar: T20100; 02_Prosjekt: 72101; 01_Lufthavnkode: ENGM; ID-nummer2: +TO=446.001-IB2206; 05_ID-nummer: +TO=446.001-IB2206
ePset_LocationTool - Splitting: ORIGINAL
Pset_LightFixtureTypeCommon - TotalWattage: 50 W
ePset_Simplebim - Assembly Level: Leaf
MagiCAD Pset_Device - System code: 442; User code: IB2206; Manufacturer: Glamox; Length [mm]: 0 mm; Width [mm]: 0 mm; Height [mm]: 0 mm
Group: Belysningsutstyr

# IfcFlowTerminal: Electra 6220F
In: Nivå F - 0,7 m
Type - Description: Electra lavatory faucet 230V, temperature adjustment
MagiCAD Pset_WaterDevices - User Code: vask; Manufacturer: Oras; ProductCode: Electra 6220F; ConnectionSize_mm: 0 mm; qv_SizingFlow_ls: 0 m3/s; pTot_SizingFlow_Pa: 0 kPa; dpTot_SizingFlow_Pa: 0 kPa; Description: Electra lavatory faucet 230V, temperature adjustment
ePset_Simplebim - Assembly Level: Leaf
ePset_LocationTool - Splitting: ORIGINAL
Group: KV; VV

# IfcFlowTerminal: IB1152 (2)
In: Nivå D + 1,2
Type - Description: Industrial luminaire IP 23, with special installation system which reduces installation time up to 50%
Pset_ElectricalDeviceCommon - NumberOfPoles: 1; ElectricalDeviceNominalPower: 54 W; NominalVoltage: 230
ePset_LocationTool - Splitting: ORIGINAL
AVINOR - 07_Fase: F90; 05_ID-nummer: +TO=446.001-IB1152; ID-nummer2: +TO=446.001-IB1152; 04_Kontrakt: FDV; 08_Status: S2; 06_Omrade: TG; 03_Ansvar: T20100; 02_Prosjekt: 72101; 01_Lufthavnkode: ENGM
MagiCAD Pset_Device - System code: 442; Manufacturer: Glamox; Length [mm]: 0 mm; Width [mm]: 0 mm; Height [mm]: 0 mm; User code: IB1152
Pset_LightFixtureTypeCommon - TotalWattage: 54 W
ePset_Simplebim - Assembly Level: Leaf
Group: Belysningsutstyr

# IfcFlowTerminal: IB5310 Zumtobe Panos INF R200H 16W LED940 LDO SM WH (10)
In: Nivå F
Type - Description: Lysarmatur LED Downlight Innfelt Interiør
MagiCAD Pset_Device - System code: 442; Switchboard: +TG=433.055; User code: IB5310; Length [mm]: 0 mm; Width [mm]: 0 mm; Height [mm]: 0 mm
ePset_Simplebim - Assembly Level: Leaf
Pset_ElectricalDeviceCommon - NominalVoltage: 0; ElectricalDeviceNominalPower: 0 W; NumberOfPoles: 0
Pset_LightFixtureTypeCommon - TotalWattage: 0 W
ePset_LocationTool - Splitting: ORIGINAL
AVINOR - 08_Status: S4; 07_Fase: F90; 02_Prosjekt: A162446; 05_ID-nummer: +TO=442.001-IB5310; ID-nummer2: +TO=442.001-IB5310; 06_Omrade: TG; 04_Kontrakt: 183766; 03_Ansvar: 181608; 01_Lufthavnkode: ENGM
Group: Belysningsutstyr
Name | Circuit
7 x IB5310 Zumtobe Panos INF R200H 16W LED940 LDO SM WH | 59
3 x IB5310 Zumtobe Panos INF R200H 16W LED940 LDO SM WH | 60

# IfcFlowTerminal: IB5375 Zumtobel Vivo M LED2200-930 LDO 3CY WFL-S SRM (5)
In: Nivå F
Type - Description: Lysarmatur LED Spotlight på Strømskinne
MagiCAD Pset_Device - System code: 442; User code: IB5375; Length [mm]: 0 mm; Width [mm]: 0 mm; Height [mm]: 0 mm
AVINOR - 08_Status: S4; 07_Fase: F90; 05_ID-nummer: +TO=442.001-IB5375; ID-nummer2: +TO=442.001-IB5375; 06_Omrade: TG; 03_Ansvar: T20100; 04_Kontrakt: 72586; 02_Prosjekt: 72101; 01_Lufthavnkode: ENGM
ePset_Simplebim - Assembly Level: Leaf
Pset_ElectricalDeviceCommon - NominalVoltage: 0; ElectricalDeviceNominalPower: 0 W; NumberOfPoles: 0
Pset_LightFixtureTypeCommon - TotalWattage: 0 W
ePset_LocationTool - Splitting: ORIGINAL
Group: Belysningsutstyr

# IfcFlowTerminal: IB5402 Zumtobel Panos INF E200HG 29W LED930 LDO WH (8)
In: Nivå F
Type - Description: Lysarmatur LED Downlight Innfelt Interiør
ePset_LocationTool - Splitting: ORIGINAL
ePset_Simplebim - Assembly Level: Leaf
Pset_ElectricalDeviceCommon - NominalVoltage: 0; ElectricalDeviceNominalPower: 0 W; NumberOfPoles: 0
Pset_LightFixtureTypeCommon - TotalWattage: 0 W
AVINOR - 08_Status: S4; 05_ID-nummer: +TO=442.001-IB5402; ID-nummer2: +TO=442.001-IB5402; 07_Fase: F90; 02_Prosjekt: A162446; 06_Omrade: TG; 04_Kontrakt: 183766; 03_Ansvar: 181608; 01_Lufthavnkode: ENGM
MagiCAD Pset_Device - User code: IB5402; System code: 442; Length [mm]: 0 mm; Width [mm]: 0 mm; Height [mm]: 0 mm
Group: Belysningsutstyr

# IfcFlowTerminal: IB7330 Zumtobel Puresign/Comsign 150 ED NDA
In: Nivå F
Type - Description: Markeringslys ensidig 30 meter leseavstand innfelt
MagiCAD Pset_Device - System code: 443; Manufacturer: Zumtobel; User code: IB7330; Length [mm]: 0 mm; Width [mm]: 0 mm; Height [mm]: 0 mm; Circuit: 1; Switchboard: +TG=443.232
ePset_LocationTool - Splitting: ORIGINAL
Pset_LightFixtureTypeCommon - TotalWattage: 4.5 W
AVINOR - TT-nummer: +TG=443.232-TT6109; 08_Status: S4; 02_Prosjekt: A172140; 05_ID-nummer: +TO=443.001-IB7330; ID-nummer2: +TO=443.001-IB7330; 06_Omrade: TG; 07_Fase: F50; 03_Ansvar: 181608; 04_Kontrakt: 184990; 01_Lufthavnkode: ENGM
ePset_Simplebim - Assembly Level: Leaf
Pset_ElectricalDeviceCommon - NumberOfPoles: 1; ElectricalDeviceNominalPower: 4.5 W; NominalVoltage: 230
Group: Utstyr for nødlys

# IfcFlowTerminal: IB7404 Zumtobel Resclite C Antipanic AD NDA WH (3)
In: Nivå F
Type - Description: Ledelys utenpåliggende
ePset_LocationTool - Splitting: ORIGINAL
AVINOR - 08_Status: S4; 02_Prosjekt: A172140; 06_Omrade: TG; 07_Fase: F50; 03_Ansvar: 181608; 04_Kontrakt: 184990; ID-nummer2: +TO=443.001-IB7404; 05_ID-nummer: +TO=443.001-IB7404; 01_Lufthavnkode: ENGM
MagiCAD Pset_Device - Product code: Resclite C Antipanic AD NDA WH; System code: 443; Manufacturer: ZUMTOBEL; User code: IB7404; Length [mm]: 0 mm; Width [mm]: 0 mm; Height [mm]: 0 mm
ePset_Simplebim - Assembly Level: Leaf
Pset_LightFixtureTypeCommon - TotalWattage: 0 W
Pset_ElectricalDeviceCommon - ElectricalDeviceNominalPower: 0 W; NumberOfPoles: 1; NominalVoltage: 230
Group: Utstyr for nødlys
Name | TT-nummer | Circuit | Switchboard
IB7404 Zumtobel Resclite C Antipanic AD NDA WH | +TG=443.232-TT6107 | 1 | +TG=443.232
IB7404 Zumtobel Resclite C Antipanic AD NDA WH | +TG=443.212-TT6101 | 6 | +TG=443.212
IB7404 Zumtobel Resclite C Antipanic AD NDA WH | +TG=443.222-TT6216 | 9 | +TG=443.222

# IfcFlowTerminal: IB7405 Zumtobel Resclite C Antipanic ED NDA WH (4)
Type - Description: Ledelys innfelt i himling
MagiCAD Pset_Device - System code: 443; Product code: Resclite C Antipanic ED NDA WH; Manufacturer: Zumtobel; Length [mm]: 0 mm; Width [mm]: 0 mm; Height [mm]: 0 mm; Circuit: 1; User code: IB7405
Pset_LightFixtureTypeCommon - TotalWattage: 6 W
ePset_LocationTool - Splitting: ORIGINAL
Pset_ElectricalDeviceCommon - NumberOfPoles: 1; ElectricalDeviceNominalPower: 6 W; NominalVoltage: 230
AVINOR - 08_Status: S4; 02_Prosjekt: A172140; 05_ID-nummer: +TO=443.001-IB7405; ID-nummer2: +TO=443.001-IB7405; 06_Omrade: TG; 07_Fase: F50; 03_Ansvar: 181608; 04_Kontrakt: 184990; 01_Lufthavnkode: ENGM
ePset_Simplebim - Assembly Level: Leaf
Group: Utstyr for nødlys
Name | In | Switchboard | TT-nummer
IB7405 Zumtobel Resclite C Antipanic ED NDA WH | Nivå F | +TG=443.232 | +TG=443.232-TT6106
IB7405 Zumtobel Resclite C Antipanic ED NDA WH | Nivå F - 0,7 | +TG=443.232 | +TG=443.232-TT6105
IB7405 Zumtobel Resclite C Antipanic ED NDA WH | Nivå F - 0,7 | +TG=443.242 | +TG=443.242-TT6110
IB7405 Zumtobel Resclite C Antipanic ED NDA WH | Nivå F - 0,7 | +TG=443.232 | +TG=443.232-TT6104

# IfcFlowTerminal: IB7406 Zumtobel Resclite C Escape ED NDA WH (2)
In: Nivå F
Type - Description: Ledelys innfelt i himling
ePset_LocationTool - Splitting: ORIGINAL
AVINOR - 08_Status: S4; 02_Prosjekt: A172140; 06_Omrade: TG; 05_ID-nummer: +TO=443.001-IB7406; ID-nummer2: +TO=443.001-IB7406; 07_Fase: F50; 03_Ansvar: 181608; 04_Kontrakt: 184990; 01_Lufthavnkode: ENGM
Pset_LightFixtureTypeCommon - TotalWattage: 6 W
MagiCAD Pset_Device - System code: 443; Manufacturer: Zumtobel; Product code: Resclite C Escape ED NDA WH; Length [mm]: 0 mm; Width [mm]: 0 mm; Height [mm]: 0 mm; User code: IB7406
Pset_ElectricalDeviceCommon - NumberOfPoles: 1; ElectricalDeviceNominalPower: 6 W; NominalVoltage: 230
ePset_Simplebim - Assembly Level: Leaf
Group: Utstyr for nødlys
Name | TT-nummer | Circuit | Switchboard
IB7406 Zumtobel Resclite C Escape ED NDA WH | +TG=443.242-TT6109 | 1 | +TG=443.242
IB7406 Zumtobel Resclite C Escape ED NDA WH | +TG=443.222-TT6215 | 9 | +TG=443.222

# IfcFlowTerminal: IB9510 (5)
In: Nivå F
Type - Description: Powerful asymmetric uplighter
AVINOR - 08_Status: S4; 07_Fase: A; 06_Omrade: TG; ID-nummer2: +TO=442.001-IB9510; 05_ID-nummer: +TO=442.001-IB9510; 02_Prosjekt: 10003145; 01_Lufthavnkode: ENGM
ePset_LocationTool - Splitting: ORIGINAL
ePset_Simplebim - Assembly Level: Leaf
Pset_ElectricalDeviceCommon - NumberOfPoles: 1; NominalVoltage: 230; ElectricalDeviceNominalPower: 275 W
MagiCAD Pset_Device - Product code: A52 1X400W GREY W/SEP BALLAST; Circuit: 14; System code: 442; Manufacturer: Glamox; User code: IB9510; Length [mm]: 0 mm; Width [mm]: 0 mm; Height [mm]: 0 mm; Switchboard: +TG=433.045
Pset_LightFixtureTypeCommon - TotalWattage: 275 W
Group: Belysningsutstyr
Name | O1
IB9510 | B49
IB9510 | B50
IB9510 | B46
IB9510 | B47
IB9510 | B48

# IfcFlowTerminal: Jordet-topolet-1-veis-m_boks (24)
Type - Description: Jordet topolet 1-veis m/boks; PredefinedType: POWEROUTLET
Pset_ElectricalDeviceCommon - NumberOfPoles: 1; IP_Code: 20; ElectricalDeviceNominalPower: 150 W; NominalVoltage: 230
ePset_Simplebim - Assembly Level: Leaf
Pset_OutletTypeCommon - IsPluggableOutlet: yes
MagiCAD Pset_Device - National code: WL1.2111; Length [mm]: 0 mm; Width [mm]: 0 mm; Height [mm]: 0 mm; Product code: Elko S1012 PT; P1: -UE; Manufacturer: General; User code: 03
AVINOR - 07_Fase: F90; 06_Omrade: TG; 01_Lufthavnkode: ENGM
ePset_LocationTool - Splitting: ORIGINAL
Name | In | System code | Switchboard | Circuit | 08_Status | ID-nummer2 = 05_ID-nummer | 02_Prosjekt | 04_Kontrakt | 03_Ansvar | Group
2 x Jordet-topolet-1-veis-m_boks | Nivå F | 441 | +TG=433.055 | 3 | S4 | +TO=441.001 | A162446 | 183766 | 181608 | Kursopplegg for belysning
7 x Jordet-topolet-1-veis-m_boks | Nivå F | 441 | +TG=436.255 | 1 | S4 | +TO=441.001 | A162446 | 183766 | 181608 | Kursopplegg for belysning
4 x Jordet-topolet-1-veis-m_boks | Nivå F | 441 | +TG=433.055 | 15 | S2 | +TO=441.001 | 72101 | FDV | T20100 | Kursopplegg for belysning
Jordet-topolet-1-veis-m_boks | Nivå F | 441 | +TG=433.055 | 2 | S2 | +TO=441.001 | 72101 | FDV | T20100 | Kursopplegg for belysning
Jordet-topolet-1-veis-m_boks | Nivå F | 441 | +TG=433.055 | 6 | S2 | +TO=441.001 | 72101 | FDV | T20100 | Kursopplegg for belysning
2 x Jordet-topolet-1-veis-m_boks | Nivå F | 441 | +TG=433.055 | 4 | S2 | +TO=441.001 | 72101 | FDV | T20100 | Kursopplegg for belysning
2 x Jordet-topolet-1-veis-m_boks | Nivå F | 441 | +TG=433.055 | 15 | S4 | +TO=441.001 | A162446 | 183766 | 181608 | Kursopplegg for belysning
Jordet-topolet-1-veis-m_boks | Nivå F | 441 | +TG=433.045 | 2 | S4 | +TO=441.001 | A162446 | 183766 | 181608 | Kursopplegg for belysning
2 x Jordet-topolet-1-veis-m_boks | Nivå F - 0,7 | 461 | +TG=433.055 | 97 | S2 | +TO=461.001 | 72101 | FDV | T20100 | Kursopplegg for drift og virksomhet
2 x Jordet-topolet-1-veis-m_boks | Nivå F - 0,7 | 461 | +TG=433.055 | 95 | S2 | +TO=461.001 | 72101 | FDV | T20100 | Kursopplegg for drift og virksomhet

# IfcFlowTerminal: Jordet-topolet-2-veis m_boks (HOR) (7)
In: Nivå F - 0,7
Type - PredefinedType: POWEROUTLET
ePset_LocationTool - Splitting: ORIGINAL
ePset_Simplebim - Assembly Level: Leaf
Pset_OutletTypeCommon - IsPluggableOutlet: yes
MagiCAD Pset_Device - Length [mm]: 0 mm; Width [mm]: 0 mm; Height [mm]: 0 mm; P1: -UE; Manufacturer: General; System code: 461
AVINOR - 08_Status: S4; 07_Fase: F90; 02_Prosjekt: A162446; 05_ID-nummer: +TO=461.001; ID-nummer2: +TO=461.001; 06_Omrade: TG; 04_Kontrakt: 183766; 03_Ansvar: 181608; 01_Lufthavnkode: ENGM
Pset_ElectricalDeviceCommon - ElectricalDeviceNominalPower: 0 W; NumberOfPoles: 1; NominalVoltage: 230
Group: Kursopplegg for drift og virksomhet
Name | Circuit | Switchboard
2 x Jordet-topolet-2-veis m_boks (HOR) | 94 | +TG=433.055
4 x Jordet-topolet-2-veis m_boks (HOR) | 7 | +TG=436.255
Jordet-topolet-2-veis m_boks (HOR)

# IfcFlowTerminal: Jordet-topolet-2-veis m_boks-i-gulv
In: Nivå F - 0,7
Type - Description: Jordet topolet 2-veis m/boks GULV; PredefinedType: POWEROUTLET
MagiCAD Pset_Device - Product code: Earthed recessed socket floor 2; National code: WL1.2121; Length [mm]: 0 mm; Width [mm]: 0 mm; Height [mm]: 0 mm; Circuit: 25; P1: -UE; Manufacturer: General; Switchboard: +TG=433.045; System code: 461
ePset_LocationTool - Splitting: ORIGINAL
ePset_Simplebim - Assembly Level: Leaf
Pset_OutletTypeCommon - IsPluggableOutlet: yes
AVINOR - 08_Status: S4; 07_Fase: F90; 02_Prosjekt: A162446; 05_ID-nummer: +TO=461.001; ID-nummer2: +TO=461.001; 06_Omrade: TG; 04_Kontrakt: 183766; 03_Ansvar: 181608; 01_Lufthavnkode: ENGM
Pset_ElectricalDeviceCommon - ElectricalDeviceNominalPower: 0 W; NumberOfPoles: 1; NominalVoltage: 230
Group: Kursopplegg for drift og virksomhet

# IfcFlowTerminal: Jordet-topolet-2-veis m_boks-i-tak (2)
In: Nivå D + 1,2
Type - Description: Jordet topolet 2-veis m/boks i tak; PredefinedType: POWEROUTLET
MagiCAD Pset_Device - National code: WL1.2121; Product code: Elko RS1091; User code: 02; Length [mm]: 0 mm; Width [mm]: 0 mm; Height [mm]: 0 mm; P1: -UE; Manufacturer: General; System code: 461
Pset_ElectricalDeviceCommon - IP_Code: IP20; ElectricalDeviceNominalPower: 0 W; NumberOfPoles: 1; NominalVoltage: 230
AVINOR - 07_Fase: F90; 05_ID-nummer: +TO=461.001; ID-nummer2: +TO=461.001; 06_Omrade: TG; 01_Lufthavnkode: ENGM
ePset_LocationTool - Splitting: ORIGINAL
ePset_Simplebim - Assembly Level: Leaf
Pset_OutletTypeCommon - IsPluggableOutlet: yes
Group: Kursopplegg for drift og virksomhet
Name | 08_Status
Jordet-topolet-2-veis m_boks-i-tak | S2 | AVINOR - 04_Kontrakt: FDV; 03_Ansvar: T20100; 02_Prosjekt: 72101
Jordet-topolet-2-veis m_boks-i-tak | S4 | MagiCAD Pset_Device - Circuit: 34; Switchboard: +TG=433.043

# IfcFlowTerminal: Jordet-topolet-2-veis-Påvegg (4)
In: Nivå F - 0,7
Type - Description: Jordet topolet 2-veis Påvegg Horizontal; PredefinedType: POWEROUTLET
AVINOR - 07_Fase: F90; 04_Kontrakt: FDV; 05_ID-nummer: +TO=461.001; ID-nummer2: +TO=461.001; 08_Status: S2; 06_Omrade: TG; 03_Ansvar: T20100; 02_Prosjekt: 72101; 01_Lufthavnkode: ENGM
ePset_Simplebim - Assembly Level: Leaf
ePset_LocationTool - Splitting: ORIGINAL
Pset_OutletTypeCommon - IsPluggableOutlet: yes
MagiCAD Pset_Device - National code: WL1.2111; Switchboard: +TG=433.055; Length [mm]: 0 mm; Width [mm]: 0 mm; Height [mm]: 0 mm; P1: -UE; Manufacturer: General; System code: 461
Pset_ElectricalDeviceCommon - ElectricalDeviceNominalPower: 0 W; NumberOfPoles: 1; NominalVoltage: 230
Group: Kursopplegg driftsteknisk
Name | Circuit
Jordet-topolet-2-veis-Påvegg | 61
Jordet-topolet-2-veis-Påvegg | 62
Jordet-topolet-2-veis-Påvegg | 63
Jordet-topolet-2-veis-Påvegg | 64

# IfcFlowTerminal: KSO 100 (6)
In: Nivå F - 0,7 m
Type - Description: Exhaust diffusor.
ePset_LocationTool - Splitting: ORIGINAL
ePset_Simplebim - Assembly Level: Leaf
MagiCAD Pset_AirTerminal - Manufacturer: TROX Auranor; dpTot_SizingFlow_Pa: 0 kPa; qv_SizingFlow_ms: 0 m/s; ProductCode: KSO-100; Description: Exhaust diffusor.
Group: +TG=360.021-22 A
Name | qv_SizingFlow_ls (m3/s)
KSO 100 | 27.778
5 x KSO 100 | 20.833

# IfcFlowTerminal: KSO 160 (3)
In: Nivå F - 0,7 m
Type - Description: Exhaust diffusor.
ePset_LocationTool - Splitting: ORIGINAL
ePset_Simplebim - Assembly Level: Leaf
MagiCAD Pset_AirTerminal - User Code: trox; Manufacturer: TROX Auranor; dpTot_SizingFlow_Pa: 0 kPa; qv_SizingFlow_ms: 0 m/s; ProductCode: KSO-160; qv_SizingFlow_ls: 20.833 m3/s; Description: Exhaust diffusor.
Group: +TG=360.001 A

# IfcFlowTerminal: KV160
In: Nivå F
Type - Description: Exhaust valve
ePset_LocationTool - Splitting: ORIGINAL
ePset_Simplebim - Assembly Level: Leaf
MagiCAD Pset_AirTerminal - dpTot_SizingFlow_Pa: 0 kPa; qv_SizingFlow_ms: 0 m/s; Description: Exhaust valve; qv_SizingFlow_ls: 55.556 m3/s; ConnectionSize_mm: 160; Manufacturer: Klimatbyran_Netavent; ProductCode: KV160
Group: +TG=360.021-22 A

# IfcFlowTerminal: Koblingsboks tak-himling (7)
In: Nivå F - 0,7
Type - Description: Jordet topolet 2-veis m/boks i tak; PredefinedType: POWEROUTLET
AVINOR - 07_Fase: F90; 05_ID-nummer: +TO=461.001; ID-nummer2: +TO=461.001; 06_Omrade: TG; 01_Lufthavnkode: ENGM
MagiCAD Pset_Device - User code: -QM; Length [mm]: 0 mm; Width [mm]: 0 mm; Height [mm]: 0 mm; Manufacturer: General; System code: 461
ePset_Simplebim - Assembly Level: Leaf
Pset_OutletTypeCommon - IsPluggableOutlet: yes
ePset_LocationTool - Splitting: ORIGINAL
Pset_ElectricalDeviceCommon - ElectricalDeviceNominalPower: 0 W; NumberOfPoles: 1; NominalVoltage: 230
Group: Kursopplegg for drift og virksomhet
Name | 04_Kontrakt | 08_Status | 03_Ansvar | 02_Prosjekt | Switchboard | Circuit
Koblingsboks tak-himling | FDV | S2 | T20100 | 72101 | +TG=433.055 | 65
Koblingsboks tak-himling | FDV | S2 | T20100 | 72101 | +TG=433.055 | 81
Koblingsboks tak-himling | 183766 | S4 | 181608 | A162446 | +TG=436.255 | 8
Koblingsboks tak-himling | 183766 | S4 | 181608 | A162446 | +TG=436.255 | 10
Koblingsboks tak-himling | 183766 | S4 | 181608 | A162446 | +TG=436.255 | 9
Koblingsboks tak-himling | 183766 | S4 | 181608 | A162446 | +TG=436.255 | 11
Koblingsboks tak-himling | 183766 | S4 | 181608 | A162446 | +TG=433.055 | 98

# IfcFlowTerminal: LOV-160
In: Nivå F - 0,7 m
Type - Description: Supply air diffusor for panneld ceiling.
ePset_LocationTool - Splitting: ORIGINAL
MagiCAD Pset_AirTerminal - ProductCode: LOV-160; User Code: TROX; Description: Supply air diffusor for panneld ceiling.; Manufacturer: TROX Auranor; dpTot_SizingFlow_Pa: 0 kPa; qv_SizingFlow_ms: 0 m/s; qv_SizingFlow_ls: 41.667 m3/s; ConnectionSize_mm: 160
ePset_Simplebim - Assembly Level: Leaf
Group: +TG=360.021-1 TL

# IfcFlowTerminal: OTHER-EE-POWER-BALANCED-DUMMY (18)
In: Nivå F - 0,7
Type - Description: Fuktighetsføler
Description: Gulvboks 60x60
ePset_LocationTool - Splitting: ORIGINAL
AVINOR - 07_Fase: F90; 04_Kontrakt: FDV; 08_Status: S2; ID-nummer2: +TO=411.501; 05_ID-nummer: +TO=411.501; 06_Omrade: TG; 03_Ansvar: T20100; 02_Prosjekt: 72101; 01_Lufthavnkode: ENGM
MagiCAD Pset_Device - Length [mm]: 0 mm; Width [mm]: 0 mm; Height [mm]: 0 mm; Manufacturer: General
ePset_Simplebim - Assembly Level: Leaf
Pset_ElectricalDeviceCommon - NominalVoltage: 0; ElectricalDeviceNominalPower: 0 W; NumberOfPoles: 1

# IfcFlowTerminal: Other_E-Dummy-EE (8)
Type - Description: Tempraturføler
AVINOR - 07_Fase: F90; 06_Omrade: TG; 01_Lufthavnkode: ENGM
ePset_Simplebim - Assembly Level: Leaf
ePset_LocationTool - Splitting: ORIGINAL
MagiCAD Pset_Device - Product code: Other_E-Dummy-EE; Length [mm]: 0 mm; Width [mm]: 0 mm; Height [mm]: 0 mm; Manufacturer: General
Pset_ElectricalDeviceCommon - ElectricalDeviceNominalPower: 0 W; NumberOfPoles: 1; NominalVoltage: 230
Name | In | Description | 04_Kontrakt | 05_ID-nummer = ID-nummer2 | 08_Status | 03_Ansvar | 02_Prosjekt | System code | National code | Group
6 x Other_E-Dummy-EE | Nivå D + 1,2 | Motorstyrt ventil | FDV | +TG=561.001 | S2 | T20100 | 72101 | 561 | XJ3.1 | BUS System
Other_E-Dummy-EE | Nivå F - 0,7 | Motorstyrt ventil | 183766 | +TG=561.001 | S4 | 181608 | A162446 | 561 | XJ3.1 | BUS System | MagiCAD Pset_Device - Circuit: <unnamed>
Other_E-Dummy-EE | Nivå F - 0,7 |  | 183766 | +TO=562.001 | S4 | 181608 | A162446 | 462 | XL2.0 | Utstyr for automatisering

# IfcFlowTerminal: RIA-1-700x1200
In: Nivå F - 0,7 m
Type - Description: Wall mounted outdoor louvres
ePset_LocationTool - Splitting: ORIGINAL
ePset_Simplebim - Assembly Level: Leaf
MagiCAD Pset_AirTerminal - User Code: RIA; qv_SizingFlow_ls: 138.889 m3/s; dpTot_SizingFlow_Pa: 0 kPa; qv_SizingFlow_ms: 0 m/s; ProductCode: RIA-1-700x1200; Description: Wall mounted outdoor louvres
Group: +TG=360.021-1 TL

# IfcFlowTerminal: SKA 118 (3)
In: Nivå F
Type - Description: Batten luminaire for T8 lamps.
MagiCAD Pset_Device - System code: 442; Switchboard: +TG=433.055; Manufacturer: Glamox; Length [mm]: 0 mm; Width [mm]: 0 mm; Height [mm]: 0 mm; User code: IB1109
AVINOR - 07_Fase: F90; 04_Kontrakt: FDV; 08_Status: S2; 06_Omrade: TG; 03_Ansvar: T20100; 02_Prosjekt: 72101; 05_ID-nummer: +TO=444.001-IB1109; ID-nummer2: +TO=444.001-IB1109; 01_Lufthavnkode: ENGM
ePset_Simplebim - Assembly Level: Leaf
Pset_LightFixtureTypeCommon - TotalWattage: 58 W
ePset_LocationTool - Splitting: ORIGINAL
Pset_ElectricalDeviceCommon - NumberOfPoles: 1; ElectricalDeviceNominalPower: 58 W; NominalVoltage: 230
Group: Belysningsutstyr
Name | Circuit
SKA 118 | 2
SKA 118 | 6
SKA 118 | 4

# IfcFlowTerminal: SKA 158 (4)
In: Nivå D + 1,2
Type - Description: Batten luminaire for T8 lamps.
Pset_ElectricalDeviceCommon - NumberOfPoles: 1; ElectricalDeviceNominalPower: 54 W; NominalVoltage: 230
AVINOR - 07_Fase: F90; 04_Kontrakt: FDV; 08_Status: S2; 06_Omrade: TG; 03_Ansvar: T20100; 02_Prosjekt: 72101; 05_ID-nummer: +TO=444.001-IB1109; ID-nummer2: +TO=444.001-IB1109; 01_Lufthavnkode: ENGM
Pset_LightFixtureTypeCommon - TotalWattage: 54 W
ePset_Simplebim - Assembly Level: Leaf
ePset_LocationTool - Splitting: ORIGINAL
MagiCAD Pset_Device - System code: 442; Manufacturer: Glamox; Length [mm]: 0 mm; Width [mm]: 0 mm; Height [mm]: 0 mm; User code: IB1109
Group: Belysningsutstyr

# IfcFlowTerminal: SP-15-K80-68DGR-STD (13)
Type - Description: Spray, pendent installation, STD, K=80
MagiCAD Pset_Sprinkler - User Code: UZ03T; NationalCode: RS1.3000121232; Product code: SP-15-K80-68DGR-STD; Description: Spray, pendent installation, STD, K=80; Manufacturer: General; Nominal Release Temperature [°C]: 68; KFactor: 80
ePset_Simplebim - Assembly Level: Leaf
ePset_LocationTool - Splitting: ORIGINAL
Name | In | Group
10 x SP-15-K80-68DGR-STD | Nivå F - 0,7 m | +TG=332.003 (46)
2 x SP-15-K80-68DGR-STD | Nivå F - 0,7 m | +TG=332.003 (2)
SP-15-K80-68DGR-STD | Nivå D + 1,2 m | +TG=332.002

# IfcFlowTerminal: SP-15-K80-68DGR-STD-HIMLING (23)
In: Nivå F - 0,7 m
Type - Description: Spray, pendent installation, STD, K=80
MagiCAD Pset_Sprinkler - User Code: HIMLING; Product code: SP-15-K80-68DGR-STD; Description: Spray, pendent installation, STD, K=80; Manufacturer: General; Nominal Release Temperature [°C]: 68; KFactor: 80
ePset_LocationTool - Splitting: ORIGINAL
ePset_Simplebim - Assembly Level: Leaf
Name | Group
SP-15-K80-68DGR-STD-HIMLING | +TG=332.003 (73)
12 x SP-15-K80-68DGR-STD-HIMLING | +TG=332.003 (2)
SP-15-K80-68DGR-STD-HIMLING | +TG=332.003 (69)
SP-15-K80-68DGR-STD-HIMLING | +TG=332.003 (68)
SP-15-K80-68DGR-STD-HIMLING | +TG=332.003 (67)
SP-15-K80-68DGR-STD-HIMLING | +TG=332.003 (66)
SP-15-K80-68DGR-STD-HIMLING | +TG=332.003 (65)
SP-15-K80-68DGR-STD-HIMLING | +TG=332.003 (64)
SP-15-K80-68DGR-STD-HIMLING | +TG=332.003 (63)
SP-15-K80-68DGR-STD-HIMLING | +TG=332.003 (54)
SP-15-K80-68DGR-STD-HIMLING | +TG=332.003 (53)
SP-15-K80-68DGR-STD-HIMLING | +TG=332.003 (47)

# IfcFlowTerminal: SP-15-K80-68DGR-STD-NEDOVER (22)
In: Nivå D + 1,2 m
Type - Description: Spray, pendent installation, STD, K=80
ePset_Simplebim - Assembly Level: Leaf
ePset_LocationTool - Splitting: ORIGINAL
MagiCAD Pset_Sprinkler - Product code: SP-15-K80-68DGR-STD-N; NationalCode: RS1.3000121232; Description: Spray, pendent installation, STD, K=80; Manufacturer: General; Nominal Release Temperature [°C]: 68; KFactor: 80; User Code: UZ03TN
Name | Group
SP-15-K80-68DGR-STD-NEDOVER | +TG=332.002
16 x SP-15-K80-68DGR-STD-NEDOVER | +TG=332.002 (1) (2)
2 x SP-15-K80-68DGR-STD-NEDOVER | +TG=332.003 (10)
3 x SP-15-K80-68DGR-STD-NEDOVER

# IfcFlowTerminal: SP-15-K80-68DGR-STD-STÅENDE (2)
In: Nivå F - 0,7 m
Type - Description: Spray, pendent installation, STD, K=80
MagiCAD Pset_Sprinkler - User Code: UZ03T; NationalCode: RS1.3000121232; Product code: SP-15-K80-68DGR-STD; Description: Spray, pendent installation, STD, K=80; Manufacturer: General; Nominal Release Temperature [°C]: 68; KFactor: 80
ePset_LocationTool - Splitting: ORIGINAL
ePset_Simplebim - Assembly Level: Leaf
Group: +TG=332.003 (2)

# IfcFlowTerminal: SPHERICAL-VERTICAL-16 (2)
In: Nivå F
Type - Description: IP66 fitting with recyclable polycarbonate luminaire housing.
AVINOR - 07_Fase: F90; 04_Kontrakt: FDV; 08_Status: S2; ID-nummer2: +TO=446.001-IB2120; 05_ID-nummer: +TO=446.001-IB2120; 06_Omrade: TG; 03_Ansvar: T20100; 02_Prosjekt: 72101; 01_Lufthavnkode: ENGM
ePset_Simplebim - Assembly Level: Leaf
Pset_LightFixtureTypeCommon - TotalWattage: 0 W
ePset_LocationTool - Splitting: ORIGINAL
MagiCAD Pset_Device - System code: 442; Switchboard: +TG=433.055; Length [mm]: 0 mm; Width [mm]: 0 mm; Height [mm]: 0 mm; User code: IB2120; Manufacturer: General; Circuit: 16
Pset_ElectricalDeviceCommon - ElectricalDeviceNominalPower: 0 W; NumberOfPoles: 1; NominalVoltage: 230
Group: Belysningsutstyr

# IfcFlowTerminal: TLK-B-160/K
In: Nivå F - 0,7 m
Type - Description: ATD for wall mounting
Classification: VE1.12372 Not defined (NS3420); Group: +TG=360.021-1 TL
MagiCAD Pset_AirTerminal - Description: ATD for wall mounting; User Code: AS001T; Manufacturer: TROX Auranor; ProductCode: TLK-B-160/K; dpTot_SizingFlow_Pa: 0 kPa; qv_SizingFlow_ms: 0 m/s; NationalCode: VE1.12372; qv_SizingFlow_ls: 69.444 m3/s
ePset_LocationTool - Splitting: ORIGINAL
ePset_Simplebim - Assembly Level: Leaf

# IfcFlowTerminal: V3617DRYK5.6STD68 (2)
In: Nivå F - 0,7 m
Type - Description: Firelock V3617DRY, SSP, Pendent, STD, K=81, 68°C
MagiCAD Pset_Sprinkler - Manufacturer: Victaulic; Nominal Release Temperature [°C]: 68; KFactor: 81; User Code: DP01; Product code: V3617DRYK5.6STD68; Description: Firelock V3617DRY, SSP, Pendent, STD, K=81, 68°C
ePset_LocationTool - Splitting: ORIGINAL
ePset_Simplebim - Assembly Level: Leaf
Group: +TG=332.003 (12)

# IfcFlowTerminal: ZUMTOBEL LFE E LED4400-830 M600Q (6)
In: Nivå F
Type - Description: Recessed mounting in ventilated or unventilated susp. ceiling.
MagiCAD Pset_Device - System code: 442; User code: IB0002; National code: 42185182; Manufacturer: Fagerhult; Length [mm]: 0 mm; P1: -UP; Height [mm]: 92 mm; Width [mm]: 599 mm; Product code: ZUMTOBEL MLevo EL LED3600-830 M600Q
Pset_LightFixtureTypeCommon - TotalWattage: 29 W
Pset_ElectricalDeviceCommon - IP_Code: IP20; NumberOfPoles: 1; ElectricalDeviceNominalPower: 29 W; NominalVoltage: 230
ePset_Simplebim - Assembly Level: Leaf
AVINOR - 08_Status: S4; 04_Kontrakt: FDV; 05_ID-nummer: +TG=444.001-IB0002; ID-nummer2: +TG=444.001-IB0002; 07_Fase: A; 06_Omrade: TG; 03_Ansvar: T20100; 02_Prosjekt: 72101; 01_Lufthavnkode: ENGM
ePset_LocationTool - Splitting: ORIGINAL
Group: Belysningsutstyr

# IfcFlowTreatmentDevice: LKR-160-600
In: Nivå F
Type - Description: Circular sound attenuator.; PredefinedType: ROUND
MagiCAD Pset_Silencer - ProductCode: LKR-160-600; User Code: LKR-600; Manufacturer: TROX Auranor; Description: Circular sound attenuator.; qv_SizingFlow_ls: 0 m3/s; pTot_SizingFlow_Pa: 0 kPa; dpTot_SizingFlow_Pa: 0 kPa
ePset_Simplebim - Assembly Level: Leaf
ePset_LocationTool - Splitting: ORIGINAL
Group: +TG=360.021-22 A

# IfcFlowTreatmentDevice: SLCU 160 600 50 (2)
In: Nivå F - 0,7 m
Type - Description: Circular straight silencer; PredefinedType: ROUND
Classification: VB2.143122 Not defined (NS3420); Group: +TG=360.001 A
MagiCAD Pset_Silencer - Description: Circular straight silencer; User Code: QL02T; qv_SizingFlow_ls: 0 m3/s; pTot_SizingFlow_Pa: 0 kPa; dpTot_SizingFlow_Pa: 0 kPa; ProductCode: SLCU 160 600 50; NationalCode: VB2.143122; Manufacturer: Air Duct System
ePset_LocationTool - Splitting: ORIGINAL
ePset_Simplebim - Assembly Level: Leaf

# IfcFurnishingElement: A278 - brannskap1:A278 - Brannskap - eksisterende 840 x 840 x 150 mm, A278 - brannskap1:A278 - Brannskap - eksisterende 840 x 840 x 150 mm:46840283
In: Nivå F - 0,7 m
Type - Material: <Unnamed>
AVINOR - 08_Status: S4; 07_Fase: F90; 03_Ansvar: FDV; 06_Omrade: TG; 02_Prosjekt: T20100; 01_Lufthavnkode: ENGM
ePset_LocationTool - Splitting: ORIGINAL
Pset_QuantityTakeOff - Reference: A278 - Brannskap - eksisterende 840 x 840 x 150 mm
ePset_Simplebim - Assembly Level: Leaf

# IfcGroup: Model Group:pylon 2430, Model Group:pylon 2430 (members excluded):59105865
Group: Model Group:A162446 - Utvidelse eksisterende Kiosk (members excluded):59114857

# IfcMember: L Corner Mullion:A233 - Sprosse - 20 x 100 mm (58)
In: Nivå F - 0,7 m
Type - PredefinedType: MULLION; Material: Metal - Steel
AVINOR - 08_Status: S4; 07_Fase: F90; 03_Ansvar: FDV; 06_Omrade: TG; 02_Prosjekt: T20100; 01_Lufthavnkode: ENGM
ePset_SimplebimBasicQuantities - Width (Simplebim): 110 mm; Length (Simplebim): 110 mm
Pset_QuantityTakeOff - Reference: A233 - Sprosse - 20 x 100 mm
ePset_LocationTool - Splitting: ORIGINAL
ePset_Simplebim - Assembly Level: Leaf
Pset_MemberCommon - Reference: A233 - Sprosse - 20 x 100 mm; IsExternal: no
Name (L Corner Mullion:A233 - Sprosse - 20 x 100 mm:...) | Volume, net (Simplebim) (m3) | Height (Simplebim) (mm) = Span (mm) | Weight, as steel (Simplebim) (kg) | Area, sides, net (Simplebim) (m2)
50238666 | 0.00442 | 1105 | 34.697 | 0.4942
50238667 | 0.00018 | 45 | 1.413 | 0.0278
50238669 | 0.0006 | 150 | 4.71 | 0.074
50238674 | 0.00022 | 55 | 1.727 | 0.0322
50238675 | 0.00442 | 1105 | 34.697 | 0.4942
50238677 | 0.0006 | 150 | 4.71 | 0.074
50238726 | 0.00018 | 45 | 1.413 | 0.0278
50238727 | 0.00022 | 55 | 1.727 | 0.0322
50238734 | 0.00018 | 45 | 1.413 | 0.0278
50238735 | 0.00022 | 55 | 1.727 | 0.0322
50238742 | 0.00018 | 45 | 1.413 | 0.0278
50238743 | 0.00022 | 55 | 1.727 | 0.0322
50238750 | 0.00022 | 55 | 1.727 | 0.0322
50238751 | 0.00018 | 45 | 1.413 | 0.0278
50238758 | 0.00018 | 45 | 1.413 | 0.0278
50238759 | 0.00022 | 55 | 1.727 | 0.0322
50238766 | 0.00022 | 55 | 1.727 | 0.0322
50238767 | 0.00018 | 45 | 1.413 | 0.0278
50238774 | 0.00018 | 45 | 1.413 | 0.0278
50238775 | 0.00022 | 55 | 1.727 | 0.0322
50238782 | 0.00022 | 55 | 1.727 | 0.0322
50238783 | 0.00018 | 45 | 1.413 | 0.0278
50238790 | 0.00018 | 45 | 1.413 | 0.0278
50238791 | 0.00022 | 55 | 1.727 | 0.0322
50238798 | 0.00022 | 55 | 1.727 | 0.0322
50238799 | 0.00018 | 45 | 1.413 | 0.0278
50238806 | 0.00018 | 45 | 1.413 | 0.0278
50238807 | 0.00022 | 55 | 1.727 | 0.0322
50238814 | 0.00022 | 55 | 1.727 | 0.0322
50238815 | 0.00018 | 45 | 1.413 | 0.0278
50238822 | 0.00022 | 55 | 1.727 | 0.0322
50238823 | 0.00018 | 45 | 1.413 | 0.0278
50238830 | 0.00018 | 45 | 1.413 | 0.0278
50238831 | 0.00022 | 55 | 1.727 | 0.0322
50238838 | 0.00022 | 55 | 1.727 | 0.0322
50238839 | 0.00018 | 45 | 1.413 | 0.0278
50238846 | 0.00018 | 45 | 1.413 | 0.0278
50238847 | 0.00022 | 55 | 1.727 | 0.0322
50238854 | 0.00022 | 55 | 1.727 | 0.0322
50238855 | 0.00018 | 45 | 1.413 | 0.0278
50238862 | 0.00018 | 45 | 1.413 | 0.0278
50238863 | 0.00022 | 55 | 1.727 | 0.0322
50238870 | 0.00022 | 55 | 1.727 | 0.0322
50238871 | 0.00018 | 45 | 1.413 | 0.0278
50238878 | 0.00022 | 55 | 1.727 | 0.0322
50238879 | 0.00018 | 45 | 1.413 | 0.0278
50238886 | 0.00022 | 55 | 1.727 | 0.0322
50238887 | 0.00018 | 45 | 1.413 | 0.0278
50238894 | 0.00022 | 55 | 1.727 | 0.0322
50238895 | 0.00018 | 45 | 1.413 | 0.0278
50238902 | 0.00022 | 55 | 1.727 | 0.0322
50238903 | 0.00018 | 45 | 1.413 | 0.0278
50238910 | 0.00018 | 45 | 1.413 | 0.0278
50238911 | 0.00022 | 55 | 1.727 | 0.0322
50238918 | 0.00018 | 45 | 1.413 | 0.0278
50238919 | 0.00018 | 45 | 1.413 | 0.0278
50238926 | 0.00018 | 45 | 1.413 | 0.0278
50238927 | 0.00022 | 55 | 1.727 | 0.0322

# IfcMember: Rectangular Mullion:A233 - Sprosse - 165(post)+50(dekkprofil) x 50 mm (28)
Type - PredefinedType: MULLION; Material: T2_Metal_Aluminium
Pset_QuantityTakeOff - Reference: A233 - Sprosse - 165(post)+50(dekkprofil) x 50 mm
AVINOR - 08_Status: S4; 07_Fase: F90; 03_Ansvar: FDV; 06_Omrade: TG; 02_Prosjekt: T20100; 01_Lufthavnkode: ENGM
Pset_MemberCommon - IsExternal: yes; Reference: A233 - Sprosse - 165(post)+50(dekkprofil) x 50 mm
ePset_SimplebimBasicQuantities - Width (Simplebim): 215 mm; Height (Simplebim): 50 mm
ePset_Simplebim - Assembly Level: Leaf
ePset_LocationTool - Splitting: ORIGINAL
Name (Rectangular Mullion:A233 - Sprosse - 165(post)+50(dekkprofil) x 50 mm:...) | In | Span (mm) = Length (Simplebim) (mm) | Volume, net (Simplebim) (m3) | Area, sides, net (Simplebim) (m2) | Weight, as steel (Simplebim) (kg) | Group
6489728 | Nivå D + 1,2 m | 2205 | 0.0237038 | 1.19015 | 186.074
48691437 | Nivå F - 0,7 m | 2905 | 0.0312287 | 1.56115 | 245.146 | Model Group:A230 - eksisterende fasadesystem i pir_SØR_9000_HEL (members excluded):48691507
48691442 | Nivå F - 0,7 m | 2905 | 0.0312287 | 1.56115 | 245.146 | Model Group:A230 - eksisterende fasadesystem i pir_SØR_9000_HEL (members excluded):48691507
48691446 | Nivå F - 0,7 m | 3000 | 0.03225 | 1.6115 | 253.162 | Model Group:A230 - eksisterende fasadesystem i pir_SØR_9000_HEL (members excluded):48691507
48691469 | Nivå F - 0,7 m | 2880 | 0.03096 | 1.5479 | 243.036 | Model Group:A230 - eksisterende fasadesystem i pir_SØR_9000_HEL (members excluded):48691507
48691470 | Nivå F - 0,7 m | 2880 | 0.03096 | 1.5479 | 243.036 | Model Group:A230 - eksisterende fasadesystem i pir_SØR_9000_HEL (members excluded):48691507
48691471 | Nivå F - 0,7 m | 2950 | 0.0317125 | 1.585 | 248.943 | Model Group:A230 - eksisterende fasadesystem i pir_SØR_9000_HEL (members excluded):48691507
48691481 | Nivå F - 0,7 m | 2880 | 0.03096 | 1.5479 | 243.036 | Model Group:A230 - eksisterende fasadesystem i pir_SØR_9000_HEL (members excluded):48691507
48691482 | Nivå F - 0,7 m | 2880 | 0.03096 | 1.5479 | 243.036 | Model Group:A230 - eksisterende fasadesystem i pir_SØR_9000_HEL (members excluded):48691507
48691483 | Nivå F - 0,7 m | 2950 | 0.0317125 | 1.585 | 248.943 | Model Group:A230 - eksisterende fasadesystem i pir_SØR_9000_HEL (members excluded):48691507
49613560 | Nivå F - 0,7 m | 2905 | 0.0312287 | 1.56115 | 245.146 | Model Group:A230 - eksisterende fasadesystem i pir_SØR_9000_HEL (members excluded):49613630
49613565 | Nivå F - 0,7 m | 2905 | 0.0312287 | 1.56115 | 245.146 | Model Group:A230 - eksisterende fasadesystem i pir_SØR_9000_HEL (members excluded):49613630
49613569 | Nivå F - 0,7 m | 3000 | 0.03225 | 1.6115 | 253.162 | Model Group:A230 - eksisterende fasadesystem i pir_SØR_9000_HEL (members excluded):49613630
49613592 | Nivå F - 0,7 m | 2880 | 0.03096 | 1.5479 | 243.036 | Model Group:A230 - eksisterende fasadesystem i pir_SØR_9000_HEL (members excluded):49613630
49613593 | Nivå F - 0,7 m | 2880 | 0.03096 | 1.5479 | 243.036 | Model Group:A230 - eksisterende fasadesystem i pir_SØR_9000_HEL (members excluded):49613630
49613594 | Nivå F - 0,7 m | 2950 | 0.0317125 | 1.585 | 248.943 | Model Group:A230 - eksisterende fasadesystem i pir_SØR_9000_HEL (members excluded):49613630
49613604 | Nivå F - 0,7 m | 2880 | 0.03096 | 1.5479 | 243.036 | Model Group:A230 - eksisterende fasadesystem i pir_SØR_9000_HEL (members excluded):49613630
49613605 | Nivå F - 0,7 m | 2880 | 0.03096 | 1.5479 | 243.036 | Model Group:A230 - eksisterende fasadesystem i pir_SØR_9000_HEL (members excluded):49613630
49613606 | Nivå F - 0,7 m | 2950 | 0.0317125 | 1.585 | 248.943 | Model Group:A230 - eksisterende fasadesystem i pir_SØR_9000_HEL (members excluded):49613630
49613695 | Nivå F - 0,7 m | 2903.77 | 0.0312156 | 1.5605 | 245.042 | Model Group:A230 - eksisterende fasadesystem i pir_SØR_9000_HEL (members excluded):49613765
49613700 | Nivå F - 0,7 m | 2905 | 0.0312287 | 1.56115 | 245.146 | Model Group:A230 - eksisterende fasadesystem i pir_SØR_9000_HEL (members excluded):49613765
49613704 | Nivå F - 0,7 m | 3000 | 0.03225 | 1.6115 | 253.162 | Model Group:A230 - eksisterende fasadesystem i pir_SØR_9000_HEL (members excluded):49613765
49613727 | Nivå F - 0,7 m | 2878.77 | 0.0309468 | 1.54725 | 242.933 | Model Group:A230 - eksisterende fasadesystem i pir_SØR_9000_HEL (members excluded):49613765
49613728 | Nivå F - 0,7 m | 2880 | 0.03096 | 1.5479 | 243.036 | Model Group:A230 - eksisterende fasadesystem i pir_SØR_9000_HEL (members excluded):49613765
49613729 | Nivå F - 0,7 m | 2950 | 0.0317125 | 1.585 | 248.943 | Model Group:A230 - eksisterende fasadesystem i pir_SØR_9000_HEL (members excluded):49613765
49613739 | Nivå F - 0,7 m | 2878.77 | 0.0309468 | 1.54725 | 242.933 | Model Group:A230 - eksisterende fasadesystem i pir_SØR_9000_HEL (members excluded):49613765
49613740 | Nivå F - 0,7 m | 2880 | 0.03096 | 1.5479 | 243.036 | Model Group:A230 - eksisterende fasadesystem i pir_SØR_9000_HEL (members excluded):49613765
49613741 | Nivå F - 0,7 m | 2950 | 0.0317125 | 1.585 | 248.943 | Model Group:A230 - eksisterende fasadesystem i pir_SØR_9000_HEL (members excluded):49613765

# IfcMember: Rectangular Mullion:A233 - Sprosse - 165(post)+70(dekkprofil) x 50 mm (24)
In: Nivå F - 0,7 m
Type - PredefinedType: MULLION; Material: T2_Metal_Aluminium
AVINOR - 08_Status: S4; 07_Fase: F90; 03_Ansvar: FDV; 06_Omrade: TG; 02_Prosjekt: T20100; 01_Lufthavnkode: ENGM
ePset_SimplebimBasicQuantities - Length (Simplebim): 235 mm; Width (Simplebim): 50 mm
Pset_QuantityTakeOff - Reference: A233 - Sprosse - 165(post)+70(dekkprofil) x 50 mm
ePset_LocationTool - Splitting: ORIGINAL
ePset_Simplebim - Assembly Level: Leaf
Pset_MemberCommon - IsExternal: yes; Reference: A233 - Sprosse - 165(post)+70(dekkprofil) x 50 mm
Name (Rectangular Mullion:A233 - Sprosse - 165(post)+70(dekkprofil) x 50 mm:...) | Height (Simplebim) (mm) = Span (mm) | Weight, as steel (Simplebim) (kg) | Area, sides, net (Simplebim) (m2) | Volume, net (Simplebim) (m3) | Group
48691448 | 2225 | 205.228 | 1.29175 | 0.0261437 | Model Group:A230 - eksisterende fasadesystem i pir_SØR_9000_HEL (members excluded):48691507
48691449 | 2225 | 205.228 | 1.29175 | 0.0261437 | Model Group:A230 - eksisterende fasadesystem i pir_SØR_9000_HEL (members excluded):48691507
48691455 | 1000 | 92.2375 | 0.5935 | 0.01175 | Model Group:A230 - eksisterende fasadesystem i pir_SØR_9000_HEL (members excluded):48691507
48691477 | 1000 | 92.2375 | 0.5935 | 0.01175 | Model Group:A230 - eksisterende fasadesystem i pir_SØR_9000_HEL (members excluded):48691507
48691478 | 1000 | 92.2375 | 0.5935 | 0.01175 | Model Group:A230 - eksisterende fasadesystem i pir_SØR_9000_HEL (members excluded):48691507
48691479 | 1000 | 92.2375 | 0.5935 | 0.01175 | Model Group:A230 - eksisterende fasadesystem i pir_SØR_9000_HEL (members excluded):48691507
48691480 | 2275 | 209.84 | 1.32025 | 0.0267312 | Model Group:A230 - eksisterende fasadesystem i pir_SØR_9000_HEL (members excluded):48691507
48691512 | 2275 | 209.84 | 1.32025 | 0.0267312 | Model Group:A230 - eksisterende fasadesystem i pir_SØR_9000_HEL (members excluded):48691507
49613571 | 2225 | 205.228 | 1.29175 | 0.0261437 | Model Group:A230 - eksisterende fasadesystem i pir_SØR_9000_HEL (members excluded):49613630
49613572 | 2225 | 205.228 | 1.29175 | 0.0261437 | Model Group:A230 - eksisterende fasadesystem i pir_SØR_9000_HEL (members excluded):49613630
49613578 | 1000 | 92.2375 | 0.5935 | 0.01175 | Model Group:A230 - eksisterende fasadesystem i pir_SØR_9000_HEL (members excluded):49613630
49613600 | 1000 | 92.2375 | 0.5935 | 0.01175 | Model Group:A230 - eksisterende fasadesystem i pir_SØR_9000_HEL (members excluded):49613630
49613601 | 1000 | 92.2375 | 0.5935 | 0.01175 | Model Group:A230 - eksisterende fasadesystem i pir_SØR_9000_HEL (members excluded):49613630
49613602 | 1000 | 92.2375 | 0.5935 | 0.01175 | Model Group:A230 - eksisterende fasadesystem i pir_SØR_9000_HEL (members excluded):49613630
49613603 | 2275 | 209.84 | 1.32025 | 0.0267312 | Model Group:A230 - eksisterende fasadesystem i pir_SØR_9000_HEL (members excluded):49613630
49613635 | 2275 | 209.84 | 1.32025 | 0.0267312 | Model Group:A230 - eksisterende fasadesystem i pir_SØR_9000_HEL (members excluded):49613630
49613706 | 2225 | 205.228 | 1.29175 | 0.0261437 | Model Group:A230 - eksisterende fasadesystem i pir_SØR_9000_HEL (members excluded):49613765
49613707 | 2225 | 205.228 | 1.29175 | 0.0261437 | Model Group:A230 - eksisterende fasadesystem i pir_SØR_9000_HEL (members excluded):49613765
49613713 | 1000 | 92.2375 | 0.5935 | 0.01175 | Model Group:A230 - eksisterende fasadesystem i pir_SØR_9000_HEL (members excluded):49613765
49613735 | 1000 | 92.2375 | 0.5935 | 0.01175 | Model Group:A230 - eksisterende fasadesystem i pir_SØR_9000_HEL (members excluded):49613765
49613736 | 1000 | 92.2375 | 0.5935 | 0.01175 | Model Group:A230 - eksisterende fasadesystem i pir_SØR_9000_HEL (members excluded):49613765
49613737 | 1000 | 92.2375 | 0.5935 | 0.01175 | Model Group:A230 - eksisterende fasadesystem i pir_SØR_9000_HEL (members excluded):49613765
49613738 | 2275 | 209.84 | 1.32025 | 0.0267312 | Model Group:A230 - eksisterende fasadesystem i pir_SØR_9000_HEL (members excluded):49613765
49613770 | 2275 | 209.84 | 1.32025 | 0.0267312 | Model Group:A230 - eksisterende fasadesystem i pir_SØR_9000_HEL (members excluded):49613765

# IfcMember: Rectangular Mullion:A243 - UTGAAR - Innvendig - 50 x 100 mm (8)
In: Nivå F - 0,7 m
Type - PredefinedType: MULLION; Material: Metal - Aluminium
AVINOR - 08_Status: S4; 07_Fase: F90; 02_Prosjekt: A162446; 03_Ansvar: 182412; 06_Omrade: TG; 01_Lufthavnkode: ENGM
ePset_LocationTool - Splitting: ORIGINAL
Pset_MemberCommon - IsExternal: no; Reference: A243 - UTGAAR - Innvendig - 50 x 100 mm
Pset_QuantityTakeOff - Reference: A243 - UTGAAR - Innvendig - 50 x 100 mm
ePset_Simplebim - Assembly Level: Leaf
Group: Model Group:A162446 - Utvidelse eksisterende Kiosk (members excluded):59114857
Name (Rectangular Mullion:A243 - UTGAAR - Innvendig - 50 x 100 mm:...) | Weight, as steel (Simplebim) (kg) | Area, sides, net (Simplebim) (m2) | Height (Simplebim) (mm) | Width (Simplebim) (mm) | Volume, net (Simplebim) (m3) | Length (Simplebim) (mm) | Span (mm)
59105844 | 48.4644 | 0.380429 | 50 | 100 | 0.00617381 | 1234.76 | 1234.76
59105845 | 46.7075 | 0.367 | 50 | 100 | 0.00595 | 1190 | 1190
59105846 | 5.8875 | 0.055 | 150 | 50 | 0.00075 | 100 | 150
59105847 | 58.875 | 0.46 | 1500 | 50 | 0.0075 | 100 | 1500
59105851 | 58.875 | 0.46 | 1500 | 50 | 0.0075 | 100 | 1500
59105852 | 41.2125 | 0.325 | 1050 | 50 | 0.00525 | 100 | 1050
59105869 | 41.2125 | 0.325 | 1050 | 50 | 0.00525 | 100 | 1050
59105870 | 5.8875 | 0.055 | 150 | 50 | 0.00075 | 100 | 150

# IfcOpeningElement: Opening (30)
Name | In
A20 - Slagdør - Enkel:A243 - DI_LTO - 0990 x 2240 mm:2513270:1 | Nivå F - 0,7 m
A20 - Slagdør - Enkel:A243 - DI_LTO - 1090 x 2090 mm:2513354:1 | Nivå F - 0,7 m
A20 - Slagdør - Enkel:A243 - DI_LTO - 0990 x 2090 mm:2513423:1 | Nivå F - 0,7 m
A20 - Slagdør - Enkel:A243 - DI_LTO - 0990 x 2240 mm:2513481:1 | Nivå F - 0,7 m
A20 - Slagdør - Enkel:A243 - DI_LTO - 0690 x 2240 mm:2513532:1 | Nivå F - 0,7 m
A20 - Slagdør - Enkel:A243 - DI_LTO - 0690 x 2240 mm:2513602:1 | Nivå F - 0,7 m
A20 - Slagdør - Enkel:A243 - DI_LTO - 0690 x 2240 mm:2513699:1 | Nivå F - 0,7 m
A20 - Slagdør - Enkel:A243 - DI_LTO - 0690 x 2240 mm:2513700:1 | Nivå F - 0,7 m
A20 - Slagdør - Enkel:A243 - DI_LTO - 0690 x 2240 mm:2513722:1 | Nivå F - 0,7 m
A20 - Dørkarm - uten dørfløy:A243 - veggåpning med karm - 0890 x 2240 mm:46950982:1 | Nivå F - 0,7 m
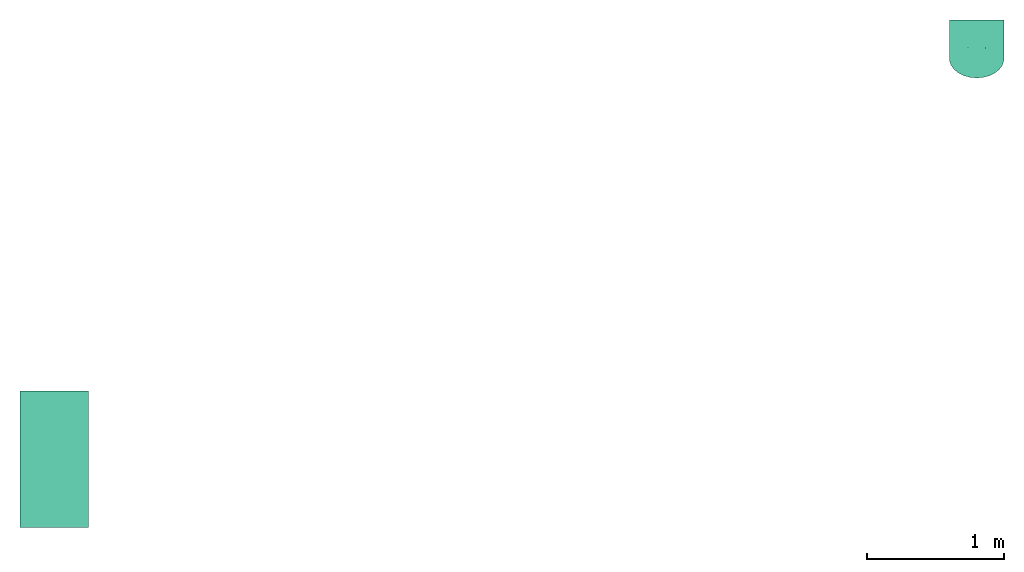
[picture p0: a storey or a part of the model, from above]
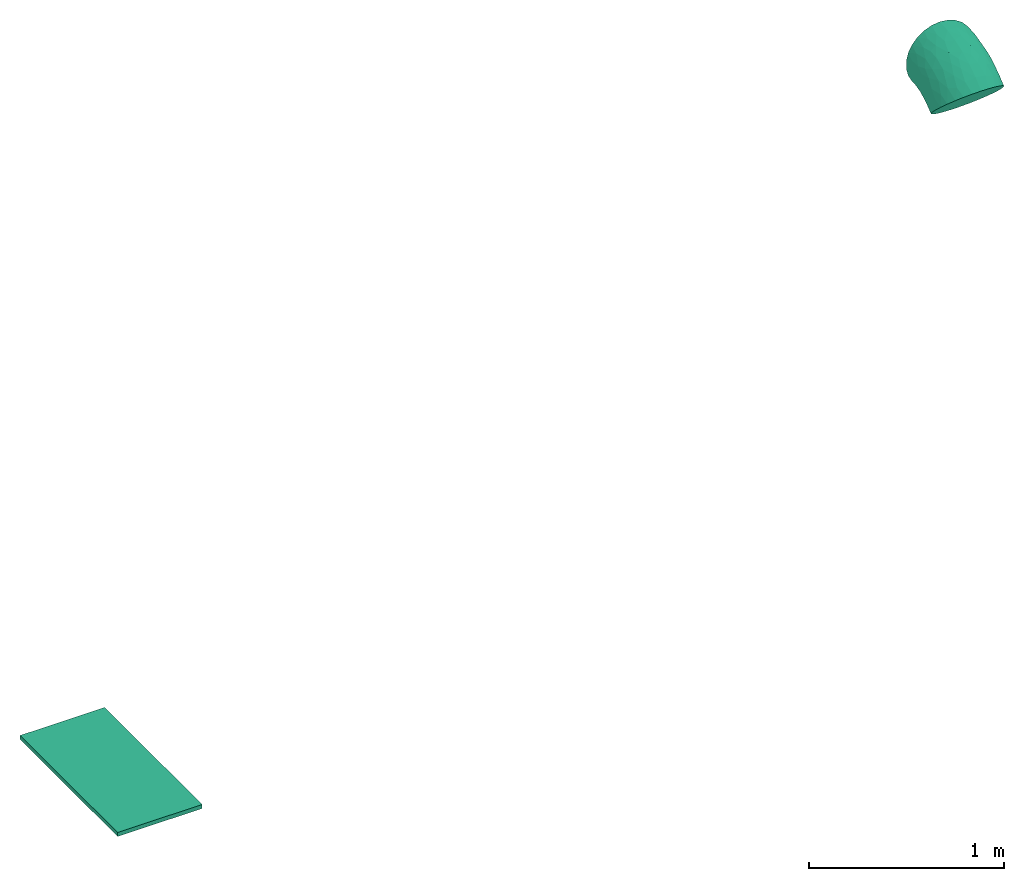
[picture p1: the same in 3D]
Properties of the parts of a building model (IFC2X3), part 10 of 11

# IfcOpeningElement: Opening (30)
Name | In
A20 - Slagdør - Enkel:A243 - DI_SSO - 0590 x 0985 mm:49723437:1 | Nivå F - 0,7 m
A20 - Slagdør - Enkel:A243 - DI_SSO - 0590 x 0985 mm:49723705:1 | Nivå F - 0,7 m
A20 - Slagdør - Enkel:A243 - DI_LTO - 0890 x 2240 mm:53693265:1 | Nivå F - 0,7 m
single_panel_sliding_door_whafele_hrdw_parametric_2015:single_panel_sliding_door_whafele_hrdw_parametric_7m:59105930:1 | Nivå F - 0,7 m
single_panel_sliding_door_whafele_hrdw_parametric_2015:single_panel_sliding_door_whafele_hrdw_parametric_7m:59106087:1 | Nivå F - 0,7 m
Floor:A254 - Gulvoppbygging m_f.o - 70mm - tre:49951745:2
Basic Wall:A241 - Eksisterende - GRVR-30:2512780 | Nivå F
Basic Wall:A241 - Eksisterende - GSVS-30:2512783 | Nivå F
Basic Wall:A241 - Eksisterende - GSVS-30:2512787 | Nivå F
Basic Wall:A241 - FSVF-100:2512799 | Nivå F
Basic Wall:A241 - FVF-100:2512800 | Nivå F
2 x Basic Wall:A241 - FSVF-100:49355532 | Nivå F
Basic Wall:A241 - SVS-75:53693264 | Nivå F
Basic Wall:A241 - V2:59105810 | Nivå F - 0,7 m | Group: Model Group:A162446 - Utvidelse eksisterende Kiosk (members excluded):59114857
Basic Wall:A241 - V2:59105810 | Nivå F | Group: Model Group:A162446 - Utvidelse eksisterende Kiosk (members excluded):59114857
Basic Wall:A241 - V2:59105834 | Nivå F - 0,7 m | Group: Model Group:A162446 - Utvidelse eksisterende Kiosk (members excluded):59114857
Basic Wall:A241 - V2:59105834 | Nivå F | Group: Model Group:A162446 - Utvidelse eksisterende Kiosk (members excluded):59114857
2 x Basic Wall:A241 - Eksisterende - GSVS-11:59105929 | Nivå F

# IfcPlate: Basic Wall:A234 - Blindfelt (eksisterende pir) (9)
In: Nivå F - 0,7 m
Type - PredefinedType: CURTAIN_PANEL; Material: _NSW Aluminium 10 mm, _NSW Luftspalte 25 mm, _NSW Luftspalte 45 mm, _NSW Isolasjon 115 mm, _NSW Aluminium 5 mm
AVINOR - 08_Status: S4; 07_Fase: F90; 03_Ansvar: FDV; 06_Omrade: TG; 02_Prosjekt: T20100; 01_Lufthavnkode: ENGM
ePset_LocationTool - Splitting: ORIGINAL
ePset_Simplebim - Assembly Level: Leaf
Pset_QuantityTakeOff - Reference: A234 - Blindfelt (eksisterende pir)
Pset_PlateCommon - IsExternal: yes; LoadBearing: no; Reference: A234 - Blindfelt (eksisterende pir)
Name (Basic Wall:A234 - Blindfelt (eksisterende pir):...) | Area, largest surface, net (Simplebim) (m2) | Volume, net (Simplebim) (m3) | Weight, as steel (Simplebim) (kg) | Group
52470100 | 0.6336 | 0.12672 | 994.752 | Model Group:A230 - eksisterende fasadesystem i pir_SØR_9000_HEL (members excluded):48691507
52470101 | 0.649 | 0.1298 | 1018.93 | Model Group:A230 - eksisterende fasadesystem i pir_SØR_9000_HEL (members excluded):48691507
52470102 | 0.6336 | 0.12672 | 994.752 | Model Group:A230 - eksisterende fasadesystem i pir_SØR_9000_HEL (members excluded):48691507
52470106 | 0.6336 | 0.12672 | 994.752 | Model Group:A230 - eksisterende fasadesystem i pir_SØR_9000_HEL (members excluded):49613630
52470107 | 0.649 | 0.1298 | 1018.93 | Model Group:A230 - eksisterende fasadesystem i pir_SØR_9000_HEL (members excluded):49613630
52470108 | 0.6336 | 0.12672 | 994.752 | Model Group:A230 - eksisterende fasadesystem i pir_SØR_9000_HEL (members excluded):49613630
52470112 | 0.633479 | 0.126696 | 994.562 | Model Group:A230 - eksisterende fasadesystem i pir_SØR_9000_HEL (members excluded):49613765
52470113 | 0.649 | 0.1298 | 1018.93 | Model Group:A230 - eksisterende fasadesystem i pir_SØR_9000_HEL (members excluded):49613765
52470114 | 0.6336 | 0.12672 | 994.752 | Model Group:A230 - eksisterende fasadesystem i pir_SØR_9000_HEL (members excluded):49613765

# IfcPlate: System Panel:A234 - Glass - 30 mm (15)
In: Nivå F - 0,7 m
Type - PredefinedType: CURTAIN_PANEL; Material: Glass (Avinor)
AVINOR - 08_Status: S4; 07_Fase: F90; 03_Ansvar: FDV; 06_Omrade: TG; 02_Prosjekt: T20100; 01_Lufthavnkode: ENGM
Pset_QuantityTakeOff - Reference: A234 - Glass - 30 mm
Pset_PlateCommon - Reference: A234 - Glass - 30 mm; IsExternal: yes
ePset_Simplebim - Assembly Level: Leaf
ePset_LocationTool - Splitting: ORIGINAL
Name (System Panel:A234 - Glass - 30 mm:...) | Volume, net (Simplebim) (m3) | Area, largest surface, net (Simplebim) (m2) | Weight, as steel (Simplebim) (kg) | Group
48691436 | 0.19008 | 6.336 | 1492.13 | Model Group:A230 - eksisterende fasadesystem i pir_SØR_9000_HEL (members excluded):48691507
48691445 | 0.1947 | 6.49 | 1528.39 | Model Group:A230 - eksisterende fasadesystem i pir_SØR_9000_HEL (members excluded):48691507
48691441 | 0.19008 | 6.336 | 1492.13 | Model Group:A230 - eksisterende fasadesystem i pir_SØR_9000_HEL (members excluded):48691507
48691475 | 0.084075 | 2.8025 | 659.989 | Model Group:A230 - eksisterende fasadesystem i pir_SØR_9000_HEL (members excluded):48691507
48691476 | 0.08208 | 2.736 | 644.328 | Model Group:A230 - eksisterende fasadesystem i pir_SØR_9000_HEL (members excluded):48691507
49613559 | 0.19008 | 6.336 | 1492.13 | Model Group:A230 - eksisterende fasadesystem i pir_SØR_9000_HEL (members excluded):49613630
49613568 | 0.1947 | 6.49 | 1528.39 | Model Group:A230 - eksisterende fasadesystem i pir_SØR_9000_HEL (members excluded):49613630
49613564 | 0.19008 | 6.336 | 1492.13 | Model Group:A230 - eksisterende fasadesystem i pir_SØR_9000_HEL (members excluded):49613630
49613598 | 0.084075 | 2.8025 | 659.989 | Model Group:A230 - eksisterende fasadesystem i pir_SØR_9000_HEL (members excluded):49613630
49613599 | 0.08208 | 2.736 | 644.328 | Model Group:A230 - eksisterende fasadesystem i pir_SØR_9000_HEL (members excluded):49613630
49613694 | 0.189999 | 6.33331 | 1491.49 | Model Group:A230 - eksisterende fasadesystem i pir_SØR_9000_HEL (members excluded):49613765
49613703 | 0.1947 | 6.49 | 1528.39 | Model Group:A230 - eksisterende fasadesystem i pir_SØR_9000_HEL (members excluded):49613765
49613699 | 0.19008 | 6.336 | 1492.13 | Model Group:A230 - eksisterende fasadesystem i pir_SØR_9000_HEL (members excluded):49613765
49613733 | 0.084075 | 2.8025 | 659.989 | Model Group:A230 - eksisterende fasadesystem i pir_SØR_9000_HEL (members excluded):49613765
49613734 | 0.08208 | 2.736 | 644.328 | Model Group:A230 - eksisterende fasadesystem i pir_SØR_9000_HEL (members excluded):49613765

# IfcPlate: System Panel:A245 - Glass - 10 mm (12)
In: Nivå F - 0,7 m
Type - PredefinedType: CURTAIN_PANEL; Material: Glass (Avinor)
AVINOR - 08_Status: S4; 07_Fase: F90; 06_Omrade: TG; 01_Lufthavnkode: ENGM
ePset_Simplebim - Assembly Level: Leaf
ePset_LocationTool - Splitting: ORIGINAL
Pset_QuantityTakeOff - Reference: A245 - Glass - 10 mm
Pset_PlateCommon - Reference: A245 - Glass - 10 mm
Name (System Panel:A245 - Glass - 10 mm:...) | 03_Ansvar | 02_Prosjekt | IsExternal | Area, largest surface, net (Simplebim) (m2) | Volume, net (Simplebim) (m3) | Weight, as steel (Simplebim) (kg) | Group
48691474 | FDV | T20100 | yes | 2.736 | 0.02736 | 214.776 | Model Group:A230 - eksisterende fasadesystem i pir_SØR_9000_HEL (members excluded):48691507
49613597 | FDV | T20100 | yes | 2.736 | 0.02736 | 214.776 | Model Group:A230 - eksisterende fasadesystem i pir_SØR_9000_HEL (members excluded):49613630
49613732 | FDV | T20100 | yes | 2.73484 | 0.0273484 | 214.685 | Model Group:A230 - eksisterende fasadesystem i pir_SØR_9000_HEL (members excluded):49613765
53692767 | FDV | T20100 | no | 0.312155 | 0.00312155 | 24.5042
53692773 | FDV | T20100 | no | 0.509235 | 0.00509235 | 39.975
53693267 | FDV | T20100 | no | 0.368255 | 0.00368255 | 28.9081
59106084 | 182412 | A162446 | no | 0.0102 | 0.00000210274 | 0.0165065 | Model Group:A162446 - Utvidelse eksisterende Kiosk (members excluded):59114857
59106089 | 182412 | A162446 | no | 2.856 | 0.02856 | 224.196 | Model Group:A162446 - Utvidelse eksisterende Kiosk (members excluded):59114857
59106090 | 182412 | A162446 | no | 2.856 | 0.02856 | 224.196 | Model Group:A162446 - Utvidelse eksisterende Kiosk (members excluded):59114857
59106091 | 182412 | A162446 | no | 1.56383 | 0.0156383 | 122.761 | Model Group:A162446 - Utvidelse eksisterende Kiosk (members excluded):59114857
59106092 | 182412 | A162446 | no | 0.408 | 0.00408 | 32.028 | Model Group:A162446 - Utvidelse eksisterende Kiosk (members excluded):59114857
59106093 | 182412 | A162446 | no | 1.8809 | 0.018809 | 147.651 | Model Group:A162446 - Utvidelse eksisterende Kiosk (members excluded):59114857

# IfcPlate: System Panel:A245 - Glass - 12 mm (3)
In: Nivå F - 0,7 m
Type - PredefinedType: CURTAIN_PANEL; Material: Glass (Avinor)
AVINOR - 08_Status: S4; 07_Fase: F90; 03_Ansvar: FDV; 06_Omrade: TG; 02_Prosjekt: T20100; 01_Lufthavnkode: ENGM
ePset_LocationTool - Splitting: RESULT
ePset_Simplebim - Assembly Level: Leaf
Pset_QuantityTakeOff - Reference: A245 - Glass - 12 mm
Pset_PlateCommon - Reference: A245 - Glass - 12 mm; IsExternal: no
Name (System Panel:A245 - Glass - 12 mm:...) | Volume, net (Simplebim) (m3) | Weight, as steel (Simplebim) (kg) | Area, largest surface, net (Simplebim) (m2)
49351544 | 0.109389 | 858.701 | 9.11572
49351546 | 0.0718219 | 563.802 | 5.98515
49351548 | 0.084349 | 662.139 | 7.02908

# IfcPlate: System Panel:A245 - Glass - 6 mm (18)
In: Nivå F - 0,7 m
Type - PredefinedType: CURTAIN_PANEL; Material: Glass (Avinor)
AVINOR - 08_Status: S4; 07_Fase: F90; 03_Ansvar: FDV; 06_Omrade: TG; 02_Prosjekt: T20100; 01_Lufthavnkode: ENGM
Pset_QuantityTakeOff - Reference: A245 - Glass - 6 mm
Pset_PlateCommon - IsExternal: no; Reference: A245 - Glass - 6 mm
ePset_Simplebim - Assembly Level: Leaf
ePset_LocationTool - Splitting: ORIGINAL
Name (System Panel:A245 - Glass - 6 mm:...) | Volume, net (Simplebim) (m3) | Area, largest surface, net (Simplebim) (m2) | Weight, as steel (Simplebim) (kg)
49469458 | 0.00267794 | 0.446323 | 21.0218
49469460 | 0.0112682 | 1.87803 | 88.4552
49469462 | 0.00267794 | 0.446323 | 21.0218
49469464 | 0.00267794 | 0.446323 | 21.0218
49469466 | 0.00267794 | 0.446323 | 21.0218
50544381 | 0.00434808 | 0.72468 | 34.1324
50544383 | 0.00173694 | 0.28949 | 13.635
50544385 | 0.00504765 | 0.841275 | 39.6241
50544387 | 0.00729105 | 1.21517 | 57.2347
50544389 | 0.00738855 | 1.23142 | 58.0001
50544396 | 0.00504765 | 0.841275 | 39.6241
50544398 | 0.0117439 | 1.95732 | 92.1898
50544400 | 0.00316478 | 0.527463 | 24.8435
50544405 | 0.002739 | 0.4565 | 21.5011
50544407 | 0.00106488 | 0.17748 | 8.35931
50544409 | 0.00316478 | 0.527463 | 24.8435
50544414 | 0.002739 | 0.4565 | 21.5011
50544416 | 0.00106488 | 0.17748 | 8.35931

# IfcPlate: System Panel:A245 - KL-G00 - - - skal byttes manuelt (2)
In: Nivå F - 0,7 m
Type - PredefinedType: CURTAIN_PANEL; Material: Glasskledning, silketrykket
Pset_PlateCommon - Reference: A245 - KL-G00 - - - skal byttes manuelt; IsExternal: no
ePset_Simplebim - Assembly Level: Leaf
ePset_LocationTool - Splitting: ORIGINAL
Pset_QuantityTakeOff - Reference: A245 - KL-G00 - - - skal byttes manuelt
Group: Model Group:pylon 2430 (members excluded):59105865
Name (System Panel:A245 - KL-G00 - - - skal byttes manuelt:...) | Area, largest surface, net (Simplebim) (m2) | Volume, net (Simplebim) (m3) | Weight, as steel (Simplebim) (kg)
59105854 | 1.50417 | 0.0150417 | 118.077
59105858 | 1.34512 | 0.0134512 | 105.592

# IfcPlate: System Panel:A245 - KL-M00 - - - skal byttes manuelt (5)
In: Nivå F - 0,7 m
Type - PredefinedType: CURTAIN_PANEL; Material: Metal - Preget plate
ePset_LocationTool - Splitting: ORIGINAL
Pset_QuantityTakeOff - Reference: A245 - KL-M00 - - - skal byttes manuelt
Pset_PlateCommon - Reference: A245 - KL-M00 - - - skal byttes manuelt; IsExternal: no
ePset_Simplebim - Assembly Level: Leaf
Name (System Panel:A245 - KL-M00 - - - skal byttes manuelt:...) | Volume, net (Simplebim) (m3) | Weight, as steel (Simplebim) (kg) | Area, largest surface, net (Simplebim) (m2) | 08_Status | 07_Fase | 02_Prosjekt | 03_Ansvar | 06_Omrade | 01_Lufthavnkode | Group
59105833 | 0.065318 | 512.746 | 6.5318 | S4 | F90 | A162446 | 182412 | TG | ENGM | Model Group:A162446 - Utvidelse eksisterende Kiosk (members excluded):59114857
59105872 | 0.00185214 | 14.5393 | 0.185214 | S4 | F90 | A162446 | 182412 | TG | ENGM | Model Group:A162446 - Utvidelse eksisterende Kiosk (members excluded):59114857
59105874 | 0.001785 | 14.0122 | 0.1785 | S4 | F90 | A162446 | 182412 | TG | ENGM | Model Group:A162446 - Utvidelse eksisterende Kiosk (members excluded):59114857
59105856 | 0.0026244 | 20.6015 | 0.26244 |  |  |  |  |  |  | Model Group:pylon 2430 (members excluded):59105865
59105862 | 0.0026244 | 20.6015 | 0.26244 |  |  |  |  |  |  | Model Group:pylon 2430 (members excluded):59105865

# IfcPlate: System Panel:A245 - KL-M06 - Veggkledning metallplate fendring (4)
In: Nivå F - 0,7 m
Type - PredefinedType: CURTAIN_PANEL; Material: Metal - Panel
AVINOR - 08_Status: S4; 07_Fase: F90; 02_Prosjekt: A162446; 03_Ansvar: 182412; 06_Omrade: TG; 01_Lufthavnkode: ENGM
Pset_PlateCommon - IsExternal: no; Reference: A245 - KL-M06 - Veggkledning metallplate fendring
ePset_LocationTool - Splitting: ORIGINAL
ePset_Simplebim - Assembly Level: Leaf
Pset_QuantityTakeOff - Reference: A245 - KL-M06 - Veggkledning metallplate fendring
Group: Model Group:A162446 - Utvidelse eksisterende Kiosk (members excluded):59114857
Name (System Panel:A245 - KL-M06 - Veggkledning metallplate fendring:...) | Area, largest surface, net (Simplebim) (m2) | Volume, net (Simplebim) (m3) | Weight, as steel (Simplebim) (kg)
59106077 | 0.144 | 0.00216 | 16.956
59106080 | 0.144 | 0.00216 | 16.956
59106082 | 0.0760683 | 0.00114102 | 8.95704
59106086 | 0.0900692 | 0.00135104 | 10.6057

# IfcPlate: System Panel:A245 - KL-T00 - - - skal byttes manuelt (2)
In: Nivå F - 0,7 m
Type - PredefinedType: CURTAIN_PANEL; Material: T2_Tre Finerplate
AVINOR - 08_Status: S4; 07_Fase: F90; 02_Prosjekt: A162446; 03_Ansvar: 182412; 06_Omrade: TG; 01_Lufthavnkode: ENGM
Pset_QuantityTakeOff - Reference: A245 - KL-T00 - - - skal byttes manuelt
ePset_LocationTool - Splitting: ORIGINAL
ePset_Simplebim - Assembly Level: Leaf
Pset_PlateCommon - Reference: A245 - KL-T00 - - - skal byttes manuelt; IsExternal: no
Group: Model Group:A162446 - Utvidelse eksisterende Kiosk (members excluded):59114857
Name (System Panel:A245 - KL-T00 - - - skal byttes manuelt:...) | Volume, net (Simplebim) (m3) | Area, largest surface, net (Simplebim) (m2) | Weight, as steel (Simplebim) (kg)
59105867 | 0.02593 | 1.2965 | 203.551
59105868 | 0.02499 | 1.2495 | 196.171

# IfcPlate: System Panel:A245 - KL-T03 - Trekledning 14mm (36)
In: Nivå F - 0,7 m
Type - PredefinedType: CURTAIN_PANEL; Material: Wood - Timber
AVINOR - 08_Status: S4; 07_Fase: F90; 03_Ansvar: FDV; 06_Omrade: TG; 02_Prosjekt: T20100; 01_Lufthavnkode: ENGM
Pset_PlateCommon - IsExternal: no; Reference: A245 - KL-T03 - Trekledning 14mm
Pset_QuantityTakeOff - Reference: A245 - KL-T03 - Trekledning 14mm
ePset_Simplebim - Assembly Level: Leaf
ePset_LocationTool - Splitting: ORIGINAL
Name (System Panel:A245 - KL-T03 - Trekledning 14mm:...) | Weight, as steel (Simplebim) (kg) | Volume, net (Simplebim) (m3) | Area, largest surface, net (Simplebim) (m2)
50255383 | 155.981 | 0.0198702 | 1.4193
50255385 | 623.924 | 0.0794808 | 5.6772
50255389 | 155.981 | 0.0198702 | 1.4193
50255387 | 623.924 | 0.0794808 | 5.6772
50255391 | 155.981 | 0.0198702 | 1.4193
50255393 | 623.924 | 0.0794808 | 5.6772
50255407 | 1.29127 | 0.000164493 | 0.0117495
50255409 | 5.16509 | 0.000657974 | 0.0469981
50255413 | 1.29127 | 0.000164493 | 0.0117495
50255411 | 5.16509 | 0.000657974 | 0.0469981
50255415 | 1.29127 | 0.000164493 | 0.0117495
50255417 | 5.16509 | 0.000657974 | 0.0469981
50255419 | 16.518 | 0.0021042 | 0.1503
50255421 | 66.0719 | 0.0084168 | 0.6012
50255425 | 16.518 | 0.0021042 | 0.1503
50255423 | 66.0719 | 0.0084168 | 0.6012
50255427 | 16.518 | 0.0021042 | 0.1503
50255429 | 66.0719 | 0.0084168 | 0.6012
50255443 | 38.5419 | 0.0049098 | 0.3507
50255445 | 154.168 | 0.0196392 | 1.4028
50255449 | 38.5419 | 0.0049098 | 0.3507
50255447 | 154.168 | 0.0196392 | 1.4028
50255451 | 38.5419 | 0.0049098 | 0.3507
50255453 | 154.168 | 0.0196392 | 1.4028
50255455 | 1.35177 | 0.0001722 | 0.0123
50255457 | 5.40708 | 0.0006888 | 0.0492
50255461 | 1.35177 | 0.0001722 | 0.0123
50255459 | 5.40708 | 0.0006888 | 0.0492
50255463 | 1.35177 | 0.0001722 | 0.0123
50255465 | 5.40708 | 0.0006888 | 0.0492
50255467 | 16.518 | 0.0021042 | 0.1503
50255469 | 66.0719 | 0.0084168 | 0.6012
50255473 | 16.518 | 0.0021042 | 0.1503
50255471 | 66.0719 | 0.0084168 | 0.6012
50255475 | 16.518 | 0.0021042 | 0.1503
50255477 | 66.0719 | 0.0084168 | 0.6012

# IfcPlate: System Panel:A245 - Metallkasett Inv.20mm - Offset 30mm (7)
In: Nivå F - 0,7 m
Type - PredefinedType: CURTAIN_PANEL; Material: Metal - Steel
AVINOR - 08_Status: S4; 07_Fase: F90; 03_Ansvar: FDV; 06_Omrade: TG; 02_Prosjekt: T20100; 01_Lufthavnkode: ENGM
Pset_PlateCommon - IsExternal: no; Reference: A245 - Metallkasett Inv.20mm - Offset 30mm
ePset_LocationTool - Splitting: ORIGINAL
Pset_QuantityTakeOff - Reference: A245 - Metallkasett Inv.20mm - Offset 30mm
ePset_Simplebim - Assembly Level: Leaf
Name (System Panel:A245 - Metallkasett Inv.20mm - Offset 30mm:...) | Volume, net (Simplebim) (m3) | Weight, as steel (Simplebim) (kg) | Area, largest surface, net (Simplebim) (m2)
50238659 | 0.01551 | 121.754 | 0.7755
50238683 | 0.0011688 | 9.17508 | 0.05844
50238935 | 0.0009945 | 7.80683 | 0.049725
50238691 | 0.0284518 | 223.347 | 1.42259
50238941 | 0.00101182 | 7.94277 | 0.0505909
50238957 | 0.00221681 | 17.402 | 0.110841
50238949 | 0.0306069 | 240.265 | 1.53035

# IfcPlate: System Panel:A245 - T1 - Glass - 10 mm (2)
In: Nivå F - 0,7 m
Type - PredefinedType: CURTAIN_PANEL; Material: Glass (Avinor)
AVINOR - 08_Status: S4; 07_Fase: F90; 02_Prosjekt: A162446; 03_Ansvar: 182412; 06_Omrade: TG; 01_Lufthavnkode: ENGM
Pset_PlateCommon - Reference: A245 - T1 - Glass - 10 mm; IsExternal: no
Pset_QuantityTakeOff - Reference: A245 - T1 - Glass - 10 mm
ePset_Simplebim - Assembly Level: Leaf
ePset_LocationTool - Splitting: ORIGINAL
Group: Model Group:A162446 - Utvidelse eksisterende Kiosk (members excluded):59114857
Name (System Panel:A245 - T1 - Glass - 10 mm:...) | Area, largest surface, net (Simplebim) (m2) | Volume, net (Simplebim) (m3) | Weight, as steel (Simplebim) (kg)
59105849 | 1.7904 | 0.017904 | 140.547
59105850 | 1.7255 | 0.017255 | 135.452

# IfcPlate: System Panel:A245 - Trepanel eksisterende (10)
In: Nivå F - 0,7 m
Type - PredefinedType: CURTAIN_PANEL; Material: T2_Tre Finerplate
AVINOR - 08_Status: S4; 07_Fase: F90; 03_Ansvar: FDV; 06_Omrade: TG; 02_Prosjekt: T20100; 01_Lufthavnkode: ENGM
Pset_PlateCommon - Reference: A245 - Trepanel eksisterende; IsExternal: no
ePset_Simplebim - Assembly Level: Leaf
Pset_QuantityTakeOff - Reference: A245 - Trepanel eksisterende
ePset_LocationTool - Splitting: ORIGINAL
Name (System Panel:A245 - Trepanel eksisterende:...) | Weight, as steel (Simplebim) (kg) | Area, largest surface, net (Simplebim) (m2) | Volume, net (Simplebim) (m3)
50238663 | 162.208 | 1.03317 | 0.0206635
50238716 | 190.833 | 1.2155 | 0.02431
50238709 | 190.833 | 1.2155 | 0.02431
50238702 | 190.833 | 1.2155 | 0.02431
50238695 | 162.208 | 1.03317 | 0.0206635
50238665 | 171.837 | 1.0945 | 0.02189
50238717 | 189.97 | 1.21 | 0.0242
50238710 | 189.97 | 1.21 | 0.0242
50238703 | 189.97 | 1.21 | 0.0242
50238696 | 171.837 | 1.0945 | 0.02189

# IfcPlate: System Panel:A245 - Trepanel eksisterende 2 (14)
In: Nivå F - 0,7 m
Type - PredefinedType: CURTAIN_PANEL; Material: T2_Tre Finerplate
AVINOR - 08_Status: S4; 07_Fase: F90; 03_Ansvar: FDV; 06_Omrade: TG; 02_Prosjekt: T20100; 01_Lufthavnkode: ENGM
Pset_PlateCommon - Reference: A245 - Trepanel eksisterende 2; IsExternal: no
ePset_LocationTool - Splitting: ORIGINAL
ePset_Simplebim - Assembly Level: Leaf
Pset_QuantityTakeOff - Reference: A245 - Trepanel eksisterende 2
Name (System Panel:A245 - Trepanel eksisterende 2:...) | Volume, net (Simplebim) (m3) | Area, largest surface, net (Simplebim) (m2) | Weight, as steel (Simplebim) (kg)
50238661 | 0.011374 | 0.28435 | 89.2859
50238721 | 0.011374 | 0.28435 | 89.2859
50238737 | 0.011374 | 0.28435 | 89.2859
50238753 | 0.011374 | 0.28435 | 89.2859
50238809 | 0.011374 | 0.28435 | 89.2859
50238785 | 0.011374 | 0.28435 | 89.2859
50238801 | 0.011374 | 0.28435 | 89.2859
50238825 | 0.011374 | 0.28435 | 89.2859
50238841 | 0.011374 | 0.28435 | 89.2859
50238857 | 0.011374 | 0.28435 | 89.2859
50238889 | 0.011374 | 0.28435 | 89.2859
50238897 | 0.011374 | 0.28435 | 89.2859
50238905 | 0.011374 | 0.28435 | 89.2859
50238913 | 0.009306 | 0.23265 | 73.0521

# IfcPlate: System Panel:U245 - Metallkasett Inv. - 20 mm - Offset 30 mm (12)
In: Nivå F - 0,7 m
Type - PredefinedType: CURTAIN_PANEL; Material: Metal - Preget plate
AVINOR - 08_Status: S4; 07_Fase: F90; 03_Ansvar: FDV; 06_Omrade: TG; 02_Prosjekt: T20100; 01_Lufthavnkode: ENGM
Pset_QuantityTakeOff - Reference: U245 - Metallkasett Inv. - 20 mm - Offset 30 mm
Pset_PlateCommon - Reference: U245 - Metallkasett Inv. - 20 mm - Offset 30 mm; IsExternal: no
ePset_Simplebim - Assembly Level: Leaf
ePset_LocationTool - Splitting: ORIGINAL
Name (System Panel:U245 - Metallkasett Inv. - 20 mm - Offset 30 mm:...) | Area, largest surface, net (Simplebim) (m2) | Volume, net (Simplebim) (m3) | Weight, as steel (Simplebim) (kg)
50238685 | 0.23376 | 0.0046752 | 36.7003
50238936 | 0.1989 | 0.003978 | 31.2273
50238687 | 0.2922 | 0.005844 | 45.8754
50238937 | 0.248625 | 0.0049725 | 39.0341
50238689 | 0.2922 | 0.005844 | 45.8754
50238938 | 0.248625 | 0.0049725 | 39.0341
50238943 | 0.202364 | 0.00404727 | 31.7711
50238958 | 0.443362 | 0.00886725 | 69.6079
50238945 | 0.252955 | 0.00505909 | 39.7139
50238959 | 0.554203 | 0.0110841 | 87.0099
50238947 | 0.252955 | 0.00505909 | 39.7139
50238960 | 0.554203 | 0.0110841 | 87.0099

# IfcRailing: Railing:A247 Fendring - FE-S01 - Avviser, montert m. brakett mot dekke, 1 rør Ø=49 mm, Railing:A247 Fendring - FE-S01 - Avviser, montert m. brakett mot dekke, 1 rør Ø=49 mm:56271095
In: Nivå F - 0,7 m
Material: <Unnamed>
ePset_SimplebimBasicQuantities - Height: 50 mm; Width: 50 mm; Length: 3860 mm
AVINOR - 08_Status: S4; 04_Kontrakt: 72717; 06_Omrade: TG; 02_Prosjekt: T20100; 07_Fase: F50; 05_ID-nummer: +TG=254.010-IY0001; 03_Ansvar: OSL; 01_Lufthavnkode: ENGM
Pset_QuantityTakeOff - Reference: A247 Fendring - FE-S01 - Avviser, montert m. brakett mot dekke, 1 rør Ø=49 mm
ePset_LocationTool - Splitting: ORIGINAL
ePset_Simplebim - Assembly Level: Leaf
Pset_RailingCommon - Height: 1219.2 mm; Reference: A247 Fendring - FE-S01 - Avviser, montert m. brakett mot dekke, 1 rør Ø=49 mm; IsExternal: no

# IfcSlab: 100*26610, PÅSTØP
In: F
Description: 100*26610; PredefinedType: FLOOR
AVINOR - 07_Fase: F90; 02_Prosjekt: T1; 04_Kontrakt: FDV; 03_Ansvar: FDV; 08_Status: S2; 06_Omrade: TG; 01_Lufthavnkode: ENGM
ePset_SimplebimBasicQuantities - Perimeter (Simplebim): 45858.9 mm; Area, largest surface, net (Simplebim): 80.7509 m2; Area, top, net (Simplebim): 80.7509 m2; Area, sides, net (Simplebim): 4.58589 m2; Thickness (Simplebim): 100 mm; Volume, net (Simplebim): 8.07509 m3
Tekla Common - Bottom elevation: +210.030; Name: PÅSTØP; Part mark: Concrete-4280(?); Profile: 100*26610; Top elevation: +210.130; Assembly mark: PST-344(?); Grade: C30/37; Class: 262
ePset_Simplebim - Assembly Level: Leaf
Pset_SlabCommon - Reference: Concrete-4280(?); LoadBearing: no
ePset_LocationTool - Splitting: RESULT

# IfcSlab: 100*26620, PÅSTØP
In: F
Description: 100*26620; PredefinedType: FLOOR
Tekla Common - Bottom elevation: +210.030; Name: PÅSTØP; Top elevation: +210.130; Profile: 100*26620; Grade: C30/37; Assembly mark: PST-337(?); Part mark: Concrete-4272(?); Class: 262
AVINOR - 07_Fase: F90; 02_Prosjekt: T1; 04_Kontrakt: FDV; 03_Ansvar: FDV; 08_Status: S2; 06_Omrade: TG; 01_Lufthavnkode: ENGM
ePset_LocationTool - Splitting: RESULT
ePset_SimplebimBasicQuantities - Area, sides, net (Simplebim): 5.47493 m2; Perimeter (Simplebim): 54749.3 mm; Thickness (Simplebim): 100 mm; Area, largest surface, net (Simplebim): 168.181 m2; Area, top, net (Simplebim): 168.181 m2; Volume, net (Simplebim): 16.8181 m3
ePset_Simplebim - Assembly Level: Leaf
Pset_SlabCommon - LoadBearing: no; Reference: Concrete-4272(?)

# IfcSlab: 100*3600 (2)
In: G
Description: 100*3600; PredefinedType: FLOOR
AVINOR - 07_Fase: F90; 02_Prosjekt: T1; 04_Kontrakt: FDV; 03_Ansvar: FDV; 08_Status: S2; 06_Omrade: TG; 01_Lufthavnkode: ENGM
Pset_SlabCommon - LoadBearing: no
Tekla Common - Profile: 100*3600; Name: PÅSTØP; Bottom elevation: +213.560; Grade: C30/37; Class: 262; Top elevation: +213.660
ePset_Simplebim - Assembly Level: Leaf
ePset_LocationTool - Splitting: RESULT
ePset_SimplebimBasicQuantities - Thickness (Simplebim): 100 mm
Name | Reference = Part mark | Assembly mark | Volume, net (Simplebim) (m3) | Perimeter (Simplebim) (mm) | Area, sides, net (Simplebim) (m2) | Area, top, net (Simplebim) (m2) = Area, largest surface, net (Simplebim) (m2)
PÅSTØP | Concrete-19429(?) | PST-1039(?) | 3.05763 | 26810.5 | 2.68105 | 30.5763
PÅSTØP | Concrete-4281(?) | PST-345(?) | 6.50324 | 43329 | 4.3329 | 65.0323

# IfcSlab: 250*1420, PREFABDEKKE
In: F
Description: 250*1420; PredefinedType: FLOOR; Material: CONCRETE/C45/55
Pset_SlabCommon - Reference: Concrete_PD-1-7(?); LoadBearing: no
AVINOR - 07_Fase: F90; 02_Prosjekt: T1; 05_ID-nummer: +TA=251.003; 04_Kontrakt: FDV; 03_Ansvar: FDV; 08_Status: S2; 06_Omrade: TG; 01_Lufthavnkode: ENGM
Tekla Quantity - Heigth: 1420.01 mm; AREA_GROSS: 3.86244 m2; AREA_NET: 9.79488 m2; VOLUME_GROSS: 0.96561 m3; VOLUME_NET: 0.96561 m3; WEIGTH_GROSS: 2317.46 kg; Length: 2720 mm; WEIGTH_NET: 2317.46 kg; Width: 250 mm
ePset_Simplebim - Assembly Level: Leaf
Tekla Common - Bottom elevation: +209.785; Name: PREFABDEKKE; Profile: 250*1420; Top elevation: +210.035; Assembly mark: PD-610(?); Grade: C45/55; Part mark: Concrete_PD-1-7(?); Class: 160
ePset_LocationTool - Splitting: ORIGINAL
ePset_SimplebimBasicQuantities - Area, sides, net (Simplebim): 2.07001 m2; Volume, net (Simplebim): 0.965609 m3; Perimeter (Simplebim): 8280.03 mm; Thickness (Simplebim): 250 mm; Area, largest surface, net (Simplebim): 3.86244 m2; Area, top, net (Simplebim): 3.86244 m2

# IfcSlab: 250*1670, PREFABDEKKE
In: F
Description: 250*1670; PredefinedType: FLOOR; Material: CONCRETE/C45/55
ePset_SimplebimBasicQuantities - Area, largest surface, net (Simplebim): 6.26616 m2; Area, top, net (Simplebim): 6.26616 m2; Perimeter (Simplebim): 14834.8 mm; Thickness (Simplebim): 250 mm; Volume, net (Simplebim): 1.56654 m3; Area, sides, net (Simplebim): 3.70871 m2
Pset_SlabCommon - Reference: Concrete_PD-1-29(?); LoadBearing: no
ePset_LocationTool - Splitting: ORIGINAL
AVINOR - 07_Fase: F90; 02_Prosjekt: T1; 05_ID-nummer: +TA=251.003; 04_Kontrakt: FDV; 03_Ansvar: FDV; 08_Status: S2; 06_Omrade: TG; 01_Lufthavnkode: ENGM
ePset_Simplebim - Assembly Level: Leaf
Tekla Quantity - VOLUME_GROSS: 1.78672 m3; AREA_NET: 16.241 m2; AREA_GROSS: 7.1469 m2; WEIGTH_NET: 3759.7 kg; Heigth: 1670 mm; VOLUME_NET: 1.56654 m3; Length: 4279.58 mm; Width: 250 mm; WEIGTH_GROSS: 4288.14 kg
Tekla Common - Bottom elevation: +209.785; Part mark: Concrete_PD-1-29(?); Profile: 250*1670; Name: PREFABDEKKE; Top elevation: +210.035; Grade: C45/55; Assembly mark: PD-632(?); Class: 160

# IfcSlab: 265*1635, PREFABDEKKE
In: F
Description: 265*1635; PredefinedType: FLOOR; Material: CONCRETE/C45/55
Tekla Common - Bottom elevation: +209.765; Top elevation: +210.030; Name: PREFABDEKKE; Part mark: Concrete_PD-1-37(?); Assembly mark: PD-640(?); Grade: C45/55; Profile: 265*1635; Class: 160
ePset_SimplebimBasicQuantities - Volume, net (Simplebim): 0.703974 m3; Area, top, net (Simplebim): 2.6565 m2; Area, largest surface, net (Simplebim): 2.6565 m2; Area, sides, net (Simplebim): 1.75685 m2; Perimeter (Simplebim): 6629.64 mm; Thickness (Simplebim): 265 mm
ePset_LocationTool - Splitting: ORIGINAL
AVINOR - 07_Fase: F90; 02_Prosjekt: T1; 05_ID-nummer: +TA=251.003; 04_Kontrakt: FDV; 03_Ansvar: FDV; 08_Status: S2; 06_Omrade: TG; 01_Lufthavnkode: ENGM
Pset_SlabCommon - Reference: Concrete_PD-1-37(?); LoadBearing: no
Tekla Quantity - Heigth: 1635 mm; AREA_GROSS: 2.7465 m2; WEIGTH_NET: 1689.54 kg; WEIGTH_GROSS: 1746.78 kg; AREA_NET: 7.06986 m2; VOLUME_NET: 0.70397 m3; VOLUME_GROSS: 0.70397 m3; Width: 265 mm; Length: 1679.82 mm
ePset_Simplebim - Assembly Level: Leaf

# IfcSlab: 90*14990, PÅSTØP
In: G
Description: 90*14990; PredefinedType: FLOOR
Tekla Common - Profile: 90*14990; Name: PÅSTØP; Bottom elevation: +213.570; Assembly mark: PST-352(?); Part mark: Concrete-4288(?); Grade: C30/37; Class: 262; Top elevation: +213.660
AVINOR - 07_Fase: F90; 02_Prosjekt: T1; 04_Kontrakt: FDV; 03_Ansvar: FDV; 08_Status: S2; 06_Omrade: TG; 01_Lufthavnkode: ENGM
ePset_SimplebimBasicQuantities - Area, largest surface, net (Simplebim): 40.3949 m2; Perimeter (Simplebim): 58598.3 mm; Area, top, net (Simplebim): 40.3949 m2; Area, sides, net (Simplebim): 5.27385 m2; Thickness (Simplebim): 90 mm; Volume, net (Simplebim): 3.63554 m3
ePset_LocationTool - Splitting: RESULT
ePset_Simplebim - Assembly Level: Leaf
Pset_SlabCommon - Reference: Concrete-4288(?); LoadBearing: no

# IfcSlab: Floor:A251 - TRP - 45 mm, Floor:A251 - TRP - 45 mm:59105904
In: Nivå G
Type - PredefinedType: FLOOR; Material: _NSW Generell Gulv (Floor) 45 mm
AVINOR - 08_Status: S4; 07_Fase: F90; 02_Prosjekt: A162446; 03_Ansvar: 182412; 06_Omrade: TG; 01_Lufthavnkode: ENGM
Pset_ReinforcementBarPitchOfSlab - Reference: A251 - TRP - 45 mm; sets with these values: 2
ePset_LocationTool - Splitting: ORIGINAL
ePset_Simplebim - Assembly Level: Leaf
Pset_SlabCommon - IsExternal: no; LoadBearing: no; PitchAngle: 0 deg; Reference: A251 - TRP - 45 mm
ePset_SimplebimBasicQuantities - Perimeter (Simplebim): 43886.7 mm; Area, top, net (Simplebim): 74.8242 m2; Area, largest surface, net (Simplebim): 74.8242 m2; Area, sides, net (Simplebim): 1.9749 m2; Thickness (Simplebim): 45 mm; Volume, net (Simplebim): 3.36709 m3
Group: Model Group:A162446 - Utvidelse eksisterende Kiosk (members excluded):59114857

# IfcSlab: Floor:A254 - Gulvoppbygging m_f.o - 40mm, Floor:A254 - Gulvoppbygging m_f.o - 40mm:50089583
In: Nivå G - 2,0 m
Type - PredefinedType: FLOOR; Material: T2 - Dekke uten skravur 40 mm
Type - Pset_ReinforcementBarPitchOfSlab - Description: eksisterende gulv
AVINOR - 08_Status: S4; 07_Fase: F90; 03_Ansvar: FDV; 06_Omrade: TG; 02_Prosjekt: T20100; 01_Lufthavnkode: ENGM
ePset_LocationTool - Splitting: ORIGINAL
Pset_ReinforcementBarPitchOfSlab - Reference: A254 - Gulvoppbygging m_f.o - 40mm; sets with these values: 2
ePset_SimplebimBasicQuantities - Volume, net (Simplebim): 0.0865733 m3; Area, top, net (Simplebim): 2.16433 m2; Area, largest surface, net (Simplebim): 2.16433 m2; Thickness (Simplebim): 40 mm; Perimeter (Simplebim): 10216.5 mm; Area, sides, net (Simplebim): 0.40866 m2
ePset_Simplebim - Assembly Level: Leaf
Pset_SlabCommon - IsExternal: no; LoadBearing: no; PitchAngle: 0 deg; Reference: A254 - Gulvoppbygging m_f.o - 40mm

# IfcSlab: Floor:A254 - Gulvoppbygging m_f.o - 40mm - tre (2)
In: Nivå G - 2,0 m
Type - PredefinedType: FLOOR; Material: T2 - Dekke uten skravur 40 mm
Type - Pset_ReinforcementBarPitchOfSlab - Description: eksisterende tregulv
AVINOR - 08_Status: S4; 07_Fase: F90; 03_Ansvar: FDV; 06_Omrade: TG; 02_Prosjekt: T20100; 01_Lufthavnkode: ENGM
ePset_Simplebim - Assembly Level: Leaf
Pset_ReinforcementBarPitchOfSlab - Reference: A254 - Gulvoppbygging m_f.o - 40mm - tre; sets with these values: 2
Pset_SlabCommon - Reference: A254 - Gulvoppbygging m_f.o - 40mm - tre; IsExternal: no; LoadBearing: no
ePset_SimplebimBasicQuantities - Thickness (Simplebim): 40 mm
ePset_LocationTool - Splitting: RESULT
Name (Floor:A254 - Gulvoppbygging m_f.o - 40mm - tre:...) | Perimeter (Simplebim) (mm) | Area, sides, net (Simplebim) (m2) | Area, top, net (Simplebim) (m2) = Area, largest surface, net (Simplebim) (m2) | Volume, net (Simplebim) (m3)
50088594 | 46408.4 | 1.85634 | 39.9542 | 1.59817
50089729 | 61667.8 | 2.46671 | 97.0803 | 3.88322

# IfcSlab: Floor:A254 - Gulvoppbygging m_f.o - 40mm - våtrom, Floor:A254 - Gulvoppbygging m_f.o - 40mm - våtrom:50089261
In: Nivå G - 2,0 m
Type - PredefinedType: FLOOR; Material: T2 - Dekke uten skravur 40 mm
Type - Pset_ReinforcementBarPitchOfSlab - Description: eksisterende våtromgulv
AVINOR - 08_Status: S4; 07_Fase: F90; 03_Ansvar: FDV; 06_Omrade: TG; 02_Prosjekt: T20100; 01_Lufthavnkode: ENGM
ePset_SimplebimBasicQuantities - Area, sides, net (Simplebim): 0.41634 m2; Area, top, net (Simplebim): 6.50878 m2; Area, largest surface, net (Simplebim): 6.50878 m2; Volume, net (Simplebim): 0.260351 m3; Thickness (Simplebim): 40 mm; Perimeter (Simplebim): 10408.5 mm
ePset_LocationTool - Splitting: ORIGINAL
Pset_ReinforcementBarPitchOfSlab - Reference: A254 - Gulvoppbygging m_f.o - 40mm - våtrom; sets with these values: 2
ePset_Simplebim - Assembly Level: Leaf
Pset_SlabCommon - Reference: A254 - Gulvoppbygging m_f.o - 40mm - våtrom; IsExternal: no; LoadBearing: no; PitchAngle: 0 deg

# IfcSlab: Floor:A254 - Gulvoppbygging m_f.o - 70mm - stein (2)
In: Nivå F - 0,7 m
Type - PredefinedType: FLOOR; Material: T2 - Dekke uten skravur 70 mm
Type - Pset_ReinforcementBarPitchOfSlab - Description: eksisterende steingulv
AVINOR - 08_Status: S4; 07_Fase: F90; 03_Ansvar: FDV; 06_Omrade: TG; 02_Prosjekt: T20100; 01_Lufthavnkode: ENGM
ePset_SimplebimBasicQuantities - Thickness (Simplebim): 70 mm
ePset_Simplebim - Assembly Level: Leaf
Pset_SlabCommon - Reference: A254 - Gulvoppbygging m_f.o - 70mm - stein; IsExternal: no; LoadBearing: no
Pset_QuantityTakeOff - Reference: A254 - Gulvoppbygging m_f.o - 70mm - stein; sets with these values: 2
Name (Floor:A254 - Gulvoppbygging m_f.o - 70mm - stein:...) | Splitting | Area, top, net (Simplebim) (m2) = Area, largest surface, net (Simplebim) (m2) | Perimeter (Simplebim) (mm) | Area, sides, net (Simplebim) (m2) | Volume, net (Simplebim) (m3)
49468518 | ORIGINAL | 23.4202 | 22080.1 | 1.54561 | 1.63942 | Pset_SlabCommon - PitchAngle: 0 deg
49466013 | RESULT | 32.9397 | 39601.4 | 2.7721 | 2.30578

# IfcSlab: Floor:A254 - Gulvoppbygging m_f.o - 70mm - tre, Floor:A254 - Gulvoppbygging m_f.o - 70mm - tre:49951745:2
In: Nivå F - 0,7 m
Type - PredefinedType: FLOOR; Material: T2 - Dekke uten skravur 70 mm
Type - Pset_ReinforcementBarPitchOfSlab - Description: eksisterende tregulv
AVINOR - 08_Status: S4; 07_Fase: F90; 03_Ansvar: FDV; 06_Omrade: TG; 02_Prosjekt: T20100; 01_Lufthavnkode: ENGM
ePset_SimplebimBasicQuantities - Area, top, net (Simplebim): 158.146 m2; Area, largest surface, net (Simplebim): 158.146 m2; Area, sides, net (Simplebim): 6.66675 m2; Perimeter (Simplebim): 95239.3 mm; Volume, net (Simplebim): 11.0702 m3; Thickness (Simplebim): 70 mm
Pset_SlabCommon - Reference: A254 - Gulvoppbygging m_f.o - 70mm - tre; IsExternal: no; LoadBearing: no
Pset_QuantityTakeOff - Reference: A254 - Gulvoppbygging m_f.o - 70mm - tre; sets with these values: 2
ePset_Simplebim - Assembly Level: Leaf
ePset_LocationTool - Splitting: RESULT

# IfcSlab: Floor:A254 - Gulvoppbygging m_f.o - 70mm - våtrom, Floor:A254 - Gulvoppbygging m_f.o - 70mm - våtrom:49468337
In: Nivå F - 0,7 m
Type - PredefinedType: FLOOR; Material: T2 - Dekke uten skravur 70 mm
Type - Pset_ReinforcementBarPitchOfSlab - Description: eksisterende våtromgulv
AVINOR - 08_Status: S4; 07_Fase: F90; 03_Ansvar: FDV; 06_Omrade: TG; 02_Prosjekt: T20100; 01_Lufthavnkode: ENGM
ePset_LocationTool - Splitting: ORIGINAL
Pset_ReinforcementBarPitchOfSlab - Reference: A254 - Gulvoppbygging m_f.o - 70mm - våtrom; sets with these values: 2
ePset_Simplebim - Assembly Level: Leaf
Pset_SlabCommon - IsExternal: no; LoadBearing: no; PitchAngle: 0 deg; Reference: A254 - Gulvoppbygging m_f.o - 70mm - våtrom
ePset_SimplebimBasicQuantities - Volume, net (Simplebim): 1.59865 m3; Thickness (Simplebim): 70 mm; Perimeter (Simplebim): 23879.6 mm; Area, sides, net (Simplebim): 1.67157 m2; Area, largest surface, net (Simplebim): 22.838 m2; Area, top, net (Simplebim): 22.838 m2

# IfcSlab: Floor:A254 - eksisterende gangbar glass pir - 27mm (9)
In: Nivå G - 2,0 m
Type - PredefinedType: FLOOR; Material: Glass (Avinor) 27 mm
AVINOR - 08_Status: S4; 07_Fase: F90; 03_Ansvar: FDV; 06_Omrade: TG; 02_Prosjekt: T20100; 01_Lufthavnkode: ENGM
Pset_SlabCommon - IsExternal: no; LoadBearing: no; PitchAngle: 0 deg; Reference: A254 - eksisterende gangbar glass pir - 27mm
Pset_ReinforcementBarPitchOfSlab - Reference: A254 - eksisterende gangbar glass pir - 27mm; sets with these values: 2
ePset_Simplebim - Assembly Level: Leaf
ePset_LocationTool - Splitting: ORIGINAL
ePset_SimplebimBasicQuantities - Area, sides, net (Simplebim): 0.17955 m2; Volume, net (Simplebim): 0.0266855 m3; Area, top, net (Simplebim): 0.98835 m2; Area, largest surface, net (Simplebim): 0.98835 m2; Thickness (Simplebim): 27 mm; Perimeter (Simplebim): 6650 mm
Name (Floor:A254 - eksisterende gangbar glass pir - 27mm:...) | Group
49956593 | Model Group:A254 - eksisterende glassgulv i pir G ved fasade / __generell (members excluded):49956618
49956600 | Model Group:A254 - eksisterende glassgulv i pir G ved fasade / __generell (members excluded):49956618
49956607 | Model Group:A254 - eksisterende glassgulv i pir G ved fasade / __generell (members excluded):49956618
49956646 | Model Group:A254 - eksisterende glassgulv i pir G ved fasade / __generell (members excluded):49956671
49956653 | Model Group:A254 - eksisterende glassgulv i pir G ved fasade / __generell (members excluded):49956671
49956660 | Model Group:A254 - eksisterende glassgulv i pir G ved fasade / __generell (members excluded):49956671
53645449 | Model Group:A254 - eksisterende glassgulv i pir G ved fasade / __generell (members excluded):53645474
53645456 | Model Group:A254 - eksisterende glassgulv i pir G ved fasade / __generell (members excluded):53645474
53645463 | Model Group:A254 - eksisterende glassgulv i pir G ved fasade / __generell (members excluded):53645474

# IfcSlab: HD265 (31)
Description: HD265; PredefinedType: FLOOR
ePset_SimplebimBasicQuantities - Thickness (Simplebim): 265 mm
Tekla Common - Grade: C45/55; Profile: HD265; Name: HULLDEKKE; Class: 162
AVINOR - 07_Fase: F90; 02_Prosjekt: T1; 04_Kontrakt: FDV; 03_Ansvar: FDV; 08_Status: S2; 06_Omrade: TG; 01_Lufthavnkode: ENGM
ePset_Simplebim - Assembly Level: Leaf
Pset_SlabCommon - LoadBearing: no
Name | In | Material | VOLUME_NET (m3) | AREA_GROSS (m2) | AREA_NET (m2) | Heigth (mm) | Width (mm) | Length (mm) | WEIGTH_NET (kg) | WEIGTH_GROSS (kg) | VOLUME_GROSS (m3) | Area, top, net (Simplebim) (m2) | Volume, net (Simplebim) (m3) | Perimeter (Simplebim) (mm) | Area, largest surface, net (Simplebim) (m2) | Area, sides, net (Simplebim) (m2) | Bottom elevation | Top elevation | Part mark = Reference | Assembly mark | 05_ID-nummer | Splitting
3 x HULLDEKKE | F | CONCRETE/C45/55 | 1.35128 | 0 | 45.9113 | 265 | 1200 | 8220 | 3243.08 | 3442.8 | 1.4345 | 8.88498 | 1.35128 | 101785 | 9.59077 | 26.9729 | +209.765 | +210.030 | Concrete_HD-1-198(?) | HD-3523(?) | +TA=251.001 | ORIGINAL
3 x HULLDEKKE | G | CONCRETE/C45/55 | 1.50525 | 0 | 50.8441 | 265 | 1200 | 8768 | 3612.59 | 3672.32 | 1.53013 | 9.99318 | 1.50525 | 96842.7 | 10.2302 | 25.6633 | +213.295 | +213.560 | Concrete-18854 | HD-3074 |  | ORIGINAL
4 x HULLDEKKE | G | CONCRETE/C45/55 | 1.52551 | 0 | 51.1949 | 265 | 1200 | 8768 | 3661.21 | 3672.32 | 1.53013 | 10.4432 | 1.52551 | 113892 | 10.2302 | 30.1814 | +213.295 | +213.560 | Concrete-14302 | HD-2346 |  | ORIGINAL
2 x HULLDEKKE | G | CONCRETE/C45/55 | 1.43349 | 0 | 49.3754 | 265 | 1200 | 8768 | 3440.38 | 3672.32 | 1.53013 | 8.86494 | 1.43349 | 112982 | 10.2302 | 29.9401 | +213.295 | +213.560 | Concrete-14302(?) | HD-2346(?) |  | ORIGINAL
HULLDEKKE | F | CONCRETE/C45/55 | 0.67828 | 0 | 23.2087 | 265 | 550.01 | 8220 | 1627.87 | 3442.8 | 1.4345 | 4.48432 | 0.678279 | 53511.4 | 4.77606 | 14.1805 | +209.765 | +210.030 | Concrete_HD-1-206(?) | HD-3531(?) | +TA=251.001 | ORIGINAL
2 x HULLDEKKE | F | CONCRETE/C45/55 | 0.75858 | 0 | 25.6325 | 265 | 1200 | 4360.04 | 1820.6 | 1826.12 | 0.76088 | 5.19305 | 0.758584 | 57295 | 5.08712 | 15.1832 | +209.765 | +210.030 | Concrete_HD-1-12(?) | HD-3337(?) | +TA=251.001 | ORIGINAL
2 x HULLDEKKE | F | CONCRETE/C45/55 | 1.43016 | 0 | 48.017 | 265 | 1200 | 8220 | 3432.39 | 3442.8 | 1.4345 | 9.79048 | 1.43016 | 106856 | 9.59077 | 28.3169 | +209.765 | +210.030 | Concrete_HD-1-10(?) | HD-3335(?) | +TA=251.001 | ORIGINAL
12 x HULLDEKKE | F | CONCRETE/C45/55 | 1.43016 | 0 | 48.017 | 265 | 1200 | 8220 | 3432.39 | 3442.8 | 1.4345 | 9.79048 | 1.43016 | 106856 | 9.59077 | 28.3169 | +209.765 | +210.030 | Concrete-665 | HD-1002 | +TA=251.001 | ORIGINAL
2 x HULLDEKKE | F |  |  |  |  |  |  |  |  |  |  | 10.2988 | 0.966102 | 44482.2 | 6.43942 | 11.7878 | +209.765 | +210.030 | Concrete-665 | HD-1002 | +TA=251.001 | RESULT

# IfcSlab: PLNJABE155*40*42.6*71*32.5 (6)
In: G
Description: PLNJABE155*40*42.6*71*32.5; PredefinedType: FLOOR; Material: CONCRETE/C35/45
AVINOR - 07_Fase: F90; 02_Prosjekt: T1; 04_Kontrakt: FDV; 03_Ansvar: FDV; 08_Status: S2; 06_Omrade: TG; 01_Lufthavnkode: ENGM
ePset_SimplebimBasicQuantities - Thickness (Simplebim): 197.6 mm
ePset_LocationTool - Splitting: ORIGINAL
ePset_Simplebim - Assembly Level: Leaf
Pset_SlabCommon - LoadBearing: no
Tekla Common - Top elevation: +213.699; Name: PLASSTØPTDEKKE; Grade: C35/45; Profile: PLNJABE155*40*42.6*71*32.5; Bottom elevation: +213.501; Class: 260
Tekla Quantity - AREA_GROSS: 4.94696 m2; WEIGTH_GROSS: 771.947 kg; VOLUME_GROSS: 0.32164 m3; Length: 2030 mm; Heigth: 197.6 mm
Name | Area, sides, net (Simplebim) (m2) | Perimeter (Simplebim) (mm) | Area, top, net (Simplebim) (m2) = Area, largest surface, net (Simplebim) (m2) | Volume, net (Simplebim) (m3) | Reference = Part mark | Assembly mark | VOLUME_NET (m3) | WEIGTH_NET (kg) | AREA_NET (m2) | Width (mm)
PLASSTØPTDEKKE | 1.99343 | 10088.2 | 1.67211 | 0.302191 | Concrete-20472(?) | PLD-2849(?) | 0.30219 | 725.259 | 4.74023 | 830.006
2 x PLASSTØPTDEKKE | 2.0339 | 10293 | 1.7864 | 0.321645 | Concrete-20477(?) | PLD-2854(?) | 0.32164 | 771.947 | 4.94696 | 880
PLASSTØPTDEKKE | 2.05783 | 10414.1 | 1.7776 | 0.320087 | Concrete-20474(?) | PLD-2853(?) | 0.32009 | 768.209 | 4.95587 | 880
PLASSTØPTDEKKE | 2.05796 | 10414.8 | 1.7696 | 0.318603 | Concrete-20473(?) | PLD-2852(?) | 0.3186 | 764.648 | 4.94457 | 880
PLASSTØPTDEKKE | 2.03215 | 10284.1 | 1.7736 | 0.319363 | Concrete-20478(?) | PLD-2855(?) | 0.31936 | 766.47 | 4.9248 | 880

# IfcSlab: PLNJABE56.4*40*42.6*71*32.5 (5)
In: G
Description: PLNJABE56.4*40*42.6*71*32.5; PredefinedType: FLOOR; Material: CONCRETE/C35/45
ePset_LocationTool - Splitting: ORIGINAL
AVINOR - 07_Fase: F90; 02_Prosjekt: T1; 04_Kontrakt: FDV; 03_Ansvar: FDV; 08_Status: S2; 06_Omrade: TG; 01_Lufthavnkode: ENGM
Tekla Common - Name: PLASSTØPTDEKKE; Grade: C35/45; Bottom elevation: +213.561; Class: 260; Top elevation: +213.660; Profile: PLNJABE56.4*40*42.6*71*32.5
ePset_SimplebimBasicQuantities - Thickness (Simplebim): 99 mm
Tekla Quantity - VOLUME_GROSS: 0.07849 m3; WEIGTH_GROSS: 188.369 kg; AREA_GROSS: 2.42492 m2; Heigth: 99 mm; Length: 1095 mm
Pset_SlabCommon - LoadBearing: no
ePset_Simplebim - Assembly Level: Leaf
Name | Assembly mark | Part mark = Reference | Area, largest surface, net (Simplebim) (m2) = Area, top, net (Simplebim) (m2) | Perimeter (Simplebim) (mm) | Volume, net (Simplebim) (m3) | Area, sides, net (Simplebim) (m2) | Width (mm) | VOLUME_NET (m3) | WEIGTH_NET (kg) | AREA_NET (m2)
PLASSTØPTDEKKE | PLD-2879(?) | Concrete-20698(?) | 0.822347 | 8094.28 | 0.0662155 | 0.801334 | 751.002 | 0.06622 | 158.917 | 2.13176
4 x PLASSTØPTDEKKE | PLD-2877(?) | Concrete-20694(?) | 0.963602 | 8622.15 | 0.078487 | 0.853593 | 880 | 0.07849 | 188.369 | 2.42492

# IfcSystem (84)
Name | Description
+TG=332.003 (2) | +TG=332.003 (2)
+TG=332.003 (12) | +TG=332.003 (12)
+TG=332.003 (73) | +TG=332.003 (73)
+TG=332.003 (69) | +TG=332.003 (69)
+TG=332.003 (68) | +TG=332.003 (68)
+TG=332.003 (67) | +TG=332.003 (67)
+TG=332.003 (66) | +TG=332.003 (66)
+TG=332.003 (65) | +TG=332.003 (65)
+TG=332.003 (64) | +TG=332.003 (64)
+TG=332.003 (63) | +TG=332.003 (63)
+TG=332.003 (54) | +TG=332.003 (54)
+TG=332.003 (53) | +TG=332.003 (53)
+TG=332.003 (47) | +TG=332.003 (47)
+TG=332.003 (46) | +TG=332.003 (46)
+TG=332.002 (1) (2) | +TG=332.002 (1) (2)
+TG=332.002 | +TG=332.002 | MagiCAD Pset_System - Code: +TG=332.002
+TG=332.003 (10) | +TG=332.003 (10)
31= SPV Kopi 63 | 31= SPV Kopi 63
37= R 18° Kopi 13 | 37= R 18° Kopi 13
37= T 9° Kopi 1 | 37= T 9° Kopi 1
37= T 9° Kopi 22 | 37= T 9° Kopi 22
37= R 18° Kopi 20 | 37= R 18° Kopi 20
31=KV Kopi 4 (2) | 31=KV Kopi 4 (2)
31= VV Kopi 12 | 31= VV Kopi 12
+TG=310.002 (2) | +TG=310.002 (2)
31= SPV Kopi 138 | 31= SPV Kopi 138
+TG=310.002 (15) | +TG=310.002 (15)
31= SPV Kopi 147 (11) | 31= SPV Kopi 147 (11)
31=KV Kopi 4 (4) | 31=KV Kopi 4 (4)
31= SPV Kopi 13 | 31= SPV Kopi 13
32= R 20° Kopi 5 | 32= R 20° Kopi 5
32= R 20° Kopi 7 | 32= R 20° Kopi 7
31= SPV Kopi 147 (5) | 31= SPV Kopi 147 (5)
31= SPV Kopi 147 (4) | 31= SPV Kopi 147 (4)
31= SPV Kopi 147 (3) | 31= SPV Kopi 147 (3)
31=KV Kopi 13 | 31=KV Kopi 13
31= SPV Kopi 147 (7) | 31= SPV Kopi 147 (7)
31= VV Kopi 11 | 31= VV Kopi 11
37= R 12° Kopi 4 | 37= R 12° Kopi 4
31= SPV Kopi 147 (1) | 31= SPV Kopi 147 (1)
Kjøle Retur 17° | Retur17 | MagiCAD Pset_System - Code: Retur17
32= T 60° Kopi 10 | Tur14 | MagiCAD Pset_System - Code: Tur14
37= R 12° Kopi 6 | 37= R 12° Kopi 6
37= T 7° Kopi 6 | 37= T 7° Kopi 6
KV | KV | MagiCAD Pset_System - Code: KV
VV | VV | MagiCAD Pset_System - Code: VV
31=KV Kopi 4 (49) | 31=KV Kopi 4 (49)
+TG=310.002 (33) | +TG=310.002 (33)
37= T 7° Kopi 4 | 37= T 7° Kopi 4
32= R 50° Kopi 56 | +TG=320.001 | MagiCAD Pset_System - Code: +TG=320.001
32= T 60° Kopi 125 | +TG=320.001 | MagiCAD Pset_System - Code: +TG=320.001
32= R 20° Kopi 57 | 32= R 20° Kopi 57
32= R 20° Kopi 58 | 32= R 20° Kopi 58
+TG=310.002 (29) | +TG=310.002 (29)
37= R 18° Kopi 82 | 37= R 18° Kopi 82
37= T 9° Kopi 122 | 37= T 9° Kopi 122
31=KV Kopi 4 (29) (2) | 31=KV Kopi 4 (29) (2)
31= VV Kopi 41 | 31= VV Kopi 41
37= R 18° Kopi 81 | 37= R 18° Kopi 81
37= T 9° Kopi 54 | 37= T 9° Kopi 54
32= R 50° Kopi 54 | 32= R 50° Kopi 54
32= T 60° Kopi 50 | 32= T 60° Kopi 50
+TG=320.000.T | +TG=320.000.T
+TG=320.000.R | +TG=320.000.R
31= SPV Kopi 21 | 31= SPV Kopi 21
37= R 18° Kopi 30 | 37= R 18° Kopi 30
37= T 9° Kopi 44 | 37= T 9° Kopi 44
37= T 9° Kopi 168 | 37= T 9° Kopi 168
32= R 20° Kopi 81 | 32= R 20° Kopi 81
+TG=360.020 TL | +TG=360.020 TL
+TG=360.021-1 TL | +TG=360.021-1 TL
+TG=360.021-22 A | +TG=360.021-22 A
Mechanical 36 Avtrekk (obsolete) 149 | Mechanical 36 Avtrekk (obsolete) 149
36= Avtrekk 3 | 36= Avtrekk 3
Mechanical 36 Avtrekk (obsolete) 151 | Mechanical 36 Avtrekk (obsolete) 151
+TG=360.001 A | +TG=360.001 A
Bæresystem generelt | 410 | AVINOR - 08_Status: S4; 07_Fase: F90; 04_Kontrakt: 72527; 06_Omrade: TG; 03_Ansvar: T20100; 02_Prosjekt: 72101; 05_ID-nummer: +TO=411.011; ID-nummer2: +TO=411.011; 01_Lufthavnkode: ENGM
Bæresystem for elkraft | 4111 | AVINOR - 08_Status: S2; 07_Fase: F90; 04_Kontrakt: FDV; 06_Omrade: TG; 03_Ansvar: T20100; 02_Prosjekt: 72101; 05_ID-nummer: +TO=411.501; ID-nummer2: +TO=411.501; 01_Lufthavnkode: ENGM
Brannalarm | 542 | AVINOR - 08_Status: S4; 07_Fase: F90; 04_Kontrakt: 72581; 06_Omrade: TG; 03_Ansvar: T20100; 02_Prosjekt: 72101; 05_ID-nummer: +TG=542.011-TY0003; ID-nummer2: +TG=542.011-TY0003; 01_Lufthavnkode: ENGM
Bæresytem for tele- og automasjon | 5111 | AVINOR - 08_Status: S2; 07_Fase: F90; 04_Kontrakt: FDV; 06_Omrade: TG; 03_Ansvar: T20100; 02_Prosjekt: 72101; 05_ID-nummer: +TO=411.501; ID-nummer2: +TO=411.501; 01_Lufthavnkode: ENGM
Armaturskinne | 4111 | AVINOR - 08_Status: S2; 07_Fase: F90; 04_Kontrakt: FDV; 06_Omrade: TG; 03_Ansvar: T20100; 02_Prosjekt: 72101; 05_ID-nummer: +TO=411.501; ID-nummer2: +TO=411.501; 01_Lufthavnkode: ENGM
Trekkerør generelt | 4110 | AVINOR - 08_Status: S2; 07_Fase: F90; 04_Kontrakt: FDV; 06_Omrade: TG; 03_Ansvar: T20100; 02_Prosjekt: 72101; 05_ID-nummer: +TO=411.501; ID-nummer2: +TO=411.501; 01_Lufthavnkode: ENGM
Gulvkanal | 4115 | AVINOR - 08_Status: S2; 07_Fase: F90; 04_Kontrakt: FDV; 06_Omrade: TG; 03_Ansvar: T20100; 02_Prosjekt: 72101; 05_ID-nummer: +TO=411.501; ID-nummer2: +TO=411.501; 01_Lufthavnkode: ENGM
KNX Binærutgang | 562X | AVINOR - ID-nummer2: +TG=561.001

# IfcWall: Basic Wall:A241 - Eksisterende - GRVR-20 (2)
Type - PredefinedType: STANDARD; Material: Plate - Gips 12.5 mm, _NSW Stålstender, uisolert 100 mm, Plate - Gips 12.5 mm
AVINOR - 08_Status: S4; 07_Fase: F90; 03_Ansvar: FDV; 06_Omrade: TG; 02_Prosjekt: T20100; 01_Lufthavnkode: ENGM
Pset_WallCommon - Reference: A241 - Eksisterende - GRVR-20; IsExternal: no; ExtendToStructure: no; LoadBearing: no
Pset_ReinforcementBarPitchOfWall - Reference: A241 - Eksisterende - GRVR-20; sets with these values: 2
ePset_SimplebimBasicQuantities - Thickness (Simplebim): 125 mm; Length (Simplebim): 4987 mm
ePset_Simplebim - Assembly Level: Leaf
ePset_LocationTool - Splitting: ORIGINAL
Name (Basic Wall:A241 - Eksisterende - GRVR-20:...) | In | Area, side, net, larger (Simplebim) (m2) = Area, side, net, smaller (Simplebim) (m2) = Area, side, net, average (Simplebim) (m2) | Volume, net (Simplebim) (m3) | Area, side, gross, AABB (Simplebim) (m2) | Area, side, gross, average (Simplebim) (m2) = Area, side, gross, larger (Simplebim) (m2) = Area, side, gross, smaller (Simplebim) (m2) | Area, largest surface, net (Simplebim) (m2) | Height (Simplebim) (mm)
2512779 | Nivå F - 0,7 m | 1.0059 | 0.125737 | 3.4909 | 9.0289 | 0.2191 | 700
2512779 | Nivå F | 2.22735 | 0.278419 | 7.72985 | 2.22735 | 0.48515 | 1550

# IfcWall: Basic Wall:A241 - FSVF-100 (4)
Type - PredefinedType: STANDARD; Material: T2_Gips Protect F 15 mm, T2_Gips Standard 12.5 mm, _NSW Stålstender, uisolert 100 mm, T2_Gips Protect F 15 mm
Type - Pset_ReinforcementBarPitchOfWall - Description: Tilsvarende: T2 - IVEGG-150 - Forprosjekt
AVINOR - 08_Status: S4; 07_Fase: F90; 03_Ansvar: FDV; 06_Omrade: TG; 02_Prosjekt: T20100; 01_Lufthavnkode: ENGM
ePset_SimplebimBasicQuantities - Thickness (Simplebim): 142.5 mm
Pset_WallCommon - IsExternal: no; ExtendToStructure: no; LoadBearing: no; Reference: A241 - FSVF-100
Pset_QuantityTakeOff - Reference: A241 - FSVF-100; sets with these values: 2
ePset_Simplebim - Assembly Level: Leaf
ePset_LocationTool - Splitting: ORIGINAL
Name (Basic Wall:A241 - FSVF-100:...) | In | Height (Simplebim) (mm) | Length (Simplebim) (mm) | Volume, net (Simplebim) (m3) | Area, side, gross, larger (Simplebim) (m2) = Area, side, net, larger (Simplebim) (m2) = Area, side, gross, smaller (Simplebim) (m2) = Area, side, net, smaller (Simplebim) (m2) = Area, largest surface, net (Simplebim) (m2) = Area, side, net, average (Simplebim) (m2) = Area, side, gross, average (Simplebim) (m2) | Area, side, gross, AABB (Simplebim) (m2)
2512798 | Nivå F - 0,7 m | 700 | 2781.25 | 0.27743 | 1.94687 | 1.94688 | Identity Data - CQFireRequirement: EI 60/ A2-s1,d0
2512798 | Nivå F | 2800 | 2846.25 | 1.11347 | 7.81383 | 7.9695 | Identity Data - CQFireRequirement: EI 60/ A2-s1,d0
40981143 | Nivå F - 0,7 m | 700 | 2359.75 | 0.235385 | 1.65183 | 1.65182
40981143 | Nivå F | 2800 | 2359.75 | 0.937789 | 6.58097 | 6.6073

# IfcWall: Basic Wall:A241 - FVR-200 (T1) (2)
Type - PredefinedType: STANDARD; Material: T2_Gips Protect F 15 mm, T2_Gips Protect F 15 mm, _NSW Stålstender, isolert uten skravur 200 mm, T2_Gips Fibergips 12.5 mm
AVINOR - 08_Status: S4; 07_Fase: F90; 03_Ansvar: FDV; 06_Omrade: TG; 02_Prosjekt: T20100; 01_Lufthavnkode: ENGM
ePset_SimplebimBasicQuantities - Thickness (Simplebim): 242.5 mm; Length (Simplebim): 2911.25 mm
Identity Data - CQFireRequirement: EI 60/ A2-s1,d0
ePset_LocationTool - Splitting: ORIGINAL
ePset_Simplebim - Assembly Level: Leaf
Pset_QuantityTakeOff - Reference: A241 - FVR-200 (T1); sets with these values: 2
Pset_WallCommon - IsExternal: no; ExtendToStructure: no; LoadBearing: no; Reference: A241 - FVR-200 (T1)
Name (Basic Wall:A241 - FVR-200 (T1):...) | In | Area, side, gross, AABB (Simplebim) (m2) = Area, largest surface, net (Simplebim) (m2) = Area, side, net, average (Simplebim) (m2) = Area, side, gross, average (Simplebim) (m2) = Area, side, gross, larger (Simplebim) (m2) = Area, side, net, larger (Simplebim) (m2) = Area, side, gross, smaller (Simplebim) (m2) = Area, side, net, smaller (Simplebim) (m2) | Height (Simplebim) (mm) | Volume, net (Simplebim) (m3)
40981157 | Nivå F - 0,7 m | 2.03788 | 700 | 0.49418
40981157 | Nivå F | 6.97244 | 2395 | 1.6908

# IfcWall: Basic Wall:A241 - MH-187 (5)
Type - PredefinedType: STANDARD; Material: Betong - Multiblokk 187 mm
Type - Pset_ReinforcementBarPitchOfWall - Description: Hulmur murblokk
AVINOR - 08_Status: S4; 07_Fase: F90; 03_Ansvar: FDV; 06_Omrade: TG; 02_Prosjekt: T20100; 01_Lufthavnkode: ENGM
Pset_WallCommon - Reference: A241 - MH-187; IsExternal: no; ExtendToStructure: no; LoadBearing: no
ePset_SimplebimBasicQuantities - Thickness (Simplebim): 188 mm; Height (Simplebim): 565 mm
ePset_LocationTool - Splitting: RESULT
Pset_QuantityTakeOff - Reference: A241 - MH-187; sets with these values: 2
ePset_Simplebim - Assembly Level: Leaf
Name (Basic Wall:A241 - MH-187:...) | In | Area, side, gross, AABB (Simplebim) (m2) | Area, largest surface, net (Simplebim) (m2) = Area, side, net, average (Simplebim) (m2) = Area, side, gross, average (Simplebim) (m2) = Area, side, gross, larger (Simplebim) (m2) = Area, side, net, larger (Simplebim) (m2) = Area, side, gross, smaller (Simplebim) (m2) = Area, side, net, smaller (Simplebim) (m2) | Length (Simplebim) (mm) | Volume, net (Simplebim) (m3)
2526678 | Nivå E | 1.62833 | 1.62833 | 2882 | 0.304499
39949039 | Nivå E | 2.35323 | 2.35323 | 4165 | 0.440053 | Identity Data - CQFireRequirement: EI 60/ A2-s1,d0
39949149 | Nivå E | 0.73563 | 0.735689 | 1302 | 0.137574
39949204 | Nivå E | 2.31537 | 2.3153 | 4098 | 0.432962 | Identity Data - CQFireRequirement: EI 60/ A2-s1,d0
2526686 | Nivå D + 1,2 m | 2.85833 | 2.85852 | 5059 | 0.534543

# IfcWall: Basic Wall:A241 - SVS-101, Basic Wall:A241 - SVS-101:2526687
In: Nivå E
Type - PredefinedType: STANDARD; Material: Plate - Gips 12.5 mm, Plate - Gips 12.5 mm, _NSW Stålstender, uisolert 100 mm, Plate - Gips 12.5 mm, Plate - Gips 12.5 mm
Type - Pset_ReinforcementBarPitchOfWall - Description: Stendervegg: 2x12.5mm Gipsplater - 100mm Stålstender - 2x12.5mm Gipsplater
AVINOR - 08_Status: S4; 07_Fase: F90; 03_Ansvar: FDV; 06_Omrade: TG; 02_Prosjekt: T20100; 01_Lufthavnkode: ENGM
Identity Data - CQFireRequirement: EI 60/ A2-s1,d0
ePset_SimplebimBasicQuantities - Area, side, gross, AABB (Simplebim): 2.85833 m2; Thickness (Simplebim): 150 mm; Height (Simplebim): 565 mm; Length (Simplebim): 5059 mm; Area, side, net, smaller (Simplebim): 2.85852 m2; Area, side, gross, smaller (Simplebim): 2.85852 m2; Area, side, net, larger (Simplebim): 2.85852 m2; Area, side, gross, larger (Simplebim): 2.85852 m2; Area, largest surface, net (Simplebim): 2.85852 m2; Area, side, gross, average (Simplebim): 2.85852 m2; Area, side, net, average (Simplebim): 2.85852 m2; Volume, net (Simplebim): 0.428778 m3
ePset_LocationTool - Splitting: RESULT
ePset_Simplebim - Assembly Level: Leaf
Pset_QuantityTakeOff - Reference: A241 - SVS-101; sets with these values: 2
Pset_WallCommon - IsExternal: no; ExtendToStructure: no; LoadBearing: no; Reference: A241 - SVS-101

# IfcWall: Basic Wall:A241 - Skjørt - SVS-100 S (2)
In: Nivå F - 0,7 m
Type - PredefinedType: STANDARD; Material: Plate - Gips 12.5 mm, _NSW Stålstender, uisolert 100 mm, Plate - Gips 12.5 mm
Type - Pset_ReinforcementBarPitchOfWall - Description: Stendervegg: 12.5mm Gipsplater - 100mm Stålstender - 2x12.5mm Gipsplater
AVINOR - 08_Status: S4; 07_Fase: F90; 03_Ansvar: FDV; 06_Omrade: TG; 02_Prosjekt: T20100; 01_Lufthavnkode: ENGM
ePset_Simplebim - Assembly Level: Leaf
Pset_WallCommon - Reference: A241 - Skjørt - SVS-100 S; IsExternal: no; ExtendToStructure: no; LoadBearing: no
ePset_SimplebimBasicQuantities - Height (Simplebim): 845 mm; Thickness (Simplebim): 125 mm
Pset_QuantityTakeOff - Reference: A241 - Skjørt - SVS-100 S; sets with these values: 2
ePset_LocationTool - Splitting: ORIGINAL
Name (Basic Wall:A241 - Skjørt - SVS-100 S:...) | Length (Simplebim) (mm) | Volume, net (Simplebim) (m3) | Area, side, gross, smaller (Simplebim) (m2) = Area, side, net, smaller (Simplebim) (m2) = Area, side, gross, larger (Simplebim) (m2) = Area, side, net, larger (Simplebim) (m2) = Area, largest surface, net (Simplebim) (m2) = Area, side, net, average (Simplebim) (m2) = Area, side, gross, average (Simplebim) (m2) | Area, side, gross, AABB (Simplebim) (m2)
50544391 | 2051.25 | 0.0682602 | 0.546081 | 1.73331
50544394 | 2055.5 | 0.0663528 | 0.530822 | 1.7369

# IfcWallStandardCase: Basic Wall:A231 - ISO-165 (3)
In: Nivå E
Type - PredefinedType: STANDARD; Material: _NSW Isolasjon 165 mm
Type - Pset_ReinforcementBarPitchOfWall - Description: Generell yttervegg 200mm
AVINOR - 08_Status: S4; 07_Fase: F90; 03_Ansvar: FDV; 06_Omrade: TG; 02_Prosjekt: T20100; 01_Lufthavnkode: ENGM
ePset_LocationTool - Splitting: ORIGINAL
Pset_WallCommon - IsExternal: yes; ExtendToStructure: no; LoadBearing: no; Reference: A231 - ISO-165
ePset_SimplebimBasicQuantities - Length (Simplebim): 9000 mm; Height (Simplebim): 250 mm; Thickness (Simplebim): 165 mm; Area, side, gross, AABB (Simplebim): 2.25 m2; Area, side, gross, larger (Simplebim): 2.25 m2; Area, side, net, larger (Simplebim): 2.25 m2; Area, side, gross, smaller (Simplebim): 2.25 m2; Area, side, net, smaller (Simplebim): 2.25 m2; Area, largest surface, net (Simplebim): 2.25 m2; Area, side, net, average (Simplebim): 2.25 m2; Area, side, gross, average (Simplebim): 2.25 m2; Volume, net (Simplebim): 0.37125 m3
ePset_Simplebim - Assembly Level: Leaf
Pset_QuantityTakeOff - Reference: A231 - ISO-165; sets with these values: 2
Name (Basic Wall:A231 - ISO-165:...) | Group
48691422 | Model Group:A230 - eksisterende fasadesystem i pir_SØR_9000_HEL (members excluded):48691507
49613545 | Model Group:A230 - eksisterende fasadesystem i pir_SØR_9000_HEL (members excluded):49613630
49613680 | Model Group:A230 - eksisterende fasadesystem i pir_SØR_9000_HEL (members excluded):49613765

# IfcWallStandardCase: Basic Wall:A231 - X-finer med beslag (3)
In: Nivå E
Type - PredefinedType: STANDARD; Material: T2_Metal_Aluminium 1 mm, T2_X-finer 15 mm
AVINOR - 08_Status: S4; 07_Fase: F90; 03_Ansvar: FDV; 06_Omrade: TG; 02_Prosjekt: T20100; 01_Lufthavnkode: ENGM
Pset_ReinforcementBarPitchOfWall - Reference: A231 - X-finer med beslag; sets with these values: 2
Pset_WallCommon - IsExternal: no; ExtendToStructure: no; LoadBearing: no; Reference: A231 - X-finer med beslag
ePset_LocationTool - Splitting: ORIGINAL
ePset_SimplebimBasicQuantities - Volume, net (Simplebim): 0.05112 m3; Length (Simplebim): 9000 mm; Height (Simplebim): 355 mm; Thickness (Simplebim): 16 mm; Area, largest surface, net (Simplebim): 3.195 m2; Area, side, gross, average (Simplebim): 3.195 m2; Area, side, net, average (Simplebim): 3.195 m2; Area, side, net, smaller (Simplebim): 3.195 m2; Area, side, gross, smaller (Simplebim): 3.195 m2; Area, side, net, larger (Simplebim): 3.195 m2; Area, side, gross, larger (Simplebim): 3.195 m2; Area, side, gross, AABB (Simplebim): 3.195 m2
ePset_Simplebim - Assembly Level: Leaf
Name (Basic Wall:A231 - X-finer med beslag:...) | Group
48691511 | Model Group:A230 - eksisterende fasadesystem i pir_SØR_9000_HEL (members excluded):48691507
49613634 | Model Group:A230 - eksisterende fasadesystem i pir_SØR_9000_HEL (members excluded):49613630
49613769 | Model Group:A230 - eksisterende fasadesystem i pir_SØR_9000_HEL (members excluded):49613765

# IfcWallStandardCase: Basic Wall:A241 - Eksisterende - GRVR-20 (8)
Type - PredefinedType: STANDARD; Material: Plate - Gips 12.5 mm, _NSW Stålstender, uisolert 100 mm, Plate - Gips 12.5 mm
AVINOR - 08_Status: S4; 07_Fase: F90; 03_Ansvar: FDV; 06_Omrade: TG; 02_Prosjekt: T20100; 01_Lufthavnkode: ENGM
Pset_WallCommon - Reference: A241 - Eksisterende - GRVR-20; IsExternal: no; ExtendToStructure: no; LoadBearing: no
Pset_ReinforcementBarPitchOfWall - Reference: A241 - Eksisterende - GRVR-20; sets with these values: 2
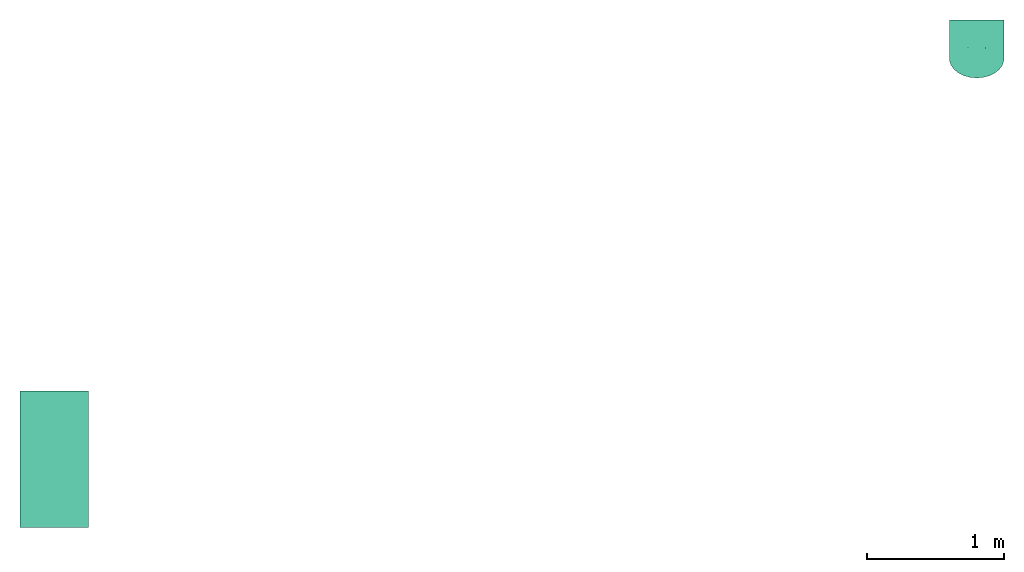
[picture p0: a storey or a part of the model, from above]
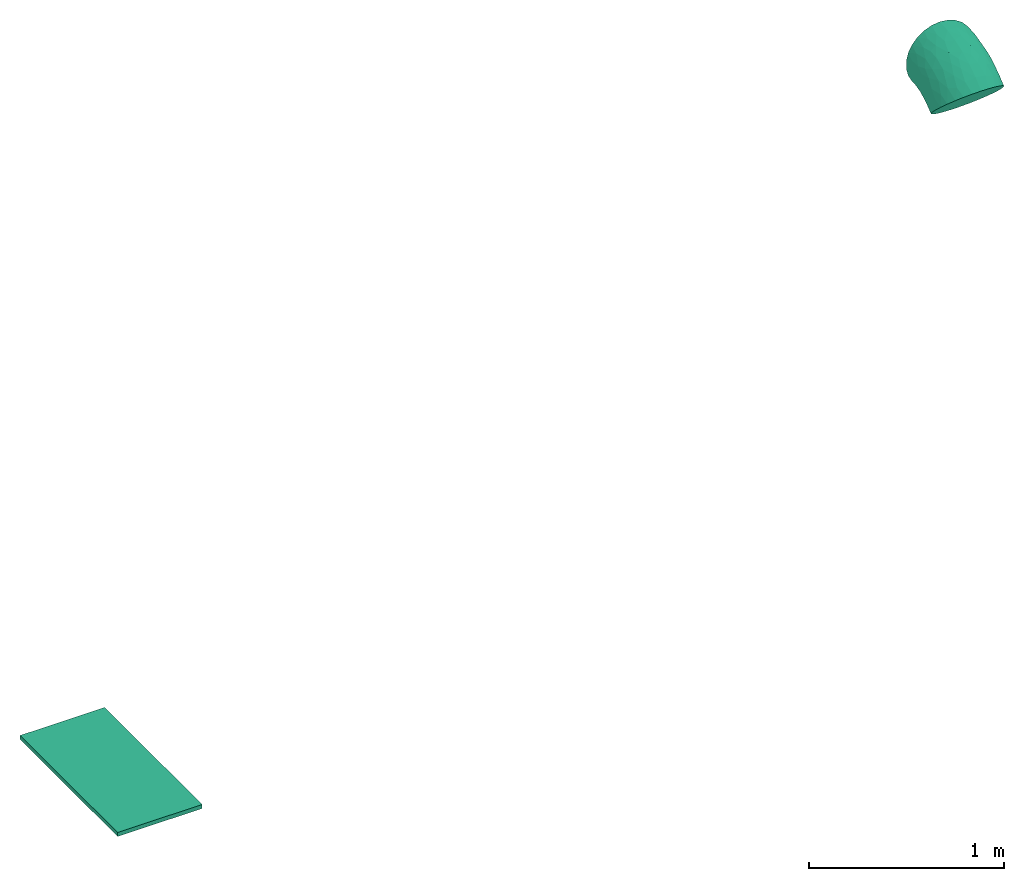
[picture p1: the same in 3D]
Properties of the parts of a building model (IFC2X3), part 11 of 11

# IfcWallStandardCase: Basic Wall:A241 - Eksisterende - GRVR-20 (8)
ePset_SimplebimBasicQuantities - Thickness (Simplebim): 125 mm; Length (Simplebim): 1177.29 mm
ePset_Simplebim - Assembly Level: Leaf
ePset_LocationTool - Splitting: ORIGINAL
Name (Basic Wall:A241 - Eksisterende - GRVR-20:...) | In | Volume, net (Simplebim) (m3) | Area, largest surface, net (Simplebim) (m2) = Area, side, gross, average (Simplebim) (m2) = Area, side, net, average (Simplebim) (m2) = Area, side, net, larger (Simplebim) (m2) = Area, side, gross, larger (Simplebim) (m2) = Area, side, net, smaller (Simplebim) (m2) = Area, side, gross, smaller (Simplebim) (m2) = Area, side, gross, AABB (Simplebim) (m2) | Height (Simplebim) (mm)
2512791 | Nivå F - 0,7 m | 0.103013 | 0.824101 | 700
2512791 | Nivå F | 0.228099 | 1.8248 | 1550
2512792 | Nivå F - 0,7 m | 0.103013 | 0.824101 | 700
2512792 | Nivå F | 0.228099 | 1.8248 | 1550
2512793 | Nivå F - 0,7 m | 0.103013 | 0.824101 | 700
2512793 | Nivå F | 0.228099 | 1.8248 | 1550
2512794 | Nivå F - 0,7 m | 0.103013 | 0.824101 | 700
2512794 | Nivå F | 0.228099 | 1.8248 | 1550

# IfcWallStandardCase: Basic Wall:A241 - Eksisterende - GRVR-30 (4)
Type - PredefinedType: STANDARD; Material: Plate - Gips 12.5 mm, _NSW Stålstender, uisolert 200 mm, Plate - Gips 12.5 mm
AVINOR - 08_Status: S4; 07_Fase: F90; 03_Ansvar: FDV; 06_Omrade: TG; 02_Prosjekt: T20100; 01_Lufthavnkode: ENGM
Pset_WallCommon - IsExternal: no; ExtendToStructure: no; LoadBearing: no; Reference: A241 - Eksisterende - GRVR-30
ePset_SimplebimBasicQuantities - Thickness (Simplebim): 225 mm
Pset_ReinforcementBarPitchOfWall - Reference: A241 - Eksisterende - GRVR-30; sets with these values: 2
ePset_Simplebim - Assembly Level: Leaf
ePset_LocationTool - Splitting: ORIGINAL
Name (Basic Wall:A241 - Eksisterende - GRVR-30:...) | In | Area, side, net, larger (Simplebim) (m2) = Area, side, net, smaller (Simplebim) (m2) = Area, side, net, average (Simplebim) (m2) | Area, side, gross, larger (Simplebim) (m2) = Area, side, gross, smaller (Simplebim) (m2) = Area, side, gross, average (Simplebim) (m2) | Volume, net (Simplebim) (m3) | Height (Simplebim) (mm) | Length (Simplebim) (mm) | Area, largest surface, net (Simplebim) (m2) | Area, side, gross, AABB (Simplebim) (m2)
2512780 | Nivå F - 0,7 m | 0.9555 | 3.0121 | 0.214988 | 700 | 2275 | 0.772783 | 1.5925
2512780 | Nivå F | 2.11575 | 4.17235 | 0.476044 | 1550 | 2275 | 1.71116 | 3.52625
2512781 | Nivå F - 0,7 m | 1.59348 | 1.59348 | 0.358533 | 700 | 2276.4 | 1.59348 | 1.59348
2512781 | Nivå F | 3.52842 | 3.52842 | 0.793894 | 1550 | 2276.4 | 3.52842 | 3.52842

# IfcWallStandardCase: Basic Wall:A241 - Eksisterende - GSVS-11 (6)
Type - PredefinedType: STANDARD; Material: Plate - Gips 12.5 mm, _NSW Stålstender, uisolert 75 mm, Plate - Gips 12.5 mm
Pset_WallCommon - Reference: A241 - Eksisterende - GSVS-11; IsExternal: no; ExtendToStructure: no; LoadBearing: no
AVINOR - 08_Status: S4; 07_Fase: F90; 02_Prosjekt: A162446; 03_Ansvar: 182412; 06_Omrade: TG; 01_Lufthavnkode: ENGM
Pset_ReinforcementBarPitchOfWall - Reference: A241 - Eksisterende - GSVS-11; sets with these values: 2
ePset_LocationTool - Splitting: ORIGINAL
ePset_Simplebim - Assembly Level: Leaf
ePset_SimplebimBasicQuantities - Thickness (Simplebim): 100 mm
Group: Model Group:A162446 - Utvidelse eksisterende Kiosk (members excluded):59114857
Name (Basic Wall:A241 - Eksisterende - GSVS-11:...) | In | Length (Simplebim) (mm) | Area, side, gross, AABB (Simplebim) (m2) | Area, side, gross, average (Simplebim) (m2) = Area, side, gross, larger (Simplebim) (m2) = Area, side, gross, smaller (Simplebim) (m2) | Area, side, net, average (Simplebim) (m2) = Area, side, net, larger (Simplebim) (m2) = Area, side, net, smaller (Simplebim) (m2) | Area, largest surface, net (Simplebim) (m2) | Volume, net (Simplebim) (m3) | Height (Simplebim) (mm)
59105928 | Nivå F - 0,7 m | 5252.8 | 3.67696 | 3.67696 | 3.67696 | 3.67696 | 0.367696 | 700
59105928 | Nivå F | 5252.8 | 9.45505 | 9.45505 | 9.45505 | 9.45505 | 0.945505 | 1800
59105929 | Nivå F - 0,7 m | 5253.87 | 3.67771 | 2.69771 | 2.69771 | 2.16818 | 0.269771 | 700
59105929 | Nivå F | 5253.87 | 9.45696 | 10.437 | 7.44992 | 7.44992 | 0.744992 | 1800
59106061 | Nivå F - 0,7 m | 5252.8 | 3.67696 | 3.67696 | 3.67696 | 3.67696 | 0.367696 | 700
59106061 | Nivå F | 5252.8 | 9.45505 | 9.45505 | 9.45505 | 9.45505 | 0.945505 | 1800

# IfcWallStandardCase: Basic Wall:A241 - Eksisterende - GSVS-30 (14)
Type - PredefinedType: STANDARD; Material: Plate - Gips 12.5 mm, Plate - Gips 12.5 mm, _NSW Stålstender, uisolert 100 mm, Plate - Gips 12.5 mm, Plate - Gips 12.5 mm
AVINOR - 08_Status: S4; 07_Fase: F90; 03_Ansvar: FDV; 06_Omrade: TG; 02_Prosjekt: T20100; 01_Lufthavnkode: ENGM
ePset_LocationTool - Splitting: ORIGINAL
Pset_QuantityTakeOff - Reference: A241 - Eksisterende - GSVS-30; sets with these values: 2
Pset_WallCommon - Reference: A241 - Eksisterende - GSVS-30; IsExternal: no; ExtendToStructure: no; LoadBearing: no
ePset_Simplebim - Assembly Level: Leaf
ePset_SimplebimBasicQuantities - Thickness (Simplebim): 150 mm
Name (Basic Wall:A241 - Eksisterende - GSVS-30:...) | In | Length (Simplebim) (mm) | Area, side, gross, smaller (Simplebim) (m2) = Area, side, gross, larger (Simplebim) (m2) = Area, side, gross, average (Simplebim) (m2) | Area, side, gross, AABB (Simplebim) (m2) | Area, largest surface, net (Simplebim) (m2) | Height (Simplebim) (mm) | Volume, net (Simplebim) (m3) | Area, side, net, average (Simplebim) (m2) = Area, side, net, smaller (Simplebim) (m2) = Area, side, net, larger (Simplebim) (m2)
2512783 | Nivå F - 0,7 m | 1986.75 | 2.96632 | 1.39072 | 0.679175 | 700 | 0.102559 | 0.683725
2512783 | Nivå F | 1986.75 | 3.79656 | 3.07946 | 1.50389 | 1550 | 0.227094 | 1.51396
2512784 | Nivå F - 0,7 m | 2126.4 | 1.48848 | 1.48848 | 1.48848 | 700 | 0.223272 | 1.48848
2512784 | Nivå F | 2126.4 | 3.29592 | 3.29592 | 3.29592 | 1550 | 0.494388 | 3.29592
2512785 | Nivå F - 0,7 m | 2125 | 1.4875 | 1.4875 | 1.4875 | 700 | 0.223125 | 1.4875
2512785 | Nivå F | 2125 | 3.29375 | 3.29375 | 3.29375 | 1550 | 0.494063 | 3.29375
2512787 | Nivå F - 0,7 m | 1980.5 | 2.96195 | 1.38635 | 0.672 | 700 | 0.101902 | 0.67935
2512787 | Nivå F | 1980.5 | 3.78687 | 3.06977 | 1.488 | 1550 | 0.225641 | 1.50428
2512788 | Nivå F - 0,7 m | 4987 | 3.4909 | 3.4909 | 3.4909 | 700 | 0.523635 | 3.4909
2512788 | Nivå F | 4987 | 7.72985 | 7.72985 | 7.72985 | 1550 | 1.15948 | 7.72985
2512797 | Nivå F - 0,7 m | 306 | 0.2142 | 0.2142 | 0.2142 | 700 | 0.03213 | 0.2142
2512797 | Nivå F | 306 | 0.73287 | 0.73287 | 0.73287 | 2395 | 0.109931 | 0.73287
49355322 | Nivå F - 0,7 m | 305.15 | 0.213605 | 0.213605 | 0.213605 | 700 | 0.0320408 | 0.213605
49355322 | Nivå F | 305.15 | 0.730834 | 0.730834 | 0.730834 | 2395 | 0.109625 | 0.730834

# IfcWallStandardCase: Basic Wall:A241 - Eksisterende - GSVS-50 (4)
Type - PredefinedType: STANDARD; Material: Plate - Gips 12.5 mm, Plate - Gips 12.5 mm, _NSW Stålstender, uisolert 200 mm, Plate - Gips 12.5 mm, Plate - Gips 12.5 mm
AVINOR - 08_Status: S4; 07_Fase: F90; 03_Ansvar: FDV; 06_Omrade: TG; 02_Prosjekt: T20100; 01_Lufthavnkode: ENGM
ePset_SimplebimBasicQuantities - Thickness (Simplebim): 250 mm
ePset_LocationTool - Splitting: ORIGINAL
Pset_WallCommon - IsExternal: no; ExtendToStructure: no; LoadBearing: no; Reference: A241 - Eksisterende - GSVS-50
Pset_ReinforcementBarPitchOfWall - Reference: A241 - Eksisterende - GSVS-50; sets with these values: 2
ePset_Simplebim - Assembly Level: Leaf
Name (Basic Wall:A241 - Eksisterende - GSVS-50:...) | In | Length (Simplebim) (mm) | Height (Simplebim) (mm) | Area, side, gross, average (Simplebim) (m2) = Area, side, net, average (Simplebim) (m2) = Area, largest surface, net (Simplebim) (m2) = Area, side, net, smaller (Simplebim) (m2) = Area, side, gross, smaller (Simplebim) (m2) = Area, side, net, larger (Simplebim) (m2) = Area, side, gross, larger (Simplebim) (m2) | Area, side, gross, AABB (Simplebim) (m2) | Volume, net (Simplebim) (m3)
2512782 | Nivå F - 0,7 m | 1836.75 | 700 | 1.28573 | 1.28572 | 0.321431
2512782 | Nivå F | 1836.75 | 1550 | 2.84696 | 2.84696 | 0.711741
2512786 | Nivå F - 0,7 m | 1830.5 | 700 | 1.28135 | 1.28135 | 0.320337
2512786 | Nivå F | 1830.5 | 1550 | 2.83727 | 2.83727 | 0.709319

# IfcWallStandardCase: Basic Wall:A241 - FSVF-100 (4)
Type - PredefinedType: STANDARD; Material: T2_Gips Protect F 15 mm, T2_Gips Standard 12.5 mm, _NSW Stålstender, uisolert 100 mm, T2_Gips Protect F 15 mm
Type - Pset_ReinforcementBarPitchOfWall - Description: Tilsvarende: T2 - IVEGG-150 - Forprosjekt
AVINOR - 08_Status: S4; 07_Fase: F90; 03_Ansvar: FDV; 06_Omrade: TG; 02_Prosjekt: T20100; 01_Lufthavnkode: ENGM
Pset_WallCommon - IsExternal: no; ExtendToStructure: no; LoadBearing: no; Reference: A241 - FSVF-100
ePset_LocationTool - Splitting: ORIGINAL
Pset_QuantityTakeOff - Reference: A241 - FSVF-100; sets with these values: 2
ePset_SimplebimBasicQuantities - Thickness (Simplebim): 142.5 mm
ePset_Simplebim - Assembly Level: Leaf
Name (Basic Wall:A241 - FSVF-100:...) | In | Length (Simplebim) (mm) | Area, side, gross, AABB (Simplebim) (m2) | Area, side, gross, average (Simplebim) (m2) = Area, side, gross, smaller (Simplebim) (m2) = Area, side, gross, larger (Simplebim) (m2) | Volume, net (Simplebim) (m3) | Area, largest surface, net (Simplebim) (m2) | Area, side, net, average (Simplebim) (m2) = Area, side, net, larger (Simplebim) (m2) = Area, side, net, smaller (Simplebim) (m2) | Height (Simplebim) (mm)
2512799 | Nivå F - 0,7 m | 2052.65 | 1.43685 | 3.00195 | 0.0940293 | 0.48398 | 0.659855 | 700
2512799 | Nivå F | 2052.65 | 4.9161 | 5.6931 | 0.477517 | 3.351 | 3.351 | 2395
49355532 | Nivå F - 0,7 m | 2194.15 | 1.5359 | 2.5424 | 0.187573 | 1.3001 | 1.3163 | 700 | Identity Data - CQFireRequirement: EI 60/ A2-s1,d0
49355532 | Nivå F | 2194.15 | 5.25499 | 5.47459 | 0.60541 | 4.24849 | 4.24849 | 2395 | Identity Data - CQFireRequirement: EI 60/ A2-s1,d0

# IfcWallStandardCase: Basic Wall:A241 - FV-30 (2)
In: Nivå G
Type - PredefinedType: STANDARD; Material: T2_Gips Protect F 15 mm, T2_Gips Protect F 15 mm
ePset_LocationTool - Splitting: ORIGINAL
AVINOR - 08_Status: S4; 07_Fase: F90; 02_Prosjekt: A162446; 03_Ansvar: 182412; 06_Omrade: TG; 01_Lufthavnkode: ENGM
Pset_ReinforcementBarPitchOfWall - Reference: A241 - FV-30; sets with these values: 2
ePset_SimplebimBasicQuantities - Thickness (Simplebim): 30 mm
ePset_Simplebim - Assembly Level: Leaf
Pset_WallCommon - IsExternal: no; ExtendToStructure: no; LoadBearing: no; Reference: A241 - FV-30
Group: Model Group:A162446 - Utvidelse eksisterende Kiosk (members excluded):59114857
Name (Basic Wall:A241 - FV-30:...) | Volume, net (Simplebim) (m3) | Height (Simplebim) (mm) | Length (Simplebim) (mm) | Area, side, gross, AABB (Simplebim) (m2) = Area, side, gross, average (Simplebim) (m2) = Area, side, net, average (Simplebim) (m2) = Area, largest surface, net (Simplebim) (m2) = Area, side, net, larger (Simplebim) (m2) = Area, side, gross, larger (Simplebim) (m2) = Area, side, net, smaller (Simplebim) (m2) = Area, side, gross, smaller (Simplebim) (m2)
59105909 | 0.0258958 | 57.45 | 15025.1 | 0.863192
59105911 | 0.0184217 | 70.5 | 8710 | 0.614055

# IfcWallStandardCase: Basic Wall:A241 - FVF-100 (4)
Type - PredefinedType: STANDARD; Material: T2_Gips Protect F 15 mm, _NSW Stålstender, uisolert 100 mm, T2_Gips Protect F 15 mm
Type - Pset_ReinforcementBarPitchOfWall - Description: Tilsvarende: T2 - IVEGG-150 - Forprosjekt
AVINOR - 08_Status: S4; 07_Fase: F90; 03_Ansvar: FDV; 06_Omrade: TG; 02_Prosjekt: T20100; 01_Lufthavnkode: ENGM
ePset_SimplebimBasicQuantities - Length (Simplebim): 1810 mm; Thickness (Simplebim): 130 mm
Identity Data - CQFireRequirement: EI 60/ A2-s1,d0
Pset_QuantityTakeOff - Reference: A241 - FVF-100; sets with these values: 2
ePset_LocationTool - Splitting: ORIGINAL
Pset_WallCommon - Reference: A241 - FVF-100; IsExternal: no; ExtendToStructure: no; LoadBearing: no
ePset_Simplebim - Assembly Level: Leaf
Name (Basic Wall:A241 - FVF-100:...) | In | Area, largest surface, net (Simplebim) (m2) | Area, side, gross, AABB (Simplebim) (m2) | Area, side, net, smaller (Simplebim) (m2) = Area, side, net, larger (Simplebim) (m2) = Area, side, net, average (Simplebim) (m2) | Area, side, gross, average (Simplebim) (m2) = Area, side, gross, larger (Simplebim) (m2) = Area, side, gross, smaller (Simplebim) (m2) | Height (Simplebim) (mm) | Volume, net (Simplebim) (m3)
2512800 | Nivå F - 0,7 m | 0.475125 | 1.267 | 0.56 | 2.6911 | 700 | 0.0728
2512800 | Nivå F | 2.91085 | 4.33495 | 2.91085 | 5.04195 | 2395 | 0.37841
2513096 | Nivå F - 0,7 m | 1.267 | 1.267 | 1.267 | 1.267 | 700 | 0.16471
2513096 | Nivå F | 4.33495 | 4.33495 | 4.33495 | 4.33495 | 2395 | 0.563543

# IfcWallStandardCase: Basic Wall:A241 - FVR-200 (T1) (2)
Type - PredefinedType: STANDARD; Material: T2_Gips Protect F 15 mm, T2_Gips Protect F 15 mm, _NSW Stålstender, isolert uten skravur 200 mm, T2_Gips Fibergips 12.5 mm
AVINOR - 08_Status: S4; 07_Fase: F90; 03_Ansvar: FDV; 06_Omrade: TG; 02_Prosjekt: T20100; 01_Lufthavnkode: ENGM
ePset_SimplebimBasicQuantities - Length (Simplebim): 2087.25 mm; Thickness (Simplebim): 242.5 mm
ePset_Simplebim - Assembly Level: Leaf
ePset_LocationTool - Splitting: ORIGINAL
Pset_QuantityTakeOff - Reference: A241 - FVR-200 (T1); sets with these values: 2
Pset_WallCommon - IsExternal: no; ExtendToStructure: no; LoadBearing: no; Reference: A241 - FVR-200 (T1)
Name (Basic Wall:A241 - FVR-200 (T1):...) | In | Volume, net (Simplebim) (m3) | Area, side, gross, AABB (Simplebim) (m2) = Area, side, net, smaller (Simplebim) (m2) = Area, side, gross, smaller (Simplebim) (m2) = Area, side, net, larger (Simplebim) (m2) = Area, side, gross, larger (Simplebim) (m2) = Area, largest surface, net (Simplebim) (m2) = Area, side, gross, average (Simplebim) (m2) = Area, side, net, average (Simplebim) (m2) | Height (Simplebim) (mm)
2512796 | Nivå F - 0,7 m | 0.354311 | 1.46107 | 700
2512796 | Nivå F | 1.21225 | 4.99896 | 2395

# IfcWallStandardCase: Basic Wall:A241 - SVS-75 (2)
Type - PredefinedType: STANDARD; Material: Plate - Gips 12.5 mm, _NSW Stålstender, uisolert 75 mm, Plate - Gips 12.5 mm
Type - Pset_ReinforcementBarPitchOfWall - Description: Tilsvarende: T2 - IVEGG-100 - Forprosjekt
AVINOR - 08_Status: S4; 07_Fase: F90; 03_Ansvar: FDV; 06_Omrade: TG; 02_Prosjekt: T20100; 01_Lufthavnkode: ENGM
ePset_LocationTool - Splitting: ORIGINAL
Pset_WallCommon - Reference: A241 - SVS-75; IsExternal: no; ExtendToStructure: no; LoadBearing: no
ePset_SimplebimBasicQuantities - Length (Simplebim): 1302.43 mm; Thickness (Simplebim): 100 mm
ePset_Simplebim - Assembly Level: Leaf
Pset_ReinforcementBarPitchOfWall - Reference: A241 - SVS-75; sets with these values: 2
Name (Basic Wall:A241 - SVS-75:...) | In | Volume, net (Simplebim) (m3) | Area, side, gross, AABB (Simplebim) (m2) | Area, side, net, larger (Simplebim) (m2) = Area, side, net, smaller (Simplebim) (m2) = Area, side, net, average (Simplebim) (m2) | Area, side, gross, larger (Simplebim) (m2) = Area, side, gross, smaller (Simplebim) (m2) = Area, side, gross, average (Simplebim) (m2) | Height (Simplebim) (mm) | Area, largest surface, net (Simplebim) (m2)
53693264 | Nivå F - 0,7 m | 0.0274702 | 0.911702 | 0.274702 | 2.3313 | 700 | 0.234355
53693264 | Nivå F | 0.0608268 | 2.01877 | 0.608268 | 2.66487 | 1550 | 0.51893

# IfcWallStandardCase: Basic Wall:A241 - Skjørt - SVS-100 S (5)
In: Nivå F - 0,7 m
Type - PredefinedType: STANDARD; Material: Plate - Gips 12.5 mm, _NSW Stålstender, uisolert 100 mm, Plate - Gips 12.5 mm
Type - Pset_ReinforcementBarPitchOfWall - Description: Stendervegg: 12.5mm Gipsplater - 100mm Stålstender - 2x12.5mm Gipsplater
AVINOR - 08_Status: S4; 07_Fase: F90; 03_Ansvar: FDV; 06_Omrade: TG; 02_Prosjekt: T20100; 01_Lufthavnkode: ENGM
ePset_LocationTool - Splitting: ORIGINAL
ePset_Simplebim - Assembly Level: Leaf
Pset_WallCommon - Reference: A241 - Skjørt - SVS-100 S; IsExternal: no; ExtendToStructure: no; LoadBearing: no
Pset_QuantityTakeOff - Reference: A241 - Skjørt - SVS-100 S; sets with these values: 2
ePset_SimplebimBasicQuantities - Height (Simplebim): 485 mm; Thickness (Simplebim): 125 mm
Name (Basic Wall:A241 - Skjørt - SVS-100 S:...) | Volume, net (Simplebim) (m3) | Area, largest surface, net (Simplebim) (m2) = Area, side, net, average (Simplebim) (m2) = Area, side, gross, average (Simplebim) (m2) = Area, side, gross, larger (Simplebim) (m2) = Area, side, net, larger (Simplebim) (m2) = Area, side, gross, smaller (Simplebim) (m2) = Area, side, net, smaller (Simplebim) (m2) = Area, side, gross, AABB (Simplebim) (m2) | Length (Simplebim) (mm)
50544677 | 0.311431 | 2.49145 | 5137
50544678 | 0.0712476 | 0.569981 | 1175.22
50544679 | 0.0712476 | 0.569981 | 1175.22
50544680 | 0.0712476 | 0.569981 | 1175.22
50544681 | 0.0712476 | 0.569981 | 1175.22

# IfcWallStandardCase: Basic Wall:A241 - Skjørt - SVS-101 S (11)
In: Nivå F - 0,7 m
Type - PredefinedType: STANDARD; Material: Plate - Gips 12.5 mm, Plate - Gips 12.5 mm, _NSW Stålstender, uisolert 100 mm, Plate - Gips 12.5 mm, Plate - Gips 12.5 mm
Type - Pset_ReinforcementBarPitchOfWall - Description: Stendervegg: 2x12.5mm Gipsplater - 100mm Stålstender - 2x12.5mm Gipsplater
AVINOR - 08_Status: S4; 07_Fase: F90; 03_Ansvar: FDV; 06_Omrade: TG; 02_Prosjekt: T20100; 01_Lufthavnkode: ENGM
ePset_SimplebimBasicQuantities - Thickness (Simplebim): 150 mm
ePset_LocationTool - Splitting: ORIGINAL
Pset_WallCommon - Reference: A241 - Skjørt - SVS-101 S; IsExternal: no; ExtendToStructure: no; LoadBearing: no
ePset_Simplebim - Assembly Level: Leaf
Pset_ReinforcementBarPitchOfWall - Reference: A241 - Skjørt - SVS-101 S; sets with these values: 2
Name (Basic Wall:A241 - Skjørt - SVS-101 S:...) | Length (Simplebim) (mm) | Height (Simplebim) (mm) | Volume, net (Simplebim) (m3) | Area, side, gross, AABB (Simplebim) (m2) | Area, largest surface, net (Simplebim) (m2) = Area, side, gross, average (Simplebim) (m2) = Area, side, net, average (Simplebim) (m2) = Area, side, net, larger (Simplebim) (m2) = Area, side, gross, larger (Simplebim) (m2) = Area, side, net, smaller (Simplebim) (m2) = Area, side, gross, smaller (Simplebim) (m2)
50544390 | 1976.5 | 395 | 0.117108 | 0.780717 | 0.780717
50544392 | 2055.5 | 395 | 0.121788 | 0.811922 | 0.811922
50544393 | 5287 | 485 | 0.384629 | 2.5642 | 2.56419
50544401 | 913.6 | 183 | 0.0250783 | 0.167189 | 0.167189
50544402 | 830 | 283 | 0.0352335 | 0.23489 | 0.23489
50544403 | 355 | 395 | 0.0210338 | 0.140225 | 0.140225
50544410 | 355 | 383 | 0.0203948 | 0.135965 | 0.135965
50544411 | 830 | 283 | 0.0352335 | 0.23489 | 0.23489
50544412 | 913.6 | 183 | 0.0250783 | 0.167189 | 0.167189
50544417 | 2123.6 | 485 | 0.154492 | 1.02995 | 1.02995
50544418 | 1973.6 | 485 | 0.143579 | 0.957196 | 0.957196

# IfcWallStandardCase: Basic Wall:A241 - V1 (4)
Type - PredefinedType: STANDARD; Material: T2_Fibersement 15 mm, T2_X-finer 12 mm, _NSW Stålstender, uisolert 75 mm, T2_X-finer 12 mm, T2_Fibersement 15 mm
Type - Pset_ReinforcementBarPitchOfWall - Description: økt toalettkapasitet i pir øst nivå F - 72101-A127372
AVINOR - 08_Status: S4; 07_Fase: F90; 02_Prosjekt: A162446; 03_Ansvar: 182412; 06_Omrade: TG; 01_Lufthavnkode: ENGM
ePset_SimplebimBasicQuantities - Thickness (Simplebim): 129 mm
Pset_QuantityTakeOff - Reference: A241 - V1; sets with these values: 2
ePset_Simplebim - Assembly Level: Leaf
Pset_WallCommon - IsExternal: no; ExtendToStructure: no; LoadBearing: no; Reference: A241 - V1
ePset_LocationTool - Splitting: ORIGINAL
Group: Model Group:A162446 - Utvidelse eksisterende Kiosk (members excluded):59114857
Name (Basic Wall:A241 - V1:...) | In | Area, side, gross, smaller (Simplebim) (m2) = Area, side, net, smaller (Simplebim) (m2) = Area, side, gross, larger (Simplebim) (m2) = Area, side, net, larger (Simplebim) (m2) = Area, side, net, average (Simplebim) (m2) = Area, side, gross, average (Simplebim) (m2) = Area, largest surface, net (Simplebim) (m2) = Area, side, gross, AABB (Simplebim) (m2) | Length (Simplebim) (mm) | Height (Simplebim) (mm) | Volume, net (Simplebim) (m3)
59105806 | Nivå F - 0,7 m | 3.01 | 4300 | 700 | 0.38829
59105806 | Nivå F | 9.89 | 4300 | 2300 | 1.27581
59105811 | Nivå F - 0,7 m | 2.7069 | 3867 | 700 | 0.34919
59105811 | Nivå F | 7.92735 | 3867 | 2050 | 1.02263

# IfcWallStandardCase: Basic Wall:A241 - V2 (4)
Type - PredefinedType: STANDARD; Material: T2_Fibersement 15 mm, _NSW Stålstender, uisolert 100 mm, T2_X-finer 12 mm, T2_Fibersement 15 mm
Type - Pset_ReinforcementBarPitchOfWall - Description: økt toalettkapasitet i pir øst nivå F - 72101-A127372
AVINOR - 08_Status: S4; 07_Fase: F90; 02_Prosjekt: A162446; 03_Ansvar: 182412; 06_Omrade: TG; 01_Lufthavnkode: ENGM
ePset_SimplebimBasicQuantities - Thickness (Simplebim): 142 mm
Pset_ReinforcementBarPitchOfWall - Reference: A241 - V2; sets with these values: 2
ePset_Simplebim - Assembly Level: Leaf
Pset_WallCommon - IsExternal: no; ExtendToStructure: no; LoadBearing: no; Reference: A241 - V2
ePset_LocationTool - Splitting: ORIGINAL
Group: Model Group:A162446 - Utvidelse eksisterende Kiosk (members excluded):59114857
Name (Basic Wall:A241 - V2:...) | In | Area, largest surface, net (Simplebim) (m2) | Length (Simplebim) (mm) | Volume, net (Simplebim) (m3) | Area, side, gross, AABB (Simplebim) (m2) | Area, side, gross, smaller (Simplebim) (m2) = Area, side, gross, larger (Simplebim) (m2) = Area, side, gross, average (Simplebim) (m2) | Area, side, net, larger (Simplebim) (m2) = Area, side, net, smaller (Simplebim) (m2) = Area, side, net, average (Simplebim) (m2) | Height (Simplebim) (mm)
59105810 | Nivå F - 0,7 m | 11.9756 | 18050 | 1.71465 | 12.635 | 13.755 | 12.075 | 700
59105810 | Nivå F | 35.8825 | 18050 | 5.09531 | 37.0025 | 37.5625 | 35.8825 | 2050
59105834 | Nivå F - 0,7 m | 0.640452 | 914.931 | 0.0909441 | 0.640452 | 1.00871 | 0.640452 | 700
59105834 | Nivå F | 1.41814 | 914.931 | 0.201376 | 1.41814 | 1.7864 | 1.41814 | 1550
